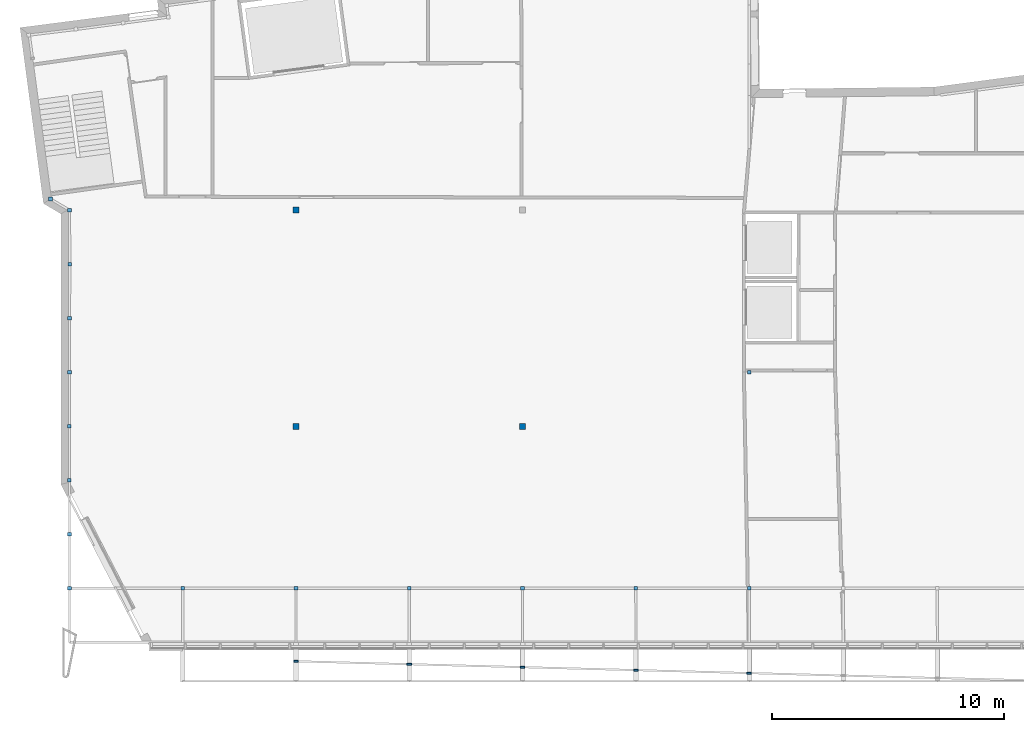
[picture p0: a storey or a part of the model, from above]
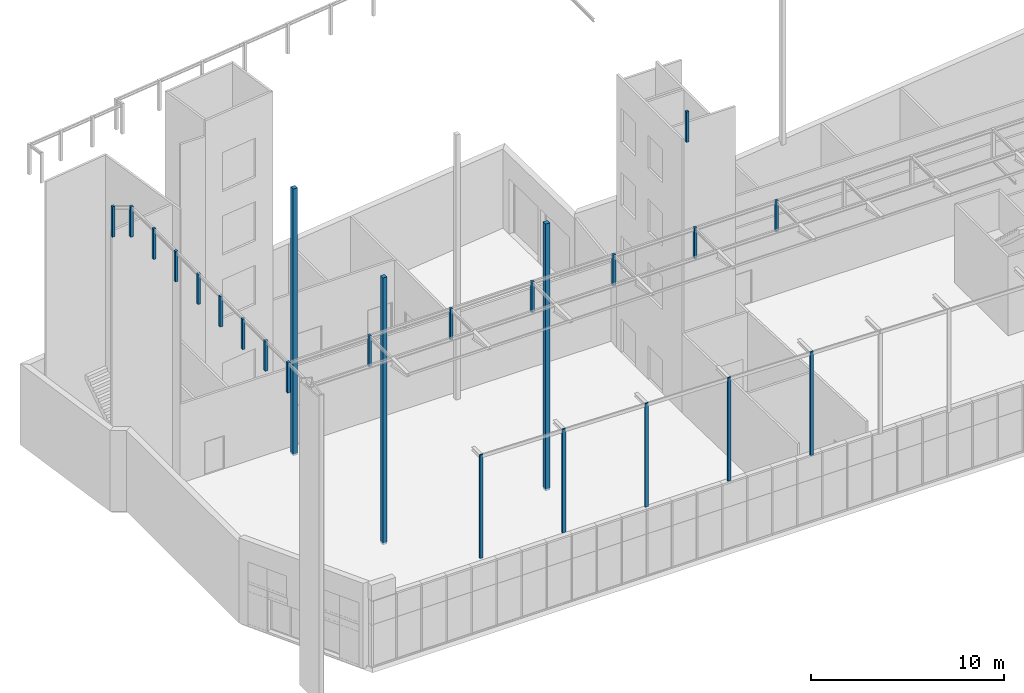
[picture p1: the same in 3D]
Properties of the parts of a building model (IFC2X3), part 1 of 19

# File
Description: ViewDefinition [CoordinationView_V2.0, QuantityTakeOffAddOnView, SpaceBoundary2ndLevelAddOnView], Option [Drawing Scale: 50.000000], Option [Global Unique Identifiers (GUID): Keep existing], Option [Elements to export: Visible elements (on all stories)], Option [Partial Structure Display: Entire Model], Option [IFC Domain: All], Option [Structural Function: All Elements], Option [Convert Grid elements: On], Option [Convert IFC Annotations and ArchiCAD 2D elements: Off], Option [Convert 2D symbols of Doors and Windows: Off], Option [Explode Composite and Complex Profile elements into parts: Off], Option [Export geometries that Participates in Collision Detection only: Off], Option [Multi-skin complex geometries: Building element parts], Option [Elements in Solid Element Operations: Extruded/revolved], Option [Elements with junctions: Extruded/revolved without junctions], Option [Slabs with slanted edge(s): Extruded], Option [Use legacy geometric methods as in Coordination View 1.0: Off], Option [IFC Site Geometry: As boundary representation (BRep)], Option [Properties To Export: All properties], Option [Space containment: On], Option [Bounding Box: Off], Option [Geometry to type objects: Off], Option [IFC base quantities (size, area and volume): On], Option [All ArchiCAD BIM parameters: On], Option [IFC Space boundaries: On], Option [ArchiCAD Zone Categories as IFC Space classification data: On]
File name: /Users/judde/Desktop/OpenBIM Tour/ArchiCAD Modèle entier.ifc
Time: 2015-04-22T15:16:54
Author: Architect
Organization: Building Designer Office
Written by: PreProc - EDM 5.0
Made in: IFC file generated by Graphisoft ArchiCAD-64 18.0.0 FRA FULL Macintosh version (IFC2x3 add-on version: 5100 FRA FULL).
Authorization: The authorising person

# IfcSite, Undefined
RefLatitude: 38, 55, 0, 0; RefLongitude: -77, 0, 0, 0; RefElevation: 0 m
BaseQuantities - GrossPerimeter: 0 m; GrossArea: 0 m2

# IfcBuilding, Undefined
BaseQuantities - GrossFloorArea: 0 m2

# IfcBuildingStorey (6)
In: Undefined
BaseQuantities - GrossFloorArea: 0 m2
Name | LongName | Elevation (m) | NetHeight (m) = GrossHeight (m) = Height (m)
Rez de chaussée | 0. Groud | 0 | 5.4
R+1 | 1. First Floor | 5.4 | 4.025
Mezzannine | 2. Mezz | 9.425 | 4.025
R+2 | 3. 2nd Floor | 13.45 | 3.95
Toiture | 4. Roof | 17.4 | 1.95
Etage | 5. Story | 19.35 | 3.235

# IfcBeam: HEB200 (10)
In: Rez de chaussée
Description: A_Beam; Material: STEEL/S235JRG2 3386696625
ArchiCADProperties - ID: BEAM; Etage d'implantation: Rez de chaussée; Calque: A-BEAM; Type: Poutre; Verrouillé: no; Matériau de construction / Composite / Profil / Hachure: HEB200 0000000000; Fonction structurelle: Elément porteur; Position: Non défini; Classification d'lément: Poutre; Etat de rénovation: Existant; Afficher sur filtre de rénovation: Tous les filtres appropriés; Type de structure: Profil complexe; Matériau de construction / Profil: HEB200 0000000000; Angle d'inclinaison de poutre: 0 deg; Coupe transversale de poutre: Profilé
AC_Pset_RenovationAndPhasing - Renovation Status: Existing
Pset_BeamCommon - LoadBearing: yes; Reference: HEB200 0000000000 200 x 200
BaseQuantities - CrossSectionArea: 0.00780812 m2
ArchiCADQuantities - Altitude à Zéro du Projet: 11.65 m; Altitude à étage: 11.65 m; Hauteur: 0.2 m; Surface des trous: 0 m2; Surface des arêtes de trou: 0 m2; Nombre de trous: 0; Volume des trous: 0 m3; Largeur des trous: 0 m; Hauteur du trou: 0 m; Niveau du trou: 0 m; Largeur: 0.2 m; Décalage: 0 m
Name | Nom de Zone | Numéro de Zone | NetSurfaceAreaExtrudedSides (m2) = OuterSurfaceArea (m2) | Length (m) = Longueur droite (m) = Longueur gauche (m) | TotalSurfaceArea (m2) = GrossSurfaceArea (m2) | GrossVolume (m3) = NetVolume (m3) = Volume net (m3) = Volume (m3) = Volume conditionnel (m3) | Superficie de surface (m2) | Superficie (m2) = Surface inférieure (m2) = Surface supérieure (m2) | Surface côté gauche (m2) | Surface côté droit (m2) | Surface de fin (m2)
BEAM | Vide | 001 | 0.917813 | 1.23231 | 0.93343 | 0.00626754 | 0.925667 | 0.283291 | 0.175661 | 0.175571 | 0.007854
BEAM | Vide | 001 | 1.06306 | 1.35983 | 1.07868 | 0.00726072 | 1.07091 | 0.328183 | 0.203375 | 0.203318 | 0.007854
BEAM | Vide | 001 | 1.30754 | 1.57068 | 1.32316 | 0.00892973 | 1.31539 | 0.403621 | 0.250178 | 0.25012 | 0.007854
BEAM | Vide | 001 | 0.770857 | 1.10595 | 0.786474 | 0.00526391 | 0.778711 | 0.237927 | 0.147544 | 0.147459 | 0.007854
BEAM | Vide | 001 | 0.607316 | 0.978469 | 0.622933 | 0.00414768 | 0.607316 | 0.187474 | 0.116213 | 0.116155 | 0
BEAM | Plateau bureaux | 005 | 1.74563 | 1.95138 | 1.76125 | 0.0119068 | 1.76134 | 0.538184 | 0.33586 | 0.333402 | 0.015708
BEAM | Vide | 001 | 1.45225 | 1.69643 | 1.46787 | 0.00991454 | 1.46011 | 0.448133 | 0.277794 | 0.278195 | 0.007854
BEAM | Vide | 001 | 1.18343 | 1.46426 | 1.19904 | 0.00808366 | 1.19128 | 0.36538 | 0.22634 | 0.226326 | 0.007854
BEAM | Cafetaria | 007 | 0.46249 | 0.852231 | 0.478106 | 0.00315913 | 0.46249 | 0.142792 | 0.0884527 | 0.0884527 | 0
BEAM | Vide | 001 | 1.59732 | 1.82448 | 1.61293 | 0.0109101 | 1.60517 | 0.493134 | 0.305554 | 0.305496 | 0.007854

# IfcBeam: IPE200 (87)
In: Rez de chaussée
Description: A_Beam; Material: STEEL/S235JRG2 3386696625
ArchiCADProperties - Etage d'implantation: Rez de chaussée; Calque: A-BEAM; Type: Poutre; Verrouillé: no; Matériau de construction / Composite / Profil / Hachure: IPE200 0000000000; Classification d'lément: Poutre; Etat de rénovation: Existant; Afficher sur filtre de rénovation: Tous les filtres appropriés; Type de structure: Profil complexe; Matériau de construction / Profil: IPE200 0000000000; Coupe transversale de poutre: Profilé
AC_Pset_RenovationAndPhasing - Renovation Status: Existing
Pset_BeamCommon - Reference: IPE200 0000000000 100 x 200
BaseQuantities - CrossSectionArea: 0.00284841 m2
ArchiCADQuantities - Hauteur: 0.2 m; Surface des trous: 0 m2; Surface des arêtes de trou: 0 m2; Nombre de trous: 0; Volume des trous: 0 m3; Largeur des trous: 0 m; Hauteur du trou: 0 m; Niveau du trou: 0 m; Largeur: 0.1 m; Décalage: 0 m
Name | ID | Fonction structurelle | Position | Angle d'inclinaison de poutre (deg) | LoadBearing | IsExternal | NetSurfaceAreaExtrudedSides (m2) = OuterSurfaceArea (m2) | Length (m) = Longueur droite (m) = Longueur gauche (m) | TotalSurfaceArea (m2) = GrossSurfaceArea (m2) | GrossVolume (m3) = NetVolume (m3) = Volume net (m3) = Volume (m3) = Volume conditionnel (m3) | Altitude à Zéro du Projet (m) = Altitude à étage (m) | Superficie de surface (m2) | Superficie (m2) = Surface inférieure (m2) | Surface supérieure (m2) | Surface côté gauche (m2) | Surface côté droit (m2) | Surface de fin (m2)
Poutre | Poutre | Elément non porteur | Extérieur | 0 | no | yes | 1.45974 | 2.2201 | 1.46544 | 0.00530882 | 19.025 | 1.4649 | 0.24483 | 0.351041 | 0.425612 | 0.43826 | 0.00515369
3 x Poutre | Poutre | Elément porteur | Extérieur | 0 | yes | yes | 3.613 | 4.875 | 3.61869 | 0.0136423 | 19.025 | 3.613 | 0.803447 | 0.803447 | 1.00306 | 1.00305 | 0
Poutre | Poutre | Elément non porteur | Extérieur | 0 | no | yes | 1.3931 | 2.05 | 1.39879 | 0.00520218 | 19.025 | 1.3931 | 0.278304 | 0.322088 | 0.390549 | 0.402156 | 0
Poutre | Poutre | Elément porteur | Extérieur | 0 | yes | yes | 2.73538 | 4.69122 | 2.74108 | 0.0102079 | 19.025 | 2.73538 | 0.436856 | 0.436856 | 0.866843 | 0.994826 | 0
Poutre | Poutre | Elément porteur | Extérieur | 0 | yes | yes | 1.33106 | 2.07 | 1.33676 | 0.00509716 | 19.025 | 1.33107 | 0.28051 | 0.28051 | 0.3699 | 0.400141 | 0.0000115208
Poutre | Poutre | Elément non porteur | Extérieur | 0 | no | yes | 1.38022 | 1.96802 | 1.38592 | 0.00498391 | 19.025 | 1.38529 | 0.219614 | 0.33535 | 0.406589 | 0.418671 | 0.0050649
3 x BEAM | BEAM | Elément porteur | Extérieur | -0.000687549 | yes | yes | 1.72018 | 2.32501 | 1.72588 | 0.00649781 | 19.025 | 1.72308 | 0.382548 | 0.382548 | 0.477562 | 0.477524 | 0.00289552
Poutre | Poutre | Elément porteur | Extérieur | 0 | yes | yes | 2.83053 | 4.69121 | 2.83623 | 0.0106495 | 19.025 | 2.83053 | 0.459461 | 0.459461 | 0.916788 | 0.994823 | 0
Poutre | Poutre | Elément porteur | Extérieur | 0 | yes | yes | 2.83059 | 4.69121 | 2.83629 | 0.0106497 | 19.025 | 2.83059 | 0.459491 | 0.459491 | 0.916788 | 0.994823 | 0
Poutre | Poutre | Elément non porteur | Extérieur | 0 | no | yes | 3.19786 | 4.65 | 3.20356 | 0.0118507 | 19.025 | 3.19891 | 0.603178 | 0.761832 | 0.929718 | 0.903134 | 0.00105092
BEAM | BEAM | Elément porteur | Extérieur | -0.000687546 | yes | yes | 1.71677 | 2.32481 | 1.72247 | 0.00644232 | 19.025 | 1.71752 | 0.377904 | 0.385892 | 0.477004 | 0.47597 | 0.000745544
Poutre | Poutre | Elément porteur | Extérieur | 0 | yes | yes | 1.73799 | 2.325 | 1.74368 | 0.00658569 | 19.025 | 1.7457 | 0.388585 | 0.391068 | 0.479167 | 0.479167 | 0.00771184
Poutre | Poutre | Elément porteur | Extérieur | 0 | yes | yes | 1.80863 | 2.56534 | 1.81433 | 0.00680944 | 19.025 | 1.80863 | 0.397836 | 0.397836 | 0.50702 | 0.505937 | 0 | ArchiCADProperties - Nom de Zone: Dégagement; Numéro de Zone: 001
Poutre | Poutre | Elément porteur | Extérieur | 0 | yes | yes | 1.55051 | 2.14602 | 1.55621 | 0.00585484 | 19.025 | 1.55051 | 0.344794 | 0.344794 | 0.430252 | 0.430672 | 0
BEAM | BEAM | Elément porteur | Extérieur | 0 | yes | yes | 2.95887 | 4.05 | 2.96457 | 0.0113675 | 19.025 | 2.95887 | 0.652573 | 0.655539 | 0.858892 | 0.791865 | 0.00000111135
Poutre | Poutre | Elément porteur | Extérieur | 0 | yes | yes | 3.613 | 4.875 | 3.61869 | 0.0136422 | 19.025 | 3.613 | 0.803447 | 0.803447 | 1.00306 | 1.00305 | 0
Poutre | Poutre | Elément porteur | Extérieur | 0 | yes | yes | 3.06337 | 4.05 | 3.06907 | 0.0115359 | 19.025 | 3.06338 | 0.683569 | 0.672733 | 0.858439 | 0.848632 | 0.0000061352
BEAM | BEAM | Elément porteur | Extérieur | 0 | yes | yes | 3.21158 | 4.875 | 3.21727 | 0.0121817 | 19.025 | 3.21158 | 0.608472 | 0.616131 | 1.03392 | 0.953048 | 0.00000362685
Poutre | Poutre | Elément porteur | Extérieur | 0 | yes | yes | 3.61299 | 4.875 | 3.61869 | 0.0136421 | 19.025 | 3.61299 | 0.803447 | 0.803447 | 1.00305 | 1.00304 | 0
Poutre | Poutre | Elément non porteur | Extérieur | 0 | no | yes | 1.3121 | 1.96001 | 1.3178 | 0.00486586 | 19.025 | 1.3121 | 0.250649 | 0.306682 | 0.371935 | 0.382837 | 0
2 x Poutre | Poutre | Elément non porteur | Extérieur | 0 | no | yes | 1.58475 | 2.32504 | 1.59045 | 0.00589022 | 19.025 | 1.58475 | 0.307953 | 0.368922 | 0.447293 | 0.460585 | 0
Poutre | Poutre | Elément porteur | Extérieur | 0 | yes | yes | 0 | 3.31938 | 0.00569682 | 0 | 19.025 | 0 | 0 | 0 | 0 | 0 | 0
Poutre | Poutre | Elément porteur | Extérieur | 0 | yes | yes | 0 | 2.53 | 0.00569682 | 0 | 19.025 | 0 | 0 | 0 | 0 | 0 | 0
Poutre | Poutre | Elément porteur | Extérieur | 0 | yes | yes | 1.3938 | 2.07 | 1.39949 | 0.00526307 | 19.025 | 1.3938 | 0.309945 | 0.309945 | 0.386954 | 0.386954 | 0
Poutre | Poutre | Elément porteur | Extérieur | 0 | yes | yes | 0 | 1.3559 | 0.00569682 | 0 | 19.025 | 0 | 0 | 0 | 0 | 0 | 0
BEAM | BEAM | Elément porteur | Extérieur | 0 | yes | yes | 3.39687 | 4.875 | 3.40257 | 0.0129631 | 19.025 | 3.39688 | 0.7004 | 0.709502 | 1.03392 | 0.953048 | 0.00000440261
Poutre | Poutre | Elément porteur | Extérieur | 0 | yes | yes | 1.73364 | 2.325 | 1.73934 | 0.00656146 | 19.025 | 1.73781 | 0.387158 | 0.388637 | 0.478925 | 0.478924 | 0.00416588
Poutre | Poutre | Elément porteur | Extérieur | 0 | yes | yes | 3.3044 | 4.47366 | 3.3101 | 0.0124776 | 19.025 | 3.3044 | 0.734823 | 0.734823 | 0.917377 | 0.917377 | 0
Poutre | Poutre | Elément non porteur | Extérieur | 0 | no | yes | 1.45526 | 2.2201 | 1.46096 | 0.00528133 | 19.025 | 1.46039 | 0.240351 | 0.351041 | 0.425612 | 0.43826 | 0.00512644
Poutre | Poutre | Elément porteur | Extérieur | 0 | yes | yes | 3.47108 | 4.69121 | 3.47678 | 0.013107 | 19.025 | 3.47108 | 0.771883 | 0.771883 | 0.963657 | 0.963657 | 0
Poutre | Poutre | Elément porteur | Extérieur | 0 | yes | yes | 3.70828 | 4.875 | 3.71397 | 0.0139433 | 19.025 | 3.70934 | 0.823691 | 0.814935 | 1.03474 | 1.03491 | 0.00106386
Poutre | Poutre | Elément porteur | Extérieur | 0 | yes | yes | 3.70523 | 4.875 | 3.71093 | 0.0139262 | 19.025 | 3.70524 | 0.823422 | 0.81366 | 1.03395 | 1.0342 | 0.00000570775
Poutre | Poutre | Elément porteur | Extérieur | 0 | yes | yes | 3.47108 | 4.69121 | 3.47678 | 0.013107 | 19.025 | 3.47108 | 0.771882 | 0.771882 | 0.963657 | 0.963657 | 0
Poutre | Poutre | Elément porteur | Extérieur | 0 | yes | yes | 3.47183 | 4.69221 | 3.47753 | 0.0131099 | 19.025 | 3.47183 | 0.772047 | 0.772047 | 0.96387 | 0.96387 | 0
BEAM | BEAM | Elément porteur | Extérieur | -0.000687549 | yes | yes | 1.72018 | 2.32501 | 1.72588 | 0.00649779 | 19.025 | 1.72308 | 0.382548 | 0.382548 | 0.477562 | 0.477525 | 0.0028955
Poutre | Poutre | Elément non porteur | Extérieur | 0 | no | yes | 1.93865 | 2.91441 | 1.94435 | 0.0070178 | 19.025 | 1.94374 | 0.314274 | 0.469352 | 0.569056 | 0.585967 | 0.0050949
2 x BEAM | BEAM | Elément porteur | Non défini | 0 | yes |  | 0.590744 | 2.325 | 0.596441 | 0.00249364 | 17.1 | 0.591855 | 0.158048 | 0.2245 | 0.104098 | 0.104098 | 0.00111075 | ArchiCADProperties - Nom de Zone: Plateau bureaux; Numéro de Zone: 005
Poutre | Poutre | Elément non porteur | Extérieur | 0 | no | yes | 0.524645 | 0.949746 | 0.530342 | 0.00184989 | 19.025 | 0.524645 | 0.0706959 | 0.132346 | 0.158303 | 0.1633 | 0
Poutre | Poutre | Elément porteur | Extérieur | 0 | yes | yes | 3.613 | 4.875 | 3.61869 | 0.0136422 | 19.025 | 3.613 | 0.803447 | 0.803447 | 1.00305 | 1.00305 | 0
Poutre | Poutre | Elément porteur | Extérieur | 0 | yes | yes | 3.34717 | 4.47366 | 3.35287 | 0.0126256 | 19.025 | 3.34718 | 0.740315 | 0.740315 | 0.933474 | 0.933065 | 0.0000115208
Poutre | Poutre | Elément porteur | Extérieur | 0 | yes | yes | 1.55054 | 2.11398 | 1.55624 | 0.00585495 | 19.025 | 1.55054 | 0.344801 | 0.344801 | 0.43026 | 0.43068 | 0
Poutre | Poutre | Elément porteur | Extérieur | 0 | yes | yes | 0.949796 | 1.32029 | 0.955493 | 0.00358649 | 19.025 | 0.953904 | 0.21121 | 0.21121 | 0.26505 | 0.262325 | 0.00410816
Poutre | Poutre | Elément porteur | Extérieur | 0 | yes | yes | 1.55054 | 2.17912 | 1.55624 | 0.00585495 | 19.025 | 1.55054 | 0.344801 | 0.344801 | 0.43026 | 0.43068 | 0
Poutre | Poutre | Elément porteur | Extérieur | 0 | yes | yes | 1.55054 | 2.21219 | 1.55624 | 0.00585495 | 19.025 | 1.55054 | 0.344801 | 0.344801 | 0.43026 | 0.43068 | 0
Poutre | Poutre | Elément non porteur | Extérieur | 0 | no | yes | 1.90755 | 2.806 | 1.91325 | 0.00701914 | 19.025 | 1.90755 | 0.347112 | 0.450878 | 0.546659 | 0.562904 | 0
Poutre | Poutre | Elément non porteur | Extérieur | 0 | no | yes | 1.62822 | 2.43476 | 1.63391 | 0.0059625 | 19.025 | 1.63346 | 0.286709 | 0.38762 | 0.469962 | 0.483928 | 0.00524305
Poutre | Poutre | Elément porteur | Extérieur | 0 | yes | yes | 3.51719 | 4.75 | 3.52289 | 0.0132808 | 19.025 | 3.51719 | 0.782136 | 0.782152 | 0.976455 | 0.97645 | 0
Poutre | Poutre | Elément non porteur | Extérieur | 0 | no | yes | 1.91499 | 2.806 | 1.92069 | 0.00706481 | 19.025 | 1.91499 | 0.354551 | 0.450878 | 0.546658 | 0.562904 | 0
Poutre | Poutre | Elément porteur | Extérieur | 0 | yes | yes | 3.45841 | 4.6905 | 3.46411 | 0.0130547 | 19.025 | 3.45841 | 0.769762 | 0.76976 | 0.959449 | 0.95944 | 0
Poutre | Poutre | Elément porteur | Extérieur | 0 | yes | yes | 3.03836 | 4.75 | 3.04406 | 0.0114906 | 19.025 | 3.03837 | 0.554067 | 0.548361 | 1.00736 | 0.928577 | 0.00000338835
Poutre | Poutre | Elément non porteur | Extérieur | 0 | no | yes | 1.6574 | 2.48344 | 1.6631 | 0.00605535 | 19.025 | 1.66261 | 0.287186 | 0.395914 | 0.480018 | 0.494283 | 0.00521284
Poutre | Poutre | Elément porteur | Extérieur | 0 | yes | yes | 1.47839 | 2.08034 | 1.48409 | 0.00559674 | 19.025 | 1.48734 | 0.31971 | 0.31971 | 0.421284 | 0.417685 | 0.00895083 | ArchiCADProperties - Nom de Zone: Dégagement; Numéro de Zone: 001
Poutre | Poutre | Elément non porteur | Extérieur | 0 | no | yes | 1.6344 | 2.4591 | 1.6401 | 0.00595728 | 19.025 | 1.63958 | 0.278536 | 0.391767 | 0.47499 | 0.489105 | 0.00518243
Poutre | Poutre | Elément non porteur | Extérieur | 0 | no | yes | 1.70877 | 2.4591 | 1.71447 | 0.00627203 | 19.025 | 1.7114 | 0.305731 | 0.405399 | 0.491518 | 0.506124 | 0.00262899
Poutre | Poutre | Elément non porteur | Extérieur | 0 | no | yes | 0.246564 | 0.499998 | 0.252261 | 0.000911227 | 19.025 | 0.246564 | 0.0460409 | 0.0579356 | 0.0702512 | 0.0723365 | 0
Poutre | Poutre | Elément porteur | Extérieur | 0 | yes | yes | 1.73072 | 2.325 | 1.73641 | 0.00654514 | 19.025 | 1.73363 | 0.386196 | 0.386997 | 0.478762 | 0.478761 | 0.00291842
Poutre | Poutre | Elément porteur | Extérieur | 0 | yes | yes | 1.38566 | 2.05014 | 1.39136 | 0.00515703 | 19.025 | 1.38566 | 0.270923 | 0.322069 | 0.390573 | 0.402099 | 0
Poutre | Poutre | Elément porteur | Extérieur | 0 | yes | yes | 3.7205 | 4.875 | 3.7262 | 0.0140058 | 19.025 | 3.72375 | 0.828957 | 0.820955 | 1.03395 | 1.03664 | 0.00325495
BEAM | BEAM | Elément porteur | Extérieur | 0 | yes | yes | 3.70649 | 4.875 | 3.71219 | 0.013926 | 19.025 | 3.70649 | 0.813671 | 0.824666 | 1.03392 | 1.03423 | 0.00000554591
Poutre | Poutre | Elément porteur | Extérieur | 0 | yes | yes | 3.30299 | 4.875 | 3.30868 | 0.0125726 | 19.025 | 3.30299 | 0.661577 | 0.654436 | 1.03395 | 0.953027 | 0.00000410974
Poutre | Poutre | Elément porteur | Extérieur | 0 | yes | yes | 1.89292 | 2.56534 | 1.89861 | 0.0071447 | 19.025 | 1.89498 | 0.418638 | 0.418638 | 0.526791 | 0.528849 | 0.00206217
BEAM | BEAM | Elément porteur | Extérieur | -0.000687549 | yes | yes | 1.72814 | 2.32501 | 1.73384 | 0.00649579 | 19.025 | 1.73104 | 0.382548 | 0.390408 | 0.477596 | 0.47759 | 0.0028936
Poutre | Poutre | Elément porteur | Extérieur | 0 | yes | yes | 1.738 | 2.325 | 1.74369 | 0.00658573 | 19.025 | 1.74571 | 0.388591 | 0.391074 | 0.479165 | 0.479166 | 0.0077119
BEAM | BEAM | Elément porteur | Extérieur | -0.000687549 | yes | yes | 1.72018 | 2.32501 | 1.72588 | 0.00649781 | 19.025 | 1.72308 | 0.382548 | 0.382548 | 0.477563 | 0.477526 | 0.00289549
Poutre | Poutre | Elément porteur | Extérieur | 0 | yes | yes | 2.74807 | 4.69121 | 2.75377 | 0.01035 | 19.025 | 2.74807 | 0.45098 | 0.45098 | 0.962662 | 0.88345 | 0
Poutre | Poutre | Elément porteur | Extérieur | 0 | yes | yes | 2.98081 | 4.05 | 2.98651 | 0.0112552 | 19.025 | 2.98081 | 0.662863 | 0.662863 | 0.827542 | 0.827544 | 0
Poutre | Poutre | Elément porteur | Extérieur | 0 | yes | yes | 0.884971 | 1.5975 | 0.890668 | 0.00328279 | 19.025 | 0.884971 | 0.136711 | 0.136711 | 0.295753 | 0.315795 | 0 | ArchiCADProperties - Nom de Zone: Dégagement; Numéro de Zone: 001
Poutre | Poutre | Elément porteur | Extérieur | 0 | yes | yes | 0 | 2.3 | 0.00569682 | 0 | 19.025 | 0 | 0 | 0 | 0 | 0 | 0
Poutre | Poutre | Elément non porteur | Extérieur | 0.000687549 | no | yes | 1.61636 | 2.32501 | 1.62206 | 0.00600006 | 19.025 | 1.61802 | 0.307437 | 0.384915 | 0.468634 | 0.455372 | 0.00165853
BEAM | BEAM | Elément non porteur | Extérieur | 0 | no | yes | 1.36437 | 2.325 | 1.37007 | 0.00514087 | 19.025 | 1.36762 | 0.223123 | 0.225073 | 0.476024 | 0.440154 | 0.00325058
Poutre | Poutre | Elément porteur | Extérieur | 0 | yes | yes | 1.73799 | 2.325 | 1.74368 | 0.00658572 | 19.025 | 1.7457 | 0.388585 | 0.391068 | 0.479167 | 0.479167 | 0.00771218
Poutre | Poutre | Elément porteur | Extérieur | 0 | yes | yes | 2.98082 | 4.05 | 2.98651 | 0.0112552 | 19.025 | 2.98082 | 0.662865 | 0.662865 | 0.827547 | 0.827538 | 0
Poutre | Poutre | Elément porteur | Extérieur | 0 | yes | yes | 3.61561 | 4.875 | 3.62131 | 0.0136389 | 19.025 | 3.61561 | 0.803447 | 0.806636 | 1.00263 | 1.00289 | 0
Poutre | Poutre | Elément porteur | Extérieur | 0 | yes | yes | 1.719 | 2.325 | 1.7247 | 0.00648576 | 19.025 | 1.72006 | 0.381944 | 0.381943 | 0.479091 | 0.476023 | 0.00105482
Poutre | Poutre | Elément porteur | Extérieur | 0 | yes | yes | 3.61299 | 4.875 | 3.61869 | 0.0136432 | 19.025 | 3.61299 | 0.803436 | 0.803436 | 1.00306 | 1.00306 | 0
Poutre | Poutre | Elément porteur | Extérieur | 0 | yes | yes | 3.50504 | 4.875 | 3.51074 | 0.0134402 | 19.025 | 3.50786 | 0.761476 | 0.754417 | 1.03552 | 0.95363 | 0.00281842
Poutre | Poutre | Elément porteur | Extérieur | 0 | yes | yes | 3.61298 | 4.875 | 3.61868 | 0.0136428 | 19.025 | 3.61298 | 0.803437 | 0.803438 | 1.00305 | 1.00306 | 0
BEAM | BEAM | Elément porteur | Extérieur | 0 | yes | yes | 3.72421 | 4.875 | 3.7299 | 0.014016 | 19.025 | 3.72711 | 0.822185 | 0.8307 | 1.03552 | 1.0358 | 0.00290153
BEAM | BEAM | Elément porteur | Extérieur | 0 | yes | yes | 3.70651 | 4.875 | 3.71221 | 0.0139262 | 19.025 | 3.70652 | 0.813671 | 0.824667 | 1.03395 | 1.03423 | 0.00000551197
Poutre | Poutre | Elément porteur | Extérieur | 0 | yes | yes | 3.613 | 4.875 | 3.61869 | 0.0136423 | 19.025 | 3.613 | 0.803447 | 0.803447 | 1.00305 | 1.00305 | 0
BEAM | BEAM | Elément porteur | Extérieur | 0 | yes | yes | 4.16914 | 6.84121 | 4.17484 | 0.0157209 | 19.025 | 4.16914 | 0.710063 | 0.718645 | 1.42673 | 1.3137 | 0.00000249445

# IfcBeam: IPE200 0000000000 100 x 200 (9)
In: Rez de chaussée
Description: A_Beam; Material: STEEL/S235JRG2 3386696625
ArchiCADProperties - Etage d'implantation: Rez de chaussée; Calque: A-BEAM; Type: Poutre; Verrouillé: no; Matériau de construction / Composite / Profil / Hachure: IPE200 0000000000; Position: Extérieur; Classification d'lément: Poutre; Etat de rénovation: Existant; Afficher sur filtre de rénovation: Tous les filtres appropriés; Type de structure: Profil complexe; Matériau de construction / Profil: IPE200 0000000000; Angle d'inclinaison de poutre: 0 deg; Coupe transversale de poutre: Profilé
AC_Pset_RenovationAndPhasing - Renovation Status: Existing
Pset_BeamCommon - IsExternal: yes; Reference: IPE200 0000000000 100 x 200
BaseQuantities - CrossSectionArea: 0.00284841 m2
ArchiCADQuantities - Altitude à Zéro du Projet: 19.025 m; Altitude à étage: 19.025 m; Hauteur: 0.2 m; Surface des trous: 0 m2; Surface des arêtes de trou: 0 m2; Nombre de trous: 0; Volume des trous: 0 m3; Largeur des trous: 0 m; Hauteur du trou: 0 m; Niveau du trou: 0 m; Largeur: 0.1 m; Décalage: 0 m
Name | ID | Fonction structurelle | LoadBearing | NetSurfaceAreaExtrudedSides (m2) = OuterSurfaceArea (m2) | Length (m) = Longueur droite (m) = Longueur gauche (m) | TotalSurfaceArea (m2) = GrossSurfaceArea (m2) | GrossVolume (m3) = NetVolume (m3) = Volume net (m3) = Volume (m3) = Volume conditionnel (m3) | Superficie de surface (m2) | Superficie (m2) = Surface inférieure (m2) | Surface supérieure (m2) | Surface côté gauche (m2) | Surface côté droit (m2) | Surface de fin (m2)
Poutre | Poutre | Elément porteur | yes | 0.635466 | 1.05252 | 0.641163 | 0.0023096 | 0.635466 | 0.107522 | 0.152171 | 0.191303 | 0.18447 | 0
BEAM | BEAM | Elément non porteur | no | 1.61337 | 2.325 | 1.61906 | 0.00598279 | 1.61563 | 0.304405 | 0.384916 | 0.455409 | 0.468636 | 0.00226633
BEAM | BEAM | Elément non porteur | no | 1.41382 | 2.325 | 1.41952 | 0.00528079 | 1.41488 | 0.243216 | 0.274251 | 0.43292 | 0.463438 | 0.00105303
Poutre | Poutre | Elément non porteur | no | 3.85126 | 5.41151 | 3.85695 | 0.0143322 | 3.85126 | 0.754296 | 0.894846 | 1.08496 | 1.11715 | 0
Poutre | Poutre | Elément non porteur | no | 3.40083 | 4.7957 | 3.40653 | 0.0126055 | 3.40354 | 0.649303 | 0.795035 | 0.99257 | 0.963924 | 0.00270474
Poutre | Poutre | Elément non porteur | no | 1.63979 | 2.45871 | 1.64548 | 0.00607972 | 1.63979 | 0.313639 | 0.383181 | 0.464581 | 0.478385 | 0
Poutre | Poutre | Elément non porteur | no | 3.47397 | 4.91781 | 3.47966 | 0.0128912 | 3.47397 | 0.668114 | 0.810731 | 0.982954 | 1.01217 | 0
Poutre | Poutre | Elément non porteur | no | 3.46877 | 4.9182 | 3.47446 | 0.0128585 | 3.46877 | 0.662684 | 0.810797 | 0.983019 | 1.01227 | 0
Poutre | Poutre | Elément non porteur | no | 2.06371 | 2.95243 | 2.0694 | 0.00787333 | 2.07046 | 0.430982 | 0.448576 | 0.573182 | 0.610966 | 0.00675977

# IfcBeam: IPE300 (3)
In: Rez de chaussée
Description: A_Beam; Material: STEEL/S235JRG2 3386696625
ArchiCADProperties - ID: BEAM; Etage d'implantation: Rez de chaussée; Calque: A-BEAM; Type: Poutre; Verrouillé: no; Matériau de construction / Composite / Profil / Hachure: IPE300 0000000000; Fonction structurelle: Elément porteur; Position: Non défini; Classification d'lément: Poutre; Etat de rénovation: Existant; Afficher sur filtre de rénovation: Tous les filtres appropriés; Type de structure: Profil complexe; Matériau de construction / Profil: IPE300 0000000000; Angle d'inclinaison de poutre: 0 deg; Coupe transversale de poutre: Profilé
AC_Pset_RenovationAndPhasing - Renovation Status: Existing
Pset_BeamCommon - LoadBearing: yes; Reference: IPE300 0000000000 150 x 300
BaseQuantities - CrossSectionArea: 0.0053812 m2
ArchiCADQuantities - Altitude à Zéro du Projet: 17.05 m; Altitude à étage: 17.05 m; Hauteur: 0.3 m; Surface des trous: 0 m2; Surface des arêtes de trou: 0 m2; Nombre de trous: 0; Volume des trous: 0 m3; Largeur des trous: 0 m; Hauteur du trou: 0 m; Niveau du trou: 0 m; Largeur: 0.15 m; Décalage: 0 m
Name | NetSurfaceAreaExtrudedSides (m2) = OuterSurfaceArea (m2) | Length (m) = Longueur droite (m) = Longueur gauche (m) | TotalSurfaceArea (m2) = GrossSurfaceArea (m2) | GrossVolume (m3) = NetVolume (m3) = Volume net (m3) = Volume (m3) = Volume conditionnel (m3) | Superficie de surface (m2) | Superficie (m2) = Surface inférieure (m2) | Surface supérieure (m2) | Surface côté gauche (m2) | Surface côté droit (m2) | Surface de fin (m2)
BEAM | 2.18266 | 1.9084 | 2.19342 | 0.0101725 | 2.18807 | 0.491521 | 0.488516 | 0.601312 | 0.601312 | 0.00541306
BEAM | 2.75786 | 2.56527 | 2.76863 | 0.0130316 | 2.76328 | 0.654691 | 0.654691 | 0.724239 | 0.724243 | 0.00541306
BEAM | 3.20556 | 4.36069 | 3.21632 | 0.0168594 | 3.21162 | 1.11117 | 1.10818 | 0.492988 | 0.493216 | 0.00606059 | ArchiCADProperties - Nom de Zone: Plateau bureaux; Numéro de Zone: 005

# IfcBeam: IPE360, BEAM
In: Rez de chaussée
Description: A_Beam; Material: STEEL/S235JRG2 3386696625
ArchiCADProperties - ID: BEAM; Etage d'implantation: Rez de chaussée; Nom de Zone: Plateau bureaux; Numéro de Zone: 005; Calque: A-BEAM; Type: Poutre; Verrouillé: no; Matériau de construction / Composite / Profil / Hachure: IPE360 0000000000; Fonction structurelle: Elément porteur; Position: Non défini; Classification d'lément: Poutre; Etat de rénovation: Existant; Afficher sur filtre de rénovation: Tous les filtres appropriés; Type de structure: Profil complexe; Matériau de construction / Profil: IPE360 0000000000; Angle d'inclinaison de poutre: 0 deg; Coupe transversale de poutre: Profilé
AC_Pset_RenovationAndPhasing - Renovation Status: Existing
Pset_BeamCommon - LoadBearing: yes; Reference: IPE360 0000000000 170 x 360
BaseQuantities - NetSurfaceAreaExtrudedSides: 4.20173 m2; Length: 4.34 m; CrossSectionArea: 0.00727292 m2; OuterSurfaceArea: 4.20173 m2; TotalSurfaceArea: 4.21628 m2; GrossSurfaceArea: 4.21628 m2; GrossVolume: 0.0235418 m3; NetVolume: 0.0235418 m3
ArchiCADQuantities - Altitude à Zéro du Projet: 17.02 m; Altitude à étage: 17.02 m; Hauteur: 0.36 m; Superficie de surface: 4.21521 m2; Volume net: 0.0235418 m3; Superficie: 0.869628 m2; Longueur droite: 4.34 m; Longueur gauche: 4.34 m; Surface inférieure: 0.869628 m2; Surface supérieure: 0.869628 m2; Surface côté gauche: 1.18091 m2; Surface côté droit: 1.28157 m2; Volume: 0.0235418 m3; Surface de fin: 0.0134799 m2; Surface des trous: 0 m2; Surface des arêtes de trou: 0 m2; Nombre de trous: 0; Volume des trous: 0 m3; Largeur des trous: 0 m; Hauteur du trou: 0 m; Niveau du trou: 0 m; Largeur: 0.17 m; Décalage: 0 m; Volume conditionnel: 0.0235418 m3

# IfcBeam: IPE550, BEAM
In: Rez de chaussée
Description: A_Beam; Material: STEEL/S235JRG2 3386696625
ArchiCADProperties - ID: BEAM; Etage d'implantation: Rez de chaussée; Calque: A-BEAM; Type: Poutre; Verrouillé: no; Matériau de construction / Composite / Profil / Hachure: IPE550 0000000000; Fonction structurelle: Elément porteur; Position: Non défini; Classification d'lément: Poutre; Etat de rénovation: Existant; Afficher sur filtre de rénovation: Tous les filtres appropriés; Type de structure: Profil complexe; Matériau de construction / Profil: IPE550 0000000000; Angle d'inclinaison de poutre: 0 deg; Coupe transversale de poutre: Profilé
AC_Pset_RenovationAndPhasing - Renovation Status: Existing
Pset_BeamCommon - LoadBearing: yes; Reference: IPE550 0000000000 210 x 550
BaseQuantities - NetSurfaceAreaExtrudedSides: 2.09891 m2; Length: 1.90851 m; CrossSectionArea: 0.0134416 m2; OuterSurfaceArea: 2.09891 m2; TotalSurfaceArea: 2.12579 m2; GrossSurfaceArea: 2.12579 m2; GrossVolume: 0.0157966 m3; NetVolume: 0.0157966 m3
ArchiCADQuantities - Altitude à Zéro du Projet: 16.925 m; Altitude à étage: 16.925 m; Hauteur: 0.55 m; Superficie de surface: 2.1179 m2; Volume net: 0.0157966 m3; Superficie: 0.356083 m2; Longueur droite: 1.90851 m; Longueur gauche: 1.90851 m; Surface inférieure: 0.356083 m2; Surface supérieure: 0.356083 m2; Surface côté gauche: 0.944564 m2; Surface côté droit: 0.442179 m2; Volume: 0.0157966 m3; Surface de fin: 0.0189934 m2; Surface des trous: 0 m2; Surface des arêtes de trou: 0 m2; Nombre de trous: 0; Volume des trous: 0 m3; Largeur des trous: 0 m; Hauteur du trou: 0 m; Niveau du trou: 0 m; Largeur: 0.21 m; Décalage: 0 m; Volume conditionnel: 0.0157966 m3

# IfcBeam: PHI533-125-10-14*210-14*210 (16)
In: Rez de chaussée
Description: PHI533-125-10-14*210-14*210; Material: 50 %
Tekla Common - Part mark: M/0(?); Phase: 1; Class: 3; Grade: S275; Profile: PHI533-125-10-14*210-14*210; Name: BEAM
Tekla Quantity - Net weight: 0 g; Gross weight: 0 g; Weight: 0 g; Gross footprint area: 357000 m2; Height: 533 m; Width: 210 m; Length: 1700 m
ArchiCADProperties - ID: BEAM; Etage d'implantation: Rez de chaussée; Calque: A-BEAM; Type: Objet; Verrouillé: no; Matériau de construction / Composite / Profil / Hachure: 50 %; Fonction structurelle: Elément porteur; Position: Extérieur; Classification d'lément: Type ArchiCAD; Etat de rénovation: Existant; Afficher sur filtre de rénovation: Tous les filtres appropriés; Surface: Mtl-Stainless Steel
AC_Pset_RenovationAndPhasing - Renovation Status: Existing
Pset_BeamCommon - LoadBearing: yes; IsExternal: yes
ArchiCADQuantities - Altitude à Zéro du Projet: 19.025 m; Altitude à étage: 19.025 m; Superficie de surface: 2.55033 m2; Volume net: 0.0152483 m3; Superficie: 1 m2; Hauteur (Taille en Z): 1 m; Longueur (A): 1 m; Volume: 0.0152483 m3; Largeur (B): 1 m
Name | Center of gravity Z (m) | Center of gravity Y (m) | Center of gravity X (m) | Bottom elevation | Top elevation | Assembly mark | Net volume (m3) = Gross volume (m3) | Net surface area (m2) = Gross area (m2) | Nom Elément de Bibliothèque | Angle de rotation (deg)
BEAM | 19588.9 | -785.56 | 47109.7 | +19.230 | +19.763 | B/595(?) | 15248169 | 2550332 | IFC Beam 8EECFB47-5D60-46AC-9301-5C0A1F680FA9 | -90 | AC_Pset_IFC_Beam_8EECFB47-5D60-46AC-9301-5C0A1F680FA9 - Contour Pen: Eléments 2D - Général; Fill Type: Background Fill-International; Fill Pen: Fond - Couleur 1; Fill Background Pen: Fond - Couleur 1; Cost: 0; Group Type: Others; Type de groupe: 25; Object Weight: 0; Object Weight Unit: kg; IFC Material: 07 | Spanish Tile; AC_Equantity_IFC_Beam_8EECFB47-5D60-46AC-9301-5C0A1F680FA9 - Dimension 1: 1 m; Dimension 2: 1 m; Height: 1 m; Bottom Level: 1 m; Top Level: 0 m
BEAM | 19588.9 | 103.895 | 69161.3 | +19.229 | +19.762 | B/595(?) | 15248168 | 2550331 | IFC Beam C3E2A19D-6B3E-4DA2-811C-C8BABFE3A247 | 7.6 | AC_Pset_IFC_Beam_C3E2A19D-6B3E-4DA2-811C-C8BABFE3A247 - Contour Pen: Eléments 2D - Général; Fill Type: Background Fill-International; Fill Pen: Fond - Couleur 1; Fill Background Pen: Fond - Couleur 1; Cost: 0; Group Type: Others; Type de groupe: 25; Object Weight: 0; Object Weight Unit: kg; IFC Material: 07 | Spanish Tile; AC_Equantity_IFC_Beam_C3E2A19D-6B3E-4DA2-811C-C8BABFE3A247 - Dimension 1: 1 m; Dimension 2: 1 m; Height: 1 m; Bottom Level: 1 m; Top Level: 0 m
BEAM | 19588.9 | -785.56 | 29257.5 | +19.229 | +19.762 | B/595(?) | 15248169 | 2550332 | IFC Beam 3FDDF855-154C-4F76-8819-6CBF0826A86B | -90 | AC_Pset_IFC_Beam_3FDDF855-154C-4F76-8819-6CBF0826A86B - Contour Pen: Eléments 2D - Général; Fill Type: Background Fill-International; Fill Pen: Fond - Couleur 1; Fill Background Pen: Fond - Couleur 1; Cost: 0; Group Type: Others; Type de groupe: 25; Object Weight: 0; Object Weight Unit: kg; IFC Material: 07 | Spanish Tile; AC_Equantity_IFC_Beam_3FDDF855-154C-4F76-8819-6CBF0826A86B - Dimension 1: 1 m; Dimension 2: 1 m; Height: 1 m; Bottom Level: 1 m; Top Level: 0 m
BEAM | 19588.9 | 27939.2 | 64654.6 | +19.229 | +19.762 | B/593(?) | 15248169 | 2550332 | IFC Beam 6E4A7AAD-44DD-43CA-BBB9-2BEAA058AF3A | 97.6 | AC_Pset_IFC_Beam_6E4A7AAD-44DD-43CA-BBB9-2BEAA058AF3A - Contour Pen: Eléments 2D - Général; Fill Type: Background Fill-International; Fill Pen: Fond - Couleur 1; Fill Background Pen: Fond - Couleur 1; Cost: 0; Group Type: Others; Type de groupe: 25; Object Weight: 0; Object Weight Unit: kg; IFC Material: 07 | Spanish Tile; AC_Equantity_IFC_Beam_6E4A7AAD-44DD-43CA-BBB9-2BEAA058AF3A - Dimension 1: 1 m; Dimension 2: 1 m; Height: 1 m; Bottom Level: 1 m; Top Level: 0 m
BEAM | 19588.9 | 27665.5 | 62602.8 | +19.229 | +19.762 | B/596(?) | 15248169 | 2550332 | IFC Beam 0376F248-F389-44C0-991B-D3C7ED58CA60 | 97.6 | AC_Pset_IFC_Beam_0376F248-F389-44C0-991B-D3C7ED58CA60 - Contour Pen: Eléments 2D - Général; Fill Type: Background Fill-International; Fill Pen: Fond - Couleur 1; Fill Background Pen: Fond - Couleur 1; Cost: 0; Group Type: Others; Type de groupe: 25; Object Weight: 0; Object Weight Unit: kg; IFC Material: 07 | Spanish Tile; AC_Equantity_IFC_Beam_0376F248-F389-44C0-991B-D3C7ED58CA60 - Dimension 1: 1 m; Dimension 2: 1 m; Height: 1 m; Bottom Level: 1 m; Top Level: 0 m
BEAM | 19588.9 | 18705.2 | 66689.2 | +19.229 | +19.762 | B/595(?) | 15248168 | 2550332 | IFC Beam DF3DA8A2-0B6C-452F-8640-2FB6D51E3C50 | 7.6 | AC_Pset_IFC_Beam_DF3DA8A2-0B6C-452F-8640-2FB6D51E3C50 - Contour Pen: Eléments 2D - Général; Fill Type: Background Fill-International; Fill Pen: Fond - Couleur 1; Fill Background Pen: Fond - Couleur 1; Cost: 0; Group Type: Others; Type de groupe: 25; Object Weight: 0; Object Weight Unit: kg; IFC Material: 07 | Spanish Tile; AC_Equantity_IFC_Beam_DF3DA8A2-0B6C-452F-8640-2FB6D51E3C50 - Dimension 1: 1 m; Dimension 2: 1 m; Height: 1 m; Bottom Level: 1 m; Top Level: 0 m
BEAM | 19588.9 | 14053.9 | 67300 | +19.229 | +19.762 | B/595(?) | 15248168 | 2550332 | IFC Beam AD47241C-6B34-4C66-A925-06E6CC1A0111 | 7.6 | AC_Pset_IFC_Beam_AD47241C-6B34-4C66-A925-06E6CC1A0111 - Contour Pen: Eléments 2D - Général; Fill Type: Background Fill-International; Fill Pen: Fond - Couleur 1; Fill Background Pen: Fond - Couleur 1; Cost: 0; Group Type: Others; Type de groupe: 25; Object Weight: 0; Object Weight Unit: kg; IFC Material: 07 | Spanish Tile; AC_Equantity_IFC_Beam_AD47241C-6B34-4C66-A925-06E6CC1A0111 - Dimension 1: 1 m; Dimension 2: 1 m; Height: 1 m; Bottom Level: 1 m; Top Level: 0 m
BEAM | 19588.9 | 9403.9 | 67920.4 | +19.229 | +19.762 | B/595(?) | 15248168 | 2550331 | IFC Beam 5D250349-0A12-4F45-A130-49F93D5FC557 | 7.6 | AC_Pset_IFC_Beam_5D250349-0A12-4F45-A130-49F93D5FC557 - Contour Pen: Eléments 2D - Général; Fill Type: Background Fill-International; Fill Pen: Fond - Couleur 1; Fill Background Pen: Fond - Couleur 1; Cost: 0; Group Type: Others; Type de groupe: 25; Object Weight: 0; Object Weight Unit: kg; IFC Material: 07 | Spanish Tile; AC_Equantity_IFC_Beam_5D250349-0A12-4F45-A130-49F93D5FC557 - Dimension 1: 1 m; Dimension 2: 1 m; Height: 1 m; Bottom Level: 1 m; Top Level: 0 m
BEAM | 19588.9 | -778.662 | 68486.5 | +19.229 | +19.762 | B/591(?) | 15248169 | 2550332 | IFC Beam E29CFB2B-4941-43D1-8E87-5F7E310EBEF2 | -82.4018 | AC_Pset_IFC_Beam_E29CFB2B-4941-43D1-8E87-5F7E310EBEF2 - Contour Pen: Eléments 2D - Général; Fill Type: Background Fill-International; Fill Pen: Fond - Couleur 1; Fill Background Pen: Fond - Couleur 1; Cost: 0; Group Type: Others; Type de groupe: 25; Object Weight: 0; Object Weight Unit: kg; IFC Material: 07 | Spanish Tile; AC_Equantity_IFC_Beam_E29CFB2B-4941-43D1-8E87-5F7E310EBEF2 - Dimension 1: 1 m; Dimension 2: 1 m; Height: 1 m; Bottom Level: 1 m; Top Level: 0 m
BEAM | 19588.9 | -785.56 | 37359.7 | +19.229 | +19.762 | B/595(?) | 15248169 | 2550332 | IFC Beam CB83B1B8-4510-4357-8497-49179DBB5492 | -90 | AC_Pset_IFC_Beam_CB83B1B8-4510-4357-8497-49179DBB5492 - Contour Pen: Eléments 2D - Général; Fill Type: Background Fill-International; Fill Pen: Fond - Couleur 1; Fill Background Pen: Fond - Couleur 1; Cost: 0; Group Type: Others; Type de groupe: 25; Object Weight: 0; Object Weight Unit: kg; IFC Material: 07 | Spanish Tile; AC_Equantity_IFC_Beam_CB83B1B8-4510-4357-8497-49179DBB5492 - Dimension 1: 1 m; Dimension 2: 1 m; Height: 1 m; Bottom Level: 1 m; Top Level: 0 m
BEAM | 19589 | -785.56 | 42234.7 | +19.230 | +19.763 | B/595(?) | 15248169 | 2550332 | IFC Beam 30843C20-7F3A-4699-8F4B-53C472F7902D | -90 | AC_Pset_IFC_Beam_30843C20-7F3A-4699-8F4B-53C472F7902D - Contour Pen: Eléments 2D - Général; Fill Type: Background Fill-International; Fill Pen: Fond - Couleur 1; Fill Background Pen: Fond - Couleur 1; Cost: 0; Group Type: Others; Type de groupe: 25; Object Weight: 0; Object Weight Unit: kg; IFC Material: 07 | Spanish Tile; AC_Equantity_IFC_Beam_30843C20-7F3A-4699-8F4B-53C472F7902D - Dimension 1: 1 m; Dimension 2: 1 m; Height: 1 m; Bottom Level: 1 m; Top Level: 0 m
BEAM | 19589 | -785.56 | 61609.7 | +19.230 | +19.763 | B/595(?) | 15248169 | 2550332 | IFC Beam FE3D1B2D-54E1-4488-A4C8-591FD77DE250 | -90 | AC_Pset_IFC_Beam_FE3D1B2D-54E1-4488-A4C8-591FD77DE250 - Contour Pen: Eléments 2D - Général; Fill Type: Background Fill-International; Fill Pen: Fond - Couleur 1; Fill Background Pen: Fond - Couleur 1; Cost: 0; Group Type: Others; Type de groupe: 25; Object Weight: 0; Object Weight Unit: kg; IFC Material: 07 | Spanish Tile; AC_Equantity_IFC_Beam_FE3D1B2D-54E1-4488-A4C8-591FD77DE250 - Dimension 1: 1 m; Dimension 2: 1 m; Height: 1 m; Bottom Level: 1 m; Top Level: 0 m
BEAM | 19588.9 | -785.56 | 56859.7 | +19.229 | +19.762 | B/595(?) | 15248169 | 2550332 | IFC Beam F3B2D20F-C953-4AC1-92AB-B673CBFCACD5 | -90 | AC_Pset_IFC_Beam_F3B2D20F-C953-4AC1-92AB-B673CBFCACD5 - Contour Pen: Eléments 2D - Général; Fill Type: Background Fill-International; Fill Pen: Fond - Couleur 1; Fill Background Pen: Fond - Couleur 1; Cost: 0; Group Type: Others; Type de groupe: 25; Object Weight: 0; Object Weight Unit: kg; IFC Material: 07 | Spanish Tile; AC_Equantity_IFC_Beam_F3B2D20F-C953-4AC1-92AB-B673CBFCACD5 - Dimension 1: 1 m; Dimension 2: 1 m; Height: 1 m; Bottom Level: 1 m; Top Level: 0 m
BEAM | 19589 | -785.56 | 51984.7 | +19.230 | +19.763 | B/595(?) | 15248169 | 2550332 | IFC Beam C6684523-284A-413B-BBFF-6E87432DFF51 | -90 | AC_Pset_IFC_Beam_C6684523-284A-413B-BBFF-6E87432DFF51 - Contour Pen: Eléments 2D - Général; Fill Type: Background Fill-International; Fill Pen: Fond - Couleur 1; Fill Background Pen: Fond - Couleur 1; Cost: 0; Group Type: Others; Type de groupe: 25; Object Weight: 0; Object Weight Unit: kg; IFC Material: 07 | Spanish Tile; AC_Equantity_IFC_Beam_C6684523-284A-413B-BBFF-6E87432DFF51 - Dimension 1: 1 m; Dimension 2: 1 m; Height: 1 m; Bottom Level: 1 m; Top Level: 0 m
BEAM | 19588.9 | 4753.9 | 68540.9 | +19.229 | +19.762 | B/595(?) | 15248168 | 2550331 | IFC Beam DB1B9199-4AFA-4E28-B072-E42F7D0BA569 | 7.6 | AC_Pset_IFC_Beam_DB1B9199-4AFA-4E28-B072-E42F7D0BA569 - Contour Pen: Eléments 2D - Général; Fill Type: Background Fill-International; Fill Pen: Fond - Couleur 1; Fill Background Pen: Fond - Couleur 1; Cost: 0; Group Type: Others; Type de groupe: 25; Object Weight: 0; Object Weight Unit: kg; IFC Material: 07 | Spanish Tile; AC_Equantity_IFC_Beam_DB1B9199-4AFA-4E28-B072-E42F7D0BA569 - Dimension 1: 1 m; Dimension 2: 1 m; Height: 1 m; Bottom Level: 1 m; Top Level: 0 m
BEAM | 19589 | -785.56 | 33307.5 | +19.230 | +19.763 | B/595(?) | 15248169 | 2550332 | IFC Beam CB54A826-F254-4EDA-8C11-8B536EE12554 | -90 | AC_Pset_IFC_Beam_CB54A826-F254-4EDA-8C11-8B536EE12554 - Contour Pen: Eléments 2D - Général; Fill Type: Background Fill-International; Fill Pen: Fond - Couleur 1; Fill Background Pen: Fond - Couleur 1; Cost: 0; Group Type: Others; Type de groupe: 25; Object Weight: 0; Object Weight Unit: kg; IFC Material: 07 | Spanish Tile; AC_Equantity_IFC_Beam_CB54A826-F254-4EDA-8C11-8B536EE12554 - Dimension 1: 1 m; Dimension 2: 1 m; Height: 1 m; Bottom Level: 1 m; Top Level: 0 m

# IfcBeam: PHI533-200-10-14*210-14*210 (6)
In: Rez de chaussée
Description: PHI533-200-10-14*210-14*210; Material: 50 %
Tekla Common - Bottom elevation: +19.267; Top elevation: +19.800; Part mark: M/0(?); Phase: 1; Class: 3; Grade: S275; Profile: PHI533-200-10-14*210-14*210; Name: BEAM
Tekla Quantity - Net weight: 0 g; Gross weight: 0 g; Weight: 0 g; Net volume: 15840961 m3; Gross volume: 15840961 m3; Gross footprint area: 357000 m2; Net surface area: 2671982 m2; Gross area: 2671982 m2; Height: 533 m; Width: 210 m; Length: 1700 m
ArchiCADProperties - ID: BEAM; Etage d'implantation: Rez de chaussée; Calque: A-BEAM; Type: Objet; Verrouillé: no; Matériau de construction / Composite / Profil / Hachure: 50 %; Classification d'lément: Type ArchiCAD; Etat de rénovation: Existant; Afficher sur filtre de rénovation: Tous les filtres appropriés; Angle de rotation: -90 deg; Surface: Mtl-Stainless Steel
AC_Pset_RenovationAndPhasing - Renovation Status: Existing
ArchiCADQuantities - Superficie de surface: 2.67198 m2; Volume net: 0.0158409 m3; Superficie: 1 m2; Hauteur (Taille en Z): 1 m; Longueur (A): 1 m; Volume: 0.0158409 m3; Largeur (B): 1 m
Name | Center of gravity Z (m) | Center of gravity Y (m) | Center of gravity X (m) | Assembly mark | Nom Elément de Bibliothèque | Fonction structurelle | Position | LoadBearing = IsExternal | Altitude à Zéro du Projet (m) = Altitude à étage (m)
BEAM | 19610.9 | -799.373 | 4875 | B/590(?) | IFC Beam 4494EBF5-99DF-4DFF-8A58-51AB8CA3FADE | Elément porteur | Extérieur | yes | 19.025 | AC_Pset_IFC_Beam_4494EBF5-99DF-4DFF-8A58-51AB8CA3FADE - Contour Pen: Eléments 2D - Général; Fill Type: Background Fill-International; Fill Pen: Fond - Couleur 1; Fill Background Pen: Fond - Couleur 1; Cost: 0; Group Type: Others; Type de groupe: 25; Object Weight: 0; Object Weight Unit: kg; IFC Material: 07 | Spanish Tile; AC_Equantity_IFC_Beam_4494EBF5-99DF-4DFF-8A58-51AB8CA3FADE - Dimension 1: 1 m; Dimension 2: 1 m; Height: 1 m; Bottom Level: 1 m; Top Level: 0 m
BEAM | 19610.9 | -799.373 | 14625 | B/590(?) | IFC Beam 824B5283-3665-43B5-B57B-16A2EC6BFAAB | Elément porteur | Extérieur | yes | 19.025 | AC_Pset_IFC_Beam_824B5283-3665-43B5-B57B-16A2EC6BFAAB - Contour Pen: Eléments 2D - Général; Fill Type: Background Fill-International; Fill Pen: Fond - Couleur 1; Fill Background Pen: Fond - Couleur 1; Cost: 0; Group Type: Others; Type de groupe: 25; Object Weight: 0; Object Weight Unit: kg; IFC Material: 07 | Spanish Tile; AC_Equantity_IFC_Beam_824B5283-3665-43B5-B57B-16A2EC6BFAAB - Dimension 1: 1 m; Dimension 2: 1 m; Height: 1 m; Bottom Level: 1 m; Top Level: 0 m
BEAM | 19610.8 | -799.373 | 9750 | B/590(?) | IFC Beam 97B1B40D-602A-4041-9CD9-6F6EEB14CD4B | Elément porteur | Extérieur | yes | 19.025 | AC_Pset_IFC_Beam_97B1B40D-602A-4041-9CD9-6F6EEB14CD4B - Contour Pen: Eléments 2D - Général; Fill Type: Background Fill-International; Fill Pen: Fond - Couleur 1; Fill Background Pen: Fond - Couleur 1; Cost: 0; Group Type: Others; Type de groupe: 25; Object Weight: 0; Object Weight Unit: kg; IFC Material: 07 | Spanish Tile; AC_Equantity_IFC_Beam_97B1B40D-602A-4041-9CD9-6F6EEB14CD4B - Dimension 1: 1 m; Dimension 2: 1 m; Height: 1 m; Bottom Level: 1 m; Top Level: 0 m
BEAM | 19610.9 | -799.163 | 19507.5 | B/590(?) | IFC Beam 7B7CAE2F-ED8E-439A-8E55-D99453439C67 | Non défini | Non défini |  | 19.0251 | AC_Pset_IFC_Beam_7B7CAE2F-ED8E-439A-8E55-D99453439C67 - Contour Pen: Eléments 2D - Général; Fill Type: Background Fill-International; Fill Pen: Fond - Couleur 1; Fill Background Pen: Fond - Couleur 1; Cost: 0; Group Type: Others; Type de groupe: 25; Object Weight: 0; Object Weight Unit: kg; IFC Material: 07 | Spanish Tile; AC_Equantity_IFC_Beam_7B7CAE2F-ED8E-439A-8E55-D99453439C67 - Dimension 1: 1 m; Dimension 2: 1 m; Height: 1 m; Bottom Level: 1 m; Top Level: 0 m
BEAM | 19610.8 | -799.373 | 19500 | B/590(?) | IFC Beam 15229522-8FC6-4F9A-B1B1-672EAB7E8F32 | Elément porteur | Extérieur | yes | 19.025 | AC_Pset_IFC_Beam_15229522-8FC6-4F9A-B1B1-672EAB7E8F32 - Contour Pen: Eléments 2D - Général; Fill Type: Background Fill-International; Fill Pen: Fond - Couleur 1; Fill Background Pen: Fond - Couleur 1; Cost: 0; Group Type: Others; Type de groupe: 25; Object Weight: 0; Object Weight Unit: kg; IFC Material: 07 | Spanish Tile; AC_Equantity_IFC_Beam_15229522-8FC6-4F9A-B1B1-672EAB7E8F32 - Dimension 1: 1 m; Dimension 2: 1 m; Height: 1 m; Bottom Level: 1 m; Top Level: 0 m
BEAM | 19610.9 | -799.163 | 24382.5 | B/589(?) | IFC Beam 3AD8FF48-429B-4184-B807-78002E85085D | Elément porteur | Extérieur | yes | 19.025 | AC_Pset_IFC_Beam_3AD8FF48-429B-4184-B807-78002E85085D - Contour Pen: Eléments 2D - Général; Fill Type: Background Fill-International; Fill Pen: Fond - Couleur 1; Fill Background Pen: Fond - Couleur 1; Cost: 0; Group Type: Others; Type de groupe: 25; Object Weight: 0; Object Weight Unit: kg; IFC Material: 07 | Spanish Tile; AC_Equantity_IFC_Beam_3AD8FF48-429B-4184-B807-78002E85085D - Dimension 1: 1 m; Dimension 2: 1 m; Height: 1 m; Bottom Level: 1 m; Top Level: 0 m

# IfcBeam: UPE120 (20)
In: Rez de chaussée
Description: A_Beam; Material: STEEL/S235JRG2 3386696625
ArchiCADProperties - ID: Poutre; Etage d'implantation: Rez de chaussée; Calque: A-BEAM; Type: Poutre; Verrouillé: no; Matériau de construction / Composite / Profil / Hachure: UPE120 0000000000; Fonction structurelle: Elément porteur; Position: Extérieur; Classification d'lément: Poutre; Etat de rénovation: Existant; Afficher sur filtre de rénovation: Tous les filtres appropriés; Type de structure: Profil complexe; Matériau de construction / Profil: UPE120 0000000000; Angle d'inclinaison de poutre: 0 deg; Coupe transversale de poutre: Profilé
AC_Pset_RenovationAndPhasing - Renovation Status: Existing
Pset_BeamCommon - LoadBearing: yes; IsExternal: yes; Reference: UPE120 0000000000 60 x 120
BaseQuantities - CrossSectionArea: 0.00154181 m2
ArchiCADQuantities - Altitude à Zéro du Projet: 19.045 m; Altitude à étage: 19.045 m; Hauteur: 0.12 m; Surface des trous: 0 m2; Surface des arêtes de trou: 0 m2; Nombre de trous: 0; Volume des trous: 0 m3; Largeur des trous: 0 m; Hauteur du trou: 0 m; Niveau du trou: 0 m; Largeur: 0.06 m; Décalage: 0 m
Name | NetSurfaceAreaExtrudedSides (m2) = OuterSurfaceArea (m2) | Length (m) = Longueur droite (m) = Longueur gauche (m) | TotalSurfaceArea (m2) = GrossSurfaceArea (m2) | GrossVolume (m3) = NetVolume (m3) = Volume net (m3) = Volume (m3) = Volume conditionnel (m3) | Superficie de surface (m2) | Superficie (m2) = Surface inférieure (m2) | Surface supérieure (m2) | Surface côté gauche (m2) | Surface côté droit (m2) | Surface de fin (m2)
7 x Poutre | 2.23635 | 4.875 | 2.23943 | 0.00762622 | 2.23947 | 0.502125 | 0.502125 | 0.647096 | 0.585 | 0.00312871
Poutre | 1.85891 | 4.05222 | 1.86199 | 0.0063391 | 1.86203 | 0.417379 | 0.417379 | 0.537882 | 0.486267 | 0.00312871
Poutre | 1.85789 | 4.05 | 1.86097 | 0.00633563 | 1.86102 | 0.41715 | 0.41715 | 0.537587 | 0.486 | 0.00312871
Poutre | 2.23977 | 4.88246 | 2.24285 | 0.0076379 | 2.2429 | 0.502894 | 0.502894 | 0.648086 | 0.585896 | 0.00312871
Poutre | 2.23734 | 4.88246 | 2.24043 | 0.00762641 | 2.23893 | 0.502128 | 0.502128 | 0.648086 | 0.585 | 0.00158951
Poutre | 1.97528 | 4.34 | 1.97837 | 0.00672805 | 1.97685 | 0.440843 | 0.440843 | 0.519236 | 0.574363 | 0.00156435
Poutre | 2.15204 | 4.69122 | 2.15512 | 0.00733872 | 2.15517 | 0.483196 | 0.483196 | 0.562946 | 0.622701 | 0.00312871
2 x Poutre | 2.15203 | 4.69121 | 2.15512 | 0.00733871 | 2.15516 | 0.483195 | 0.483195 | 0.562945 | 0.6227 | 0.00312871
Poutre | 3.03425 | 6.61436 | 3.03734 | 0.0103472 | 3.03738 | 0.681279 | 0.681279 | 0.793723 | 0.877974 | 0.00312871
Poutre | 3.76039 | 8.65461 | 3.76347 | 0.0128228 | 3.76195 | 0.844209 | 0.844202 | 0.983805 | 1.08817 | 0.00156435 | ArchiCADProperties - Nom de Zone: Dégagement; Numéro de Zone: 001
Poutre | 2.17899 | 4.75 | 2.18208 | 0.00743061 | 2.18056 | 0.489243 | 0.48925 | 0.630502 | 0.57 | 0.00156435
Poutre | 3.98093 | 8.7124 | 3.98401 | 0.0135672 | 3.98406 | 0.891144 | 0.891144 | 1.15473 | 1.04391 | 0.00312871
Poutre | 0.617002 | 1.7 | 0.620086 | 0.00210405 | 0.620131 | 0.138535 | 0.138535 | 0.1614 | 0.178532 | 0.00312871

# IfcBeam: UPE200 (9)
In: Rez de chaussée
Description: A_Beam; Material: STEEL/S235JRG2 3386696625
ArchiCADProperties - ID: BEAM; Etage d'implantation: Rez de chaussée; Calque: A-BEAM; Type: Poutre; Verrouillé: no; Matériau de construction / Composite / Profil / Hachure: UPE200 0000000000; Fonction structurelle: Elément porteur; Position: Non défini; Classification d'lément: Poutre; Etat de rénovation: Existant; Afficher sur filtre de rénovation: Tous les filtres appropriés; Type de structure: Profil complexe; Matériau de construction / Profil: UPE200 0000000000; Angle d'inclinaison de poutre: 0 deg; Coupe transversale de poutre: Profilé
AC_Pset_RenovationAndPhasing - Renovation Status: Existing
Pset_BeamCommon - LoadBearing: yes; Reference: UPE200 0000000000 80 x 200
BaseQuantities - CrossSectionArea: 0.00290054 m2
ArchiCADQuantities - Altitude à Zéro du Projet: 11.65 m; Altitude à étage: 11.65 m; Hauteur: 0.2 m; Surface des trous: 0 m2; Surface des arêtes de trou: 0 m2; Nombre de trous: 0; Volume des trous: 0 m3; Largeur des trous: 0 m; Hauteur du trou: 0 m; Niveau du trou: 0 m; Largeur: 0.08 m; Décalage: 0 m
Name | NetSurfaceAreaExtrudedSides (m2) = OuterSurfaceArea (m2) | Length (m) = Longueur droite (m) = Longueur gauche (m) | TotalSurfaceArea (m2) = GrossSurfaceArea (m2) | GrossVolume (m3) = NetVolume (m3) = Volume net (m3) = Volume (m3) = Volume conditionnel (m3) | Superficie de surface (m2) | Superficie (m2) = Surface inférieure (m2) = Surface supérieure (m2) | Surface côté gauche (m2) | Surface côté droit (m2) | Surface de fin (m2)
BEAM | 2.7054 | 4.0514 | 2.7112 | 0.0112859 | 2.70579 | 0.543635 | 0.827855 | 0.790272 | 0.000397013
BEAM | 3.26362 | 4.87663 | 3.26942 | 0.0136301 | 3.26372 | 0.660262 | 1.00687 | 0.936233 | 0.0000930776
BEAM | 3.27967 | 4.87663 | 3.28547 | 0.013651 | 3.27971 | 0.660087 | 1.00484 | 0.954659 | 0.0000336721
BEAM | 3.28019 | 4.87663 | 3.286 | 0.0136521 | 3.28022 | 0.660043 | 1.00479 | 0.95532 | 0.0000266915
2 x BEAM | 3.27967 | 4.87663 | 3.28547 | 0.0136493 | 3.27967 | 0.65979 | 1.00477 | 0.95532 | 0
BEAM | 2.7181 | 4.0514 | 2.7239 | 0.0112585 | 2.71849 | 0.543261 | 0.826193 | 0.805382 | 0.000397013
BEAM | 3.27979 | 4.87663 | 3.2856 | 0.0136625 | 3.27993 | 0.659855 | 1.00476 | 0.955319 | 0.000132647
BEAM | 3.27966 | 4.87663 | 3.28546 | 0.0136493 | 3.27966 | 0.659789 | 1.00477 | 0.955319 | 0

# IfcBuildingElementPart (45)
Name | In | Material
 | Rez de chaussée | Finition int - Enduit plâtre
 | Rez de chaussée | Métal - Acier
3 x  | R+1 | Finition ext - Crépis
3 x  | R+1 | Isolation - Fibres de bois
4 x  | R+1 | Struct. - B.A. banché
4 x  | R+1 | Finition int - Enduit plâtre
 | R+1 | Lame d'air
 | R+1 | Isolation - Laine de verre
 | R+1 | Finition int - Enduit minéral
2 x  | Mezzannine | Finition ext - Crépis
2 x  | Mezzannine | Isolation - Fibres de bois
3 x  | Mezzannine | Struct. - B.A. banché
3 x  | Mezzannine | Finition int - Enduit plâtre
 | Mezzannine | Lame d'air
 | Mezzannine | Isolation - Laine de verre
 | Mezzannine | Finition int - Enduit minéral
2 x  | R+2 | Finition ext - Crépis
2 x  | R+2 | Isolation - Fibres de bois
3 x  | R+2 | Struct. - B.A. banché
3 x  | R+2 | Finition int - Enduit plâtre
 | R+2 | Lame d'air
 | R+2 | Isolation - Laine de verre
 | R+2 | Finition int - Enduit minéral

# IfcColumn: HEB160 (37)
In: Rez de chaussée
Description: A_col; Material: STEEL/S235JRG2 3386696625
ArchiCADProperties - ID: Column; Etage d'implantation: Rez de chaussée; Calque: A-COLS; Type: Poteau; Verrouillé: no; Matériau de construction / Composite / Profil / Hachure: STEEL/S235JRG2 3386696625; Classification d'lément: Type ArchiCAD; Etat de rénovation: Existant; Afficher sur filtre de rénovation: Tous les filtres appropriés; Type de structure: Basique; Matériau de construction / Profil: STEEL/S235JRG2 3386696625; Surface: STEEL/S235JRG2 1; Angle d'inclinaison de poteau: 90 deg; Coupe transversale de poteau: Rectangulaire; Etage supérieur lié: Non lié
AC_Pset_RenovationAndPhasing - Renovation Status: Existing
Pset_ColumnCommon - Reference: STEEL/S235JRG2 3386696625 160 x 160
BaseQuantities - Width: 0.16 m; Depth: 0.16 m; CrossSectionArea: 0.0256 m2
ArchiCADQuantities - Superficie: 0.0256 m2; Surface du revêtement: 0 m2; Volume net du revêtement: 0 m3; Dimensions Ame: 0.16 m; 2ème dimension âme: 0.16 m; Périmètre du Poteau: 0.64 m; Surface du Poteau: 0.0256 m2; Surface brute du revêtement (sans haut/bas): 0 m2; Volume brut du revêtement: 0 m3; Surface nette du haut du Revêtement: 0 m2; Surface nette du bas du Revêtement: 0 m2; Surface brute du haut (ou bas) de l'âme: 0.0256 m2; Surface brute du haut (ou bas) du revêtement: 0 m2; Décalage supérieur: 0 m
Name | Nom de Zone | Numéro de Zone | Fonction structurelle | Position | Length (m) = Hauteur (m) = Hauteur maximum Poteau (m) | OuterSurfaceArea (m2) = Superficie de surface (m2) = Surface nette de l'âme (sans haut/bas) (m2) | TotalSurfaceArea (m2) = GrossSurfaceArea (m2) | GrossVolume (m3) = NetVolume (m3) = Volume net (m3) = Volume net de l'Ame (m3) = Volume du Poteau (m3) | Altitude à Zéro du Projet (m) = Altitude à étage (m) = Décalage étage d'implantation (m) | Hauteur minimum du Poteau (m) | Volume brut du Poteau (m3) = Volume brut de l'Ame (m3) | Surface brute de l'âme (sans haut/bas) (m2) | Surface nette du haut de l'Ame (m2) | Surface nette du bas de l'Ame (m2) | LoadBearing | IsExternal
Column | Plateau bureaux | 005 | Non défini | Non défini | 1.925 | 0.721468 | 0.762268 | 0.0309713 | 17.1707 | 0 | 0.04928 | 1.232 | 0.0256 | 0.0152
Column | Plateau bureaux | 005 | Elément non porteur | Extérieur | 1.925 | 0.747907 | 0.789536 | 0.0327112 | 17.2 | 0 | 0.04928 | 1.232 | 0.0256 | 0.0160289 | no | yes
Column | Plateau bureaux | 005 | Elément non porteur | Extérieur | 1.925 | 0.72998 | 0.77078 | 0.0312765 | 17.2 | 0 | 0.04928 | 1.232 | 0.0256 | 0.0152 | no | yes
Column | Plateau bureaux | 005 | Elément non porteur | Extérieur | 1.925 | 0.746824 | 0.788403 | 0.0326245 | 17.2 | 0 | 0.04928 | 1.232 | 0.0256 | 0.0159789 | no | yes
Column | Plateau bureaux | 005 | Elément non porteur | Extérieur | 1.925 | 0.452859 | 0.487481 | 0.0205816 | 17.2 | 0 | 0.04928 | 1.232 | 0.0256 | 0.00902214 | no | yes
Column |  |  | Elément non porteur | Extérieur | 1.925 | 1.232 | 1.2832 | 0.04928 | 17.2 | 1.925 | 0.04928 | 1.232 | 0.0256 | 0.0256 | no | yes
18 x Column | Plateau bureaux | 005 | Elément porteur | Extérieur | 1.965 | 1.2576 | 1.3088 | 0.050304 | 17.16 | 1.965 | 0.050304 | 1.2576 | 0.0256 | 0.0256 | yes | yes
Column | Plateau bureaux | 005 | Elément non porteur | Extérieur | 1.925 | 0.720238 | 0.760589 | 0.0304977 | 17.2 | 0 | 0.04928 | 1.232 | 0.0256 | 0.0147503 | no | yes
Column | Plateau bureaux | 005 | Elément non porteur | Extérieur | 1.925 | 0.738829 | 0.780039 | 0.0319849 | 17.2 | 0 | 0.04928 | 1.232 | 0.0256 | 0.0156094 | no | yes
Column | Plateau bureaux | 005 | Elément non porteur | Extérieur | 1.925 | 1.00751 | 1.0545 | 0.0419876 | 17.2 | 0 | 0.04928 | 1.232 | 0.0256 | 0.0213874 | no | yes
Column | Plateau bureaux | 005 | Elément non porteur | Extérieur | 1.925 | 0 | 0 | 0 | 17.2 | 1.925 | 0.04928 | 1.232 | 0 | 0 | no | yes
Column | Plateau bureaux | 005 | Elément non porteur | Extérieur | 1.925 | 0.72997 | 0.77077 | 0.0312762 | 17.2 | 0 | 0.04928 | 1.232 | 0.0256 | 0.0152 | no | yes
Column |  |  | Elément non porteur | Extérieur | 1.925 | 0.773278 | 0.81195 | 0.0372222 | 17.2 | 0 | 0.04928 | 1.232 | 0.0193362 | 0.0193362 | no | yes
Column | Plateau bureaux | 005 | Elément non porteur | Extérieur | 1.925 | 0.72997 | 0.77077 | 0.0312761 | 17.2 | 0 | 0.04928 | 1.232 | 0.0256 | 0.0152 | no | yes
Column | Plateau bureaux | 005 | Elément non porteur | Extérieur | 1.925 | 0.835272 | 0.877172 | 0.0331808 | 17.2 | 0 | 0.04928 | 1.232 | 0.0256 | 0.0163002 | no | yes
Column | Plateau bureaux | 005 | Elément non porteur | Extérieur | 1.925 | 0.777329 | 0.820318 | 0.0350649 | 17.2 | 0 | 0.04928 | 1.232 | 0.0256 | 0.0173886 | no | yes
Column | Plateau bureaux | 005 | Elément non porteur | Extérieur | 1.925 | 0.729998 | 0.770799 | 0.0312779 | 17.2 | 0 | 0.04928 | 1.232 | 0.0256 | 0.0152008 | no | yes
Column | Plateau bureaux | 005 | Elément non porteur | Extérieur | 1.925 | 0.374541 | 0.404879 | 0.0131647 | 17.2 | 0 | 0.04928 | 1.232 | 0.0256 | 0.00473774 | no | yes
Column | Plateau bureaux | 005 | Elément non porteur | Extérieur | 1.925 | 0.73175 | 0.77255 | 0.03134 | 17.2 | 0.2 | 0.04928 | 1.232 | 0.0152 | 0.0256 | no | yes
Column | Plateau bureaux | 005 | Elément non porteur | Extérieur | 1.925 | 0.166956 | 0.189436 | 0.00595913 | 17.2 | 0 | 0.04928 | 1.232 | 0.0214388 | 0.00104152 | no | yes

# IfcColumn: HEB260 (7)
In: Rez de chaussée
ArchiCADProperties - Etage d'implantation: Rez de chaussée; Calque: A-COLS; Type: Poteau; Verrouillé: no; Classification d'lément: Type ArchiCAD; Etat de rénovation: Existant; Afficher sur filtre de rénovation: Tous les filtres appropriés; Type de structure: Basique; Angle d'inclinaison de poteau: 90 deg; Etage supérieur lié: Non lié
AC_Pset_RenovationAndPhasing - Renovation Status: Existing
ArchiCADQuantities - Surface nette du bas du Revêtement: 0 m2; Décalage supérieur: 0 m
Name | Description | Material | Reference | LoadBearing | IsExternal | GUID | RepËre de piËce = RepËre d'assemblage | Phase | Classe | MatÈriau | Profil | Nom | ID | Matériau de construction / Composite / Profil / Hachure = Matériau de construction / Profil | Fonction structurelle | Position | Surface | Coupe transversale de poteau | Length (m) = Hauteur (m) = Hauteur maximum Poteau (m) | CrossSectionArea (m2) | OuterSurfaceArea (m2) = Surface nette de l'âme (sans haut/bas) (m2) | TotalSurfaceArea (m2) = GrossSurfaceArea (m2) | GrossVolume (m3) = NetVolume (m3) = Volume net (m3) = Volume du Poteau (m3) | Altitude à Zéro du Projet (m) = Altitude à étage (m) = Décalage étage d'implantation (m) | Superficie de surface (m2) | Superficie (m2) = Surface du Poteau (m2) | Surface du revêtement (m2) | Volume net de l'Ame (m3) | Volume net du revêtement (m3) | Dimensions Ame (m) = 2ème dimension âme (m) | Hauteur minimum du Poteau (m) | Périmètre du Poteau (m) | Volume brut du Poteau (m3) | Surface brute de l'âme (sans haut/bas) (m2) | Volume brut de l'Ame (m3) | Surface brute du revêtement (sans haut/bas) (m2) | Volume brut du revêtement (m3) | Surface nette du haut de l'Ame (m2) | Surface nette du bas de l'Ame (m2) | Surface nette du haut du Revêtement (m2) = Surface brute du haut (ou bas) du revêtement (m2) | Surface brute du haut (ou bas) de l'âme (m2) | Nom de Zone | Numéro de Zone | Width (m) = Depth (m)
POTEAU | 260*260 | STEEL/S235JRG2 3386696625 | Pt0(?) | yes | yes | ID551A4115-0000-433D-3134-323737393933 | Pt0(?) | 202 | 13 | C25/30 | 260*260 | POTEAU | POTEAU | STEEL/S235JRG2 3386696625 | Elément porteur | Extérieur | STEEL/S235JRG2 1 | Circulaire | 19.32 | 3.14159 | 28.8711 | 29.2185 | 3.67754 | -0.195 | 28.8711 | 0.19635 | 0 | 3.67754 | 0 | 0.5 | 4.465 | 1.5708 | 3.77424 | 30.3093 | 3.77424 | 0 | 0 | 0.151985 | 0.195354 | 0 | 0.19635
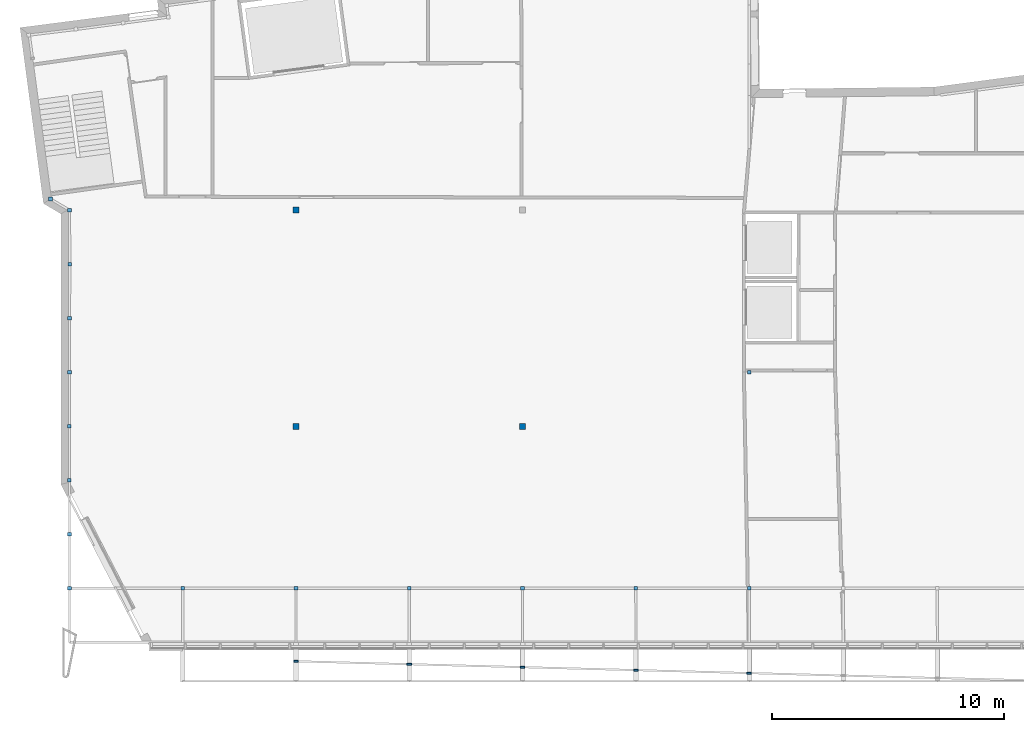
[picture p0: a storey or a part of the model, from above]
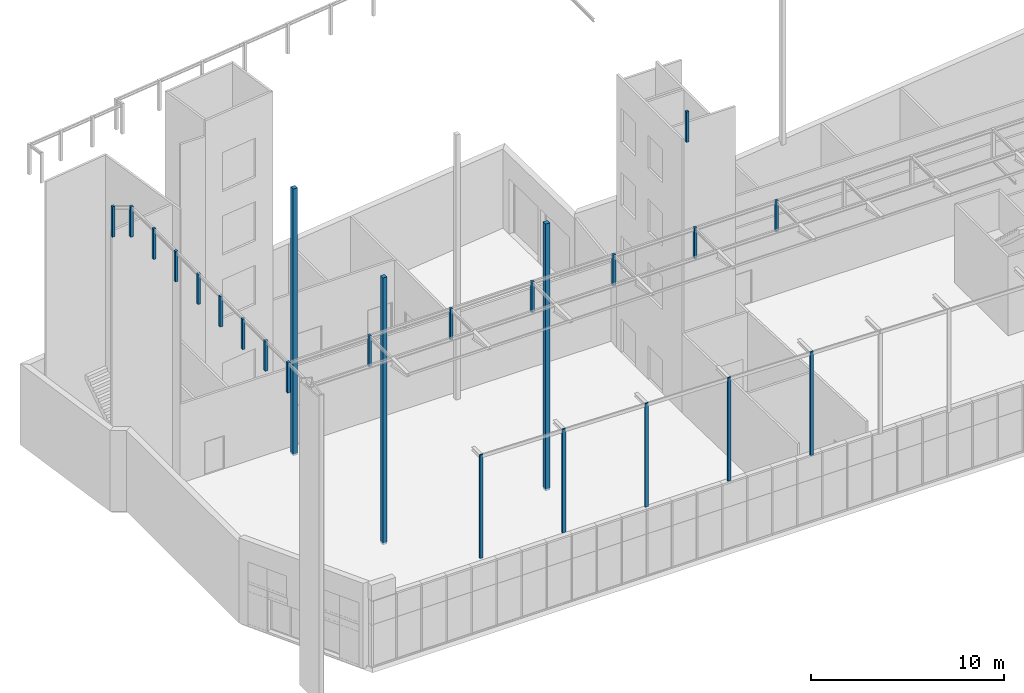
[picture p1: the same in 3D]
Properties of the parts of a building model (IFC2X3), part 2 of 19

# IfcColumn: HEB260 (7)
Name | Description | Material | Reference | LoadBearing | IsExternal | GUID | RepËre de piËce = RepËre d'assemblage | Phase | Classe | MatÈriau | Profil | Nom | ID | Matériau de construction / Composite / Profil / Hachure = Matériau de construction / Profil | Fonction structurelle | Position | Surface | Coupe transversale de poteau | Length (m) = Hauteur (m) = Hauteur maximum Poteau (m) | CrossSectionArea (m2) | OuterSurfaceArea (m2) = Surface nette de l'âme (sans haut/bas) (m2) | TotalSurfaceArea (m2) = GrossSurfaceArea (m2) | GrossVolume (m3) = NetVolume (m3) = Volume net (m3) = Volume du Poteau (m3) | Altitude à Zéro du Projet (m) = Altitude à étage (m) = Décalage étage d'implantation (m) | Superficie de surface (m2) | Superficie (m2) = Surface du Poteau (m2) | Surface du revêtement (m2) | Volume net de l'Ame (m3) | Volume net du revêtement (m3) | Dimensions Ame (m) = 2ème dimension âme (m) | Hauteur minimum du Poteau (m) | Périmètre du Poteau (m) | Volume brut du Poteau (m3) | Surface brute de l'âme (sans haut/bas) (m2) | Volume brut de l'Ame (m3) | Surface brute du revêtement (sans haut/bas) (m2) | Volume brut du revêtement (m3) | Surface nette du haut de l'Ame (m2) | Surface nette du bas de l'Ame (m2) | Surface nette du haut du Revêtement (m2) = Surface brute du haut (ou bas) du revêtement (m2) | Surface brute du haut (ou bas) de l'âme (m2) | Nom de Zone | Numéro de Zone | Width (m) = Depth (m)
Poteau | A_col | Métal - Acier | Métal - Acier 260 x 260 | yes | no |  |  |  |  |  |  |  | Poteau | Métal - Acier | Elément porteur | Intérieur | Métal - Acier | Rectangulaire | 16.9 | 0.0676 | 17.0144 | 17.1496 | 1.10594 | 0 | 17.0144 | 0.0676 | 0 | 1.10594 | 0 | 0.26 | 5.12 | 1.04 | 1.14244 | 17.576 | 1.14244 | 0 | 0 | 0.0676 | 0.0676 | 0 | 0.0676 | Plateau bureaux | 005 | 0.26
POTEAU | 260*260 | Métal - Acier | Pt0(?) | yes | no | ID551A4115-0000-435D-3134-323737393933 | Pt0(?) | 202 | 13 | C25/30 | 260*260 | POTEAU | POTEAU | Métal - Acier | Elément porteur | Intérieur | Métal - Acier | Rectangulaire | 16.9 | 0.0676 | 17.2016 | 17.3368 | 1.1181 | 0 | 17.2016 | 0.0676 | 0 | 1.1181 | 0 | 0.26 | 5.12 | 1.04 | 1.14244 | 17.576 | 1.14244 | 0 | 0 | 0.0676 | 0.0676 | 0 | 0.0676 | Plateau bureaux | 005 | 0.26
POTEAU | 260*260 |  | Pt0(?) | yes | no | ID551A4115-0000-4359-3134-323737393933 | Pt0(?) | 202 | 13 | C25/30 | 260*260 | POTEAU | POTEAU | Métal - Acier | Elément porteur | Intérieur | Métal - Acier | Rectangulaire | 16.9 | 0.0841 | 17.0144 | 17.1496 | 1.35232 | 0 | 17.3754 | 0.0841 | 17.3754 | 1.10594 | 0.246385 | 0.26 | 0.105 | 1.16 | 1.42129 | 17.576 | 1.14244 | 19.604 | 0.27885 | 0.0676 | 0.0676 | 0.0165 | 0.0676 | Plateau bureaux | 005 | 0.275 | ArchiCADProperties - Matériau de construction de revêtement: Finition int - Enduit plâtre; Type de revêtement: Ame
POTEAU | 260*260 | Métal - Acier | Pt0(?) | yes | no | ID551A4115-0000-434D-3134-323737393933 | Pt0(?) | 202 | 13 | C25/30 | 260*260 | POTEAU | POTEAU | Métal - Acier | Elément porteur | Intérieur | Métal - Acier | Rectangulaire | 16.9 | 0.0676 | 17.2016 | 17.3368 | 1.1181 | 0 | 17.2016 | 0.0676 | 0 | 1.1181 | 0 | 0.26 | 5.12 | 1.04 | 1.14244 | 17.576 | 1.14244 | 0 | 0 | 0.0676 | 0.0676 | 0 | 0.0676 | Plateau bureaux | 005 | 0.26
POTEAU | 260*260 | Métal - Acier | Pt0(?) | yes | no | ID551A4115-0000-4341-3134-323737393933 | Pt0(?) | 202 | 13 | C25/30 | 260*260 | POTEAU | POTEAU | Métal - Acier | Elément porteur | Intérieur | Métal - Acier | Rectangulaire | 16.9 | 0.0676 | 17.0144 | 17.1496 | 1.10594 | 0 | 17.0144 | 0.0676 | 0 | 1.10594 | 0 | 0.26 | 5.12 | 1.04 | 1.14244 | 17.576 | 1.14244 | 0 | 0 | 0.0676 | 0.0676 | 0 | 0.0676 | Plateau bureaux | 005 | 0.26
Column | A_col | STEEL/S235JRG2 3386696625 | STEEL/S235JRG2 3386696625 260 x 260 |  |  |  |  |  |  |  |  |  | Column | STEEL/S235JRG2 3386696625 | Non défini | Non défini | STEEL/S235JRG2 1 | Rectangulaire | 14.225 | 0.0676 | 7.62701 | 7.73316 | 0.529166 | 4.9 | 7.62701 | 0.0676 | 0 | 0.529166 | 0 | 0.26 | 0 | 1.04 | 0.96161 | 14.794 | 0.96161 | 0 | 0 | 0.0676 | 0.0385438 | 0 | 0.0676 | Plateau bureaux | 005 | 0.26

# IfcColumn: STEEL/S235JRG2 3386696625 160 x 160 (10)
In: Rez de chaussée
Description: A_col; Material: STEEL/S235JRG2 3386696625
ArchiCADProperties - ID: Column; Etage d'implantation: Rez de chaussée; Nom de Zone: Plateau bureaux; Numéro de Zone: 005; Calque: A-COLS; Type: Poteau; Verrouillé: no; Matériau de construction / Composite / Profil / Hachure: STEEL/S235JRG2 3386696625; Classification d'lément: Type ArchiCAD; Etat de rénovation: Existant; Afficher sur filtre de rénovation: Tous les filtres appropriés; Type de structure: Basique; Matériau de construction / Profil: STEEL/S235JRG2 3386696625; Surface: STEEL/S235JRG2 1; Angle d'inclinaison de poteau: 90 deg; Coupe transversale de poteau: Rectangulaire; Etage supérieur lié: Non lié
AC_Pset_RenovationAndPhasing - Renovation Status: Existing
Pset_ColumnCommon - Reference: STEEL/S235JRG2 3386696625 160 x 160
BaseQuantities - Width: 0.16 m; Depth: 0.16 m; CrossSectionArea: 0.0256 m2
ArchiCADQuantities - Hauteur: 1.925 m; Superficie: 0.0256 m2; Surface du revêtement: 0 m2; Volume net du revêtement: 0 m3; Dimensions Ame: 0.16 m; 2ème dimension âme: 0.16 m; Hauteur minimum du Poteau: 0 m; Périmètre du Poteau: 0.64 m; Surface du Poteau: 0.0256 m2; Volume brut du Poteau: 0.04928 m3; Surface brute de l'âme (sans haut/bas): 1.232 m2; Volume brut de l'Ame: 0.04928 m3; Surface brute du revêtement (sans haut/bas): 0 m2; Volume brut du revêtement: 0 m3; Surface nette du haut de l'Ame: 0.0256 m2; Surface nette du haut du Revêtement: 0 m2; Surface nette du bas du Revêtement: 0 m2; Surface brute du haut (ou bas) de l'âme: 0.0256 m2; Surface brute du haut (ou bas) du revêtement: 0 m2; Décalage supérieur: 0 m
Name | Fonction structurelle | Position | Length (m) = Hauteur maximum Poteau (m) | OuterSurfaceArea (m2) = Superficie de surface (m2) = Surface nette de l'âme (sans haut/bas) (m2) | TotalSurfaceArea (m2) = GrossSurfaceArea (m2) | GrossVolume (m3) = NetVolume (m3) = Volume net (m3) = Volume net de l'Ame (m3) = Volume du Poteau (m3) | Altitude à Zéro du Projet (m) = Altitude à étage (m) = Décalage étage d'implantation (m) | Surface nette du bas de l'Ame (m2) | LoadBearing | IsExternal
Column | Non défini | Non défini | 1.925 | 0.721468 | 0.762268 | 0.0309713 | 17.1707 | 0.0152
Column | Elément non porteur | Extérieur | 1.925 | 0.671559 | 0.709659 | 0.0266033 | 17.2 | 0.0125007 | no | yes
Column | Elément non porteur | Extérieur | 1.925 | 0.681295 | 0.719845 | 0.0273822 | 17.2 | 0.0129506 | no | yes
Column | Non défini | Non défini | 1.90637 | 0.657993 | 0.683593 | 0.0265069 | 17.1414 | 0
Column | Elément non porteur | Extérieur | 1.925 | 0.700767 | 0.740217 | 0.0289399 | 17.2 | 0.0138505 | no | yes
Column | Elément non porteur | Extérieur | 1.925 | 0.710503 | 0.750403 | 0.0297188 | 17.2 | 0.0143004 | no | yes
Column | Elément non porteur | Extérieur | 1.925 | 0.652087 | 0.689288 | 0.0250455 | 17.2 | 0.0116009 | no | yes
Column | Elément non porteur | Extérieur | 1.925 | 0.691031 | 0.730031 | 0.028161 | 17.2 | 0.0134005 | no | yes
Column | Elément non porteur | Extérieur | 1.925 | 0.661823 | 0.699474 | 0.0258244 | 17.2 | 0.0120508 | no | yes
Column | Non défini | Non défini | 1.925 | 0.673307 | 0.711918 | 0.0271184 | 17.1707 | 0.0130114

# IfcColumn: STEEL/S235JRG2 3386696625 80 x 160, Column
In: Rez de chaussée
Description: A_col; Material: STEEL/S235JRG2 3386696625
ArchiCADProperties - ID: Column; Etage d'implantation: Rez de chaussée; Nom de Zone: Plateau bureaux; Numéro de Zone: 005; Calque: A-COLS; Type: Poteau; Verrouillé: no; Matériau de construction / Composite / Profil / Hachure: STEEL/S235JRG2 3386696625; Fonction structurelle: Elément non porteur; Position: Extérieur; Classification d'lément: Type ArchiCAD; Etat de rénovation: Existant; Afficher sur filtre de rénovation: Tous les filtres appropriés; Type de structure: Basique; Matériau de construction / Profil: STEEL/S235JRG2 3386696625; Surface: STEEL/S235JRG2 1; Angle d'inclinaison de poteau: 90 deg; Coupe transversale de poteau: Rectangulaire; Etage supérieur lié: Non lié
AC_Pset_RenovationAndPhasing - Renovation Status: Existing
Pset_ColumnCommon - LoadBearing: no; IsExternal: yes; Reference: STEEL/S235JRG2 3386696625 80 x 160
BaseQuantities - Length: 1.925 m; Width: 0.08 m; Depth: 0.16 m; CrossSectionArea: 0.0128 m2; OuterSurfaceArea: 0.508526 m2; TotalSurfaceArea: 0.527726 m2; GrossSurfaceArea: 0.527726 m2; GrossVolume: 0.0135607 m3; NetVolume: 0.0135607 m3
ArchiCADQuantities - Altitude à Zéro du Projet: 17.2 m; Altitude à étage: 17.2 m; Hauteur: 1.925 m; Superficie de surface: 0.508526 m2; Volume net: 0.0135607 m3; Superficie: 0.0128 m2; Surface nette de l'âme (sans haut/bas): 0.508526 m2; Surface du revêtement: 0 m2; Volume net de l'Ame: 0.0135607 m3; Volume net du revêtement: 0 m3; Dimensions Ame: 0.16 m; 2ème dimension âme: 0.08 m; Hauteur minimum du Poteau: 0 m; Hauteur maximum Poteau: 1.925 m; Périmètre du Poteau: 0.48 m; Surface du Poteau: 0.0128 m2; Volume du Poteau: 0.0135607 m3; Volume brut du Poteau: 0.02464 m3; Surface brute de l'âme (sans haut/bas): 0.924 m2; Volume brut de l'Ame: 0.02464 m3; Surface brute du revêtement (sans haut/bas): 0 m2; Volume brut du revêtement: 0 m3; Surface nette du haut de l'Ame: 0.0128 m2; Surface nette du bas de l'Ame: 0.0064 m2; Surface nette du haut du Revêtement: 0 m2; Surface nette du bas du Revêtement: 0 m2; Surface brute du haut (ou bas) de l'âme: 0.0128 m2; Surface brute du haut (ou bas) du revêtement: 0 m2; Décalage étage d'implantation: 17.2 m; Décalage supérieur: 0 m

# IfcColumn: UPE200 (10)
In: Rez de chaussée
Description: A_col; Material: STEEL/S235JRG2 3386696625
ArchiCADProperties - ID: Column; Etage d'implantation: Rez de chaussée; Nom de Zone: Serre; Numéro de Zone: 006; Calque: A-COLS; Type: Poteau; Verrouillé: no; Matériau de construction / Composite / Profil / Hachure: STEEL/S235JRG2 3386696625; Fonction structurelle: Elément porteur; Position: Intérieur; Classification d'lément: Type ArchiCAD; Etat de rénovation: Existant; Afficher sur filtre de rénovation: Tous les filtres appropriés; Type de structure: Basique; Matériau de construction / Profil: STEEL/S235JRG2 3386696625; Surface: STEEL/S235JRG2 1; Angle d'inclinaison de poteau: 90 deg; Coupe transversale de poteau: Rectangulaire; Etage supérieur lié: Non lié
AC_Pset_RenovationAndPhasing - Renovation Status: Existing
Pset_ColumnCommon - LoadBearing: yes; IsExternal: no; Reference: STEEL/S235JRG2 3386696625 80 x 200
BaseQuantities - Length: 6.45 m; Width: 0.08 m; Depth: 0.2 m; CrossSectionArea: 0.016 m2; OuterSurfaceArea: 3.612 m2; TotalSurfaceArea: 3.628 m2; GrossSurfaceArea: 3.628 m2; GrossVolume: 0.1032 m3; NetVolume: 0.1032 m3
ArchiCADQuantities - Altitude à Zéro du Projet: 5.2 m; Altitude à étage: 5.2 m; Hauteur: 6.55 m; Superficie de surface: 3.612 m2; Volume net: 0.1032 m3; Superficie: 0.016 m2; Surface nette de l'âme (sans haut/bas): 3.612 m2; Surface du revêtement: 0 m2; Volume net de l'Ame: 0.1032 m3; Volume net du revêtement: 0 m3; Dimensions Ame: 0.2 m; 2ème dimension âme: 0.08 m; Hauteur minimum du Poteau: 6.45 m; Hauteur maximum Poteau: 6.45 m; Périmètre du Poteau: 0.56 m; Surface du Poteau: 0.016 m2; Volume du Poteau: 0.1032 m3; Volume brut du Poteau: 0.1048 m3; Surface brute de l'âme (sans haut/bas): 3.668 m2; Volume brut de l'Ame: 0.1048 m3; Surface brute du revêtement (sans haut/bas): 0 m2; Volume brut du revêtement: 0 m3; Surface nette du haut de l'Ame: 0.016 m2; Surface nette du bas de l'Ame: 0 m2; Surface nette du haut du Revêtement: 0 m2; Surface nette du bas du Revêtement: 0 m2; Surface brute du haut (ou bas) de l'âme: 0.016 m2; Surface brute du haut (ou bas) du revêtement: 0 m2; Décalage étage d'implantation: 5.2 m; Décalage supérieur: 0 m

# IfcCurtainWall: Type de mur-rideau (10)
ArchiCADProperties - Calque: A-WALL-CURT; Type: Mur-rideau; Verrouillé: no; Fonction structurelle: Elément non porteur; Position: Extérieur; Classification d'lément: Type ArchiCAD; Etat de rénovation: Existant; Afficher sur filtre de rénovation: Tous les filtres appropriés; Angle d'inclinaison: 90 deg; Angle de motif: 90 deg
AC_Pset_RenovationAndPhasing - Renovation Status: Existing
Pset_CurtainWallCommon - IsExternal: yes
BaseQuantities - Width: 0.3 m
ArchiCADQuantities - Epaisseur: 0.3 m; Longueur totale des cadres personnalisés: 0 m; Surface totale des panneaux tournés vers le nord-est: 0 m2; Surface totale des panneaux tournés vers le nord-ouest: 0 m2; Surface totale des panneaux tournés vers le sud-est: 0 m2; Surface totale des panneaux tournés vers le sud-ouest: 0 m2
Name | In | Description = ID | Etage d'implantation | Length (m) = Longueur (m) | Height (m) | GrossSideArea (m2) = NetSideArea (m2) = Superficie de surface (m2) | Altitude à Zéro du Projet (m) | Altitude à étage (m) | Hauteur (m) | Longueur totale des cadres (m) | Surface totale de panneau (m2) | Nombre de panneaux | Surface inclut bordure (m2) | Longueur totale des cadres de contour (m) | Longueur totale des cadres appartient à axe principal (m) | Longueur totale des cadres appartient à axe secondaire (m) | Surface totale des panneaux tournés vers le nord (m2) | Surface totale des panneaux tournés vers le sud (m2) | Surface totale des panneaux tournés vers l'est (m2) | Surface totale des panneaux tournés vers l'ouest (m2)
CurtainWall_02 | Rez de chaussée | CurtainWall_02 | Rez de chaussée | 58.1168 | 4.3 | 249.902 | 0.1 | 0.1 | 6 | 393.787 | 220.056 | 117 | 249.902 | 124.434 | 159.6 | 109.754 | 0 | 220.056 | 0 | 0 | ArchiCADProperties - Nom de Zone: Réserve; Numéro de Zone: 010
CurtainWall_01 | R+1 | CurtainWall_01 | R+1 | 0.852231 | 7.27483 | 6.19984 | 4.85 | -0.55 | 18 | 17.574 | 5.14137 | 5 | 6.19037 | 15.5592 | 0 | 2.01483 | 0 | 0 | 0 | 5.14137
CurtainWall_01 | R+1 | CurtainWall_01 | R+1 | 12.6756 | 12 | 152.107 | 5.4 | -7.09988e-14 | 3.1 | 191.768 | 132.74 | 40 | 152.107 | 60.3506 | 35.4 | 96.0176 | 0 | 56.2691 | 0 | 76.4708
CurtainWall_01 | R+1 | CurtainWall_01 | R+1 | 1.95138 | 7.275 | 14.1963 | 4.85 | -0.55 | 18 | 25.3583 | 12.3124 | 5 | 14.5601 | 18.1528 | 0 | 7.20553 | 0 | 0 | 12.3124 | 0
CurtainWall_01 | R+1 | CurtainWall_01 | R+1 | 7.20529 | 12 | 86.4635 | 5.4 | 0 | 18 | 109.528 | 77.8994 | 24 | 86.4635 | 38.0106 | 23.6 | 47.917 | 0 | 0 | 77.8994 | 0
CurtainWall_01 | R+1 | CurtainWall_01 | R+1 | 9.38242 | 13 | 121.971 | 4.4 | -1 | 15 | 154.304 | 110.171 | 36 | 121.971 | 44.3648 | 38.4 | 71.5394 | 0 | 0 | 110.171 | 0
CurtainWall_01 | R+1 | CurtainWall_01 | R+1 | 11.5326 | 13 | 149.924 | 4.4 | -1 | 15 | 175.806 | 136.661 | 36 | 149.924 | 48.6653 | 38.4 | 88.7412 | 0 | 136.661 | 0 | 0 | ArchiCADProperties - Nom de Zone: Plateau bureaux; Numéro de Zone: 005
CurtainWall_01 | R+1 | CurtainWall_01 | R+1 | 8.1 | 12 | 97.2 | 5.4 | 0 | 18 | 117.58 | 88.0812 | 24 | 97.2 | 39.8 | 23.6 | 54.18 | 88.0812 | 0 | 0 | 0
CurtainWall_01 | R+1 | CurtainWall_01 | R+1 | 42.7389 | 7.27507 | 310.928 | 4.85 | -0.55 | 18 | 363.743 | 284.126 | 75 | 311.283 | 99.4226 | 99.051 | 165.269 | 0 | 284.126 | 0 | 0
CurtainWall_02 | Mezzannine | CurtainWall_02 | Mezzannine | 17.0227 | 4.3 | 73.1976 | 0.1 | -9.325 | 3.1 | 148.611 | 61.6846 | 57 | 73.1976 | 42.2454 | 75.6 | 30.7654 | 0 | 0 | 61.6846 | 0

# IfcDoor: Double porte d'entrée 18 (2)
In: Rez de chaussée
Type - OperationType: DOUBLE_DOOR_SINGLE_SWING; ParameterTakesPrecedence: no; Sizeable: no
Type - Propriétés Doublure Porte - LiningDepth: 0.1 m; LiningThickness: 0.032 m; LiningOffset: -0.27 m
Type - Propriétés Panneau Porte - Panneau1 - PanelDepth: 0.04 m; PanelOperation: SWINGING; PanelWidth: 0.506198; PanelPosition: RIGHT
Type - Propriétés Panneau Porte - Panneau2 - PanelDepth: 0.04 m; PanelOperation: SWINGING; PanelWidth: 0.506198; PanelPosition: LEFT
Description: DOOR; OverallHeight: 2.1 m; OverallWidth: 2 m; Material: Background Fill-International (12), Air Space (2), 01 | Hatch-Dashed, Foreground Fill-International, 07 | Insulation Rigid
ArchiCADProperties - ID: DOOR; Etage d'implantation: Rez de chaussée; Calque: A-WALL-EXTR; Type: Porte; Verrouillé: no; Nom Elément de Bibliothèque: Double porte d'entrée 18; Matériau de construction / Composite / Profil / Hachure: Solid Fill; Fonction structurelle: Elément non porteur; Position: Intérieur; Classification d'lément: Porte; Etat de rénovation: Existant; Afficher sur filtre de rénovation: Tous les filtres appropriés; Texte Marque: DOOR; Orientation: D; Dimensions ébrasure: 78,74"x82,68"; Dimensions trou mur: 78,74"x82,68"; Dimensions unité: 78,74"x82,68"; Dimensions sortie: 76,22"x81,42"; Dimensions battant: 77,17"x81,89"; Structure mur: 1.2-Mur ext: revét ext + isol ext + maçonnerie + enduit; Taille L x H nominale: 78,74"x82,68"; Taille L x H x E nominale: 78,74"x82,68"x14,57"
AC_Pset_Double_porte_d'entrée_18 - Contours Mur (0-Sans,1-Tout,2-Côté,3-Longueur): 0; Point ch.0-Non,1-2D,2-3D,3-Tous: 3; Afficher points chauds 2D en 3D: yes; Option affichage en plan: 3; Angle de position baie: 0 deg; Trou reprend surface latérale de mur: yes; Division de surface de trou courbée: no; Type de mur: 1; Type de direction de mur: 0; Direction d'ouverture: 0; Basculer: no; Valeur incrustation allège: 3; Démolition / Nouvelle constr.: 1; Motif de hachure démolition: 0; Stylo démolition: Transparent; Stylo fond démolition: Transparent; Nouveau motif de hachure: 0; Nouveau stylo: Transparent; Nouveau stylo de fond: Transparent; Nouveau motif de hachure de mur: 04 | Block Masonry; Nouveau stylo de hachure de mur: Général - Dessin; Nouveau stylo fond hachure mur: Fond - Couleur 1; Afficher nouv. constr. sur mur: no; Type de ligne démolition: 1; Aff. param. Démolition/Nouveau: no; Afficher comme imposte: no; Châssis vitré (gs_SidelightTransomRelation): Sous imposte; Châssis vitré (gs_SidelightTransomRelation_m): 1; Tierce vitrée 1: no; Tierce vitrée 2: no; Tolérances uniformes: no; Taille nominale: 0; Taille trou comme taille nominale: yes; Taille ébrasure comme nominale: no; Taille unité comme nominale: no; Taille sortie comme nominale: no; Taille battant comme nominale: no; Conserver valeur de taille nominale en changeant: no; Afficher points chaud éditables: yes; Niveau de détail 2D: 2; Afficher ébrasure sur symbole: 2; Affichage symbolique de l'ouverture: no; Niveau de détail 3D: 2; Direction ouverture tiere vitrée (gs_opening_dir_sl): Identique à battant; Direction ouverture tiere vitrée (gs_opening_dir_sl_m): 1; Cadre porte (gs_pocket_door_frame): yes; Style de cadre (gs_frame_style): Simple feuillure; Style de cadre (gs_frame_style_m): 3; Epaisseur cadre=Epaisseur mur: no; Epaisseur cadre uniforme: yes; Battant centré: yes; Largeur cadre uniforme: yes; Style cadre changé automatiquement: no; Nombre de battants: 4; Nombre de battants - côté 2: 3; Style panneau de porte (gs_door_typ): Style 6; Style panneau de porte (gs_door_typ_m): 75; Configuration battants (gs_LeavesConfig): Battants uniformes; Configuration battants (gs_iLeavesConfig): 1; Position meneau (gs_grill_pos): Les deux; Position meneau (gs_grill_pos_m): 3; Nombre panneaux verticalement: 4; Nombre panneaux horizontalement: 3; Nbre panneaux vert. côté 1: 4; Nbre panneaux hor. côté 1: 3; Afficher comme panneau vitre sur symbole: no; Afficher symbole porte chinoise: no; Afficher symbole comme panneau étanche: no; Poignée d'ouverture (gs_handle_type): Sans; Poignée d'ouverture (gs_handle_type_m): 0; Afficher poignée sur symbole: no; Châssis uniformes: no; Type d'ouverture (gs_optype_m_05): 3; Type d'ouverture (gs_optype_m_09): 1; Type d'ouverture (gs_optype_m_02): 1; Type d'ouverture (gs_optype_m_06): 1; Type d'ouverture (gs_optype_m_10): 1; Type châssis (MullionStyle_00): Nombre de meneaux; Type châssis (iMullionStyle_00): 1; Type châssis (iMullionStyle_05): 1; Type châssis (iMullionStyle_09): 1; Type châssis (iMullionStyle_02): 1; Type châssis (iMullionStyle_06): 1; Type châssis (iMullionStyle_10): 1; Edition point chaud de grille: yes; Position meneau (MullionPosition): Les deux; Position meneau (iMullionPosition): 3; Nbre panneaux V châssis princ. côté 1: 4; Nbre panneaux H châssis princ. côté 1: 2; Nbre panneaux V 2 châssis princ. côté 1: 4; Nbre panneaux H 2 châssis princ. côté 1: 2; Nbre panneaux V châssis princ. côté 2: 4; Nbre panneaux H châssis princ. côté 2: 2; Nbre panneaux V 2 châssis princ. côté 2: 4; Nbre panneaux H 2 châssis princ. côté 2: 2; Nbre panneaux V imposte centre: 2; Nbre panneaux H imposte centre: 2; Nbre panneaux V 2 imposte centre: 2; Nbre panneaux H 2 imposte centre: 2; Nbre panneaux vert. imposte côté 1: 2; Nbre panneaux hor. imposte côté 1: 2; Nbre panneaux V 2 imposte côté 1: 2; Nbre panneaux H 2 imposte côté 1: 2; Nbre panneaux vert. imposte côté 2: 2; Nbre panneaux hor. imposte côté 2: 2; Nbre panneaux V 2 imposte côté 2: 2; Nbre panneaux H 2 imposte côté 2: 2; Imposte (gs_door_transom): no; Chambranle extérieur: no; Type chambr. ext. (gs_trimtype_out): Rectangulaire; Type chambr. ext. (gs_trimtype_out_int): 1; Largeurs uniformes de chambranle (gs_trim_outside_uniform): no; Chambranle intérieur.: no; Type chambr. intérieur (gs_trimtype_in): Rectangulaire; Type chambr. intérieur (gs_trimtype_in_int): 1; Largeurs uniformes de chambranle (gs_trim_inside_uniform): no; Seuil: 1; Angle seuil: 3.1996 deg; Seuil changé automatiquement: no; Appui - porte: yes; Appui - Tierce vitrée côté 1: no; Appui - Tierce vitrée: no; Dépassement appui: no; Type d'appui/seuil: 2; Angle appui: 3 deg; Appui courbe dans murs courbes: yes; Isolation sous appui: yes; Utiliser couche isolation mur: no; Niveau détail 3D seuil brique: 1; Style appui changé automatiquement: no; Tablette - côté tierce vitrée 1: no; Tablette - Tierce vitrée: no; Tablette - porte: no; Angle tablette: 0 deg; Tabl. courbe dans murs courbes: yes; Tableau dans murs polygonaux: 1; Aération naturelle (VentilationProfileType): Sans; Aération naturelle (iVentilationProfileType): 1; Type volet (gs_sunShade_type): Sans; Type volet (gs_sunShade_iType): 0; Types volet activés: 127; Nombre de panneaux: 2; Nombre de panneaux 2: 1; Position panneau (gs_shutter_panelPos): Symmetric; Position panneau (gs_shutter_iPanelPos): 1; Hauteur volet automatique: yes; Cadre supplémentaire: no; Type de couverture (gs_slidingShutter_cover): Z-Profile; Type de couverture (gs_slidingShutter_iCover): 1; Direction articulation (gs_foldingShutter_stacking): Inside; Direction articulation (gs_foldingShutter_iStacking): 1; Ouvert en 3D: yes; Angle ouverture en 3D (gs_shutter_opAngle): 180 deg; Afficher symbole 2D: yes; Afficher lignes d'ouverture sur symbole: no; Type de panneau: (gs_shutPanel_type): Style 1; Type de panneau: (gs_shutPanel_iType): 1; Largeur cadre inf. différente: no; Largeur volets automatiques: yes; Angle persienne: 30 deg; Résolution trou: 3; Nombre trous horizontaux: 5; Nombre trous verticaux: 8; Placement volet roulant (gs_shutRoll_placement): Fixed on Facade; Placement volet roulant (gs_shutRoll_iPlacement): 1; Type boîte (gs_shutRoll_boxType): Rectangular; Type boîte (gs_shutRoll_iBoxType): 1; Position rampe (gs_shutRoll_railPos): Sur revêtement; Position rampe (gs_shutRoll_iRailPos): 1; Afficher revêtement derrière parasol (gs_shutRoll_showCasingBehind): no; Isolation derrière cellule (gs_shutRoll_cutWallBehind): no; Inclure hauteur dans hauteur de trou de mur: no; Angle supérieur boîte: 10 deg; Taille boîte par défaut (gs_shutRoll_boxDefaultSize): Reveal Width; Taille boîte par défaut (gs_shutRoll_iBoxDefaultSize): 1; Placement stores (gs_shutLam_placement): Fixed on Facade; Placement stores (gs_shutLam_iPlacement): 1; Isolation derrière cellule (gs_shutLam_cutWallBehind): no; Boîte ouverte: yes; Rampe (gs_shutLam_bRail): yes; Position rampe (gs_shutLam_railPos): Sur revêtement; Position rampe (gs_shutLam_iRailPos): 1; Afficher revêtement derrière parasol (gs_shutLam_showCasingBehind): no; Angle de rotation des lamelles (gs_shutLam_rotation): 45 deg; Angle de rotation des lamelles (gs_shutLam2_rotation): 45 deg; Linteau (gs_masonry_arch): Sans; Linteau (gs_masonry_arch_int): 1; Type linteau (gs_masonry_arch_structure): Stuc; Type linteau (gs_masonry_arch_structure_int): 1; Arche sur linteau: yes; Niche sous arche: yes; Angle inclinaison: 75 deg; Surface niche personnalisée: no; Type ébrasure (gs_reveal_type_new): Pas d'ébrasure - arête; Type ébrasure (gs_reveal_type_int): 1; Type ébrasure inférieure (gs_reveal_type_bottom): Baie simple; Type ébrasure inférieure (gs_reveal_type_bottom_int): 2; Définir profondeur montant sur côté: 1; Profondeur montant uniforme: no; Type ébrasure extérieure: Baie simple; Type ébrasure (gs_reveal_doubleOuterTypeInt): 2; Type ébrasure intérieure: Baie simple; Type ébrasure (gs_reveal_doubleInnerTypeInt): 2; Côté angle 2: 20 deg; Côté angle: 20 deg; Angle côté supérieur: 20 deg; Angle côté inférieur: 20 deg; Côté angle extérieur 2: 20 deg; Côté angle extérieur: 20 deg; Angle extérieur côté sup.: 20 deg; Angle extérieur côté inf.: 20 deg; Rampe sous battants: no; Rampe (gs_door_rail_ext): Sans; Rampe (gs_door_rail_ext_m): 1; Utiliser composant finition mur: no; Tourner automatiquement plâtre surface intérieure: yes; Tourner plâtre surface intérieure: 0; Tourner automatiquement plâtre surface extérieure: yes; Tourner plâtre surface extérieure: 0; Afficher en 3D: no; Type de fermeture (gs_closure_type): Pas de fermeture; Type de fermeture (gs_closure_type_int): 1; Tourner couche sur côté (gs_cavity_side): Les deux; Tourner couche sur côté (iCavityClosureSide): 1; Nbre de couches retournées: 1; Num. à partir de (gs_nTurnDir): Face extérieure; Num. à partir de (iCavityClosureTurnDir): 1; Placer fermeture sur côté 1: yes; Placer fermeture sur côté 2: yes; Placer fermeture en haut: no; Placer fermeture en bas: no; Placer fermeture sur couche: 1; Placer fermeture de côté (gs_cc_dutch_ClosureToSide): 1; Ecart à couche externe: yes; Tourner couche sur fermeture: no; Insérer bande d'isolation: yes; Afficher bande d'isolation: yes; Stylo contour (gs_penJoint): Ouvertures - Coupé non structurel; Type de ligne de contour (gs_ltJoint): 1; Motif de hachure (gs_fillJoint): 07 | Insulation Rigid; Stylo hachure (gs_penJointFg): Général - Dessin; Stylo fond de hachure (gs_penJointBg): Eléments 2D - Dessin; Surface personnalisée: no; Surface: 06 | W Pine H; Stylo contour (gs_penPlug): Ouvertures - Coupé non structurel; Type de ligne de contour (gs_ltPlug): 1; Motif de hachure (gs_fillPlug): 07 | Insulation Rigid; Stylo hachure (gs_penPlugFg): Général - Dessin; Stylo fond de hachure (gs_penPlugBg): Eléments 2D - Dessin; Côté montant édité: 1; Côté mur édité: 1; Numéro couche éditée: 1; Tourner couche: no; Considérer couches comme plâtre: no; Tourner épaiseur: 1; Orientation hachure: 1; Ligne de séparation tournant: no; Stylo ligne de séparation: Général - Dessin; Dernier côté sélectionné: no; Méthode fermeture changée auto.: no; Connexion sur côté 1: no; Connexion sur côté 2: no; Connexion en haut: no; Type d'ouverture (gs_leaf_optype): Accrochée sur côté; Type d'ouverture (gs_leaf_optype_m): 5; Ouverture panneau de fin côté 1: no; Ouverture panneau de fin côté 2: no; Angle ouverture en 2D: 90 deg; Angle ouverture 2D côté 2: 90 deg; Angle ouverture en 3D (gs_open_3D): 0 deg; Angle ouv. battant fin 3D côté 2: 0 deg; Angle ouv. châssis principal côté 1 (openingAngle_05): 0 deg; Angle ouv. châssis principal côté 1 (openingAngle2_05): 0 deg; Angle ouv. châssis principal côté 2 (openingAngle_09): 0 deg; Angle ouv. châssis principal côté 2 (openingAngle2_09): 0 deg; Angle ouv. imposte centre (openingAngle_02): 0 deg; Angle ouv. imposte centre (openingAngle2_02): 0 deg; Angle ouverture imposte côté 1 (openingAngle_06): 0 deg; Angle ouverture imposte côté 1 (openingAngle2_06): 0 deg; Angle ouverture imposte côté 2 (openingAngle_10): 0 deg; Angle ouverture imposte côté 2 (openingAngle2_10): 0 deg; Type ligne double à carreaux: 4; Suppl. Opt. vue pour aff. symb. 2D: no; Type ligne ouverture: 1; Forme ligne ouverture (or_SwingType): Courbé; Forme ligne ouverture (or_iSwingType): 1; Forme ligne ouverture (or_SlidingType): Sans; Forme ligne ouverture (or_iSlidingType): 0; Suppl. Opt. vue pour proj. porte 3D: no; Afficher ligne d'ouverture (or_bOplines3d): yes; Type ligne côté ouverture (or_opLineType3dIn): Tirets; Type ligne côté ouverture (or_iOpLineType3dIn): 1; Type ligne côté opposé (or_opLineType3dOut): Ligne continue; Type ligne côté opposé (or_iOpLineType3dOut): 0; Orient. ligne (or_oplineStyle): Poignée; Orient. ligne (or_iOplineStyle): 1; Stylo ligne ouverture 2D/3D (or_opLinePen): Ouvertures - Général; Stylo ligne ouverture 2D/3D (or_iOpLinePen): 3; Suppl. Opt. vue mod. pr proj. 3D tierce/imposte: no; Afficher ligne d'ouverture (or_bWinOplines3d): yes; Type ligne côté ouverture (or_winOpLineType3dIn): Ligne continue; Type ligne côté ouverture (or_iWinOpLineType3dIn): 0; Type ligne côté opposé (or_winOpLineType3dOut): Ligne continue; Type ligne côté opposé (or_iWinOpLineType3dOut): 0; Orient. ligne (or_winOplineStyle): Poignée; Orient. ligne (or_iWinOplineStyle): 1; Stylo ligne ouverture 2D/3D (or_winOpLinePen): Ouvertures - Général; Stylo ligne ouverture 2D/3D (or_iWinOpLinePen): 3; Stylo du symbole: Ouvertures - Général; Stylo contour vitre: A construire - Coupe; Stylo ligne coupée chambranle des deux côtés: Ouvertures - Général; Stylo contour battant: A construire - Coupe; Ligne contour de porte ds mur: Sans; Ligne de contour de mur: 1; Type ligne contour int. mur: 4; Type ligne contour ext. mur: 4; Type ligne contour int. mur masqué: 4; Type ligne contour ext. mur masqué: 4; Ligne contour de tierce vitrée ds mur (gs_wcont_line_sl): Des deux côtés; Ligne contour de tierce vitrée ds mur (iWallContourLineSl): 4; Type ligne contour int. tierce vitrée ds mur: 1; Type ligne contour ext. tierce vitrée ds mur: 1; Type ligne contour int. tierce vitrée ds mur masqué: 4; Type ligne contour ext. tierce vitrée ds mur masqué: 4; Stylo ligne contour de mur: Ouvertures - Général; Utiliser hachures: yes; Motif de hachure cadre: Background Fill-International; Stylo fond de hachure cadre: Fond - Couleur 1; Motif de hachure battant: Air Space; Stylo hachure de battant: Fond - Couleur 1; Stylo fond de hachure battant: Fond - Couleur 1; Hachure vitrage: 01 | Hatch-Dashed; Stylo hachure vitrage: A construire - Coupe; Stylo fond de hachure vitre: Transparent; Motif hachure symbole étanche: Foreground Fill-International; Stylo hachure symbole étanche: Général - Dessin; Stylo fond hachure symbole étanche: Général - Dessin; Motif hachure symbole plan de porte: Background Fill-International; Stylo hachure symbole plan de porte: Fond - Couleur 1; Stylo fond hachure symbole plan de porte: Transparent; Motif hachure symbole plan de tierce vitrée: Background Fill-International; Stylo hachure symbole plan de tierce vitrée: Fond - Couleur 1; Stylo fond hachure symbole plan de tierce vitrée: Fond - Couleur 1; Type ligne seuil et appui: 1; Stylo contour de seuil en coupe: Ouvertures - Général; Motif hachure de seuil en Coupe: Background Fill-International; Stylo hachure seuil en Coupe: Fond - Couleur 1; Stylo fond hachure coupe Seuil: Fond - Couleur 1; Stylo appui 3D et non coupé: Général - Dessin; Stylo contour appui en Coupe: Général - Dessin; Motif hachure appui en Coupe: Background Fill-International; Stylo hachure d'appui en Coupe: Fond - Couleur 1; Stylo fond hachure appui Coupe: Fond - Couleur 1; Stylo contour isolation coupe: Général - Dessin; Motif hachure isolation Coupe: 07 | Insulation Rigid; Stylo hachure isolation Coupe: Général - Dessin; Stylo fond hachure isol. Coupe: Fond - Couleur 1; Stylo latte 3D et non coupé: Général - Dessin; Stylo contour latte en Coupe: Général - Dessin; Motif hachure tablette en Coupe: Background Fill-International; Stylo hachure tablette en Coupe: Fond - Couleur 1; Stylo fond hach. tablette Coupe: Fond - Couleur 1; Type hachure chambr. intérieur: Background Fill-International; Stylo hachure chambr. int.: Fond - Couleur 1; Stylo fond hachure chambr. int.: Fond - Couleur 1; Type hachure chambr. ext.: Background Fill-International; Stylo hachure chambr. ext.: Fond - Couleur 1; Stylo fond hachure chambr. ext.: Fond - Couleur 1; Motif de hachure arche coupe: Background Fill-International; Stylo fond hachure appui arche Coupe (gs_masonry_arch_pen_fg): Fond - Couleur 1; Stylo fond hachure appui arche Coupe (gs_masonry_arch_pen_bg): Fond - Couleur 1; Motif de hachure de Coupe de Profil de ventilation: Air Space; Stylo de hachure de Coupe de Profil de ventilation: Fond - Couleur 1; Stylo de fond de hachure de Coupe de Profil de ventilation: Fond - Couleur 1; Type de ligne symbole volet: 1; Stylo ligne coupée volet: Général - Dessin; Stylo ligne non coupée volet: Général - Dessin; Type hachure coupée volet: Background Fill-International; Stylo hachure coupée volet: Général - Dessin; Stylo fond hachure coupé volet: Fond de fenêtre; Motif de hachure d'isolation de pare-soleil: Background Fill-International; Stylo de hachure d'isolation de pare-soleil: Général - Dessin; Stylo de fond d'isolation de pare-soleil: Fond de fenêtre; Type hachure non coupée: Background Fill-International; Stylo hachure non coupée: Fond - Couleur 1; Stylo fond de hachure non coupé: Fond - Couleur 1; Valeurs côté ouverture (gs_opside_list): Custom; Valeurs côté ouverture (gs_opside_list_m): 0; Jonction éléments cadree (gs_SashText_typ): Assemblage bout à bout; Jonction éléments cadree (gs_SashText_typ_num): 2; Stylo panneaux: A construire - Coupe; Stylo linteau: Murs - Général; Résolution de courbe: 12; Ombre: yes; Surface extérieure cadre: 05 | Iron Coarse; Surface intérieure cadre: 05 | Iron Coarse; Surface extérieure de battant: 05 | Nickel Satin; Surface intérieure de battant: 05 | Nickel Satin; Surface de battant 2: 05 | Nickel Satin; Surface de battant 3: 06 | W Pine H; Surface de verrou: 09 | Paint-08 Black; Surface extérieure de meneau (gs_grill_mat): 06 | W Pine H; Surface intérieure de meneau (gs_grill_mat2): 06 | W Pine H; Surface extérieure de meneau (gs_leaf_grill_mat): 06 | W Pine H; Surface intérieure de meneau (gs_leaf_grill_mat2): 06 | W Pine H; Surface vitre: 08 | Glass-Clear; Surface vitre battant: 08 | Glass-Clear; Surface de rampe: 05 | Iron Coarse; Surface extérieure de persienne: 06 | W Pine H; Surface intérieure de persienne: 06 | W Pine H; Surface de plaque entrée inférieure: 05 | Aluminum Plain; Surface intérieure chambranle: 05 | Iron Coarse; Surface extérieure chambranle: 05 | Iron Coarse; Surface de profil de ventilation: 05 | Aluminum Plain; Surface panneau de volet: 06 | W Pine H; Surface cadre volet: 06 | W Pine H; Surface boîte volet roulant: 05 | Stainless Reflective; Surface lames volet roulant: 09 | Paint-05 Grey; Surface rail volet roulant: 09 | Paint-05 Grey; Surface boîtier de stores: 05 | Stainless Reflective; Surface segments de stores: 09 | Paint-05 Grey; Surface rail volet coulissant: 05 | Stainless Reflective; Surface de seuil: 05 | Iron Coarse; Surface métal seuil: 05 | Aluminum Plain; Surface d'appui: 04 | B Running Bond; Surface mortier appui briques: 09 | Stucco White; Surface de tableau: 06 | W Pine H; Surface de poignée: 05 | Stainless Reflective; Surface accessoires poignée: 05 | Iron Coarse; Surface brique linteau: 04 | B Running Bond; Surface mortier linteau: 09 | Stucco White; Surface clef de voûte linteau: 04 | Sandstone; Surface niche: 32 | Mulch; Porte appartient à Zone vers laquelle elle donne: yes; Coût: 0; Emplacement comme: Personnalisé; Surface vitrée totale (gs_list_glassarea_tmp): 0; Supplanter surface vitrée: yes; Surface vitrée totale (gs_list_glassarea): 0; Périmètre total vitrage: 0; Fermeture automatique: no; Numéro de fermeture automatique: 2; Performance air libre (mm2/l/m): 0; Type de groupe (FM_Type): Others; Type de groupe (iFMType): 999; Poids de l'objet: 0; Unité poids de l'objet: kg; Définition orientation porte (gs_list_orientationDef): Automatique; Définition orientation porte (gs_list_orientationDef_m): 0; Fermeture porte: no; Type panneau de vision: Nbre panneaux vision; Dispositif main. ouvert.: no; Opération IFC (ifc_optypestr): Porte double battant simple; Opération IFC (ifc_optype): 2
AC_Pset_RenovationAndPhasing - Renovation Status: Existing
Pset_DoorCommon - IsExternal: no
BaseQuantities - Height: 2.1 m; Width: 2 m; Perimeter: 8.2 m; Area: 4.2 m2; Volume: 0.0752371 m3; Depth: 0.37 m
ArchiCADQuantities - Hauteur: 2.1 m; Superficie de surface: 10.8533 m2; Volume net: 0.0752371 m3; Largeur: 2 m; Epaisseur: 0.1 m; Largeur ouverture côté ébrasure: 2 m; Largeur ouverture côté opposé ébrasure: 2 m; Hauteur ouverture côté ébrasure: 2.1 m; Hauteur ouverture côté opposé ébrasure: 2.1 m; Surface ouverture côté ébrasure: 4.2 m2; Surface ouverture côté opposé ébrasure: 4.2 m2; Largeur nominale de l'ouverture côté ébrasure: 1.88 m; Largeur nominale de l'ouverture côté opposée ébrasure: 2 m; Hauteur nominale de l'ouverture côté ébrasure: 2.04 m; Hauteur nominale de l'ouverture côté opposée ébrasure: 2.1 m; Surface nominale de l'ouverture P/F côté ébrasure: 3.8352 m2; Surface nominale de l'ouverture P/F côté opposé ébrasure: 4.2 m2; Volume ouverture: 0.0752371 m3; Surface nominale ouverture P/F: 4.2 m2; Volume nominal ouverture: 1.554 m3; Epaisseur de Mur: 0.37 m
AC_Equantity_Double_porte_d'entrée_18 - Largeur: 2 m; Hauteur: 2.1 m; Dimension Z: 1 m; Niveau inférieur: 1 m; Niveau supérieur: 0 m; Nouv. largeur droite hach. mur: 0.15 m; Nouv. largeur gauche hach. mur: 0.15 m; Hauteur départ Linteau: 2.074 m; Largeur tierce vitrée 1: 0.3 m; Largeur tierce vitrée 2 (gs_sidelight_width_right_half): 0.15 m; Largeur tierce vitrée 2 (gs_sidelight_width_right_orig): 0.3 m; Hauteur seuil tierce vitrée 1: 0 m; Largeur tierce vitrée 2 (gs_sidelight_width_left): 0.3 m; Largeur tierce vitrée 2 (gs_sidelight_width_left_half): 0.15 m; Largeur tierce vitrée 2 (gs_sidelight_width_left_orig): 0.3 m; Hauteur seuil tierce vitrée 2: 0 m; Décalage axe pivot: 0.275 m; Tolérance côté 1: 0 m; Tolérance côté 1 inf.: 0 m; Tolérance tierce vitrée bas1: 0 m; Tolérance côté 2: 0 m; Tolérance côté 2 inf.: 0 m; Tolérance tierce vitrée bas 2: 0 m; Tolérance supérieure: 0 m; Tolérance inférieure: 0 m; Largeur cavité mur: 2 m; Hauteur cavité mur: 2.1 m; Largeur ébrasure: 2 m; Hauteur ébrasure: 2.1 m; Largeur unité: 2 m; Hauteur unité: 2.1 m; Largeur passage: 1.936 m; Hauteur passage: 2.068 m; Largeur battant: 1.96 m; Hauteur battant: 2.08 m; Epaisseur cadre: 0.1 m; Epaisseur cadre intérieur: 0.115 m; Décalage battant: 0 m; Largeur cadre: 0.032 m; Débord cadre: 0.01 m; Largeur cadre côté 1: 0.032 m; Largeur cadre centre côté 1: 0.032 m; Largeur cadre inf. côté 1: 0.032 m; Largeur cadre côté 2: 0.032 m; Largeur cadre centre côté 2: 0.032 m; Largeur cadre inf. côté 2: 0.032 m; Largeur cadre imposte (gs_frame_width_transom): 0.032 m; Largeur cadre supérieur: 0.032 m; Epaisseur butoir: 0.04 m; Largeur butoir: 0.016 m; Largeur feuillure: 0.012 m; Largeur feuillure tierce vitrée et imposte: 0.01 m; Profondeur feuillure tierce vitrée et imposte: 0.018 m; Largeur battant côté 1: 0.98 m; Epaisseur panneaux: 0.04 m; Larg. latérale cadre battant: 0.1 m; Larg. droite cadre battant: 0.1 m; Larg. gauche cadre battant: 0.1 m; Larg. inférieure cadre battant: 0.2 m; Larg. sup. cadre battant: 0.1 m; Largeur int. cadre battant: 0.025 m; Largeur meneau: 0.012 m; Épaisseur meneau: 0.025 m; Epaisseur vitrage: 0.007 m; Hauteur poignée: 1 m; Position poignée: 0.05 m; Hauteur division H côté tierce vitrée 1: 0.9 m; Hauteur division H côté tierce vitrée 2: 0.9 m; Hauteur division H imposte centre: 0.9 m; Hauteur division H côté imposte 1: 0.9 m; Hauteur division H côté imposte 2: 0.9 m; Epaisseur cadre tierce vitrée et imposte: 0.044 m; Largeur cadre imposte (gs_sash_width): 0.067 m; Largeur cadre châssis vitré: 0.067 m; Largeur grille: 0.02 m; Epaisseur grille: 0.025 m; Largeur division tierce vitrée: 0.04 m; Epaisseur division tierce vitrée: 0.1 m; Hauteur imposte: 0.3 m; Largeur côté 1 (gs_tw_right_out): 0.075 m; Largeur côté 2 (gs_tw_left_out): 0.075 m; Largeur haut (gs_tw_top_out): 0.075 m; Epaisseur sur mur (gs_trim_thk_out): 0.005 m; Epaisseur dans trou de mur (gs_trim_width_out): 0.005 m; Décalage (gs_trim_offs_out): 0.012 m; Débord supérieur (gs_trimov_top_left_out): 0 m; Débord supérieur (gs_trimov_top_right_out): 0 m; Largeur côté 1 (gs_tw_right_in): 0.075 m; Largeur côté 2 (gs_tw_left_in): 0.075 m; Largeur haut (gs_tw_top_in): 0.075 m; Epaisseur sur mur (gs_trim_thk_in): 0.005 m; Epaisseur dans trou de mur (gs_trim_width_in): 0.005 m; Décalage (gs_trim_offs_in): 0.012 m; Débord supérieur (gs_trimov_top_left_in): 0 m; Débord supérieur (gs_trimov_top_right_in): 0 m; Epaisseur seuil: 0.012 m; Largeur seuil: 0.01 m; Epaisseur externe seuil: 0.00580738 m; Nez seuil extérieur: 0.025 m; Nez seuil intérieur: 0.025 m; Débord côté ext.: 0 m; Débord côté int.: 0 m; Epaisseur appui: 0.025 m; Epaisseur front appui: 0.07 m; Altitude appui: 0.005 m; Débord larmier appui: 0.02 m; Largeur larmier appui: 0.03 m; Débord appui: 0.03 m; Débord seuil sur côté 1: 0 m; Débord seuil sur côté 2: 0 m; Glissement appui en profondeur: 0.02 m; Largeur supérieure appui: 0.02 m; Hauteur supérieure appui: 0.01 m; Glissement appui de mur: 0 m; Profondeur trou arrière (gs_sill_holeDepthBehind): 0.0013084 m; Largeur appui: 0.0513788 m; Epaisseur brique (gs_brick_sill_br_thk): 0.065 m; Epaisseur mortier (gs_brick_sill_mort_thk): 0.015 m; Largeur latte: 0.1 m; Epaisseur latte: 0.025 m; Débord tablette: 0.03 m; Débord tablette côté 1: 0 m; Débord tablette côté 2: 0 m; Glissement tabl. en profondeur: 0 m; Hauteur profil: 0.065 m; Epaisseur profil: 0.11 m; Hauteur panneau: 1.5 m; Décalage intérieur: 0.02 m; Profondeur fermeture: 0 m; Largeur cadre supplémentaire: 0.04 m; Epaisseur cadre supplémentaire: 0.03 m; Epaisseur allège vitrée: 0.03 m; Longueur colonne centrale: 0.02 m; Rayon colonne centrale: 0.005 m; Distance panneau: 0.006 m; Débord extérieur: 0 m; Largeur panneau intérieur: 0.12 m; Longueur ouverture en 3D: 1.5 m; Longueur fermée en 3D: 0 m; Longueur ouverture 1 en 3D: 0.56 m; Longueur ouverture 2 en 3D: 0.14 m; Hauteur ouverture en 3D: 1.5 m; Hauteur fermée en 3D: 0 m; Epaisseur panneau: 0.05 m; Largeur cadre panneau: 0.05 m; Largeur cadre inférieur: 0.05 m; Largeur panneau: 0 m; Epaisseur hachure panneau: 0.01 m; Epaisseur persienne: 0.01 m; Largeur persienne: 0.04 m; Largeur diviseur cadre horiz.: 0.05 m; Largeur diviseur cadre vert.: 0.05 m; Rayon trou: 0.01 m; Largeur montant: 0.1 m; Largeur cadre Z: 0.05 m; Epaisseur cadre Z: 0.025 m; Epaisseur plans verticaux: 0.025 m; Epaisseur plans horizontaux: 0.025 m; Largeur appr. plans verticaux: 0.08 m; Largeur appr. plans horizontaux: 0.115 m; Hauteur boîte (gs_shutRoll_boxHeight): 0.2 m; Profondeur boîte (gs_shutRoll_boxWidth): 0.15 m; Décalage boîte gauche: 0 m; Décalage boîte droite: 0 m; Profondeur rails: 0.0725 m; Distance au mur (gs_shutRoll_distFromWall): 0 m; Distance au linteau (gs_shutRoll_distFromHead): 0 m; Largeur lamelle: 0.05 m; Hauteur boîte (gs_shutLam_boxHeight): 0.2 m; Profondeur boîte (gs_shutLam_boxWidth): 0.15 m; Largeur recouvrement: 0 m; Distance au mur (gs_shutLam_distFromWall): 0 m; Distance au linteau (gs_shutLam_distFromHead): 0 m; Largeur segment (gs_shutLam_segmentWidth): 0.06 m; Hauteur boîte (gs_shutLam2_boxHeight): 0.06 m; Largeur boîte: 0.06 m; Distance à fenêtre: 0.06 m; Distance au linteau (gs_shutLam2_distFromHead): 0.06 m; Hauteur axe cellule à linteau: 0 m; Largeur segment (gs_shutLam2_segmentWidth): 0.06 m; Distance entre arche et fenêtre: 0 m; Dépassement linteau côté 1: 0 m; Dépassement linteau côté 2: 0 m; Elevation linteau: 0.03 m; Décalage linteau: 0 m; Hauteur linteau: 0.25 m; Profondeur linteau: 0.12 m; Profondeur trou arrière (gs_masonry_arch_rearHoleDepth): 0 m; Epaisseur brique (gs_masonry_arch_brick_thk): 0.065 m; Epaisseur mortier (gs_masonry_arch_mort_thk): 0.01 m; Largeur clé de voûte: 0.1 m; Dépassement clé de voûte: 0 m; Projection clé de voûte: 0.01 m; Profondeur ébrasure : (gs_wido_sill): 0 m; Profondeur ébrasure : (AC_wido_sill): 0 m; Profondeur montant: 0.06 m; Profondeur montant côté 2: 0.06 m; Profondeur montant inf. côté 1: 0.06 m; Profondeur montant inf. côté 2: 0.06 m; Profondeur montant int. côté 2 (gs_reveal_splayed_innerLeft): 0.06 m; Profondeur montant intérieur (gs_reveal_splayed_innerRight): 0.06 m; Profondeur montant intérieur (gs_reveal_double_innerRight): 0.06 m; Profondeur montant int. côté 2 (gs_reveal_double_innerLeft): 0.06 m; Profondeur montant inf. int. côté 1: 0.06 m; Profondeur montant inf. int. côté 2: 0.06 m; Profondeur tête: 0.06 m; Profondeur appui: 0 m; Profondeur seuil sur côté 1: 0.06 m; Profondeur seuil sur côté 2: 0.06 m; Profondeur linteau int. (gs_reveal_splayed_innerTop): 0.06 m; Profondeur appui int. (gs_reveal_splayed_innerBottom): 0.06 m; Profondeur linteau int. (gs_reveal_double_innerTop): 0.06 m; Profondeur appui int. (gs_reveal_double_innerBottom): 0 m; Profondeur seuil int. côté 1: 0 m; Profondeur seuil int. côté 2: 0 m; Profondeur montant ext.: 0.08 m; Limite épaisseur plâtre: 0.04 m; Distance de couche / fermeture: 0 m; Largeur fermeture: 0.038 m; Epaisseur fermeture: 0.1 m; Epaisseur bande: 0.025 m; Largeur profilé: 0.15 m; Epaisseur personnalisée: 0.015 m; Dépassement couche prof. cadre: 0 m; Dépassement ouverture gauche: 0 m; Dépassement ouverture droite: 0 m; Dépassement ouverture supérieur: 0 m; Dépassement ouverture inférieur: 0 m; Largeur d'ouverture en 3D: 0 m; Largeur ouverture 3D côté 2: 0 m; Largeur d'ouverture en 2D: 0 m; Largeur ouverture 2D côté 2: 0 m; Distance ouverture 1 Châssis princ. côté 1: 0 m; Distance ouverture 2 Châssis princ. côté 1: 0 m; Distance ouverture 1 Châssis princ. côté 2: 0 m; Distance ouverture 2 Châssis princ. côté 2: 0 m; Distance ouverture 1 imposte centre: 0 m; Distance ouverture 2 imposte centre: 0 m; Distance ouverture 1 imposte côté 1: 0 m; Distance ouverture 2 imposte côté 1: 0 m; Distance ouverture 1 imposte côté 2: 0 m; Distance ouverture 2 imposte côté 2: 0 m; Côté ouverture Largeur 2 (ms_openingSWidth1): 0.1 m; Côté ouverture Largeur 1 (ms_openingSWidth2): 0.1 m; Côté ouverture Profondeur: 2 m; Côté ouverture Largeur 2 (ms_oppositeSWidth1): 0.1 m; Côté ouverture Largeur 1 (ms_oppositeSWidth2): 0.1 m; Côté opposé Profondeur: 1.2 m; Côté ouverture Largeur: 0 m; Dépass.ouverture gauche: 0 m; Dépass.ouverture à droite: 0 m; Dépass.ouverture supérieur: 0 m; Dépass.ouverture inférieur: 0 m; Epaisseur réelle du cadre: 0.1 m
Name | Stylo contour cadre | Stylo hachure cadre | Stylo cadre | Stylo vitrage = Stylo vitrage battant | Orientation porte | Altitude à Zéro du Projet (m) = Altitude à étage (m) = Hauteur appui à étage actuel (m) | Hauteur nominale seuil (m) = Hauteur seuil côté ébrasure (m) = Hauteur seuil côté opposé ébrasure (m) = Valeur Appui ou Linteau (m) | Hauteur nominale linteau (m) = Hauteur linteau côté opposé ébrasure (m) | Hauteur linteau côté ébrasure (m)
DOOR | Ouvertures - Coupé structurel | Ouvertures - Hachures coupées | Ouvertures - Général | Maçonnerie | G | 0.12 | 0.12 | 2.22 | 2.16 | ArchiCADProperties - Nom de Zone: Surface expoitation; Numéro de Zone: 007; De Zone: Surface expoitation; De la Zone numéro: 007
DOOR | A construire - Coupe | A construire - Coupe | A construire - Coupe | A construire - Coupe | D | 0.1 | 0 | 2.1 | 2.04

# IfcDoor: IFC Porte - Enroulée (2)
In: Rez de chaussée
Type - OperationType: ROLLINGUP; ConstructionType: ALUMINIUM; ParameterTakesPrecedence: yes; Sizeable: no
Type - Propriétés Doublure Porte - LiningDepth: 0.1 m; LiningThickness: 0.05 m; LiningOffset: 0 m
Type - Propriétés Panneau Porte - Panneau1 - PanelDepth: 0.04 m; PanelOperation: ROLLINGUP; PanelWidth: 1; PanelPosition: MIDDLE
Description: DOOR; OverallHeight: 3.5 m; OverallWidth: 2.94934 m; Material: Background Fill-International, Air Space
ArchiCADProperties - ID: DOOR; Etage d'implantation: Rez de chaussée; Nom de Zone: Garage; Numéro de Zone: 004; Calque: A-WALL-EXTR; Type: Porte; Verrouillé: no; Nom Elément de Bibliothèque: IFC Porte - Enroulée; Matériau de construction / Composite / Profil / Hachure: Solid Fill; Fonction structurelle: Elément non porteur; Position: Intérieur; Classification d'lément: Porte; Etat de rénovation: Existant; Afficher sur filtre de rénovation: Tous les filtres appropriés; Texte Marque: DOOR; De Zone: Garage; Orientation: G; De la Zone numéro: 004; Dimensions ébrasure: 116,12"x137,80"; Dimensions trou mur: 116,12"x137,80"; Dimensions unité: 116,12"x137,80"; Dimensions sortie: 112,18"x135,83"; Dimensions battant: 112,18"x135,83"; Structure mur: 1.2-Mur ext: revét ext + isol ext + maçonnerie + enduit; Taille L x H nominale: 116,12"x137,80"; Taille L x H x E nominale: 116,12"x137,80"x14,57"
AC_Pset_IFC_Porte_-_Enroulée - Contours Mur (0-Sans,1-Tout,2-Côté,3-Longueur): 1; Point ch.0-Non,1-2D,2-3D,3-Tous: 3; Afficher points chauds 2D en 3D: yes; Trou reprend surface latérale de mur: no; Division de surface de trou courbée: no; Type racine: IfcDoor; Matière de construction: Aluminum; ID matériau de construction: 1; Cadre porte (Revêtement) (ifc_door_frame): yes; Epaisseur cadre = Epaisseur mur: no; Ajuster largeur panneau à trou: yes; Largeur panneau: 1; Encadr./Chambranle: no; Seuil: no; Ajuster larg. seuil revêtement: yes; Imposte: no; Ligne d'ouverture en 2D: yes; Type ligne d'ouverture en 2D: 4; Stylo du symbole: Ouvertures - Général; Angle ouverture en 2D: 0 deg; Motif de hachure cadre: Background Fill-International; Stylo hachure cadre: Ouvertures - Hachures coupées; Stylo fond de hachure cadre: Fond - Couleur 1; Motif de hachure battant: Air Space; Stylo hachure de battant: Fond - Couleur 1; Stylo fond de hachure battant: Fond - Couleur 1; Stylo cadre: Eléments 2D - Général; Stylo panneaux: Eléments 2D - Général; Angle ouverture en 3D: 0 deg; Surface de cadre: 06 | W Pine V; Surface de battant: 06 | W Pine H; Surface d'imposte: 08 | Glass-Clear; Surface de seuil: 06 | W Pine V; Opération IFC (ifc_optypestr): Déroulement vers le haut; Opération IFC (ifc_optype): 11
AC_Pset_RenovationAndPhasing - Renovation Status: Existing
Pset_DoorCommon - IsExternal: no
BaseQuantities - Height: 3.5 m; Width: 2.94934 m; Perimeter: 12.8987 m; Area: 10.3227 m2; Volume: 0.442455 m3; Depth: 0.37 m
ArchiCADQuantities - Altitude à Zéro du Projet: 0.12 m; Altitude à étage: 0.12 m; Hauteur: 3.5 m; Superficie de surface: 23.1292 m2; Volume net: 0.442455 m3; Largeur: 2.94934 m; Epaisseur: 0.1 m; Hauteur nominale seuil: 0.12 m; Hauteur seuil côté ébrasure: 0.12 m; Hauteur seuil côté opposé ébrasure: 0.12 m; Hauteur nominale linteau: 3.62 m; Hauteur linteau côté ébrasure: 3.62 m; Hauteur linteau côté opposé ébrasure: 3.62 m; Largeur ouverture côté ébrasure: 2.94934 m; Largeur ouverture côté opposé ébrasure: 2.94934 m; Hauteur ouverture côté ébrasure: 3.5 m; Hauteur ouverture côté opposé ébrasure: 3.5 m; Surface ouverture côté ébrasure: 10.3227 m2; Surface ouverture côté opposé ébrasure: 10.3227 m2; Largeur nominale de l'ouverture côté ébrasure: 2.94934 m; Largeur nominale de l'ouverture côté opposée ébrasure: 2.94934 m; Hauteur nominale de l'ouverture côté ébrasure: 3.5 m; Hauteur nominale de l'ouverture côté opposée ébrasure: 3.5 m; Surface nominale de l'ouverture P/F côté ébrasure: 10.3227 m2; Surface nominale de l'ouverture P/F côté opposé ébrasure: 10.3227 m2; Volume ouverture: 0.442455 m3; Surface nominale ouverture P/F: 10.3227 m2; Volume nominal ouverture: 3.81939 m3; Valeur Appui ou Linteau: 0.12 m; Epaisseur de Mur: 0.37 m
AC_Equantity_IFC_Porte_-_Enroulée - 1ère dimension: 2.94934 m; 2ème dimension: 3.5 m; Hauteur: 1 m; Niveau inférieur: 1 m; Niveau supérieur: 0 m; Largeur cavité mur: 2.94934 m; Hauteur cavité mur: 3.5 m; Largeur ébrasure: 2.94934 m; Hauteur ébrasure: 3.5 m; Largeur unité: 2.94934 m; Hauteur unité: 3.5 m; Largeur passage: 2.84934 m; Hauteur passage: 3.45 m; Largeur battant: 2.84934 m; Hauteur battant: 3.45 m; Epaisseur cadre: 0.1 m; Largeur cadre: 0.05 m; Epaisseur panneaux: 0.04 m; Couper épaisseur (Profondeur de chambranle): 0.02 m; Couper largeur (Epaisseur de chambranle): 0.1 m; Largeur seuil: 0.1 m; Décalage seuil: 0 m; Epaisseur seuil: 0.025 m; Hauteur panneau de porte: 1.5 m; Epaisseur imposte: 0.05 m; Hauteur ouverture en 3D: 0 m; Dépass.ouverture gauche: 0 m; Dépass.ouverture à droite: 0 m; Dépass.ouverture supérieur: 0 m; Dépass.ouverture inférieur: 0 m

# IfcDoor: IFC Porte - Simple battant (13)
Type - OperationType: SINGLE_SWING_LEFT; ParameterTakesPrecedence: yes; Sizeable: no
Type - Propriétés Doublure Porte - LiningDepth: 0.1 m; LiningThickness: 0.05 m; LiningOffset: 0 m
Type - Propriétés Panneau Porte - Panneau1 - PanelDepth: 0.04 m; PanelOperation: SWINGING; PanelWidth: 1; PanelPosition: MIDDLE
Description: DOOR_1000; OverallHeight: 2.1 m; OverallWidth: 1 m; Material: Background Fill-International, Air Space
ArchiCADProperties - ID: DOOR_1000; Calque: A-WALL-INTR; Type: Porte; Verrouillé: no; Nom Elément de Bibliothèque: IFC Porte - Simple battant; Matériau de construction / Composite / Profil / Hachure: Solid Fill; Fonction structurelle: Elément non porteur; Position: Intérieur; Classification d'lément: Porte; Etat de rénovation: Existant; Afficher sur filtre de rénovation: Tous les filtres appropriés; Texte Marque: DOOR_1000; Orientation: D; Dimensions ébrasure: 39,37"x82,68"; Dimensions trou mur: 39,37"x82,68"; Dimensions unité: 39,37"x82,68"; Dimensions sortie: 35,43"x80,71"; Dimensions battant: 35,43"x80,71"; Structure mur: 0.0-Cloison: parpaing + plâtre 2 faces copie; Taille L x H nominale: 39,37"x82,68"; Taille L x H x E nominale: 39,37"x82,68"x5,12"
AC_Pset_IFC_Porte_-_Simple_battant - Contours Mur (0-Sans,1-Tout,2-Côté,3-Longueur): 1; Point ch.0-Non,1-2D,2-3D,3-Tous: 3; Afficher points chauds 2D en 3D: yes; Trou reprend surface latérale de mur: no; Division de surface de trou courbée: no; Type racine: IfcDoor; Matière de construction: Non défini; ID matériau de construction: 0; Cadre porte (Revêtement) (ifc_door_frame): yes; Epaisseur cadre = Epaisseur mur: no; Ajuster largeur panneau à trou: yes; Largeur panneau: 1; Encadr./Chambranle: no; Seuil: no; Ajuster larg. seuil revêtement: yes; Imposte: no; Angle ouverture en 2D: 90 deg; Stylo du symbole: Ouvertures - Général; Motif de hachure cadre: Background Fill-International; Stylo hachure cadre: Ouvertures - Hachures coupées; Stylo fond de hachure cadre: Fond - Couleur 1; Motif de hachure battant: Air Space; Stylo hachure de battant: Fond - Couleur 1; Stylo fond de hachure battant: Fond - Couleur 1; Angle ouverture en 3D: 0 deg; Stylo cadre: Eléments 2D - Général; Stylo panneaux: Eléments 2D - Général; Surface de cadre: 06 | W Pine V; Surface de battant: 06 | W Pine H; Surface d'imposte: 08 | Glass-Clear; Surface de seuil: 06 | W Pine V; Opération IFC (ifc_optypestr): Porte simple battant simple; Opération IFC (ifc_optype): 1
AC_Pset_RenovationAndPhasing - Renovation Status: Existing
Pset_DoorCommon - IsExternal: no
BaseQuantities - Height: 2.1 m; Width: 1 m; Perimeter: 6.2 m; Area: 2.1 m2; Volume: 0.0993 m3; Depth: 0.13 m
ArchiCADQuantities - Hauteur: 2.1 m; Superficie de surface: 5.466 m2; Volume net: 0.0993 m3; Largeur: 1 m; Epaisseur: 0.1 m; Largeur ouverture côté ébrasure: 1 m; Largeur ouverture côté opposé ébrasure: 1 m; Hauteur ouverture côté ébrasure: 2.1 m; Hauteur ouverture côté opposé ébrasure: 2.1 m; Surface ouverture côté ébrasure: 2.1 m2; Surface ouverture côté opposé ébrasure: 2.1 m2; Largeur nominale de l'ouverture côté ébrasure: 1 m; Largeur nominale de l'ouverture côté opposée ébrasure: 1 m; Hauteur nominale de l'ouverture côté ébrasure: 2.1 m; Hauteur nominale de l'ouverture côté opposée ébrasure: 2.1 m; Surface nominale de l'ouverture P/F côté ébrasure: 2.1 m2; Surface nominale de l'ouverture P/F côté opposé ébrasure: 2.1 m2; Volume ouverture: 0.0993 m3; Surface nominale ouverture P/F: 2.1 m2; Volume nominal ouverture: 0.273 m3; Epaisseur de Mur: 0.13 m
AC_Equantity_IFC_Porte_-_Simple_battant - 1ère dimension: 1 m; 2ème dimension: 2.1 m; Hauteur: 1 m; Niveau inférieur: 1 m; Niveau supérieur: 0 m; Largeur cavité mur: 1 m; Hauteur cavité mur: 2.1 m; Largeur ébrasure: 1 m; Hauteur ébrasure: 2.1 m; Largeur unité: 1 m; Hauteur unité: 2.1 m; Largeur passage: 0.9 m; Hauteur passage: 2.05 m; Largeur battant: 0.9 m; Hauteur battant: 2.05 m; Epaisseur cadre: 0.1 m; Largeur cadre: 0.05 m; Epaisseur panneaux: 0.04 m; Couper épaisseur (Profondeur de chambranle): 0.02 m; Couper largeur (Epaisseur de chambranle): 0.1 m; Largeur seuil: 0.1 m; Décalage seuil: 0 m; Epaisseur seuil: 0.02 m; Hauteur panneau de porte: 1.5 m; Epaisseur imposte: 0.05 m; Dépass.ouverture gauche: 0 m; Dépass.ouverture à droite: 0 m; Dépass.ouverture supérieur: 0 m; Dépass.ouverture inférieur: 0 m
Name | In | Etage d'implantation | Nom de Zone = De Zone | Numéro de Zone = De la Zone numéro | Altitude à Zéro du Projet (m) | Altitude à étage (m) | Hauteur nominale seuil (m) = Hauteur seuil côté ébrasure (m) = Hauteur seuil côté opposé ébrasure (m) = Valeur Appui ou Linteau (m) | Hauteur nominale linteau (m) = Hauteur linteau côté ébrasure (m) = Hauteur linteau côté opposé ébrasure (m)
DOOR_1000 | Rez de chaussée | Rez de chaussée | Dégagement | 001 | 0.12 | 0.12 | 0.12 | 2.22
DOOR_1000 | Rez de chaussée | Rez de chaussée | Rangement | 004 | 0.12 | 0.12 | 0.12 | 2.22
DOOR_1000 | Rez de chaussée | Rez de chaussée | Rangement | 006 | 0.12 | 0.12 | 0.12 | 2.22
DOOR_1000 | Rez de chaussée | Rez de chaussée | Cage Escalier | 001 | 0 | 0 | 0 | 2.1
DOOR_1000 | R+1 | R+1 | WC | 006 | 5.4 | 0 | 0.1 | 2.2
DOOR_1000 | R+1 | R+1 | WC | 004 | 5.4 | 0 | 0.1 | 2.2
DOOR_1000 | R+1 | R+1 |  |  | 5.3 | -0.1 | 0 | 2.1
DOOR_1000 | Mezzannine | Mezzannine | WC | 006 | 9.425 | 3.55271e-15 | 0.12 | 2.22
DOOR_1000 | Mezzannine | Mezzannine | WC | 004 | 9.425 | 3.55271e-15 | 0.12 | 2.22
DOOR_1000 | Mezzannine | Mezzannine |  |  | 9.305 | -0.12 | 0 | 2.1
DOOR_1000 | R+2 | R+2 |  |  | 13.33 | -0.12 | 0 | 2.1
DOOR_1000 | R+2 | R+2 | Rangement | 006 | 13.45 | 0 | 0.12 | 2.22
DOOR_1000 | R+2 | R+2 | Rangement | 004 | 13.45 | 0 | 0.12 | 2.22

# IfcDoor: IFC Porte - Simple battant (4)
Type - OperationType: SINGLE_SWING_LEFT; ParameterTakesPrecedence: yes; Sizeable: no
Type - Propriétés Doublure Porte - LiningDepth: 0.1 m; LiningThickness: 0.05 m; LiningOffset: 0.13 m
Type - Propriétés Panneau Porte - Panneau1 - PanelDepth: 0.04 m; PanelOperation: SWINGING; PanelWidth: 1; PanelPosition: MIDDLE
Description: DOOR_1000; OverallHeight: 2.1 m; OverallWidth: 1 m; Material: Background Fill-International, Air Space
ArchiCADProperties - ID: DOOR_1000; Numéro de Zone: 006; Calque: A-WALL-INTR; Type: Porte; Verrouillé: no; Nom Elément de Bibliothèque: IFC Porte - Simple battant; Matériau de construction / Composite / Profil / Hachure: Solid Fill; Fonction structurelle: Elément non porteur; Position: Intérieur; Classification d'lément: Porte; Etat de rénovation: Existant; Afficher sur filtre de rénovation: Tous les filtres appropriés; Texte Marque: DOOR_1000; Orientation: D; De la Zone numéro: 006; Dimensions ébrasure: 39,37"x82,68"; Dimensions trou mur: 39,37"x82,68"; Dimensions unité: 39,37"x82,68"; Dimensions sortie: 35,43"x80,71"; Dimensions battant: 35,43"x80,71"; Structure mur: 0.0-Cloison: parpaing + plâtre 2 faces copie; Taille L x H nominale: 39,37"x82,68"; Taille L x H x E nominale: 39,37"x82,68"x5,12"
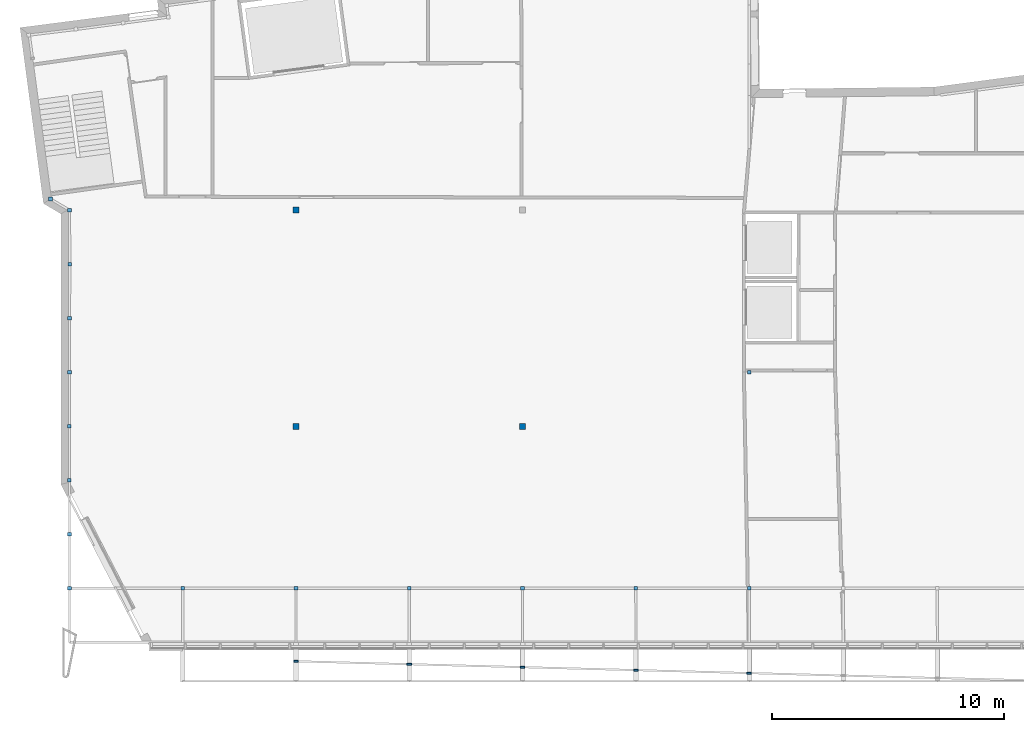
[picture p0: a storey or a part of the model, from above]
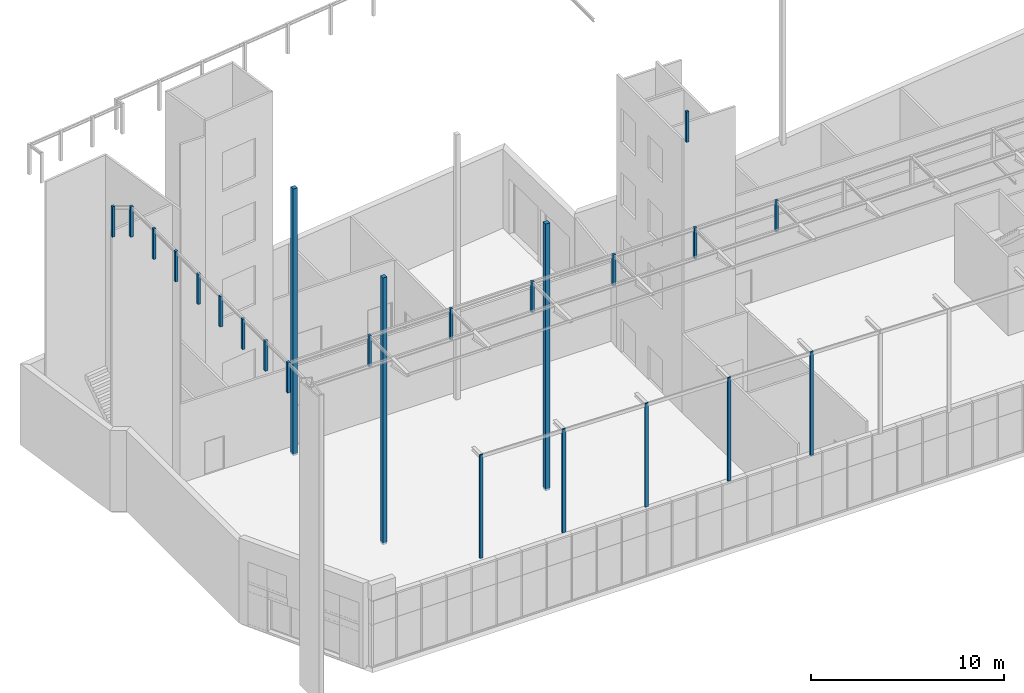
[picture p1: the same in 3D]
Properties of the parts of a building model (IFC2X3), part 3 of 19

# IfcDoor: IFC Porte - Simple battant (4)
AC_Pset_IFC_Porte_-_Simple_battant - Contours Mur (0-Sans,1-Tout,2-Côté,3-Longueur): 1; Point ch.0-Non,1-2D,2-3D,3-Tous: 3; Afficher points chauds 2D en 3D: yes; Trou reprend surface latérale de mur: no; Division de surface de trou courbée: no; Type racine: IfcDoor; Matière de construction: Non défini; ID matériau de construction: 0; Cadre porte (Revêtement) (ifc_door_frame): yes; Epaisseur cadre = Epaisseur mur: no; Ajuster largeur panneau à trou: yes; Largeur panneau: 1; Encadr./Chambranle: no; Seuil: no; Ajuster larg. seuil revêtement: yes; Imposte: no; Angle ouverture en 2D: 90 deg; Stylo du symbole: Ouvertures - Général; Motif de hachure cadre: Background Fill-International; Stylo hachure cadre: Ouvertures - Hachures coupées; Stylo fond de hachure cadre: Fond - Couleur 1; Motif de hachure battant: Air Space; Stylo hachure de battant: Fond - Couleur 1; Stylo fond de hachure battant: Fond - Couleur 1; Angle ouverture en 3D: 0 deg; Stylo cadre: Eléments 2D - Général; Stylo panneaux: Eléments 2D - Général; Surface de cadre: 06 | W Pine V; Surface de battant: 06 | W Pine H; Surface d'imposte: 08 | Glass-Clear; Surface de seuil: 06 | W Pine V; Opération IFC (ifc_optypestr): Porte simple battant simple; Opération IFC (ifc_optype): 1
AC_Pset_RenovationAndPhasing - Renovation Status: Existing
Pset_DoorCommon - IsExternal: no
BaseQuantities - Height: 2.1 m; Width: 1 m; Perimeter: 6.2 m; Area: 2.1 m2; Volume: 0.0993 m3; Depth: 0.13 m
ArchiCADQuantities - Altitude à étage: 0 m; Hauteur: 2.1 m; Superficie de surface: 5.466 m2; Volume net: 0.0993 m3; Largeur: 1 m; Epaisseur: 0.1 m; Largeur ouverture côté ébrasure: 1 m; Largeur ouverture côté opposé ébrasure: 1 m; Hauteur ouverture côté ébrasure: 2.1 m; Hauteur ouverture côté opposé ébrasure: 2.1 m; Surface ouverture côté ébrasure: 2.1 m2; Surface ouverture côté opposé ébrasure: 2.1 m2; Largeur nominale de l'ouverture côté ébrasure: 1 m; Largeur nominale de l'ouverture côté opposée ébrasure: 1 m; Hauteur nominale de l'ouverture côté ébrasure: 2.1 m; Hauteur nominale de l'ouverture côté opposée ébrasure: 2.1 m; Surface nominale de l'ouverture P/F côté ébrasure: 2.1 m2; Surface nominale de l'ouverture P/F côté opposé ébrasure: 2.1 m2; Volume ouverture: 0.0993 m3; Surface nominale ouverture P/F: 2.1 m2; Volume nominal ouverture: 0.273 m3; Epaisseur de Mur: 0.13 m
AC_Equantity_IFC_Porte_-_Simple_battant - 1ère dimension: 1 m; 2ème dimension: 2.1 m; Hauteur: 1 m; Niveau inférieur: 1 m; Niveau supérieur: 0 m; Largeur cavité mur: 1 m; Hauteur cavité mur: 2.1 m; Largeur ébrasure: 1 m; Hauteur ébrasure: 2.1 m; Largeur unité: 1 m; Hauteur unité: 2.1 m; Largeur passage: 0.9 m; Hauteur passage: 2.05 m; Largeur battant: 0.9 m; Hauteur battant: 2.05 m; Epaisseur cadre: 0.1 m; Largeur cadre: 0.05 m; Epaisseur panneaux: 0.04 m; Couper épaisseur (Profondeur de chambranle): 0.02 m; Couper largeur (Epaisseur de chambranle): 0.1 m; Largeur seuil: 0.1 m; Décalage seuil: 0 m; Epaisseur seuil: 0.02 m; Hauteur panneau de porte: 1.5 m; Epaisseur imposte: 0.05 m; Dépass.ouverture gauche: 0 m; Dépass.ouverture à droite: 0 m; Dépass.ouverture supérieur: 0 m; Dépass.ouverture inférieur: 0 m
Name | In | Etage d'implantation | Nom de Zone = De Zone | Altitude à Zéro du Projet (m) | Hauteur nominale seuil (m) = Hauteur seuil côté ébrasure (m) = Hauteur seuil côté opposé ébrasure (m) = Valeur Appui ou Linteau (m) | Hauteur nominale linteau (m) = Hauteur linteau côté ébrasure (m) = Hauteur linteau côté opposé ébrasure (m)
DOOR_1000 | Rez de chaussée | Rez de chaussée | Rangement | 0 | 0 | 2.1
DOOR_1000 | R+1 | R+1 | WC | 5.4 | 0.1 | 2.2
DOOR_1000 | Mezzannine | Mezzannine | WC | 9.425 | 0.12 | 2.22
DOOR_1000 | R+2 | R+2 | Rangement | 13.45 | 0.12 | 2.22

# IfcDoor: IFC Porte - Simple battant (15)
Type - OperationType: SINGLE_SWING_RIGHT; ParameterTakesPrecedence: yes; Sizeable: no
Type - Propriétés Doublure Porte - LiningDepth: 0.1 m; LiningThickness: 0.05 m; LiningOffset: 0 m
Type - Propriétés Panneau Porte - Panneau1 - PanelDepth: 0.04 m; PanelOperation: SWINGING; PanelWidth: 1; PanelPosition: MIDDLE
OverallHeight: 2.1 m; Material: Background Fill-International, Air Space
ArchiCADProperties - Type: Porte; Verrouillé: no; Nom Elément de Bibliothèque: IFC Porte - Simple battant; Matériau de construction / Composite / Profil / Hachure: Solid Fill; Fonction structurelle: Elément non porteur; Position: Intérieur; Classification d'lément: Porte; Etat de rénovation: Existant; Afficher sur filtre de rénovation: Tous les filtres appropriés; Orientation: G
AC_Pset_IFC_Porte_-_Simple_battant - Contours Mur (0-Sans,1-Tout,2-Côté,3-Longueur): 1; Point ch.0-Non,1-2D,2-3D,3-Tous: 3; Afficher points chauds 2D en 3D: yes; Trou reprend surface latérale de mur: no; Division de surface de trou courbée: no; Type racine: IfcDoor; Matière de construction: Non défini; ID matériau de construction: 0; Cadre porte (Revêtement) (ifc_door_frame): yes; Epaisseur cadre = Epaisseur mur: no; Ajuster largeur panneau à trou: yes; Largeur panneau: 1; Encadr./Chambranle: no; Seuil: no; Ajuster larg. seuil revêtement: yes; Imposte: no; Angle ouverture en 2D: 90 deg; Stylo du symbole: Ouvertures - Général; Motif de hachure cadre: Background Fill-International; Stylo hachure cadre: Ouvertures - Hachures coupées; Stylo fond de hachure cadre: Fond - Couleur 1; Motif de hachure battant: Air Space; Stylo hachure de battant: Fond - Couleur 1; Stylo fond de hachure battant: Fond - Couleur 1; Angle ouverture en 3D: 0 deg; Stylo cadre: Eléments 2D - Général; Stylo panneaux: Eléments 2D - Général; Surface de cadre: 06 | W Pine V; Surface de battant: 06 | W Pine H; Surface d'imposte: 08 | Glass-Clear; Surface de seuil: 06 | W Pine V; Opération IFC (ifc_optypestr): Porte simple battant simple; Opération IFC (ifc_optype): 1
AC_Pset_RenovationAndPhasing - Renovation Status: Existing
Pset_DoorCommon - IsExternal: no
ArchiCADQuantities - Hauteur: 2.1 m; Epaisseur: 0.1 m; Hauteur nominale de l'ouverture côté ébrasure: 2.1 m; Hauteur nominale de l'ouverture côté opposée ébrasure: 2.1 m
AC_Equantity_IFC_Porte_-_Simple_battant - 2ème dimension: 2.1 m; Hauteur: 1 m; Niveau inférieur: 1 m; Niveau supérieur: 0 m; Hauteur cavité mur: 2.1 m; Hauteur ébrasure: 2.1 m; Hauteur unité: 2.1 m; Hauteur passage: 2.05 m; Hauteur battant: 2.05 m; Epaisseur cadre: 0.1 m; Largeur cadre: 0.05 m; Epaisseur panneaux: 0.04 m; Couper épaisseur (Profondeur de chambranle): 0.02 m; Couper largeur (Epaisseur de chambranle): 0.1 m; Largeur seuil: 0.1 m; Décalage seuil: 0 m; Epaisseur seuil: 0.02 m; Hauteur panneau de porte: 1.5 m; Epaisseur imposte: 0.05 m; Dépass.ouverture gauche: 0 m; Dépass.ouverture à droite: 0 m; Dépass.ouverture supérieur: 0 m; Dépass.ouverture inférieur: 0 m
Name | In | Description = ID = Texte Marque | OverallWidth (m) = Width (m) = Largeur (m) = Largeur ouverture côté ébrasure (m) = Largeur ouverture côté opposé ébrasure (m) = Largeur nominale de l'ouverture côté ébrasure (m) = Largeur nominale de l'ouverture côté opposée ébrasure (m) = 1ère dimension (m) = Largeur cavité mur (m) = Largeur ébrasure (m) = Largeur unité (m) | Etage d'implantation | Nom de Zone = De Zone | Numéro de Zone = De la Zone numéro | Calque | Dimensions ébrasure = Dimensions trou mur = Dimensions unité = Taille L x H nominale | Dimensions sortie = Dimensions battant | Structure mur | Taille L x H x E nominale | Height (m) = Hauteur ouverture côté ébrasure (m) | Perimeter (m) | Area (m2) = Surface ouverture côté ébrasure (m2) | Volume (m3) = Volume net (m3) = Volume ouverture (m3) | Depth (m) = Epaisseur de Mur (m) | Altitude à Zéro du Projet (m) | Altitude à étage (m) | Superficie de surface (m2) | Hauteur nominale seuil (m) = Hauteur seuil côté ébrasure (m) = Hauteur seuil côté opposé ébrasure (m) = Valeur Appui ou Linteau (m) | Hauteur nominale linteau (m) = Hauteur linteau côté ébrasure (m) = Hauteur linteau côté opposé ébrasure (m) | Hauteur ouverture côté opposé ébrasure (m) | Surface ouverture côté opposé ébrasure (m2) | Surface nominale de l'ouverture P/F côté ébrasure (m2) = Surface nominale de l'ouverture P/F côté opposé ébrasure (m2) = Surface nominale ouverture P/F (m2) | Volume nominal ouverture (m3) | Largeur passage (m) = Largeur battant (m)
DOOR | Rez de chaussée | DOOR | 1.2 | Rez de chaussée | Dégagement | 001 | A-WALL-EXTR | 47,24"x82,68" | 43,31"x80,71" | 1.2-Mur ext: revét ext + isol ext + maçonnerie + enduit | 47,24"x82,68"x14,57" | 2.1 | 6.6 | 2.52 | 0.1167 | 0.37 | 0.105 | 0.105 | 6.362 | 0.105 | 2.205 | 2.1 | 2.52 | 2.52 | 0.9324 | 1.1
DOOR_1000 | Rez de chaussée | DOOR_1000 | 1 | Rez de chaussée | Dégagement | 003 | A-WALL-EXTR | 39,37"x82,68" | 35,43"x80,71" | 1.2-Mur ext: revét ext + isol ext + maçonnerie + enduit | 39,37"x82,68"x14,57" | 2.1 | 6.2 | 2.1 | 0.0993 | 0.37 | -0.195 | -0.195 | 5.466 | 0 | 2.1 | 2.1 | 2.1 | 2.1 | 0.777 | 0.9
DOOR | Rez de chaussée | DOOR | 1.25889 | Rez de chaussée | Dégagement | 002 | A-WALL-EXTR | 49,56"x82,68" | 45,63"x80,71" | 1.2-Mur ext: revét ext + isol ext + maçonnerie + enduit | 49,56"x82,68"x14,57" | 2.1 | 6.71779 | 2.64368 | 0.121824 | 0.37 | 0 | 0 | 6.62585 | 0 | 2.1 | 2.1 | 2.64368 | 2.64368 | 0.978161 | 1.15889
DOOR_1000 | Rez de chaussée | DOOR_1000 | 1 | Rez de chaussée | Dégagement | 002 | A-WALL-INTR | 39,37"x82,68" | 35,43"x80,71" | 0.0-Cloison: parpaing + plâtre 2 faces copie | 39,37"x82,68"x5,12" | 2.1 | 6.2 | 2.1 | 0.0993 | 0.13 | 0 | 0 | 5.466 | 0 | 2.1 | 2.1 | 2.1 | 2.1 | 0.273 | 0.9
DOOR | Rez de chaussée | DOOR | 1.2 | Rez de chaussée | Dégagement | 002 | A-WALL-INTR | 47,24"x82,68" | 43,31"x80,71" | 0.0-Cloison: parpaing + plâtre 2 faces copie | 47,24"x82,68"x5,12" | 2.1 | 6.6 | 2.52 | 0.1167 | 0.13 | 0.12 | 0.12 | 6.362 | 0.12 | 2.22 | 2.1 | 2.52 | 2.52 | 0.3276 | 1.1
DOOR_1000 | Rez de chaussée | DOOR_1000 | 1 | Rez de chaussée | Dégagement | 001 | A-WALL-INTR | 39,37"x82,68" | 35,43"x80,71" | 0.0-Cloison: parpaing + plâtre 2 faces copie | 39,37"x82,68"x5,12" | 2.1 | 6.2 | 2.1 | 0.0993 | 0.13 | 0 | 0 | 5.466 | 0 | 2.1 | 2.1 | 2.1 | 2.1 | 0.273 | 0.9
DOOR_1000 | R+1 | DOOR_1000 | 1 | R+1 | Dégagement | 001 | A-WALL-INTR | 39,37"x82,68" | 35,43"x80,71" | 0.0-Cloison: parpaing + plâtre 2 faces copie | 39,37"x82,68"x5,12" | 2.1 | 6.2 | 2.1 | 0.0993 | 0.13 | 5.4 | 0 | 5.466 | 0.1 | 2.2 | 2.1 | 2.1 | 2.1 | 0.273 | 0.9
DOOR_1000 | R+1 | DOOR_1000 | 1 | R+1 | Plateau bureaux | 005 | A-WALL-INTR | 39,37"x82,68" | 35,43"x80,71" | 0.0-Cloison: parpaing + plâtre 2 faces copie | 39,37"x82,68"x5,12" | 2.1 | 6.2 | 2.1 | 0.0993 | 0.13 | 5.4 | 0 | 5.466 | 0 | 2.1 | 2.1 | 2.1 | 2.1 | 0.273 | 0.9
DOOR_1000 | Mezzannine | DOOR_1000 | 1 | Mezzannine | Cafetaria | 007 | A-WALL-INTR | 39,37"x82,68" | 35,43"x80,71" | 0.0-Cloison: parpaing + plâtre 2 faces copie | 39,37"x82,68"x5,12" | 2.1 | 6.2 | 2.1 | 0.0993 | 0.13 | 9.425 | 0 | 5.466 | 0 | 2.1 | 2.1 | 2.1 | 2.1 | 0.273 | 0.9
DOOR_1000 | Mezzannine | DOOR_1000 | 1 | Mezzannine |  |  | A-WALL-INTR | 39,37"x82,68" | 35,43"x80,71" | 0.0-Cloison: parpaing + plâtre 2 faces copie | 39,37"x82,68"x5,12" | 2.1 | 6.2 | 2.1 | 0.0993 | 0.13 | 9.425 | 0 | 5.466 | 0.12 | 2.22 | 2.1 | 2.1 | 2.1 | 0.273 | 0.9
DOOR_1000 | R+2 | DOOR_1000 | 1 | R+2 |  |  | A-WALL-INTR | 39,37"x82,68" | 35,43"x80,71" | 0.0-Cloison: parpaing + plâtre 2 faces copie | 39,37"x82,68"x5,12" | 2.1 | 6.2 | 2.1 | 0.0993 | 0.13 | 13.45 | 0 | 5.466 | 0 | 2.1 | 2.1 | 2.1 | 2.1 | 0.273 | 0.9
DOOR_1000 | R+2 | DOOR_1000 | 1 | R+2 |  |  | A-WALL-INTR | 39,37"x82,68" | 35,43"x80,71" | 0.0-Cloison: parpaing + plâtre 2 faces copie | 39,37"x82,68"x5,12" | 2.1 | 6.2 | 2.1 | 0.0993 | 0.13 | 13.45 | -8.20677e-13 | 5.466 | 0.12 | 2.22 | 2.1 | 2.1 | 2.1 | 0.273 | 0.9
DOOR_1000 | Toiture | DOOR_1000 | 1 | Toiture |  |  | A-WALL-INTR | 39,37"x82,68" | 35,43"x80,71" | 0.0-Cloison: parpaing + plâtre 2 faces copie | 39,37"x82,68"x5,12" | 1.84981 | 5.69962 | 1.84981 | 0.0993 | 0.13 | 17.16 | -0.24 | 5.466 | 0 | 2.1 | 1.83844 | 1.83843 | 2.1 | 0.273 | 0.9
DOOR_1000 | Etage | DOOR_1000 | 1 |  |  |  | A-WALL-EXTR | 39,37"x82,68" | 35,43"x80,71" | 3.3-Refend: 2x béton + vide + enduit plâtre 2 faces | 39,37"x82,68"x11,02" | 2.1 | 6.2 | 2.1 | 0.0993 | 0.28 | 17.413 | 0.0129817 | 5.466 | 0.252982 | 2.35298 | 2.1 | 2.1 | 2.1 | 0.588 | 0.9
DOOR_1000 | Etage | DOOR_1000 | 1 |  | Local Tech. | 007 | A-WALL-EXTR | 39,37"x82,68" | 35,43"x80,71" | 1.2-Mur ext: revét ext + isol ext + maçonnerie + enduit | 39,37"x82,68"x14,57" | 2.1 | 6.2 | 2.1 | 0.0993 | 0.37 | 17.4182 | 0.0181735 | 5.466 | 0.258174 | 2.35817 | 2.1 | 2.1 | 2.1 | 0.777 | 0.9

# IfcDoor: IFC Porte - Simple battant (6)
Type - OperationType: SINGLE_SWING_RIGHT; ParameterTakesPrecedence: yes; Sizeable: no
Type - Propriétés Doublure Porte - LiningDepth: 0.1 m; LiningThickness: 0.05 m; LiningOffset: 0.13 m
Type - Propriétés Panneau Porte - Panneau1 - PanelDepth: 0.04 m; PanelOperation: SWINGING; PanelWidth: 1; PanelPosition: MIDDLE
Description: DOOR_1000; OverallHeight: 2.1 m; OverallWidth: 1 m; Material: Background Fill-International, Air Space
ArchiCADProperties - ID: DOOR_1000; Calque: A-WALL-INTR; Type: Porte; Verrouillé: no; Nom Elément de Bibliothèque: IFC Porte - Simple battant; Matériau de construction / Composite / Profil / Hachure: Solid Fill; Fonction structurelle: Elément non porteur; Position: Intérieur; Classification d'lément: Porte; Etat de rénovation: Existant; Afficher sur filtre de rénovation: Tous les filtres appropriés; Texte Marque: DOOR_1000; Orientation: G; Dimensions ébrasure: 39,37"x82,68"; Dimensions trou mur: 39,37"x82,68"; Dimensions unité: 39,37"x82,68"; Dimensions sortie: 35,43"x80,71"; Dimensions battant: 35,43"x80,71"; Structure mur: 0.0-Cloison: parpaing + plâtre 2 faces copie; Taille L x H nominale: 39,37"x82,68"; Taille L x H x E nominale: 39,37"x82,68"x5,12"
AC_Pset_IFC_Porte_-_Simple_battant - Contours Mur (0-Sans,1-Tout,2-Côté,3-Longueur): 1; Point ch.0-Non,1-2D,2-3D,3-Tous: 3; Afficher points chauds 2D en 3D: yes; Trou reprend surface latérale de mur: no; Division de surface de trou courbée: no; Type racine: IfcDoor; Matière de construction: Non défini; ID matériau de construction: 0; Cadre porte (Revêtement) (ifc_door_frame): yes; Epaisseur cadre = Epaisseur mur: no; Ajuster largeur panneau à trou: yes; Largeur panneau: 1; Encadr./Chambranle: no; Seuil: no; Ajuster larg. seuil revêtement: yes; Imposte: no; Angle ouverture en 2D: 90 deg; Stylo du symbole: Ouvertures - Général; Motif de hachure cadre: Background Fill-International; Stylo hachure cadre: Ouvertures - Hachures coupées; Stylo fond de hachure cadre: Fond - Couleur 1; Motif de hachure battant: Air Space; Stylo hachure de battant: Fond - Couleur 1; Stylo fond de hachure battant: Fond - Couleur 1; Angle ouverture en 3D: 0 deg; Stylo cadre: Eléments 2D - Général; Stylo panneaux: Eléments 2D - Général; Surface de cadre: 06 | W Pine V; Surface de battant: 06 | W Pine H; Surface d'imposte: 08 | Glass-Clear; Surface de seuil: 06 | W Pine V; Opération IFC (ifc_optypestr): Porte simple battant simple; Opération IFC (ifc_optype): 1
AC_Pset_RenovationAndPhasing - Renovation Status: Existing
Pset_DoorCommon - IsExternal: no
BaseQuantities - Width: 1 m; Volume: 0.0993 m3; Depth: 0.13 m
ArchiCADQuantities - Hauteur: 2.1 m; Superficie de surface: 5.466 m2; Volume net: 0.0993 m3; Largeur: 1 m; Epaisseur: 0.1 m; Hauteur nominale seuil: 0 m; Hauteur seuil côté ébrasure: 0 m; Hauteur seuil côté opposé ébrasure: 0 m; Hauteur nominale linteau: 2.1 m; Hauteur linteau côté ébrasure: 2.1 m; Hauteur linteau côté opposé ébrasure: 2.1 m; Largeur ouverture côté ébrasure: 1 m; Largeur ouverture côté opposé ébrasure: 1 m; Largeur nominale de l'ouverture côté ébrasure: 1 m; Largeur nominale de l'ouverture côté opposée ébrasure: 1 m; Hauteur nominale de l'ouverture côté ébrasure: 2.1 m; Hauteur nominale de l'ouverture côté opposée ébrasure: 2.1 m; Surface nominale de l'ouverture P/F côté ébrasure: 2.1 m2; Surface nominale de l'ouverture P/F côté opposé ébrasure: 2.1 m2; Volume ouverture: 0.0993 m3; Surface nominale ouverture P/F: 2.1 m2; Volume nominal ouverture: 0.273 m3; Valeur Appui ou Linteau: 0 m; Epaisseur de Mur: 0.13 m
AC_Equantity_IFC_Porte_-_Simple_battant - 1ère dimension: 1 m; 2ème dimension: 2.1 m; Hauteur: 1 m; Niveau inférieur: 1 m; Niveau supérieur: 0 m; Largeur cavité mur: 1 m; Hauteur cavité mur: 2.1 m; Largeur ébrasure: 1 m; Hauteur ébrasure: 2.1 m; Largeur unité: 1 m; Hauteur unité: 2.1 m; Largeur passage: 0.9 m; Hauteur passage: 2.05 m; Largeur battant: 0.9 m; Hauteur battant: 2.05 m; Epaisseur cadre: 0.1 m; Largeur cadre: 0.05 m; Epaisseur panneaux: 0.04 m; Couper épaisseur (Profondeur de chambranle): 0.02 m; Couper largeur (Epaisseur de chambranle): 0.1 m; Largeur seuil: 0.1 m; Décalage seuil: 0 m; Epaisseur seuil: 0.02 m; Hauteur panneau de porte: 1.5 m; Epaisseur imposte: 0.05 m; Dépass.ouverture gauche: 0 m; Dépass.ouverture à droite: 0 m; Dépass.ouverture supérieur: 0 m; Dépass.ouverture inférieur: 0 m
Name | In | Etage d'implantation | Nom de Zone = De Zone | Numéro de Zone = De la Zone numéro | Height (m) = Hauteur ouverture côté ébrasure (m) | Perimeter (m) | Area (m2) = Surface ouverture côté ébrasure (m2) | Altitude à Zéro du Projet (m) | Altitude à étage (m) | Hauteur ouverture côté opposé ébrasure (m) | Surface ouverture côté opposé ébrasure (m2)
DOOR_1000 | Rez de chaussée | Rez de chaussée | Dégagement | 001 | 2.1 | 6.2 | 2.1 | -0.1 | -0.1 | 2.1 | 2.1
DOOR_1000 | Rez de chaussée | Rez de chaussée | Dégagement | 002 | 2.1 | 6.2 | 2.1 | 0 | 0 | 2.1 | 2.1
DOOR_1000 | Rez de chaussée | Rez de chaussée | Garage | 004 | 2.1 | 6.2 | 2.1 | 0 | 0 | 2.1 | 2.1
DOOR_1000 | R+1 | R+1 | Dégagement | 001 | 2.1 | 6.2 | 2.1 | 5.3 | -0.1 | 2.1 | 2.1
DOOR_1000 | Mezzannine | Mezzannine |  |  | 2.1 | 6.2 | 2.1 | 9.425 | 0 | 2.1 | 2.1
DOOR_1000 | Toiture | Toiture |  |  | 2.07891 | 6.15783 | 2.03517 | 17.115 | -0.285 | 2.0789 | 2.03516

# IfcDoor: IFC Porte - Simple battant, DOOR_1000
In: R+2
Type - OperationType: SINGLE_SWING_RIGHT; ParameterTakesPrecedence: yes; Sizeable: no
Type - Propriétés Doublure Porte - LiningDepth: 0.1 m; LiningThickness: 0.05 m; LiningOffset: 0.18 m
Type - Propriétés Panneau Porte - Panneau1 - PanelDepth: 0.04 m; PanelOperation: SWINGING; PanelWidth: 1; PanelPosition: MIDDLE
Description: DOOR_1000; OverallHeight: 2.1 m; OverallWidth: 1 m; Material: Background Fill-International, Air Space
ArchiCADProperties - ID: DOOR_1000; Etage d'implantation: R+2; Nom de Zone: Dégagement; Numéro de Zone: 001; Calque: A-WALL-INTR; Type: Porte; Verrouillé: no; Nom Elément de Bibliothèque: IFC Porte - Simple battant; Matériau de construction / Composite / Profil / Hachure: Solid Fill; Fonction structurelle: Elément non porteur; Position: Intérieur; Classification d'lément: Porte; Etat de rénovation: Existant; Afficher sur filtre de rénovation: Tous les filtres appropriés; Texte Marque: DOOR_1000; De Zone: Dégagement; Orientation: G; De la Zone numéro: 001; Dimensions ébrasure: 39,37"x82,68"; Dimensions trou mur: 39,37"x82,68"; Dimensions unité: 39,37"x82,68"; Dimensions sortie: 35,43"x80,71"; Dimensions battant: 35,43"x80,71"; Structure mur: 0.0-Mur béton enduit platre x2; Taille L x H nominale: 39,37"x82,68"; Taille L x H x E nominale: 39,37"x82,68"x7,09"
AC_Pset_IFC_Porte_-_Simple_battant - Contours Mur (0-Sans,1-Tout,2-Côté,3-Longueur): 1; Point ch.0-Non,1-2D,2-3D,3-Tous: 3; Afficher points chauds 2D en 3D: yes; Trou reprend surface latérale de mur: no; Division de surface de trou courbée: no; Type racine: IfcDoor; Matière de construction: Non défini; ID matériau de construction: 0; Cadre porte (Revêtement) (ifc_door_frame): yes; Epaisseur cadre = Epaisseur mur: no; Ajuster largeur panneau à trou: yes; Largeur panneau: 1; Encadr./Chambranle: no; Seuil: no; Ajuster larg. seuil revêtement: yes; Imposte: no; Angle ouverture en 2D: 90 deg; Stylo du symbole: Ouvertures - Général; Motif de hachure cadre: Background Fill-International; Stylo hachure cadre: Ouvertures - Hachures coupées; Stylo fond de hachure cadre: Fond - Couleur 1; Motif de hachure battant: Air Space; Stylo hachure de battant: Fond - Couleur 1; Stylo fond de hachure battant: Fond - Couleur 1; Angle ouverture en 3D: 0 deg; Stylo cadre: Eléments 2D - Général; Stylo panneaux: Eléments 2D - Général; Surface de cadre: 06 | W Pine V; Surface de battant: 06 | W Pine H; Surface d'imposte: 08 | Glass-Clear; Surface de seuil: 06 | W Pine V; Opération IFC (ifc_optypestr): Porte simple battant simple; Opération IFC (ifc_optype): 1
AC_Pset_RenovationAndPhasing - Renovation Status: Existing
Pset_DoorCommon - IsExternal: no
BaseQuantities - Height: 2.1 m; Width: 1 m; Perimeter: 6.2 m; Area: 2.1 m2; Volume: 0.0993 m3; Depth: 0.18 m
ArchiCADQuantities - Altitude à Zéro du Projet: 13.33 m; Altitude à étage: -0.12 m; Hauteur: 2.1 m; Superficie de surface: 5.466 m2; Volume net: 0.0993 m3; Largeur: 1 m; Epaisseur: 0.1 m; Hauteur nominale seuil: 0 m; Hauteur seuil côté ébrasure: 0 m; Hauteur seuil côté opposé ébrasure: 0 m; Hauteur nominale linteau: 2.1 m; Hauteur linteau côté ébrasure: 2.1 m; Hauteur linteau côté opposé ébrasure: 2.1 m; Largeur ouverture côté ébrasure: 1 m; Largeur ouverture côté opposé ébrasure: 1 m; Hauteur ouverture côté ébrasure: 2.1 m; Hauteur ouverture côté opposé ébrasure: 2.1 m; Surface ouverture côté ébrasure: 2.1 m2; Surface ouverture côté opposé ébrasure: 2.1 m2; Largeur nominale de l'ouverture côté ébrasure: 1 m; Largeur nominale de l'ouverture côté opposée ébrasure: 1 m; Hauteur nominale de l'ouverture côté ébrasure: 2.1 m; Hauteur nominale de l'ouverture côté opposée ébrasure: 2.1 m; Surface nominale de l'ouverture P/F côté ébrasure: 2.1 m2; Surface nominale de l'ouverture P/F côté opposé ébrasure: 2.1 m2; Volume ouverture: 0.0993 m3; Surface nominale ouverture P/F: 2.1 m2; Volume nominal ouverture: 0.378 m3; Valeur Appui ou Linteau: 0 m; Epaisseur de Mur: 0.18 m
AC_Equantity_IFC_Porte_-_Simple_battant - 1ère dimension: 1 m; 2ème dimension: 2.1 m; Hauteur: 1 m; Niveau inférieur: 1 m; Niveau supérieur: 0 m; Largeur cavité mur: 1 m; Hauteur cavité mur: 2.1 m; Largeur ébrasure: 1 m; Hauteur ébrasure: 2.1 m; Largeur unité: 1 m; Hauteur unité: 2.1 m; Largeur passage: 0.9 m; Hauteur passage: 2.05 m; Largeur battant: 0.9 m; Hauteur battant: 2.05 m; Epaisseur cadre: 0.1 m; Largeur cadre: 0.05 m; Epaisseur panneaux: 0.04 m; Couper épaisseur (Profondeur de chambranle): 0.02 m; Couper largeur (Epaisseur de chambranle): 0.1 m; Largeur seuil: 0.1 m; Décalage seuil: 0 m; Epaisseur seuil: 0.02 m; Hauteur panneau de porte: 1.5 m; Epaisseur imposte: 0.05 m; Dépass.ouverture gauche: 0 m; Dépass.ouverture à droite: 0 m; Dépass.ouverture supérieur: 0 m; Dépass.ouverture inférieur: 0 m

# IfcDoor: IFC Porte double - Double battant, DOOR
In: Rez de chaussée
Type - OperationType: DOUBLE_DOOR_DOUBLE_SWING; ConstructionType: ALUMINIUM; ParameterTakesPrecedence: yes; Sizeable: no
Type - Propriétés Doublure Porte - LiningDepth: 0.1 m; LiningThickness: 0.05 m; LiningOffset: 0 m
Type - Propriétés Panneau Porte - Panneau1 - PanelDepth: 0.04 m; PanelOperation: DOUBLE_ACTING; PanelWidth: 0.5; PanelPosition: LEFT
Type - Propriétés Panneau Porte - Panneau2 - PanelDepth: 0.04 m; PanelOperation: DOUBLE_ACTING; PanelWidth: 0.5; PanelPosition: RIGHT
Description: DOOR; OverallHeight: 2.5 m; OverallWidth: 1.5 m; Material: Background Fill-International, Air Space
ArchiCADProperties - ID: DOOR; Etage d'implantation: Rez de chaussée; Nom de Zone: Dégagement; Numéro de Zone: 003; Calque: A-WALL-INTR; Type: Porte; Verrouillé: no; Nom Elément de Bibliothèque: IFC Porte double - Double battant; Matériau de construction / Composite / Profil / Hachure: Solid Fill; Fonction structurelle: Elément non porteur; Position: Intérieur; Classification d'lément: Porte; Etat de rénovation: Existant; Afficher sur filtre de rénovation: Tous les filtres appropriés; Texte Marque: DOOR; De Zone: Dégagement; Orientation: G; De la Zone numéro: 003; Dimensions ébrasure: 59,06"x98,43"; Dimensions trou mur: 59,06"x98,43"; Dimensions unité: 59,06"x98,43"; Dimensions sortie: 55,12"x96,46"; Dimensions battant: 55,12"x96,46"; Structure mur: 0.0-Cloison: parpaing + plâtre 2 faces copie; Taille L x H nominale: 59,06"x98,43"; Taille L x H x E nominale: 59,06"x98,43"x5,12"
AC_Pset_IFC_Porte_double_-_Double_battant - Contours Mur (0-Sans,1-Tout,2-Côté,3-Longueur): 1; Point ch.0-Non,1-2D,2-3D,3-Tous: 3; Afficher points chauds 2D en 3D: yes; Trou reprend surface latérale de mur: no; Division de surface de trou courbée: no; Type racine: IfcDoor; Matière de construction: Aluminum; ID matériau de construction: 1; Cadre porte (Revêtement) (ifc_door_frame): yes; Epaisseur cadre = Epaisseur mur: no; Ajuster largeur panneau à trou: yes; Largeur battant droit: 0.5; Largeur battant gauche: 0.5; Encadr./Chambranle: no; Seuil: no; Ajuster larg. seuil revêtement: yes; Imposte: no; Angle ouv. battant droit en 2D: 90 deg; Angle ouv. battant gauche en 2D: 90 deg; Stylo du symbole: Ouvertures - Général; Motif de hachure cadre: Background Fill-International; Stylo hachure cadre: Ouvertures - Hachures coupées; Stylo fond de hachure cadre: Fond - Couleur 1; Motif de hachure battant: Air Space; Stylo hachure de battant: Fond - Couleur 1; Stylo fond de hachure battant: Fond - Couleur 1; Angle ouv. battant droit en 3D: 0 deg; Angle ouv. battant gauche en 3D: 0 deg; Stylo cadre: Eléments 2D - Général; Stylo panneaux: Eléments 2D - Général; Surface de cadre: 06 | W Pine H; Surface de battant: 09 | W Cherry H; Surface d'imposte: 08 | Glass-Clear; Surface de seuil: 06 | W Pine V; Opération IFC (ifc_optypestr): Porte double battant double; Opération IFC (ifc_optype): 4
AC_Pset_RenovationAndPhasing - Renovation Status: Existing
Pset_DoorCommon - IsExternal: no
BaseQuantities - Height: 2.5 m; Width: 1.5 m; Perimeter: 8 m; Area: 3.75 m2; Volume: 0.1692 m3; Depth: 0.13 m
ArchiCADQuantities - Altitude à Zéro du Projet: 0.12 m; Altitude à étage: 0.12 m; Hauteur: 2.5 m; Superficie de surface: 9.294 m2; Volume net: 0.1692 m3; Largeur: 1.5 m; Epaisseur: 0.1 m; Hauteur nominale seuil: 0.12 m; Hauteur seuil côté ébrasure: 0.12 m; Hauteur seuil côté opposé ébrasure: 0.12 m; Hauteur nominale linteau: 2.62 m; Hauteur linteau côté ébrasure: 2.62 m; Hauteur linteau côté opposé ébrasure: 2.62 m; Largeur ouverture côté ébrasure: 1.5 m; Largeur ouverture côté opposé ébrasure: 1.5 m; Hauteur ouverture côté ébrasure: 2.5 m; Hauteur ouverture côté opposé ébrasure: 2.5 m; Surface ouverture côté ébrasure: 3.75 m2; Surface ouverture côté opposé ébrasure: 3.75 m2; Largeur nominale de l'ouverture côté ébrasure: 1.5 m; Largeur nominale de l'ouverture côté opposée ébrasure: 1.5 m; Hauteur nominale de l'ouverture côté ébrasure: 2.5 m; Hauteur nominale de l'ouverture côté opposée ébrasure: 2.5 m; Surface nominale de l'ouverture P/F côté ébrasure: 3.75 m2; Surface nominale de l'ouverture P/F côté opposé ébrasure: 3.75 m2; Volume ouverture: 0.1692 m3; Surface nominale ouverture P/F: 3.75 m2; Volume nominal ouverture: 0.4875 m3; Valeur Appui ou Linteau: 0.12 m; Epaisseur de Mur: 0.13 m
AC_Equantity_IFC_Porte_double_-_Double_battant - 1ère dimension: 1.5 m; 2ème dimension: 2.5 m; Hauteur: 1 m; Niveau inférieur: 1 m; Niveau supérieur: 0 m; Largeur cavité mur: 1.5 m; Hauteur cavité mur: 2.5 m; Largeur ébrasure: 1.5 m; Hauteur ébrasure: 2.5 m; Largeur unité: 1.5 m; Hauteur unité: 2.5 m; Largeur passage: 1.4 m; Hauteur passage: 2.45 m; Largeur battant: 1.4 m; Hauteur battant: 2.45 m; Epaisseur cadre: 0.1 m; Largeur cadre: 0.05 m; Epaisseur battant droit: 0.04 m; Epaisseur battant gauche: 0.04 m; Couper épaisseur (Profondeur de chambranle): 0.02 m; Couper largeur (Epaisseur de chambranle): 0.1 m; Largeur seuil: 0.1 m; Décalage seuil: 0 m; Epaisseur seuil: 0.02 m; Hauteur panneau de porte: 1.5 m; Epaisseur imposte: 0.05 m; Dépass.ouverture gauche: 0 m; Dépass.ouverture à droite: 0 m; Dépass.ouverture supérieur: 0 m; Dépass.ouverture inférieur: 0 m

# IfcDoor: IFC Porte double - Double battant (3)
In: Rez de chaussée
Type - OperationType: DOUBLE_DOOR_DOUBLE_SWING; ConstructionType: ALUMINIUM; ParameterTakesPrecedence: yes; Sizeable: no
Type - Propriétés Doublure Porte - LiningDepth: 0.1 m; LiningThickness: 0.05 m; LiningOffset: 0 m
Type - Propriétés Panneau Porte - Panneau1 - PanelDepth: 0.04 m; PanelOperation: DOUBLE_ACTING; PanelWidth: 0.5; PanelPosition: RIGHT
Type - Propriétés Panneau Porte - Panneau2 - PanelDepth: 0.04 m; PanelOperation: DOUBLE_ACTING; PanelWidth: 0.5; PanelPosition: LEFT
Description: DOOR; OverallHeight: 2.5 m; OverallWidth: 1.5 m; Material: Background Fill-International, Air Space
ArchiCADProperties - ID: DOOR; Etage d'implantation: Rez de chaussée; Calque: A-WALL-INTR; Type: Porte; Verrouillé: no; Nom Elément de Bibliothèque: IFC Porte double - Double battant; Matériau de construction / Composite / Profil / Hachure: Solid Fill; Fonction structurelle: Elément non porteur; Position: Intérieur; Classification d'lément: Porte; Etat de rénovation: Existant; Afficher sur filtre de rénovation: Tous les filtres appropriés; Texte Marque: DOOR; Orientation: D; Dimensions ébrasure: 59,06"x98,43"; Dimensions trou mur: 59,06"x98,43"; Dimensions unité: 59,06"x98,43"; Dimensions sortie: 55,12"x96,46"; Dimensions battant: 55,12"x96,46"; Structure mur: 0.0-Cloison: parpaing + plâtre 2 faces copie; Taille L x H nominale: 59,06"x98,43"; Taille L x H x E nominale: 59,06"x98,43"x5,12"
AC_Pset_IFC_Porte_double_-_Double_battant - Contours Mur (0-Sans,1-Tout,2-Côté,3-Longueur): 1; Point ch.0-Non,1-2D,2-3D,3-Tous: 3; Afficher points chauds 2D en 3D: yes; Trou reprend surface latérale de mur: no; Division de surface de trou courbée: no; Type racine: IfcDoor; Matière de construction: Aluminum; ID matériau de construction: 1; Cadre porte (Revêtement) (ifc_door_frame): yes; Epaisseur cadre = Epaisseur mur: no; Ajuster largeur panneau à trou: yes; Largeur battant droit: 0.5; Largeur battant gauche: 0.5; Encadr./Chambranle: no; Seuil: no; Ajuster larg. seuil revêtement: yes; Imposte: no; Angle ouv. battant droit en 2D: 90 deg; Angle ouv. battant gauche en 2D: 90 deg; Stylo du symbole: Ouvertures - Général; Motif de hachure cadre: Background Fill-International; Stylo hachure cadre: Ouvertures - Hachures coupées; Stylo fond de hachure cadre: Fond - Couleur 1; Motif de hachure battant: Air Space; Stylo hachure de battant: Fond - Couleur 1; Stylo fond de hachure battant: Fond - Couleur 1; Angle ouv. battant droit en 3D: 0 deg; Angle ouv. battant gauche en 3D: 0 deg; Stylo cadre: Eléments 2D - Général; Stylo panneaux: Eléments 2D - Général; Surface de cadre: 06 | W Pine H; Surface de battant: 09 | W Cherry H; Surface d'imposte: 08 | Glass-Clear; Surface de seuil: 06 | W Pine V; Opération IFC (ifc_optypestr): Porte double battant double; Opération IFC (ifc_optype): 4
AC_Pset_RenovationAndPhasing - Renovation Status: Existing
Pset_DoorCommon - IsExternal: no
BaseQuantities - Height: 2.5 m; Width: 1.5 m; Perimeter: 8 m; Area: 3.75 m2; Volume: 0.1692 m3; Depth: 0.13 m
ArchiCADQuantities - Altitude à Zéro du Projet: 0 m; Altitude à étage: 0 m; Hauteur: 2.5 m; Superficie de surface: 9.294 m2; Volume net: 0.1692 m3; Largeur: 1.5 m; Epaisseur: 0.1 m; Hauteur nominale seuil: 0 m; Hauteur seuil côté ébrasure: 0 m; Hauteur seuil côté opposé ébrasure: 0 m; Hauteur nominale linteau: 2.5 m; Hauteur linteau côté ébrasure: 2.5 m; Hauteur linteau côté opposé ébrasure: 2.5 m; Largeur ouverture côté ébrasure: 1.5 m; Largeur ouverture côté opposé ébrasure: 1.5 m; Hauteur ouverture côté ébrasure: 2.5 m; Hauteur ouverture côté opposé ébrasure: 2.5 m; Surface ouverture côté ébrasure: 3.75 m2; Surface ouverture côté opposé ébrasure: 3.75 m2; Largeur nominale de l'ouverture côté ébrasure: 1.5 m; Largeur nominale de l'ouverture côté opposée ébrasure: 1.5 m; Hauteur nominale de l'ouverture côté ébrasure: 2.5 m; Hauteur nominale de l'ouverture côté opposée ébrasure: 2.5 m; Surface nominale de l'ouverture P/F côté ébrasure: 3.75 m2; Surface nominale de l'ouverture P/F côté opposé ébrasure: 3.75 m2; Volume ouverture: 0.1692 m3; Surface nominale ouverture P/F: 3.75 m2; Volume nominal ouverture: 0.4875 m3; Valeur Appui ou Linteau: 0 m; Epaisseur de Mur: 0.13 m
AC_Equantity_IFC_Porte_double_-_Double_battant - 1ère dimension: 1.5 m; 2ème dimension: 2.5 m; Hauteur: 1 m; Niveau inférieur: 1 m; Niveau supérieur: 0 m; Largeur cavité mur: 1.5 m; Hauteur cavité mur: 2.5 m; Largeur ébrasure: 1.5 m; Hauteur ébrasure: 2.5 m; Largeur unité: 1.5 m; Hauteur unité: 2.5 m; Largeur passage: 1.4 m; Hauteur passage: 2.45 m; Largeur battant: 1.4 m; Hauteur battant: 2.45 m; Epaisseur cadre: 0.1 m; Largeur cadre: 0.05 m; Epaisseur battant droit: 0.04 m; Epaisseur battant gauche: 0.04 m; Couper épaisseur (Profondeur de chambranle): 0.02 m; Couper largeur (Epaisseur de chambranle): 0.1 m; Largeur seuil: 0.1 m; Décalage seuil: 0 m; Epaisseur seuil: 0.02 m; Hauteur panneau de porte: 1.5 m; Epaisseur imposte: 0.05 m; Dépass.ouverture gauche: 0 m; Dépass.ouverture à droite: 0 m; Dépass.ouverture supérieur: 0 m; Dépass.ouverture inférieur: 0 m
Name | Nom de Zone = De Zone | Numéro de Zone = De la Zone numéro
DOOR | Local Tech. | 007
DOOR | Réserve | 008
DOOR | Garage | 004

# IfcDoor: IFC Porte double - Simple battant (3)
Type - OperationType: DOUBLE_DOOR_SINGLE_SWING; ConstructionType: ALUMINIUM; ParameterTakesPrecedence: yes; Sizeable: no
Type - Propriétés Doublure Porte - LiningDepth: 0.1 m; LiningThickness: 0.05 m; LiningOffset: 0 m
Type - Propriétés Panneau Porte - Panneau1 - PanelDepth: 0.04 m; PanelOperation: SWINGING; PanelWidth: 0.2; PanelPosition: RIGHT
Type - Propriétés Panneau Porte - Panneau2 - PanelDepth: 0.04 m; PanelOperation: SWINGING; PanelWidth: 0.8; PanelPosition: LEFT
Description: DOOR; OverallHeight: 2.1 m; OverallWidth: 1.5 m; Material: Background Fill-International, Air Space
ArchiCADProperties - ID: DOOR; Nom de Zone: Dégagement; Numéro de Zone: 001; Calque: A-WALL-INTR; Type: Porte; Verrouillé: no; Nom Elément de Bibliothèque: IFC Porte double - Simple battant; Matériau de construction / Composite / Profil / Hachure: Solid Fill; Fonction structurelle: Elément non porteur; Position: Intérieur; Classification d'lément: Porte; Etat de rénovation: Existant; Afficher sur filtre de rénovation: Tous les filtres appropriés; Texte Marque: DOOR; De Zone: Dégagement; Orientation: D; De la Zone numéro: 001; Dimensions ébrasure: 59,06"x82,68"; Dimensions trou mur: 59,06"x82,68"; Dimensions unité: 59,06"x82,68"; Dimensions sortie: 55,12"x80,71"; Dimensions battant: 55,12"x80,71"; Structure mur: 0.0-Cloison: parpaing + plâtre 2 faces copie; Taille L x H nominale: 59,06"x82,68"; Taille L x H x E nominale: 59,06"x82,68"x5,12"
AC_Pset_IFC_Porte_double_-_Simple_battant - Contours Mur (0-Sans,1-Tout,2-Côté,3-Longueur): 1; Point ch.0-Non,1-2D,2-3D,3-Tous: 3; Afficher points chauds 2D en 3D: yes; Trou reprend surface latérale de mur: no; Division de surface de trou courbée: no; Type racine: IfcDoor; Matière de construction: Aluminum; ID matériau de construction: 1; Cadre porte (Revêtement) (ifc_door_frame): yes; Epaisseur cadre = Epaisseur mur: no; Ajuster largeur panneau à trou: yes; Largeur battant droit: 0.8; Largeur battant gauche: 0.2; Encadr./Chambranle: no; Seuil: no; Ajuster larg. seuil revêtement: yes; Imposte: no; Angle ouv. battant droit en 2D: 90 deg; Angle ouv. battant gauche en 2D: 90 deg; Stylo du symbole: Ouvertures - Général; Motif de hachure cadre: Background Fill-International; Stylo hachure cadre: Ouvertures - Hachures coupées; Stylo fond de hachure cadre: Fond - Couleur 1; Motif de hachure battant: Air Space; Stylo hachure de battant: Fond - Couleur 1; Stylo fond de hachure battant: Fond - Couleur 1; Angle ouv. battant droit en 3D: 0 deg; Angle ouv. battant gauche en 3D: 0 deg; Stylo cadre: Eléments 2D - Général; Stylo panneaux: Eléments 2D - Général; Surface de cadre: 06 | W Pine V; Surface de battant: 06 | W Pine H; Surface d'imposte: 08 | Glass-Clear; Surface de seuil: 06 | W Pine V; Opération IFC (ifc_optypestr): Porte double battant simple; Opération IFC (ifc_optype): 2
AC_Pset_RenovationAndPhasing - Renovation Status: Existing
Pset_DoorCommon - IsExternal: no
BaseQuantities - Height: 2.1 m; Width: 1.5 m; Perimeter: 7.2 m; Area: 3.15 m2; Volume: 0.1428 m3; Depth: 0.13 m
ArchiCADQuantities - Hauteur: 2.1 m; Superficie de surface: 7.87 m2; Volume net: 0.1428 m3; Largeur: 1.5 m; Epaisseur: 0.1 m; Largeur ouverture côté ébrasure: 1.5 m; Largeur ouverture côté opposé ébrasure: 1.5 m; Hauteur ouverture côté ébrasure: 2.1 m; Hauteur ouverture côté opposé ébrasure: 2.1 m; Surface ouverture côté ébrasure: 3.15 m2; Surface ouverture côté opposé ébrasure: 3.15 m2; Largeur nominale de l'ouverture côté ébrasure: 1.5 m; Largeur nominale de l'ouverture côté opposée ébrasure: 1.5 m; Hauteur nominale de l'ouverture côté ébrasure: 2.1 m; Hauteur nominale de l'ouverture côté opposée ébrasure: 2.1 m; Surface nominale de l'ouverture P/F côté ébrasure: 3.15 m2; Surface nominale de l'ouverture P/F côté opposé ébrasure: 3.15 m2; Volume ouverture: 0.1428 m3; Surface nominale ouverture P/F: 3.15 m2; Volume nominal ouverture: 0.4095 m3; Epaisseur de Mur: 0.13 m
AC_Equantity_IFC_Porte_double_-_Simple_battant - 1ère dimension: 1.5 m; 2ème dimension: 2.1 m; Hauteur: 1 m; Niveau inférieur: 1 m; Niveau supérieur: 0 m; Largeur cavité mur: 1.5 m; Hauteur cavité mur: 2.1 m; Largeur ébrasure: 1.5 m; Hauteur ébrasure: 2.1 m; Largeur unité: 1.5 m; Hauteur unité: 2.1 m; Largeur passage: 1.4 m; Hauteur passage: 2.05 m; Largeur battant: 1.4 m; Hauteur battant: 2.05 m; Epaisseur cadre: 0.1 m; Largeur cadre: 0.05 m; Epaisseur battant droit: 0.04 m; Epaisseur battant gauche: 0.04 m; Couper épaisseur (Profondeur de chambranle): 0.02 m; Couper largeur (Epaisseur de chambranle): 0.1 m; Largeur seuil: 0.1 m; Décalage seuil: 0 m; Epaisseur seuil: 0.02 m; Hauteur panneau de porte: 1.5 m; Epaisseur imposte: 0.05 m; Dépass.ouverture gauche: 0 m; Dépass.ouverture à droite: 0 m; Dépass.ouverture supérieur: 0 m; Dépass.ouverture inférieur: 0 m
Name | In | Etage d'implantation | Altitude à Zéro du Projet (m) | Altitude à étage (m) | Hauteur nominale seuil (m) = Hauteur seuil côté ébrasure (m) = Hauteur seuil côté opposé ébrasure (m) = Valeur Appui ou Linteau (m) | Hauteur nominale linteau (m) = Hauteur linteau côté ébrasure (m) = Hauteur linteau côté opposé ébrasure (m)
DOOR | R+1 | R+1 | 5.4 | 0 | 0.1 | 2.2
DOOR | Mezzannine | Mezzannine | 9.425 | 3.55271e-15 | 0.12 | 2.22
DOOR | R+2 | R+2 | 13.45 | 0 | 0.12 | 2.22

# IfcDoor: IFC Porte double - Simple battant (4)
Type - OperationType: DOUBLE_DOOR_SINGLE_SWING; ConstructionType: ALUMINIUM; ParameterTakesPrecedence: yes; Sizeable: no
Type - Propriétés Doublure Porte - LiningDepth: 0.1 m; LiningThickness: 0.05 m; LiningOffset: 0 m
Type - Propriétés Panneau Porte - Panneau1 - PanelDepth: 0.04 m; PanelOperation: SWINGING; PanelWidth: 0.5; PanelPosition: LEFT
Type - Propriétés Panneau Porte - Panneau2 - PanelDepth: 0.04 m; PanelOperation: SWINGING; PanelWidth: 0.5; PanelPosition: RIGHT
Description: DOOR; OverallHeight: 2.1 m; OverallWidth: 1.5 m; Material: Background Fill-International, Air Space
ArchiCADProperties - ID: DOOR; Calque: A-WALL-INTR; Type: Porte; Verrouillé: no; Nom Elément de Bibliothèque: IFC Porte double - Simple battant; Matériau de construction / Composite / Profil / Hachure: Solid Fill; Fonction structurelle: Elément non porteur; Position: Intérieur; Classification d'lément: Porte; Etat de rénovation: Existant; Afficher sur filtre de rénovation: Tous les filtres appropriés; Texte Marque: DOOR; Orientation: G; Dimensions ébrasure: 59,06"x82,68"; Dimensions trou mur: 59,06"x82,68"; Dimensions unité: 59,06"x82,68"; Dimensions sortie: 55,12"x80,71"; Dimensions battant: 55,12"x80,71"; Structure mur: 0.0-Cloison: parpaing + plâtre 2 faces copie; Taille L x H nominale: 59,06"x82,68"; Taille L x H x E nominale: 59,06"x82,68"x5,12"
AC_Pset_IFC_Porte_double_-_Simple_battant - Contours Mur (0-Sans,1-Tout,2-Côté,3-Longueur): 1; Point ch.0-Non,1-2D,2-3D,3-Tous: 3; Afficher points chauds 2D en 3D: yes; Trou reprend surface latérale de mur: no; Division de surface de trou courbée: no; Type racine: IfcDoor; Matière de construction: Aluminum; ID matériau de construction: 1; Cadre porte (Revêtement) (ifc_door_frame): yes; Epaisseur cadre = Epaisseur mur: no; Ajuster largeur panneau à trou: yes; Largeur battant droit: 0.5; Largeur battant gauche: 0.5; Encadr./Chambranle: no; Seuil: no; Ajuster larg. seuil revêtement: yes; Imposte: no; Angle ouv. battant droit en 2D: 90 deg; Angle ouv. battant gauche en 2D: 90 deg; Stylo du symbole: Ouvertures - Général; Motif de hachure cadre: Background Fill-International; Stylo hachure cadre: Ouvertures - Hachures coupées; Stylo fond de hachure cadre: Fond - Couleur 1; Motif de hachure battant: Air Space; Stylo hachure de battant: Fond - Couleur 1; Stylo fond de hachure battant: Fond - Couleur 1; Angle ouv. battant droit en 3D: 0 deg; Angle ouv. battant gauche en 3D: 0 deg; Stylo cadre: Eléments 2D - Général; Stylo panneaux: Eléments 2D - Général; Surface de cadre: 06 | W Pine V; Surface de battant: 06 | W Pine H; Surface d'imposte: 08 | Glass-Clear; Surface de seuil: 06 | W Pine V; Opération IFC (ifc_optypestr): Porte double battant simple; Opération IFC (ifc_optype): 2
AC_Pset_RenovationAndPhasing - Renovation Status: Existing
Pset_DoorCommon - IsExternal: no
BaseQuantities - Height: 2.1 m; Width: 1.5 m; Perimeter: 7.2 m; Area: 3.15 m2; Volume: 0.1428 m3; Depth: 0.13 m
ArchiCADQuantities - Hauteur: 2.1 m; Superficie de surface: 7.87 m2; Volume net: 0.1428 m3; Largeur: 1.5 m; Epaisseur: 0.1 m; Largeur ouverture côté ébrasure: 1.5 m; Largeur ouverture côté opposé ébrasure: 1.5 m; Hauteur ouverture côté ébrasure: 2.1 m; Hauteur ouverture côté opposé ébrasure: 2.1 m; Surface ouverture côté ébrasure: 3.15 m2; Surface ouverture côté opposé ébrasure: 3.15 m2; Largeur nominale de l'ouverture côté ébrasure: 1.5 m; Largeur nominale de l'ouverture côté opposée ébrasure: 1.5 m; Hauteur nominale de l'ouverture côté ébrasure: 2.1 m; Hauteur nominale de l'ouverture côté opposée ébrasure: 2.1 m; Surface nominale de l'ouverture P/F côté ébrasure: 3.15 m2; Surface nominale de l'ouverture P/F côté opposé ébrasure: 3.15 m2; Volume ouverture: 0.1428 m3; Surface nominale ouverture P/F: 3.15 m2; Volume nominal ouverture: 0.4095 m3; Epaisseur de Mur: 0.13 m
AC_Equantity_IFC_Porte_double_-_Simple_battant - 1ère dimension: 1.5 m; 2ème dimension: 2.1 m; Hauteur: 1 m; Niveau inférieur: 1 m; Niveau supérieur: 0 m; Largeur cavité mur: 1.5 m; Hauteur cavité mur: 2.1 m; Largeur ébrasure: 1.5 m; Hauteur ébrasure: 2.1 m; Largeur unité: 1.5 m; Hauteur unité: 2.1 m; Largeur passage: 1.4 m; Hauteur passage: 2.05 m; Largeur battant: 1.4 m; Hauteur battant: 2.05 m; Epaisseur cadre: 0.1 m; Largeur cadre: 0.05 m; Epaisseur battant droit: 0.04 m; Epaisseur battant gauche: 0.04 m; Couper épaisseur (Profondeur de chambranle): 0.02 m; Couper largeur (Epaisseur de chambranle): 0.1 m; Largeur seuil: 0.1 m; Décalage seuil: 0 m; Epaisseur seuil: 0.02 m; Hauteur panneau de porte: 1.5 m; Epaisseur imposte: 0.05 m; Dépass.ouverture gauche: 0 m; Dépass.ouverture à droite: 0 m; Dépass.ouverture supérieur: 0 m; Dépass.ouverture inférieur: 0 m
Name | In | Etage d'implantation | Altitude à Zéro du Projet (m) | Altitude à étage (m) | Hauteur nominale seuil (m) = Hauteur seuil côté ébrasure (m) = Hauteur seuil côté opposé ébrasure (m) = Valeur Appui ou Linteau (m) | Hauteur nominale linteau (m) = Hauteur linteau côté ébrasure (m) = Hauteur linteau côté opposé ébrasure (m)
DOOR | Rez de chaussée | Rez de chaussée | 0.12 | 0.12 | 0.12 | 2.22 | ArchiCADProperties - Nom de Zone: Réserve; Numéro de Zone: 009; De Zone: Réserve; De la Zone numéro: 009
DOOR | R+1 | R+1 | 5.4 | 4.17444e-14 | 0.1 | 2.2
DOOR | Mezzannine | Mezzannine | 9.425 | 0 | 0.12 | 2.22 | ArchiCADProperties - Nom de Zone: Plateau bureaux; Numéro de Zone: 005; De Zone: Plateau bureaux; De la Zone numéro: 005
DOOR | R+2 | R+2 | 13.45 | 3.55271e-15 | 0.12 | 2.22

# IfcDoor: IFC Porte double - Simple battant (8)
Type - OperationType: DOUBLE_DOOR_SINGLE_SWING; ConstructionType: ALUMINIUM; ParameterTakesPrecedence: yes; Sizeable: no
Type - Propriétés Doublure Porte - LiningDepth: 0.1 m; LiningThickness: 0.05 m; LiningOffset: 0 m
Type - Propriétés Panneau Porte - Panneau1 - PanelDepth: 0.04 m; PanelOperation: SWINGING; PanelWidth: 0.5; PanelPosition: RIGHT
Type - Propriétés Panneau Porte - Panneau2 - PanelDepth: 0.04 m; PanelOperation: SWINGING; PanelWidth: 0.5; PanelPosition: LEFT
Description: DOOR; OverallHeight: 2.1 m; Material: Background Fill-International, Air Space
ArchiCADProperties - ID: DOOR; Calque: A-WALL-INTR; Type: Porte; Verrouillé: no; Nom Elément de Bibliothèque: IFC Porte double - Simple battant; Matériau de construction / Composite / Profil / Hachure: Solid Fill; Fonction structurelle: Elément non porteur; Position: Intérieur; Classification d'lément: Porte; Etat de rénovation: Existant; Afficher sur filtre de rénovation: Tous les filtres appropriés; Texte Marque: DOOR; Orientation: D; Structure mur: 0.0-Cloison: parpaing + plâtre 2 faces copie
AC_Pset_IFC_Porte_double_-_Simple_battant - Contours Mur (0-Sans,1-Tout,2-Côté,3-Longueur): 1; Point ch.0-Non,1-2D,2-3D,3-Tous: 3; Afficher points chauds 2D en 3D: yes; Trou reprend surface latérale de mur: no; Division de surface de trou courbée: no; Type racine: IfcDoor; Matière de construction: Aluminum; ID matériau de construction: 1; Cadre porte (Revêtement) (ifc_door_frame): yes; Epaisseur cadre = Epaisseur mur: no; Ajuster largeur panneau à trou: yes; Largeur battant droit: 0.5; Largeur battant gauche: 0.5; Encadr./Chambranle: no; Seuil: no; Ajuster larg. seuil revêtement: yes; Imposte: no; Angle ouv. battant droit en 2D: 90 deg; Angle ouv. battant gauche en 2D: 90 deg; Stylo du symbole: Ouvertures - Général; Motif de hachure cadre: Background Fill-International; Stylo hachure cadre: Ouvertures - Hachures coupées; Stylo fond de hachure cadre: Fond - Couleur 1; Motif de hachure battant: Air Space; Stylo hachure de battant: Fond - Couleur 1; Stylo fond de hachure battant: Fond - Couleur 1; Angle ouv. battant droit en 3D: 0 deg; Angle ouv. battant gauche en 3D: 0 deg; Stylo cadre: Eléments 2D - Général; Stylo panneaux: Eléments 2D - Général; Surface de cadre: 06 | W Pine V; Surface de battant: 06 | W Pine H; Surface d'imposte: 08 | Glass-Clear; Surface de seuil: 06 | W Pine V; Opération IFC (ifc_optypestr): Porte double battant simple; Opération IFC (ifc_optype): 2
AC_Pset_RenovationAndPhasing - Renovation Status: Existing
Pset_DoorCommon - IsExternal: no
BaseQuantities - Height: 2.1 m; Depth: 0.13 m
ArchiCADQuantities - Hauteur: 2.1 m; Epaisseur: 0.1 m; Hauteur ouverture côté ébrasure: 2.1 m; Hauteur ouverture côté opposé ébrasure: 2.1 m; Hauteur nominale de l'ouverture côté ébrasure: 2.1 m; Hauteur nominale de l'ouverture côté opposée ébrasure: 2.1 m; Epaisseur de Mur: 0.13 m
AC_Equantity_IFC_Porte_double_-_Simple_battant - 2ème dimension: 2.1 m; Hauteur: 1 m; Niveau inférieur: 1 m; Niveau supérieur: 0 m; Hauteur cavité mur: 2.1 m; Hauteur ébrasure: 2.1 m; Hauteur unité: 2.1 m; Hauteur passage: 2.05 m; Hauteur battant: 2.05 m; Epaisseur cadre: 0.1 m; Largeur cadre: 0.05 m; Epaisseur battant droit: 0.04 m; Epaisseur battant gauche: 0.04 m; Couper épaisseur (Profondeur de chambranle): 0.02 m; Couper largeur (Epaisseur de chambranle): 0.1 m; Largeur seuil: 0.1 m; Décalage seuil: 0 m; Epaisseur seuil: 0.02 m; Hauteur panneau de porte: 1.5 m; Epaisseur imposte: 0.05 m; Dépass.ouverture gauche: 0 m; Dépass.ouverture à droite: 0 m; Dépass.ouverture supérieur: 0 m; Dépass.ouverture inférieur: 0 m
Name | In | OverallWidth (m) = Width (m) = Largeur (m) = Largeur ouverture côté ébrasure (m) = Largeur ouverture côté opposé ébrasure (m) = Largeur nominale de l'ouverture côté ébrasure (m) = Largeur nominale de l'ouverture côté opposée ébrasure (m) = 1ère dimension (m) = Largeur cavité mur (m) = Largeur ébrasure (m) = Largeur unité (m) | Etage d'implantation | Nom de Zone = De Zone | Numéro de Zone = De la Zone numéro | Dimensions ébrasure = Dimensions trou mur = Dimensions unité = Taille L x H nominale | Dimensions sortie = Dimensions battant | Taille L x H x E nominale | Perimeter (m) | Area (m2) = Surface ouverture côté ébrasure (m2) = Surface ouverture côté opposé ébrasure (m2) = Surface nominale de l'ouverture P/F côté ébrasure (m2) = Surface nominale de l'ouverture P/F côté opposé ébrasure (m2) = Surface nominale ouverture P/F (m2) | Volume (m3) = Volume net (m3) = Volume ouverture (m3) | Altitude à Zéro du Projet (m) | Altitude à étage (m) | Superficie de surface (m2) | Hauteur nominale seuil (m) = Hauteur seuil côté ébrasure (m) = Hauteur seuil côté opposé ébrasure (m) = Valeur Appui ou Linteau (m) | Hauteur nominale linteau (m) = Hauteur linteau côté ébrasure (m) = Hauteur linteau côté opposé ébrasure (m) | Volume nominal ouverture (m3) | Largeur passage (m) = Largeur battant (m)
DOOR | Rez de chaussée | 1.5 | Rez de chaussée | Surface expoitation | 007 | 59,06"x82,68" | 55,12"x80,71" | 59,06"x82,68"x5,12" | 7.2 | 3.15 | 0.1428 | 0.12 | 0.12 | 7.87 | 0.12 | 2.22 | 0.4095 | 1.4
DOOR | Rez de chaussée | 1.5 | Rez de chaussée | Surface expoitation | 007 | 59,06"x82,68" | 55,12"x80,71" | 59,06"x82,68"x5,12" | 7.2 | 3.15 | 0.1428 | 0 | 0 | 7.87 | 0 | 2.1 | 0.4095 | 1.4
DOOR | R+1 | 1.39592 | R+1 | Plateau bureaux | 005 | 54,96"x82,68" | 51,02"x80,71" | 54,96"x82,68"x5,12" | 6.99184 | 2.93143 | 0.133745 | 5.4 | -4.52971e-14 | 7.40372 | 0.1 | 2.2 | 0.381086 | 1.29592
DOOR | R+1 | 1.5 | R+1 | Plateau bureaux | 005 | 59,06"x82,68" | 55,12"x80,71" | 59,06"x82,68"x5,12" | 7.2 | 3.15 | 0.1428 | 5.4 | -4.52971e-14 | 7.87 | 0.1 | 2.2 | 0.4095 | 1.4
2 x DOOR | Mezzannine | 1.5 | Mezzannine |  |  | 59,06"x82,68" | 55,12"x80,71" | 59,06"x82,68"x5,12" | 7.2 | 3.15 | 0.1428 | 9.425 | -2.94875e-13 | 7.87 | 0.12 | 2.22 | 0.4095 | 1.4
DOOR | R+2 | 1.39592 | R+2 | Plateau bureaux | 005 | 54,96"x82,68" | 51,02"x80,71" | 54,96"x82,68"x5,12" | 6.99184 | 2.93143 | 0.133745 | 13.45 | -1.35003e-13 | 7.40372 | 0.12 | 2.22 | 0.381086 | 1.29592
DOOR | R+2 | 1.5 | R+2 | Plateau bureaux | 005 | 59,06"x82,68" | 55,12"x80,71" | 59,06"x82,68"x5,12" | 7.2 | 3.15 | 0.1428 | 13.45 | -1.35003e-13 | 7.87 | 0.12 | 2.22 | 0.4095 | 1.4

# IfcDoor: IFC Porte double - Simple battant, DOOR
In: Rez de chaussée
Type - OperationType: DOUBLE_DOOR_SINGLE_SWING; ConstructionType: ALUMINIUM; ParameterTakesPrecedence: yes; Sizeable: no
Type - Propriétés Doublure Porte - LiningDepth: 0.1 m; LiningThickness: 0.05 m; LiningOffset: 0.13 m
Type - Propriétés Panneau Porte - Panneau1 - PanelDepth: 0.04 m; PanelOperation: SWINGING; PanelWidth: 0.5; PanelPosition: LEFT
Type - Propriétés Panneau Porte - Panneau2 - PanelDepth: 0.04 m; PanelOperation: SWINGING; PanelWidth: 0.5; PanelPosition: RIGHT
Description: DOOR; OverallHeight: 2.1 m; OverallWidth: 1.5 m; Material: Background Fill-International, Air Space
ArchiCADProperties - ID: DOOR; Etage d'implantation: Rez de chaussée; Calque: A-WALL-INTR; Type: Porte; Verrouillé: no; Nom Elément de Bibliothèque: IFC Porte double - Simple battant; Matériau de construction / Composite / Profil / Hachure: Solid Fill; Fonction structurelle: Elément non porteur; Position: Intérieur; Classification d'lément: Porte; Etat de rénovation: Existant; Afficher sur filtre de rénovation: Tous les filtres appropriés; Texte Marque: DOOR; Orientation: G; Dimensions ébrasure: 59,06"x82,68"; Dimensions trou mur: 59,06"x82,68"; Dimensions unité: 59,06"x82,68"; Dimensions sortie: 55,12"x80,71"; Dimensions battant: 55,12"x80,71"; Structure mur: 0.0-Cloison: parpaing + plâtre 2 faces copie; Taille L x H nominale: 59,06"x82,68"; Taille L x H x E nominale: 59,06"x82,68"x5,12"
AC_Pset_IFC_Porte_double_-_Simple_battant - Contours Mur (0-Sans,1-Tout,2-Côté,3-Longueur): 1; Point ch.0-Non,1-2D,2-3D,3-Tous: 3; Afficher points chauds 2D en 3D: yes; Trou reprend surface latérale de mur: no; Division de surface de trou courbée: no; Type racine: IfcDoor; Matière de construction: Aluminum; ID matériau de construction: 1; Cadre porte (Revêtement) (ifc_door_frame): yes; Epaisseur cadre = Epaisseur mur: no; Ajuster largeur panneau à trou: yes; Largeur battant droit: 0.5; Largeur battant gauche: 0.5; Encadr./Chambranle: no; Seuil: no; Ajuster larg. seuil revêtement: yes; Imposte: no; Angle ouv. battant droit en 2D: 90 deg; Angle ouv. battant gauche en 2D: 90 deg; Stylo du symbole: Ouvertures - Général; Motif de hachure cadre: Background Fill-International; Stylo hachure cadre: Ouvertures - Hachures coupées; Stylo fond de hachure cadre: Fond - Couleur 1; Motif de hachure battant: Air Space; Stylo hachure de battant: Fond - Couleur 1; Stylo fond de hachure battant: Fond - Couleur 1; Angle ouv. battant droit en 3D: 0 deg; Angle ouv. battant gauche en 3D: 0 deg; Stylo cadre: Eléments 2D - Général; Stylo panneaux: Eléments 2D - Général; Surface de cadre: 06 | W Pine V; Surface de battant: 06 | W Pine H; Surface d'imposte: 08 | Glass-Clear; Surface de seuil: 06 | W Pine V; Opération IFC (ifc_optypestr): Porte double battant simple; Opération IFC (ifc_optype): 2
AC_Pset_RenovationAndPhasing - Renovation Status: Existing
Pset_DoorCommon - IsExternal: no
BaseQuantities - Height: 2.1 m; Width: 1.5 m; Perimeter: 7.2 m; Area: 3.15 m2; Volume: 0.1428 m3; Depth: 0.13 m
ArchiCADQuantities - Altitude à Zéro du Projet: 0.12 m; Altitude à étage: 0.12 m; Hauteur: 2.1 m; Superficie de surface: 7.87 m2; Volume net: 0.1428 m3; Largeur: 1.5 m; Epaisseur: 0.1 m; Hauteur nominale seuil: 0.12 m; Hauteur seuil côté ébrasure: 0.12 m; Hauteur seuil côté opposé ébrasure: 0.12 m; Hauteur nominale linteau: 2.22 m; Hauteur linteau côté ébrasure: 2.22 m; Hauteur linteau côté opposé ébrasure: 2.22 m; Largeur ouverture côté ébrasure: 1.5 m; Largeur ouverture côté opposé ébrasure: 1.5 m; Hauteur ouverture côté ébrasure: 2.1 m; Hauteur ouverture côté opposé ébrasure: 2.1 m; Surface ouverture côté ébrasure: 3.15 m2; Surface ouverture côté opposé ébrasure: 3.15 m2; Largeur nominale de l'ouverture côté ébrasure: 1.5 m; Largeur nominale de l'ouverture côté opposée ébrasure: 1.5 m; Hauteur nominale de l'ouverture côté ébrasure: 2.1 m; Hauteur nominale de l'ouverture côté opposée ébrasure: 2.1 m; Surface nominale de l'ouverture P/F côté ébrasure: 3.15 m2; Surface nominale de l'ouverture P/F côté opposé ébrasure: 3.15 m2; Volume ouverture: 0.1428 m3; Surface nominale ouverture P/F: 3.15 m2; Volume nominal ouverture: 0.4095 m3; Valeur Appui ou Linteau: 0.12 m; Epaisseur de Mur: 0.13 m
AC_Equantity_IFC_Porte_double_-_Simple_battant - 1ère dimension: 1.5 m; 2ème dimension: 2.1 m; Hauteur: 1 m; Niveau inférieur: 1 m; Niveau supérieur: 0 m; Largeur cavité mur: 1.5 m; Hauteur cavité mur: 2.1 m; Largeur ébrasure: 1.5 m; Hauteur ébrasure: 2.1 m; Largeur unité: 1.5 m; Hauteur unité: 2.1 m; Largeur passage: 1.4 m; Hauteur passage: 2.05 m; Largeur battant: 1.4 m; Hauteur battant: 2.05 m; Epaisseur cadre: 0.1 m; Largeur cadre: 0.05 m; Epaisseur battant droit: 0.04 m; Epaisseur battant gauche: 0.04 m; Couper épaisseur (Profondeur de chambranle): 0.02 m; Couper largeur (Epaisseur de chambranle): 0.1 m; Largeur seuil: 0.1 m; Décalage seuil: 0 m; Epaisseur seuil: 0.02 m; Hauteur panneau de porte: 1.5 m; Epaisseur imposte: 0.05 m; Dépass.ouverture gauche: 0 m; Dépass.ouverture à droite: 0 m; Dépass.ouverture supérieur: 0 m; Dépass.ouverture inférieur: 0 m

# IfcDoor: IFC Porte double - Simple battant (6)
In: Rez de chaussée
Type - OperationType: DOUBLE_DOOR_SINGLE_SWING; ConstructionType: ALUMINIUM; ParameterTakesPrecedence: yes; Sizeable: no
Type - Propriétés Doublure Porte - LiningDepth: 0.1 m; LiningThickness: 0.05 m; LiningOffset: 0.13 m
Type - Propriétés Panneau Porte - Panneau1 - PanelDepth: 0.04 m; PanelOperation: SWINGING; PanelWidth: 0.5; PanelPosition: RIGHT
Type - Propriétés Panneau Porte - Panneau2 - PanelDepth: 0.04 m; PanelOperation: SWINGING; PanelWidth: 0.5; PanelPosition: LEFT
Description: DOOR; OverallHeight: 2.1 m; Material: Background Fill-International, Air Space
ArchiCADProperties - ID: DOOR; Etage d'implantation: Rez de chaussée; Calque: A-WALL-INTR; Type: Porte; Verrouillé: no; Nom Elément de Bibliothèque: IFC Porte double - Simple battant; Matériau de construction / Composite / Profil / Hachure: Solid Fill; Fonction structurelle: Elément non porteur; Position: Intérieur; Classification d'lément: Porte; Etat de rénovation: Existant; Afficher sur filtre de rénovation: Tous les filtres appropriés; Texte Marque: DOOR; Orientation: D; Structure mur: 0.0-Cloison: parpaing + plâtre 2 faces copie
AC_Pset_IFC_Porte_double_-_Simple_battant - Contours Mur (0-Sans,1-Tout,2-Côté,3-Longueur): 1; Point ch.0-Non,1-2D,2-3D,3-Tous: 3; Afficher points chauds 2D en 3D: yes; Trou reprend surface latérale de mur: no; Division de surface de trou courbée: no; Type racine: IfcDoor; Matière de construction: Aluminum; ID matériau de construction: 1; Cadre porte (Revêtement) (ifc_door_frame): yes; Epaisseur cadre = Epaisseur mur: no; Ajuster largeur panneau à trou: yes; Largeur battant droit: 0.5; Largeur battant gauche: 0.5; Encadr./Chambranle: no; Seuil: no; Ajuster larg. seuil revêtement: yes; Imposte: no; Angle ouv. battant droit en 2D: 90 deg; Angle ouv. battant gauche en 2D: 90 deg; Stylo du symbole: Ouvertures - Général; Motif de hachure cadre: Background Fill-International; Stylo hachure cadre: Ouvertures - Hachures coupées; Stylo fond de hachure cadre: Fond - Couleur 1; Motif de hachure battant: Air Space; Stylo hachure de battant: Fond - Couleur 1; Stylo fond de hachure battant: Fond - Couleur 1; Angle ouv. battant droit en 3D: 0 deg; Angle ouv. battant gauche en 3D: 0 deg; Stylo cadre: Eléments 2D - Général; Stylo panneaux: Eléments 2D - Général; Surface de cadre: 06 | W Pine V; Surface de battant: 06 | W Pine H; Surface d'imposte: 08 | Glass-Clear; Surface de seuil: 06 | W Pine V; Opération IFC (ifc_optypestr): Porte double battant simple; Opération IFC (ifc_optype): 2
AC_Pset_RenovationAndPhasing - Renovation Status: Existing
Pset_DoorCommon - IsExternal: no
BaseQuantities - Height: 2.1 m; Depth: 0.13 m
ArchiCADQuantities - Hauteur: 2.1 m; Epaisseur: 0.1 m; Hauteur ouverture côté ébrasure: 2.1 m; Hauteur ouverture côté opposé ébrasure: 2.1 m; Hauteur nominale de l'ouverture côté ébrasure: 2.1 m; Hauteur nominale de l'ouverture côté opposée ébrasure: 2.1 m; Epaisseur de Mur: 0.13 m
AC_Equantity_IFC_Porte_double_-_Simple_battant - 2ème dimension: 2.1 m; Hauteur: 1 m; Niveau inférieur: 1 m; Niveau supérieur: 0 m; Hauteur cavité mur: 2.1 m; Hauteur ébrasure: 2.1 m; Hauteur unité: 2.1 m; Hauteur passage: 2.05 m; Hauteur battant: 2.05 m; Epaisseur cadre: 0.1 m; Largeur cadre: 0.05 m; Epaisseur battant droit: 0.04 m; Epaisseur battant gauche: 0.04 m; Couper épaisseur (Profondeur de chambranle): 0.02 m; Couper largeur (Epaisseur de chambranle): 0.1 m; Largeur seuil: 0.1 m; Décalage seuil: 0 m; Epaisseur seuil: 0.02 m; Hauteur panneau de porte: 1.5 m; Epaisseur imposte: 0.05 m; Dépass.ouverture gauche: 0 m; Dépass.ouverture à droite: 0 m; Dépass.ouverture supérieur: 0 m; Dépass.ouverture inférieur: 0 m
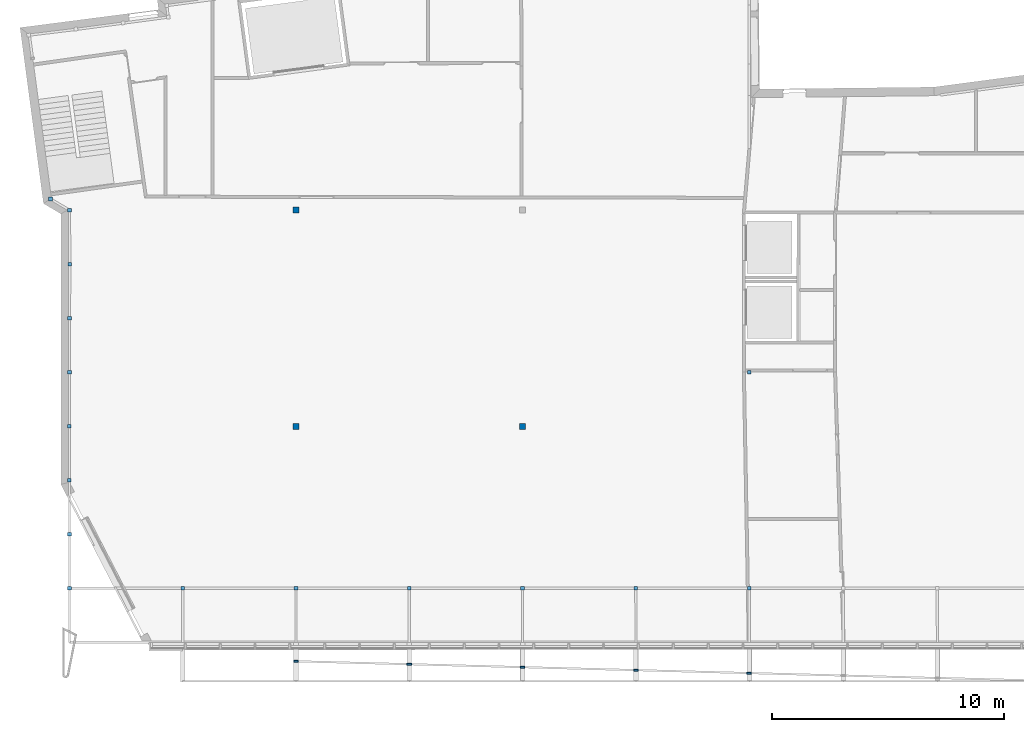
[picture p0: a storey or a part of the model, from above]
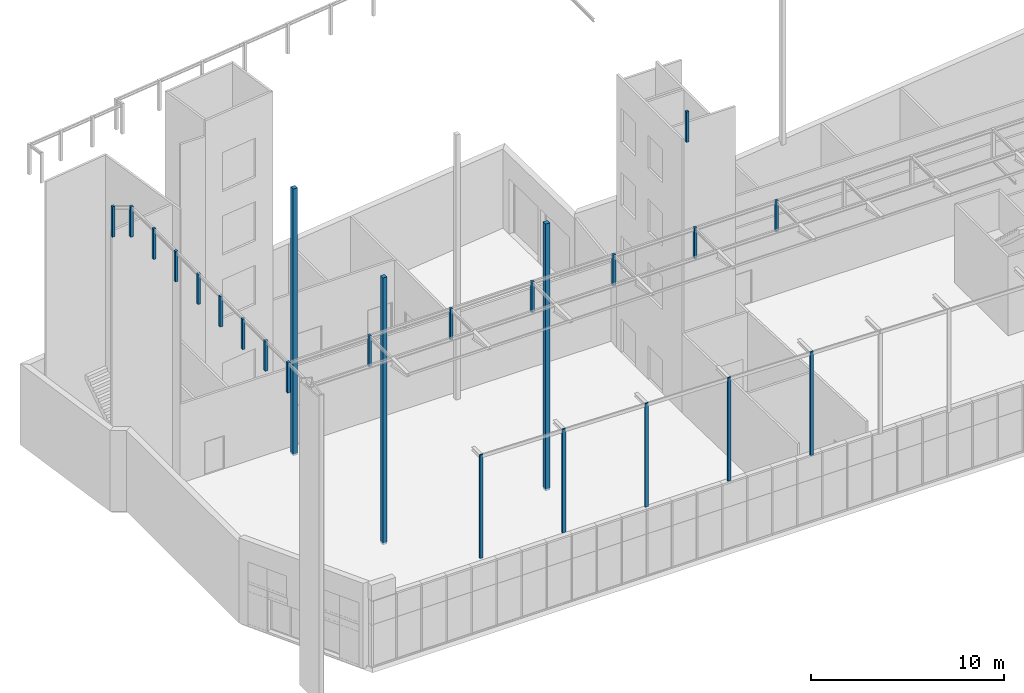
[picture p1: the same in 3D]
Properties of the parts of a building model (IFC2X3), part 9 of 19

# IfcDoor: Porte d'entrée 18 (2)
AC_Equantity_Porte_d'entrée_18 - Largeur: 1.2 m; Hauteur: 2.1 m; Dimension Z: 1 m; Niveau inférieur: 1 m; Niveau supérieur: 0 m; Nouv. largeur droite hach. mur: 0.15 m; Nouv. largeur gauche hach. mur: 0.15 m; Hauteur départ Linteau: 2.07 m; Largeur tierce vitrée 1 (gs_sidelight_width_right): 0.3 m; Largeur tierce vitrée 1 (gs_sidelight_width_right_half): 0.15 m; Largeur tierce vitrée 1 (gs_sidelight_width_right_orig): 0.3 m; Hauteur seuil tierce vitrée 1: 0 m; Largeur tierce vitrée 2 (gs_sidelight_width_left): 0.3 m; Largeur tierce vitrée 2 (gs_sidelight_width_left_half): 0.15 m; Largeur tierce vitrée 2 (gs_sidelight_width_left_orig): 0.3 m; Hauteur seuil tierce vitrée 2: 0 m; Décalage axe pivot: 0.275 m; Tolérance côté 1: 0 m; Tolérance côté 1 inf.: 0 m; Tolérance tierce vitrée bas1: 0 m; Tolérance côté 2: 0 m; Tolérance côté 2 inf.: 0 m; Tolérance tierce vitrée bas 2: 0 m; Tolérance supérieure: 0 m; Tolérance inférieure: 0 m; Largeur cavité mur: 1.2 m; Hauteur cavité mur: 2.1 m; Largeur ébrasure: 1.2 m; Hauteur ébrasure: 2.1 m; Largeur unité: 1.2 m; Hauteur unité: 2.1 m; Largeur passage: 1.12 m; Hauteur passage: 2.06 m; Largeur battant: 1.144 m; Hauteur battant: 2.072 m; Epaisseur cadre: 0.1 m; Epaisseur cadre intérieur: 0.115 m; Décalage battant: 0 m; Largeur cadre: 0.04 m; Débord cadre: 0.01 m; Largeur cadre côté 1: 0.032 m; Largeur cadre centre côté 1: 0.04 m; Largeur cadre inf. côté 1: 0.04 m; Largeur cadre côté 2: 0.032 m; Largeur cadre centre côté 2: 0.04 m; Largeur cadre inf. côté 2: 0.04 m; Largeur cadre imposte (gs_frame_width_transom): 0.04 m; Largeur cadre supérieur: 0.032 m; Epaisseur butoir: 0.032 m; Largeur butoir: 0.016 m; Largeur feuillure: 0.012 m; Largeur feuillure tierce vitrée et imposte: 0.01 m; Profondeur feuillure tierce vitrée et imposte: 0.018 m; Largeur battant côté 1: 0.9 m; Epaisseur panneaux: 0.04 m; Larg. latérale cadre battant: 0.1 m; Larg. droite cadre battant: 0.1 m; Larg. gauche cadre battant: 0.1 m; Larg. inférieure cadre battant: 0.2 m; Larg. sup. cadre battant: 0.1 m; Largeur int. cadre battant: 0.025 m; Largeur meneau: 0.012 m; Épaisseur meneau: 0.025 m; Epaisseur vitrage: 0.007 m; Hauteur poignée: 1 m; Position poignée: 0.05 m; Hauteur division H côté tierce vitrée 1: 0.9 m; Hauteur division H côté tierce vitrée 2: 0.9 m; Hauteur division H imposte centre: 0.9 m; Hauteur division H côté imposte 1: 0.9 m; Hauteur division H côté imposte 2: 0.9 m; Epaisseur cadre tierce vitrée et imposte: 0.044 m; Largeur cadre imposte (gs_sash_width): 0.067 m; Largeur cadre châssis vitré: 0.067 m; Largeur grille: 0.02 m; Epaisseur grille: 0.025 m; Largeur division tierce vitrée: 0.04 m; Epaisseur division tierce vitrée: 0.1 m; Hauteur imposte: 0.3 m; Largeur côté 1 (gs_tw_right_out): 0.075 m; Largeur côté 2 (gs_tw_left_out): 0.075 m; Largeur haut (gs_tw_top_out): 0.075 m; Epaisseur sur mur (gs_trim_thk_out): 0.005 m; Epaisseur dans trou de mur (gs_trim_width_out): 0.005 m; Décalage (gs_trim_offs_out): 0.012 m; Débord supérieur (gs_trimov_top_left_out): 0 m; Débord supérieur (gs_trimov_top_right_out): 0 m; Largeur côté 1 (gs_tw_right_in): 0.075 m; Largeur côté 2 (gs_tw_left_in): 0.075 m; Largeur haut (gs_tw_top_in): 0.075 m; Epaisseur sur mur (gs_trim_thk_in): 0.005 m; Epaisseur dans trou de mur (gs_trim_width_in): 0.005 m; Décalage (gs_trim_offs_in): 0.012 m; Débord supérieur (gs_trimov_top_left_in): 0 m; Débord supérieur (gs_trimov_top_right_in): 0 m; Epaisseur seuil: 0.012 m; Largeur seuil: 0.01 m; Epaisseur externe seuil: 0.00580738 m; Nez seuil extérieur: 0.025 m; Nez seuil intérieur: 0.025 m; Débord côté ext.: 0 m; Débord côté int.: 0 m; Epaisseur appui: 0.025 m; Epaisseur front appui: 0.07 m; Altitude appui: 0.005 m; Débord larmier appui: 0.02 m; Largeur larmier appui: 0.03 m; Débord appui: 0.03 m; Débord seuil sur côté 1: 0 m; Débord seuil sur côté 2: 0 m; Glissement appui en profondeur: 0.02 m; Largeur supérieure appui: 0.02 m; Hauteur supérieure appui: 0.01 m; Glissement appui de mur: 0 m; Profondeur trou arrière (gs_sill_holeDepthBehind): 0.0013084 m; Largeur appui: 0.0513788 m; Epaisseur brique (gs_brick_sill_br_thk): 0.065 m; Epaisseur mortier (gs_brick_sill_mort_thk): 0.015 m; Largeur latte: 0.1 m; Epaisseur latte: 0.025 m; Débord tablette: 0.03 m; Débord tablette côté 1: 0 m; Débord tablette côté 2: 0 m; Glissement tabl. en profondeur: 0 m; Hauteur profil: 0.065 m; Epaisseur profil: 0.11 m; Hauteur panneau: 1.5 m; Décalage intérieur: 0.02 m; Profondeur fermeture: 0 m; Largeur cadre supplémentaire: 0.04 m; Epaisseur cadre supplémentaire: 0.03 m; Epaisseur allège vitrée: 0.03 m; Longueur colonne centrale: 0.02 m; Rayon colonne centrale: 0.005 m; Distance panneau: 0.006 m; Débord extérieur: 0 m; Largeur panneau intérieur: 0.12 m; Longueur ouverture en 3D: 1.5 m; Longueur fermée en 3D: 0 m; Longueur ouverture 1 en 3D: 0.56 m; Longueur ouverture 2 en 3D: 0.14 m; Hauteur ouverture en 3D: 1.5 m; Hauteur fermée en 3D: 0 m; Epaisseur panneau: 0.05 m; Largeur cadre panneau: 0.05 m; Largeur cadre inférieur: 0.05 m; Largeur panneau: 0 m; Epaisseur hachure panneau: 0.01 m; Epaisseur persienne: 0.01 m; Largeur persienne: 0.04 m; Largeur diviseur cadre horiz.: 0.05 m; Largeur diviseur cadre vert.: 0.05 m; Rayon trou: 0.01 m; Largeur montant: 0.1 m; Largeur cadre Z: 0.05 m; Epaisseur cadre Z: 0.025 m; Epaisseur plans verticaux: 0.025 m; Epaisseur plans horizontaux: 0.025 m; Largeur appr. plans verticaux: 0.08 m; Largeur appr. plans horizontaux: 0.115 m; Hauteur boîte (gs_shutRoll_boxHeight): 0.2 m; Profondeur boîte (gs_shutRoll_boxWidth): 0.15 m; Décalage boîte gauche: 0 m; Décalage boîte droite: 0 m; Profondeur rails: 0.0725 m; Distance au mur (gs_shutRoll_distFromWall): 0 m; Distance au linteau (gs_shutRoll_distFromHead): 0 m; Largeur lamelle: 0.05 m; Hauteur boîte (gs_shutLam_boxHeight): 0.2 m; Profondeur boîte (gs_shutLam_boxWidth): 0.15 m; Largeur recouvrement: 0 m; Distance au mur (gs_shutLam_distFromWall): 0 m; Distance au linteau (gs_shutLam_distFromHead): 0 m; Largeur segment (gs_shutLam_segmentWidth): 0.06 m; Hauteur boîte (gs_shutLam2_boxHeight): 0.06 m; Largeur boîte: 0.06 m; Distance à fenêtre: 0.06 m; Distance au linteau (gs_shutLam2_distFromHead): 0.06 m; Hauteur axe cellule à linteau: 0 m; Largeur segment (gs_shutLam2_segmentWidth): 0.06 m; Distance entre arche et fenêtre: 0 m; Dépassement linteau côté 1: 0 m; Dépassement linteau côté 2: 0 m; Elevation linteau: 0.03 m; Décalage linteau: 0 m; Hauteur linteau: 0.25 m; Profondeur linteau: 0.12 m; Profondeur trou arrière (gs_masonry_arch_rearHoleDepth): 0 m; Epaisseur brique (gs_masonry_arch_brick_thk): 0.065 m; Epaisseur mortier (gs_masonry_arch_mort_thk): 0.01 m; Largeur clé de voûte: 0.1 m; Dépassement clé de voûte: 0 m; Projection clé de voûte: 0.01 m; Profondeur ébrasure : (gs_wido_sill): 0 m; Profondeur ébrasure : (AC_wido_sill): 0 m; Profondeur montant: 0.06 m; Profondeur montant côté 2: 0.06 m; Profondeur montant inf. côté 1: 0.06 m; Profondeur montant inf. côté 2: 0.06 m; Profondeur montant int. côté 2 (gs_reveal_splayed_innerLeft): 0.06 m; Profondeur montant intérieur (gs_reveal_splayed_innerRight): 0.06 m; Profondeur montant intérieur (gs_reveal_double_innerRight): 0.06 m; Profondeur montant int. côté 2 (gs_reveal_double_innerLeft): 0.06 m; Profondeur montant inf. int. côté 1: 0.06 m; Profondeur montant inf. int. côté 2: 0.06 m; Profondeur tête: 0.06 m; Profondeur appui: 0 m; Profondeur seuil sur côté 1: 0.06 m; Profondeur seuil sur côté 2: 0.06 m; Profondeur linteau int. (gs_reveal_splayed_innerTop): 0.06 m; Profondeur appui int. (gs_reveal_splayed_innerBottom): 0.06 m; Profondeur linteau int. (gs_reveal_double_innerTop): 0.06 m; Profondeur appui int. (gs_reveal_double_innerBottom): 0 m; Profondeur seuil int. côté 1: 0 m; Profondeur seuil int. côté 2: 0 m; Profondeur montant ext.: 0.08 m; Limite épaisseur plâtre: 0.04 m; Distance de couche / fermeture: 0 m; Largeur fermeture: 0.038 m; Epaisseur fermeture: 0.1 m; Epaisseur bande: 0.025 m; Largeur profilé: 0.15 m; Epaisseur personnalisée: 0.015 m; Dépassement couche prof. cadre: 0 m; Dépassement ouverture gauche: 0 m; Dépassement ouverture droite: 0 m; Dépassement ouverture supérieur: 0 m; Dépassement ouverture inférieur: 0 m; Largeur d'ouverture en 3D: 0 m; Largeur ouverture 3D côté 2: 0 m; Largeur d'ouverture en 2D: 0 m; Largeur ouverture 2D côté 2: 0 m; Distance ouverture 1 Châssis princ. côté 1: 0 m; Distance ouverture 2 Châssis princ. côté 1: 0 m; Distance ouverture 1 Châssis princ. côté 2: 0 m; Distance ouverture 2 Châssis princ. côté 2: 0 m; Distance ouverture 1 imposte centre: 0 m; Distance ouverture 2 imposte centre: 0 m; Distance ouverture 1 imposte côté 1: 0 m; Distance ouverture 2 imposte côté 1: 0 m; Distance ouverture 1 imposte côté 2: 0 m; Distance ouverture 2 imposte côté 2: 0 m; Côté ouverture Largeur 2 (ms_openingSWidth1): 0.3 m; Côté ouverture Largeur 1 (ms_openingSWidth2): 0.1 m; Côté ouverture Profondeur: 2 m; Côté ouverture Largeur 2 (ms_oppositeSWidth1): 0.25 m; Côté ouverture Largeur 1 (ms_oppositeSWidth2): 0.1 m; Côté opposé Profondeur: 1.2 m; Côté ouverture Largeur: 0 m; Dépass.ouverture gauche: 0 m; Dépass.ouverture à droite: 0 m; Dépass.ouverture supérieur: 0 m; Dépass.ouverture inférieur: 0 m; Epaisseur réelle du cadre: 0.1 m
Name | Stylo contour cadre | Stylo hachure cadre | Stylo cadre | Stylo vitrage = Stylo vitrage battant | Orientation porte | Altitude à Zéro du Projet (m) = Altitude à étage (m) = Hauteur appui à étage actuel (m) | Hauteur nominale seuil (m) = Hauteur seuil côté ébrasure (m) = Hauteur seuil côté opposé ébrasure (m) = Valeur Appui ou Linteau (m) | Hauteur nominale linteau (m) = Hauteur linteau côté opposé ébrasure (m) | Hauteur linteau côté ébrasure (m)
DOOR | Ouvertures - Coupé structurel | Ouvertures - Hachures coupées | Ouvertures - Général | Maçonnerie | G | 0.12 | 0.12 | 2.22 | 2.16 | ArchiCADProperties - Nom de Zone: Surface expoitation; Numéro de Zone: 007; De Zone: Surface expoitation; De la Zone numéro: 007
DOOR | A construire - Coupe | A construire - Coupe | A construire - Coupe | A construire - Coupe | D | 0.1 | 0 | 2.1 | 2.04

# IfcDoor: Porte d'entrée 18 (2)
In: Rez de chaussée
Type - OperationType: SINGLE_SWING_RIGHT; ParameterTakesPrecedence: no; Sizeable: no
Type - Propriétés Doublure Porte - LiningDepth: 0.1 m; LiningThickness: 0.04 m; LiningOffset: -0.27 m
Type - Propriétés Panneau Porte - Panneau1 - PanelDepth: 0.04 m; PanelOperation: SWINGING; PanelWidth: 1; PanelPosition: MIDDLE
Description: DOOR; OverallHeight: 2.1 m; OverallWidth: 1.2 m; Material: Background Fill-International (12), Air Space (2), 01 | Hatch-Dashed, Foreground Fill-International, 07 | Insulation Rigid
ArchiCADProperties - ID: DOOR; Etage d'implantation: Rez de chaussée; Calque: A-WALL-EXTR; Type: Porte; Verrouillé: no; Nom Elément de Bibliothèque: Porte d'entrée 18; Matériau de construction / Composite / Profil / Hachure: Solid Fill; Fonction structurelle: Elément non porteur; Position: Intérieur; Classification d'lément: Porte; Etat de rénovation: Existant; Afficher sur filtre de rénovation: Tous les filtres appropriés; Texte Marque: DOOR; Orientation: G; Dimensions ébrasure: 47,24"x82,68"; Dimensions trou mur: 47,24"x82,68"; Dimensions unité: 47,24"x82,68"; Dimensions sortie: 44,09"x81,10"; Dimensions battant: 45,04"x81,57"; Structure mur: 1.2-Mur ext: revét ext + isol ext + maçonnerie + enduit; Taille L x H nominale: 47,24"x82,68"; Taille L x H x E nominale: 47,24"x82,68"x14,57"
AC_Pset_Porte_d'entrée_18 - Contours Mur (0-Sans,1-Tout,2-Côté,3-Longueur): 0; Point ch.0-Non,1-2D,2-3D,3-Tous: 3; Afficher points chauds 2D en 3D: yes; Option affichage en plan: 3; Angle de position baie: 0 deg; Trou reprend surface latérale de mur: yes; Division de surface de trou courbée: no; Type de mur: 1; Type de direction de mur: 0; Direction d'ouverture: 0; Basculer: no; Valeur incrustation allège: 3; Démolition / Nouvelle constr.: 1; Motif de hachure démolition: 0; Stylo démolition: Transparent; Stylo fond démolition: Transparent; Nouveau motif de hachure: 0; Nouveau stylo: Transparent; Nouveau stylo de fond: Transparent; Nouveau motif de hachure de mur: 04 | Block Masonry; Nouveau stylo de hachure de mur: Général - Dessin; Nouveau stylo fond hachure mur: Fond - Couleur 1; Afficher nouv. constr. sur mur: no; Type de ligne démolition: 1; Aff. param. Démolition/Nouveau: no; Afficher comme imposte: no; Châssis vitré (gs_SidelightTransomRelation): Sous imposte; Châssis vitré (gs_SidelightTransomRelation_m): 1; Tierce vitrée 1: no; Tierce vitrée 2: no; Tolérances uniformes: no; Taille nominale: 0; Taille trou comme taille nominale: yes; Taille ébrasure comme nominale: no; Taille unité comme nominale: no; Taille sortie comme nominale: no; Taille battant comme nominale: no; Conserver valeur de taille nominale en changeant: no; Afficher points chaud éditables: yes; Niveau de détail 2D: 2; Afficher ébrasure sur symbole: 2; Affichage symbolique de l'ouverture: no; Niveau de détail 3D: 2; Direction ouverture tiere vitrée (gs_opening_dir_sl): Identique à battant; Direction ouverture tiere vitrée (gs_opening_dir_sl_m): 1; Cadre porte (gs_pocket_door_frame): yes; Style de cadre (gs_frame_style): Simple feuillure; Style de cadre (gs_frame_style_m): 3; Epaisseur cadre=Epaisseur mur: no; Epaisseur cadre uniforme: yes; Battant centré: yes; Largeur cadre uniforme: yes; Style cadre changé automatiquement: no; Nombre de battants: 4; Nombre de battants - côté 2: 3; Style panneau de porte (gs_door_typ): Style 6; Style panneau de porte (gs_door_typ_m): 75; Configuration battants (gs_LeavesConfig): Battants uniformes; Configuration battants (gs_iLeavesConfig): 1; Position meneau (gs_grill_pos): Les deux; Position meneau (gs_grill_pos_m): 3; Nombre panneaux verticalement: 4; Nombre panneaux horizontalement: 3; Nbre panneaux vert. côté 1: 4; Nbre panneaux hor. côté 1: 3; Afficher comme panneau vitre sur symbole: no; Afficher symbole porte chinoise: no; Afficher symbole comme panneau étanche: no; Poignée d'ouverture (gs_handle_type): Sans; Poignée d'ouverture (gs_handle_type_m): 0; Afficher poignée sur symbole: no; Châssis uniformes: no; Type d'ouverture (gs_optype_m_05): 3; Type d'ouverture (gs_optype_m_09): 1; Type d'ouverture (gs_optype_m_02): 1; Type d'ouverture (gs_optype_m_06): 1; Type d'ouverture (gs_optype_m_10): 1; Type châssis (MullionStyle_00): Nombre de meneaux; Type châssis (iMullionStyle_00): 1; Type châssis (iMullionStyle_05): 1; Type châssis (iMullionStyle_09): 1; Type châssis (iMullionStyle_02): 1; Type châssis (iMullionStyle_06): 1; Type châssis (iMullionStyle_10): 1; Edition point chaud de grille: yes; Position meneau (MullionPosition): Les deux; Position meneau (iMullionPosition): 3; Nbre panneaux V châssis princ. côté 1: 4; Nbre panneaux H châssis princ. côté 1: 2; Nbre panneaux V 2 châssis princ. côté 1: 4; Nbre panneaux H 2 châssis princ. côté 1: 2; Nbre panneaux V châssis princ. côté 2: 4; Nbre panneaux H châssis princ. côté 2: 2; Nbre panneaux V 2 châssis princ. côté 2: 4; Nbre panneaux H 2 châssis princ. côté 2: 2; Nbre panneaux V imposte centre: 2; Nbre panneaux H imposte centre: 2; Nbre panneaux V 2 imposte centre: 2; Nbre panneaux H 2 imposte centre: 2; Nbre panneaux vert. imposte côté 1: 2; Nbre panneaux hor. imposte côté 1: 2; Nbre panneaux V 2 imposte côté 1: 2; Nbre panneaux H 2 imposte côté 1: 2; Nbre panneaux vert. imposte côté 2: 2; Nbre panneaux hor. imposte côté 2: 2; Nbre panneaux V 2 imposte côté 2: 2; Nbre panneaux H 2 imposte côté 2: 2; Imposte (gs_door_transom): no; Chambranle extérieur: no; Type chambr. ext. (gs_trimtype_out): Rectangulaire; Type chambr. ext. (gs_trimtype_out_int): 1; Largeurs uniformes de chambranle (gs_trim_outside_uniform): no; Chambranle intérieur.: no; Type chambr. intérieur (gs_trimtype_in): Rectangulaire; Type chambr. intérieur (gs_trimtype_in_int): 1; Largeurs uniformes de chambranle (gs_trim_inside_uniform): no; Seuil: 1; Angle seuil: 3.1996 deg; Seuil changé automatiquement: no; Appui - porte: yes; Appui - Tierce vitrée côté 1: no; Appui - Tierce vitrée: no; Dépassement appui: no; Type d'appui/seuil: 2; Angle appui: 3 deg; Appui courbe dans murs courbes: yes; Isolation sous appui: yes; Utiliser couche isolation mur: no; Niveau détail 3D seuil brique: 1; Style appui changé automatiquement: no; Tablette - côté tierce vitrée 1: no; Tablette - Tierce vitrée: no; Tablette - porte: no; Angle tablette: 0 deg; Tabl. courbe dans murs courbes: yes; Tableau dans murs polygonaux: 1; Aération naturelle (VentilationProfileType): Sans; Aération naturelle (iVentilationProfileType): 1; Type volet (gs_sunShade_type): Sans; Type volet (gs_sunShade_iType): 0; Types volet activés: 127; Nombre de panneaux: 2; Nombre de panneaux 2: 1; Position panneau (gs_shutter_panelPos): Symmetric; Position panneau (gs_shutter_iPanelPos): 1; Hauteur volet automatique: yes; Cadre supplémentaire: no; Type de couverture (gs_slidingShutter_cover): Z-Profile; Type de couverture (gs_slidingShutter_iCover): 1; Direction articulation (gs_foldingShutter_stacking): Inside; Direction articulation (gs_foldingShutter_iStacking): 1; Ouvert en 3D: yes; Angle ouverture en 3D (gs_shutter_opAngle): 180 deg; Afficher symbole 2D: yes; Afficher lignes d'ouverture sur symbole: no; Type de panneau: (gs_shutPanel_type): Style 1; Type de panneau: (gs_shutPanel_iType): 1; Largeur cadre inf. différente: no; Largeur volets automatiques: yes; Angle persienne: 30 deg; Résolution trou: 3; Nombre trous horizontaux: 5; Nombre trous verticaux: 8; Placement volet roulant (gs_shutRoll_placement): Fixed on Facade; Placement volet roulant (gs_shutRoll_iPlacement): 1; Type boîte (gs_shutRoll_boxType): Rectangular; Type boîte (gs_shutRoll_iBoxType): 1; Position rampe (gs_shutRoll_railPos): Sur revêtement; Position rampe (gs_shutRoll_iRailPos): 1; Afficher revêtement derrière parasol (gs_shutRoll_showCasingBehind): no; Isolation derrière cellule (gs_shutRoll_cutWallBehind): no; Inclure hauteur dans hauteur de trou de mur: no; Angle supérieur boîte: 10 deg; Taille boîte par défaut (gs_shutRoll_boxDefaultSize): Reveal Width; Taille boîte par défaut (gs_shutRoll_iBoxDefaultSize): 1; Placement stores (gs_shutLam_placement): Fixed on Facade; Placement stores (gs_shutLam_iPlacement): 1; Isolation derrière cellule (gs_shutLam_cutWallBehind): no; Boîte ouverte: yes; Rampe (gs_shutLam_bRail): yes; Position rampe (gs_shutLam_railPos): Sur revêtement; Position rampe (gs_shutLam_iRailPos): 1; Afficher revêtement derrière parasol (gs_shutLam_showCasingBehind): no; Angle de rotation des lamelles (gs_shutLam_rotation): 45 deg; Angle de rotation des lamelles (gs_shutLam2_rotation): 45 deg; Linteau (gs_masonry_arch): Sans; Linteau (gs_masonry_arch_int): 1; Type linteau (gs_masonry_arch_structure): Stuc; Type linteau (gs_masonry_arch_structure_int): 1; Arche sur linteau: yes; Niche sous arche: yes; Angle inclinaison: 75 deg; Surface niche personnalisée: no; Type ébrasure (gs_reveal_type_new): Pas d'ébrasure - arête; Type ébrasure (gs_reveal_type_int): 1; Type ébrasure inférieure (gs_reveal_type_bottom): Baie simple; Type ébrasure inférieure (gs_reveal_type_bottom_int): 2; Définir profondeur montant sur côté: 1; Profondeur montant uniforme: no; Type ébrasure extérieure: Baie simple; Type ébrasure (gs_reveal_doubleOuterTypeInt): 2; Type ébrasure intérieure: Baie simple; Type ébrasure (gs_reveal_doubleInnerTypeInt): 2; Côté angle 2: 20 deg; Côté angle: 20 deg; Angle côté supérieur: 20 deg; Angle côté inférieur: 20 deg; Côté angle extérieur 2: 20 deg; Côté angle extérieur: 20 deg; Angle extérieur côté sup.: 20 deg; Angle extérieur côté inf.: 20 deg; Rampe sous battants: no; Rampe (gs_door_rail_ext): Sans; Rampe (gs_door_rail_ext_m): 1; Utiliser composant finition mur: no; Tourner automatiquement plâtre surface intérieure: yes; Tourner plâtre surface intérieure: 0; Tourner automatiquement plâtre surface extérieure: yes; Tourner plâtre surface extérieure: 0; Afficher en 3D: no; Type de fermeture (gs_closure_type): Pas de fermeture; Type de fermeture (gs_closure_type_int): 1; Tourner couche sur côté (gs_cavity_side): Les deux; Tourner couche sur côté (iCavityClosureSide): 1; Nbre de couches retournées: 1; Num. à partir de (gs_nTurnDir): Face extérieure; Num. à partir de (iCavityClosureTurnDir): 1; Placer fermeture sur côté 1: yes; Placer fermeture sur côté 2: yes; Placer fermeture en haut: no; Placer fermeture en bas: no; Placer fermeture sur couche: 1; Placer fermeture de côté (gs_cc_dutch_ClosureToSide): 1; Ecart à couche externe: yes; Tourner couche sur fermeture: no; Insérer bande d'isolation: yes; Afficher bande d'isolation: yes; Stylo contour (gs_penJoint): Ouvertures - Coupé non structurel; Type de ligne de contour (gs_ltJoint): 1; Motif de hachure (gs_fillJoint): 07 | Insulation Rigid; Stylo hachure (gs_penJointFg): Général - Dessin; Stylo fond de hachure (gs_penJointBg): Eléments 2D - Dessin; Surface personnalisée: no; Surface: 06 | W Pine H; Stylo contour (gs_penPlug): Ouvertures - Coupé non structurel; Type de ligne de contour (gs_ltPlug): 1; Motif de hachure (gs_fillPlug): 07 | Insulation Rigid; Stylo hachure (gs_penPlugFg): Général - Dessin; Stylo fond de hachure (gs_penPlugBg): Eléments 2D - Dessin; Côté montant édité: 1; Côté mur édité: 1; Numéro couche éditée: 1; Tourner couche: no; Considérer couches comme plâtre: no; Tourner épaiseur: 1; Orientation hachure: 1; Ligne de séparation tournant: no; Stylo ligne de séparation: Général - Dessin; Dernier côté sélectionné: no; Méthode fermeture changée auto.: no; Connexion sur côté 1: no; Connexion sur côté 2: no; Connexion en haut: no; Type d'ouverture (gs_leaf_optype): Accrochée sur côté; Type d'ouverture (gs_leaf_optype_m): 1; Ouverture panneau de fin côté 1: no; Ouverture panneau de fin côté 2: no; Angle ouverture en 2D: 90 deg; Angle ouverture 2D côté 2: 90 deg; Angle ouverture en 3D (gs_open_3D): 0 deg; Angle ouv. battant fin 3D côté 2: 0 deg; Angle ouv. châssis principal côté 1 (openingAngle_05): 0 deg; Angle ouv. châssis principal côté 1 (openingAngle2_05): 0 deg; Angle ouv. châssis principal côté 2 (openingAngle_09): 0 deg; Angle ouv. châssis principal côté 2 (openingAngle2_09): 0 deg; Angle ouv. imposte centre (openingAngle_02): 0 deg; Angle ouv. imposte centre (openingAngle2_02): 0 deg; Angle ouverture imposte côté 1 (openingAngle_06): 0 deg; Angle ouverture imposte côté 1 (openingAngle2_06): 0 deg; Angle ouverture imposte côté 2 (openingAngle_10): 0 deg; Angle ouverture imposte côté 2 (openingAngle2_10): 0 deg; Type ligne double à carreaux: 4; Suppl. Opt. vue pour aff. symb. 2D: no; Type ligne ouverture: 1; Forme ligne ouverture (or_SwingType): Courbé; Forme ligne ouverture (or_iSwingType): 1; Forme ligne ouverture (or_SlidingType): Sans; Forme ligne ouverture (or_iSlidingType): 0; Suppl. Opt. vue pour proj. porte 3D: no; Afficher ligne d'ouverture (or_bOplines3d): yes; Type ligne côté ouverture (or_opLineType3dIn): Tirets; Type ligne côté ouverture (or_iOpLineType3dIn): 1; Type ligne côté opposé (or_opLineType3dOut): Ligne continue; Type ligne côté opposé (or_iOpLineType3dOut): 0; Orient. ligne (or_oplineStyle): Poignée; Orient. ligne (or_iOplineStyle): 1; Stylo ligne ouverture 2D/3D (or_opLinePen): Ouvertures - Général; Stylo ligne ouverture 2D/3D (or_iOpLinePen): 3; Suppl. Opt. vue mod. pr proj. 3D tierce/imposte: no; Afficher ligne d'ouverture (or_bWinOplines3d): yes; Type ligne côté ouverture (or_winOpLineType3dIn): Ligne continue; Type ligne côté ouverture (or_iWinOpLineType3dIn): 0; Type ligne côté opposé (or_winOpLineType3dOut): Ligne continue; Type ligne côté opposé (or_iWinOpLineType3dOut): 0; Orient. ligne (or_winOplineStyle): Poignée; Orient. ligne (or_iWinOplineStyle): 1; Stylo ligne ouverture 2D/3D (or_winOpLinePen): Ouvertures - Général; Stylo ligne ouverture 2D/3D (or_iWinOpLinePen): 3; Stylo du symbole: Ouvertures - Général; Stylo contour vitre: A construire - Coupe; Stylo ligne coupée chambranle des deux côtés: Ouvertures - Général; Stylo contour battant: A construire - Coupe; Ligne contour de porte ds mur: Sans; Ligne de contour de mur: 1; Type ligne contour int. mur: 4; Type ligne contour ext. mur: 4; Type ligne contour int. mur masqué: 4; Type ligne contour ext. mur masqué: 4; Ligne contour de tierce vitrée ds mur (gs_wcont_line_sl): Des deux côtés; Ligne contour de tierce vitrée ds mur (iWallContourLineSl): 4; Type ligne contour int. tierce vitrée ds mur: 1; Type ligne contour ext. tierce vitrée ds mur: 1; Type ligne contour int. tierce vitrée ds mur masqué: 4; Type ligne contour ext. tierce vitrée ds mur masqué: 4; Stylo ligne contour de mur: Ouvertures - Général; Utiliser hachures: yes; Motif de hachure cadre: Background Fill-International; Stylo fond de hachure cadre: Fond - Couleur 1; Motif de hachure battant: Air Space; Stylo hachure de battant: Fond - Couleur 1; Stylo fond de hachure battant: Fond - Couleur 1; Hachure vitrage: 01 | Hatch-Dashed; Stylo hachure vitrage: A construire - Coupe; Stylo fond de hachure vitre: Transparent; Motif hachure symbole étanche: Foreground Fill-International; Stylo hachure symbole étanche: Général - Dessin; Stylo fond hachure symbole étanche: Général - Dessin; Motif hachure symbole plan de porte: Background Fill-International; Stylo hachure symbole plan de porte: Fond - Couleur 1; Stylo fond hachure symbole plan de porte: Transparent; Motif hachure symbole plan de tierce vitrée: Background Fill-International; Stylo hachure symbole plan de tierce vitrée: Fond - Couleur 1; Stylo fond hachure symbole plan de tierce vitrée: Fond - Couleur 1; Type ligne seuil et appui: 1; Stylo contour de seuil en coupe: Ouvertures - Général; Motif hachure de seuil en Coupe: Background Fill-International; Stylo hachure seuil en Coupe: Fond - Couleur 1; Stylo fond hachure coupe Seuil: Fond - Couleur 1; Stylo appui 3D et non coupé: Général - Dessin; Stylo contour appui en Coupe: Général - Dessin; Motif hachure appui en Coupe: Background Fill-International; Stylo hachure d'appui en Coupe: Fond - Couleur 1; Stylo fond hachure appui Coupe: Fond - Couleur 1; Stylo contour isolation coupe: Général - Dessin; Motif hachure isolation Coupe: 07 | Insulation Rigid; Stylo hachure isolation Coupe: Général - Dessin; Stylo fond hachure isol. Coupe: Fond - Couleur 1; Stylo latte 3D et non coupé: Général - Dessin; Stylo contour latte en Coupe: Général - Dessin; Motif hachure tablette en Coupe: Background Fill-International; Stylo hachure tablette en Coupe: Fond - Couleur 1; Stylo fond hach. tablette Coupe: Fond - Couleur 1; Type hachure chambr. intérieur: Background Fill-International; Stylo hachure chambr. int.: Fond - Couleur 1; Stylo fond hachure chambr. int.: Fond - Couleur 1; Type hachure chambr. ext.: Background Fill-International; Stylo hachure chambr. ext.: Fond - Couleur 1; Stylo fond hachure chambr. ext.: Fond - Couleur 1; Motif de hachure arche coupe: Background Fill-International; Stylo fond hachure appui arche Coupe (gs_masonry_arch_pen_fg): Fond - Couleur 1; Stylo fond hachure appui arche Coupe (gs_masonry_arch_pen_bg): Fond - Couleur 1; Motif de hachure de Coupe de Profil de ventilation: Air Space; Stylo de hachure de Coupe de Profil de ventilation: Fond - Couleur 1; Stylo de fond de hachure de Coupe de Profil de ventilation: Fond - Couleur 1; Type de ligne symbole volet: 1; Stylo ligne coupée volet: Général - Dessin; Stylo ligne non coupée volet: Général - Dessin; Type hachure coupée volet: Background Fill-International; Stylo hachure coupée volet: Général - Dessin; Stylo fond hachure coupé volet: Fond de fenêtre; Motif de hachure d'isolation de pare-soleil: Background Fill-International; Stylo de hachure d'isolation de pare-soleil: Général - Dessin; Stylo de fond d'isolation de pare-soleil: Fond de fenêtre; Type hachure non coupée: Background Fill-International; Stylo hachure non coupée: Fond - Couleur 1; Stylo fond de hachure non coupé: Fond - Couleur 1; Valeurs côté ouverture (gs_opside_list): Custom; Valeurs côté ouverture (gs_opside_list_m): 0; Jonction éléments cadree (gs_SashText_typ): Assemblage bout à bout; Jonction éléments cadree (gs_SashText_typ_num): 2; Stylo panneaux: A construire - Coupe; Stylo linteau: Murs - Général; Résolution de courbe: 12; Ombre: yes; Surface extérieure cadre: 05 | Iron Coarse; Surface intérieure cadre: 05 | Iron Coarse; Surface extérieure de battant: 05 | Nickel Satin; Surface intérieure de battant: 05 | Nickel Satin; Surface de battant 2: 05 | Nickel Satin; Surface de battant 3: 06 | W Pine H; Surface de verrou: 09 | Paint-08 Black; Surface extérieure de meneau (gs_grill_mat): 06 | W Pine H; Surface intérieure de meneau (gs_grill_mat2): 06 | W Pine H; Surface extérieure de meneau (gs_leaf_grill_mat): 06 | W Pine H; Surface intérieure de meneau (gs_leaf_grill_mat2): 06 | W Pine H; Surface vitre: 08 | Glass-Clear; Surface vitre battant: 08 | Glass-Clear; Surface de rampe: 05 | Iron Coarse; Surface extérieure de persienne: 06 | W Pine H; Surface intérieure de persienne: 06 | W Pine H; Surface de plaque entrée inférieure: 05 | Aluminum Plain; Surface intérieure chambranle: 05 | Iron Coarse; Surface extérieure chambranle: 05 | Iron Coarse; Surface de profil de ventilation: 05 | Aluminum Plain; Surface panneau de volet: 06 | W Pine H; Surface cadre volet: 06 | W Pine H; Surface boîte volet roulant: 05 | Stainless Reflective; Surface lames volet roulant: 09 | Paint-05 Grey; Surface rail volet roulant: 09 | Paint-05 Grey; Surface boîtier de stores: 05 | Stainless Reflective; Surface segments de stores: 09 | Paint-05 Grey; Surface rail volet coulissant: 05 | Stainless Reflective; Surface de seuil: 05 | Iron Coarse; Surface métal seuil: 05 | Aluminum Plain; Surface d'appui: 04 | B Running Bond; Surface mortier appui briques: 09 | Stucco White; Surface de tableau: 06 | W Pine H; Surface de poignée: 05 | Stainless Reflective; Surface accessoires poignée: 05 | Iron Coarse; Surface brique linteau: 04 | B Running Bond; Surface mortier linteau: 09 | Stucco White; Surface clef de voûte linteau: 04 | Sandstone; Surface niche: 32 | Mulch; Porte appartient à Zone vers laquelle elle donne: yes; Coût: 0; Emplacement comme: Personnalisé; Surface vitrée totale (gs_list_glassarea_tmp): 0; Supplanter surface vitrée: yes; Surface vitrée totale (gs_list_glassarea): 0; Périmètre total vitrage: 0; Fermeture automatique: no; Numéro de fermeture automatique: 2; Performance air libre (mm2/l/m): 0; Type de groupe (FM_Type): Others; Type de groupe (iFMType): 999; Poids de l'objet: 0; Unité poids de l'objet: kg; Définition orientation porte (gs_list_orientationDef): Automatique; Définition orientation porte (gs_list_orientationDef_m): 0; Fermeture porte: no; Type panneau de vision: Nbre panneaux vision; Dispositif main. ouvert.: no; Opération IFC (ifc_optypestr): Porte simple battant simple; Opération IFC (ifc_optype): 1
AC_Pset_RenovationAndPhasing - Renovation Status: Existing
Pset_DoorCommon - IsExternal: no
BaseQuantities - Height: 2.1 m; Width: 1.2 m; Perimeter: 6.6 m; Area: 2.52 m2; Volume: 0.051805 m3; Depth: 0.37 m
ArchiCADQuantities - Hauteur: 2.1 m; Superficie de surface: 6.81226 m2; Volume net: 0.051805 m3; Largeur: 1.2 m; Epaisseur: 0.1 m; Largeur ouverture côté ébrasure: 1.2 m; Largeur ouverture côté opposé ébrasure: 1.2 m; Hauteur ouverture côté ébrasure: 2.1 m; Hauteur ouverture côté opposé ébrasure: 2.1 m; Surface ouverture côté ébrasure: 2.52 m2; Surface ouverture côté opposé ébrasure: 2.52 m2; Largeur nominale de l'ouverture côté ébrasure: 1.08 m; Largeur nominale de l'ouverture côté opposée ébrasure: 1.2 m; Hauteur nominale de l'ouverture côté ébrasure: 2.04 m; Hauteur nominale de l'ouverture côté opposée ébrasure: 2.1 m; Surface nominale de l'ouverture P/F côté ébrasure: 2.2032 m2; Surface nominale de l'ouverture P/F côté opposé ébrasure: 2.52 m2; Volume ouverture: 0.051805 m3; Surface nominale ouverture P/F: 2.52 m2; Volume nominal ouverture: 0.9324 m3; Epaisseur de Mur: 0.37 m
AC_Equantity_Porte_d'entrée_18 - Largeur: 1.2 m; Hauteur: 2.1 m; Dimension Z: 1 m; Niveau inférieur: 1 m; Niveau supérieur: 0 m; Nouv. largeur droite hach. mur: 0.15 m; Nouv. largeur gauche hach. mur: 0.15 m; Hauteur départ Linteau: 2.07 m; Largeur tierce vitrée 1 (gs_sidelight_width_right): 0.3 m; Largeur tierce vitrée 1 (gs_sidelight_width_right_half): 0.15 m; Largeur tierce vitrée 1 (gs_sidelight_width_right_orig): 0.3 m; Hauteur seuil tierce vitrée 1: 0 m; Largeur tierce vitrée 2 (gs_sidelight_width_left): 0.3 m; Largeur tierce vitrée 2 (gs_sidelight_width_left_half): 0.15 m; Largeur tierce vitrée 2 (gs_sidelight_width_left_orig): 0.3 m; Hauteur seuil tierce vitrée 2: 0 m; Décalage axe pivot: 0.275 m; Tolérance côté 1: 0 m; Tolérance côté 1 inf.: 0 m; Tolérance tierce vitrée bas1: 0 m; Tolérance côté 2: 0 m; Tolérance côté 2 inf.: 0 m; Tolérance tierce vitrée bas 2: 0 m; Tolérance supérieure: 0 m; Tolérance inférieure: 0 m; Largeur cavité mur: 1.2 m; Hauteur cavité mur: 2.1 m; Largeur ébrasure: 1.2 m; Hauteur ébrasure: 2.1 m; Largeur unité: 1.2 m; Hauteur unité: 2.1 m; Largeur passage: 1.12 m; Hauteur passage: 2.06 m; Largeur battant: 1.144 m; Hauteur battant: 2.072 m; Epaisseur cadre: 0.1 m; Epaisseur cadre intérieur: 0.115 m; Décalage battant: 0 m; Largeur cadre: 0.04 m; Débord cadre: 0.01 m; Largeur cadre côté 1: 0.032 m; Largeur cadre centre côté 1: 0.04 m; Largeur cadre inf. côté 1: 0.04 m; Largeur cadre côté 2: 0.032 m; Largeur cadre centre côté 2: 0.04 m; Largeur cadre inf. côté 2: 0.04 m; Largeur cadre imposte (gs_frame_width_transom): 0.04 m; Largeur cadre supérieur: 0.032 m; Epaisseur butoir: 0.032 m; Largeur butoir: 0.016 m; Largeur feuillure: 0.012 m; Largeur feuillure tierce vitrée et imposte: 0.01 m; Profondeur feuillure tierce vitrée et imposte: 0.018 m; Largeur battant côté 1: 0.9 m; Epaisseur panneaux: 0.04 m; Larg. latérale cadre battant: 0.1 m; Larg. droite cadre battant: 0.1 m; Larg. gauche cadre battant: 0.1 m; Larg. inférieure cadre battant: 0.2 m; Larg. sup. cadre battant: 0.1 m; Largeur int. cadre battant: 0.025 m; Largeur meneau: 0.012 m; Épaisseur meneau: 0.025 m; Epaisseur vitrage: 0.007 m; Hauteur poignée: 1 m; Position poignée: 0.05 m; Hauteur division H côté tierce vitrée 1: 0.9 m; Hauteur division H côté tierce vitrée 2: 0.9 m; Hauteur division H imposte centre: 0.9 m; Hauteur division H côté imposte 1: 0.9 m; Hauteur division H côté imposte 2: 0.9 m; Epaisseur cadre tierce vitrée et imposte: 0.044 m; Largeur cadre imposte (gs_sash_width): 0.067 m; Largeur cadre châssis vitré: 0.067 m; Largeur grille: 0.02 m; Epaisseur grille: 0.025 m; Largeur division tierce vitrée: 0.04 m; Epaisseur division tierce vitrée: 0.1 m; Hauteur imposte: 0.3 m; Largeur côté 1 (gs_tw_right_out): 0.075 m; Largeur côté 2 (gs_tw_left_out): 0.075 m; Largeur haut (gs_tw_top_out): 0.075 m; Epaisseur sur mur (gs_trim_thk_out): 0.005 m; Epaisseur dans trou de mur (gs_trim_width_out): 0.005 m; Décalage (gs_trim_offs_out): 0.012 m; Débord supérieur (gs_trimov_top_left_out): 0 m; Débord supérieur (gs_trimov_top_right_out): 0 m; Largeur côté 1 (gs_tw_right_in): 0.075 m; Largeur côté 2 (gs_tw_left_in): 0.075 m; Largeur haut (gs_tw_top_in): 0.075 m; Epaisseur sur mur (gs_trim_thk_in): 0.005 m; Epaisseur dans trou de mur (gs_trim_width_in): 0.005 m; Décalage (gs_trim_offs_in): 0.012 m; Débord supérieur (gs_trimov_top_left_in): 0 m; Débord supérieur (gs_trimov_top_right_in): 0 m; Epaisseur seuil: 0.012 m; Largeur seuil: 0.01 m; Epaisseur externe seuil: 0.00580738 m; Nez seuil extérieur: 0.025 m; Nez seuil intérieur: 0.025 m; Débord côté ext.: 0 m; Débord côté int.: 0 m; Epaisseur appui: 0.025 m; Epaisseur front appui: 0.07 m; Altitude appui: 0.005 m; Débord larmier appui: 0.02 m; Largeur larmier appui: 0.03 m; Débord appui: 0.03 m; Débord seuil sur côté 1: 0 m; Débord seuil sur côté 2: 0 m; Glissement appui en profondeur: 0.02 m; Largeur supérieure appui: 0.02 m; Hauteur supérieure appui: 0.01 m; Glissement appui de mur: 0 m; Profondeur trou arrière (gs_sill_holeDepthBehind): 0.0013084 m; Largeur appui: 0.0513788 m; Epaisseur brique (gs_brick_sill_br_thk): 0.065 m; Epaisseur mortier (gs_brick_sill_mort_thk): 0.015 m; Largeur latte: 0.1 m; Epaisseur latte: 0.025 m; Débord tablette: 0.03 m; Débord tablette côté 1: 0 m; Débord tablette côté 2: 0 m; Glissement tabl. en profondeur: 0 m; Hauteur profil: 0.065 m; Epaisseur profil: 0.11 m; Hauteur panneau: 1.5 m; Décalage intérieur: 0.02 m; Profondeur fermeture: 0 m; Largeur cadre supplémentaire: 0.04 m; Epaisseur cadre supplémentaire: 0.03 m; Epaisseur allège vitrée: 0.03 m; Longueur colonne centrale: 0.02 m; Rayon colonne centrale: 0.005 m; Distance panneau: 0.006 m; Débord extérieur: 0 m; Largeur panneau intérieur: 0.12 m; Longueur ouverture en 3D: 1.5 m; Longueur fermée en 3D: 0 m; Longueur ouverture 1 en 3D: 0.56 m; Longueur ouverture 2 en 3D: 0.14 m; Hauteur ouverture en 3D: 1.5 m; Hauteur fermée en 3D: 0 m; Epaisseur panneau: 0.05 m; Largeur cadre panneau: 0.05 m; Largeur cadre inférieur: 0.05 m; Largeur panneau: 0 m; Epaisseur hachure panneau: 0.01 m; Epaisseur persienne: 0.01 m; Largeur persienne: 0.04 m; Largeur diviseur cadre horiz.: 0.05 m; Largeur diviseur cadre vert.: 0.05 m; Rayon trou: 0.01 m; Largeur montant: 0.1 m; Largeur cadre Z: 0.05 m; Epaisseur cadre Z: 0.025 m; Epaisseur plans verticaux: 0.025 m; Epaisseur plans horizontaux: 0.025 m; Largeur appr. plans verticaux: 0.08 m; Largeur appr. plans horizontaux: 0.115 m; Hauteur boîte (gs_shutRoll_boxHeight): 0.2 m; Profondeur boîte (gs_shutRoll_boxWidth): 0.15 m; Décalage boîte gauche: 0 m; Décalage boîte droite: 0 m; Profondeur rails: 0.0725 m; Distance au mur (gs_shutRoll_distFromWall): 0 m; Distance au linteau (gs_shutRoll_distFromHead): 0 m; Largeur lamelle: 0.05 m; Hauteur boîte (gs_shutLam_boxHeight): 0.2 m; Profondeur boîte (gs_shutLam_boxWidth): 0.15 m; Largeur recouvrement: 0 m; Distance au mur (gs_shutLam_distFromWall): 0 m; Distance au linteau (gs_shutLam_distFromHead): 0 m; Largeur segment (gs_shutLam_segmentWidth): 0.06 m; Hauteur boîte (gs_shutLam2_boxHeight): 0.06 m; Largeur boîte: 0.06 m; Distance à fenêtre: 0.06 m; Distance au linteau (gs_shutLam2_distFromHead): 0.06 m; Hauteur axe cellule à linteau: 0 m; Largeur segment (gs_shutLam2_segmentWidth): 0.06 m; Distance entre arche et fenêtre: 0 m; Dépassement linteau côté 1: 0 m; Dépassement linteau côté 2: 0 m; Elevation linteau: 0.03 m; Décalage linteau: 0 m; Hauteur linteau: 0.25 m; Profondeur linteau: 0.12 m; Profondeur trou arrière (gs_masonry_arch_rearHoleDepth): 0 m; Epaisseur brique (gs_masonry_arch_brick_thk): 0.065 m; Epaisseur mortier (gs_masonry_arch_mort_thk): 0.01 m; Largeur clé de voûte: 0.1 m; Dépassement clé de voûte: 0 m; Projection clé de voûte: 0.01 m; Profondeur ébrasure : (gs_wido_sill): 0 m; Profondeur ébrasure : (AC_wido_sill): 0 m; Profondeur montant: 0.06 m; Profondeur montant côté 2: 0.06 m; Profondeur montant inf. côté 1: 0.06 m; Profondeur montant inf. côté 2: 0.06 m; Profondeur montant int. côté 2 (gs_reveal_splayed_innerLeft): 0.06 m; Profondeur montant intérieur (gs_reveal_splayed_innerRight): 0.06 m; Profondeur montant intérieur (gs_reveal_double_innerRight): 0.06 m; Profondeur montant int. côté 2 (gs_reveal_double_innerLeft): 0.06 m; Profondeur montant inf. int. côté 1: 0.06 m; Profondeur montant inf. int. côté 2: 0.06 m; Profondeur tête: 0.06 m; Profondeur appui: 0 m; Profondeur seuil sur côté 1: 0.06 m; Profondeur seuil sur côté 2: 0.06 m; Profondeur linteau int. (gs_reveal_splayed_innerTop): 0.06 m; Profondeur appui int. (gs_reveal_splayed_innerBottom): 0.06 m; Profondeur linteau int. (gs_reveal_double_innerTop): 0.06 m; Profondeur appui int. (gs_reveal_double_innerBottom): 0 m; Profondeur seuil int. côté 1: 0 m; Profondeur seuil int. côté 2: 0 m; Profondeur montant ext.: 0.08 m; Limite épaisseur plâtre: 0.04 m; Distance de couche / fermeture: 0 m; Largeur fermeture: 0.038 m; Epaisseur fermeture: 0.1 m; Epaisseur bande: 0.025 m; Largeur profilé: 0.15 m; Epaisseur personnalisée: 0.015 m; Dépassement couche prof. cadre: 0 m; Dépassement ouverture gauche: 0 m; Dépassement ouverture droite: 0 m; Dépassement ouverture supérieur: 0 m; Dépassement ouverture inférieur: 0 m; Largeur d'ouverture en 3D: 0 m; Largeur ouverture 3D côté 2: 0 m; Largeur d'ouverture en 2D: 0 m; Largeur ouverture 2D côté 2: 0 m; Distance ouverture 1 Châssis princ. côté 1: 0 m; Distance ouverture 2 Châssis princ. côté 1: 0 m; Distance ouverture 1 Châssis princ. côté 2: 0 m; Distance ouverture 2 Châssis princ. côté 2: 0 m; Distance ouverture 1 imposte centre: 0 m; Distance ouverture 2 imposte centre: 0 m; Distance ouverture 1 imposte côté 1: 0 m; Distance ouverture 2 imposte côté 1: 0 m; Distance ouverture 1 imposte côté 2: 0 m; Distance ouverture 2 imposte côté 2: 0 m; Côté ouverture Largeur 2 (ms_openingSWidth1): 0.3 m; Côté ouverture Largeur 1 (ms_openingSWidth2): 0.1 m; Côté ouverture Profondeur: 2 m; Côté ouverture Largeur 2 (ms_oppositeSWidth1): 0.25 m; Côté ouverture Largeur 1 (ms_oppositeSWidth2): 0.1 m; Côté opposé Profondeur: 1.2 m; Côté ouverture Largeur: 0 m; Dépass.ouverture gauche: 0 m; Dépass.ouverture à droite: 0 m; Dépass.ouverture supérieur: 0 m; Dépass.ouverture inférieur: 0 m; Epaisseur réelle du cadre: 0.1 m
Name | Stylo contour cadre | Stylo hachure cadre | Stylo cadre | Stylo vitrage = Stylo vitrage battant | Orientation porte | Altitude à Zéro du Projet (m) = Altitude à étage (m) = Hauteur appui à étage actuel (m) | Hauteur nominale seuil (m) = Hauteur seuil côté ébrasure (m) = Hauteur seuil côté opposé ébrasure (m) = Valeur Appui ou Linteau (m) | Hauteur nominale linteau (m) = Hauteur linteau côté opposé ébrasure (m) | Hauteur linteau côté ébrasure (m)
DOOR | Ouvertures - Coupé structurel | Ouvertures - Hachures coupées | Ouvertures - Général | Maçonnerie | D | 0.12 | 0.12 | 2.22 | 2.16 | ArchiCADProperties - Nom de Zone: Surface expoitation; Numéro de Zone: 007; De Zone: Surface expoitation; De la Zone numéro: 007
DOOR | A construire - Coupe | A construire - Coupe | A construire - Coupe | A construire - Coupe | G | 0.1 | 0 | 2.1 | 2.04

# IfcFurnishingElement: Lavabo 18 (3)
In: Mezzannine
Description: San_01; Material: 50 %
ArchiCADProperties - ID: Sanitary; Etage d'implantation: Mezzannine; Nom de Zone: WC; Calque: A-EQMT; Type: Objet; Verrouillé: no; Nom Elément de Bibliothèque: Lavabo 18; Matériau de construction / Composite / Profil / Hachure: 50 %; Fonction structurelle: Elément non porteur; Position: Intérieur; Classification d'lément: Mobilier; Etat de rénovation: Existant; Afficher sur filtre de rénovation: Tous les filtres appropriés; Surface: GENERAL
AC_Pset_Lavabo_18 - Type évier (stStyle): Arrondi 1; Type évier (iStyle): 1; Afficher points chauds 2D en 3D: no; Définir programme: no; 3D (gs_detlevel_3D): Détaillé; 3D (gs_detlevel_3D_m): 2; Type de support (suptyp): Sans; Type de support (iSuptyp): 0; Type robinet (tapGroup): Sans; Type robinet (iTapGroup): 6; Style de robinet (gs_tap_type): Sans; Style de robinet (gs_tap_type_m): 0; Connexion d'eau chaude: yes; Type outil (ConToolType_1): 2; Système MEP (ConSystem_1): Non défini; Type de forme (ConType_1): Cercle; Type connexion (ConConnectorType_1): Soudé; Connexion d'eau froide: yes; Type outil (ConToolType_2): 2; Système MEP (ConSystem_2): Non défini; Type de forme (ConType_2): Cercle; Type connexion (ConConnectorType_2): Soudé; Connexion eau résiduaire: yes; Type outil (ConToolType_3): 2; Système MEP (ConSystem_3): Non défini; Type de forme (ConType_3): Cercle; Type connexion (ConConnectorType_3): Soudé; Résolution: 12; Résolution connexion: 8; Ombre: yes; Type de symbole (gs_symbol_type): Fondé sur modèle; Type de symbole (iSymbolType): 1; Activer types de symbole: no; Niveau de détail 2D (gs_detlevel_2D): Selon échelle; Niveau de détail 2D (gs_detlevel_2D_m): 0; Type symbole robinet (TapSymbol): Détaillé; Type symbole robinet (TapSymbol_m): 2; Stylo contour: Technique - Plomberie; Stylo hachure: Fond - Couleur 1; Stylo fond de hachure: Fond - Couleur 1; Utiliser surface de système: no; Nombre connexions: 3; Coût: 0; Type de groupe (FM_Type): Sanitation; Type de groupe (iFMType): 999; Aire: 0; Volume: 0; Poids de l'objet: 0; Unité poids de l'objet: kg
AC_Pset_RenovationAndPhasing - Renovation Status: Existing
ArchiCADQuantities - Altitude à Zéro du Projet: 9.425 m; Altitude à étage: 0 m; Superficie de surface: 0.475487 m2; Volume net: 0.00000286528 m3; Superficie: 0.1518 m2; Hauteur (Taille en Z): 0.14 m; Longueur (A): 0.46 m; Volume: 0.00000286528 m3; Largeur (B): 0.33 m
AC_Equantity_Lavabo_18 - Largeur lavabo: 0.46 m; Profondeur lavabo: 0.33 m; Hauteur: 0.14 m; Hauteur robinet: 1.1 m; Position robinet en X: 0 m; Position robinet en Y: 0 m; Position robinet en Z: 0 m; Profondeur nominale (ConNominalDepth_1): 0.025 m; Diamètre extérieur (ConWidth_1): 0.027 m; Profondeur extérieure (ConDepth_1): 0.027 m; Epaisseur mur (ConWallThickness_1): 0.001 m; Longueur connexion (ConLength_1): 0.02 m; Diamètre connecteur (ConConnectorWidth_1): 0.04 m; Profondeur connecteur (ConConnectorDepth_1): 0 m; Largeur connecteur (ConConnectorWidth2_1): 0.005 m; Position connexion en X (ConPosX_1): -0.05 m; Position connexion en Y (ConPosY_1): 0 m; Position connexion en Z (ConPosZ_1): 0.107 m; Profondeur nominale (ConNominalDepth_2): 0.025 m; Diamètre extérieur (ConWidth_2): 0.027 m; Profondeur extérieure (ConDepth_2): 0.027 m; Epaisseur mur (ConWallThickness_2): 0.001 m; Longueur connexion (ConLength_2): 0.02 m; Diamètre connecteur (ConConnectorWidth_2): 0.04 m; Profondeur connecteur (ConConnectorDepth_2): 0 m; Largeur connecteur (ConConnectorWidth2_2): 0.005 m; Position connexion en X (ConPosX_2): 0.05 m; Position connexion en Y (ConPosY_2): 0 m; Position connexion en Z (ConPosZ_2): 0.107 m; Profondeur nominale (ConNominalDepth_3): 0.04 m; Diamètre extérieur (ConWidth_3): 0.042 m; Profondeur extérieure (ConDepth_3): 0.042 m; Epaisseur mur (ConWallThickness_3): 0.001 m; Longueur connexion (ConLength_3): 0.02 m; Diamètre connecteur (ConConnectorWidth_3): 0.042 m; Profondeur connecteur (ConConnectorDepth_3): 0 m; Largeur connecteur (ConConnectorWidth2_3): 0.005 m; Position connexion en X (ConPosX_3): 0 m; Position connexion en Y (ConPosY_3): -0.1519 m; Position connexion en Z (ConPosZ_3): 0 m; Espace minimum devant: 1.1 m; Espace minimum sur côté 1: 0.17 m; Espace minimum sur côté 2: 0.22 m
Name | Numéro de Zone | Angle de rotation (deg) | Motif de hachure | Lavabo | Robinet | Egout = Connexion | Surface de système | Hauteur supérieure (m) = Niveau supérieur (m) | Niveau inférieur (m)
Sanitary | 003 | 0 | Background | Surf-Porcelain | Mtl-Chrome | Mtl-Stainless Steel | Paint-15 | 0.9 | 0.76
Sanitary | 002 | 0 | Background | Surf-Porcelain | Mtl-Chrome | Mtl-Stainless Steel | Paint-15 | 0.9 | 0.76
Sanitary | 002 | 360 | Background Fill-International | 09 / Porcelain Fixture | 05 / Chrome Simple | 05 / Stainless Reflective | 08 / Glass-Tinted Dk | 1 | 0.86

# IfcFurnishingElement: WC 18 (3)
In: Mezzannine
Description: San_01; Material: 50 %
ArchiCADProperties - ID: Sanitary; Etage d'implantation: Mezzannine; Nom de Zone: WC; Calque: A-EQMT; Type: Equipement; Verrouillé: no; Nom Elément de Bibliothèque: WC 18; Matériau de construction / Composite / Profil / Hachure: 50 %; Fonction structurelle: Elément non porteur; Position: Intérieur; Classification d'lément: Mobilier; Etat de rénovation: Existant; Afficher sur filtre de rénovation: Tous les filtres appropriés; Angle de rotation: 90 deg; Surface: GENERAL
AC_Pset_WC_18 - Afficher points chauds 2D en 3D: no; Définir programme: no; Type support: Monté sur mur; Type cuvette support sol: Type 1; Type cuvette support mur: Type 1; Siège (gs_seat): Fermé; Couvercle: yes; Type chasse (strFlushType): Bâti-support; Type réservoir: Type 1; Type réservoir élevé: Type 1; Type bouton bâti-support: Type 2; Type chasse (strFlushometerType): Simple; Position bouton: Face; Afficher bâti-support en 2D: no; Afficher bâti-support en 3D: no; Type effluent: Retour; Connexion d'eau: yes; Type outil (ConToolType_1): 2; Système MEP (ConSystem_1): Non défini; Type de forme (ConType_1): Cercle; Type connexion (ConConnectorType_1): Soudé; Connexion eau résiduaire: yes; Type outil (ConToolType_2): 2; Système MEP (ConSystem_2): Non défini; Type de forme (ConType_2): Cercle; Type connexion (ConConnectorType_2): Soudé; Niveau de détail 3D: Détaillé; Résolution: 32; Ombre: yes; Afficher 3D (Projection 2D): yes; Niveau de détail 2D: Selon échelle; Stylo contour: Technique - Plomberie; Motif de hachure: Background Fill-International; Stylo hachure: Fond - Couleur 1; Stylo fond de hachure: Fond - Couleur 1; Cuvette (gs_bowl_mat): 09 | Porcelain Fixture; Siège (matSeatCover): 06 | P Laminate; Réservoir: 09 | Paint-02 Whitewash; Tuyau de réservoir: 05 | Stainless Reflective; Bouton: 09 | Paint-02 Whitewash; Détecteur: 09 | Paint-08 Black; Tuyau de débimètre: 05 | Stainless Reflective; Connexion: 05 | Stainless Reflective; Nombre connexions: 2; Aire: 0; Volume: 0; Coût: 0; Type de groupe (FM_Type): Sanitaires; Type de groupe (iFMType): 13; Poids de l'objet: 0; Unité poids de l'objet: kg
AC_Pset_RenovationAndPhasing - Renovation Status: Existing
ArchiCADQuantities - Altitude à Zéro du Projet: 9.425 m; Altitude à étage: 0 m; Volume net: 0.0105083 m3; Superficie: 0.196 m2; Hauteur (Taille en Z): 0.33 m; Longueur (A): 0.35 m; Volume: 0.0105083 m3; Largeur (B): 0.56 m
AC_Equantity_WC_18 - 1ère dimension: 0.35 m; 2ème dimension: 0.56 m; Hauteur: 0.33 m; Niveau inférieur: 1 m; Niveau supérieur: 0 m; Hauteur siège: 0.4 m; Largeur cuvette: 0.35 m; Profondeur cuvette: 0.56 m; Hauteur cuvette: 0.33 m; Altitude réservoir: 1.2 m; Diamètre tuyau: 0.03 m; Largeur réservoir: 0.435 m; Profondeur réservoir: 0.095 m; Hauteur réservoir: 0.3 m; Largeur bâti: 0.5 m; Hauteur bâti: 1.2 m; Profondeur bâti: 0.12 m; Hauteur connexion eau: 0.755 m; Profondeur nominale (ConNominalDepth_1): 0.03 m; Diamètre extérieur (ConWidth_1): 0.032 m; Profondeur extérieure (ConDepth_1): 0.032 m; Epaisseur mur (ConWallThickness_1): 0.001 m; Diamètre connecteur (ConConnectorWidth_1): 0.04 m; Profondeur connecteur (ConConnectorDepth_1): 0 m; Largeur connecteur (ConConnectorWidth2_1): 0.005 m; Position connexion en X (ConPosX_1): 0 m; Position connexion en Y (ConPosY_1): 0 m; Position connexion en Z (ConPosZ_1): 0.755 m; Profondeur nominale (ConNominalDepth_2): 0.11 m; Diamètre extérieur (ConWidth_2): 0.114 m; Profondeur extérieure (ConDepth_2): 0.114 m; Epaisseur mur (ConWallThickness_2): 0.002 m; Longueur connexion (ConLength_2): 0.02 m; Diamètre connecteur (ConConnectorWidth_2): 0.13 m; Profondeur connecteur (ConConnectorDepth_2): 0 m; Largeur connecteur (ConConnectorWidth2_2): 0.005 m; Position connexion en X (ConPosX_2): 0 m; Position connexion en Y (ConPosY_2): 0 m; Position connexion en Z (ConPosZ_2): 0.205128 m; Espace minimum devant: 1 m; Espace minimum sur côté 1: 0.3 m; Espace minimum sur côté 2: 0.9 m
Name | Numéro de Zone | Superficie de surface (m2) | Longueur connexion (ConLength_1) (m)
Sanitary | 002 | 1.59571 | 0.02
Sanitary | 002 | 1.59371 | 0
Sanitary | 003 | 1.59571 | 0.02

# IfcMember: Cadre 100 x 300 (296)
Material: 25 % 359672764
ArchiCADProperties - Calque: A-WALL-CURT; Type: Cadre de mur-rideau; Verrouillé: no; Matériau de construction / Composite / Profil / Hachure: 25 % 359672764; Etat de rénovation: Existant; Afficher sur filtre de rénovation: Tous les filtres appropriés; Emplacement :: Cadre; Type de cadre: Générique; Classe de cadre: Cadre; Surface: Mtl-Stainless Steel
AC_Pset_RenovationAndPhasing - Renovation Status: Existing
BaseQuantities - CrossSectionArea: 0.03 m2
ArchiCADQuantities - Superficie de surface: 0.03 m2; Largeur cadre: 0.1 m; Profondeur de cadre: 0.3 m
Name | In | ID | Etage d'implantation | Angle d'inclinaison (deg) | ID mur-rideau | Length (m) = Longueur cadre (m) | OuterSurfaceArea (m2) | TotalSurfaceArea (m2) = GrossSurfaceArea (m2) | GrossVolume (m3) = NetVolume (m3) = Volume net (m3) | Altitude à Zéro du Projet (m) | Altitude à étage (m)
Frame-Bnd-942 | Rez de chaussée | Frame-Bnd-942 | Rez de chaussée | 0 | CurtainWall_02 | 1.5 | 1.2 | 1.26 | 0.045 | 0.1 | 0.1
Frame-Bnd-922 | Rez de chaussée | Frame-Bnd-922 | Rez de chaussée | 0 | CurtainWall_02 | 1.5 | 1.2 | 1.26 | 0.045 | 0.1 | 0.1
Frame-Bnd-941 | Rez de chaussée | Frame-Bnd-941 | Rez de chaussée | 0 | CurtainWall_02 | 1.5 | 1.2 | 1.26 | 0.045 | 0.1 | 0.1
Frame-Bnd-912 | Rez de chaussée | Frame-Bnd-912 | Rez de chaussée | 0 | CurtainWall_02 | 1.5 | 1.2 | 1.26 | 0.045 | 0.1 | 0.1
Frame-Bnd-940 | Rez de chaussée | Frame-Bnd-940 | Rez de chaussée | 0 | CurtainWall_02 | 1.5 | 1.2 | 1.26 | 0.045 | 0.1 | 0.1
Frame-Bnd-921 | Rez de chaussée | Frame-Bnd-921 | Rez de chaussée | 0 | CurtainWall_02 | 1.5 | 1.2 | 1.26 | 0.045 | 0.1 | 0.1
Frame-Bnd-939 | Rez de chaussée | Frame-Bnd-939 | Rez de chaussée | 0 | CurtainWall_02 | 1.5 | 1.2 | 1.26 | 0.045 | 0.1 | 0.1
Frame-Bnd-907 | Rez de chaussée | Frame-Bnd-907 | Rez de chaussée | 0 | CurtainWall_02 | 1.5 | 1.2 | 1.26 | 0.045 | 0.1 | 0.1
Frame-Bnd-938 | Rez de chaussée | Frame-Bnd-938 | Rez de chaussée | 0 | CurtainWall_02 | 1.5 | 1.2 | 1.26 | 0.045 | 0.1 | 0.1
Frame-Bnd-920 | Rez de chaussée | Frame-Bnd-920 | Rez de chaussée | 0 | CurtainWall_02 | 1.5 | 1.2 | 1.26 | 0.045 | 0.1 | 0.1
Frame-Bnd-937 | Rez de chaussée | Frame-Bnd-937 | Rez de chaussée | 0 | CurtainWall_02 | 1.5 | 1.2 | 1.26 | 0.045 | 0.1 | 0.1
Frame-Bnd-911 | Rez de chaussée | Frame-Bnd-911 | Rez de chaussée | 0 | CurtainWall_02 | 1.5 | 1.2 | 1.26 | 0.045 | 0.1 | 0.1
Frame-Bnd-936 | Rez de chaussée | Frame-Bnd-936 | Rez de chaussée | 0 | CurtainWall_02 | 1.5 | 1.2 | 1.26 | 0.045 | 0.1 | 0.1
Frame-Bnd-919 | Rez de chaussée | Frame-Bnd-919 | Rez de chaussée | 0 | CurtainWall_02 | 1.5 | 1.2 | 1.26 | 0.045 | 0.1 | 0.1
Frame-Bnd-935 | Rez de chaussée | Frame-Bnd-935 | Rez de chaussée | 0 | CurtainWall_02 | 1.5 | 1.2 | 1.26 | 0.045 | 0.1 | 0.1
Frame-Bnd-798 | Rez de chaussée | Frame-Bnd-798 | Rez de chaussée | 90 | CurtainWall_02 | 2.65 | 2.12 | 2.18 | 0.0795 | 0.1 | 0.1
Frame-Bnd-934 | Rez de chaussée | Frame-Bnd-934 | Rez de chaussée | 0 | CurtainWall_02 | 1.5 | 1.2 | 1.26 | 0.045 | 0.1 | 0.1
Frame-Bnd-918 | Rez de chaussée | Frame-Bnd-918 | Rez de chaussée | 0 | CurtainWall_02 | 1.5 | 1.2 | 1.26 | 0.045 | 0.1 | 0.1
Frame-Bnd-933 | Rez de chaussée | Frame-Bnd-933 | Rez de chaussée | 0 | CurtainWall_02 | 1.5 | 1.2 | 1.26 | 0.045 | 0.1 | 0.1
Frame-Bnd-910 | Rez de chaussée | Frame-Bnd-910 | Rez de chaussée | 0 | CurtainWall_02 | 1.5 | 1.2 | 1.26 | 0.045 | 0.1 | 0.1
Frame-Bnd-932 | Rez de chaussée | Frame-Bnd-932 | Rez de chaussée | 0 | CurtainWall_02 | 1.5 | 1.2 | 1.26 | 0.045 | 0.1 | 0.1
Frame-Bnd-917 | Rez de chaussée | Frame-Bnd-917 | Rez de chaussée | 0 | CurtainWall_02 | 1.5 | 1.2 | 1.26 | 0.045 | 0.1 | 0.1
Frame-Bnd-931 | Rez de chaussée | Frame-Bnd-931 | Rez de chaussée | 0 | CurtainWall_02 | 1.5 | 1.2 | 1.26 | 0.045 | 0.1 | 0.1
Frame-Bnd-906 | Rez de chaussée | Frame-Bnd-906 | Rez de chaussée | 1.1662e-14 | CurtainWall_02 | 1.5 | 1.2 | 1.26 | 0.045 | 0.1 | 0.1
Frame-Bnd-930 | Rez de chaussée | Frame-Bnd-930 | Rez de chaussée | 0 | CurtainWall_02 | 1.5 | 1.2 | 1.26 | 0.045 | 0.1 | 0.1
Frame-Bnd-916 | Rez de chaussée | Frame-Bnd-916 | Rez de chaussée | 0 | CurtainWall_02 | 1.5 | 1.2 | 1.26 | 0.045 | 0.1 | 0.1
Frame-Bnd-929 | Rez de chaussée | Frame-Bnd-929 | Rez de chaussée | 0 | CurtainWall_02 | 1.5 | 1.2 | 1.26 | 0.045 | 0.1 | 0.1
Frame-Bnd-909 | Rez de chaussée | Frame-Bnd-909 | Rez de chaussée | 0 | CurtainWall_02 | 1.5 | 1.2 | 1.26 | 0.045 | 0.1 | 0.1
Frame-Bnd-928 | Rez de chaussée | Frame-Bnd-928 | Rez de chaussée | 0 | CurtainWall_02 | 1.5 | 1.2 | 1.26 | 0.045 | 0.1 | 0.1
Frame-Bnd-915 | Rez de chaussée | Frame-Bnd-915 | Rez de chaussée | 0 | CurtainWall_02 | 1.5 | 1.2 | 1.26 | 0.045 | 0.1 | 0.1
Frame-Bnd-927 | Rez de chaussée | Frame-Bnd-927 | Rez de chaussée | 0 | CurtainWall_02 | 1.5 | 1.2 | 1.26 | 0.045 | 0.1 | 0.1
Frame-Bnd-499 | Rez de chaussée | Frame-Bnd-499 | Rez de chaussée | 90 | CurtainWall_02 | 2.65 | 2.12 | 2.18 | 0.0795 | 0.1 | 0.1
Frame-Bnd-926 | Rez de chaussée | Frame-Bnd-926 | Rez de chaussée | 0 | CurtainWall_02 | 1.5 | 1.2 | 1.26 | 0.045 | 0.1 | 0.1 | ArchiCADProperties - Nom de Zone: Réserve; Numéro de Zone: 010
Frame-Bnd-914 | Rez de chaussée | Frame-Bnd-914 | Rez de chaussée | 0 | CurtainWall_02 | 1.5 | 1.2 | 1.26 | 0.045 | 0.1 | 0.1
Frame-Bnd-925 | Rez de chaussée | Frame-Bnd-925 | Rez de chaussée | 0 | CurtainWall_02 | 1.5 | 1.2 | 1.26 | 0.045 | 0.1 | 0.1 | ArchiCADProperties - Nom de Zone: Réserve; Numéro de Zone: 010
Frame-Bnd-908 | Rez de chaussée | Frame-Bnd-908 | Rez de chaussée | 0 | CurtainWall_02 | 1.5 | 1.2 | 1.26 | 0.045 | 0.1 | 0.1
Frame-Bnd-924 | Rez de chaussée | Frame-Bnd-924 | Rez de chaussée | 0 | CurtainWall_02 | 1.5 | 1.2 | 1.26 | 0.045 | 0.1 | 0.1 | ArchiCADProperties - Nom de Zone: Réserve; Numéro de Zone: 010
Frame-Bnd-913 | Rez de chaussée | Frame-Bnd-913 | Rez de chaussée | 0 | CurtainWall_02 | 1.5 | 1.2 | 1.26 | 0.045 | 0.1 | 0.1
Frame-Bnd-923 | Rez de chaussée | Frame-Bnd-923 | Rez de chaussée | 0 | CurtainWall_02 | 1.5 | 1.2 | 1.26 | 0.045 | 0.1 | 0.1
Frame-Bnd-943 | Rez de chaussée | Frame-Bnd-943 | Rez de chaussée | 0 | CurtainWall_02 | 1.45 | 1.16 | 1.22 | 0.0435 | 0.1 | 0.1
Frame-Bnd-905 | Rez de chaussée | Frame-Bnd-905 | Rez de chaussée | 0 | CurtainWall_02 | 1.06683 | 0.853462 | 0.913462 | 0.0320048 | 0.1 | 0.1
Frame-Bnd-499 | Rez de chaussée | Frame-Bnd-499 | Rez de chaussée | 90 | CurtainWall_02 | 1.5 | 1.2 | 1.26 | 0.045 | 2.8 | 2.8
Frame-Bnd-558 | Rez de chaussée | Frame-Bnd-558 | Rez de chaussée | 90 | CurtainWall_02 | 1.5 | 1.2 | 1.26 | 0.045 | 2.8 | 2.8
Frame-Bnd-814 | Rez de chaussée | Frame-Bnd-814 | Rez de chaussée | 90 | CurtainWall_02 | 0.05 | 0.04 | 0.1 | 0.0015 | 4.3 | 4.3
Frame-Bnd-813 | Rez de chaussée | Frame-Bnd-813 | Rez de chaussée | 4.77011e-14 | CurtainWall_02 | 1.06683 | 0.853462 | 0.913462 | 0.0320048 | 4.4 | 4.4
Frame-Bnd-812 | Rez de chaussée | Frame-Bnd-812 | Rez de chaussée | 0 | CurtainWall_02 | 1.5 | 1.2 | 1.26 | 0.045 | 4.4 | 4.4
Frame-Bnd-811 | Rez de chaussée | Frame-Bnd-811 | Rez de chaussée | 0 | CurtainWall_02 | 1.5 | 1.2 | 1.26 | 0.045 | 4.4 | 4.4
Frame-Bnd-810 | Rez de chaussée | Frame-Bnd-810 | Rez de chaussée | 0 | CurtainWall_02 | 1.5 | 1.2 | 1.26 | 0.045 | 4.4 | 4.4
Frame-Bnd-809 | Rez de chaussée | Frame-Bnd-809 | Rez de chaussée | 0 | CurtainWall_02 | 1.5 | 1.2 | 1.26 | 0.045 | 4.4 | 4.4
Frame-Bnd-808 | Rez de chaussée | Frame-Bnd-808 | Rez de chaussée | 0 | CurtainWall_02 | 1.5 | 1.2 | 1.26 | 0.045 | 4.4 | 4.4
Frame-Bnd-807 | Rez de chaussée | Frame-Bnd-807 | Rez de chaussée | 0 | CurtainWall_02 | 1.5 | 1.2 | 1.26 | 0.045 | 4.4 | 4.4
Frame-Bnd-806 | Rez de chaussée | Frame-Bnd-806 | Rez de chaussée | 0 | CurtainWall_02 | 1.5 | 1.2 | 1.26 | 0.045 | 4.4 | 4.4
Frame-Bnd-805 | Rez de chaussée | Frame-Bnd-805 | Rez de chaussée | 0 | CurtainWall_02 | 1.5 | 1.2 | 1.26 | 0.045 | 4.4 | 4.4
Frame-Bnd-804 | Rez de chaussée | Frame-Bnd-804 | Rez de chaussée | 0 | CurtainWall_02 | 1.5 | 1.2 | 1.26 | 0.045 | 4.4 | 4.4
Frame-Bnd-803 | Rez de chaussée | Frame-Bnd-803 | Rez de chaussée | 0 | CurtainWall_02 | 1.5 | 1.2 | 1.26 | 0.045 | 4.4 | 4.4
Frame-Bnd-802 | Rez de chaussée | Frame-Bnd-802 | Rez de chaussée | 0 | CurtainWall_02 | 1.5 | 1.2 | 1.26 | 0.045 | 4.4 | 4.4
Frame-Bnd-801 | Rez de chaussée | Frame-Bnd-801 | Rez de chaussée | 0 | CurtainWall_02 | 1.5 | 1.2 | 1.26 | 0.045 | 4.4 | 4.4
Frame-Bnd-800 | Rez de chaussée | Frame-Bnd-800 | Rez de chaussée | 0 | CurtainWall_02 | 1.5 | 1.2 | 1.26 | 0.045 | 4.4 | 4.4
Frame-Bnd-799 | Rez de chaussée | Frame-Bnd-799 | Rez de chaussée | 0 | CurtainWall_02 | 1.5 | 1.2 | 1.26 | 0.045 | 4.4 | 4.4
Frame-Bnd-798 | Rez de chaussée | Frame-Bnd-798 | Rez de chaussée | 0 | CurtainWall_02 | 1.5 | 1.2 | 1.26 | 0.045 | 4.4 | 4.4
Frame-Bnd-797 | Rez de chaussée | Frame-Bnd-797 | Rez de chaussée | 0 | CurtainWall_02 | 1.5 | 1.2 | 1.26 | 0.045 | 4.4 | 4.4
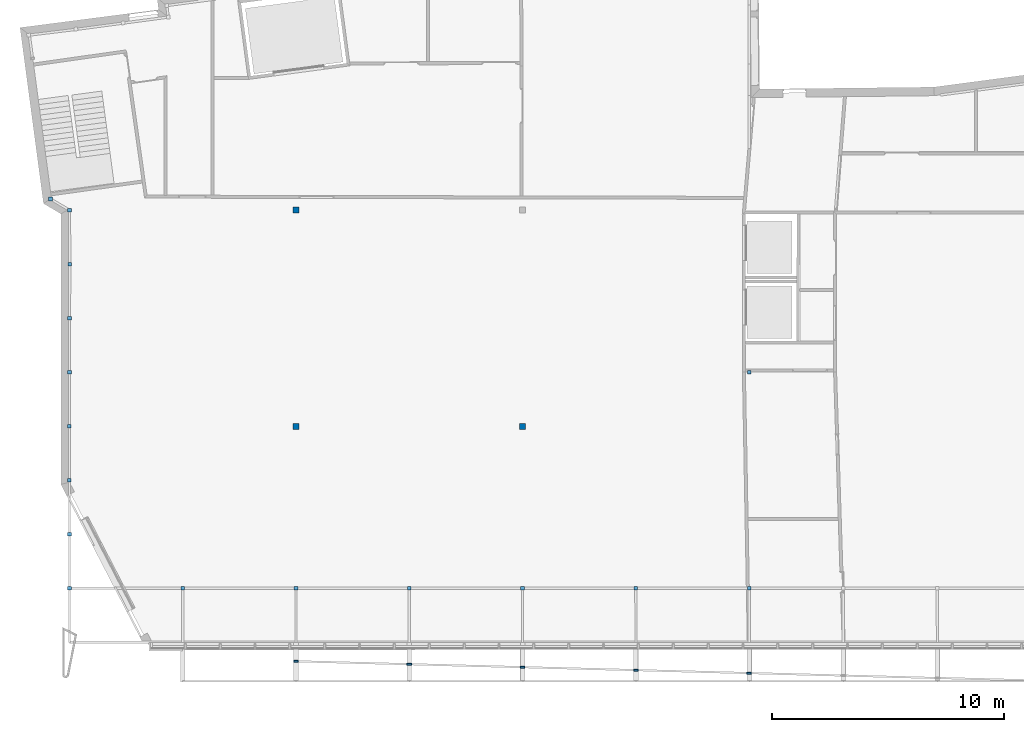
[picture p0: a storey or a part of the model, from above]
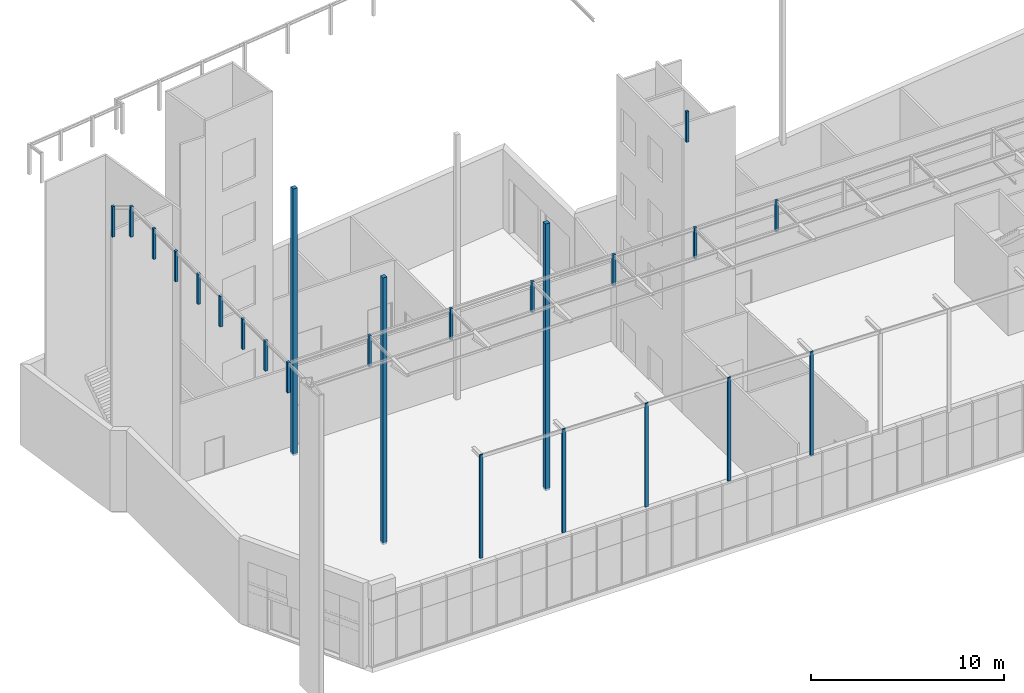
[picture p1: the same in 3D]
Properties of the parts of a building model (IFC2X3), part 10 of 19

# IfcMember: Cadre 100 x 300 (296)
Name | In | ID | Etage d'implantation | Angle d'inclinaison (deg) | ID mur-rideau | Length (m) = Longueur cadre (m) | OuterSurfaceArea (m2) | TotalSurfaceArea (m2) = GrossSurfaceArea (m2) | GrossVolume (m3) = NetVolume (m3) = Volume net (m3) | Altitude à Zéro du Projet (m) | Altitude à étage (m)
Frame-Bnd-796 | Rez de chaussée | Frame-Bnd-796 | Rez de chaussée | 0 | CurtainWall_02 | 1.5 | 1.2 | 1.26 | 0.045 | 4.4 | 4.4
Frame-Bnd-795 | Rez de chaussée | Frame-Bnd-795 | Rez de chaussée | 0 | CurtainWall_02 | 1.5 | 1.2 | 1.26 | 0.045 | 4.4 | 4.4
Frame-Bnd-794 | Rez de chaussée | Frame-Bnd-794 | Rez de chaussée | 0 | CurtainWall_02 | 1.5 | 1.2 | 1.26 | 0.045 | 4.4 | 4.4 | ArchiCADProperties - Nom de Zone: Réserve; Numéro de Zone: 010
Frame-Bnd-793 | Rez de chaussée | Frame-Bnd-793 | Rez de chaussée | 0 | CurtainWall_02 | 1.5 | 1.2 | 1.26 | 0.045 | 4.4 | 4.4 | ArchiCADProperties - Nom de Zone: Réserve; Numéro de Zone: 010
Frame-Bnd-792 | Rez de chaussée | Frame-Bnd-792 | Rez de chaussée | 0 | CurtainWall_02 | 1.5 | 1.2 | 1.26 | 0.045 | 4.4 | 4.4 | ArchiCADProperties - Nom de Zone: Réserve; Numéro de Zone: 010
Frame-Bnd-791 | Rez de chaussée | Frame-Bnd-791 | Rez de chaussée | 0 | CurtainWall_02 | 1.5 | 1.2 | 1.26 | 0.045 | 4.4 | 4.4
Frame-Bnd-790 | Rez de chaussée | Frame-Bnd-790 | Rez de chaussée | 0 | CurtainWall_02 | 1.5 | 1.2 | 1.26 | 0.045 | 4.4 | 4.4
Frame-Bnd-789 | Rez de chaussée | Frame-Bnd-789 | Rez de chaussée | 0 | CurtainWall_02 | 1.5 | 1.2 | 1.26 | 0.045 | 4.4 | 4.4
Frame-Bnd-788 | Rez de chaussée | Frame-Bnd-788 | Rez de chaussée | 0 | CurtainWall_02 | 1.5 | 1.2 | 1.26 | 0.045 | 4.4 | 4.4
Frame-Bnd-787 | Rez de chaussée | Frame-Bnd-787 | Rez de chaussée | 0 | CurtainWall_02 | 1.5 | 1.2 | 1.26 | 0.045 | 4.4 | 4.4
Frame-Bnd-786 | Rez de chaussée | Frame-Bnd-786 | Rez de chaussée | 0 | CurtainWall_02 | 1.5 | 1.2 | 1.26 | 0.045 | 4.4 | 4.4
Frame-Bnd-785 | Rez de chaussée | Frame-Bnd-785 | Rez de chaussée | 0 | CurtainWall_02 | 1.5 | 1.2 | 1.26 | 0.045 | 4.4 | 4.4
Frame-Bnd-784 | Rez de chaussée | Frame-Bnd-784 | Rez de chaussée | 0 | CurtainWall_02 | 1.5 | 1.2 | 1.26 | 0.045 | 4.4 | 4.4
Frame-Bnd-783 | Rez de chaussée | Frame-Bnd-783 | Rez de chaussée | 0 | CurtainWall_02 | 1.5 | 1.2 | 1.26 | 0.045 | 4.4 | 4.4
Frame-Bnd-782 | Rez de chaussée | Frame-Bnd-782 | Rez de chaussée | 0 | CurtainWall_02 | 1.5 | 1.2 | 1.26 | 0.045 | 4.4 | 4.4
Frame-Bnd-781 | Rez de chaussée | Frame-Bnd-781 | Rez de chaussée | 0 | CurtainWall_02 | 1.5 | 1.2 | 1.26 | 0.045 | 4.4 | 4.4
Frame-Bnd-780 | Rez de chaussée | Frame-Bnd-780 | Rez de chaussée | 0 | CurtainWall_02 | 1.5 | 1.2 | 1.26 | 0.045 | 4.4 | 4.4
Frame-Bnd-779 | Rez de chaussée | Frame-Bnd-779 | Rez de chaussée | 0 | CurtainWall_02 | 1.5 | 1.2 | 1.26 | 0.045 | 4.4 | 4.4
Frame-Bnd-778 | Rez de chaussée | Frame-Bnd-778 | Rez de chaussée | 0 | CurtainWall_02 | 1.5 | 1.2 | 1.26 | 0.045 | 4.4 | 4.4
Frame-Bnd-777 | Rez de chaussée | Frame-Bnd-777 | Rez de chaussée | 0 | CurtainWall_02 | 1.5 | 1.2 | 1.26 | 0.045 | 4.4 | 4.4
Frame-Bnd-776 | Rez de chaussée | Frame-Bnd-776 | Rez de chaussée | 0 | CurtainWall_02 | 1.5 | 1.2 | 1.26 | 0.045 | 4.4 | 4.4
Frame-Bnd-775 | Rez de chaussée | Frame-Bnd-775 | Rez de chaussée | 0 | CurtainWall_02 | 1.45 | 1.16 | 1.22 | 0.0435 | 4.4 | 4.4
Frame-Bnd-774 | Rez de chaussée | Frame-Bnd-774 | Rez de chaussée | 90 | CurtainWall_02 | 0.05 | 0.04 | 0.1 | 0.0015 | 4.3 | 4.3
Frame-Bnd-802 | R+1 | Frame-Bnd-802 | R+1 | 90 | CurtainWall_01 | 1.45 | 1.16 | 1.22 | 0.0435 | 4.85 | -0.55
Frame-Bnd-802 | R+1 | Frame-Bnd-802 | R+1 | 90 | CurtainWall_01 | 1.5 | 1.2 | 1.26 | 0.045 | 6.35 | 0.95
Frame-Bnd-802 | R+1 | Frame-Bnd-802 | R+1 | 90 | CurtainWall_01 | 1.5 | 1.2 | 1.26 | 0.045 | 7.85 | 2.45
Frame-Bnd-802 | R+1 | Frame-Bnd-802 | R+1 | 90 | CurtainWall_01 | 1.5 | 1.2 | 1.26 | 0.045 | 9.35 | 3.95
Frame-Bnd-802 | R+1 | Frame-Bnd-802 | R+1 | 0 | CurtainWall_01 | 0.55475 | 0.4438 | 0.5038 | 0.0166425 | 4.85 | -0.55
Frame-Bnd-802 | R+1 | Frame-Bnd-802 | R+1 | 90 | CurtainWall_01 | 1.22483 | 0.979862 | 1.03986 | 0.0367448 | 10.85 | 5.45
Frame-Bnd-880 | R+1 | Frame-Bnd-880 | R+1 | 0 | CurtainWall_01 | 0.55475 | 0.4438 | 0.5038 | 0.0166425 | 12.1248 | 6.72483
Frame-Bnd-934 | R+1 | Frame-Bnd-934 | R+1 | 0 | CurtainWall_01 | 2.95 | 2.36 | 2.42 | 0.0885 | 17.4 | 12
Frame-Bnd-727 | R+1 | Frame-Bnd-727 | R+1 | 90 | CurtainWall_01 | 0.45 | 0.36 | 0.42 | 0.0135 | 16.9 | 11.5
Frame-Bnd-677 | R+1 | Frame-Bnd-677 | R+1 | 90 | CurtainWall_01 | 0.95 | 0.76 | 0.82 | 0.0285 | 5.4 | 7.16094e-15
Frame-Bnd-835 | R+1 | Frame-Bnd-835 | R+1 | 0 | CurtainWall_01 | 2.95 | 2.36 | 2.42 | 0.0885 | 5.4 | -6.83897e-14
Frame-Bnd-833 | R+1 | Frame-Bnd-833 | R+1 | 0 | CurtainWall_01 | 1.20011 | 0.960085 | 1.02009 | 0.0360032 | 5.4 | -6.83897e-14
Frame-Bnd-635 | R+1 | Frame-Bnd-635 | R+1 | 90 | CurtainWall_01 | 1.5 | 1.2 | 1.26 | 0.045 | 7.9 | 2.5
Frame-Bnd-633 | R+1 | Frame-Bnd-633 | R+1 | 90 | CurtainWall_01 | 0.95 | 0.76 | 0.82 | 0.0285 | 5.4 | -6.83897e-14
Frame-Bnd-985 | R+1 | Frame-Bnd-985 | R+1 | 0.00000181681 | CurtainWall_01 | 2.9002 | 2.32016 | 2.38016 | 0.087006 | 17.4 | 12
Frame-Bnd-675 | R+1 | Frame-Bnd-675 | R+1 | 90 | CurtainWall_01 | 1.5 | 1.2 | 1.26 | 0.045 | 7.9 | 2.5
Frame-Bnd-676 | R+1 | Frame-Bnd-676 | R+1 | 90 | CurtainWall_01 | 1.5 | 1.2 | 1.26 | 0.045 | 6.4 | 1
Frame-Bnd-890 | R+1 | Frame-Bnd-890 | R+1 | 0 | CurtainWall_01 | 2.325 | 1.86 | 1.92 | 0.06975 | 5.4 | 7.16094e-15
Frame-Bnd-834 | R+1 | Frame-Bnd-834 | R+1 | 0 | CurtainWall_01 | 3 | 2.4 | 2.46 | 0.09 | 5.4 | -6.83897e-14
Frame-Bnd-722 | R+1 | Frame-Bnd-722 | R+1 | 90 | CurtainWall_01 | 1.5 | 1.2 | 1.26 | 0.045 | 9.4 | 4
Frame-Bnd-723 | R+1 | Frame-Bnd-723 | R+1 | 90 | CurtainWall_01 | 1.5 | 1.2 | 1.26 | 0.045 | 10.9 | 5.5
Frame-Bnd-724 | R+1 | Frame-Bnd-724 | R+1 | 90 | CurtainWall_01 | 1.5 | 1.2 | 1.26 | 0.045 | 12.4 | 7
Frame-Bnd-725 | R+1 | Frame-Bnd-725 | R+1 | 90 | CurtainWall_01 | 1.5 | 1.2 | 1.26 | 0.045 | 13.9 | 8.5
Frame-Bnd-726 | R+1 | Frame-Bnd-726 | R+1 | 90 | CurtainWall_01 | 1.5 | 1.2 | 1.26 | 0.045 | 15.4 | 10
Frame-Bnd-936 | R+1 | Frame-Bnd-936 | R+1 | 0.00000419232 | CurtainWall_01 | 1.20011 | 0.960085 | 1.02009 | 0.0360032 | 17.4 | 12
Frame-Bnd-634 | R+1 | Frame-Bnd-634 | R+1 | 90 | CurtainWall_01 | 1.5 | 1.2 | 1.26 | 0.045 | 6.4 | 1
Frame-Bnd-935 | R+1 | Frame-Bnd-935 | R+1 | 0 | CurtainWall_01 | 3 | 2.4 | 2.46 | 0.09 | 17.4 | 12
Frame-Bnd-986 | R+1 | Frame-Bnd-986 | R+1 | 0 | CurtainWall_01 | 2.325 | 1.86 | 1.92 | 0.06975 | 17.4 | 12
Frame-Bnd-891 | R+1 | Frame-Bnd-891 | R+1 | 0 | CurtainWall_01 | 2.9002 | 2.32016 | 2.38016 | 0.087006 | 5.4 | 7.16094e-15
Frame-Bnd-987 | R+1 | Frame-Bnd-987 | R+1 | 90 | CurtainWall_01 | 0.45 | 0.36 | 0.42 | 0.0135 | 16.9 | 11.5
Frame-Bnd-777 | R+1 | Frame-Bnd-777 | R+1 | 90 | CurtainWall_01 | 1.5 | 1.2 | 1.26 | 0.045 | 15.4 | 10
Frame-Bnd-778 | R+1 | Frame-Bnd-778 | R+1 | 90 | CurtainWall_01 | 1.5 | 1.2 | 1.26 | 0.045 | 13.9 | 8.5
Frame-Bnd-779 | R+1 | Frame-Bnd-779 | R+1 | 90 | CurtainWall_01 | 1.5 | 1.2 | 1.26 | 0.045 | 12.4 | 7
Frame-Bnd-780 | R+1 | Frame-Bnd-780 | R+1 | 90 | CurtainWall_01 | 1.5 | 1.2 | 1.26 | 0.045 | 10.9 | 5.5
Frame-Bnd-781 | R+1 | Frame-Bnd-781 | R+1 | 90 | CurtainWall_01 | 1.5 | 1.2 | 1.26 | 0.045 | 9.4 | 4
Frame-Bnd-565 | R+1 | Frame-Bnd-565 | R+1 | 90 | CurtainWall_01 | 1.5 | 1.2 | 1.26 | 0.045 | 9.35 | 3.95
Frame-Bnd-565 | R+1 | Frame-Bnd-565 | R+1 | 90 | CurtainWall_01 | 1.5 | 1.2 | 1.26 | 0.045 | 7.85 | 2.45
Frame-Bnd-565 | R+1 | Frame-Bnd-565 | R+1 | 90 | CurtainWall_01 | 1.5 | 1.2 | 1.26 | 0.045 | 6.35 | 0.95
Frame-Bnd-565 | R+1 | Frame-Bnd-565 | R+1 | 90 | CurtainWall_01 | 1.45 | 1.16 | 1.22 | 0.0435 | 4.85 | -0.55
Frame-Bnd-565 | R+1 | Frame-Bnd-565 | R+1 | 0 | CurtainWall_01 | 1.85138 | 1.48111 | 1.54111 | 0.0555415 | 4.85 | -0.55
Frame-Bnd-623 | R+1 | Frame-Bnd-623 | R+1 | 90 | CurtainWall_01 | 1.225 | 0.98 | 1.04 | 0.03675 | 10.85 | 5.45
Frame-Bnd-666 | R+1 | Frame-Bnd-666 | R+1 | 0 | CurtainWall_01 | 1.85138 | 1.48111 | 1.54111 | 0.0555415 | 12.125 | 6.725
Frame-Bnd-212 | R+1 | Frame-Bnd-212 | R+1 | 0 | CurtainWall_01 | 2.95 | 2.36 | 2.42 | 0.0885 | 5.4 | 0
Frame-Bnd-242 | R+1 | Frame-Bnd-242 | R+1 | 90 | CurtainWall_01 | 1.45 | 1.16 | 1.22 | 0.0435 | 5.4 | 0
Frame-Bnd-213 | R+1 | Frame-Bnd-213 | R+1 | 0 | CurtainWall_01 | 3 | 2.4 | 2.46 | 0.09 | 5.4 | 0
Frame-Bnd-243 | R+1 | Frame-Bnd-243 | R+1 | 90 | CurtainWall_01 | 1.5 | 1.2 | 1.26 | 0.045 | 6.9 | 1.5
Frame-Bnd-244 | R+1 | Frame-Bnd-244 | R+1 | 90 | CurtainWall_01 | 1.5 | 1.2 | 1.26 | 0.045 | 8.4 | 3
Frame-Bnd-245 | R+1 | Frame-Bnd-245 | R+1 | 90 | CurtainWall_01 | 1.5 | 1.2 | 1.26 | 0.045 | 9.9 | 4.5
Frame-Bnd-246 | R+1 | Frame-Bnd-246 | R+1 | 90 | CurtainWall_01 | 1.5 | 1.2 | 1.26 | 0.045 | 11.4 | 6
Frame-Bnd-247 | R+1 | Frame-Bnd-247 | R+1 | 90 | CurtainWall_01 | 1.5 | 1.2 | 1.26 | 0.045 | 12.9 | 7.5
Frame-Bnd-248 | R+1 | Frame-Bnd-248 | R+1 | 90 | CurtainWall_01 | 1.5 | 1.2 | 1.26 | 0.045 | 14.4 | 9
Frame-Bnd-249 | R+1 | Frame-Bnd-249 | R+1 | 90 | CurtainWall_01 | 1.45 | 1.16 | 1.22 | 0.0435 | 15.9 | 10.5
Frame-Bnd-270 | R+1 | Frame-Bnd-270 | R+1 | 0 | CurtainWall_01 | 2.95 | 2.36 | 2.42 | 0.0885 | 17.4 | 12
Frame-Bnd-270 | R+1 | Frame-Bnd-270 | R+1 | 0 | CurtainWall_01 | 3 | 2.4 | 2.46 | 0.09 | 17.4 | 12
Frame-Bnd-270 | R+1 | Frame-Bnd-270 | R+1 | 0 | CurtainWall_01 | 1.15529 | 0.924232 | 0.984232 | 0.0346587 | 17.4 | 12
Frame-Bnd-261 | R+1 | Frame-Bnd-261 | R+1 | 90 | CurtainWall_01 | 1.45 | 1.16 | 1.22 | 0.0435 | 15.9 | 10.5
Frame-Bnd-262 | R+1 | Frame-Bnd-262 | R+1 | 90 | CurtainWall_01 | 1.5 | 1.2 | 1.26 | 0.045 | 14.4 | 9
Frame-Bnd-263 | R+1 | Frame-Bnd-263 | R+1 | 90 | CurtainWall_01 | 1.5 | 1.2 | 1.26 | 0.045 | 12.9 | 7.5
Frame-Bnd-264 | R+1 | Frame-Bnd-264 | R+1 | 90 | CurtainWall_01 | 1.5 | 1.2 | 1.26 | 0.045 | 11.4 | 6
Frame-Bnd-265 | R+1 | Frame-Bnd-265 | R+1 | 90 | CurtainWall_01 | 1.5 | 1.2 | 1.26 | 0.045 | 9.9 | 4.5
Frame-Bnd-266 | R+1 | Frame-Bnd-266 | R+1 | 90 | CurtainWall_01 | 1.5 | 1.2 | 1.26 | 0.045 | 8.4 | 3
Frame-Bnd-267 | R+1 | Frame-Bnd-267 | R+1 | 90 | CurtainWall_01 | 1.5 | 1.2 | 1.26 | 0.045 | 6.9 | 1.5
Frame-Bnd-268 | R+1 | Frame-Bnd-268 | R+1 | 90 | CurtainWall_01 | 1.45 | 1.16 | 1.22 | 0.0435 | 5.4 | 0
Frame-Bnd-269 | R+1 | Frame-Bnd-269 | R+1 | 0 | CurtainWall_01 | 1.15529 | 0.924232 | 0.984232 | 0.0346587 | 5.4 | 0
Frame-Bnd-716 | R+1 | Frame-Bnd-716 | R+1 | 0 | CurtainWall_01 | 2.95 | 2.36 | 2.42 | 0.0885 | 4.4 | -1
Frame-Bnd-716 | R+1 | Frame-Bnd-716 | R+1 | 90 | CurtainWall_01 | 1.45 | 1.16 | 1.22 | 0.0435 | 4.4 | -1
2 x Frame-Bnd-716 | R+1 | Frame-Bnd-716 | R+1 | 0 | CurtainWall_01 | 3 | 2.4 | 2.46 | 0.09 | 4.4 | -1
Frame-Bnd-716 | R+1 | Frame-Bnd-716 | R+1 | 90 | CurtainWall_01 | 1.5 | 1.2 | 1.26 | 0.045 | 5.9 | 0.5
Frame-Bnd-716 | R+1 | Frame-Bnd-716 | R+1 | 90 | CurtainWall_01 | 1.5 | 1.2 | 1.26 | 0.045 | 7.4 | 2
Frame-Bnd-716 | R+1 | Frame-Bnd-716 | R+1 | 90 | CurtainWall_01 | 1.5 | 1.2 | 1.26 | 0.045 | 8.9 | 3.5
Frame-Bnd-716 | R+1 | Frame-Bnd-716 | R+1 | 90 | CurtainWall_01 | 1.5 | 1.2 | 1.26 | 0.045 | 10.4 | 5
Frame-Bnd-716 | R+1 | Frame-Bnd-716 | R+1 | 90 | CurtainWall_01 | 1.5 | 1.2 | 1.26 | 0.045 | 11.9 | 6.5
Frame-Bnd-716 | R+1 | Frame-Bnd-716 | R+1 | 90 | CurtainWall_01 | 1.5 | 1.2 | 1.26 | 0.045 | 13.4 | 8
Frame-Bnd-716 | R+1 | Frame-Bnd-716 | R+1 | 90 | CurtainWall_01 | 1.5 | 1.2 | 1.26 | 0.045 | 14.9 | 9.5
Frame-Bnd-830 | R+1 | Frame-Bnd-830 | R+1 | 0 | CurtainWall_01 | 0.332419 | 0.265935 | 0.325935 | 0.00997257 | 4.4 | -1
Frame-Bnd-824 | R+1 | Frame-Bnd-824 | R+1 | 90 | CurtainWall_01 | 1.5 | 1.2 | 1.26 | 0.045 | 11.9 | 6.5
Frame-Bnd-828 | R+1 | Frame-Bnd-828 | R+1 | 90 | CurtainWall_01 | 1.5 | 1.2 | 1.26 | 0.045 | 5.9 | 0.5
Frame-Bnd-826 | R+1 | Frame-Bnd-826 | R+1 | 90 | CurtainWall_01 | 1.5 | 1.2 | 1.26 | 0.045 | 8.9 | 3.5
Frame-Bnd-822 | R+1 | Frame-Bnd-822 | R+1 | 90 | CurtainWall_01 | 1.5 | 1.2 | 1.26 | 0.045 | 14.9 | 9.5
Frame-Bnd-866 | R+1 | Frame-Bnd-866 | R+1 | 0 | CurtainWall_01 | 2.95 | 2.36 | 2.42 | 0.0885 | 17.4 | 12
Frame-Bnd-825 | R+1 | Frame-Bnd-825 | R+1 | 90 | CurtainWall_01 | 1.5 | 1.2 | 1.26 | 0.045 | 10.4 | 5
Frame-Bnd-867 | R+1 | Frame-Bnd-867 | R+1 | 0 | CurtainWall_01 | 3 | 2.4 | 2.46 | 0.09 | 17.4 | 12
Frame-Bnd-869 | R+1 | Frame-Bnd-869 | R+1 | 0 | CurtainWall_01 | 0.332419 | 0.265935 | 0.325935 | 0.00997257 | 17.4 | 12
Frame-Bnd-868 | R+1 | Frame-Bnd-868 | R+1 | 0 | CurtainWall_01 | 3 | 2.4 | 2.46 | 0.09 | 17.4 | 12
Frame-Bnd-829 | R+1 | Frame-Bnd-829 | R+1 | 90 | CurtainWall_01 | 1.45 | 1.16 | 1.22 | 0.0435 | 4.4 | -1
Frame-Bnd-870 | R+1 | Frame-Bnd-870 | R+1 | 90 | CurtainWall_01 | 0.95 | 0.76 | 0.82 | 0.0285 | 16.4 | 11
Frame-Bnd-823 | R+1 | Frame-Bnd-823 | R+1 | 90 | CurtainWall_01 | 1.5 | 1.2 | 1.26 | 0.045 | 13.4 | 8
Frame-Bnd-827 | R+1 | Frame-Bnd-827 | R+1 | 90 | CurtainWall_01 | 1.5 | 1.2 | 1.26 | 0.045 | 7.4 | 2
Frame-Bnd-865 | R+1 | Frame-Bnd-865 | R+1 | 90 | CurtainWall_01 | 0.95 | 0.76 | 0.82 | 0.0285 | 16.4 | 11
Frame-Bnd-832 | R+1 | Frame-Bnd-832 | R+1 | 0 | CurtainWall_01 | 2.95 | 2.36 | 2.42 | 0.0885 | 4.4 | -1
2 x Frame-Bnd-832 | R+1 | Frame-Bnd-832 | R+1 | 90 | CurtainWall_01 | 1.45 | 1.16 | 1.22 | 0.0435 | 4.4 | -1
2 x Frame-Bnd-832 | R+1 | Frame-Bnd-832 | R+1 | 0 | CurtainWall_01 | 3 | 2.4 | 2.46 | 0.09 | 4.4 | -1
2 x Frame-Bnd-832 | R+1 | Frame-Bnd-832 | R+1 | 90 | CurtainWall_01 | 1.5 | 1.2 | 1.26 | 0.045 | 5.9 | 0.5
2 x Frame-Bnd-832 | R+1 | Frame-Bnd-832 | R+1 | 90 | CurtainWall_01 | 1.5 | 1.2 | 1.26 | 0.045 | 7.4 | 2
2 x Frame-Bnd-832 | R+1 | Frame-Bnd-832 | R+1 | 90 | CurtainWall_01 | 1.5 | 1.2 | 1.26 | 0.045 | 8.9 | 3.5
Frame-Bnd-832 | R+1 | Frame-Bnd-832 | R+1 | 90 | CurtainWall_01 | 1.5 | 1.2 | 1.26 | 0.045 | 10.4 | 5 | ArchiCADProperties - Nom de Zone: Plateau bureaux; Numéro de Zone: 005
Frame-Bnd-832 | R+1 | Frame-Bnd-832 | R+1 | 90 | CurtainWall_01 | 1.5 | 1.2 | 1.26 | 0.045 | 11.9 | 6.5 | ArchiCADProperties - Nom de Zone: Plateau bureaux; Numéro de Zone: 005
Frame-Bnd-832 | R+1 | Frame-Bnd-832 | R+1 | 90 | CurtainWall_01 | 1.5 | 1.2 | 1.26 | 0.045 | 13.4 | 8 | ArchiCADProperties - Nom de Zone: Plateau bureaux; Numéro de Zone: 005
Frame-Bnd-832 | R+1 | Frame-Bnd-832 | R+1 | 90 | CurtainWall_01 | 1.5 | 1.2 | 1.26 | 0.045 | 14.9 | 9.5 | ArchiCADProperties - Nom de Zone: Plateau bureaux; Numéro de Zone: 005
Frame-Bnd-832 | R+1 | Frame-Bnd-832 | R+1 | 90 | CurtainWall_01 | 1.5 | 1.2 | 1.26 | 0.045 | 14.9 | 9.5
Frame-Bnd-832 | R+1 | Frame-Bnd-832 | R+1 | 90 | CurtainWall_01 | 1.5 | 1.2 | 1.26 | 0.045 | 13.4 | 8
Frame-Bnd-832 | R+1 | Frame-Bnd-832 | R+1 | 90 | CurtainWall_01 | 1.5 | 1.2 | 1.26 | 0.045 | 11.9 | 6.5
Frame-Bnd-832 | R+1 | Frame-Bnd-832 | R+1 | 90 | CurtainWall_01 | 1.5 | 1.2 | 1.26 | 0.045 | 10.4 | 5
Frame-Bnd-832 | R+1 | Frame-Bnd-832 | R+1 | 0 | CurtainWall_01 | 2.48265 | 1.98612 | 2.04612 | 0.0744795 | 4.4 | -1
Frame-Bnd-903 | R+1 | Frame-Bnd-903 | R+1 | 90 | CurtainWall_01 | 0.95 | 0.76 | 0.82 | 0.0285 | 16.4 | 11 | ArchiCADProperties - Nom de Zone: Plateau bureaux; Numéro de Zone: 005
Frame-Bnd-904 | R+1 | Frame-Bnd-904 | R+1 | 0 | CurtainWall_01 | 2.95 | 2.36 | 2.42 | 0.0885 | 17.4 | 12 | ArchiCADProperties - Nom de Zone: Plateau bureaux; Numéro de Zone: 005
Frame-Bnd-905 | R+1 | Frame-Bnd-905 | R+1 | 0 | CurtainWall_01 | 3 | 2.4 | 2.46 | 0.09 | 17.4 | 12 | ArchiCADProperties - Nom de Zone: Plateau bureaux; Numéro de Zone: 005
Frame-Bnd-906 | R+1 | Frame-Bnd-906 | R+1 | 0 | CurtainWall_01 | 3 | 2.4 | 2.46 | 0.09 | 17.4 | 12 | ArchiCADProperties - Nom de Zone: Plateau bureaux; Numéro de Zone: 005
Frame-Bnd-907 | R+1 | Frame-Bnd-907 | R+1 | 0 | CurtainWall_01 | 2.48265 | 1.98612 | 2.04612 | 0.0744795 | 17.4 | 12 | ArchiCADProperties - Nom de Zone: Plateau bureaux; Numéro de Zone: 005
Frame-Bnd-908 | R+1 | Frame-Bnd-908 | R+1 | 90 | CurtainWall_01 | 0.95 | 0.76 | 0.82 | 0.0285 | 16.4 | 11
Frame-Bnd-120 | R+1 | Frame-Bnd-120 | R+1 | 0 | CurtainWall_01 | 2.95 | 2.36 | 2.42 | 0.0885 | 5.4 | 0
Frame-Bnd-150 | R+1 | Frame-Bnd-150 | R+1 | 90 | CurtainWall_01 | 1.45 | 1.16 | 1.22 | 0.0435 | 5.4 | 0
Frame-Bnd-121 | R+1 | Frame-Bnd-121 | R+1 | 0 | CurtainWall_01 | 3 | 2.4 | 2.46 | 0.09 | 5.4 | 0
Frame-Bnd-151 | R+1 | Frame-Bnd-151 | R+1 | 90 | CurtainWall_01 | 1.5 | 1.2 | 1.26 | 0.045 | 6.9 | 1.5
Frame-Bnd-152 | R+1 | Frame-Bnd-152 | R+1 | 90 | CurtainWall_01 | 1.5 | 1.2 | 1.26 | 0.045 | 8.4 | 3
Frame-Bnd-153 | R+1 | Frame-Bnd-153 | R+1 | 90 | CurtainWall_01 | 1.5 | 1.2 | 1.26 | 0.045 | 9.9 | 4.5
Frame-Bnd-154 | R+1 | Frame-Bnd-154 | R+1 | 90 | CurtainWall_01 | 1.5 | 1.2 | 1.26 | 0.045 | 11.4 | 6
Frame-Bnd-155 | R+1 | Frame-Bnd-155 | R+1 | 90 | CurtainWall_01 | 1.5 | 1.2 | 1.26 | 0.045 | 12.9 | 7.5
Frame-Bnd-156 | R+1 | Frame-Bnd-156 | R+1 | 90 | CurtainWall_01 | 1.5 | 1.2 | 1.26 | 0.045 | 14.4 | 9
Frame-Bnd-157 | R+1 | Frame-Bnd-157 | R+1 | 90 | CurtainWall_01 | 1.45 | 1.16 | 1.22 | 0.0435 | 15.9 | 10.5
Frame-Bnd-178 | R+1 | Frame-Bnd-178 | R+1 | 0 | CurtainWall_01 | 2.95 | 2.36 | 2.42 | 0.0885 | 17.4 | 12
Frame-Bnd-178 | R+1 | Frame-Bnd-178 | R+1 | 0 | CurtainWall_01 | 3 | 2.4 | 2.46 | 0.09 | 17.4 | 12
Frame-Bnd-178 | R+1 | Frame-Bnd-178 | R+1 | 0 | CurtainWall_01 | 2.05 | 1.64 | 1.7 | 0.0615 | 17.4 | 12
Frame-Bnd-169 | R+1 | Frame-Bnd-169 | R+1 | 90 | CurtainWall_01 | 1.45 | 1.16 | 1.22 | 0.0435 | 15.9 | 10.5
Frame-Bnd-170 | R+1 | Frame-Bnd-170 | R+1 | 90 | CurtainWall_01 | 1.5 | 1.2 | 1.26 | 0.045 | 14.4 | 9
Frame-Bnd-171 | R+1 | Frame-Bnd-171 | R+1 | 90 | CurtainWall_01 | 1.5 | 1.2 | 1.26 | 0.045 | 12.9 | 7.5
Frame-Bnd-172 | R+1 | Frame-Bnd-172 | R+1 | 90 | CurtainWall_01 | 1.5 | 1.2 | 1.26 | 0.045 | 11.4 | 6
Frame-Bnd-173 | R+1 | Frame-Bnd-173 | R+1 | 90 | CurtainWall_01 | 1.5 | 1.2 | 1.26 | 0.045 | 9.9 | 4.5
Frame-Bnd-174 | R+1 | Frame-Bnd-174 | R+1 | 90 | CurtainWall_01 | 1.5 | 1.2 | 1.26 | 0.045 | 8.4 | 3
Frame-Bnd-175 | R+1 | Frame-Bnd-175 | R+1 | 90 | CurtainWall_01 | 1.5 | 1.2 | 1.26 | 0.045 | 6.9 | 1.5
Frame-Bnd-176 | R+1 | Frame-Bnd-176 | R+1 | 90 | CurtainWall_01 | 1.45 | 1.16 | 1.22 | 0.0435 | 5.4 | 0
Frame-Bnd-177 | R+1 | Frame-Bnd-177 | R+1 | 0 | CurtainWall_01 | 2.05 | 1.64 | 1.7 | 0.0615 | 5.4 | 0
Frame-Bnd-565 | R+1 | Frame-Bnd-565 | R+1 | 0 | CurtainWall_01 | 2.95 | 2.36 | 2.42 | 0.0885 | 4.85 | -0.55
13 x Frame-Bnd-565 | R+1 | Frame-Bnd-565 | R+1 | 0 | CurtainWall_01 | 3 | 2.4 | 2.46 | 0.09 | 4.85 | -0.55
Frame-Bnd-565 | R+1 | Frame-Bnd-565 | R+1 | 0 | CurtainWall_01 | 0.486217 | 0.388973 | 0.448973 | 0.0145865 | 4.85 | -0.55
Frame-Bnd-848 | R+1 | Frame-Bnd-848 | R+1 | 0 | CurtainWall_01 | 2.95 | 2.36 | 2.42 | 0.0885 | 12.1251 | 6.72507
Frame-Bnd-849 | R+1 | Frame-Bnd-849 | R+1 | 0 | CurtainWall_01 | 3 | 2.4 | 2.46 | 0.09 | 12.1251 | 6.72507
Frame-Bnd-850 | R+1 | Frame-Bnd-850 | R+1 | 0 | CurtainWall_01 | 3 | 2.4 | 2.46 | 0.09 | 12.1251 | 6.72507
Frame-Bnd-851 | R+1 | Frame-Bnd-851 | R+1 | 0 | CurtainWall_01 | 3 | 2.4 | 2.46 | 0.09 | 12.1251 | 6.72507
Frame-Bnd-852 | R+1 | Frame-Bnd-852 | R+1 | 0 | CurtainWall_01 | 3 | 2.4 | 2.46 | 0.09 | 12.1251 | 6.72507
Frame-Bnd-853 | R+1 | Frame-Bnd-853 | R+1 | 0 | CurtainWall_01 | 3 | 2.4 | 2.46 | 0.09 | 12.1251 | 6.72507
Frame-Bnd-854 | R+1 | Frame-Bnd-854 | R+1 | 0 | CurtainWall_01 | 3 | 2.4 | 2.46 | 0.09 | 12.1251 | 6.72507
Frame-Bnd-855 | R+1 | Frame-Bnd-855 | R+1 | 0 | CurtainWall_01 | 3 | 2.4 | 2.46 | 0.09 | 12.1251 | 6.72507
Frame-Bnd-856 | R+1 | Frame-Bnd-856 | R+1 | 0 | CurtainWall_01 | 3 | 2.4 | 2.46 | 0.09 | 12.1251 | 6.72507
Frame-Bnd-857 | R+1 | Frame-Bnd-857 | R+1 | 0 | CurtainWall_01 | 3 | 2.4 | 2.46 | 0.09 | 12.1251 | 6.72507
Frame-Bnd-858 | R+1 | Frame-Bnd-858 | R+1 | 0 | CurtainWall_01 | 3 | 2.4 | 2.46 | 0.09 | 12.1251 | 6.72507
Frame-Bnd-859 | R+1 | Frame-Bnd-859 | R+1 | 0 | CurtainWall_01 | 3 | 2.4 | 2.46 | 0.09 | 12.1251 | 6.72507
Frame-Bnd-860 | R+1 | Frame-Bnd-860 | R+1 | 0 | CurtainWall_01 | 3 | 2.4 | 2.46 | 0.09 | 12.1251 | 6.72507
Frame-Bnd-861 | R+1 | Frame-Bnd-861 | R+1 | 0 | CurtainWall_01 | 3 | 2.4 | 2.46 | 0.09 | 12.1251 | 6.72507
Frame-Bnd-862 | R+1 | Frame-Bnd-862 | R+1 | 1.04663e-13 | CurtainWall_01 | 0.486217 | 0.388973 | 0.448973 | 0.0145865 | 12.1251 | 6.72507
Frame-Bnd-429 | Mezzannine | Frame-Bnd-429 | Mezzannine | 0 | CurtainWall_02 | 0.9 | 0.72 | 0.78 | 0.027 | 0.0999999 | -9.325
Frame-Bnd-419 | Mezzannine | Frame-Bnd-419 | Mezzannine | 0 | CurtainWall_02 | 0.9 | 0.72 | 0.78 | 0.027 | 0.0999999 | -9.325
Frame-Bnd-428 | Mezzannine | Frame-Bnd-428 | Mezzannine | 0 | CurtainWall_02 | 0.9 | 0.72 | 0.78 | 0.027 | 0.0999999 | -9.325
Frame-Bnd-414 | Mezzannine | Frame-Bnd-414 | Mezzannine | 0 | CurtainWall_02 | 0.9 | 0.72 | 0.78 | 0.027 | 0.0999999 | -9.325
Frame-Bnd-427 | Mezzannine | Frame-Bnd-427 | Mezzannine | 0 | CurtainWall_02 | 0.9 | 0.72 | 0.78 | 0.027 | 0.0999999 | -9.325
Frame-Bnd-418 | Mezzannine | Frame-Bnd-418 | Mezzannine | 0 | CurtainWall_02 | 0.9 | 0.72 | 0.78 | 0.027 | 0.0999999 | -9.325
Frame-Bnd-426 | Mezzannine | Frame-Bnd-426 | Mezzannine | 0 | CurtainWall_02 | 0.9 | 0.72 | 0.78 | 0.027 | 0.0999999 | -9.325
Frame-Bnd-360 | Mezzannine | Frame-Bnd-360 | Mezzannine | 90 | CurtainWall_02 | 2.65 | 2.12 | 2.18 | 0.0795 | 0.1 | -9.325
Frame-Bnd-425 | Mezzannine | Frame-Bnd-425 | Mezzannine | 0 | CurtainWall_02 | 0.9 | 0.72 | 0.78 | 0.027 | 0.0999999 | -9.325
Frame-Bnd-417 | Mezzannine | Frame-Bnd-417 | Mezzannine | 0 | CurtainWall_02 | 0.9 | 0.72 | 0.78 | 0.027 | 0.0999999 | -9.325
Frame-Bnd-424 | Mezzannine | Frame-Bnd-424 | Mezzannine | 0 | CurtainWall_02 | 0.9 | 0.72 | 0.78 | 0.027 | 0.0999999 | -9.325
Frame-Bnd-413 | Mezzannine | Frame-Bnd-413 | Mezzannine | 0.00000679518 | CurtainWall_02 | 0.9 | 0.72 | 0.78 | 0.027 | 0.0999999 | -9.325
Frame-Bnd-423 | Mezzannine | Frame-Bnd-423 | Mezzannine | 0 | CurtainWall_02 | 0.9 | 0.72 | 0.78 | 0.027 | 0.0999999 | -9.325
Frame-Bnd-416 | Mezzannine | Frame-Bnd-416 | Mezzannine | 0 | CurtainWall_02 | 0.9 | 0.72 | 0.78 | 0.027 | 0.0999999 | -9.325
Frame-Bnd-422 | Mezzannine | Frame-Bnd-422 | Mezzannine | 0 | CurtainWall_02 | 0.9 | 0.72 | 0.78 | 0.027 | 0.0999999 | -9.325
Frame-Bnd-236 | Mezzannine | Frame-Bnd-236 | Mezzannine | 90 | CurtainWall_02 | 2.65 | 2.12 | 2.18 | 0.0795 | 0.0999999 | -9.325
Frame-Bnd-421 | Mezzannine | Frame-Bnd-421 | Mezzannine | 0 | CurtainWall_02 | 0.9 | 0.72 | 0.78 | 0.027 | 0.0999999 | -9.325
Frame-Bnd-415 | Mezzannine | Frame-Bnd-415 | Mezzannine | 0 | CurtainWall_02 | 0.9 | 0.72 | 0.78 | 0.027 | 0.0999999 | -9.325
Frame-Bnd-420 | Mezzannine | Frame-Bnd-420 | Mezzannine | 0 | CurtainWall_02 | 0.9 | 0.72 | 0.78 | 0.027 | 0.0999999 | -9.325
Frame-Bnd-359 | Mezzannine | Frame-Bnd-359 | Mezzannine | 90 | CurtainWall_02 | 1.5 | 1.2 | 1.26 | 0.045 | 2.8 | -6.625
Frame-Bnd-287 | Mezzannine | Frame-Bnd-287 | Mezzannine | 0 | CurtainWall_02 | 0.9 | 0.72 | 0.78 | 0.027 | 4.4 | -5.025
Frame-Bnd-236 | Mezzannine | Frame-Bnd-236 | Mezzannine | 90 | CurtainWall_02 | 1.5 | 1.2 | 1.26 | 0.045 | 2.8 | -6.625
Frame-Bnd-297 | Mezzannine | Frame-Bnd-297 | Mezzannine | 0 | CurtainWall_02 | 0.9 | 0.72 | 0.78 | 0.027 | 4.4 | -5.025
Frame-Bnd-298 | Mezzannine | Frame-Bnd-298 | Mezzannine | 0 | CurtainWall_02 | 0.9 | 0.72 | 0.78 | 0.027 | 4.4 | -5.025
Frame-Bnd-299 | Mezzannine | Frame-Bnd-299 | Mezzannine | 0 | CurtainWall_02 | 0.9 | 0.72 | 0.78 | 0.027 | 4.4 | -5.025
Frame-Bnd-300 | Mezzannine | Frame-Bnd-300 | Mezzannine | 0 | CurtainWall_02 | 0.9 | 0.72 | 0.78 | 0.027 | 4.4 | -5.025
Frame-Bnd-301 | Mezzannine | Frame-Bnd-301 | Mezzannine | 0 | CurtainWall_02 | 0.9 | 0.72 | 0.78 | 0.027 | 4.4 | -5.025
Frame-Bnd-302 | Mezzannine | Frame-Bnd-302 | Mezzannine | 0 | CurtainWall_02 | 0.9 | 0.72 | 0.78 | 0.027 | 4.4 | -5.025
Frame-Bnd-303 | Mezzannine | Frame-Bnd-303 | Mezzannine | 0 | CurtainWall_02 | 0.9 | 0.72 | 0.78 | 0.027 | 4.4 | -5.025
Frame-Bnd-412 | Mezzannine | Frame-Bnd-412 | Mezzannine | 0 | CurtainWall_02 | 0.772687 | 0.618149 | 0.678149 | 0.0231806 | 0.1 | -9.325
Frame-Bnd-430 | Mezzannine | Frame-Bnd-430 | Mezzannine | 0 | CurtainWall_02 | 0.85 | 0.68 | 0.74 | 0.0255 | 0.0999999 | -9.325
Frame-Bnd-358 | Mezzannine | Frame-Bnd-358 | Mezzannine | 90 | CurtainWall_02 | 0.05 | 0.04 | 0.1 | 0.0015 | 4.3 | -5.125
Frame-Bnd-288 | Mezzannine | Frame-Bnd-288 | Mezzannine | 0 | CurtainWall_02 | 0.9 | 0.72 | 0.78 | 0.027 | 4.4 | -5.025
Frame-Bnd-286 | Mezzannine | Frame-Bnd-286 | Mezzannine | 0 | CurtainWall_02 | 0.85 | 0.68 | 0.74 | 0.0255 | 4.4 | -5.025
Frame-Bnd-296 | Mezzannine | Frame-Bnd-296 | Mezzannine | 0 | CurtainWall_02 | 0.9 | 0.72 | 0.78 | 0.027 | 4.4 | -5.025
Frame-Bnd-285 | Mezzannine | Frame-Bnd-285 | Mezzannine | 90 | CurtainWall_02 | 0.05 | 0.04 | 0.1 | 0.0015 | 4.3 | -5.125
Frame-Bnd-295 | Mezzannine | Frame-Bnd-295 | Mezzannine | 0 | CurtainWall_02 | 0.9 | 0.72 | 0.78 | 0.027 | 4.4 | -5.025
Frame-Bnd-304 | Mezzannine | Frame-Bnd-304 | Mezzannine | 0.00000577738 | CurtainWall_02 | 0.772687 | 0.618149 | 0.678149 | 0.0231806 | 4.4 | -5.025
Frame-Bnd-294 | Mezzannine | Frame-Bnd-294 | Mezzannine | 0 | CurtainWall_02 | 0.9 | 0.72 | 0.78 | 0.027 | 4.4 | -5.025
Frame-Bnd-293 | Mezzannine | Frame-Bnd-293 | Mezzannine | 0 | CurtainWall_02 | 0.9 | 0.72 | 0.78 | 0.027 | 4.4 | -5.025
Frame-Bnd-292 | Mezzannine | Frame-Bnd-292 | Mezzannine | 0 | CurtainWall_02 | 0.9 | 0.72 | 0.78 | 0.027 | 4.4 | -5.025
Frame-Bnd-291 | Mezzannine | Frame-Bnd-291 | Mezzannine | 0 | CurtainWall_02 | 0.9 | 0.72 | 0.78 | 0.027 | 4.4 | -5.025
Frame-Bnd-290 | Mezzannine | Frame-Bnd-290 | Mezzannine | 0 | CurtainWall_02 | 0.9 | 0.72 | 0.78 | 0.027 | 4.4 | -5.025
Frame-Bnd-289 | Mezzannine | Frame-Bnd-289 | Mezzannine | 0 | CurtainWall_02 | 0.9 | 0.72 | 0.78 | 0.027 | 4.4 | -5.025

# IfcMember: Montant 80 x 250 (304)
Material: 25 % 359672764
ArchiCADProperties - Calque: A-WALL-CURT; Type: Cadre de mur-rideau; Verrouillé: no; Matériau de construction / Composite / Profil / Hachure: 25 % 359672764; Etat de rénovation: Existant; Afficher sur filtre de rénovation: Tous les filtres appropriés; Type de cadre: Générique; Angle d'inclinaison: 90 deg; Classe de cadre: Montant; Surface: Mtl-Stainless Steel
AC_Pset_RenovationAndPhasing - Renovation Status: Existing
BaseQuantities - CrossSectionArea: 0.02 m2
ArchiCADQuantities - Superficie de surface: 0.02 m2; Largeur cadre: 0.08 m; Profondeur de cadre: 0.25 m
Name | In | ID | Etage d'implantation | Emplacement : | ID mur-rideau | Length (m) = Longueur cadre (m) | OuterSurfaceArea (m2) | TotalSurfaceArea (m2) = GrossSurfaceArea (m2) | GrossVolume (m3) = NetVolume (m3) = Volume net (m3) | Altitude à Zéro du Projet (m) | Altitude à étage (m)
36 x Frame-Mll-283 | Rez de chaussée | Frame-Mll-283 | Rez de chaussée | Grille primaire | CurtainWall_02 | 2.6 | 1.716 | 1.756 | 0.052 | 0.1 | 0.1
2 x Frame-Mll-283 | Rez de chaussée | Frame-Mll-283 | Rez de chaussée | Grille primaire | CurtainWall_02 | 2.6 | 1.716 | 1.756 | 0.052 | 0.1 | 0.1 | ArchiCADProperties - Nom de Zone: Réserve; Numéro de Zone: 010
Frame-Mll-651 | Rez de chaussée | Frame-Mll-651 | Rez de chaussée | Grille primaire | CurtainWall_02 | 1.5 | 0.99 | 1.03 | 0.03 | 2.8 | 2.8
Frame-Mll-652 | Rez de chaussée | Frame-Mll-652 | Rez de chaussée | Grille primaire | CurtainWall_02 | 1.5 | 0.99 | 1.03 | 0.03 | 2.8 | 2.8
Frame-Mll-653 | Rez de chaussée | Frame-Mll-653 | Rez de chaussée | Grille primaire | CurtainWall_02 | 1.5 | 0.99 | 1.03 | 0.03 | 2.8 | 2.8
Frame-Mll-654 | Rez de chaussée | Frame-Mll-654 | Rez de chaussée | Grille primaire | CurtainWall_02 | 1.5 | 0.99 | 1.03 | 0.03 | 2.8 | 2.8
Frame-Mll-655 | Rez de chaussée | Frame-Mll-655 | Rez de chaussée | Grille primaire | CurtainWall_02 | 1.5 | 0.99 | 1.03 | 0.03 | 2.8 | 2.8
Frame-Mll-656 | Rez de chaussée | Frame-Mll-656 | Rez de chaussée | Grille primaire | CurtainWall_02 | 1.5 | 0.99 | 1.03 | 0.03 | 2.8 | 2.8
Frame-Mll-657 | Rez de chaussée | Frame-Mll-657 | Rez de chaussée | Grille primaire | CurtainWall_02 | 1.5 | 0.99 | 1.03 | 0.03 | 2.8 | 2.8
Frame-Mll-658 | Rez de chaussée | Frame-Mll-658 | Rez de chaussée | Grille primaire | CurtainWall_02 | 1.5 | 0.99 | 1.03 | 0.03 | 2.8 | 2.8
Frame-Mll-659 | Rez de chaussée | Frame-Mll-659 | Rez de chaussée | Grille primaire | CurtainWall_02 | 1.5 | 0.99 | 1.03 | 0.03 | 2.8 | 2.8
Frame-Mll-660 | Rez de chaussée | Frame-Mll-660 | Rez de chaussée | Grille primaire | CurtainWall_02 | 1.5 | 0.99 | 1.03 | 0.03 | 2.8 | 2.8
Frame-Mll-661 | Rez de chaussée | Frame-Mll-661 | Rez de chaussée | Grille primaire | CurtainWall_02 | 1.5 | 0.99 | 1.03 | 0.03 | 2.8 | 2.8
Frame-Mll-662 | Rez de chaussée | Frame-Mll-662 | Rez de chaussée | Grille primaire | CurtainWall_02 | 1.5 | 0.99 | 1.03 | 0.03 | 2.8 | 2.8
Frame-Mll-663 | Rez de chaussée | Frame-Mll-663 | Rez de chaussée | Grille primaire | CurtainWall_02 | 1.5 | 0.99 | 1.03 | 0.03 | 2.8 | 2.8
Frame-Mll-664 | Rez de chaussée | Frame-Mll-664 | Rez de chaussée | Grille primaire | CurtainWall_02 | 1.5 | 0.99 | 1.03 | 0.03 | 2.8 | 2.8
Frame-Mll-665 | Rez de chaussée | Frame-Mll-665 | Rez de chaussée | Grille primaire | CurtainWall_02 | 1.5 | 0.99 | 1.03 | 0.03 | 2.8 | 2.8
Frame-Mll-666 | Rez de chaussée | Frame-Mll-666 | Rez de chaussée | Grille primaire | CurtainWall_02 | 1.5 | 0.99 | 1.03 | 0.03 | 2.8 | 2.8
Frame-Mll-667 | Rez de chaussée | Frame-Mll-667 | Rez de chaussée | Grille primaire | CurtainWall_02 | 1.5 | 0.99 | 1.03 | 0.03 | 2.8 | 2.8
Frame-Mll-668 | Rez de chaussée | Frame-Mll-668 | Rez de chaussée | Grille primaire | CurtainWall_02 | 1.5 | 0.99 | 1.03 | 0.03 | 2.8 | 2.8 | ArchiCADProperties - Nom de Zone: Réserve; Numéro de Zone: 010
Frame-Mll-669 | Rez de chaussée | Frame-Mll-669 | Rez de chaussée | Grille primaire | CurtainWall_02 | 1.5 | 0.99 | 1.03 | 0.03 | 2.8 | 2.8 | ArchiCADProperties - Nom de Zone: Réserve; Numéro de Zone: 010
Frame-Mll-670 | Rez de chaussée | Frame-Mll-670 | Rez de chaussée | Grille primaire | CurtainWall_02 | 1.5 | 0.99 | 1.03 | 0.03 | 2.8 | 2.8
Frame-Mll-671 | Rez de chaussée | Frame-Mll-671 | Rez de chaussée | Grille primaire | CurtainWall_02 | 1.5 | 0.99 | 1.03 | 0.03 | 2.8 | 2.8
Frame-Mll-672 | Rez de chaussée | Frame-Mll-672 | Rez de chaussée | Grille primaire | CurtainWall_02 | 1.5 | 0.99 | 1.03 | 0.03 | 2.8 | 2.8
Frame-Mll-673 | Rez de chaussée | Frame-Mll-673 | Rez de chaussée | Grille primaire | CurtainWall_02 | 1.5 | 0.99 | 1.03 | 0.03 | 2.8 | 2.8
Frame-Mll-674 | Rez de chaussée | Frame-Mll-674 | Rez de chaussée | Grille primaire | CurtainWall_02 | 1.5 | 0.99 | 1.03 | 0.03 | 2.8 | 2.8
Frame-Mll-675 | Rez de chaussée | Frame-Mll-675 | Rez de chaussée | Grille primaire | CurtainWall_02 | 1.5 | 0.99 | 1.03 | 0.03 | 2.8 | 2.8
Frame-Mll-676 | Rez de chaussée | Frame-Mll-676 | Rez de chaussée | Grille primaire | CurtainWall_02 | 1.5 | 0.99 | 1.03 | 0.03 | 2.8 | 2.8
Frame-Mll-677 | Rez de chaussée | Frame-Mll-677 | Rez de chaussée | Grille primaire | CurtainWall_02 | 1.5 | 0.99 | 1.03 | 0.03 | 2.8 | 2.8
Frame-Mll-678 | Rez de chaussée | Frame-Mll-678 | Rez de chaussée | Grille primaire | CurtainWall_02 | 1.5 | 0.99 | 1.03 | 0.03 | 2.8 | 2.8
Frame-Mll-679 | Rez de chaussée | Frame-Mll-679 | Rez de chaussée | Grille primaire | CurtainWall_02 | 1.5 | 0.99 | 1.03 | 0.03 | 2.8 | 2.8
Frame-Mll-680 | Rez de chaussée | Frame-Mll-680 | Rez de chaussée | Grille primaire | CurtainWall_02 | 1.5 | 0.99 | 1.03 | 0.03 | 2.8 | 2.8
Frame-Mll-681 | Rez de chaussée | Frame-Mll-681 | Rez de chaussée | Grille primaire | CurtainWall_02 | 1.5 | 0.99 | 1.03 | 0.03 | 2.8 | 2.8
Frame-Mll-682 | Rez de chaussée | Frame-Mll-682 | Rez de chaussée | Grille primaire | CurtainWall_02 | 1.5 | 0.99 | 1.03 | 0.03 | 2.8 | 2.8
Frame-Mll-683 | Rez de chaussée | Frame-Mll-683 | Rez de chaussée | Grille primaire | CurtainWall_02 | 1.5 | 0.99 | 1.03 | 0.03 | 2.8 | 2.8
Frame-Mll-684 | Rez de chaussée | Frame-Mll-684 | Rez de chaussée | Grille primaire | CurtainWall_02 | 1.5 | 0.99 | 1.03 | 0.03 | 2.8 | 2.8
Frame-Mll-685 | Rez de chaussée | Frame-Mll-685 | Rez de chaussée | Grille primaire | CurtainWall_02 | 1.5 | 0.99 | 1.03 | 0.03 | 2.8 | 2.8
Frame-Mll-686 | Rez de chaussée | Frame-Mll-686 | Rez de chaussée | Grille primaire | CurtainWall_02 | 1.5 | 0.99 | 1.03 | 0.03 | 2.8 | 2.8
Frame-Mll-687 | Rez de chaussée | Frame-Mll-687 | Rez de chaussée | Grille primaire | CurtainWall_02 | 1.5 | 0.99 | 1.03 | 0.03 | 2.8 | 2.8
Frame-Mll-688 | Rez de chaussée | Frame-Mll-688 | Rez de chaussée | Grille primaire | CurtainWall_02 | 1.5 | 0.99 | 1.03 | 0.03 | 2.8 | 2.8
Frame-Mll-289 | R+1 | Frame-Mll-289 | R+1 | Grille primaire | CurtainWall_01 | 0.4 | 0.264 | 0.304 | 0.008 | 16.9 | 11.5
Frame-Mll-361 | R+1 | Frame-Mll-361 | R+1 | Cadre | CurtainWall_01 | 1.5 | 0.99 | 1.03 | 0.03 | 6.4 | 1
Frame-Mll-132 | R+1 | Frame-Mll-132 | R+1 | Grille primaire | CurtainWall_01 | 0.9 | 0.594 | 0.634 | 0.018 | 5.4 | -6.83897e-14
Frame-Mll-133 | R+1 | Frame-Mll-133 | R+1 | Grille primaire | CurtainWall_01 | 1.5 | 0.99 | 1.03 | 0.03 | 6.4 | 1
Frame-Mll-134 | R+1 | Frame-Mll-134 | R+1 | Grille primaire | CurtainWall_01 | 1.5 | 0.99 | 1.03 | 0.03 | 6.4 | 1
Frame-Mll-361 | R+1 | Frame-Mll-361 | R+1 | Cadre | CurtainWall_01 | 0.9 | 0.594 | 0.634 | 0.018 | 5.4 | 7.16094e-15
Frame-Mll-145 | R+1 | Frame-Mll-145 | R+1 | Grille primaire | CurtainWall_01 | 0.9 | 0.594 | 0.634 | 0.018 | 5.4 | 7.16094e-15
Frame-Mll-146 | R+1 | Frame-Mll-146 | R+1 | Grille primaire | CurtainWall_01 | 1.5 | 0.99 | 1.03 | 0.03 | 6.4 | 1
Frame-Mll-361 | R+1 | Frame-Mll-361 | R+1 | Cadre | CurtainWall_01 | 1.5 | 0.99 | 1.03 | 0.03 | 7.9 | 2.5
Frame-Mll-166 | R+1 | Frame-Mll-166 | R+1 | Grille primaire | CurtainWall_01 | 1.5 | 0.99 | 1.03 | 0.03 | 7.9 | 2.5
Frame-Mll-167 | R+1 | Frame-Mll-167 | R+1 | Grille primaire | CurtainWall_01 | 1.5 | 0.99 | 1.03 | 0.03 | 9.4 | 4
Frame-Mll-168 | R+1 | Frame-Mll-168 | R+1 | Grille primaire | CurtainWall_01 | 1.5 | 0.99 | 1.03 | 0.03 | 10.9 | 5.5
Frame-Mll-169 | R+1 | Frame-Mll-169 | R+1 | Grille primaire | CurtainWall_01 | 1.5 | 0.99 | 1.03 | 0.03 | 12.4 | 7
Frame-Mll-170 | R+1 | Frame-Mll-170 | R+1 | Grille primaire | CurtainWall_01 | 1.5 | 0.99 | 1.03 | 0.03 | 13.9 | 8.5
Frame-Mll-171 | R+1 | Frame-Mll-171 | R+1 | Grille primaire | CurtainWall_01 | 1.5 | 0.99 | 1.03 | 0.03 | 15.4 | 10
Frame-Mll-173 | R+1 | Frame-Mll-173 | R+1 | Grille primaire | CurtainWall_01 | 1.5 | 0.99 | 1.03 | 0.03 | 7.9 | 2.5
Frame-Mll-174 | R+1 | Frame-Mll-174 | R+1 | Grille primaire | CurtainWall_01 | 1.5 | 0.99 | 1.03 | 0.03 | 9.4 | 4
Frame-Mll-175 | R+1 | Frame-Mll-175 | R+1 | Grille primaire | CurtainWall_01 | 1.5 | 0.99 | 1.03 | 0.03 | 10.9 | 5.5
Frame-Mll-176 | R+1 | Frame-Mll-176 | R+1 | Grille primaire | CurtainWall_01 | 1.5 | 0.99 | 1.03 | 0.03 | 12.4 | 7
Frame-Mll-177 | R+1 | Frame-Mll-177 | R+1 | Grille primaire | CurtainWall_01 | 1.5 | 0.99 | 1.03 | 0.03 | 13.9 | 8.5
Frame-Mll-178 | R+1 | Frame-Mll-178 | R+1 | Grille primaire | CurtainWall_01 | 1.5 | 0.99 | 1.03 | 0.03 | 15.4 | 10
Frame-Mll-361 | R+1 | Frame-Mll-361 | R+1 | Cadre | CurtainWall_01 | 1.5 | 0.99 | 1.03 | 0.03 | 9.4 | 4
Frame-Mll-290 | R+1 | Frame-Mll-290 | R+1 | Grille primaire | CurtainWall_01 | 0.4 | 0.264 | 0.304 | 0.008 | 16.9 | 11.5
Frame-Mll-361 | R+1 | Frame-Mll-361 | R+1 | Cadre | CurtainWall_01 | 1.5 | 0.99 | 1.03 | 0.03 | 10.9 | 5.5
Frame-Mll-361 | R+1 | Frame-Mll-361 | R+1 | Cadre | CurtainWall_01 | 1.5 | 0.99 | 1.03 | 0.03 | 12.4 | 7
Frame-Mll-361 | R+1 | Frame-Mll-361 | R+1 | Cadre | CurtainWall_01 | 1.5 | 0.99 | 1.03 | 0.03 | 13.9 | 8.5
Frame-Mll-320 | R+1 | Frame-Mll-320 | R+1 | Grille primaire | CurtainWall_01 | 0.4 | 0.264 | 0.304 | 0.008 | 16.9 | 11.5
Frame-Mll-201 | R+1 | Frame-Mll-201 | R+1 | Grille primaire | CurtainWall_01 | 1.5 | 0.99 | 1.03 | 0.03 | 7.9 | 2.5
Frame-Mll-202 | R+1 | Frame-Mll-202 | R+1 | Grille primaire | CurtainWall_01 | 1.5 | 0.99 | 1.03 | 0.03 | 9.4 | 4
Frame-Mll-203 | R+1 | Frame-Mll-203 | R+1 | Grille primaire | CurtainWall_01 | 1.5 | 0.99 | 1.03 | 0.03 | 10.9 | 5.5
Frame-Mll-204 | R+1 | Frame-Mll-204 | R+1 | Grille primaire | CurtainWall_01 | 1.5 | 0.99 | 1.03 | 0.03 | 12.4 | 7
Frame-Mll-205 | R+1 | Frame-Mll-205 | R+1 | Grille primaire | CurtainWall_01 | 1.5 | 0.99 | 1.03 | 0.03 | 13.9 | 8.5
Frame-Mll-206 | R+1 | Frame-Mll-206 | R+1 | Grille primaire | CurtainWall_01 | 1.5 | 0.99 | 1.03 | 0.03 | 15.4 | 10
Frame-Mll-361 | R+1 | Frame-Mll-361 | R+1 | Cadre | CurtainWall_01 | 0.4 | 0.264 | 0.304 | 0.008 | 16.9 | 11.5
Frame-Mll-131 | R+1 | Frame-Mll-131 | R+1 | Grille primaire | CurtainWall_01 | 0.9 | 0.594 | 0.634 | 0.018 | 5.4 | -6.83897e-14
Frame-Mll-361 | R+1 | Frame-Mll-361 | R+1 | Cadre | CurtainWall_01 | 1.5 | 0.99 | 1.03 | 0.03 | 15.4 | 10
Frame-Mll-447 | R+1 | Frame-Mll-447 | R+1 | Grille primaire | CurtainWall_01 | 1.4 | 0.924 | 0.964 | 0.028 | 5.4 | 0
Frame-Mll-448 | R+1 | Frame-Mll-448 | R+1 | Grille primaire | CurtainWall_01 | 1.4 | 0.924 | 0.964 | 0.028 | 5.4 | 0
Frame-Mll-449 | R+1 | Frame-Mll-449 | R+1 | Grille primaire | CurtainWall_01 | 1.5 | 0.99 | 1.03 | 0.03 | 6.9 | 1.5
Frame-Mll-450 | R+1 | Frame-Mll-450 | R+1 | Grille primaire | CurtainWall_01 | 1.5 | 0.99 | 1.03 | 0.03 | 6.9 | 1.5
Frame-Mll-451 | R+1 | Frame-Mll-451 | R+1 | Grille primaire | CurtainWall_01 | 1.5 | 0.99 | 1.03 | 0.03 | 8.4 | 3
Frame-Mll-452 | R+1 | Frame-Mll-452 | R+1 | Grille primaire | CurtainWall_01 | 1.5 | 0.99 | 1.03 | 0.03 | 8.4 | 3
Frame-Mll-453 | R+1 | Frame-Mll-453 | R+1 | Grille primaire | CurtainWall_01 | 1.5 | 0.99 | 1.03 | 0.03 | 9.9 | 4.5
Frame-Mll-454 | R+1 | Frame-Mll-454 | R+1 | Grille primaire | CurtainWall_01 | 1.5 | 0.99 | 1.03 | 0.03 | 9.9 | 4.5
Frame-Mll-455 | R+1 | Frame-Mll-455 | R+1 | Grille primaire | CurtainWall_01 | 1.5 | 0.99 | 1.03 | 0.03 | 11.4 | 6
Frame-Mll-456 | R+1 | Frame-Mll-456 | R+1 | Grille primaire | CurtainWall_01 | 1.5 | 0.99 | 1.03 | 0.03 | 11.4 | 6
Frame-Mll-457 | R+1 | Frame-Mll-457 | R+1 | Grille primaire | CurtainWall_01 | 1.5 | 0.99 | 1.03 | 0.03 | 12.9 | 7.5
Frame-Mll-458 | R+1 | Frame-Mll-458 | R+1 | Grille primaire | CurtainWall_01 | 1.5 | 0.99 | 1.03 | 0.03 | 12.9 | 7.5
Frame-Mll-459 | R+1 | Frame-Mll-459 | R+1 | Grille primaire | CurtainWall_01 | 1.5 | 0.99 | 1.03 | 0.03 | 14.4 | 9
Frame-Mll-460 | R+1 | Frame-Mll-460 | R+1 | Grille primaire | CurtainWall_01 | 1.5 | 0.99 | 1.03 | 0.03 | 14.4 | 9
Frame-Mll-461 | R+1 | Frame-Mll-461 | R+1 | Grille primaire | CurtainWall_01 | 1.4 | 0.924 | 0.964 | 0.028 | 15.9 | 10.5
Frame-Mll-462 | R+1 | Frame-Mll-462 | R+1 | Grille primaire | CurtainWall_01 | 1.4 | 0.924 | 0.964 | 0.028 | 15.9 | 10.5
3 x Frame-Mll-291 | R+1 | Frame-Mll-291 | R+1 | Grille primaire | CurtainWall_01 | 1.4 | 0.924 | 0.964 | 0.028 | 4.4 | -1
3 x Frame-Mll-291 | R+1 | Frame-Mll-291 | R+1 | Grille primaire | CurtainWall_01 | 1.5 | 0.99 | 1.03 | 0.03 | 5.9 | 0.5
3 x Frame-Mll-291 | R+1 | Frame-Mll-291 | R+1 | Grille primaire | CurtainWall_01 | 1.5 | 0.99 | 1.03 | 0.03 | 7.4 | 2
3 x Frame-Mll-291 | R+1 | Frame-Mll-291 | R+1 | Grille primaire | CurtainWall_01 | 1.5 | 0.99 | 1.03 | 0.03 | 8.9 | 3.5
3 x Frame-Mll-291 | R+1 | Frame-Mll-291 | R+1 | Grille primaire | CurtainWall_01 | 1.5 | 0.99 | 1.03 | 0.03 | 10.4 | 5
3 x Frame-Mll-291 | R+1 | Frame-Mll-291 | R+1 | Grille primaire | CurtainWall_01 | 1.5 | 0.99 | 1.03 | 0.03 | 11.9 | 6.5
3 x Frame-Mll-291 | R+1 | Frame-Mll-291 | R+1 | Grille primaire | CurtainWall_01 | 1.5 | 0.99 | 1.03 | 0.03 | 13.4 | 8
3 x Frame-Mll-291 | R+1 | Frame-Mll-291 | R+1 | Grille primaire | CurtainWall_01 | 1.5 | 0.99 | 1.03 | 0.03 | 14.9 | 9.5
Frame-Mll-307 | R+1 | Frame-Mll-307 | R+1 | Grille primaire | CurtainWall_01 | 0.9 | 0.594 | 0.634 | 0.018 | 16.4 | 11
Frame-Mll-306 | R+1 | Frame-Mll-306 | R+1 | Grille primaire | CurtainWall_01 | 0.9 | 0.594 | 0.634 | 0.018 | 16.4 | 11
Frame-Mll-305 | R+1 | Frame-Mll-305 | R+1 | Grille primaire | CurtainWall_01 | 0.9 | 0.594 | 0.634 | 0.018 | 16.4 | 11
3 x Frame-Mll-300 | R+1 | Frame-Mll-300 | R+1 | Grille primaire | CurtainWall_01 | 1.4 | 0.924 | 0.964 | 0.028 | 4.4 | -1 | ArchiCADProperties - Nom de Zone: Plateau bureaux; Numéro de Zone: 005
3 x Frame-Mll-300 | R+1 | Frame-Mll-300 | R+1 | Grille primaire | CurtainWall_01 | 1.5 | 0.99 | 1.03 | 0.03 | 5.9 | 0.5 | ArchiCADProperties - Nom de Zone: Plateau bureaux; Numéro de Zone: 005
3 x Frame-Mll-300 | R+1 | Frame-Mll-300 | R+1 | Grille primaire | CurtainWall_01 | 1.5 | 0.99 | 1.03 | 0.03 | 7.4 | 2 | ArchiCADProperties - Nom de Zone: Plateau bureaux; Numéro de Zone: 005
3 x Frame-Mll-300 | R+1 | Frame-Mll-300 | R+1 | Grille primaire | CurtainWall_01 | 1.5 | 0.99 | 1.03 | 0.03 | 8.9 | 3.5 | ArchiCADProperties - Nom de Zone: Plateau bureaux; Numéro de Zone: 005
3 x Frame-Mll-300 | R+1 | Frame-Mll-300 | R+1 | Grille primaire | CurtainWall_01 | 1.5 | 0.99 | 1.03 | 0.03 | 10.4 | 5 | ArchiCADProperties - Nom de Zone: Plateau bureaux; Numéro de Zone: 005
3 x Frame-Mll-300 | R+1 | Frame-Mll-300 | R+1 | Grille primaire | CurtainWall_01 | 1.5 | 0.99 | 1.03 | 0.03 | 11.9 | 6.5 | ArchiCADProperties - Nom de Zone: Plateau bureaux; Numéro de Zone: 005
3 x Frame-Mll-300 | R+1 | Frame-Mll-300 | R+1 | Grille primaire | CurtainWall_01 | 1.5 | 0.99 | 1.03 | 0.03 | 13.4 | 8 | ArchiCADProperties - Nom de Zone: Plateau bureaux; Numéro de Zone: 005
3 x Frame-Mll-300 | R+1 | Frame-Mll-300 | R+1 | Grille primaire | CurtainWall_01 | 1.5 | 0.99 | 1.03 | 0.03 | 14.9 | 9.5 | ArchiCADProperties - Nom de Zone: Plateau bureaux; Numéro de Zone: 005
Frame-Mll-314 | R+1 | Frame-Mll-314 | R+1 | Grille primaire | CurtainWall_01 | 0.9 | 0.594 | 0.634 | 0.018 | 16.4 | 11 | ArchiCADProperties - Nom de Zone: Plateau bureaux; Numéro de Zone: 005
Frame-Mll-315 | R+1 | Frame-Mll-315 | R+1 | Grille primaire | CurtainWall_01 | 0.9 | 0.594 | 0.634 | 0.018 | 16.4 | 11 | ArchiCADProperties - Nom de Zone: Plateau bureaux; Numéro de Zone: 005
Frame-Mll-316 | R+1 | Frame-Mll-316 | R+1 | Grille primaire | CurtainWall_01 | 0.9 | 0.594 | 0.634 | 0.018 | 16.4 | 11 | ArchiCADProperties - Nom de Zone: Plateau bureaux; Numéro de Zone: 005
Frame-Mll-414 | R+1 | Frame-Mll-414 | R+1 | Grille primaire | CurtainWall_01 | 1.4 | 0.924 | 0.964 | 0.028 | 5.4 | 0
Frame-Mll-415 | R+1 | Frame-Mll-415 | R+1 | Grille primaire | CurtainWall_01 | 1.4 | 0.924 | 0.964 | 0.028 | 5.4 | 0
Frame-Mll-416 | R+1 | Frame-Mll-416 | R+1 | Grille primaire | CurtainWall_01 | 1.5 | 0.99 | 1.03 | 0.03 | 6.9 | 1.5
Frame-Mll-417 | R+1 | Frame-Mll-417 | R+1 | Grille primaire | CurtainWall_01 | 1.5 | 0.99 | 1.03 | 0.03 | 6.9 | 1.5
Frame-Mll-418 | R+1 | Frame-Mll-418 | R+1 | Grille primaire | CurtainWall_01 | 1.5 | 0.99 | 1.03 | 0.03 | 8.4 | 3
Frame-Mll-419 | R+1 | Frame-Mll-419 | R+1 | Grille primaire | CurtainWall_01 | 1.5 | 0.99 | 1.03 | 0.03 | 8.4 | 3
Frame-Mll-420 | R+1 | Frame-Mll-420 | R+1 | Grille primaire | CurtainWall_01 | 1.5 | 0.99 | 1.03 | 0.03 | 9.9 | 4.5
Frame-Mll-421 | R+1 | Frame-Mll-421 | R+1 | Grille primaire | CurtainWall_01 | 1.5 | 0.99 | 1.03 | 0.03 | 9.9 | 4.5
Frame-Mll-422 | R+1 | Frame-Mll-422 | R+1 | Grille primaire | CurtainWall_01 | 1.5 | 0.99 | 1.03 | 0.03 | 11.4 | 6
Frame-Mll-423 | R+1 | Frame-Mll-423 | R+1 | Grille primaire | CurtainWall_01 | 1.5 | 0.99 | 1.03 | 0.03 | 11.4 | 6
Frame-Mll-424 | R+1 | Frame-Mll-424 | R+1 | Grille primaire | CurtainWall_01 | 1.5 | 0.99 | 1.03 | 0.03 | 12.9 | 7.5
Frame-Mll-425 | R+1 | Frame-Mll-425 | R+1 | Grille primaire | CurtainWall_01 | 1.5 | 0.99 | 1.03 | 0.03 | 12.9 | 7.5
Frame-Mll-426 | R+1 | Frame-Mll-426 | R+1 | Grille primaire | CurtainWall_01 | 1.5 | 0.99 | 1.03 | 0.03 | 14.4 | 9
Frame-Mll-427 | R+1 | Frame-Mll-427 | R+1 | Grille primaire | CurtainWall_01 | 1.5 | 0.99 | 1.03 | 0.03 | 14.4 | 9
Frame-Mll-428 | R+1 | Frame-Mll-428 | R+1 | Grille primaire | CurtainWall_01 | 1.4 | 0.924 | 0.964 | 0.028 | 15.9 | 10.5
Frame-Mll-429 | R+1 | Frame-Mll-429 | R+1 | Grille primaire | CurtainWall_01 | 1.4 | 0.924 | 0.964 | 0.028 | 15.9 | 10.5
14 x Frame-Mll-209 | R+1 | Frame-Mll-209 | R+1 | Grille primaire | CurtainWall_01 | 1.4 | 0.924 | 0.964 | 0.028 | 4.85 | -0.55
14 x Frame-Mll-209 | R+1 | Frame-Mll-209 | R+1 | Grille primaire | CurtainWall_01 | 1.5 | 0.99 | 1.03 | 0.03 | 6.35 | 0.95
14 x Frame-Mll-209 | R+1 | Frame-Mll-209 | R+1 | Grille primaire | CurtainWall_01 | 1.5 | 0.99 | 1.03 | 0.03 | 7.85 | 2.45
14 x Frame-Mll-209 | R+1 | Frame-Mll-209 | R+1 | Grille primaire | CurtainWall_01 | 1.5 | 0.99 | 1.03 | 0.03 | 9.35 | 3.95
14 x Frame-Mll-209 | R+1 | Frame-Mll-209 | R+1 | Grille primaire | CurtainWall_01 | 1.17507 | 0.775545 | 0.815545 | 0.0235014 | 10.85 | 5.45
17 x Frame-Mll-458 | Mezzannine | Frame-Mll-458 | Mezzannine | Grille primaire | CurtainWall_02 | 2.6 | 1.716 | 1.756 | 0.052 | 0.0999999 | -9.325
Frame-Mll-458 | Mezzannine | Frame-Mll-458 | Mezzannine | Grille primaire | CurtainWall_02 | 2.6 | 1.716 | 1.756 | 0.052 | 0.1 | -9.325
18 x Frame-Mll-458 | Mezzannine | Frame-Mll-458 | Mezzannine | Grille primaire | CurtainWall_02 | 1.5 | 0.99 | 1.03 | 0.03 | 2.8 | -6.625

# IfcMember: Personnalisé 100 x 300 (10)
In: R+1
Material: 25 % 359672764
ArchiCADProperties - ID: Frame-Bnd-565; Etage d'implantation: R+1; Calque: A-WALL-CURT; Type: Cadre de mur-rideau; Verrouillé: no; Matériau de construction / Composite / Profil / Hachure: 25 % 359672764; Etat de rénovation: Existant; Afficher sur filtre de rénovation: Tous les filtres appropriés; Emplacement :: Cadre; Type de cadre: Générique; Angle d'inclinaison: 90 deg; Classe de cadre: Autre; Surface: Mtl-Stainless Steel; ID mur-rideau: CurtainWall_01
AC_Pset_RenovationAndPhasing - Renovation Status: Existing
BaseQuantities - CrossSectionArea: 0.03 m2
ArchiCADQuantities - Superficie de surface: 0.03 m2; Largeur cadre: 0.1 m; Profondeur de cadre: 0.3 m
Name | Length (m) = Longueur cadre (m) | OuterSurfaceArea (m2) | TotalSurfaceArea (m2) = GrossSurfaceArea (m2) | GrossVolume (m3) = NetVolume (m3) = Volume net (m3) | Altitude à Zéro du Projet (m) | Altitude à étage (m)
2 x Frame-Bnd-565 | 1.5 | 1.2 | 1.26 | 0.045 | 4.85 | -0.55
2 x Frame-Bnd-565 | 1.5 | 1.2 | 1.26 | 0.045 | 6.35 | 0.95
2 x Frame-Bnd-565 | 1.5 | 1.2 | 1.26 | 0.045 | 7.85 | 2.45
2 x Frame-Bnd-565 | 1.5 | 1.2 | 1.26 | 0.045 | 9.35 | 3.95
Frame-Bnd-565 | 1.275 | 1.02 | 1.08 | 0.03825 | 10.85 | 5.45
Frame-Bnd-565 | 1.27507 | 1.02005 | 1.08005 | 0.038252 | 10.85 | 5.45

# IfcMember: Traverse 60 x 100 (330)
Material: 25 % 359672764
ArchiCADProperties - Calque: A-WALL-CURT; Type: Cadre de mur-rideau; Verrouillé: no; Matériau de construction / Composite / Profil / Hachure: 25 % 359672764; Etat de rénovation: Existant; Afficher sur filtre de rénovation: Tous les filtres appropriés; Emplacement :: Grille secondaire; Type de cadre: En applique; Angle d'inclinaison: 0 deg; Classe de cadre: Traverse; Surface: Mtl-Iron
AC_Pset_RenovationAndPhasing - Renovation Status: Existing
BaseQuantities - CrossSectionArea: 0.006 m2
ArchiCADQuantities - Superficie de surface: 0.006 m2; Largeur cadre: 0.06 m; Profondeur de cadre: 0.1 m
Name | In | ID | Etage d'implantation | ID mur-rideau | Length (m) = Longueur cadre (m) | OuterSurfaceArea (m2) | TotalSurfaceArea (m2) = GrossSurfaceArea (m2) | GrossVolume (m3) = NetVolume (m3) = Volume net (m3) | Altitude à Zéro du Projet (m) | Altitude à étage (m)
Frame-Trs-922 | Rez de chaussée | Frame-Trs-922 | Rez de chaussée | CurtainWall_02 | 1.36 | 0.4352 | 0.4472 | 0.00816 | 2.8 | 2.8
34 x Frame-Trs-922 | Rez de chaussée | Frame-Trs-922 | Rez de chaussée | CurtainWall_02 | 1.42 | 0.4544 | 0.4664 | 0.00852 | 2.8 | 2.8
3 x Frame-Trs-922 | Rez de chaussée | Frame-Trs-922 | Rez de chaussée | CurtainWall_02 | 1.42 | 0.4544 | 0.4664 | 0.00852 | 2.8 | 2.8 | ArchiCADProperties - Nom de Zone: Réserve; Numéro de Zone: 010
Frame-Trs-963 | Rez de chaussée | Frame-Trs-963 | Rez de chaussée | CurtainWall_02 | 0.976827 | 0.312585 | 0.324585 | 0.00586096 | 2.8 | 2.8
Frame-Trs-227 | Rez de chaussée | Frame-Trs-227 | Rez de chaussée | CurtainWall_02 | 1.36 | 0.4352 | 0.4472 | 0.00816 | 4.3 | 4.3
34 x Frame-Trs-227 | Rez de chaussée | Frame-Trs-227 | Rez de chaussée | CurtainWall_02 | 1.42 | 0.4544 | 0.4664 | 0.00852 | 4.3 | 4.3
3 x Frame-Trs-227 | Rez de chaussée | Frame-Trs-227 | Rez de chaussée | CurtainWall_02 | 1.42 | 0.4544 | 0.4664 | 0.00852 | 4.3 | 4.3 | ArchiCADProperties - Nom de Zone: Réserve; Numéro de Zone: 010
Frame-Trs-227 | Rez de chaussée | Frame-Trs-227 | Rez de chaussée | CurtainWall_02 | 0.976827 | 0.312585 | 0.324585 | 0.00586096 | 4.3 | 4.3
Frame-Trs-571 | R+1 | Frame-Trs-571 | R+1 | CurtainWall_01 | 0.503709 | 0.161187 | 0.173187 | 0.00302225 | 10.85 | 5.45
Frame-Trs-571 | R+1 | Frame-Trs-571 | R+1 | CurtainWall_01 | 0.503709 | 0.161187 | 0.173187 | 0.00302225 | 9.35 | 3.95
Frame-Trs-571 | R+1 | Frame-Trs-571 | R+1 | CurtainWall_01 | 0.503709 | 0.161187 | 0.173187 | 0.00302225 | 7.85 | 2.45
Frame-Trs-571 | R+1 | Frame-Trs-571 | R+1 | CurtainWall_01 | 0.503709 | 0.161187 | 0.173187 | 0.00302225 | 6.35 | 0.95
Frame-Trs-424 | R+1 | Frame-Trs-424 | R+1 | CurtainWall_01 | 1.14355 | 0.365937 | 0.377937 | 0.00686132 | 6.4 | 1
Frame-Trs-422 | R+1 | Frame-Trs-422 | R+1 | CurtainWall_01 | 2.86 | 0.9152 | 0.9272 | 0.01716 | 6.4 | 1
Frame-Trs-425 | R+1 | Frame-Trs-425 | R+1 | CurtainWall_01 | 2.86 | 0.9152 | 0.9272 | 0.01716 | 7.9 | 2.5
Frame-Trs-426 | R+1 | Frame-Trs-426 | R+1 | CurtainWall_01 | 2.92 | 0.9344 | 0.9464 | 0.01752 | 7.9 | 2.5
Frame-Trs-427 | R+1 | Frame-Trs-427 | R+1 | CurtainWall_01 | 1.14355 | 0.365937 | 0.377937 | 0.00686132 | 7.9 | 2.5
Frame-Trs-432 | R+1 | Frame-Trs-432 | R+1 | CurtainWall_01 | 2.84365 | 0.909967 | 0.921967 | 0.0170619 | 6.4 | 1
Frame-Trs-434 | R+1 | Frame-Trs-434 | R+1 | CurtainWall_01 | 2.84365 | 0.909967 | 0.921967 | 0.0170619 | 7.9 | 2.5
Frame-Trs-436 | R+1 | Frame-Trs-436 | R+1 | CurtainWall_01 | 2.235 | 0.7152 | 0.7272 | 0.01341 | 7.9 | 2.5
Frame-Trs-437 | R+1 | Frame-Trs-437 | R+1 | CurtainWall_01 | 2.235 | 0.7152 | 0.7272 | 0.01341 | 6.4 | 1
Frame-Trs-446 | R+1 | Frame-Trs-446 | R+1 | CurtainWall_01 | 2.86 | 0.9152 | 0.9272 | 0.01716 | 9.4 | 4
Frame-Trs-447 | R+1 | Frame-Trs-447 | R+1 | CurtainWall_01 | 2.92 | 0.9344 | 0.9464 | 0.01752 | 9.4 | 4
Frame-Trs-448 | R+1 | Frame-Trs-448 | R+1 | CurtainWall_01 | 1.14355 | 0.365937 | 0.377937 | 0.00686132 | 9.4 | 4
Frame-Trs-449 | R+1 | Frame-Trs-449 | R+1 | CurtainWall_01 | 2.86 | 0.9152 | 0.9272 | 0.01716 | 10.9 | 5.5
Frame-Trs-450 | R+1 | Frame-Trs-450 | R+1 | CurtainWall_01 | 2.92 | 0.9344 | 0.9464 | 0.01752 | 10.9 | 5.5
Frame-Trs-451 | R+1 | Frame-Trs-451 | R+1 | CurtainWall_01 | 1.14355 | 0.365937 | 0.377937 | 0.00686132 | 10.9 | 5.5
Frame-Trs-452 | R+1 | Frame-Trs-452 | R+1 | CurtainWall_01 | 2.86 | 0.9152 | 0.9272 | 0.01716 | 12.4 | 7
Frame-Trs-453 | R+1 | Frame-Trs-453 | R+1 | CurtainWall_01 | 2.92 | 0.9344 | 0.9464 | 0.01752 | 12.4 | 7
Frame-Trs-454 | R+1 | Frame-Trs-454 | R+1 | CurtainWall_01 | 1.14355 | 0.365937 | 0.377937 | 0.00686132 | 12.4 | 7
Frame-Trs-455 | R+1 | Frame-Trs-455 | R+1 | CurtainWall_01 | 2.86 | 0.9152 | 0.9272 | 0.01716 | 13.9 | 8.5
Frame-Trs-456 | R+1 | Frame-Trs-456 | R+1 | CurtainWall_01 | 2.92 | 0.9344 | 0.9464 | 0.01752 | 13.9 | 8.5
Frame-Trs-457 | R+1 | Frame-Trs-457 | R+1 | CurtainWall_01 | 1.14355 | 0.365937 | 0.377937 | 0.00686132 | 13.9 | 8.5
Frame-Trs-458 | R+1 | Frame-Trs-458 | R+1 | CurtainWall_01 | 2.86 | 0.9152 | 0.9272 | 0.01716 | 15.4 | 10
Frame-Trs-459 | R+1 | Frame-Trs-459 | R+1 | CurtainWall_01 | 2.92 | 0.9344 | 0.9464 | 0.01752 | 15.4 | 10
Frame-Trs-460 | R+1 | Frame-Trs-460 | R+1 | CurtainWall_01 | 1.14355 | 0.365937 | 0.377937 | 0.00686132 | 15.4 | 10
Frame-Trs-461 | R+1 | Frame-Trs-461 | R+1 | CurtainWall_01 | 2.86 | 0.9152 | 0.9272 | 0.01716 | 16.9 | 11.5
Frame-Trs-462 | R+1 | Frame-Trs-462 | R+1 | CurtainWall_01 | 2.92 | 0.9344 | 0.9464 | 0.01752 | 16.9 | 11.5
Frame-Trs-463 | R+1 | Frame-Trs-463 | R+1 | CurtainWall_01 | 1.14355 | 0.365937 | 0.377937 | 0.00686132 | 16.9 | 11.5
Frame-Trs-423 | R+1 | Frame-Trs-423 | R+1 | CurtainWall_01 | 2.92 | 0.9344 | 0.9464 | 0.01752 | 6.4 | 1
Frame-Trs-471 | R+1 | Frame-Trs-471 | R+1 | CurtainWall_01 | 2.84365 | 0.909967 | 0.921967 | 0.0170619 | 9.4 | 4
Frame-Trs-473 | R+1 | Frame-Trs-473 | R+1 | CurtainWall_01 | 2.84365 | 0.909967 | 0.921967 | 0.0170619 | 10.9 | 5.5
Frame-Trs-475 | R+1 | Frame-Trs-475 | R+1 | CurtainWall_01 | 2.84365 | 0.909967 | 0.921967 | 0.0170619 | 12.4 | 7
Frame-Trs-477 | R+1 | Frame-Trs-477 | R+1 | CurtainWall_01 | 2.84365 | 0.909967 | 0.921967 | 0.0170619 | 13.9 | 8.5
Frame-Trs-479 | R+1 | Frame-Trs-479 | R+1 | CurtainWall_01 | 2.84365 | 0.909967 | 0.921967 | 0.0170619 | 15.4 | 10
Frame-Trs-481 | R+1 | Frame-Trs-481 | R+1 | CurtainWall_01 | 2.84365 | 0.909967 | 0.921967 | 0.0170619 | 16.9 | 11.5
Frame-Trs-485 | R+1 | Frame-Trs-485 | R+1 | CurtainWall_01 | 2.235 | 0.7152 | 0.7272 | 0.01341 | 16.9 | 11.5
Frame-Trs-486 | R+1 | Frame-Trs-486 | R+1 | CurtainWall_01 | 2.235 | 0.7152 | 0.7272 | 0.01341 | 15.4 | 10
Frame-Trs-487 | R+1 | Frame-Trs-487 | R+1 | CurtainWall_01 | 2.235 | 0.7152 | 0.7272 | 0.01341 | 13.9 | 8.5
Frame-Trs-488 | R+1 | Frame-Trs-488 | R+1 | CurtainWall_01 | 2.235 | 0.7152 | 0.7272 | 0.01341 | 12.4 | 7
Frame-Trs-489 | R+1 | Frame-Trs-489 | R+1 | CurtainWall_01 | 2.235 | 0.7152 | 0.7272 | 0.01341 | 10.9 | 5.5
Frame-Trs-490 | R+1 | Frame-Trs-490 | R+1 | CurtainWall_01 | 2.235 | 0.7152 | 0.7272 | 0.01341 | 9.4 | 4
Frame-Trs-487 | R+1 | Frame-Trs-487 | R+1 | CurtainWall_01 | 1.80138 | 0.576442 | 0.588442 | 0.0108083 | 10.85 | 5.45
Frame-Trs-487 | R+1 | Frame-Trs-487 | R+1 | CurtainWall_01 | 1.80138 | 0.576442 | 0.588442 | 0.0108083 | 9.35 | 3.95
Frame-Trs-487 | R+1 | Frame-Trs-487 | R+1 | CurtainWall_01 | 1.80138 | 0.576442 | 0.588442 | 0.0108083 | 7.85 | 2.45
Frame-Trs-487 | R+1 | Frame-Trs-487 | R+1 | CurtainWall_01 | 1.80138 | 0.576442 | 0.588442 | 0.0108083 | 6.35 | 0.95
Frame-Trs-001 | R+1 | Frame-Trs-001 | R+1 | CurtainWall_01 | 2.86 | 0.9152 | 0.9272 | 0.01716 | 6.9 | 1.5
Frame-Trs-002 | R+1 | Frame-Trs-002 | R+1 | CurtainWall_01 | 2.92 | 0.9344 | 0.9464 | 0.01752 | 6.9 | 1.5
Frame-Trs-004 | R+1 | Frame-Trs-004 | R+1 | CurtainWall_01 | 2.86 | 0.9152 | 0.9272 | 0.01716 | 8.4 | 3
Frame-Trs-005 | R+1 | Frame-Trs-005 | R+1 | CurtainWall_01 | 2.92 | 0.9344 | 0.9464 | 0.01752 | 8.4 | 3
Frame-Trs-007 | R+1 | Frame-Trs-007 | R+1 | CurtainWall_01 | 2.86 | 0.9152 | 0.9272 | 0.01716 | 9.9 | 4.5
Frame-Trs-008 | R+1 | Frame-Trs-008 | R+1 | CurtainWall_01 | 2.92 | 0.9344 | 0.9464 | 0.01752 | 9.9 | 4.5
Frame-Trs-010 | R+1 | Frame-Trs-010 | R+1 | CurtainWall_01 | 2.86 | 0.9152 | 0.9272 | 0.01716 | 11.4 | 6
Frame-Trs-011 | R+1 | Frame-Trs-011 | R+1 | CurtainWall_01 | 2.92 | 0.9344 | 0.9464 | 0.01752 | 11.4 | 6
Frame-Trs-013 | R+1 | Frame-Trs-013 | R+1 | CurtainWall_01 | 2.86 | 0.9152 | 0.9272 | 0.01716 | 12.9 | 7.5
Frame-Trs-014 | R+1 | Frame-Trs-014 | R+1 | CurtainWall_01 | 2.92 | 0.9344 | 0.9464 | 0.01752 | 12.9 | 7.5
Frame-Trs-016 | R+1 | Frame-Trs-016 | R+1 | CurtainWall_01 | 2.86 | 0.9152 | 0.9272 | 0.01716 | 14.4 | 9
Frame-Trs-017 | R+1 | Frame-Trs-017 | R+1 | CurtainWall_01 | 2.92 | 0.9344 | 0.9464 | 0.01752 | 14.4 | 9
Frame-Trs-019 | R+1 | Frame-Trs-019 | R+1 | CurtainWall_01 | 2.86 | 0.9152 | 0.9272 | 0.01716 | 15.9 | 10.5
Frame-Trs-020 | R+1 | Frame-Trs-020 | R+1 | CurtainWall_01 | 2.92 | 0.9344 | 0.9464 | 0.01752 | 15.9 | 10.5
Frame-Trs-038 | R+1 | Frame-Trs-038 | R+1 | CurtainWall_01 | 1.06529 | 0.340893 | 0.352893 | 0.00639174 | 15.9 | 10.5
Frame-Trs-039 | R+1 | Frame-Trs-039 | R+1 | CurtainWall_01 | 1.06529 | 0.340893 | 0.352893 | 0.00639174 | 14.4 | 9
Frame-Trs-040 | R+1 | Frame-Trs-040 | R+1 | CurtainWall_01 | 1.06529 | 0.340893 | 0.352893 | 0.00639174 | 12.9 | 7.5
Frame-Trs-041 | R+1 | Frame-Trs-041 | R+1 | CurtainWall_01 | 1.06529 | 0.340893 | 0.352893 | 0.00639174 | 11.4 | 6
Frame-Trs-042 | R+1 | Frame-Trs-042 | R+1 | CurtainWall_01 | 1.06529 | 0.340893 | 0.352893 | 0.00639174 | 9.9 | 4.5
Frame-Trs-043 | R+1 | Frame-Trs-043 | R+1 | CurtainWall_01 | 1.06529 | 0.340893 | 0.352893 | 0.00639174 | 8.4 | 3
Frame-Trs-044 | R+1 | Frame-Trs-044 | R+1 | CurtainWall_01 | 1.06529 | 0.340893 | 0.352893 | 0.00639174 | 6.9 | 1.5
Frame-Trs-752 | R+1 | Frame-Trs-752 | R+1 | CurtainWall_01 | 2.86 | 0.9152 | 0.9272 | 0.01716 | 5.9 | 0.5
2 x Frame-Trs-752 | R+1 | Frame-Trs-752 | R+1 | CurtainWall_01 | 2.92 | 0.9344 | 0.9464 | 0.01752 | 5.9 | 0.5
Frame-Trs-752 | R+1 | Frame-Trs-752 | R+1 | CurtainWall_01 | 2.86 | 0.9152 | 0.9272 | 0.01716 | 7.4 | 2
2 x Frame-Trs-752 | R+1 | Frame-Trs-752 | R+1 | CurtainWall_01 | 2.92 | 0.9344 | 0.9464 | 0.01752 | 7.4 | 2
Frame-Trs-752 | R+1 | Frame-Trs-752 | R+1 | CurtainWall_01 | 2.86 | 0.9152 | 0.9272 | 0.01716 | 8.9 | 3.5
2 x Frame-Trs-752 | R+1 | Frame-Trs-752 | R+1 | CurtainWall_01 | 2.92 | 0.9344 | 0.9464 | 0.01752 | 8.9 | 3.5
Frame-Trs-752 | R+1 | Frame-Trs-752 | R+1 | CurtainWall_01 | 2.86 | 0.9152 | 0.9272 | 0.01716 | 10.4 | 5
2 x Frame-Trs-752 | R+1 | Frame-Trs-752 | R+1 | CurtainWall_01 | 2.92 | 0.9344 | 0.9464 | 0.01752 | 10.4 | 5
Frame-Trs-752 | R+1 | Frame-Trs-752 | R+1 | CurtainWall_01 | 2.86 | 0.9152 | 0.9272 | 0.01716 | 11.9 | 6.5
2 x Frame-Trs-752 | R+1 | Frame-Trs-752 | R+1 | CurtainWall_01 | 2.92 | 0.9344 | 0.9464 | 0.01752 | 11.9 | 6.5
Frame-Trs-752 | R+1 | Frame-Trs-752 | R+1 | CurtainWall_01 | 2.86 | 0.9152 | 0.9272 | 0.01716 | 13.4 | 8
2 x Frame-Trs-752 | R+1 | Frame-Trs-752 | R+1 | CurtainWall_01 | 2.92 | 0.9344 | 0.9464 | 0.01752 | 13.4 | 8
Frame-Trs-752 | R+1 | Frame-Trs-752 | R+1 | CurtainWall_01 | 2.86 | 0.9152 | 0.9272 | 0.01716 | 14.9 | 9.5
2 x Frame-Trs-752 | R+1 | Frame-Trs-752 | R+1 | CurtainWall_01 | 2.92 | 0.9344 | 0.9464 | 0.01752 | 14.9 | 9.5
Frame-Trs-773 | R+1 | Frame-Trs-773 | R+1 | CurtainWall_01 | 2.86 | 0.9152 | 0.9272 | 0.01716 | 16.4 | 11
2 x Frame-Trs-773 | R+1 | Frame-Trs-773 | R+1 | CurtainWall_01 | 2.92 | 0.9344 | 0.9464 | 0.01752 | 16.4 | 11
Frame-Trs-757 | R+1 | Frame-Trs-757 | R+1 | CurtainWall_01 | 0.242419 | 0.0775741 | 0.0895741 | 0.00145451 | 7.4 | 2
Frame-Trs-752 | R+1 | Frame-Trs-752 | R+1 | CurtainWall_01 | 0.242419 | 0.0775741 | 0.0895741 | 0.00145451 | 14.9 | 9.5
Frame-Trs-755 | R+1 | Frame-Trs-755 | R+1 | CurtainWall_01 | 0.242419 | 0.0775741 | 0.0895741 | 0.00145451 | 10.4 | 5
Frame-Trs-756 | R+1 | Frame-Trs-756 | R+1 | CurtainWall_01 | 0.242419 | 0.0775741 | 0.0895741 | 0.00145451 | 8.9 | 3.5
Frame-Trs-754 | R+1 | Frame-Trs-754 | R+1 | CurtainWall_01 | 0.242419 | 0.0775741 | 0.0895741 | 0.00145451 | 11.9 | 6.5
Frame-Trs-753 | R+1 | Frame-Trs-753 | R+1 | CurtainWall_01 | 0.242419 | 0.0775741 | 0.0895741 | 0.00145451 | 13.4 | 8
Frame-Trs-773 | R+1 | Frame-Trs-773 | R+1 | CurtainWall_01 | 0.242419 | 0.0775741 | 0.0895741 | 0.00145451 | 16.4 | 11
Frame-Trs-758 | R+1 | Frame-Trs-758 | R+1 | CurtainWall_01 | 0.242419 | 0.0775741 | 0.0895741 | 0.00145451 | 5.9 | 0.5
Frame-Trs-769 | R+1 | Frame-Trs-769 | R+1 | CurtainWall_01 | 2.86 | 0.9152 | 0.9272 | 0.01716 | 5.9 | 0.5 | ArchiCADProperties - Nom de Zone: Plateau bureaux; Numéro de Zone: 005
2 x Frame-Trs-769 | R+1 | Frame-Trs-769 | R+1 | CurtainWall_01 | 2.92 | 0.9344 | 0.9464 | 0.01752 | 5.9 | 0.5 | ArchiCADProperties - Nom de Zone: Plateau bureaux; Numéro de Zone: 005
Frame-Trs-769 | R+1 | Frame-Trs-769 | R+1 | CurtainWall_01 | 2.86 | 0.9152 | 0.9272 | 0.01716 | 7.4 | 2 | ArchiCADProperties - Nom de Zone: Plateau bureaux; Numéro de Zone: 005
2 x Frame-Trs-769 | R+1 | Frame-Trs-769 | R+1 | CurtainWall_01 | 2.92 | 0.9344 | 0.9464 | 0.01752 | 7.4 | 2 | ArchiCADProperties - Nom de Zone: Plateau bureaux; Numéro de Zone: 005
Frame-Trs-769 | R+1 | Frame-Trs-769 | R+1 | CurtainWall_01 | 2.86 | 0.9152 | 0.9272 | 0.01716 | 8.9 | 3.5 | ArchiCADProperties - Nom de Zone: Plateau bureaux; Numéro de Zone: 005
2 x Frame-Trs-769 | R+1 | Frame-Trs-769 | R+1 | CurtainWall_01 | 2.92 | 0.9344 | 0.9464 | 0.01752 | 8.9 | 3.5 | ArchiCADProperties - Nom de Zone: Plateau bureaux; Numéro de Zone: 005
Frame-Trs-769 | R+1 | Frame-Trs-769 | R+1 | CurtainWall_01 | 2.86 | 0.9152 | 0.9272 | 0.01716 | 10.4 | 5 | ArchiCADProperties - Nom de Zone: Plateau bureaux; Numéro de Zone: 005
2 x Frame-Trs-769 | R+1 | Frame-Trs-769 | R+1 | CurtainWall_01 | 2.92 | 0.9344 | 0.9464 | 0.01752 | 10.4 | 5 | ArchiCADProperties - Nom de Zone: Plateau bureaux; Numéro de Zone: 005
Frame-Trs-769 | R+1 | Frame-Trs-769 | R+1 | CurtainWall_01 | 2.86 | 0.9152 | 0.9272 | 0.01716 | 11.9 | 6.5 | ArchiCADProperties - Nom de Zone: Plateau bureaux; Numéro de Zone: 005
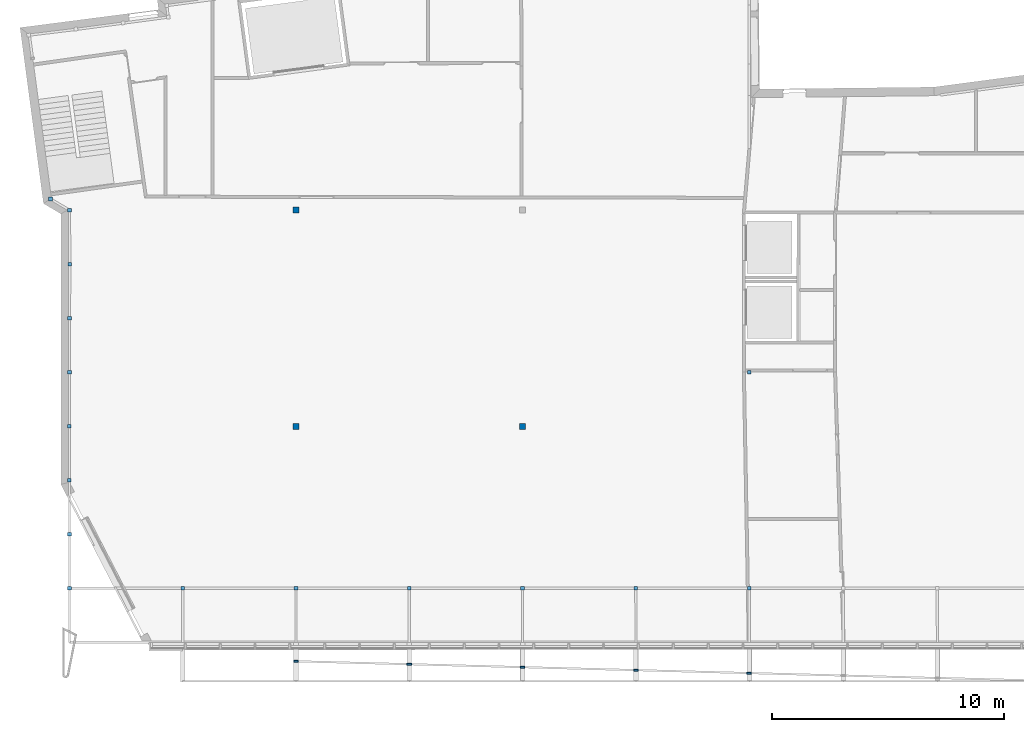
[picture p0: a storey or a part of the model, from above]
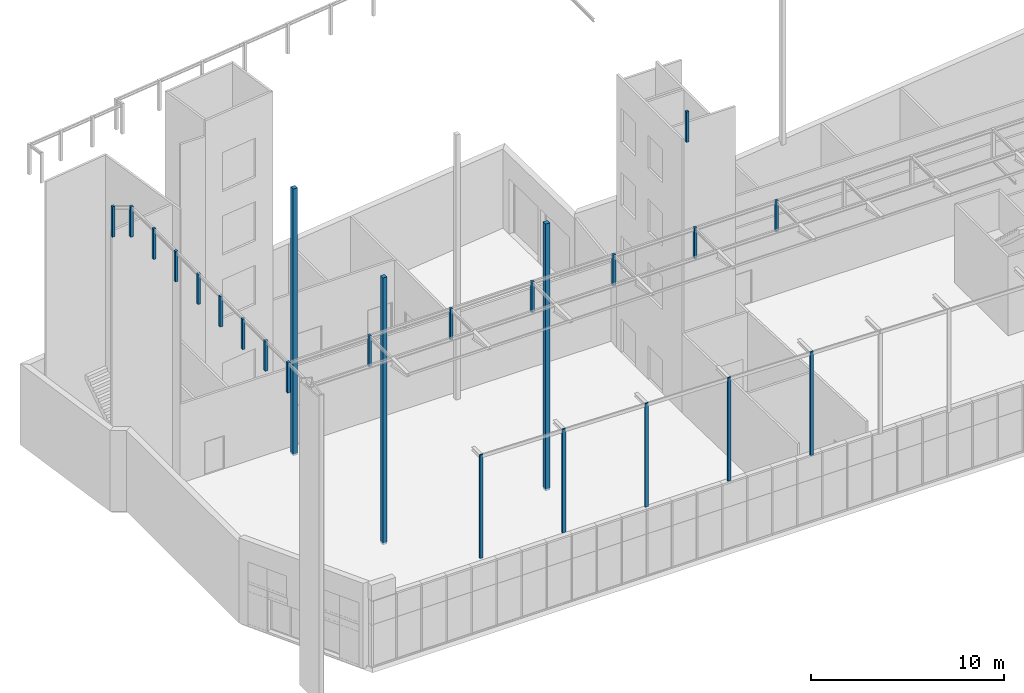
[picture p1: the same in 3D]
Properties of the parts of a building model (IFC2X3), part 11 of 19

# IfcMember: Traverse 60 x 100 (330)
Name | In | ID | Etage d'implantation | ID mur-rideau | Length (m) = Longueur cadre (m) | OuterSurfaceArea (m2) | TotalSurfaceArea (m2) = GrossSurfaceArea (m2) | GrossVolume (m3) = NetVolume (m3) = Volume net (m3) | Altitude à Zéro du Projet (m) | Altitude à étage (m)
2 x Frame-Trs-769 | R+1 | Frame-Trs-769 | R+1 | CurtainWall_01 | 2.92 | 0.9344 | 0.9464 | 0.01752 | 11.9 | 6.5 | ArchiCADProperties - Nom de Zone: Plateau bureaux; Numéro de Zone: 005
Frame-Trs-769 | R+1 | Frame-Trs-769 | R+1 | CurtainWall_01 | 2.86 | 0.9152 | 0.9272 | 0.01716 | 13.4 | 8 | ArchiCADProperties - Nom de Zone: Plateau bureaux; Numéro de Zone: 005
2 x Frame-Trs-769 | R+1 | Frame-Trs-769 | R+1 | CurtainWall_01 | 2.92 | 0.9344 | 0.9464 | 0.01752 | 13.4 | 8 | ArchiCADProperties - Nom de Zone: Plateau bureaux; Numéro de Zone: 005
Frame-Trs-769 | R+1 | Frame-Trs-769 | R+1 | CurtainWall_01 | 2.86 | 0.9152 | 0.9272 | 0.01716 | 14.9 | 9.5 | ArchiCADProperties - Nom de Zone: Plateau bureaux; Numéro de Zone: 005
2 x Frame-Trs-769 | R+1 | Frame-Trs-769 | R+1 | CurtainWall_01 | 2.92 | 0.9344 | 0.9464 | 0.01752 | 14.9 | 9.5 | ArchiCADProperties - Nom de Zone: Plateau bureaux; Numéro de Zone: 005
Frame-Trs-783 | R+1 | Frame-Trs-783 | R+1 | CurtainWall_01 | 2.86 | 0.9152 | 0.9272 | 0.01716 | 16.4 | 11 | ArchiCADProperties - Nom de Zone: Plateau bureaux; Numéro de Zone: 005
2 x Frame-Trs-783 | R+1 | Frame-Trs-783 | R+1 | CurtainWall_01 | 2.92 | 0.9344 | 0.9464 | 0.01752 | 16.4 | 11 | ArchiCADProperties - Nom de Zone: Plateau bureaux; Numéro de Zone: 005
Frame-Trs-783 | R+1 | Frame-Trs-783 | R+1 | CurtainWall_01 | 2.39265 | 0.765648 | 0.777648 | 0.0143559 | 16.4 | 11 | ArchiCADProperties - Nom de Zone: Plateau bureaux; Numéro de Zone: 005
Frame-Trs-769 | R+1 | Frame-Trs-769 | R+1 | CurtainWall_01 | 2.39265 | 0.765648 | 0.777648 | 0.0143559 | 14.9 | 9.5 | ArchiCADProperties - Nom de Zone: Plateau bureaux; Numéro de Zone: 005
Frame-Trs-769 | R+1 | Frame-Trs-769 | R+1 | CurtainWall_01 | 2.39265 | 0.765648 | 0.777648 | 0.0143559 | 13.4 | 8 | ArchiCADProperties - Nom de Zone: Plateau bureaux; Numéro de Zone: 005
Frame-Trs-769 | R+1 | Frame-Trs-769 | R+1 | CurtainWall_01 | 2.39265 | 0.765648 | 0.777648 | 0.0143559 | 11.9 | 6.5 | ArchiCADProperties - Nom de Zone: Plateau bureaux; Numéro de Zone: 005
Frame-Trs-769 | R+1 | Frame-Trs-769 | R+1 | CurtainWall_01 | 2.39265 | 0.765648 | 0.777648 | 0.0143559 | 10.4 | 5 | ArchiCADProperties - Nom de Zone: Plateau bureaux; Numéro de Zone: 005
Frame-Trs-769 | R+1 | Frame-Trs-769 | R+1 | CurtainWall_01 | 2.39265 | 0.765648 | 0.777648 | 0.0143559 | 8.9 | 3.5 | ArchiCADProperties - Nom de Zone: Plateau bureaux; Numéro de Zone: 005
Frame-Trs-769 | R+1 | Frame-Trs-769 | R+1 | CurtainWall_01 | 2.39265 | 0.765648 | 0.777648 | 0.0143559 | 7.4 | 2 | ArchiCADProperties - Nom de Zone: Plateau bureaux; Numéro de Zone: 005
Frame-Trs-769 | R+1 | Frame-Trs-769 | R+1 | CurtainWall_01 | 2.39265 | 0.765648 | 0.777648 | 0.0143559 | 5.9 | 0.5 | ArchiCADProperties - Nom de Zone: Plateau bureaux; Numéro de Zone: 005
Frame-Trs-946 | R+1 | Frame-Trs-946 | R+1 | CurtainWall_01 | 2.86 | 0.9152 | 0.9272 | 0.01716 | 6.9 | 1.5
Frame-Trs-947 | R+1 | Frame-Trs-947 | R+1 | CurtainWall_01 | 2.92 | 0.9344 | 0.9464 | 0.01752 | 6.9 | 1.5
Frame-Trs-949 | R+1 | Frame-Trs-949 | R+1 | CurtainWall_01 | 2.86 | 0.9152 | 0.9272 | 0.01716 | 8.4 | 3
Frame-Trs-950 | R+1 | Frame-Trs-950 | R+1 | CurtainWall_01 | 2.92 | 0.9344 | 0.9464 | 0.01752 | 8.4 | 3
Frame-Trs-952 | R+1 | Frame-Trs-952 | R+1 | CurtainWall_01 | 2.86 | 0.9152 | 0.9272 | 0.01716 | 9.9 | 4.5
Frame-Trs-953 | R+1 | Frame-Trs-953 | R+1 | CurtainWall_01 | 2.92 | 0.9344 | 0.9464 | 0.01752 | 9.9 | 4.5
Frame-Trs-955 | R+1 | Frame-Trs-955 | R+1 | CurtainWall_01 | 2.86 | 0.9152 | 0.9272 | 0.01716 | 11.4 | 6
Frame-Trs-956 | R+1 | Frame-Trs-956 | R+1 | CurtainWall_01 | 2.92 | 0.9344 | 0.9464 | 0.01752 | 11.4 | 6
Frame-Trs-958 | R+1 | Frame-Trs-958 | R+1 | CurtainWall_01 | 2.86 | 0.9152 | 0.9272 | 0.01716 | 12.9 | 7.5
Frame-Trs-959 | R+1 | Frame-Trs-959 | R+1 | CurtainWall_01 | 2.92 | 0.9344 | 0.9464 | 0.01752 | 12.9 | 7.5
Frame-Trs-961 | R+1 | Frame-Trs-961 | R+1 | CurtainWall_01 | 2.86 | 0.9152 | 0.9272 | 0.01716 | 14.4 | 9
Frame-Trs-962 | R+1 | Frame-Trs-962 | R+1 | CurtainWall_01 | 2.92 | 0.9344 | 0.9464 | 0.01752 | 14.4 | 9
Frame-Trs-964 | R+1 | Frame-Trs-964 | R+1 | CurtainWall_01 | 2.86 | 0.9152 | 0.9272 | 0.01716 | 15.9 | 10.5
Frame-Trs-965 | R+1 | Frame-Trs-965 | R+1 | CurtainWall_01 | 2.92 | 0.9344 | 0.9464 | 0.01752 | 15.9 | 10.5
Frame-Trs-983 | R+1 | Frame-Trs-983 | R+1 | CurtainWall_01 | 1.96 | 0.6272 | 0.6392 | 0.01176 | 15.9 | 10.5
Frame-Trs-984 | R+1 | Frame-Trs-984 | R+1 | CurtainWall_01 | 1.96 | 0.6272 | 0.6392 | 0.01176 | 14.4 | 9
Frame-Trs-985 | R+1 | Frame-Trs-985 | R+1 | CurtainWall_01 | 1.96 | 0.6272 | 0.6392 | 0.01176 | 12.9 | 7.5
Frame-Trs-986 | R+1 | Frame-Trs-986 | R+1 | CurtainWall_01 | 1.96 | 0.6272 | 0.6392 | 0.01176 | 11.4 | 6
Frame-Trs-987 | R+1 | Frame-Trs-987 | R+1 | CurtainWall_01 | 1.96 | 0.6272 | 0.6392 | 0.01176 | 9.9 | 4.5
Frame-Trs-988 | R+1 | Frame-Trs-988 | R+1 | CurtainWall_01 | 1.96 | 0.6272 | 0.6392 | 0.01176 | 8.4 | 3
Frame-Trs-989 | R+1 | Frame-Trs-989 | R+1 | CurtainWall_01 | 1.96 | 0.6272 | 0.6392 | 0.01176 | 6.9 | 1.5
Frame-Trs-501 | R+1 | Frame-Trs-501 | R+1 | CurtainWall_01 | 2.91 | 0.9312 | 0.9432 | 0.01746 | 6.35 | 0.95
13 x Frame-Trs-501 | R+1 | Frame-Trs-501 | R+1 | CurtainWall_01 | 2.92 | 0.9344 | 0.9464 | 0.01752 | 6.35 | 0.95
Frame-Trs-501 | R+1 | Frame-Trs-501 | R+1 | CurtainWall_01 | 2.91 | 0.9312 | 0.9432 | 0.01746 | 7.85 | 2.45
13 x Frame-Trs-501 | R+1 | Frame-Trs-501 | R+1 | CurtainWall_01 | 2.92 | 0.9344 | 0.9464 | 0.01752 | 7.85 | 2.45
Frame-Trs-501 | R+1 | Frame-Trs-501 | R+1 | CurtainWall_01 | 2.91 | 0.9312 | 0.9432 | 0.01746 | 9.35 | 3.95
13 x Frame-Trs-501 | R+1 | Frame-Trs-501 | R+1 | CurtainWall_01 | 2.92 | 0.9344 | 0.9464 | 0.01752 | 9.35 | 3.95
Frame-Trs-501 | R+1 | Frame-Trs-501 | R+1 | CurtainWall_01 | 2.91 | 0.9312 | 0.9432 | 0.01746 | 10.85 | 5.45
13 x Frame-Trs-501 | R+1 | Frame-Trs-501 | R+1 | CurtainWall_01 | 2.92 | 0.9344 | 0.9464 | 0.01752 | 10.85 | 5.45
Frame-Trs-606 | R+1 | Frame-Trs-606 | R+1 | CurtainWall_01 | 0.447258 | 0.143123 | 0.155123 | 0.00268355 | 10.85 | 5.45
Frame-Trs-607 | R+1 | Frame-Trs-607 | R+1 | CurtainWall_01 | 0.447258 | 0.143123 | 0.155123 | 0.00268355 | 9.35 | 3.95
Frame-Trs-608 | R+1 | Frame-Trs-608 | R+1 | CurtainWall_01 | 0.447258 | 0.143123 | 0.155123 | 0.00268355 | 7.85 | 2.45
Frame-Trs-609 | R+1 | Frame-Trs-609 | R+1 | CurtainWall_01 | 0.447258 | 0.143123 | 0.155123 | 0.00268355 | 6.35 | 0.95
Frame-Trs-078 | Mezzannine | Frame-Trs-078 | Mezzannine | CurtainWall_02 | 0.682687 | 0.21846 | 0.23046 | 0.00409612 | 2.8 | -6.625
Frame-Trs-030 | Mezzannine | Frame-Trs-030 | Mezzannine | CurtainWall_02 | 0.82 | 0.2624 | 0.2744 | 0.00492 | 4.3 | -5.125
Frame-Trs-029 | Mezzannine | Frame-Trs-029 | Mezzannine | CurtainWall_02 | 0.82 | 0.2624 | 0.2744 | 0.00492 | 4.3 | -5.125
Frame-Trs-013 | Mezzannine | Frame-Trs-013 | Mezzannine | CurtainWall_02 | 0.76 | 0.2432 | 0.2552 | 0.00456 | 2.8 | -6.625
17 x Frame-Trs-013 | Mezzannine | Frame-Trs-013 | Mezzannine | CurtainWall_02 | 0.82 | 0.2624 | 0.2744 | 0.00492 | 2.8 | -6.625
Frame-Trs-077 | Mezzannine | Frame-Trs-077 | Mezzannine | CurtainWall_02 | 0.682687 | 0.21846 | 0.23046 | 0.00409612 | 4.3 | -5.125
Frame-Trs-028 | Mezzannine | Frame-Trs-028 | Mezzannine | CurtainWall_02 | 0.82 | 0.2624 | 0.2744 | 0.00492 | 4.3 | -5.125
Frame-Trs-027 | Mezzannine | Frame-Trs-027 | Mezzannine | CurtainWall_02 | 0.82 | 0.2624 | 0.2744 | 0.00492 | 4.3 | -5.125
Frame-Trs-031 | Mezzannine | Frame-Trs-031 | Mezzannine | CurtainWall_02 | 0.82 | 0.2624 | 0.2744 | 0.00492 | 4.3 | -5.125
Frame-Trs-032 | Mezzannine | Frame-Trs-032 | Mezzannine | CurtainWall_02 | 0.82 | 0.2624 | 0.2744 | 0.00492 | 4.3 | -5.125
Frame-Trs-033 | Mezzannine | Frame-Trs-033 | Mezzannine | CurtainWall_02 | 0.82 | 0.2624 | 0.2744 | 0.00492 | 4.3 | -5.125
Frame-Trs-016 | Mezzannine | Frame-Trs-016 | Mezzannine | CurtainWall_02 | 0.76 | 0.2432 | 0.2552 | 0.00456 | 4.3 | -5.125
Frame-Trs-017 | Mezzannine | Frame-Trs-017 | Mezzannine | CurtainWall_02 | 0.82 | 0.2624 | 0.2744 | 0.00492 | 4.3 | -5.125
Frame-Trs-018 | Mezzannine | Frame-Trs-018 | Mezzannine | CurtainWall_02 | 0.82 | 0.2624 | 0.2744 | 0.00492 | 4.3 | -5.125
Frame-Trs-019 | Mezzannine | Frame-Trs-019 | Mezzannine | CurtainWall_02 | 0.82 | 0.2624 | 0.2744 | 0.00492 | 4.3 | -5.125
Frame-Trs-020 | Mezzannine | Frame-Trs-020 | Mezzannine | CurtainWall_02 | 0.82 | 0.2624 | 0.2744 | 0.00492 | 4.3 | -5.125
Frame-Trs-021 | Mezzannine | Frame-Trs-021 | Mezzannine | CurtainWall_02 | 0.82 | 0.2624 | 0.2744 | 0.00492 | 4.3 | -5.125
Frame-Trs-022 | Mezzannine | Frame-Trs-022 | Mezzannine | CurtainWall_02 | 0.82 | 0.2624 | 0.2744 | 0.00492 | 4.3 | -5.125
Frame-Trs-023 | Mezzannine | Frame-Trs-023 | Mezzannine | CurtainWall_02 | 0.82 | 0.2624 | 0.2744 | 0.00492 | 4.3 | -5.125
Frame-Trs-024 | Mezzannine | Frame-Trs-024 | Mezzannine | CurtainWall_02 | 0.82 | 0.2624 | 0.2744 | 0.00492 | 4.3 | -5.125
Frame-Trs-025 | Mezzannine | Frame-Trs-025 | Mezzannine | CurtainWall_02 | 0.82 | 0.2624 | 0.2744 | 0.00492 | 4.3 | -5.125
Frame-Trs-026 | Mezzannine | Frame-Trs-026 | Mezzannine | CurtainWall_02 | 0.82 | 0.2624 | 0.2744 | 0.00492 | 4.3 | -5.125

# IfcOpeningElement (175)
Name | In | Depth (m) | Height (m) | Width (m) | Area (m2) | Volume (m3)
10 x DOOR_1000 | Rez de chaussée | 0.13 | 2.1 | 1 | 2.1 | 0.0993
4 x DOOR_1000 | Rez de chaussée | 0.13 | 2.1 | 0.9 | 1.89 | 0.09066
3 x DOOR_1000 | Rez de chaussée | 0.13 | 2.1 | 1 | 2.1 | 0.102432
4 x DOOR_1007 | Rez de chaussée | 0.13 | 2.1 | 1.5 | 3.15 | 0.126
4 x DOOR_1006 | Rez de chaussée | 0.13 | 2.1 | 1.5 | 3.15 | 0.126
4 x WD - 003 | Rez de chaussée | 0.37 | 2.7 | 1.2 | 3.24 | 0.065552
8 x WD - 003 | Rez de chaussée | 0.37 | 1.38165 | 1.2 | 1.65798 | 0.0392131
4 x WD - 003 | Rez de chaussée | 0.37 | 0.5 | 1.2 | 0.6 | 0.023696
4 x DOOR | Rez de chaussée | 0.37 | 2.1 | 1.2 | 2.52 | 0.051805
2 x DOOR | Rez de chaussée | 0.37 | 2.1 | 2 | 4.2 | 0.0752371
4 x DOOR | Rez de chaussée | 0.13 | 2.5 | 1.5 | 3.75 | 0.1692
9 x DOOR | Rez de chaussée | 0.13 | 2.1 | 1.5 | 3.15 | 0.1428
DOOR | Rez de chaussée | 0.37 | 2.1 | 1.2 | 2.52 | 0.1167
DOOR_1000 | Rez de chaussée | 0.37 | 2.1 | 1 | 2.1 | 0.0993
2 x DOOR | Rez de chaussée | 0.37 | 3.5 | 2.94934 | 10.3227 | 0.442455
DOOR | Rez de chaussée | 0.37 | 2.1 | 1.25889 | 2.64368 | 0.121824
2 x Slab Opening | Rez de chaussée
4 x DOOR_1007 | Rez de chaussée | 0.13 | 2.47221 | 2.16 | 5.33998 | 0.213599
DOOR | Rez de chaussée | 0.13 | 2.1 | 1.2 | 2.52 | 0.1167
DOOR | Rez de chaussée | 0.13 | 2.1 | 2.35 | 4.935 | 0.21675
7 x DOOR_1000 | R+1 | 0.13 | 2.1 | 1 | 2.1 | 0.0993
6 x Slab Opening | R+1
3 x DOOR | R+1 | 0.13 | 2.1 | 1.5 | 3.15 | 0.1428
3 x DOOR_1000 | R+1 | 0.13 | 2.1 | 1 | 2.1 | 0.102432
WD - 002 | R+1 | 0.37 | 4 | 42.4744 | 169.898 | 0
WD - 004 | R+1 | 0.287 | 2 | 0.9 | 1.8 | 0.0240625
WD - 004 | R+1 | 0.287 | 3 | 0.9 | 2.7 | 0.0330312
DOOR | R+1 | 0.13 | 2.1 | 1.39592 | 2.93143 | 0.133745
4 x DOOR | Mezzannine | 0.13 | 2.1 | 1.5 | 3.15 | 0.1428
7 x DOOR_1000 | Mezzannine | 0.13 | 2.1 | 1 | 2.1 | 0.0993
3 x DOOR_1000 | Mezzannine | 0.13 | 2.1 | 1 | 2.1 | 0.102432
WD - 002 | Mezzannine | 0.37 | 2.225 | 42.5225 | 94.6126 | 0
2 x WD - 004 | Mezzannine | 0.287 | 2 | 0.9 | 1.8 | 0.0240625
5 x Slab Opening | Mezzannine
DOOR | R+2 | 0.13 | 2.1 | 1.39592 | 2.93143 | 0.133745
3 x DOOR | R+2 | 0.13 | 2.1 | 1.5 | 3.15 | 0.1428
6 x Slab Opening | R+2
6 x DOOR_1000 | R+2 | 0.13 | 2.1 | 1 | 2.1 | 0.0993
3 x DOOR_1000 | R+2 | 0.13 | 2.1 | 1 | 2.1 | 0.102432
15 x Window_1200 | R+2 | 0.37 | 1.5 | 1.2 | 1.8 | 0.0185
DOOR_1000 | R+2 | 0.18 | 2.1 | 1 | 2.1 | 0.0993
WD - 004 | R+2 | 0.287 | 2 | 0.9 | 1.8 | 0.0240625
WD - 004 | R+2 | 0.287 | 1.95 | 0.9 | 1.755 | 0.023625
3 x Slab Opening | Toiture
DOOR_1000 | Toiture | 0.13 | 1.84981 | 1 | 1.84981 | 0.0993
DOOR_1000 | Toiture | 0.13 | 2.07891 | 1 | 2.03517 | 0.0993
WD - 001 | Toiture | 0.37 | 1.92009 | 6 | 11.2748 | 0.049
WD - 001 | Toiture | 0.37 | 1.87813 | 6 | 11.2688 | 0.049
WD - 002 | Toiture | 0.37 | 1.87813 | 6 | 11.2688 | 0.049
WD - 003 | Toiture | 0.37 | 1.87813 | 6 | 11.2688 | 0.049
7 x WD - 004 | Toiture | 0.37 | 1.84576 | 6 | 11.0745 | 0.049
WD - 001 | Toiture | 0.37 | 2 | 9.22652 | 18.453 | 0.0663897
WD - 002 | Toiture | 0.37 | 2 | 10.7309 | 21.4617 | 0.0726543
DOOR_1000 | Etage | 0.28 | 2.1 | 1 | 2.1 | 0.0993
DOOR_1000 | Etage | 0.37 | 2.1 | 1 | 2.1 | 0.0993

# IfcPlate: Panneau principal 1037 x 1490 x 20, Panel-Dist-997
In: Rez de chaussée
Material: Background 7019220
ArchiCADProperties - ID: Panel-Dist-997; Etage d'implantation: Rez de chaussée; Calque: A-WALL-CURT; Type: Panneau de mur-rideau; Verrouillé: no; Matériau de construction / Composite / Profil / Hachure: Background 7019220; Etat de rénovation: Existant; Afficher sur filtre de rénovation: Tous les filtres appropriés; Type de panneau: Générique; Angle par rapport nord: 180 deg; Abbréviation d'orientation: S; Angle d'inclinaison: 90 deg; Fonction: Fixe; Surface extérieure: Glass-Blue; Surface intérieure: Glass-Blue; Surface latérale: Glass-Blue; Classe de panneau: Panneau principal; ID mur-rideau: CurtainWall_02
AC_Pset_RenovationAndPhasing - Renovation Status: Existing
BaseQuantities - Width: 0.976827 m; Perimeter: 4.83365 m; GrossArea: 1.54487 m2; NetArea: 1.40663 m2; GrossVolume: 0.0308975 m3; NetVolume: 0.0281326 m3
ArchiCADQuantities - Altitude à Zéro du Projet: 2.8 m; Altitude à étage: 2.8 m; Superficie de surface: 1.40663 m2; Volume net: 0.0281326 m3; Epaisseur: 0.02 m; Périmètre: 4.83365 m; Surface brute: 1.54487 m2; Surface nominale: 1.40663 m2; Largeur: 0.976827 m; Largeur nominale: 0.976827 m; Hauteur: 1.44 m; Hauteur nominale: 1.44 m

# IfcPlate: Panneau principal 1125 x 1425 x 20, Panel-Main-545
In: R+1
Material: Background 7019220
ArchiCADProperties - ID: Panel-Main-545; Etage d'implantation: R+1; Calque: A-WALL-CURT; Type: Panneau de mur-rideau; Verrouillé: no; Matériau de construction / Composite / Profil / Hachure: Background 7019220; Etat de rénovation: Existant; Afficher sur filtre de rénovation: Tous les filtres appropriés; Type de panneau: Générique; Angle par rapport nord: -90 deg; Abbréviation d'orientation: E; Angle d'inclinaison: 90 deg; Fonction: Fixe; Surface extérieure: Glass-Blue; Surface intérieure: Glass-Blue; Surface latérale: Glass-Blue; Classe de panneau: Panneau principal; ID mur-rideau: CurtainWall_01
AC_Pset_RenovationAndPhasing - Renovation Status: Existing
BaseQuantities - Width: 1.06529 m; Perimeter: 4.87058 m; GrossArea: 1.60354 m2; NetArea: 1.45945 m2; GrossVolume: 0.0320708 m3; NetVolume: 0.0291889 m3
ArchiCADQuantities - Altitude à Zéro du Projet: 15.9 m; Altitude à étage: 10.5 m; Superficie de surface: 1.45945 m2; Volume net: 0.0291889 m3; Epaisseur: 0.02 m; Périmètre: 4.87058 m; Surface brute: 1.60354 m2; Surface nominale: 1.45945 m2; Largeur: 1.06529 m; Largeur nominale: 1.06529 m; Hauteur: 1.37 m; Hauteur nominale: 1.37 m

# IfcPlate: Panneau principal 1125 x 1490 x 20 (3)
In: R+1
Material: Background 7019220
ArchiCADProperties - Etage d'implantation: R+1; Calque: A-WALL-CURT; Type: Panneau de mur-rideau; Verrouillé: no; Matériau de construction / Composite / Profil / Hachure: Background 7019220; Etat de rénovation: Existant; Afficher sur filtre de rénovation: Tous les filtres appropriés; Type de panneau: Générique; Angle par rapport nord: -90 deg; Abbréviation d'orientation: E; Angle d'inclinaison: 90 deg; Fonction: Fixe; Surface extérieure: Glass-Blue; Surface intérieure: Glass-Blue; Surface latérale: Glass-Blue; Classe de panneau: Panneau principal; ID mur-rideau: CurtainWall_01
AC_Pset_RenovationAndPhasing - Renovation Status: Existing
BaseQuantities - Width: 1.06529 m; Perimeter: 5.01058 m; GrossArea: 1.67668 m2; NetArea: 1.53402 m2; GrossVolume: 0.0335336 m3; NetVolume: 0.0306804 m3
ArchiCADQuantities - Superficie de surface: 1.53402 m2; Volume net: 0.0306804 m3; Epaisseur: 0.02 m; Périmètre: 5.01058 m; Surface brute: 1.67668 m2; Surface nominale: 1.53402 m2; Largeur: 1.06529 m; Largeur nominale: 1.06529 m; Hauteur: 1.44 m; Hauteur nominale: 1.44 m
Name | ID | Altitude à Zéro du Projet (m) | Altitude à étage (m)
Panel-Main-539 | Panel-Main-539 | 6.9 | 1.5
Panel-Main-541 | Panel-Main-541 | 9.9 | 4.5
Panel-Main-543 | Panel-Main-543 | 12.9 | 7.5

# IfcPlate: Panneau principal 1280 x 1490 x 20 (4)
In: R+1
Material: Background 7019220
ArchiCADProperties - Etage d'implantation: R+1; Calque: A-WALL-CURT; Type: Panneau de mur-rideau; Verrouillé: no; Matériau de construction / Composite / Profil / Hachure: Background 7019220; Etat de rénovation: Existant; Afficher sur filtre de rénovation: Tous les filtres appropriés; Type de panneau: Générique; Angle par rapport nord: 89.9238 deg; Abbréviation d'orientation: O; Angle d'inclinaison: 90 deg; Fonction: Fixe; Surface extérieure: Glass-Blue; Surface intérieure: Glass-Blue; Surface latérale: Glass-Blue; Classe de panneau: Panneau principal; ID mur-rideau: CurtainWall_01
AC_Pset_RenovationAndPhasing - Renovation Status: Existing
BaseQuantities - Width: 1.20363 m; Perimeter: 5.28727 m; GrossArea: 1.90756 m2; NetArea: 1.73323 m2; GrossVolume: 0.0381511 m3; NetVolume: 0.0346646 m3
ArchiCADQuantities - Superficie de surface: 1.73323 m2; Volume net: 0.0346646 m3; Epaisseur: 0.02 m; Périmètre: 5.28727 m; Surface brute: 1.90756 m2; Surface nominale: 1.73323 m2; Largeur: 1.20363 m; Largeur nominale: 1.20363 m; Hauteur: 1.44 m; Hauteur nominale: 1.44 m
Name | ID | Altitude à Zéro du Projet (m) | Altitude à étage (m)
Panel-Main-112 | Panel-Main-112 | 6.4 | 1
Panel-Main-117 | Panel-Main-117 | 9.4 | 4
Panel-Main-118 | Panel-Main-118 | 12.4 | 7
Panel-Main-119 | Panel-Main-119 | 15.4 | 10

# IfcPlate: Panneau principal 1420 x 1490 x 20, Panel-Dist-997
In: Rez de chaussée
Material: Background 7019220
ArchiCADProperties - ID: Panel-Dist-997; Etage d'implantation: Rez de chaussée; Calque: A-WALL-CURT; Type: Panneau de mur-rideau; Verrouillé: no; Matériau de construction / Composite / Profil / Hachure: Background 7019220; Etat de rénovation: Existant; Afficher sur filtre de rénovation: Tous les filtres appropriés; Type de panneau: Générique; Angle par rapport nord: 180 deg; Abbréviation d'orientation: S; Angle d'inclinaison: 90 deg; Fonction: Fixe; Surface extérieure: Glass-Blue; Surface intérieure: Glass-Blue; Surface latérale: Glass-Blue; Classe de panneau: Panneau principal; ID mur-rideau: CurtainWall_02
AC_Pset_RenovationAndPhasing - Renovation Status: Existing
BaseQuantities - Width: 1.36 m; Perimeter: 5.6 m; GrossArea: 2.1158 m2; NetArea: 1.9584 m2; GrossVolume: 0.042316 m3; NetVolume: 0.039168 m3
ArchiCADQuantities - Altitude à Zéro du Projet: 2.8 m; Altitude à étage: 2.8 m; Superficie de surface: 1.9584 m2; Volume net: 0.039168 m3; Epaisseur: 0.02 m; Périmètre: 5.6 m; Surface brute: 2.1158 m2; Surface nominale: 1.9584 m2; Largeur: 1.36 m; Largeur nominale: 1.36 m; Hauteur: 1.44 m; Hauteur nominale: 1.44 m

# IfcPlate: Panneau principal 1480 x 1490 x 20 (18)
In: Rez de chaussée
Material: Background 7019220
ArchiCADProperties - ID: Panel-Dist-997; Etage d'implantation: Rez de chaussée; Calque: A-WALL-CURT; Type: Panneau de mur-rideau; Verrouillé: no; Matériau de construction / Composite / Profil / Hachure: Background 7019220; Etat de rénovation: Existant; Afficher sur filtre de rénovation: Tous les filtres appropriés; Type de panneau: Générique; Angle par rapport nord: 180 deg; Abbréviation d'orientation: S; Angle d'inclinaison: 90 deg; Fonction: Fixe; Surface extérieure: Glass-Blue; Surface intérieure: Glass-Blue; Surface latérale: Glass-Blue; Classe de panneau: Panneau principal; ID mur-rideau: CurtainWall_02
AC_Pset_RenovationAndPhasing - Renovation Status: Existing
BaseQuantities - Width: 1.42 m; Perimeter: 5.72 m; GrossArea: 2.2052 m2; NetArea: 2.0448 m2; GrossVolume: 0.044104 m3; NetVolume: 0.040896 m3
ArchiCADQuantities - Altitude à Zéro du Projet: 2.8 m; Altitude à étage: 2.8 m; Superficie de surface: 2.0448 m2; Volume net: 0.040896 m3; Epaisseur: 0.02 m; Périmètre: 5.72 m; Surface brute: 2.2052 m2; Surface nominale: 2.0448 m2; Largeur: 1.42 m; Largeur nominale: 1.42 m; Hauteur: 1.44 m; Hauteur nominale: 1.44 m
Name
17 x Panel-Dist-997
Panel-Dist-997 | ArchiCADProperties - Nom de Zone: Réserve; Numéro de Zone: 010

# IfcPlate: Panneau principal 1861 x 1490 x 20 (2)
In: R+1
Material: Background 7019220
ArchiCADProperties - ID: Panel-Main-131; Etage d'implantation: R+1; Calque: A-WALL-CURT; Type: Panneau de mur-rideau; Verrouillé: no; Matériau de construction / Composite / Profil / Hachure: Background 7019220; Etat de rénovation: Existant; Afficher sur filtre de rénovation: Tous les filtres appropriés; Type de panneau: Générique; Angle par rapport nord: -90 deg; Abbréviation d'orientation: E; Angle d'inclinaison: 90 deg; Fonction: Fixe; Surface extérieure: Glass-Blue; Surface intérieure: Glass-Blue; Surface latérale: Glass-Blue; Classe de panneau: Panneau principal; ID mur-rideau: CurtainWall_01
AC_Pset_RenovationAndPhasing - Renovation Status: Existing
BaseQuantities - Width: 1.80138 m; Perimeter: 6.48276 m; GrossArea: 2.77346 m2; NetArea: 2.59399 m2; GrossVolume: 0.0554692 m3; NetVolume: 0.0518798 m3
ArchiCADQuantities - Superficie de surface: 2.59399 m2; Volume net: 0.0518798 m3; Epaisseur: 0.02 m; Périmètre: 6.48276 m; Surface brute: 2.77346 m2; Surface nominale: 2.59399 m2; Largeur: 1.80138 m; Largeur nominale: 1.80138 m; Hauteur: 1.44 m; Hauteur nominale: 1.44 m
Name | Altitude à Zéro du Projet (m) | Altitude à étage (m)
Panel-Main-131 | 6.35 | 0.95
Panel-Main-131 | 9.35 | 3.95

# IfcPlate: Panneau principal 2020 x 1425 x 20, Panel-Main-529
In: R+1
Material: Background 7019220
ArchiCADProperties - ID: Panel-Main-529; Etage d'implantation: R+1; Calque: A-WALL-CURT; Type: Panneau de mur-rideau; Verrouillé: no; Matériau de construction / Composite / Profil / Hachure: Background 7019220; Etat de rénovation: Existant; Afficher sur filtre de rénovation: Tous les filtres appropriés; Type de panneau: Générique; Angle par rapport nord: 0.0000721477 deg; Abbréviation d'orientation: N; Angle d'inclinaison: 90 deg; Fonction: Fixe; Surface extérieure: Glass-Blue; Surface intérieure: Glass-Blue; Surface latérale: Glass-Blue; Classe de panneau: Panneau principal; ID mur-rideau: CurtainWall_01
AC_Pset_RenovationAndPhasing - Renovation Status: Existing
BaseQuantities - Width: 1.96 m; Perimeter: 6.66 m; GrossArea: 2.8785 m2; NetArea: 2.6852 m2; GrossVolume: 0.05757 m3; NetVolume: 0.053704 m3
ArchiCADQuantities - Altitude à Zéro du Projet: 15.9 m; Altitude à étage: 10.5 m; Superficie de surface: 2.6852 m2; Volume net: 0.053704 m3; Epaisseur: 0.02 m; Périmètre: 6.66 m; Surface brute: 2.8785 m2; Surface nominale: 2.6852 m2; Largeur: 1.96 m; Largeur nominale: 1.96 m; Hauteur: 1.37 m; Hauteur nominale: 1.37 m

# IfcPlate: Panneau principal 2020 x 1490 x 20 (3)
In: R+1
Material: Background 7019220
ArchiCADProperties - Etage d'implantation: R+1; Calque: A-WALL-CURT; Type: Panneau de mur-rideau; Verrouillé: no; Matériau de construction / Composite / Profil / Hachure: Background 7019220; Etat de rénovation: Existant; Afficher sur filtre de rénovation: Tous les filtres appropriés; Type de panneau: Générique; Angle par rapport nord: 0.0000721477 deg; Abbréviation d'orientation: N; Angle d'inclinaison: 90 deg; Fonction: Fixe; Surface extérieure: Glass-Blue; Surface intérieure: Glass-Blue; Surface latérale: Glass-Blue; Classe de panneau: Panneau principal; ID mur-rideau: CurtainWall_01
AC_Pset_RenovationAndPhasing - Renovation Status: Existing
BaseQuantities - Width: 1.96 m; Perimeter: 6.8 m; GrossArea: 3.0098 m2; NetArea: 2.8224 m2; GrossVolume: 0.060196 m3; NetVolume: 0.056448 m3
ArchiCADQuantities - Superficie de surface: 2.8224 m2; Volume net: 0.056448 m3; Epaisseur: 0.02 m; Périmètre: 6.8 m; Surface brute: 3.0098 m2; Surface nominale: 2.8224 m2; Largeur: 1.96 m; Largeur nominale: 1.96 m; Hauteur: 1.44 m; Hauteur nominale: 1.44 m
Name | ID | Altitude à Zéro du Projet (m) | Altitude à étage (m)
Panel-Main-523 | Panel-Main-523 | 6.9 | 1.5
Panel-Main-525 | Panel-Main-525 | 9.9 | 4.5
Panel-Main-527 | Panel-Main-527 | 12.9 | 7.5

# IfcPlate: Panneau principal 2920 x 1425 x 20 (2)
In: R+1
Material: Background 7019220
ArchiCADProperties - Etage d'implantation: R+1; Calque: A-WALL-CURT; Type: Panneau de mur-rideau; Verrouillé: no; Matériau de construction / Composite / Profil / Hachure: Background 7019220; Etat de rénovation: Existant; Afficher sur filtre de rénovation: Tous les filtres appropriés; Type de panneau: Générique; Angle d'inclinaison: 90 deg; Fonction: Fixe; Surface extérieure: Glass-Blue; Surface intérieure: Glass-Blue; Surface latérale: Glass-Blue; Classe de panneau: Panneau principal; ID mur-rideau: CurtainWall_01
AC_Pset_RenovationAndPhasing - Renovation Status: Existing
BaseQuantities - Width: 2.86 m; Perimeter: 8.46 m; GrossArea: 4.161 m2; NetArea: 3.9182 m2; GrossVolume: 0.08322 m3; NetVolume: 0.078364 m3
ArchiCADQuantities - Altitude à Zéro du Projet: 15.9 m; Altitude à étage: 10.5 m; Superficie de surface: 3.9182 m2; Volume net: 0.078364 m3; Epaisseur: 0.02 m; Périmètre: 8.46 m; Surface brute: 4.161 m2; Surface nominale: 3.9182 m2; Largeur: 2.86 m; Largeur nominale: 2.86 m; Hauteur: 1.37 m; Hauteur nominale: 1.37 m
Name | ID | Angle par rapport nord (deg) | Abbréviation d'orientation
Panel-Main-544 | Panel-Main-544 | -90 | E
Panel-Main-528 | Panel-Main-528 | 0.0000721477 | N

# IfcPlate: Panneau principal 2920 x 1490 x 20 (18)
In: R+1
Material: Background 7019220
ArchiCADProperties - Etage d'implantation: R+1; Calque: A-WALL-CURT; Type: Panneau de mur-rideau; Verrouillé: no; Matériau de construction / Composite / Profil / Hachure: Background 7019220; Etat de rénovation: Existant; Afficher sur filtre de rénovation: Tous les filtres appropriés; Type de panneau: Générique; Angle d'inclinaison: 90 deg; Fonction: Fixe; Surface extérieure: Glass-Blue; Surface intérieure: Glass-Blue; Surface latérale: Glass-Blue; Classe de panneau: Panneau principal; ID mur-rideau: CurtainWall_01
AC_Pset_RenovationAndPhasing - Renovation Status: Existing
BaseQuantities - Width: 2.86 m; Perimeter: 8.6 m; GrossArea: 4.3508 m2; NetArea: 4.1184 m2; GrossVolume: 0.087016 m3; NetVolume: 0.082368 m3
ArchiCADQuantities - Superficie de surface: 4.1184 m2; Volume net: 0.082368 m3; Epaisseur: 0.02 m; Périmètre: 8.6 m; Surface brute: 4.3508 m2; Surface nominale: 4.1184 m2; Largeur: 2.86 m; Largeur nominale: 2.86 m; Hauteur: 1.44 m; Hauteur nominale: 1.44 m
Name | ID | Angle par rapport nord (deg) | Abbréviation d'orientation | Altitude à Zéro du Projet (m) | Altitude à étage (m)
Panel-Main-111 | Panel-Main-111 | 89.9238 | O | 6.4 | 1
Panel-Main-114 | Panel-Main-114 | 89.9238 | O | 9.4 | 4
Panel-Main-115 | Panel-Main-115 | 89.9238 | O | 12.4 | 7
Panel-Main-116 | Panel-Main-116 | 89.9238 | O | 15.4 | 10
Panel-Main-538 | Panel-Main-538 | -90 | E | 6.9 | 1.5
Panel-Main-540 | Panel-Main-540 | -90 | E | 9.9 | 4.5
Panel-Main-542 | Panel-Main-542 | -90 | E | 12.9 | 7.5
Panel-Main-482 | Panel-Main-482 | -82.4 | E | 5.9 | 0.5
Panel-Main-482 | Panel-Main-482 | -82.4 | E | 8.9 | 3.5
Panel-Main-482 | Panel-Main-482 | -82.4 | E | 11.9 | 6.5
Panel-Main-482 | Panel-Main-482 | -82.4 | E | 14.9 | 9.5
Panel-Main-482 | Panel-Main-482 | 180 | S | 5.9 | 0.5 | ArchiCADProperties - Nom de Zone: Plateau bureaux; Numéro de Zone: 005
Panel-Main-482 | Panel-Main-482 | 180 | S | 8.9 | 3.5 | ArchiCADProperties - Nom de Zone: Plateau bureaux; Numéro de Zone: 005
Panel-Main-482 | Panel-Main-482 | 180 | S | 11.9 | 6.5 | ArchiCADProperties - Nom de Zone: Plateau bureaux; Numéro de Zone: 005
Panel-Main-482 | Panel-Main-482 | 180 | S | 14.9 | 9.5
Panel-Main-522 | Panel-Main-522 | 0.0000721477 | N | 6.9 | 1.5
Panel-Main-524 | Panel-Main-524 | 0.0000721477 | N | 9.9 | 4.5
Panel-Main-526 | Panel-Main-526 | 0.0000721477 | N | 12.9 | 7.5

# IfcPlate: Panneau principal 2970 x 1490 x 20 (2)
In: R+1
Material: Background 7019220
ArchiCADProperties - ID: Panel-Main-131; Etage d'implantation: R+1; Calque: A-WALL-CURT; Type: Panneau de mur-rideau; Verrouillé: no; Matériau de construction / Composite / Profil / Hachure: Background 7019220; Etat de rénovation: Existant; Afficher sur filtre de rénovation: Tous les filtres appropriés; Type de panneau: Générique; Angle par rapport nord: 178.509 deg; Abbréviation d'orientation: S; Angle d'inclinaison: 90 deg; Fonction: Fixe; Surface extérieure: Glass-Blue; Surface intérieure: Glass-Blue; Surface latérale: Glass-Blue; Classe de panneau: Panneau principal; ID mur-rideau: CurtainWall_01
AC_Pset_RenovationAndPhasing - Renovation Status: Existing
BaseQuantities - Width: 2.91 m; Perimeter: 8.7 m; GrossArea: 4.4253 m2; NetArea: 4.1904 m2; GrossVolume: 0.088506 m3; NetVolume: 0.083808 m3
ArchiCADQuantities - Superficie de surface: 4.1904 m2; Volume net: 0.083808 m3; Epaisseur: 0.02 m; Périmètre: 8.7 m; Surface brute: 4.4253 m2; Surface nominale: 4.1904 m2; Largeur: 2.91 m; Largeur nominale: 2.91 m; Hauteur: 1.44 m; Hauteur nominale: 1.44 m
Name | Altitude à Zéro du Projet (m) | Altitude à étage (m)
Panel-Main-131 | 6.35 | 0.95
Panel-Main-131 | 9.35 | 3.95

# IfcPlate: Panneau principal 2980 x 1490 x 20 (24)
In: R+1
Material: Background 7019220
ArchiCADProperties - Etage d'implantation: R+1; Calque: A-WALL-CURT; Type: Panneau de mur-rideau; Verrouillé: no; Matériau de construction / Composite / Profil / Hachure: Background 7019220; Etat de rénovation: Existant; Afficher sur filtre de rénovation: Tous les filtres appropriés; Type de panneau: Générique; Angle d'inclinaison: 90 deg; Fonction: Fixe; Surface extérieure: Glass-Blue; Surface intérieure: Glass-Blue; Surface latérale: Glass-Blue; Classe de panneau: Panneau principal; ID mur-rideau: CurtainWall_01
AC_Pset_RenovationAndPhasing - Renovation Status: Existing
ArchiCADQuantities - Epaisseur: 0.02 m; Hauteur: 1.44 m; Hauteur nominale: 1.44 m
Name | ID | Angle par rapport nord (deg) | Abbréviation d'orientation | Width (m) = Largeur (m) = Largeur nominale (m) | Perimeter (m) = Périmètre (m) | GrossArea (m2) = Surface brute (m2) | NetArea (m2) = Superficie de surface (m2) = Surface nominale (m2) | GrossVolume (m3) | NetVolume (m3) = Volume net (m3) | Altitude à Zéro du Projet (m) | Altitude à étage (m)
Panel-Main-113 | Panel-Main-113 | 180 | S | 2.90373 | 8.68745 | 4.4407 | 4.18137 | 0.0888139 | 0.0836273 | 6.4 | 1
Panel-Main-120 | Panel-Main-120 | 180 | S | 2.90373 | 8.68745 | 4.4407 | 4.18137 | 0.0888139 | 0.0836273 | 9.4 | 4
Panel-Main-121 | Panel-Main-121 | 180 | S | 2.90373 | 8.68745 | 4.4407 | 4.18137 | 0.0888139 | 0.0836273 | 12.4 | 7
Panel-Main-122 | Panel-Main-122 | 180 | S | 2.90373 | 8.68745 | 4.4407 | 4.18137 | 0.0888139 | 0.0836273 | 15.4 | 10
Panel-Main-482 | Panel-Main-482 | -82.4 | E | 2.92 | 8.72 | 4.4402 | 4.2048 | 0.088804 | 0.084096 | 5.9 | 0.5
Panel-Main-482 | Panel-Main-482 | -82.4 | E | 2.92 | 8.72 | 4.4402 | 4.2048 | 0.088804 | 0.084096 | 8.9 | 3.5
Panel-Main-482 | Panel-Main-482 | -82.4 | E | 2.92 | 8.72 | 4.4402 | 4.2048 | 0.088804 | 0.084096 | 11.9 | 6.5
Panel-Main-482 | Panel-Main-482 | -82.4 | E | 2.92 | 8.72 | 4.4402 | 4.2048 | 0.088804 | 0.084096 | 14.9 | 9.5
Panel-Main-482 | Panel-Main-482 | 180 | S | 2.92 | 8.72 | 4.4402 | 4.2048 | 0.088804 | 0.084096 | 5.9 | 0.5 | ArchiCADProperties - Nom de Zone: Plateau bureaux; Numéro de Zone: 005
Panel-Main-482 | Panel-Main-482 | 180 | S | 2.92 | 8.72 | 4.4402 | 4.2048 | 0.088804 | 0.084096 | 8.9 | 3.5 | ArchiCADProperties - Nom de Zone: Plateau bureaux; Numéro de Zone: 005
Panel-Main-482 | Panel-Main-482 | 180 | S | 2.92 | 8.72 | 4.4402 | 4.2048 | 0.088804 | 0.084096 | 11.9 | 6.5 | ArchiCADProperties - Nom de Zone: Plateau bureaux; Numéro de Zone: 005
Panel-Main-482 | Panel-Main-482 | 180 | S | 2.92 | 8.72 | 4.4402 | 4.2048 | 0.088804 | 0.084096 | 14.9 | 9.5
6 x Panel-Main-131 | Panel-Main-131 | 178.509 | S | 2.92 | 8.72 | 4.4402 | 4.2048 | 0.088804 | 0.084096 | 6.35 | 0.95
6 x Panel-Main-131 | Panel-Main-131 | 178.509 | S | 2.92 | 8.72 | 4.4402 | 4.2048 | 0.088804 | 0.084096 | 9.35 | 3.95

# IfcPlate: Panneau principal 729 x 1490 x 20 (2)
In: R+1
Material: Background 7019220
ArchiCADProperties - Etage d'implantation: R+1; Calque: A-WALL-CURT; Type: Panneau de mur-rideau; Verrouillé: no; Matériau de construction / Composite / Profil / Hachure: Background 7019220; Etat de rénovation: Existant; Afficher sur filtre de rénovation: Tous les filtres appropriés; Type de panneau: Générique; Angle par rapport nord: 178.509 deg; Abbréviation d'orientation: S; Angle d'inclinaison: 90 deg; Fonction: Fixe; Surface extérieure: Glass-Blue; Surface intérieure: Glass-Blue; Surface latérale: Glass-Blue; Classe de panneau: Panneau principal; ID mur-rideau: CurtainWall_01
AC_Pset_RenovationAndPhasing - Renovation Status: Existing
BaseQuantities - Width: 0.698904 m; Perimeter: 4.27781 m; GrossArea: 1.08607 m2; NetArea: 1.00642 m2; GrossVolume: 0.0217214 m3; NetVolume: 0.0201284 m3
ArchiCADQuantities - Superficie de surface: 1.00642 m2; Volume net: 0.0201284 m3; Epaisseur: 0.02 m; Périmètre: 4.27781 m; Surface brute: 1.08607 m2; Surface nominale: 1.00642 m2; Largeur: 0.698904 m; Largeur nominale: 0.698904 m; Hauteur: 1.44 m; Hauteur nominale: 1.44 m
Name | ID | Altitude à Zéro du Projet (m) | Altitude à étage (m)
Panel-Main-142 | Panel-Main-142 | 6.35 | 0.95
Panel-Main-141 | Panel-Main-141 | 9.35 | 3.95

# IfcPlate: Panneau principal 743 x 1490 x 20, Panel-Main-538
In: Mezzannine
Material: Background 7019220
ArchiCADProperties - ID: Panel-Main-538; Etage d'implantation: Mezzannine; Calque: A-WALL-CURT; Type: Panneau de mur-rideau; Verrouillé: no; Matériau de construction / Composite / Profil / Hachure: Background 7019220; Etat de rénovation: Existant; Afficher sur filtre de rénovation: Tous les filtres appropriés; Type de panneau: Générique; Angle par rapport nord: -82.4095 deg; Abbréviation d'orientation: E; Angle d'inclinaison: 90 deg; Fonction: Fixe; Surface extérieure: Glass-Blue; Surface intérieure: Glass-Blue; Surface latérale: Glass-Blue; Classe de panneau: Panneau principal; ID mur-rideau: CurtainWall_02
AC_Pset_RenovationAndPhasing - Renovation Status: Existing
BaseQuantities - Width: 0.682687 m; Perimeter: 4.24537 m; GrossArea: 1.1066 m2; NetArea: 0.983069 m2; GrossVolume: 0.0221321 m3; NetVolume: 0.0196614 m3
ArchiCADQuantities - Altitude à Zéro du Projet: 2.8 m; Altitude à étage: -6.625 m; Superficie de surface: 0.983069 m2; Volume net: 0.0196614 m3; Epaisseur: 0.02 m; Périmètre: 4.24537 m; Surface brute: 1.1066 m2; Surface nominale: 0.983069 m2; Largeur: 0.682687 m; Largeur nominale: 0.682687 m; Hauteur: 1.44 m; Hauteur nominale: 1.44 m

# IfcPlate: Panneau principal 782 x 1490 x 20 (2)
In: R+1
Material: Background 7019220
ArchiCADProperties - ID: Panel-Main-139; Etage d'implantation: R+1; Calque: A-WALL-CURT; Type: Panneau de mur-rideau; Verrouillé: no; Matériau de construction / Composite / Profil / Hachure: Background 7019220; Etat de rénovation: Existant; Afficher sur filtre de rénovation: Tous les filtres appropriés; Type de panneau: Générique; Angle par rapport nord: 90 deg; Abbréviation d'orientation: O; Angle d'inclinaison: 90 deg; Fonction: Fixe; Surface extérieure: Glass-Blue; Surface intérieure: Glass-Blue; Surface latérale: Glass-Blue; Classe de panneau: Panneau principal; ID mur-rideau: CurtainWall_01
AC_Pset_RenovationAndPhasing - Renovation Status: Existing
BaseQuantities - Width: 0.752231 m; Perimeter: 4.38446 m; GrossArea: 1.16552 m2; NetArea: 1.08321 m2; GrossVolume: 0.0233105 m3; NetVolume: 0.0216643 m3
ArchiCADQuantities - Superficie de surface: 1.08321 m2; Volume net: 0.0216643 m3; Epaisseur: 0.02 m; Périmètre: 4.38446 m; Surface brute: 1.16552 m2; Surface nominale: 1.08321 m2; Largeur: 0.752231 m; Largeur nominale: 0.752231 m; Hauteur: 1.44 m; Hauteur nominale: 1.44 m
Name | Altitude à Zéro du Projet (m) | Altitude à étage (m)
Panel-Main-139 | 6.35 | 0.95
Panel-Main-139 | 9.35 | 3.95

# IfcPlate: Panneau principal 820 x 1490 x 20, Panel-Main-538
In: Mezzannine
Material: Background 7019220
ArchiCADProperties - ID: Panel-Main-538; Etage d'implantation: Mezzannine; Calque: A-WALL-CURT; Type: Panneau de mur-rideau; Verrouillé: no; Matériau de construction / Composite / Profil / Hachure: Background 7019220; Etat de rénovation: Existant; Afficher sur filtre de rénovation: Tous les filtres appropriés; Type de panneau: Générique; Angle par rapport nord: -82.4095 deg; Abbréviation d'orientation: E; Angle d'inclinaison: 90 deg; Fonction: Fixe; Surface extérieure: Glass-Blue; Surface intérieure: Glass-Blue; Surface latérale: Glass-Blue; Classe de panneau: Panneau principal; ID mur-rideau: CurtainWall_02
AC_Pset_RenovationAndPhasing - Renovation Status: Existing
BaseQuantities - Width: 0.76 m; Perimeter: 4.4 m; GrossArea: 1.2218 m2; NetArea: 1.0944 m2; GrossVolume: 0.024436 m3; NetVolume: 0.021888 m3
ArchiCADQuantities - Altitude à Zéro du Projet: 2.8 m; Altitude à étage: -6.625 m; Superficie de surface: 1.0944 m2; Volume net: 0.021888 m3; Epaisseur: 0.02 m; Périmètre: 4.4 m; Surface brute: 1.2218 m2; Surface nominale: 1.0944 m2; Largeur: 0.76 m; Largeur nominale: 0.76 m; Hauteur: 1.44 m; Hauteur nominale: 1.44 m

# IfcPlate: Panneau principal 880 x 1490 x 20 (8)
In: Mezzannine
Material: Background 7019220
ArchiCADProperties - ID: Panel-Main-538; Etage d'implantation: Mezzannine; Calque: A-WALL-CURT; Type: Panneau de mur-rideau; Verrouillé: no; Matériau de construction / Composite / Profil / Hachure: Background 7019220; Etat de rénovation: Existant; Afficher sur filtre de rénovation: Tous les filtres appropriés; Type de panneau: Générique; Angle par rapport nord: -82.4095 deg; Abbréviation d'orientation: E; Angle d'inclinaison: 90 deg; Fonction: Fixe; Surface extérieure: Glass-Blue; Surface intérieure: Glass-Blue; Surface latérale: Glass-Blue; Classe de panneau: Panneau principal; ID mur-rideau: CurtainWall_02
AC_Pset_RenovationAndPhasing - Renovation Status: Existing
BaseQuantities - Width: 0.82 m; Perimeter: 4.52 m; GrossArea: 1.3112 m2; NetArea: 1.1808 m2; GrossVolume: 0.026224 m3; NetVolume: 0.023616 m3
ArchiCADQuantities - Altitude à Zéro du Projet: 2.8 m; Altitude à étage: -6.625 m; Superficie de surface: 1.1808 m2; Volume net: 0.023616 m3; Epaisseur: 0.02 m; Périmètre: 4.52 m; Surface brute: 1.3112 m2; Surface nominale: 1.1808 m2; Largeur: 0.82 m; Largeur nominale: 0.82 m; Hauteur: 1.44 m; Hauteur nominale: 1.44 m

# IfcPlate: Panneau secondaire 1037 x 25 x 20, Panel-Dist-158
In: Rez de chaussée
Material: Background 7019220
ArchiCADProperties - ID: Panel-Dist-158; Etage d'implantation: Rez de chaussée; Calque: A-WALL-CURT; Type: Panneau de mur-rideau; Verrouillé: no; Matériau de construction / Composite / Profil / Hachure: Background 7019220; Etat de rénovation: Existant; Afficher sur filtre de rénovation: Tous les filtres appropriés; Type de panneau: Générique; Angle par rapport nord: 180 deg; Abbréviation d'orientation: S; Angle d'inclinaison: 90 deg; Fonction: Fixe; Surface extérieure: Glass-Blue; Surface intérieure: Glass-Blue; Surface latérale: Glass-Blue; Classe de panneau: Panneau secondaire; ID mur-rideau: CurtainWall_02
AC_Pset_RenovationAndPhasing - Renovation Status: Existing
BaseQuantities - Width: 0 m; Perimeter: 0 m; GrossArea: 0.0259207 m2; NetArea: 0 m2; GrossVolume: 0.000518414 m3; NetVolume: 0 m3
ArchiCADQuantities - Altitude à Zéro du Projet: 4.3 m; Altitude à étage: 4.3 m; Superficie de surface: 0 m2; Volume net: 0 m3; Epaisseur: 0.02 m; Périmètre: 0 m; Surface brute: 0.0259207 m2; Surface nominale: 0 m2; Largeur: 0 m; Largeur nominale: 0 m; Hauteur: 0 m; Hauteur nominale: 0 m

# IfcPlate: Panneau secondaire 1037 x 2625 x 20, Panel-Dist-958
In: Rez de chaussée
Material: Background 7019220
ArchiCADProperties - ID: Panel-Dist-958; Etage d'implantation: Rez de chaussée; Calque: A-WALL-CURT; Type: Panneau de mur-rideau; Verrouillé: no; Matériau de construction / Composite / Profil / Hachure: Background 7019220; Etat de rénovation: Existant; Afficher sur filtre de rénovation: Tous les filtres appropriés; Type de panneau: Générique; Angle par rapport nord: 180 deg; Abbréviation d'orientation: S; Angle d'inclinaison: 90 deg; Fonction: Fixe; Surface extérieure: Glass-Blue; Surface intérieure: Glass-Blue; Surface latérale: Glass-Blue; Classe de panneau: Panneau secondaire; ID mur-rideau: CurtainWall_02
AC_Pset_RenovationAndPhasing - Renovation Status: Existing
BaseQuantities - Width: 0.976827 m; Perimeter: 7.09365 m; GrossArea: 2.72167 m2; NetArea: 2.51045 m2; GrossVolume: 0.0544334 m3; NetVolume: 0.0502089 m3
ArchiCADQuantities - Altitude à Zéro du Projet: 0 m; Altitude à étage: 0 m; Superficie de surface: 2.51045 m2; Volume net: 0.0502089 m3; Epaisseur: 0.02 m; Périmètre: 7.09365 m; Surface brute: 2.72167 m2; Surface nominale: 2.51045 m2; Largeur: 0.976827 m; Largeur nominale: 0.976827 m; Hauteur: 2.57 m; Hauteur nominale: 2.57 m

# IfcPlate: Panneau secondaire 1125 x 1425 x 20, Panel-Dist-170
In: R+1
Material: Background 7019220
ArchiCADProperties - ID: Panel-Dist-170; Etage d'implantation: R+1; Calque: A-WALL-CURT; Type: Panneau de mur-rideau; Verrouillé: no; Matériau de construction / Composite / Profil / Hachure: Background 7019220; Etat de rénovation: Existant; Afficher sur filtre de rénovation: Tous les filtres appropriés; Type de panneau: Générique; Angle par rapport nord: -90 deg; Abbréviation d'orientation: E; Angle d'inclinaison: 90 deg; Fonction: Fixe; Surface extérieure: Glass-Blue; Surface intérieure: Glass-Blue; Surface latérale: Glass-Blue; Classe de panneau: Panneau secondaire; ID mur-rideau: CurtainWall_01
AC_Pset_RenovationAndPhasing - Renovation Status: Existing
BaseQuantities - Width: 1.06529 m; Perimeter: 4.87058 m; GrossArea: 1.60354 m2; NetArea: 1.45945 m2; GrossVolume: 0.0320708 m3; NetVolume: 0.0291889 m3
ArchiCADQuantities - Altitude à Zéro du Projet: 5.4 m; Altitude à étage: 0 m; Superficie de surface: 1.45945 m2; Volume net: 0.0291889 m3; Epaisseur: 0.02 m; Périmètre: 4.87058 m; Surface brute: 1.60354 m2; Surface nominale: 1.45945 m2; Largeur: 1.06529 m; Largeur nominale: 1.06529 m; Hauteur: 1.37 m; Hauteur nominale: 1.37 m

# IfcPlate: Panneau secondaire 1125 x 1490 x 20 (3)
In: R+1
Material: Background 7019220
ArchiCADProperties - Etage d'implantation: R+1; Calque: A-WALL-CURT; Type: Panneau de mur-rideau; Verrouillé: no; Matériau de construction / Composite / Profil / Hachure: Background 7019220; Etat de rénovation: Existant; Afficher sur filtre de rénovation: Tous les filtres appropriés; Type de panneau: Générique; Angle par rapport nord: -90 deg; Abbréviation d'orientation: E; Angle d'inclinaison: 90 deg; Fonction: Fixe; Surface extérieure: Glass-Blue; Surface intérieure: Glass-Blue; Surface latérale: Glass-Blue; Classe de panneau: Panneau secondaire; ID mur-rideau: CurtainWall_01
AC_Pset_RenovationAndPhasing - Renovation Status: Existing
BaseQuantities - Width: 1.06529 m; Perimeter: 5.01058 m; GrossArea: 1.67668 m2; NetArea: 1.53402 m2; GrossVolume: 0.0335336 m3; NetVolume: 0.0306804 m3
ArchiCADQuantities - Superficie de surface: 1.53402 m2; Volume net: 0.0306804 m3; Epaisseur: 0.02 m; Périmètre: 5.01058 m; Surface brute: 1.67668 m2; Surface nominale: 1.53402 m2; Largeur: 1.06529 m; Largeur nominale: 1.06529 m; Hauteur: 1.44 m; Hauteur nominale: 1.44 m
Name | ID | Altitude à Zéro du Projet (m) | Altitude à étage (m)
Panel-Dist-174 | Panel-Dist-174 | 8.4 | 3
Panel-Dist-178 | Panel-Dist-178 | 11.4 | 6
Panel-Dist-182 | Panel-Dist-182 | 14.4 | 9

# IfcPlate: Panneau secondaire 1280 x 1490 x 20 (3)
In: R+1
Material: Background 7019220
ArchiCADProperties - Etage d'implantation: R+1; Calque: A-WALL-CURT; Type: Panneau de mur-rideau; Verrouillé: no; Matériau de construction / Composite / Profil / Hachure: Background 7019220; Etat de rénovation: Existant; Afficher sur filtre de rénovation: Tous les filtres appropriés; Type de panneau: Générique; Angle par rapport nord: 89.9238 deg; Abbréviation d'orientation: O; Angle d'inclinaison: 90 deg; Fonction: Fixe; Surface extérieure: Glass-Blue; Surface intérieure: Glass-Blue; Surface latérale: Glass-Blue; Classe de panneau: Panneau secondaire; ID mur-rideau: CurtainWall_01
AC_Pset_RenovationAndPhasing - Renovation Status: Existing
BaseQuantities - Width: 1.20363 m; Perimeter: 5.28727 m; GrossArea: 1.90756 m2; NetArea: 1.73323 m2; GrossVolume: 0.0381511 m3; NetVolume: 0.0346646 m3
ArchiCADQuantities - Superficie de surface: 1.73323 m2; Volume net: 0.0346646 m3; Epaisseur: 0.02 m; Périmètre: 5.28727 m; Surface brute: 1.90756 m2; Surface nominale: 1.73323 m2; Largeur: 1.20363 m; Largeur nominale: 1.20363 m; Hauteur: 1.44 m; Hauteur nominale: 1.44 m
Name | ID | Altitude à Zéro du Projet (m) | Altitude à étage (m)
Panel-Dist-131 | Panel-Dist-131 | 10.9 | 5.5
Panel-Dist-132 | Panel-Dist-132 | 13.9 | 8.5
Panel-Dist-121 | Panel-Dist-121 | 7.9 | 2.5

# IfcPlate: Panneau secondaire 1280 x 925 x 20, Panel-Dist-102
In: R+1
Material: Background 7019220
ArchiCADProperties - ID: Panel-Dist-102; Etage d'implantation: R+1; Calque: A-WALL-CURT; Type: Panneau de mur-rideau; Verrouillé: no; Matériau de construction / Composite / Profil / Hachure: Background 7019220; Etat de rénovation: Existant; Afficher sur filtre de rénovation: Tous les filtres appropriés; Type de panneau: Générique; Angle par rapport nord: 89.9238 deg; Abbréviation d'orientation: O; Angle d'inclinaison: 90 deg; Fonction: Fixe; Surface extérieure: Glass-Blue; Surface intérieure: Glass-Blue; Surface latérale: Glass-Blue; Classe de panneau: Panneau secondaire; ID mur-rideau: CurtainWall_01
AC_Pset_RenovationAndPhasing - Renovation Status: Existing
BaseQuantities - Width: 1.20363 m; Perimeter: 4.14727 m; GrossArea: 1.18422 m2; NetArea: 1.04716 m2; GrossVolume: 0.0236844 m3; NetVolume: 0.0209432 m3
ArchiCADQuantities - Altitude à Zéro du Projet: 4.9 m; Altitude à étage: -0.5 m; Superficie de surface: 1.04716 m2; Volume net: 0.0209432 m3; Epaisseur: 0.02 m; Périmètre: 4.14727 m; Surface brute: 1.18422 m2; Surface nominale: 1.04716 m2; Largeur: 1.20363 m; Largeur nominale: 1.20363 m; Hauteur: 0.87 m; Hauteur nominale: 0.87 m

# IfcPlate: Panneau secondaire 1420 x 25 x 20, Panel-Dist-120
In: Rez de chaussée
Material: Background 7019220
ArchiCADProperties - ID: Panel-Dist-120; Etage d'implantation: Rez de chaussée; Calque: A-WALL-CURT; Type: Panneau de mur-rideau; Verrouillé: no; Matériau de construction / Composite / Profil / Hachure: Background 7019220; Etat de rénovation: Existant; Afficher sur filtre de rénovation: Tous les filtres appropriés; Type de panneau: Générique; Angle par rapport nord: 180 deg; Abbréviation d'orientation: S; Angle d'inclinaison: 90 deg; Fonction: Fixe; Surface extérieure: Glass-Blue; Surface intérieure: Glass-Blue; Surface latérale: Glass-Blue; Classe de panneau: Panneau secondaire; ID mur-rideau: CurtainWall_02
AC_Pset_RenovationAndPhasing - Renovation Status: Existing
BaseQuantities - Width: 0 m; Perimeter: 0 m; GrossArea: 0.0355 m2; NetArea: 0 m2; GrossVolume: 0.00071 m3; NetVolume: 0 m3
ArchiCADQuantities - Altitude à Zéro du Projet: 4.3 m; Altitude à étage: 4.3 m; Superficie de surface: 0 m2; Volume net: 0 m3; Epaisseur: 0.02 m; Périmètre: 0 m; Surface brute: 0.0355 m2; Surface nominale: 0 m2; Largeur: 0 m; Largeur nominale: 0 m; Hauteur: 0 m; Hauteur nominale: 0 m

# IfcPlate: Panneau secondaire 1420 x 2625 x 20, Panel-Dist-958
In: Rez de chaussée
Material: Background 7019220
ArchiCADProperties - ID: Panel-Dist-958; Etage d'implantation: Rez de chaussée; Calque: A-WALL-CURT; Type: Panneau de mur-rideau; Verrouillé: no; Matériau de construction / Composite / Profil / Hachure: Background 7019220; Etat de rénovation: Existant; Afficher sur filtre de rénovation: Tous les filtres appropriés; Type de panneau: Générique; Angle par rapport nord: 180 deg; Abbréviation d'orientation: S; Angle d'inclinaison: 90 deg; Fonction: Fixe; Surface extérieure: Glass-Blue; Surface intérieure: Glass-Blue; Surface latérale: Glass-Blue; Classe de panneau: Panneau secondaire; ID mur-rideau: CurtainWall_02
AC_Pset_RenovationAndPhasing - Renovation Status: Existing
BaseQuantities - Width: 1.36 m; Perimeter: 7.86 m; GrossArea: 3.7275 m2; NetArea: 3.4952 m2; GrossVolume: 0.07455 m3; NetVolume: 0.069904 m3
ArchiCADQuantities - Altitude à Zéro du Projet: 0 m; Altitude à étage: 0 m; Superficie de surface: 3.4952 m2; Volume net: 0.069904 m3; Epaisseur: 0.02 m; Périmètre: 7.86 m; Surface brute: 3.7275 m2; Surface nominale: 3.4952 m2; Largeur: 1.36 m; Largeur nominale: 1.36 m; Hauteur: 2.57 m; Hauteur nominale: 2.57 m

# IfcPlate: Panneau secondaire 1480 x 1490 x 20 (19)
In: Rez de chaussée
Material: Background 7019220
ArchiCADProperties - ID: Panel-Dist-958; Etage d'implantation: Rez de chaussée; Calque: A-WALL-CURT; Type: Panneau de mur-rideau; Verrouillé: no; Matériau de construction / Composite / Profil / Hachure: Background 7019220; Etat de rénovation: Existant; Afficher sur filtre de rénovation: Tous les filtres appropriés; Type de panneau: Générique; Angle par rapport nord: 180 deg; Abbréviation d'orientation: S; Angle d'inclinaison: 90 deg; Fonction: Fixe; Surface extérieure: Glass-Blue; Surface intérieure: Glass-Blue; Surface latérale: Glass-Blue; Classe de panneau: Panneau secondaire; ID mur-rideau: CurtainWall_02
AC_Pset_RenovationAndPhasing - Renovation Status: Existing
BaseQuantities - Width: 1.42 m; Perimeter: 5.72 m; GrossArea: 2.2052 m2; NetArea: 2.0448 m2; GrossVolume: 0.044104 m3; NetVolume: 0.040896 m3
ArchiCADQuantities - Altitude à Zéro du Projet: 2.8 m; Altitude à étage: 2.8 m; Superficie de surface: 2.0448 m2; Volume net: 0.040896 m3; Epaisseur: 0.02 m; Périmètre: 5.72 m; Surface brute: 2.2052 m2; Surface nominale: 2.0448 m2; Largeur: 1.42 m; Largeur nominale: 1.42 m; Hauteur: 1.44 m; Hauteur nominale: 1.44 m
Name
17 x Panel-Dist-958
2 x Panel-Dist-958 | ArchiCADProperties - Nom de Zone: Réserve; Numéro de Zone: 010

# IfcPlate: Panneau secondaire 1480 x 25 x 20 (37)
In: Rez de chaussée
Material: Background 7019220
ArchiCADProperties - Etage d'implantation: Rez de chaussée; Calque: A-WALL-CURT; Type: Panneau de mur-rideau; Verrouillé: no; Matériau de construction / Composite / Profil / Hachure: Background 7019220; Etat de rénovation: Existant; Afficher sur filtre de rénovation: Tous les filtres appropriés; Type de panneau: Générique; Angle par rapport nord: 180 deg; Abbréviation d'orientation: S; Angle d'inclinaison: 90 deg; Fonction: Fixe; Surface extérieure: Glass-Blue; Surface intérieure: Glass-Blue; Surface latérale: Glass-Blue; Classe de panneau: Panneau secondaire; ID mur-rideau: CurtainWall_02
AC_Pset_RenovationAndPhasing - Renovation Status: Existing
BaseQuantities - Width: 0 m; Perimeter: 0 m; GrossArea: 0.037 m2; NetArea: 0 m2; GrossVolume: 0.00074 m3; NetVolume: 0 m3
ArchiCADQuantities - Altitude à Zéro du Projet: 4.3 m; Altitude à étage: 4.3 m; Superficie de surface: 0 m2; Volume net: 0 m3; Epaisseur: 0.02 m; Périmètre: 0 m; Surface brute: 0.037 m2; Surface nominale: 0 m2; Largeur: 0 m; Largeur nominale: 0 m; Hauteur: 0 m; Hauteur nominale: 0 m
Name | ID
Panel-Dist-156 | Panel-Dist-156
Panel-Dist-157 | Panel-Dist-157
Panel-Dist-121 | Panel-Dist-121
Panel-Dist-122 | Panel-Dist-122
Panel-Dist-123 | Panel-Dist-123
Panel-Dist-124 | Panel-Dist-124
Panel-Dist-125 | Panel-Dist-125
Panel-Dist-126 | Panel-Dist-126
Panel-Dist-127 | Panel-Dist-127
Panel-Dist-128 | Panel-Dist-128
Panel-Dist-129 | Panel-Dist-129
Panel-Dist-130 | Panel-Dist-130
Panel-Dist-131 | Panel-Dist-131
Panel-Dist-132 | Panel-Dist-132
Panel-Dist-133 | Panel-Dist-133
Panel-Dist-134 | Panel-Dist-134
Panel-Dist-135 | Panel-Dist-135
Panel-Dist-136 | Panel-Dist-136
Panel-Dist-137 | Panel-Dist-137 | ArchiCADProperties - Nom de Zone: Réserve; Numéro de Zone: 010
Panel-Dist-138 | Panel-Dist-138 | ArchiCADProperties - Nom de Zone: Réserve; Numéro de Zone: 010
Panel-Dist-139 | Panel-Dist-139 | ArchiCADProperties - Nom de Zone: Réserve; Numéro de Zone: 010
Panel-Dist-140 | Panel-Dist-140
Panel-Dist-141 | Panel-Dist-141
Panel-Dist-142 | Panel-Dist-142
Panel-Dist-143 | Panel-Dist-143
Panel-Dist-144 | Panel-Dist-144
Panel-Dist-145 | Panel-Dist-145
Panel-Dist-146 | Panel-Dist-146
Panel-Dist-147 | Panel-Dist-147
Panel-Dist-148 | Panel-Dist-148
Panel-Dist-149 | Panel-Dist-149
Panel-Dist-150 | Panel-Dist-150
Panel-Dist-151 | Panel-Dist-151
Panel-Dist-152 | Panel-Dist-152
Panel-Dist-153 | Panel-Dist-153
Panel-Dist-154 | Panel-Dist-154
Panel-Dist-155 | Panel-Dist-155

# IfcPlate: Panneau secondaire 1480 x 2625 x 20 (37)
In: Rez de chaussée
Material: Background 7019220
ArchiCADProperties - ID: Panel-Dist-958; Etage d'implantation: Rez de chaussée; Calque: A-WALL-CURT; Type: Panneau de mur-rideau; Verrouillé: no; Matériau de construction / Composite / Profil / Hachure: Background 7019220; Etat de rénovation: Existant; Afficher sur filtre de rénovation: Tous les filtres appropriés; Type de panneau: Générique; Angle par rapport nord: 180 deg; Abbréviation d'orientation: S; Angle d'inclinaison: 90 deg; Fonction: Fixe; Surface extérieure: Glass-Blue; Surface intérieure: Glass-Blue; Surface latérale: Glass-Blue; Classe de panneau: Panneau secondaire; ID mur-rideau: CurtainWall_02
AC_Pset_RenovationAndPhasing - Renovation Status: Existing
BaseQuantities - Width: 1.42 m; Perimeter: 7.98 m; GrossArea: 3.885 m2; NetArea: 3.6494 m2; GrossVolume: 0.0777 m3; NetVolume: 0.072988 m3
ArchiCADQuantities - Altitude à Zéro du Projet: 0 m; Altitude à étage: 0 m; Superficie de surface: 3.6494 m2; Volume net: 0.072988 m3; Epaisseur: 0.02 m; Périmètre: 7.98 m; Surface brute: 3.885 m2; Surface nominale: 3.6494 m2; Largeur: 1.42 m; Largeur nominale: 1.42 m; Hauteur: 2.57 m; Hauteur nominale: 2.57 m
Name
34 x Panel-Dist-958
3 x Panel-Dist-958 | ArchiCADProperties - Nom de Zone: Réserve; Numéro de Zone: 010

# IfcPlate: Panneau secondaire 1861 x 1200 x 20, Panel-Dist-580
In: R+1
Material: Background 7019220
ArchiCADProperties - ID: Panel-Dist-580; Etage d'implantation: R+1; Calque: A-WALL-CURT; Type: Panneau de mur-rideau; Verrouillé: no; Matériau de construction / Composite / Profil / Hachure: Background 7019220; Etat de rénovation: Existant; Afficher sur filtre de rénovation: Tous les filtres appropriés; Type de panneau: Générique; Angle par rapport nord: -90 deg; Abbréviation d'orientation: E; Angle d'inclinaison: 90 deg; Fonction: Fixe; Surface extérieure: Glass-Blue; Surface intérieure: Glass-Blue; Surface latérale: Glass-Blue; Classe de panneau: Panneau secondaire; ID mur-rideau: CurtainWall_01
AC_Pset_RenovationAndPhasing - Renovation Status: Existing
BaseQuantities - Width: 1.80138 m; Perimeter: 5.89276 m; GrossArea: 2.23366 m2; NetArea: 2.06258 m2; GrossVolume: 0.0446732 m3; NetVolume: 0.0412517 m3
ArchiCADQuantities - Altitude à Zéro du Projet: 10.85 m; Altitude à étage: 5.45 m; Superficie de surface: 2.06258 m2; Volume net: 0.0412517 m3; Epaisseur: 0.02 m; Périmètre: 5.89276 m; Surface brute: 2.23366 m2; Surface nominale: 2.06258 m2; Largeur: 1.80138 m; Largeur nominale: 1.80138 m; Hauteur: 1.145 m; Hauteur nominale: 1.145 m

# IfcPlate: Panneau secondaire 1861 x 1425 x 20, Panel-Dist-569
In: R+1
Material: Background 7019220
ArchiCADProperties - ID: Panel-Dist-569; Etage d'implantation: R+1; Calque: A-WALL-CURT; Type: Panneau de mur-rideau; Verrouillé: no; Matériau de construction / Composite / Profil / Hachure: Background 7019220; Etat de rénovation: Existant; Afficher sur filtre de rénovation: Tous les filtres appropriés; Type de panneau: Générique; Angle par rapport nord: -90 deg; Abbréviation d'orientation: E; Angle d'inclinaison: 90 deg; Fonction: Fixe; Surface extérieure: Glass-Blue; Surface intérieure: Glass-Blue; Surface latérale: Glass-Blue; Classe de panneau: Panneau secondaire; ID mur-rideau: CurtainWall_01
AC_Pset_RenovationAndPhasing - Renovation Status: Existing
BaseQuantities - Width: 1.80138 m; Perimeter: 6.34276 m; GrossArea: 2.65247 m2; NetArea: 2.46789 m2; GrossVolume: 0.0530494 m3; NetVolume: 0.0493579 m3
ArchiCADQuantities - Altitude à Zéro du Projet: 4.85 m; Altitude à étage: -0.55 m; Superficie de surface: 2.46789 m2; Volume net: 0.0493579 m3; Epaisseur: 0.02 m; Périmètre: 6.34276 m; Surface brute: 2.65247 m2; Surface nominale: 2.46789 m2; Largeur: 1.80138 m; Largeur nominale: 1.80138 m; Hauteur: 1.37 m; Hauteur nominale: 1.37 m

# IfcPlate: Panneau secondaire 1861 x 1490 x 20, Panel-Dist-569
In: R+1
Material: Background 7019220
ArchiCADProperties - ID: Panel-Dist-569; Etage d'implantation: R+1; Calque: A-WALL-CURT; Type: Panneau de mur-rideau; Verrouillé: no; Matériau de construction / Composite / Profil / Hachure: Background 7019220; Etat de rénovation: Existant; Afficher sur filtre de rénovation: Tous les filtres appropriés; Type de panneau: Générique; Angle par rapport nord: -90 deg; Abbréviation d'orientation: E; Angle d'inclinaison: 90 deg; Fonction: Fixe; Surface extérieure: Glass-Blue; Surface intérieure: Glass-Blue; Surface latérale: Glass-Blue; Classe de panneau: Panneau secondaire; ID mur-rideau: CurtainWall_01
AC_Pset_RenovationAndPhasing - Renovation Status: Existing
BaseQuantities - Width: 1.80138 m; Perimeter: 6.48276 m; GrossArea: 2.77346 m2; NetArea: 2.59399 m2; GrossVolume: 0.0554692 m3; NetVolume: 0.0518798 m3
ArchiCADQuantities - Altitude à Zéro du Projet: 7.85 m; Altitude à étage: 2.45 m; Superficie de surface: 2.59399 m2; Volume net: 0.0518798 m3; Epaisseur: 0.02 m; Périmètre: 6.48276 m; Surface brute: 2.77346 m2; Surface nominale: 2.59399 m2; Largeur: 1.80138 m; Largeur nominale: 1.80138 m; Hauteur: 1.44 m; Hauteur nominale: 1.44 m

# IfcPlate: Panneau secondaire 2020 x 1425 x 20, Panel-Dist-142
In: R+1
Material: Background 7019220
ArchiCADProperties - ID: Panel-Dist-142; Etage d'implantation: R+1; Calque: A-WALL-CURT; Type: Panneau de mur-rideau; Verrouillé: no; Matériau de construction / Composite / Profil / Hachure: Background 7019220; Etat de rénovation: Existant; Afficher sur filtre de rénovation: Tous les filtres appropriés; Type de panneau: Générique; Angle par rapport nord: 0.0000721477 deg; Abbréviation d'orientation: N; Angle d'inclinaison: 90 deg; Fonction: Fixe; Surface extérieure: Glass-Blue; Surface intérieure: Glass-Blue; Surface latérale: Glass-Blue; Classe de panneau: Panneau secondaire; ID mur-rideau: CurtainWall_01
AC_Pset_RenovationAndPhasing - Renovation Status: Existing
BaseQuantities - Width: 1.96 m; Perimeter: 6.66 m; GrossArea: 2.8785 m2; NetArea: 2.6852 m2; GrossVolume: 0.05757 m3; NetVolume: 0.053704 m3
ArchiCADQuantities - Altitude à Zéro du Projet: 5.4 m; Altitude à étage: 0 m; Superficie de surface: 2.6852 m2; Volume net: 0.053704 m3; Epaisseur: 0.02 m; Périmètre: 6.66 m; Surface brute: 2.8785 m2; Surface nominale: 2.6852 m2; Largeur: 1.96 m; Largeur nominale: 1.96 m; Hauteur: 1.37 m; Hauteur nominale: 1.37 m

# IfcPlate: Panneau secondaire 2020 x 1490 x 20 (3)
In: R+1
Material: Background 7019220
ArchiCADProperties - Etage d'implantation: R+1; Calque: A-WALL-CURT; Type: Panneau de mur-rideau; Verrouillé: no; Matériau de construction / Composite / Profil / Hachure: Background 7019220; Etat de rénovation: Existant; Afficher sur filtre de rénovation: Tous les filtres appropriés; Type de panneau: Générique; Angle par rapport nord: 0.0000721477 deg; Abbréviation d'orientation: N; Angle d'inclinaison: 90 deg; Fonction: Fixe; Surface extérieure: Glass-Blue; Surface intérieure: Glass-Blue; Surface latérale: Glass-Blue; Classe de panneau: Panneau secondaire; ID mur-rideau: CurtainWall_01
AC_Pset_RenovationAndPhasing - Renovation Status: Existing
BaseQuantities - Width: 1.96 m; Perimeter: 6.8 m; GrossArea: 3.0098 m2; NetArea: 2.8224 m2; GrossVolume: 0.060196 m3; NetVolume: 0.056448 m3
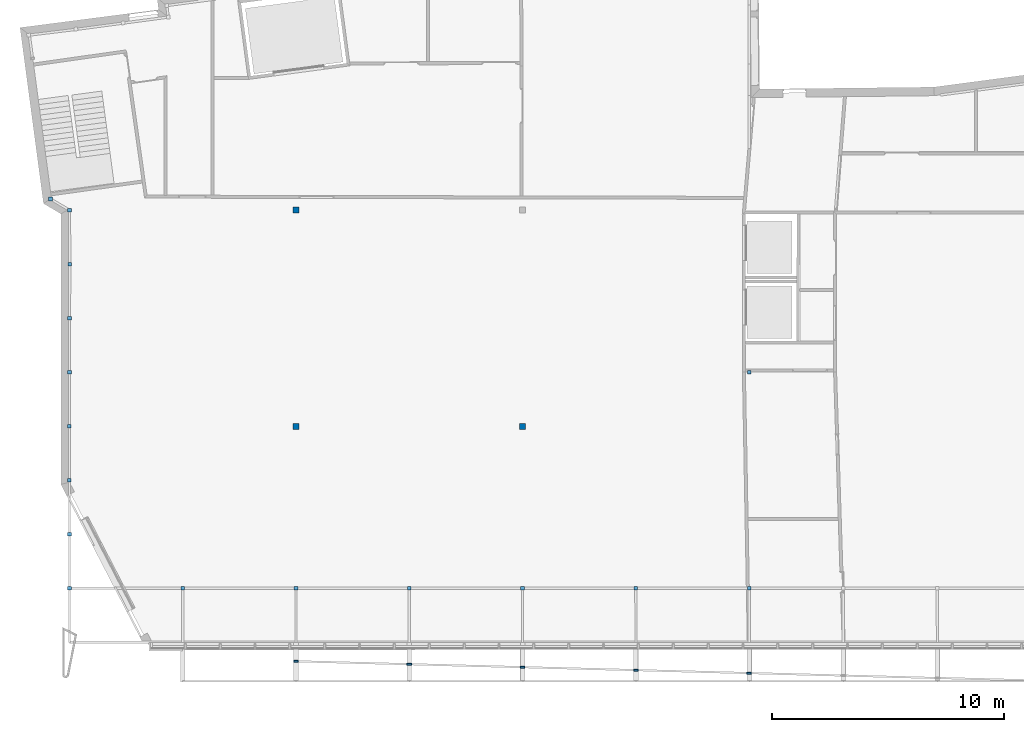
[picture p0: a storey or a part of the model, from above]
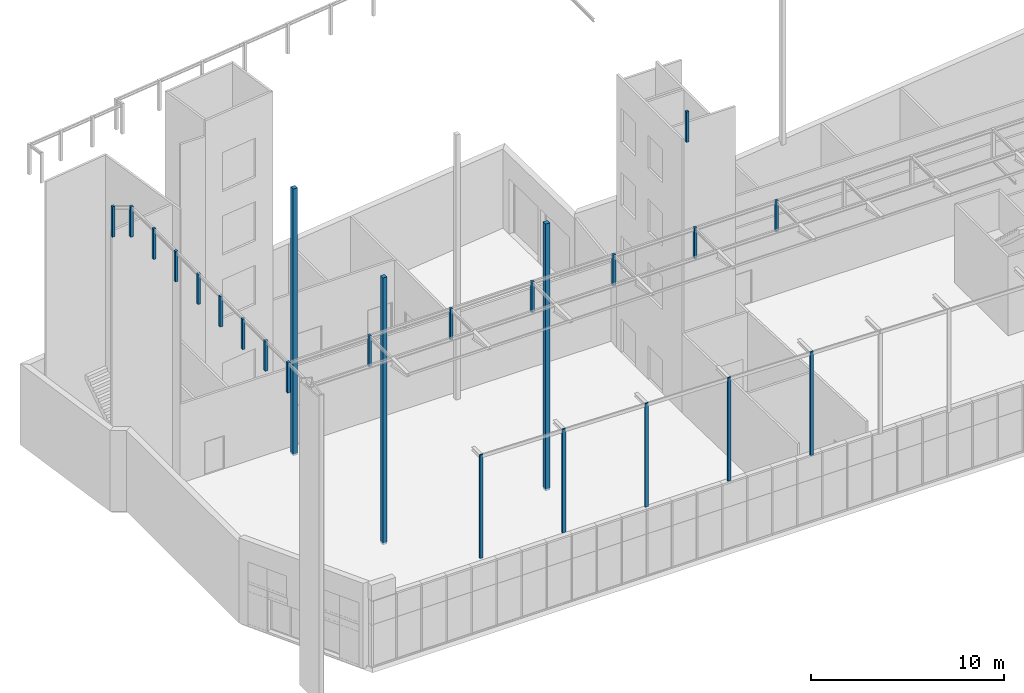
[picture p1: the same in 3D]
Properties of the parts of a building model (IFC2X3), part 12 of 19

# IfcPlate: Panneau secondaire 2020 x 1490 x 20 (3)
ArchiCADQuantities - Superficie de surface: 2.8224 m2; Volume net: 0.056448 m3; Epaisseur: 0.02 m; Périmètre: 6.8 m; Surface brute: 3.0098 m2; Surface nominale: 2.8224 m2; Largeur: 1.96 m; Largeur nominale: 1.96 m; Hauteur: 1.44 m; Hauteur nominale: 1.44 m
Name | ID | Altitude à Zéro du Projet (m) | Altitude à étage (m)
Panel-Dist-146 | Panel-Dist-146 | 8.4 | 3
Panel-Dist-150 | Panel-Dist-150 | 11.4 | 6
Panel-Dist-154 | Panel-Dist-154 | 14.4 | 9

# IfcPlate: Panneau secondaire 2295 x 1490 x 20 (7)
In: R+1
Material: Background 7019220
ArchiCADProperties - Etage d'implantation: R+1; Calque: A-WALL-CURT; Type: Panneau de mur-rideau; Verrouillé: no; Matériau de construction / Composite / Profil / Hachure: Background 7019220; Etat de rénovation: Existant; Afficher sur filtre de rénovation: Tous les filtres appropriés; Type de panneau: Générique; Angle par rapport nord: 180 deg; Abbréviation d'orientation: S; Angle d'inclinaison: 90 deg; Fonction: Fixe; Surface extérieure: Glass-Blue; Surface intérieure: Glass-Blue; Surface latérale: Glass-Blue; Classe de panneau: Panneau secondaire; ID mur-rideau: CurtainWall_01
AC_Pset_RenovationAndPhasing - Renovation Status: Existing
BaseQuantities - Width: 2.235 m; Perimeter: 7.35 m; GrossArea: 3.41955 m2; NetArea: 3.2184 m2; GrossVolume: 0.068391 m3; NetVolume: 0.064368 m3
ArchiCADQuantities - Superficie de surface: 3.2184 m2; Volume net: 0.064368 m3; Epaisseur: 0.02 m; Périmètre: 7.35 m; Surface brute: 3.41955 m2; Surface nominale: 3.2184 m2; Largeur: 2.235 m; Largeur nominale: 2.235 m; Hauteur: 1.44 m; Hauteur nominale: 1.44 m
Name | ID | Altitude à Zéro du Projet (m) | Altitude à étage (m)
Panel-Dist-112 | Panel-Dist-112 | 6.4 | 1
Panel-Dist-145 | Panel-Dist-145 | 15.4 | 10
Panel-Dist-135 | Panel-Dist-135 | 7.9 | 2.5
Panel-Dist-141 | Panel-Dist-141 | 9.4 | 4
Panel-Dist-142 | Panel-Dist-142 | 10.9 | 5.5
Panel-Dist-143 | Panel-Dist-143 | 12.4 | 7
Panel-Dist-144 | Panel-Dist-144 | 13.9 | 8.5

# IfcPlate: Panneau secondaire 2295 x 925 x 20, Panel-Dist-111
In: R+1
Material: Background 7019220
ArchiCADProperties - ID: Panel-Dist-111; Etage d'implantation: R+1; Calque: A-WALL-CURT; Type: Panneau de mur-rideau; Verrouillé: no; Matériau de construction / Composite / Profil / Hachure: Background 7019220; Etat de rénovation: Existant; Afficher sur filtre de rénovation: Tous les filtres appropriés; Type de panneau: Générique; Angle par rapport nord: 180 deg; Abbréviation d'orientation: S; Angle d'inclinaison: 90 deg; Fonction: Fixe; Surface extérieure: Glass-Blue; Surface intérieure: Glass-Blue; Surface latérale: Glass-Blue; Classe de panneau: Panneau secondaire; ID mur-rideau: CurtainWall_01
AC_Pset_RenovationAndPhasing - Renovation Status: Existing
BaseQuantities - Width: 2.235 m; Perimeter: 6.21 m; GrossArea: 2.12288 m2; NetArea: 1.94445 m2; GrossVolume: 0.0424575 m3; NetVolume: 0.038889 m3
ArchiCADQuantities - Altitude à Zéro du Projet: 4.9 m; Altitude à étage: -0.5 m; Superficie de surface: 1.94445 m2; Volume net: 0.038889 m3; Epaisseur: 0.02 m; Périmètre: 6.21 m; Surface brute: 2.12288 m2; Surface nominale: 1.94445 m2; Largeur: 2.235 m; Largeur nominale: 2.235 m; Hauteur: 0.87 m; Hauteur nominale: 0.87 m

# IfcPlate: Panneau secondaire 2453 x 1425 x 20, Panel-Dist-024
In: R+1
Material: Background 7019220
ArchiCADProperties - ID: Panel-Dist-024; Etage d'implantation: R+1; Nom de Zone: Plateau bureaux; Numéro de Zone: 005; Calque: A-WALL-CURT; Type: Panneau de mur-rideau; Verrouillé: no; Matériau de construction / Composite / Profil / Hachure: Background 7019220; Etat de rénovation: Existant; Afficher sur filtre de rénovation: Tous les filtres appropriés; Type de panneau: Générique; Angle par rapport nord: 180 deg; Abbréviation d'orientation: S; Angle d'inclinaison: 90 deg; Fonction: Fixe; Surface extérieure: Glass-Blue; Surface intérieure: Glass-Blue; Surface latérale: Glass-Blue; Classe de panneau: Panneau secondaire; ID mur-rideau: CurtainWall_01
AC_Pset_RenovationAndPhasing - Renovation Status: Existing
BaseQuantities - Width: 2.39265 m; Perimeter: 7.5253 m; GrossArea: 3.49503 m2; NetArea: 3.27793 m2; GrossVolume: 0.0699005 m3; NetVolume: 0.0655586 m3
ArchiCADQuantities - Altitude à Zéro du Projet: 4.4 m; Altitude à étage: -1 m; Superficie de surface: 3.27793 m2; Volume net: 0.0655586 m3; Epaisseur: 0.02 m; Périmètre: 7.5253 m; Surface brute: 3.49503 m2; Surface nominale: 3.27793 m2; Largeur: 2.39265 m; Largeur nominale: 2.39265 m; Hauteur: 1.37 m; Hauteur nominale: 1.37 m

# IfcPlate: Panneau secondaire 2453 x 1490 x 20 (7)
In: R+1
Material: Background 7019220
ArchiCADProperties - ID: Panel-Dist-024; Etage d'implantation: R+1; Calque: A-WALL-CURT; Type: Panneau de mur-rideau; Verrouillé: no; Matériau de construction / Composite / Profil / Hachure: Background 7019220; Etat de rénovation: Existant; Afficher sur filtre de rénovation: Tous les filtres appropriés; Type de panneau: Générique; Angle par rapport nord: 180 deg; Abbréviation d'orientation: S; Angle d'inclinaison: 90 deg; Fonction: Fixe; Surface extérieure: Glass-Blue; Surface intérieure: Glass-Blue; Surface latérale: Glass-Blue; Classe de panneau: Panneau secondaire; ID mur-rideau: CurtainWall_01
AC_Pset_RenovationAndPhasing - Renovation Status: Existing
BaseQuantities - Width: 2.39265 m; Perimeter: 7.6653 m; GrossArea: 3.65445 m2; NetArea: 3.44542 m2; GrossVolume: 0.073089 m3; NetVolume: 0.0689083 m3
ArchiCADQuantities - Superficie de surface: 3.44542 m2; Volume net: 0.0689083 m3; Epaisseur: 0.02 m; Périmètre: 7.6653 m; Surface brute: 3.65445 m2; Surface nominale: 3.44542 m2; Largeur: 2.39265 m; Largeur nominale: 2.39265 m; Hauteur: 1.44 m; Hauteur nominale: 1.44 m
Name | Nom de Zone | Numéro de Zone | Altitude à Zéro du Projet (m) | Altitude à étage (m)
Panel-Dist-024 | Plateau bureaux | 005 | 5.9 | 0.5
Panel-Dist-024 | Plateau bureaux | 005 | 7.4 | 2
Panel-Dist-024 | Plateau bureaux | 005 | 8.9 | 3.5
Panel-Dist-024 | Plateau bureaux | 005 | 10.4 | 5
Panel-Dist-024 | Plateau bureaux | 005 | 11.9 | 6.5
Panel-Dist-024 |  |  | 13.4 | 8
Panel-Dist-024 |  |  | 14.9 | 9.5

# IfcPlate: Panneau secondaire 2453 x 925 x 20, Panel-Dist-035
In: R+1
Material: Background 7019220
ArchiCADProperties - ID: Panel-Dist-035; Etage d'implantation: R+1; Calque: A-WALL-CURT; Type: Panneau de mur-rideau; Verrouillé: no; Matériau de construction / Composite / Profil / Hachure: Background 7019220; Etat de rénovation: Existant; Afficher sur filtre de rénovation: Tous les filtres appropriés; Type de panneau: Générique; Angle par rapport nord: 180 deg; Abbréviation d'orientation: S; Angle d'inclinaison: 90 deg; Fonction: Fixe; Surface extérieure: Glass-Blue; Surface intérieure: Glass-Blue; Surface latérale: Glass-Blue; Classe de panneau: Panneau secondaire; ID mur-rideau: CurtainWall_01
AC_Pset_RenovationAndPhasing - Renovation Status: Existing
BaseQuantities - Width: 2.39265 m; Perimeter: 6.5253 m; GrossArea: 2.2687 m2; NetArea: 2.08161 m2; GrossVolume: 0.045374 m3; NetVolume: 0.0416321 m3
ArchiCADQuantities - Altitude à Zéro du Projet: 16.4 m; Altitude à étage: 11 m; Superficie de surface: 2.08161 m2; Volume net: 0.0416321 m3; Epaisseur: 0.02 m; Périmètre: 6.5253 m; Surface brute: 2.2687 m2; Surface nominale: 2.08161 m2; Largeur: 2.39265 m; Largeur nominale: 2.39265 m; Hauteur: 0.87 m; Hauteur nominale: 0.87 m

# IfcPlate: Panneau secondaire 2920 x 1425 x 20 (4)
In: R+1
Material: Background 7019220
ArchiCADProperties - Etage d'implantation: R+1; Calque: A-WALL-CURT; Type: Panneau de mur-rideau; Verrouillé: no; Matériau de construction / Composite / Profil / Hachure: Background 7019220; Etat de rénovation: Existant; Afficher sur filtre de rénovation: Tous les filtres appropriés; Type de panneau: Générique; Angle d'inclinaison: 90 deg; Fonction: Fixe; Surface extérieure: Glass-Blue; Surface intérieure: Glass-Blue; Surface latérale: Glass-Blue; Classe de panneau: Panneau secondaire; ID mur-rideau: CurtainWall_01
AC_Pset_RenovationAndPhasing - Renovation Status: Existing
BaseQuantities - Width: 2.86 m; Perimeter: 8.46 m; GrossArea: 4.161 m2; NetArea: 3.9182 m2; GrossVolume: 0.08322 m3; NetVolume: 0.078364 m3
ArchiCADQuantities - Superficie de surface: 3.9182 m2; Volume net: 0.078364 m3; Epaisseur: 0.02 m; Périmètre: 8.46 m; Surface brute: 4.161 m2; Surface nominale: 3.9182 m2; Largeur: 2.86 m; Largeur nominale: 2.86 m; Hauteur: 1.37 m; Hauteur nominale: 1.37 m
Name | ID | Angle par rapport nord (deg) | Abbréviation d'orientation | Altitude à Zéro du Projet (m) | Altitude à étage (m)
Panel-Dist-168 | Panel-Dist-168 | -90 | E | 5.4 | 0
Panel-Dist-024 | Panel-Dist-024 | -82.4 | E | 4.4 | -1
Panel-Dist-024 | Panel-Dist-024 | 180 | S | 4.4 | -1 | ArchiCADProperties - Nom de Zone: Plateau bureaux; Numéro de Zone: 005
Panel-Dist-140 | Panel-Dist-140 | 0.0000721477 | N | 5.4 | 0

# IfcPlate: Panneau secondaire 2920 x 1490 x 20 (15)
In: R+1
Material: Background 7019220
ArchiCADProperties - Etage d'implantation: R+1; Calque: A-WALL-CURT; Type: Panneau de mur-rideau; Verrouillé: no; Matériau de construction / Composite / Profil / Hachure: Background 7019220; Etat de rénovation: Existant; Afficher sur filtre de rénovation: Tous les filtres appropriés; Type de panneau: Générique; Angle d'inclinaison: 90 deg; Fonction: Fixe; Surface extérieure: Glass-Blue; Surface intérieure: Glass-Blue; Surface latérale: Glass-Blue; Classe de panneau: Panneau secondaire; ID mur-rideau: CurtainWall_01
AC_Pset_RenovationAndPhasing - Renovation Status: Existing
BaseQuantities - Width: 2.86 m; Perimeter: 8.6 m; GrossArea: 4.3508 m2; NetArea: 4.1184 m2; GrossVolume: 0.087016 m3; NetVolume: 0.082368 m3
ArchiCADQuantities - Superficie de surface: 4.1184 m2; Volume net: 0.082368 m3; Epaisseur: 0.02 m; Périmètre: 8.6 m; Surface brute: 4.3508 m2; Surface nominale: 4.1184 m2; Largeur: 2.86 m; Largeur nominale: 2.86 m; Hauteur: 1.44 m; Hauteur nominale: 1.44 m
Name | ID | Angle par rapport nord (deg) | Abbréviation d'orientation | Altitude à Zéro du Projet (m) | Altitude à étage (m)
Panel-Dist-122 | Panel-Dist-122 | 89.9238 | O | 10.9 | 5.5
Panel-Dist-123 | Panel-Dist-123 | 89.9238 | O | 13.9 | 8.5
Panel-Dist-119 | Panel-Dist-119 | 89.9238 | O | 7.9 | 2.5
Panel-Dist-172 | Panel-Dist-172 | -90 | E | 8.4 | 3
Panel-Dist-176 | Panel-Dist-176 | -90 | E | 11.4 | 6
Panel-Dist-180 | Panel-Dist-180 | -90 | E | 14.4 | 9
Panel-Dist-024 | Panel-Dist-024 | -82.4 | E | 7.4 | 2
Panel-Dist-024 | Panel-Dist-024 | -82.4 | E | 10.4 | 5
Panel-Dist-024 | Panel-Dist-024 | -82.4 | E | 13.4 | 8
Panel-Dist-024 | Panel-Dist-024 | 180 | S | 7.4 | 2 | ArchiCADProperties - Nom de Zone: Plateau bureaux; Numéro de Zone: 005
Panel-Dist-024 | Panel-Dist-024 | 180 | S | 10.4 | 5 | ArchiCADProperties - Nom de Zone: Plateau bureaux; Numéro de Zone: 005
Panel-Dist-024 | Panel-Dist-024 | 180 | S | 13.4 | 8
Panel-Dist-144 | Panel-Dist-144 | 0.0000721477 | N | 8.4 | 3
Panel-Dist-148 | Panel-Dist-148 | 0.0000721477 | N | 11.4 | 6
Panel-Dist-152 | Panel-Dist-152 | 0.0000721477 | N | 14.4 | 9

# IfcPlate: Panneau secondaire 2920 x 925 x 20 (3)
In: R+1
Material: Background 7019220
ArchiCADProperties - Etage d'implantation: R+1; Calque: A-WALL-CURT; Type: Panneau de mur-rideau; Verrouillé: no; Matériau de construction / Composite / Profil / Hachure: Background 7019220; Etat de rénovation: Existant; Afficher sur filtre de rénovation: Tous les filtres appropriés; Type de panneau: Générique; Angle d'inclinaison: 90 deg; Fonction: Fixe; Surface extérieure: Glass-Blue; Surface intérieure: Glass-Blue; Surface latérale: Glass-Blue; Classe de panneau: Panneau secondaire; ID mur-rideau: CurtainWall_01
AC_Pset_RenovationAndPhasing - Renovation Status: Existing
BaseQuantities - Width: 2.86 m; Perimeter: 7.46 m; GrossArea: 2.701 m2; NetArea: 2.4882 m2; GrossVolume: 0.05402 m3; NetVolume: 0.049764 m3
ArchiCADQuantities - Superficie de surface: 2.4882 m2; Volume net: 0.049764 m3; Epaisseur: 0.02 m; Périmètre: 7.46 m; Surface brute: 2.701 m2; Surface nominale: 2.4882 m2; Largeur: 2.86 m; Largeur nominale: 2.86 m; Hauteur: 0.87 m; Hauteur nominale: 0.87 m
Name | ID | Angle par rapport nord (deg) | Abbréviation d'orientation | Altitude à Zéro du Projet (m) | Altitude à étage (m)
Panel-Dist-100 | Panel-Dist-100 | 89.9238 | O | 4.9 | -0.5
Panel-Dist-024 | Panel-Dist-024 | -82.4 | E | 16.4 | 11
Panel-Dist-032 | Panel-Dist-032 | 180 | S | 16.4 | 11

# IfcPlate: Panneau secondaire 2970 x 1200 x 20, Panel-Dist-588
In: R+1
Material: Background 7019220
ArchiCADProperties - ID: Panel-Dist-588; Etage d'implantation: R+1; Calque: A-WALL-CURT; Type: Panneau de mur-rideau; Verrouillé: no; Matériau de construction / Composite / Profil / Hachure: Background 7019220; Etat de rénovation: Existant; Afficher sur filtre de rénovation: Tous les filtres appropriés; Type de panneau: Générique; Angle par rapport nord: 178.509 deg; Abbréviation d'orientation: S; Angle d'inclinaison: 90 deg; Fonction: Fixe; Surface extérieure: Glass-Blue; Surface intérieure: Glass-Blue; Surface latérale: Glass-Blue; Classe de panneau: Panneau secondaire; ID mur-rideau: CurtainWall_01
AC_Pset_RenovationAndPhasing - Renovation Status: Existing
BaseQuantities - Width: 2.91 m; Perimeter: 8.11014 m; GrossArea: 3.5642 m2; NetArea: 3.33215 m2; GrossVolume: 0.0712841 m3; NetVolume: 0.066643 m3
ArchiCADQuantities - Altitude à Zéro du Projet: 10.85 m; Altitude à étage: 5.45 m; Superficie de surface: 3.33215 m2; Volume net: 0.066643 m3; Epaisseur: 0.02 m; Périmètre: 8.11014 m; Surface brute: 3.5642 m2; Surface nominale: 3.33215 m2; Largeur: 2.91 m; Largeur nominale: 2.91 m; Hauteur: 1.14507 m; Hauteur nominale: 1.14507 m

# IfcPlate: Panneau secondaire 2970 x 1425 x 20, Panel-Dist-569
In: R+1
Material: Background 7019220
ArchiCADProperties - ID: Panel-Dist-569; Etage d'implantation: R+1; Calque: A-WALL-CURT; Type: Panneau de mur-rideau; Verrouillé: no; Matériau de construction / Composite / Profil / Hachure: Background 7019220; Etat de rénovation: Existant; Afficher sur filtre de rénovation: Tous les filtres appropriés; Type de panneau: Générique; Angle par rapport nord: 178.509 deg; Abbréviation d'orientation: S; Angle d'inclinaison: 90 deg; Fonction: Fixe; Surface extérieure: Glass-Blue; Surface intérieure: Glass-Blue; Surface latérale: Glass-Blue; Classe de panneau: Panneau secondaire; ID mur-rideau: CurtainWall_01
AC_Pset_RenovationAndPhasing - Renovation Status: Existing
BaseQuantities - Width: 2.91 m; Perimeter: 8.56 m; GrossArea: 4.23225 m2; NetArea: 3.9867 m2; GrossVolume: 0.084645 m3; NetVolume: 0.079734 m3
ArchiCADQuantities - Altitude à Zéro du Projet: 4.85 m; Altitude à étage: -0.55 m; Superficie de surface: 3.9867 m2; Volume net: 0.079734 m3; Epaisseur: 0.02 m; Périmètre: 8.56 m; Surface brute: 4.23225 m2; Surface nominale: 3.9867 m2; Largeur: 2.91 m; Largeur nominale: 2.91 m; Hauteur: 1.37 m; Hauteur nominale: 1.37 m

# IfcPlate: Panneau secondaire 2970 x 1490 x 20, Panel-Dist-569
In: R+1
Material: Background 7019220
ArchiCADProperties - ID: Panel-Dist-569; Etage d'implantation: R+1; Calque: A-WALL-CURT; Type: Panneau de mur-rideau; Verrouillé: no; Matériau de construction / Composite / Profil / Hachure: Background 7019220; Etat de rénovation: Existant; Afficher sur filtre de rénovation: Tous les filtres appropriés; Type de panneau: Générique; Angle par rapport nord: 178.509 deg; Abbréviation d'orientation: S; Angle d'inclinaison: 90 deg; Fonction: Fixe; Surface extérieure: Glass-Blue; Surface intérieure: Glass-Blue; Surface latérale: Glass-Blue; Classe de panneau: Panneau secondaire; ID mur-rideau: CurtainWall_01
AC_Pset_RenovationAndPhasing - Renovation Status: Existing
BaseQuantities - Width: 2.91 m; Perimeter: 8.7 m; GrossArea: 4.4253 m2; NetArea: 4.1904 m2; GrossVolume: 0.088506 m3; NetVolume: 0.083808 m3
ArchiCADQuantities - Altitude à Zéro du Projet: 7.85 m; Altitude à étage: 2.45 m; Superficie de surface: 4.1904 m2; Volume net: 0.083808 m3; Epaisseur: 0.02 m; Périmètre: 8.7 m; Surface brute: 4.4253 m2; Surface nominale: 4.1904 m2; Largeur: 2.91 m; Largeur nominale: 2.91 m; Hauteur: 1.44 m; Hauteur nominale: 1.44 m

# IfcPlate: Panneau secondaire 2980 x 1200 x 20 (13)
In: R+1
Material: Background 7019220
ArchiCADProperties - Etage d'implantation: R+1; Calque: A-WALL-CURT; Type: Panneau de mur-rideau; Verrouillé: no; Matériau de construction / Composite / Profil / Hachure: Background 7019220; Etat de rénovation: Existant; Afficher sur filtre de rénovation: Tous les filtres appropriés; Type de panneau: Générique; Angle par rapport nord: 178.509 deg; Abbréviation d'orientation: S; Angle d'inclinaison: 90 deg; Fonction: Fixe; Surface extérieure: Glass-Blue; Surface intérieure: Glass-Blue; Surface latérale: Glass-Blue; Classe de panneau: Panneau secondaire; ID mur-rideau: CurtainWall_01
AC_Pset_RenovationAndPhasing - Renovation Status: Existing
BaseQuantities - Width: 2.92 m; Perimeter: 8.13014 m; GrossArea: 3.5762 m2; NetArea: 3.3436 m2; GrossVolume: 0.0715241 m3; NetVolume: 0.066872 m3
ArchiCADQuantities - Altitude à Zéro du Projet: 10.85 m; Altitude à étage: 5.45 m; Superficie de surface: 3.3436 m2; Volume net: 0.066872 m3; Epaisseur: 0.02 m; Périmètre: 8.13014 m; Surface brute: 3.5762 m2; Surface nominale: 3.3436 m2; Largeur: 2.92 m; Largeur nominale: 2.92 m; Hauteur: 1.14507 m; Hauteur nominale: 1.14507 m
Name | ID
Panel-Dist-589 | Panel-Dist-589
Panel-Dist-590 | Panel-Dist-590
Panel-Dist-591 | Panel-Dist-591
Panel-Dist-592 | Panel-Dist-592
Panel-Dist-593 | Panel-Dist-593
Panel-Dist-594 | Panel-Dist-594
Panel-Dist-595 | Panel-Dist-595
Panel-Dist-596 | Panel-Dist-596
Panel-Dist-597 | Panel-Dist-597
Panel-Dist-598 | Panel-Dist-598
Panel-Dist-599 | Panel-Dist-599
Panel-Dist-600 | Panel-Dist-600
Panel-Dist-601 | Panel-Dist-601

# IfcPlate: Panneau secondaire 2980 x 1425 x 20 (21)
In: R+1
Material: Background 7019220
ArchiCADProperties - Etage d'implantation: R+1; Calque: A-WALL-CURT; Type: Panneau de mur-rideau; Verrouillé: no; Matériau de construction / Composite / Profil / Hachure: Background 7019220; Etat de rénovation: Existant; Afficher sur filtre de rénovation: Tous les filtres appropriés; Type de panneau: Générique; Angle d'inclinaison: 90 deg; Fonction: Fixe; Surface extérieure: Glass-Blue; Surface intérieure: Glass-Blue; Surface latérale: Glass-Blue; Classe de panneau: Panneau secondaire; ID mur-rideau: CurtainWall_01
AC_Pset_RenovationAndPhasing - Renovation Status: Existing
BaseQuantities - Width: 2.92 m; Perimeter: 8.58 m; GrossArea: 4.2465 m2; NetArea: 4.0004 m2; GrossVolume: 0.08493 m3; NetVolume: 0.080008 m3
ArchiCADQuantities - Superficie de surface: 4.0004 m2; Volume net: 0.080008 m3; Epaisseur: 0.02 m; Périmètre: 8.58 m; Surface brute: 4.2465 m2; Surface nominale: 4.0004 m2; Largeur: 2.92 m; Largeur nominale: 2.92 m; Hauteur: 1.37 m; Hauteur nominale: 1.37 m
Name | ID | Angle par rapport nord (deg) | Abbréviation d'orientation | Altitude à Zéro du Projet (m) | Altitude à étage (m)
Panel-Dist-169 | Panel-Dist-169 | -90 | E | 5.4 | 0
Panel-Dist-183 | Panel-Dist-183 | -90 | E | 15.9 | 10.5
2 x Panel-Dist-024 | Panel-Dist-024 | -82.4 | E | 4.4 | -1
2 x Panel-Dist-024 | Panel-Dist-024 | 180 | S | 4.4 | -1 | ArchiCADProperties - Nom de Zone: Plateau bureaux; Numéro de Zone: 005
Panel-Dist-141 | Panel-Dist-141 | 0.0000721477 | N | 5.4 | 0
Panel-Dist-155 | Panel-Dist-155 | 0.0000721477 | N | 15.9 | 10.5
13 x Panel-Dist-569 | Panel-Dist-569 | 178.509 | S | 4.85 | -0.55

# IfcPlate: Panneau secondaire 2980 x 1490 x 20 (69)
In: R+1
Material: Background 7019220
ArchiCADProperties - Etage d'implantation: R+1; Calque: A-WALL-CURT; Type: Panneau de mur-rideau; Verrouillé: no; Matériau de construction / Composite / Profil / Hachure: Background 7019220; Etat de rénovation: Existant; Afficher sur filtre de rénovation: Tous les filtres appropriés; Type de panneau: Générique; Angle d'inclinaison: 90 deg; Fonction: Fixe; Surface extérieure: Glass-Blue; Surface intérieure: Glass-Blue; Surface latérale: Glass-Blue; Classe de panneau: Panneau secondaire; ID mur-rideau: CurtainWall_01
AC_Pset_RenovationAndPhasing - Renovation Status: Existing
ArchiCADQuantities - Epaisseur: 0.02 m; Hauteur: 1.44 m; Hauteur nominale: 1.44 m
Name | ID | Angle par rapport nord (deg) | Abbréviation d'orientation | Width (m) = Largeur (m) = Largeur nominale (m) | Perimeter (m) = Périmètre (m) | GrossArea (m2) = Surface brute (m2) | NetArea (m2) = Superficie de surface (m2) = Surface nominale (m2) | GrossVolume (m3) | NetVolume (m3) = Volume net (m3) | Altitude à Zéro du Projet (m) | Altitude à étage (m)
Panel-Dist-103 | Panel-Dist-103 | 89.9238 | O | 2.92 | 8.72 | 4.4402 | 4.2048 | 0.088804 | 0.084096 | 6.4 | 1
Panel-Dist-125 | Panel-Dist-125 | 89.9238 | O | 2.92 | 8.72 | 4.4402 | 4.2048 | 0.088804 | 0.084096 | 9.4 | 4
Panel-Dist-126 | Panel-Dist-126 | 89.9238 | O | 2.92 | 8.72 | 4.4402 | 4.2048 | 0.088804 | 0.084096 | 10.9 | 5.5
Panel-Dist-127 | Panel-Dist-127 | 89.9238 | O | 2.92 | 8.72 | 4.4402 | 4.2048 | 0.088804 | 0.084096 | 12.4 | 7
Panel-Dist-128 | Panel-Dist-128 | 89.9238 | O | 2.92 | 8.72 | 4.4402 | 4.2048 | 0.088804 | 0.084096 | 13.9 | 8.5
Panel-Dist-129 | Panel-Dist-129 | 89.9238 | O | 2.92 | 8.72 | 4.4402 | 4.2048 | 0.088804 | 0.084096 | 15.4 | 10
Panel-Dist-120 | Panel-Dist-120 | 89.9238 | O | 2.92 | 8.72 | 4.4402 | 4.2048 | 0.088804 | 0.084096 | 7.9 | 2.5
Panel-Dist-138 | Panel-Dist-138 | 180 | S | 2.90373 | 8.68745 | 4.4407 | 4.18137 | 0.0888139 | 0.0836273 | 10.9 | 5.5
Panel-Dist-139 | Panel-Dist-139 | 180 | S | 2.90373 | 8.68745 | 4.4407 | 4.18137 | 0.0888139 | 0.0836273 | 13.9 | 8.5
Panel-Dist-134 | Panel-Dist-134 | 180 | S | 2.90373 | 8.68745 | 4.4407 | 4.18137 | 0.0888139 | 0.0836273 | 7.9 | 2.5
Panel-Dist-171 | Panel-Dist-171 | -90 | E | 2.92 | 8.72 | 4.4402 | 4.2048 | 0.088804 | 0.084096 | 6.9 | 1.5
Panel-Dist-173 | Panel-Dist-173 | -90 | E | 2.92 | 8.72 | 4.4402 | 4.2048 | 0.088804 | 0.084096 | 8.4 | 3
Panel-Dist-175 | Panel-Dist-175 | -90 | E | 2.92 | 8.72 | 4.4402 | 4.2048 | 0.088804 | 0.084096 | 9.9 | 4.5
Panel-Dist-177 | Panel-Dist-177 | -90 | E | 2.92 | 8.72 | 4.4402 | 4.2048 | 0.088804 | 0.084096 | 11.4 | 6
Panel-Dist-179 | Panel-Dist-179 | -90 | E | 2.92 | 8.72 | 4.4402 | 4.2048 | 0.088804 | 0.084096 | 12.9 | 7.5
Panel-Dist-181 | Panel-Dist-181 | -90 | E | 2.92 | 8.72 | 4.4402 | 4.2048 | 0.088804 | 0.084096 | 14.4 | 9
Panel-Dist-024 | Panel-Dist-024 | -82.4 | E | 2.92 | 8.72 | 4.4402 | 4.2048 | 0.088804 | 0.084096 | 5.9 | 0.5
2 x Panel-Dist-024 | Panel-Dist-024 | -82.4 | E | 2.92 | 8.72 | 4.4402 | 4.2048 | 0.088804 | 0.084096 | 7.4 | 2
Panel-Dist-024 | Panel-Dist-024 | -82.4 | E | 2.92 | 8.72 | 4.4402 | 4.2048 | 0.088804 | 0.084096 | 8.9 | 3.5
2 x Panel-Dist-024 | Panel-Dist-024 | -82.4 | E | 2.92 | 8.72 | 4.4402 | 4.2048 | 0.088804 | 0.084096 | 10.4 | 5
Panel-Dist-024 | Panel-Dist-024 | -82.4 | E | 2.92 | 8.72 | 4.4402 | 4.2048 | 0.088804 | 0.084096 | 11.9 | 6.5
2 x Panel-Dist-024 | Panel-Dist-024 | -82.4 | E | 2.92 | 8.72 | 4.4402 | 4.2048 | 0.088804 | 0.084096 | 13.4 | 8
Panel-Dist-024 | Panel-Dist-024 | -82.4 | E | 2.92 | 8.72 | 4.4402 | 4.2048 | 0.088804 | 0.084096 | 14.9 | 9.5
Panel-Dist-024 | Panel-Dist-024 | 180 | S | 2.92 | 8.72 | 4.4402 | 4.2048 | 0.088804 | 0.084096 | 5.9 | 0.5 | ArchiCADProperties - Nom de Zone: Plateau bureaux; Numéro de Zone: 005
2 x Panel-Dist-024 | Panel-Dist-024 | 180 | S | 2.92 | 8.72 | 4.4402 | 4.2048 | 0.088804 | 0.084096 | 7.4 | 2 | ArchiCADProperties - Nom de Zone: Plateau bureaux; Numéro de Zone: 005
Panel-Dist-024 | Panel-Dist-024 | 180 | S | 2.92 | 8.72 | 4.4402 | 4.2048 | 0.088804 | 0.084096 | 8.9 | 3.5 | ArchiCADProperties - Nom de Zone: Plateau bureaux; Numéro de Zone: 005
2 x Panel-Dist-024 | Panel-Dist-024 | 180 | S | 2.92 | 8.72 | 4.4402 | 4.2048 | 0.088804 | 0.084096 | 10.4 | 5 | ArchiCADProperties - Nom de Zone: Plateau bureaux; Numéro de Zone: 005
Panel-Dist-024 | Panel-Dist-024 | 180 | S | 2.92 | 8.72 | 4.4402 | 4.2048 | 0.088804 | 0.084096 | 11.9 | 6.5 | ArchiCADProperties - Nom de Zone: Plateau bureaux; Numéro de Zone: 005
2 x Panel-Dist-024 | Panel-Dist-024 | 180 | S | 2.92 | 8.72 | 4.4402 | 4.2048 | 0.088804 | 0.084096 | 13.4 | 8
Panel-Dist-024 | Panel-Dist-024 | 180 | S | 2.92 | 8.72 | 4.4402 | 4.2048 | 0.088804 | 0.084096 | 14.9 | 9.5
Panel-Dist-143 | Panel-Dist-143 | 0.0000721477 | N | 2.92 | 8.72 | 4.4402 | 4.2048 | 0.088804 | 0.084096 | 6.9 | 1.5
Panel-Dist-145 | Panel-Dist-145 | 0.0000721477 | N | 2.92 | 8.72 | 4.4402 | 4.2048 | 0.088804 | 0.084096 | 8.4 | 3
Panel-Dist-147 | Panel-Dist-147 | 0.0000721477 | N | 2.92 | 8.72 | 4.4402 | 4.2048 | 0.088804 | 0.084096 | 9.9 | 4.5
Panel-Dist-149 | Panel-Dist-149 | 0.0000721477 | N | 2.92 | 8.72 | 4.4402 | 4.2048 | 0.088804 | 0.084096 | 11.4 | 6
Panel-Dist-151 | Panel-Dist-151 | 0.0000721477 | N | 2.92 | 8.72 | 4.4402 | 4.2048 | 0.088804 | 0.084096 | 12.9 | 7.5
Panel-Dist-153 | Panel-Dist-153 | 0.0000721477 | N | 2.92 | 8.72 | 4.4402 | 4.2048 | 0.088804 | 0.084096 | 14.4 | 9
7 x Panel-Dist-569 | Panel-Dist-569 | 178.509 | S | 2.92 | 8.72 | 4.4402 | 4.2048 | 0.088804 | 0.084096 | 6.35 | 0.95
13 x Panel-Dist-569 | Panel-Dist-569 | 178.509 | S | 2.92 | 8.72 | 4.4402 | 4.2048 | 0.088804 | 0.084096 | 7.85 | 2.45
7 x Panel-Dist-569 | Panel-Dist-569 | 178.509 | S | 2.92 | 8.72 | 4.4402 | 4.2048 | 0.088804 | 0.084096 | 9.35 | 3.95

# IfcPlate: Panneau secondaire 2980 x 925 x 20 (6)
In: R+1
Material: Background 7019220
ArchiCADProperties - Etage d'implantation: R+1; Calque: A-WALL-CURT; Type: Panneau de mur-rideau; Verrouillé: no; Matériau de construction / Composite / Profil / Hachure: Background 7019220; Etat de rénovation: Existant; Afficher sur filtre de rénovation: Tous les filtres appropriés; Type de panneau: Générique; Angle d'inclinaison: 90 deg; Fonction: Fixe; Surface extérieure: Glass-Blue; Surface intérieure: Glass-Blue; Surface latérale: Glass-Blue; Classe de panneau: Panneau secondaire; ID mur-rideau: CurtainWall_01
AC_Pset_RenovationAndPhasing - Renovation Status: Existing
ArchiCADQuantities - Epaisseur: 0.02 m; Hauteur: 0.87 m; Hauteur nominale: 0.87 m
Name | ID | Angle par rapport nord (deg) | Abbréviation d'orientation | Width (m) = Largeur (m) = Largeur nominale (m) | Perimeter (m) = Périmètre (m) | GrossArea (m2) = Surface brute (m2) | NetArea (m2) = Superficie de surface (m2) = Surface nominale (m2) | GrossVolume (m3) | NetVolume (m3) = Volume net (m3) | Altitude à Zéro du Projet (m) | Altitude à étage (m)
Panel-Dist-110 | Panel-Dist-110 | 180 | S | 2.90373 | 7.54745 | 2.75681 | 2.52624 | 0.0551362 | 0.0505248 | 4.9 | -0.5
Panel-Dist-101 | Panel-Dist-101 | 89.9238 | O | 2.92 | 7.58 | 2.7565 | 2.5404 | 0.05513 | 0.050808 | 4.9 | -0.5
Panel-Dist-025 | Panel-Dist-025 | -82.4 | E | 2.92 | 7.58 | 2.7565 | 2.5404 | 0.05513 | 0.050808 | 16.4 | 11
Panel-Dist-026 | Panel-Dist-026 | -82.4 | E | 2.92 | 7.58 | 2.7565 | 2.5404 | 0.05513 | 0.050808 | 16.4 | 11
Panel-Dist-033 | Panel-Dist-033 | 180 | S | 2.92 | 7.58 | 2.7565 | 2.5404 | 0.05513 | 0.050808 | 16.4 | 11
Panel-Dist-034 | Panel-Dist-034 | 180 | S | 2.92 | 7.58 | 2.7565 | 2.5404 | 0.05513 | 0.050808 | 16.4 | 11

# IfcPlate: Panneau secondaire 302 x 1425 x 20, Panel-Dist-024
In: R+1
Material: Background 7019220
ArchiCADProperties - ID: Panel-Dist-024; Etage d'implantation: R+1; Calque: A-WALL-CURT; Type: Panneau de mur-rideau; Verrouillé: no; Matériau de construction / Composite / Profil / Hachure: Background 7019220; Etat de rénovation: Existant; Afficher sur filtre de rénovation: Tous les filtres appropriés; Type de panneau: Générique; Angle par rapport nord: -82.4 deg; Abbréviation d'orientation: E; Angle d'inclinaison: 90 deg; Fonction: Fixe; Surface extérieure: Glass-Blue; Surface intérieure: Glass-Blue; Surface latérale: Glass-Blue; Classe de panneau: Panneau secondaire; ID mur-rideau: CurtainWall_01
AC_Pset_RenovationAndPhasing - Renovation Status: Existing
BaseQuantities - Width: 0.242419 m; Perimeter: 3.22484 m; GrossArea: 0.430947 m2; NetArea: 0.332114 m2; GrossVolume: 0.00861894 m3; NetVolume: 0.00664228 m3
ArchiCADQuantities - Altitude à Zéro du Projet: 4.4 m; Altitude à étage: -1 m; Superficie de surface: 0.332114 m2; Volume net: 0.00664228 m3; Epaisseur: 0.02 m; Périmètre: 3.22484 m; Surface brute: 0.430947 m2; Surface nominale: 0.332114 m2; Largeur: 0.242419 m; Largeur nominale: 0.242419 m; Hauteur: 1.37 m; Hauteur nominale: 1.37 m

# IfcPlate: Panneau secondaire 302 x 1490 x 20 (7)
In: R+1
Material: Background 7019220
ArchiCADProperties - ID: Panel-Dist-024; Etage d'implantation: R+1; Calque: A-WALL-CURT; Type: Panneau de mur-rideau; Verrouillé: no; Matériau de construction / Composite / Profil / Hachure: Background 7019220; Etat de rénovation: Existant; Afficher sur filtre de rénovation: Tous les filtres appropriés; Type de panneau: Générique; Angle par rapport nord: -82.4 deg; Abbréviation d'orientation: E; Angle d'inclinaison: 90 deg; Fonction: Fixe; Surface extérieure: Glass-Blue; Surface intérieure: Glass-Blue; Surface latérale: Glass-Blue; Classe de panneau: Panneau secondaire; ID mur-rideau: CurtainWall_01
AC_Pset_RenovationAndPhasing - Renovation Status: Existing
BaseQuantities - Width: 0.242419 m; Perimeter: 3.36484 m; GrossArea: 0.450604 m2; NetArea: 0.349083 m2; GrossVolume: 0.00901209 m3; NetVolume: 0.00698167 m3
ArchiCADQuantities - Superficie de surface: 0.349083 m2; Volume net: 0.00698167 m3; Epaisseur: 0.02 m; Périmètre: 3.36484 m; Surface brute: 0.450604 m2; Surface nominale: 0.349083 m2; Largeur: 0.242419 m; Largeur nominale: 0.242419 m; Hauteur: 1.44 m; Hauteur nominale: 1.44 m
Name | Altitude à Zéro du Projet (m) | Altitude à étage (m)
Panel-Dist-024 | 7.4 | 2
Panel-Dist-024 | 8.9 | 3.5
Panel-Dist-024 | 10.4 | 5
Panel-Dist-024 | 11.9 | 6.5
Panel-Dist-024 | 13.4 | 8
Panel-Dist-024 | 14.9 | 9.5
Panel-Dist-024 | 5.9 | 0.5

# IfcPlate: Panneau secondaire 302 x 925 x 20, Panel-Dist-027
In: R+1
Material: Background 7019220
ArchiCADProperties - ID: Panel-Dist-027; Etage d'implantation: R+1; Calque: A-WALL-CURT; Type: Panneau de mur-rideau; Verrouillé: no; Matériau de construction / Composite / Profil / Hachure: Background 7019220; Etat de rénovation: Existant; Afficher sur filtre de rénovation: Tous les filtres appropriés; Type de panneau: Générique; Angle par rapport nord: -82.4 deg; Abbréviation d'orientation: E; Angle d'inclinaison: 90 deg; Fonction: Fixe; Surface extérieure: Glass-Blue; Surface intérieure: Glass-Blue; Surface latérale: Glass-Blue; Classe de panneau: Panneau secondaire; ID mur-rideau: CurtainWall_01
AC_Pset_RenovationAndPhasing - Renovation Status: Existing
BaseQuantities - Width: 0.242419 m; Perimeter: 2.22484 m; GrossArea: 0.279738 m2; NetArea: 0.210905 m2; GrossVolume: 0.00559475 m3; NetVolume: 0.00421809 m3
ArchiCADQuantities - Altitude à Zéro du Projet: 16.4 m; Altitude à étage: 11 m; Superficie de surface: 0.210905 m2; Volume net: 0.00421809 m3; Epaisseur: 0.02 m; Périmètre: 2.22484 m; Surface brute: 0.279738 m2; Surface nominale: 0.210905 m2; Largeur: 0.242419 m; Largeur nominale: 0.242419 m; Hauteur: 0.87 m; Hauteur nominale: 0.87 m

# IfcPlate: Panneau secondaire 729 x 1200 x 20, Panel-Dist-656
In: R+1
Material: Background 7019220
ArchiCADProperties - ID: Panel-Dist-656; Etage d'implantation: R+1; Calque: A-WALL-CURT; Type: Panneau de mur-rideau; Verrouillé: no; Matériau de construction / Composite / Profil / Hachure: Background 7019220; Etat de rénovation: Existant; Afficher sur filtre de rénovation: Tous les filtres appropriés; Type de panneau: Générique; Angle par rapport nord: 178.509 deg; Abbréviation d'orientation: S; Angle d'inclinaison: 90 deg; Fonction: Fixe; Surface extérieure: Glass-Blue; Surface intérieure: Glass-Blue; Surface latérale: Glass-Blue; Classe de panneau: Panneau secondaire; ID mur-rideau: CurtainWall_01
AC_Pset_RenovationAndPhasing - Renovation Status: Existing
BaseQuantities - Width: 0.698904 m; Perimeter: 3.68795 m; GrossArea: 0.874735 m2; NetArea: 0.800293 m2; GrossVolume: 0.0174947 m3; NetVolume: 0.0160059 m3
ArchiCADQuantities - Altitude à Zéro du Projet: 10.85 m; Altitude à étage: 5.45 m; Superficie de surface: 0.800293 m2; Volume net: 0.0160059 m3; Epaisseur: 0.02 m; Périmètre: 3.68795 m; Surface brute: 0.874735 m2; Surface nominale: 0.800293 m2; Largeur: 0.698904 m; Largeur nominale: 0.698904 m; Hauteur: 1.14507 m; Hauteur nominale: 1.14507 m

# IfcPlate: Panneau secondaire 729 x 1425 x 20, Panel-Dist-655
In: R+1
Material: Background 7019220
ArchiCADProperties - ID: Panel-Dist-655; Etage d'implantation: R+1; Calque: A-WALL-CURT; Type: Panneau de mur-rideau; Verrouillé: no; Matériau de construction / Composite / Profil / Hachure: Background 7019220; Etat de rénovation: Existant; Afficher sur filtre de rénovation: Tous les filtres appropriés; Type de panneau: Générique; Angle par rapport nord: 178.509 deg; Abbréviation d'orientation: S; Angle d'inclinaison: 90 deg; Fonction: Fixe; Surface extérieure: Glass-Blue; Surface intérieure: Glass-Blue; Surface latérale: Glass-Blue; Classe de panneau: Panneau secondaire; ID mur-rideau: CurtainWall_01
AC_Pset_RenovationAndPhasing - Renovation Status: Existing
BaseQuantities - Width: 0.698904 m; Perimeter: 4.13781 m; GrossArea: 1.03869 m2; NetArea: 0.957499 m2; GrossVolume: 0.0207738 m3; NetVolume: 0.01915 m3
ArchiCADQuantities - Altitude à Zéro du Projet: 4.85 m; Altitude à étage: -0.55 m; Superficie de surface: 0.957499 m2; Volume net: 0.01915 m3; Epaisseur: 0.02 m; Périmètre: 4.13781 m; Surface brute: 1.03869 m2; Surface nominale: 0.957499 m2; Largeur: 0.698904 m; Largeur nominale: 0.698904 m; Hauteur: 1.37 m; Hauteur nominale: 1.37 m

# IfcPlate: Panneau secondaire 729 x 1490 x 20, Panel-Dist-654
In: R+1
Material: Background 7019220
ArchiCADProperties - ID: Panel-Dist-654; Etage d'implantation: R+1; Calque: A-WALL-CURT; Type: Panneau de mur-rideau; Verrouillé: no; Matériau de construction / Composite / Profil / Hachure: Background 7019220; Etat de rénovation: Existant; Afficher sur filtre de rénovation: Tous les filtres appropriés; Type de panneau: Générique; Angle par rapport nord: 178.509 deg; Abbréviation d'orientation: S; Angle d'inclinaison: 90 deg; Fonction: Fixe; Surface extérieure: Glass-Blue; Surface intérieure: Glass-Blue; Surface latérale: Glass-Blue; Classe de panneau: Panneau secondaire; ID mur-rideau: CurtainWall_01
AC_Pset_RenovationAndPhasing - Renovation Status: Existing
BaseQuantities - Width: 0.698904 m; Perimeter: 4.27781 m; GrossArea: 1.08607 m2; NetArea: 1.00642 m2; GrossVolume: 0.0217214 m3; NetVolume: 0.0201284 m3
ArchiCADQuantities - Altitude à Zéro du Projet: 7.85 m; Altitude à étage: 2.45 m; Superficie de surface: 1.00642 m2; Volume net: 0.0201284 m3; Epaisseur: 0.02 m; Périmètre: 4.27781 m; Surface brute: 1.08607 m2; Surface nominale: 1.00642 m2; Largeur: 0.698904 m; Largeur nominale: 0.698904 m; Hauteur: 1.44 m; Hauteur nominale: 1.44 m

# IfcPlate: Panneau secondaire 743 x 25 x 20, Panel-Dist-202
In: Mezzannine
Material: Background 7019220
ArchiCADProperties - ID: Panel-Dist-202; Etage d'implantation: Mezzannine; Calque: A-WALL-CURT; Type: Panneau de mur-rideau; Verrouillé: no; Matériau de construction / Composite / Profil / Hachure: Background 7019220; Etat de rénovation: Existant; Afficher sur filtre de rénovation: Tous les filtres appropriés; Type de panneau: Générique; Angle par rapport nord: -82.4095 deg; Abbréviation d'orientation: E; Angle d'inclinaison: 90 deg; Fonction: Fixe; Surface extérieure: Glass-Blue; Surface intérieure: Glass-Blue; Surface latérale: Glass-Blue; Classe de panneau: Panneau secondaire; ID mur-rideau: CurtainWall_02
AC_Pset_RenovationAndPhasing - Renovation Status: Existing
BaseQuantities - Width: 0 m; Perimeter: 0 m; GrossArea: 0.0185672 m2; NetArea: 0 m2; GrossVolume: 0.000371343 m3; NetVolume: 0 m3
ArchiCADQuantities - Altitude à Zéro du Projet: 4.3 m; Altitude à étage: -5.125 m; Superficie de surface: 0 m2; Volume net: 0 m3; Epaisseur: 0.02 m; Périmètre: 0 m; Surface brute: 0.0185672 m2; Surface nominale: 0 m2; Largeur: 0 m; Largeur nominale: 0 m; Hauteur: 0 m; Hauteur nominale: 0 m

# IfcPlate: Panneau secondaire 743 x 2625 x 20, Panel-Dist-173
In: Mezzannine
Material: Background 7019220
ArchiCADProperties - ID: Panel-Dist-173; Etage d'implantation: Mezzannine; Calque: A-WALL-CURT; Type: Panneau de mur-rideau; Verrouillé: no; Matériau de construction / Composite / Profil / Hachure: Background 7019220; Etat de rénovation: Existant; Afficher sur filtre de rénovation: Tous les filtres appropriés; Type de panneau: Générique; Angle par rapport nord: -82.4095 deg; Abbréviation d'orientation: E; Angle d'inclinaison: 90 deg; Fonction: Fixe; Surface extérieure: Glass-Blue; Surface intérieure: Glass-Blue; Surface latérale: Glass-Blue; Classe de panneau: Panneau secondaire; ID mur-rideau: CurtainWall_02
AC_Pset_RenovationAndPhasing - Renovation Status: Existing
BaseQuantities - Width: 0.682687 m; Perimeter: 6.50537 m; GrossArea: 1.94955 m2; NetArea: 1.7545 m2; GrossVolume: 0.038991 m3; NetVolume: 0.0350901 m3
ArchiCADQuantities - Altitude à Zéro du Projet: 1.05693e-12 m; Altitude à étage: -9.425 m; Superficie de surface: 1.7545 m2; Volume net: 0.0350901 m3; Epaisseur: 0.02 m; Périmètre: 6.50537 m; Surface brute: 1.94955 m2; Surface nominale: 1.7545 m2; Largeur: 0.682687 m; Largeur nominale: 0.682687 m; Hauteur: 2.57 m; Hauteur nominale: 2.57 m

# IfcPlate: Panneau secondaire 782 x 1200 x 20, Panel-Dist-648
In: R+1
Material: Background 7019220
ArchiCADProperties - ID: Panel-Dist-648; Etage d'implantation: R+1; Calque: A-WALL-CURT; Type: Panneau de mur-rideau; Verrouillé: no; Matériau de construction / Composite / Profil / Hachure: Background 7019220; Etat de rénovation: Existant; Afficher sur filtre de rénovation: Tous les filtres appropriés; Type de panneau: Générique; Angle par rapport nord: 90 deg; Abbréviation d'orientation: O; Angle d'inclinaison: 90 deg; Fonction: Fixe; Surface extérieure: Glass-Blue; Surface intérieure: Glass-Blue; Surface latérale: Glass-Blue; Classe de panneau: Panneau secondaire; ID mur-rideau: CurtainWall_01
AC_Pset_RenovationAndPhasing - Renovation Status: Existing
BaseQuantities - Width: 0.752231 m; Perimeter: 3.79412 m; GrossArea: 0.938543 m2; NetArea: 0.861175 m2; GrossVolume: 0.0187709 m3; NetVolume: 0.0172235 m3
ArchiCADQuantities - Altitude à Zéro du Projet: 10.85 m; Altitude à étage: 5.45 m; Superficie de surface: 0.861175 m2; Volume net: 0.0172235 m3; Epaisseur: 0.02 m; Périmètre: 3.79412 m; Surface brute: 0.938543 m2; Surface nominale: 0.861175 m2; Largeur: 0.752231 m; Largeur nominale: 0.752231 m; Hauteur: 1.14483 m; Hauteur nominale: 1.14483 m

# IfcPlate: Panneau secondaire 782 x 1425 x 20, Panel-Dist-637
In: R+1
Material: Background 7019220
ArchiCADProperties - ID: Panel-Dist-637; Etage d'implantation: R+1; Calque: A-WALL-CURT; Type: Panneau de mur-rideau; Verrouillé: no; Matériau de construction / Composite / Profil / Hachure: Background 7019220; Etat de rénovation: Existant; Afficher sur filtre de rénovation: Tous les filtres appropriés; Type de panneau: Générique; Angle par rapport nord: 90 deg; Abbréviation d'orientation: O; Angle d'inclinaison: 90 deg; Fonction: Fixe; Surface extérieure: Glass-Blue; Surface intérieure: Glass-Blue; Surface latérale: Glass-Blue; Classe de panneau: Panneau secondaire; ID mur-rideau: CurtainWall_01
AC_Pset_RenovationAndPhasing - Renovation Status: Existing
BaseQuantities - Width: 0.752231 m; Perimeter: 4.24446 m; GrossArea: 1.11468 m2; NetArea: 1.03056 m2; GrossVolume: 0.0222936 m3; NetVolume: 0.0206111 m3
ArchiCADQuantities - Altitude à Zéro du Projet: 4.85 m; Altitude à étage: -0.55 m; Superficie de surface: 1.03056 m2; Volume net: 0.0206111 m3; Epaisseur: 0.02 m; Périmètre: 4.24446 m; Surface brute: 1.11468 m2; Surface nominale: 1.03056 m2; Largeur: 0.752231 m; Largeur nominale: 0.752231 m; Hauteur: 1.37 m; Hauteur nominale: 1.37 m

# IfcPlate: Panneau secondaire 782 x 1490 x 20, Panel-Dist-637
In: R+1
Material: Background 7019220
ArchiCADProperties - ID: Panel-Dist-637; Etage d'implantation: R+1; Calque: A-WALL-CURT; Type: Panneau de mur-rideau; Verrouillé: no; Matériau de construction / Composite / Profil / Hachure: Background 7019220; Etat de rénovation: Existant; Afficher sur filtre de rénovation: Tous les filtres appropriés; Type de panneau: Générique; Angle par rapport nord: 90 deg; Abbréviation d'orientation: O; Angle d'inclinaison: 90 deg; Fonction: Fixe; Surface extérieure: Glass-Blue; Surface intérieure: Glass-Blue; Surface latérale: Glass-Blue; Classe de panneau: Panneau secondaire; ID mur-rideau: CurtainWall_01
AC_Pset_RenovationAndPhasing - Renovation Status: Existing
BaseQuantities - Width: 0.752231 m; Perimeter: 4.38446 m; GrossArea: 1.16552 m2; NetArea: 1.08321 m2; GrossVolume: 0.0233105 m3; NetVolume: 0.0216643 m3
ArchiCADQuantities - Altitude à Zéro du Projet: 7.85 m; Altitude à étage: 2.45 m; Superficie de surface: 1.08321 m2; Volume net: 0.0216643 m3; Epaisseur: 0.02 m; Périmètre: 4.38446 m; Surface brute: 1.16552 m2; Surface nominale: 1.08321 m2; Largeur: 0.752231 m; Largeur nominale: 0.752231 m; Hauteur: 1.44 m; Hauteur nominale: 1.44 m

# IfcPlate: Panneau secondaire 820 x 25 x 20, Panel-Dist-184
In: Mezzannine
Material: Background 7019220
ArchiCADProperties - ID: Panel-Dist-184; Etage d'implantation: Mezzannine; Calque: A-WALL-CURT; Type: Panneau de mur-rideau; Verrouillé: no; Matériau de construction / Composite / Profil / Hachure: Background 7019220; Etat de rénovation: Existant; Afficher sur filtre de rénovation: Tous les filtres appropriés; Type de panneau: Générique; Angle par rapport nord: -82.4095 deg; Abbréviation d'orientation: E; Angle d'inclinaison: 90 deg; Fonction: Fixe; Surface extérieure: Glass-Blue; Surface intérieure: Glass-Blue; Surface latérale: Glass-Blue; Classe de panneau: Panneau secondaire; ID mur-rideau: CurtainWall_02
AC_Pset_RenovationAndPhasing - Renovation Status: Existing
BaseQuantities - Width: 0 m; Perimeter: 0 m; GrossArea: 0.0205 m2; NetArea: 0 m2; GrossVolume: 0.000409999 m3; NetVolume: 0 m3
ArchiCADQuantities - Altitude à Zéro du Projet: 4.3 m; Altitude à étage: -5.125 m; Superficie de surface: 0 m2; Volume net: 0 m3; Epaisseur: 0.02 m; Périmètre: 0 m; Surface brute: 0.0205 m2; Surface nominale: 0 m2; Largeur: 0 m; Largeur nominale: 0 m; Hauteur: 0 m; Hauteur nominale: 0 m

# IfcPlate: Panneau secondaire 820 x 2625 x 20, Panel-Dist-173
In: Mezzannine
Material: Background 7019220
ArchiCADProperties - ID: Panel-Dist-173; Etage d'implantation: Mezzannine; Calque: A-WALL-CURT; Type: Panneau de mur-rideau; Verrouillé: no; Matériau de construction / Composite / Profil / Hachure: Background 7019220; Etat de rénovation: Existant; Afficher sur filtre de rénovation: Tous les filtres appropriés; Type de panneau: Générique; Angle par rapport nord: -82.4095 deg; Abbréviation d'orientation: E; Angle d'inclinaison: 90 deg; Fonction: Fixe; Surface extérieure: Glass-Blue; Surface intérieure: Glass-Blue; Surface latérale: Glass-Blue; Classe de panneau: Panneau secondaire; ID mur-rideau: CurtainWall_02
AC_Pset_RenovationAndPhasing - Renovation Status: Existing
BaseQuantities - Width: 0.76 m; Perimeter: 6.66 m; GrossArea: 2.1525 m2; NetArea: 1.9532 m2; GrossVolume: 0.04305 m3; NetVolume: 0.039064 m3
ArchiCADQuantities - Altitude à Zéro du Projet: 1.05693e-12 m; Altitude à étage: -9.425 m; Superficie de surface: 1.9532 m2; Volume net: 0.039064 m3; Epaisseur: 0.02 m; Périmètre: 6.66 m; Surface brute: 2.1525 m2; Surface nominale: 1.9532 m2; Largeur: 0.76 m; Largeur nominale: 0.76 m; Hauteur: 2.57 m; Hauteur nominale: 2.57 m

# IfcPlate: Panneau secondaire 880 x 1490 x 20 (9)
In: Mezzannine
Material: Background 7019220
ArchiCADProperties - ID: Panel-Dist-173; Etage d'implantation: Mezzannine; Calque: A-WALL-CURT; Type: Panneau de mur-rideau; Verrouillé: no; Matériau de construction / Composite / Profil / Hachure: Background 7019220; Etat de rénovation: Existant; Afficher sur filtre de rénovation: Tous les filtres appropriés; Type de panneau: Générique; Angle par rapport nord: -82.4095 deg; Abbréviation d'orientation: E; Angle d'inclinaison: 90 deg; Fonction: Fixe; Surface extérieure: Glass-Blue; Surface intérieure: Glass-Blue; Surface latérale: Glass-Blue; Classe de panneau: Panneau secondaire; ID mur-rideau: CurtainWall_02
AC_Pset_RenovationAndPhasing - Renovation Status: Existing
BaseQuantities - Width: 0.82 m; Perimeter: 4.52 m; GrossArea: 1.3112 m2; NetArea: 1.1808 m2; GrossVolume: 0.026224 m3; NetVolume: 0.023616 m3
ArchiCADQuantities - Altitude à Zéro du Projet: 2.8 m; Altitude à étage: -6.625 m; Superficie de surface: 1.1808 m2; Volume net: 0.023616 m3; Epaisseur: 0.02 m; Périmètre: 4.52 m; Surface brute: 1.3112 m2; Surface nominale: 1.1808 m2; Largeur: 0.82 m; Largeur nominale: 0.82 m; Hauteur: 1.44 m; Hauteur nominale: 1.44 m

# IfcPlate: Panneau secondaire 880 x 25 x 20 (17)
In: Mezzannine
Material: Background 7019220
ArchiCADProperties - Etage d'implantation: Mezzannine; Calque: A-WALL-CURT; Type: Panneau de mur-rideau; Verrouillé: no; Matériau de construction / Composite / Profil / Hachure: Background 7019220; Etat de rénovation: Existant; Afficher sur filtre de rénovation: Tous les filtres appropriés; Type de panneau: Générique; Angle par rapport nord: -82.4095 deg; Abbréviation d'orientation: E; Angle d'inclinaison: 90 deg; Fonction: Fixe; Surface extérieure: Glass-Blue; Surface intérieure: Glass-Blue; Surface latérale: Glass-Blue; Classe de panneau: Panneau secondaire; ID mur-rideau: CurtainWall_02
AC_Pset_RenovationAndPhasing - Renovation Status: Existing
BaseQuantities - Width: 0 m; Perimeter: 0 m; GrossArea: 0.022 m2; NetArea: 0 m2; GrossVolume: 0.000439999 m3; NetVolume: 0 m3
ArchiCADQuantities - Altitude à Zéro du Projet: 4.3 m; Altitude à étage: -5.125 m; Superficie de surface: 0 m2; Volume net: 0 m3; Epaisseur: 0.02 m; Périmètre: 0 m; Surface brute: 0.022 m2; Surface nominale: 0 m2; Largeur: 0 m; Largeur nominale: 0 m; Hauteur: 0 m; Hauteur nominale: 0 m
Name | ID
Panel-Dist-197 | Panel-Dist-197
Panel-Dist-196 | Panel-Dist-196
Panel-Dist-195 | Panel-Dist-195
Panel-Dist-194 | Panel-Dist-194
Panel-Dist-193 | Panel-Dist-193
Panel-Dist-192 | Panel-Dist-192
Panel-Dist-191 | Panel-Dist-191
Panel-Dist-190 | Panel-Dist-190
Panel-Dist-189 | Panel-Dist-189
Panel-Dist-188 | Panel-Dist-188
Panel-Dist-187 | Panel-Dist-187
Panel-Dist-186 | Panel-Dist-186
Panel-Dist-185 | Panel-Dist-185
Panel-Dist-198 | Panel-Dist-198
Panel-Dist-199 | Panel-Dist-199
Panel-Dist-201 | Panel-Dist-201
Panel-Dist-200 | Panel-Dist-200

# IfcPlate: Panneau secondaire 880 x 2625 x 20 (17)
In: Mezzannine
Material: Background 7019220
ArchiCADProperties - ID: Panel-Dist-173; Etage d'implantation: Mezzannine; Calque: A-WALL-CURT; Type: Panneau de mur-rideau; Verrouillé: no; Matériau de construction / Composite / Profil / Hachure: Background 7019220; Etat de rénovation: Existant; Afficher sur filtre de rénovation: Tous les filtres appropriés; Type de panneau: Générique; Angle par rapport nord: -82.4095 deg; Abbréviation d'orientation: E; Angle d'inclinaison: 90 deg; Fonction: Fixe; Surface extérieure: Glass-Blue; Surface intérieure: Glass-Blue; Surface latérale: Glass-Blue; Classe de panneau: Panneau secondaire; ID mur-rideau: CurtainWall_02
AC_Pset_RenovationAndPhasing - Renovation Status: Existing
BaseQuantities - Width: 0.82 m; Perimeter: 6.78 m; GrossArea: 2.31 m2; NetArea: 2.1074 m2; GrossVolume: 0.0462 m3; NetVolume: 0.042148 m3
ArchiCADQuantities - Altitude à Zéro du Projet: 1.05693e-12 m; Altitude à étage: -9.425 m; Superficie de surface: 2.1074 m2; Volume net: 0.042148 m3; Epaisseur: 0.02 m; Périmètre: 6.78 m; Surface brute: 2.31 m2; Surface nominale: 2.1074 m2; Largeur: 0.82 m; Largeur nominale: 0.82 m; Hauteur: 2.57 m; Hauteur nominale: 2.57 m

# IfcRailing: Rampe tordue 18 (8)
In: Mezzannine
Material: 50 %
ArchiCADProperties - ID: Tárgy-009; Etage d'implantation: Mezzannine; Calque: A-EQMT; Type: Objet; Verrouillé: no; Nom Elément de Bibliothèque: Rampe tordue 18; Matériau de construction / Composite / Profil / Hachure: 50 %; Fonction structurelle: Elément porteur; Position: Intérieur; Classification d'lément: Type ArchiCAD; Etat de rénovation: Existant; Afficher sur filtre de rénovation: Tous les filtres appropriés; Surface: Mtl-Stainless Steel
AC_Pset_Rampe_tordue_18 - 3D (gs_detlevel_3D): Détaillé; 3D (gs_detlevel_3d_m): 2; Appelé comme Macro escalier: no; Côté 'A'=Longueur main courante: yes; Type rampe et paramètres saisie (ptyp): Carré; Type rampe et paramètres saisie (ptyp_m): 1; Méthode d'inclinaison (rom): Non incliné; Méthode orientation rampe: 1; Méthode d'inclinaison (iInclinationMethod): 1; Méthode de mesure: Vertical; Modes de mesure rampe: 1; Angle d'inclinaison: 25 deg; Angle de courbure: 90 deg; Type main courante (hrt): Arrondi; Type main courante (hrt_m): 2; Nb. de câbles: 7; Résolution arc rampe: 32; Résolution coupe transversale: 12; Ombre: yes; Afficher points chauds 2D en 3D: no; Stylo contour: Fer; Motif de hachure: Background Fill-International; Stylo hachure: Fond - Couleur 1; Stylo fond de hachure: Fond - Couleur 1; Afficher axe: yes; Type de ligne d'axe: 6; Stylo ligne d'axe: Fer; 2D symbolique: no; Type de ligne symbole (postSymbolType): Sans; Type de ligne symbole (iPostSymbolType): 0; Type de ligne de poteau: 1; Stylo ligne de poteau: Structurel - Général; Main courante: 06 | W Pine H; Poteau: 05 | Stainless Reflective; Fil: 05 | Stainless Reflective; Coût: 0; Type de groupe (FM_Type): Autres; Type de groupe (iFMType): 25; Poids de l'objet: 0; Unité poids de l'objet: kg
AC_Pset_RenovationAndPhasing - Renovation Status: Existing
Pset_RailingCommon - IsExternal: no
ArchiCADQuantities - Altitude à Zéro du Projet: 9.35052 m; Altitude à étage: -0.0744786 m; Hauteur (Taille en Z): 1.15 m; Largeur (B): 0.05 m
AC_Equantity_Rampe_tordue_18 - 2ème dimension: 0.05 m; Hauteur: 1.15 m; Hauteur rampe (hr): 1 m; Hauteur rampe (hrPerp): 1 m; Rayon de courbure: 1 m; Distance de Dalle/Escalier (ds): 0.15 m; Distance de Dalle/Escalier (dsPerp): 0.15 m; Diamètre main courante: 0.05 m; Largeur main courante: 0.05 m; Hauteur main courante: 0.025 m; Débord main courante: 0 m; Largeur poteau: 0.05 m; Epaisseur poteau: 0.015 m; Débord base de poteau (gs_PostBaseOverhang): 0 m; Débord base de poteau (gs_PostBaseOverhangPerp): 0 m; Diamètre câble: 0.015 m; Niveau inférieur: 1 m; Niveau supérieur: 0 m
Name | Nom de Zone | Numéro de Zone | Angle de rotation (deg) | Angle de coupe gauche (deg) | Angle de coupe droit (deg) | Nb. poteau | Superficie de surface (m2) | Volume net (m3) = Volume (m3) | Superficie (m2) | Longueur (A) (m) = 1ère dimension (m) = Longueur horizontale de rampe (m) = Longueur rampe (m) | Débord main courante (gauche) (hroL) (m) = Débord main courante (gauche) (hroLDiagonal) (m) | Débord main courante (droite) (hroR) (m) = Débord main courante (droite) (hroRDiagonal) (m) | Ecart entre poteaux (m)
Tárgy-009 | Vide | 001 | 270 | 90 | 45 | 12 | 12.9886 | 0.0805142 | 1.17116 | 23.4231 | 0.0319163 | 0.0551155 | 2.12146
Tárgy-009 | Vide | 001 | 180 | 45 | 135 | 14 | 11.7797 | 0.0725018 | 1.0155 | 20.31 | 0.0319163 | 0.0551155 | 1.55561
Tárgy-009 | Plateau bureaux | 005 | 270 | 135 | 45 | 5 | 4.05973 | 0.0249874 | 0.34875 | 6.975 | 0.0319163 | 0.0551155 | 1.72199
Tárgy-009 | Plateau bureaux | 005 | 180 | 90 | 135 | 5 | 3.16808 | 0.0193316 | 0.256222 | 5.12443 | 0.0319163 | 0.0551155 | 1.25935
Tárgy-009 | Vide | 001 | 90 | 47.4646 | 135 | 6 | 5.26168 | 0.0324463 | 0.458357 | 9.16714 | 0.025 | 0.0551155 | 1.81741
Tárgy-009 | Cafetaria | 007 | 180 | 137.465 | 45 | 3 | 1.38129 | 0.00831487 | 0.100562 | 2.01124 | 0.0319163 | 0.0551155 | 0.962106
Tárgy-009 | Cafetaria | 007 | 90 | 47.4646 | 90 | 6 | 8.47646 | 0.0528668 | 0.792568 | 15.8514 | 0.0319163 | 0.0551155 | 3.15287
Tárgy-009 |  |  | 180 | 137.465 | 90 | 2 | 0.445452 | 0.00251195 | 0.0171981 | 0.343962 | 0.025 | 0.025 | 0.293962

# IfcSlab: % 25 359672764 130, SLAB
In: Rez de chaussée
Type - PredefinedType: FLOOR
Description: 200*31407; Material: % 25 359672764 0.13 m
ArchiCADProperties - ID: SLAB; Etage d'implantation: Rez de chaussée; Calque: A-FLOR; Type: Dalle; Verrouillé: no; Matériau de construction / Composite / Profil / Hachure: % 25 359672764; Fonction structurelle: Elément non porteur; Position: Extérieur; Classification d'lément: Type ArchiCAD; Etat de rénovation: Existant; Afficher sur filtre de rénovation: Tous les filtres appropriés; Type de structure: Basique; Surface supérieure: 09 | Paint-02 Whitewash; Surface latérale: 09 | Paint-02 Whitewash; Surface inférieure: 09 | Paint-02 Whitewash; Matériau de construction / Composite: % 25 359672764; Hachure de recouvrement: Empty Fill; Emplacement de plan de référence: Haut
AC_Pset_RenovationAndPhasing - Renovation Status: Existing
Pset_SlabCommon - LoadBearing: no; IsExternal: yes
BaseQuantities - Width: 0.13 m; Perimeter: 17.5905 m; GrossArea: 9.60236 m2; NetArea: 9.60236 m2; GrossVolume: 1.2593 m3; NetVolume: 1.2593 m3
ArchiCADQuantities - Altitude à Zéro du Projet: 4.4 m; Altitude à étage: 4.4 m; Hauteur: 0.13 m; Superficie de surface: 11.0886 m2; Volume net: 1.2593 m3; Superficie: 11.0886 m2; Surface inférieure: 9.60236 m2; Surface supérieure: 11.0886 m2; Surface d'arête: 1.32554 m2; Volume: 1.2593 m3; Périmètre: 17.5905 m; Surface des trous: 0 m2; Périmètre des trous: 0 m; Epaisseur: 0.13 m; Surface brute supérieure de la Dalle: 11.0886 m2; Surface brute inférieure de la Dalle: 11.0886 m2; Surface brute des bords de la Dalle: 2.28677 m2; Volume brut de la Dalle: 1.44152 m3; Surface conditionnelle inférieure: 9.60236 m2; Surface conditionnelle supérieure: 11.0886 m2; Volume conditionnel: 1.2593 m3; Surface brute supérieure de la dalle avec trous: 11.0886 m2; Surface brute inférieure de la dalle avec trous: 11.0886 m2; Surface brute des arêtes de la dalle avec trous: 2.28677 m2; Volume brut de la dalle avec trous: 1.44152 m3; Altitude supérieure: 4.4 m; Altitude inférieure: 4.27 m

# IfcSlab: % 25 359672764 200 (6)
Type - PredefinedType: FLOOR
Description: 200*31407; Material: % 25 359672764 0.2 m
ArchiCADProperties - ID: SLAB; Calque: A-FLOR; Type: Dalle; Verrouillé: no; Matériau de construction / Composite / Profil / Hachure: % 25 359672764; Fonction structurelle: Non défini; Position: Non défini; Classification d'lément: Type ArchiCAD; Etat de rénovation: Existant; Afficher sur filtre de rénovation: Tous les filtres appropriés; Type de structure: Basique; Surface supérieure: 03 | Concrete Light; Surface latérale: 03 | Concrete Light; Surface inférieure: 03 | Concrete Light; Matériau de construction / Composite: % 25 359672764; Hachure de recouvrement: Empty Fill; Emplacement de plan de référence: Haut
AC_Pset_RenovationAndPhasing - Renovation Status: Existing
BaseQuantities - Width: 0.2 m
ArchiCADQuantities - Hauteur: 0.2 m; Surface des trous: 0 m2; Périmètre des trous: 0 m; Epaisseur: 0.2 m
Name | In | Etage d'implantation | Perimeter (m) = Périmètre (m) | GrossArea (m2) = NetArea (m2) = Surface inférieure (m2) = Surface conditionnelle inférieure (m2) | GrossVolume (m3) = NetVolume (m3) = Volume net (m3) = Volume (m3) = Volume conditionnel (m3) | Altitude à Zéro du Projet (m) = Altitude supérieure (m) | Altitude à étage (m) | Superficie de surface (m2) = Superficie (m2) = Surface supérieure (m2) = Surface conditionnelle supérieure (m2) | Surface d'arête (m2) | Surface brute supérieure de la Dalle (m2) = Surface brute inférieure de la Dalle (m2) = Surface brute supérieure de la dalle avec trous (m2) = Surface brute inférieure de la dalle avec trous (m2) | Surface brute des bords de la Dalle (m2) = Surface brute des arêtes de la dalle avec trous (m2) | Volume brut de la Dalle (m3) = Volume brut de la dalle avec trous (m3) | Altitude inférieure (m)
SLAB | Rez de chaussée | Rez de chaussée | 8.74275 | 4.5681 | 0.91362 | 2.98144 | 2.98144 | 4.5681 | 1.39558 | 4.58424 | 1.74855 | 0.916848 | 2.78144
SLAB | R+1 | R+1 | 8.17275 | 3.59349 | 0.718698 | 5.4 | 0 | 3.59349 | 1.63455 | 3.59349 | 1.63455 | 0.718698 | 5.2
SLAB | R+1 | R+1 | 7.78275 | 3.31402 | 0.662803 | 5.4 | 0 | 3.31402 | 1.30005 | 3.32424 | 1.55655 | 0.664848 | 5.2
SLAB | Mezzannine | Mezzannine | 7.78275 | 3.32218 | 0.664428 | 9.425 | 0 | 3.32211 | 1.32356 | 3.32424 | 1.55655 | 0.664848 | 9.225
SLAB | R+2 | R+2 | 7.71989 | 3.28444 | 0.656887 | 13.45 | 0 | 3.28444 | 1.54398 | 3.28444 | 1.54398 | 0.656887 | 13.25
SLAB | R+2 | R+2 | 7.93275 | 3.52111 | 0.684102 | 13.45 | 0 | 3.35344 | 1.39559 | 3.52111 | 1.58655 | 0.704223 | 13.25

# IfcSlab: 200*28424, SLAB
In: Toiture
Description: 200*30749; PredefinedType: FLOOR; Material: Env. - Gravier 0.1 m, Etanchéité - Fondation 0.005 m, Isolation Int. - Polyuréthane 0.16 m, Struct. - B.A. coulé 0.2 m, Finition int - Enduit plâtre 0.01 m
ArchiCADProperties - ID: SLAB; Etage d'implantation: Toiture; Calque: A-FLOR; Type: Dalle; Verrouillé: no; Matériau de construction / Composite / Profil / Hachure: 7.5-Terrasse: Béton + étanch. + isol + gravier; Fonction structurelle: Elément porteur; Position: Intérieur; Classification d'lément: Type ArchiCAD; Etat de rénovation: Existant; Afficher sur filtre de rénovation: Tous les filtres appropriés; Type de structure: Composite; Surface supérieure: 03 | Concrete Light; Surface latérale: 03 | Concrete Light; Surface inférieure: 09 | Paint-01 Ceiling White; Matériau de construction / Composite: 7.5-Terrasse: Béton + étanch. + isol + gravier; Hachure de recouvrement: Empty Fill; Emplacement de plan de référence: Haut
AC_Pset_RenovationAndPhasing - Renovation Status: Existing
Pset_SlabCommon - LoadBearing: yes; IsExternal: no
BaseQuantities - Width: 0.475 m; Perimeter: 251.16 m; GrossArea: 1797.1 m2; NetArea: 1750.23 m2; GrossVolume: 861.645 m3; NetVolume: 839.381 m3
ArchiCADQuantities - Altitude à Zéro du Projet: 17.425 m; Altitude à étage: 0.025 m; Hauteur: 0.475 m; Superficie de surface: 1749.61 m2; Volume net: 839.381 m3; Superficie: 1749.61 m2; Surface inférieure: 1750.23 m2; Surface supérieure: 1749.61 m2; Surface d'arête: 54.8872 m2; Volume: 839.381 m3; Périmètre: 251.16 m; Surface des trous: 46.8726 m2; Périmètre des trous: 47.6832 m; Epaisseur: 0.475 m; Surface brute supérieure de la Dalle: 1837.86 m2; Surface brute inférieure de la Dalle: 1837.86 m2; Surface brute des bords de la Dalle: 96.6514 m2; Volume brut de la Dalle: 872.983 m3; Surface conditionnelle inférieure: 1750.23 m2; Surface conditionnelle supérieure: 1749.61 m2; Volume conditionnel: 839.381 m3; Surface brute supérieure de la dalle avec trous: 1790.99 m2; Surface brute inférieure de la dalle avec trous: 1790.99 m2; Surface brute des arêtes de la dalle avec trous: 119.301 m2; Volume brut de la dalle avec trous: 850.718 m3; Altitude supérieure: 17.425 m; Altitude inférieure: 16.95 m

# IfcSlab: 200*30675, SLAB
In: R+2
Description: 200*30749; PredefinedType: FLOOR; Material: Struct. - Chape 0.06 m, Isolation Int. - Polyuréthane 0.06 m, Struct. - B.A. coulé 0.18 m
ArchiCADProperties - ID: SLAB; Etage d'implantation: R+2; Calque: A-FLOR; Type: Dalle; Verrouillé: no; Matériau de construction / Composite / Profil / Hachure: 5.0-Dalle & Chape (Simplifié); Fonction structurelle: Elément porteur; Position: Intérieur; Classification d'lément: Type ArchiCAD; Etat de rénovation: Existant; Afficher sur filtre de rénovation: Tous les filtres appropriés; Type de structure: Composite; Surface supérieure: 09 | Paint-01 Ceiling White; Surface latérale: 03 | Concrete Light; Surface inférieure: 09 | Paint-01 Ceiling White; Matériau de construction / Composite: 5.0-Dalle & Chape (Simplifié); Hachure de recouvrement: Empty Fill; Emplacement de plan de référence: Haut
AC_Pset_RenovationAndPhasing - Renovation Status: Existing
Pset_SlabCommon - LoadBearing: yes; IsExternal: no
BaseQuantities - Width: 0.3 m; Perimeter: 286.227 m; GrossArea: 1833.27 m2; NetArea: 1764.42 m2; GrossVolume: 545.823 m3; NetVolume: 525.171 m3
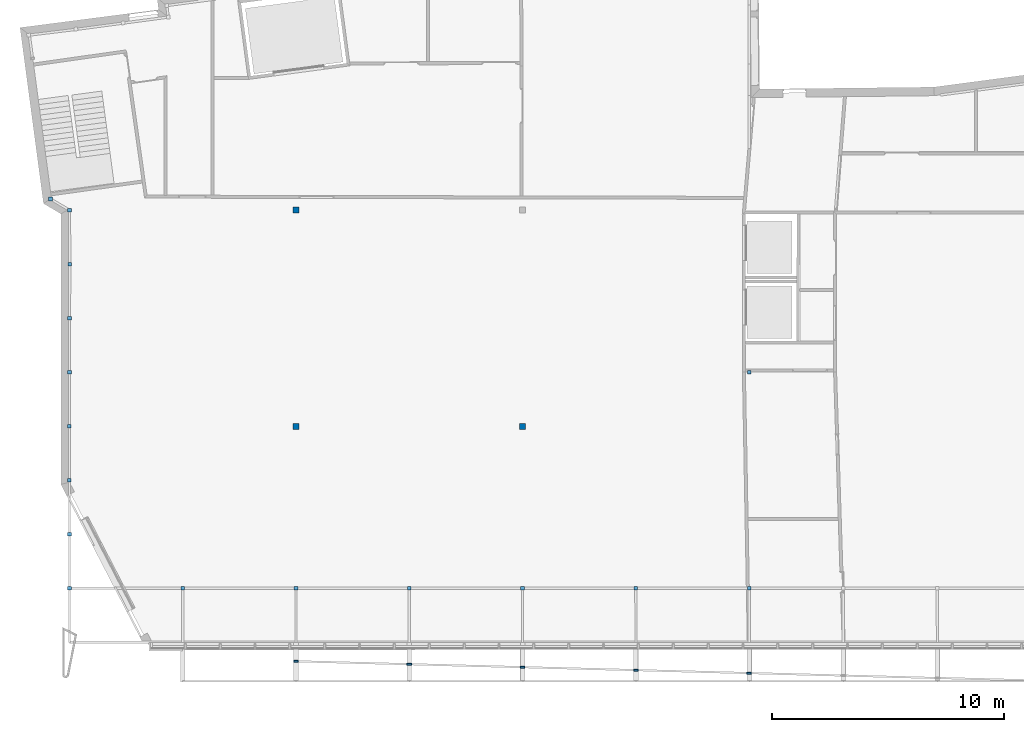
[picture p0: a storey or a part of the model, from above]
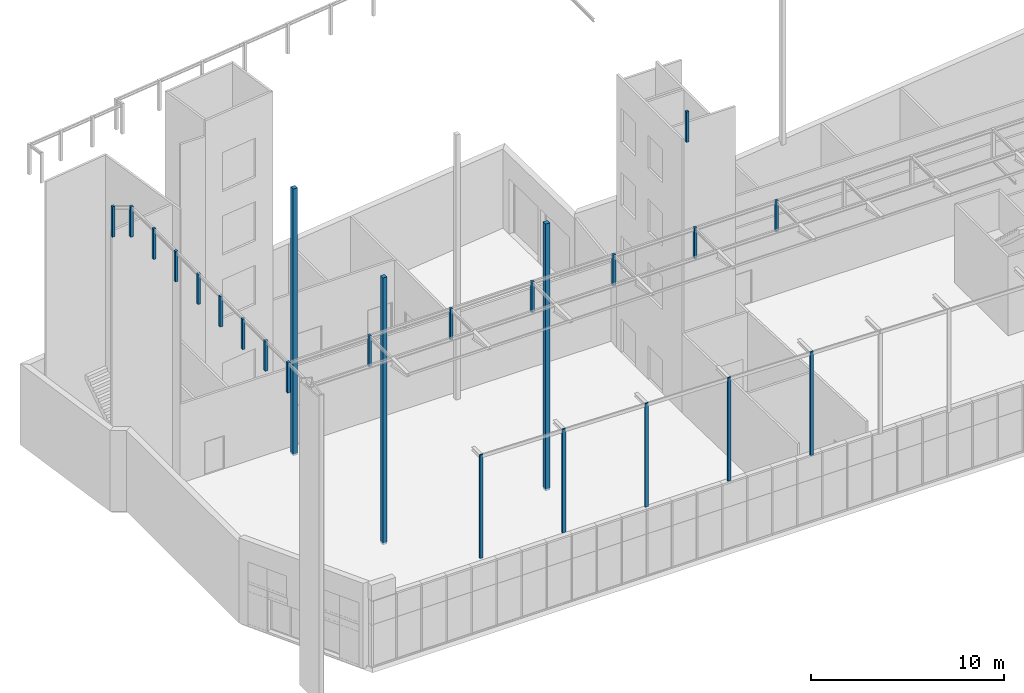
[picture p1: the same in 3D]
Properties of the parts of a building model (IFC2X3), part 13 of 19

# IfcSlab: 200*30675, SLAB
ArchiCADQuantities - Altitude à Zéro du Projet: 13.45 m; Altitude à étage: -2.61124e-13 m; Hauteur: 0.3 m; Superficie de surface: 1727.73 m2; Volume net: 525.171 m3; Superficie: 1727.73 m2; Surface inférieure: 1764.42 m2; Surface supérieure: 1727.73 m2; Surface d'arête: 56.8798 m2; Volume: 525.171 m3; Périmètre: 286.227 m; Surface des trous: 68.8418 m2; Périmètre des trous: 82.036 m; Epaisseur: 0.3 m; Surface brute supérieure de la Dalle: 1833.33 m2; Surface brute inférieure de la Dalle: 1833.33 m2; Surface brute des bords de la Dalle: 61.2573 m2; Volume brut de la Dalle: 550 m3; Surface conditionnelle inférieure: 1764.42 m2; Surface conditionnelle supérieure: 1727.73 m2; Volume conditionnel: 525.171 m3; Surface brute supérieure de la dalle avec trous: 1764.49 m2; Surface brute inférieure de la dalle avec trous: 1764.49 m2; Surface brute des arêtes de la dalle avec trous: 85.8681 m2; Volume brut de la dalle avec trous: 529.347 m3; Altitude supérieure: 13.45 m; Altitude inférieure: 13.15 m

# IfcSlab: 200*30749 (2)
In: Mezzannine
Description: 200*30749; PredefinedType: FLOOR; Material: Struct. - Chape 0.06 m, Isolation Int. - Polyuréthane 0.06 m, Struct. - B.A. coulé 0.18 m
ArchiCADProperties - ID: SLAB; Etage d'implantation: Mezzannine; Calque: A-FLOR; Type: Dalle; Verrouillé: no; Matériau de construction / Composite / Profil / Hachure: 5.0-Dalle & Chape (Simplifié); Fonction structurelle: Elément porteur; Position: Intérieur; Classification d'lément: Type ArchiCAD; Etat de rénovation: Existant; Afficher sur filtre de rénovation: Tous les filtres appropriés; Type de structure: Composite; Surface supérieure: 09 | Paint-01 Ceiling White; Surface latérale: 03 | Concrete Light; Surface inférieure: 09 | Paint-01 Ceiling White; Matériau de construction / Composite: 5.0-Dalle & Chape (Simplifié); Hachure de recouvrement: Empty Fill; Emplacement de plan de référence: Haut
AC_Pset_RenovationAndPhasing - Renovation Status: Existing
Pset_SlabCommon - LoadBearing: yes; IsExternal: no
BaseQuantities - Width: 0.3 m
ArchiCADQuantities - Altitude à Zéro du Projet: 9.425 m; Altitude à étage: -2.61124e-13 m; Hauteur: 0.3 m; Epaisseur: 0.3 m; Altitude supérieure: 9.425 m; Altitude inférieure: 9.125 m
Name | Perimeter (m) = Périmètre (m) | GrossArea (m2) | NetArea (m2) = Surface inférieure (m2) = Surface conditionnelle inférieure (m2) | GrossVolume (m3) | NetVolume (m3) = Volume net (m3) = Volume (m3) = Volume conditionnel (m3) | Superficie de surface (m2) = Superficie (m2) = Surface supérieure (m2) = Surface conditionnelle supérieure (m2) | Surface d'arête (m2) | Surface des trous (m2) | Périmètre des trous (m) | Surface brute supérieure de la Dalle (m2) = Surface brute inférieure de la Dalle (m2) | Surface brute des bords de la Dalle (m2) | Volume brut de la Dalle (m3) | Surface brute supérieure de la dalle avec trous (m2) = Surface brute inférieure de la dalle avec trous (m2) | Surface brute des arêtes de la dalle avec trous (m2) | Volume brut de la dalle avec trous (m3)
SLAB | 198.646 | 897.346 | 862.681 | 267.267 | 256.867 | 845.663 | 46.8393 | 34.6644 | 47.8435 | 897.419 | 45.2408 | 269.226 | 862.754 | 59.5939 | 258.826
SLAB | 98.0469 | 314.897 | 299.304 | 93.5256 | 88.8477 | 291.43 | 22.8393 | 15.5928 | 15.7962 | 314.944 | 24.6752 | 94.4833 | 299.352 | 29.4141 | 89.8055

# IfcSlab: 200*31407 (2)
In: Rez de chaussée
ArchiCADProperties - ID: SLAB; Etage d'implantation: Rez de chaussée; Calque: A-FLOR; Type: Dalle; Verrouillé: no; Classification d'lément: Type ArchiCAD; Etat de rénovation: Existant; Afficher sur filtre de rénovation: Tous les filtres appropriés; Hachure de recouvrement: Empty Fill; Emplacement de plan de référence: Haut
AC_Pset_RenovationAndPhasing - Renovation Status: Existing
Name | Description | Material | Matériau de construction / Composite / Profil / Hachure = Matériau de construction / Composite | Fonction structurelle | Position | Type de structure | ArchiCADProperties, Surface supérieure | Surface latérale | ArchiCADProperties, Surface inférieure | Width (m) = Hauteur (m) = Epaisseur (m) | Perimeter (m) = Périmètre (m) | GrossArea (m2) | NetArea (m2) = ArchiCADQuantities, Surface inférieure (m2) = Surface conditionnelle inférieure (m2) | GrossVolume (m3) | NetVolume (m3) = Volume net (m3) = Volume (m3) = Volume conditionnel (m3) | Altitude à Zéro du Projet (m) = Altitude à étage (m) = Altitude supérieure (m) | Superficie de surface (m2) = Superficie (m2) = ArchiCADQuantities, Surface supérieure (m2) = Surface conditionnelle supérieure (m2) | Surface d'arête (m2) | Surface des trous (m2) | Périmètre des trous (m) | Surface brute supérieure de la Dalle (m2) = Surface brute inférieure de la Dalle (m2) | Surface brute des bords de la Dalle (m2) | Volume brut de la Dalle (m3) | Surface brute supérieure de la dalle avec trous (m2) = Surface brute inférieure de la dalle avec trous (m2) | Surface brute des arêtes de la dalle avec trous (m2) | Volume brut de la dalle avec trous (m3) | Altitude inférieure (m)
SLAB | 200*31407 | % 25 359672764 0.3 m | % 25 359672764 | Non défini | Non défini | Basique | 03 / Concrete Light | 03 / Concrete Light | 03 / Concrete Light | 0.3 | 11.2625 | 0.00859111 | 0.00859111 | 0.00257733 | 0.00257733 | 0 | 0.00859111 | 3.37876 | 0 | 0 | 0.00859111 | 3.37876 | 0.00257733 | 0.00859111 | 3.37876 | 0.00257733 | -0.3 | PredefinedType: FLOOR
SLAB | Slab_Groundbearing_01 | Finition sol - Parquet 0.015 m, Struct. - Chape 0.045 m, Isolation Int. - Polyuréthane 0.06 m, Struct. - B.A. coulé 0.18 m, Finition int - Enduit plâtre 0.015 m | 5.0-Dalle & Chape avec parquet collé (Détaillé) | Elément porteur | Intérieur | Composite | 09 / Paint-01 Ceiling White | 09 / Paint-02 Whitewash | 09 / Stucco White | 0.315 | 229.933 | 1822.77 | 1793.35 | 568.936 | 559.666 | 0.12 | 1741.9 | 58.9645 | 29.4275 | 32.1892 | 1822.8 | 62.2893 | 574.181 | 1793.37 | 72.4289 | 564.911 | -0.195 | Pset_SlabCommon - LoadBearing: yes; IsExternal: no

# IfcSlab: 5.0-Dalle & Chape (Simplifié) 300, SLAB
In: Toiture
Type - PredefinedType: FLOOR
Description: 200*30749; Material: Struct. - Chape 0.06 m, Isolation Int. - Polyuréthane 0.06 m, Struct. - B.A. coulé 0.18 m
ArchiCADProperties - ID: SLAB; Etage d'implantation: Toiture; Calque: A-FLOR; Type: Dalle; Verrouillé: no; Matériau de construction / Composite / Profil / Hachure: 5.0-Dalle & Chape (Simplifié); Fonction structurelle: Elément porteur; Position: Intérieur; Classification d'lément: Type ArchiCAD; Etat de rénovation: Existant; Afficher sur filtre de rénovation: Tous les filtres appropriés; Type de structure: Composite; Surface supérieure: 03 | Concrete Light; Surface latérale: 03 | Concrete Light; Surface inférieure: 03 | Concrete Light; Matériau de construction / Composite: 5.0-Dalle & Chape (Simplifié); Hachure de recouvrement: Empty Fill; Emplacement de plan de référence: Haut
AC_Pset_RenovationAndPhasing - Renovation Status: Existing
Pset_SlabCommon - LoadBearing: yes; IsExternal: no
BaseQuantities - Width: 0.3 m; Perimeter: 10.671 m; GrossArea: 5.6761 m2; NetArea: 5.6761 m2; GrossVolume: 1.66764 m3; NetVolume: 1.66764 m3
ArchiCADQuantities - Altitude à Zéro du Projet: 17.26 m; Altitude à étage: -0.14 m; Hauteur: 0.3 m; Superficie de surface: 5.32423 m2; Volume net: 1.66764 m3; Superficie: 5.32423 m2; Surface inférieure: 5.6761 m2; Surface supérieure: 5.32423 m2; Surface d'arête: 3.00659 m2; Volume: 1.66764 m3; Périmètre: 10.671 m; Surface des trous: 0 m2; Périmètre des trous: 0 m; Epaisseur: 0.3 m; Surface brute supérieure de la Dalle: 5.6761 m2; Surface brute inférieure de la Dalle: 5.6761 m2; Surface brute des bords de la Dalle: 3.20129 m2; Volume brut de la Dalle: 1.70283 m3; Surface conditionnelle inférieure: 5.6761 m2; Surface conditionnelle supérieure: 5.32423 m2; Volume conditionnel: 1.66764 m3; Surface brute supérieure de la dalle avec trous: 5.6761 m2; Surface brute inférieure de la dalle avec trous: 5.6761 m2; Surface brute des arêtes de la dalle avec trous: 3.20129 m2; Volume brut de la dalle avec trous: 1.70283 m3; Altitude supérieure: 17.26 m; Altitude inférieure: 16.96 m

# IfcSlab: 5.0-Dalle& Chape avec sous-face isolée + bois (détaillé) 400, SLAB
In: R+1
Type - PredefinedType: FLOOR
Description: 200*31407; Material: Finition sol - Parquet 0.015 m, Struct. - Chape 0.045 m, Isolation Int. - Polyuréthane 0.04 m, Struct. - B.A. coulé 0.18 m, Isolation - Polystyrène extrudé 0.1 m, Finition int - Enduit plâtre 0.02 m
ArchiCADProperties - ID: SLAB; Etage d'implantation: R+1; Calque: A-FLOR; Type: Dalle; Verrouillé: no; Matériau de construction / Composite / Profil / Hachure: 5.0-Dalle& Chape avec sous-face isolée + bois (détaillé); Fonction structurelle: Elément porteur; Position: Intérieur; Classification d'lément: Type ArchiCAD; Etat de rénovation: Existant; Afficher sur filtre de rénovation: Tous les filtres appropriés; Type de structure: Composite; Surface supérieure: 09 | Paint-01 Ceiling White; Surface latérale: 03 | Concrete Light; Surface inférieure: 09 | Paint-01 Ceiling White; Matériau de construction / Composite: 5.0-Dalle& Chape avec sous-face isolée + bois (détaillé); Hachure de recouvrement: Empty Fill; Emplacement de plan de référence: Haut
AC_Pset_RenovationAndPhasing - Renovation Status: Existing
Pset_SlabCommon - LoadBearing: yes; IsExternal: no
BaseQuantities - Width: 0.4 m; Perimeter: 287.977 m; GrossArea: 1829.34 m2; NetArea: 1761.53 m2; GrossVolume: 746.879 m3; NetVolume: 719.756 m3
ArchiCADQuantities - Altitude à Zéro du Projet: 5.4 m; Altitude à étage: 0 m; Hauteur: 0.4 m; Superficie de surface: 1797.02 m2; Volume net: 719.756 m3; Superficie: 1797.02 m2; Surface inférieure: 1761.53 m2; Surface supérieure: 1797.02 m2; Surface d'arête: 81.4251 m2; Volume: 719.756 m3; Périmètre: 287.977 m; Surface des trous: 67.8081 m2; Périmètre des trous: 81.4447 m; Epaisseur: 0.4 m; Surface brute supérieure de la Dalle: 1900.05 m2; Surface brute inférieure de la Dalle: 1900.05 m2; Surface brute des bords de la Dalle: 82.6128 m2; Volume brut de la Dalle: 760.019 m3; Surface conditionnelle inférieure: 1761.53 m2; Surface conditionnelle supérieure: 1797.02 m2; Volume conditionnel: 719.756 m3; Surface brute supérieure de la dalle avec trous: 1832.24 m2; Surface brute inférieure de la dalle avec trous: 1832.24 m2; Surface brute des arêtes de la dalle avec trous: 115.191 m2; Volume brut de la dalle avec trous: 732.895 m3; Altitude supérieure: 5.4 m; Altitude inférieure: 5 m

# IfcSlab: 50 % 7150420 500, SLA - 003
In: Mezzannine
Type - PredefinedType: FLOOR
Description: Roof_02; PredefinedType: ROOF; Material: 50 % 7150420 0.5 m
ArchiCADProperties - ID: SLA - 003; Etage d'implantation: Mezzannine; Calque: A-ROOF; Type: Dalle; Verrouillé: no; Matériau de construction / Composite / Profil / Hachure: 50 % 7150420; Fonction structurelle: Non défini; Position: Non défini; Classification d'lément: Type ArchiCAD; Etat de rénovation: Existant; Afficher sur filtre de rénovation: Tous les filtres appropriés; Type de structure: Basique; Surface supérieure: Surf-Poured Concrete; Surface latérale: Paint-01; Surface inférieure: Paint-01; Matériau de construction / Composite: 50 % 7150420; Hachure de recouvrement: Plank Floor; Emplacement de plan de référence: Haut
AC_Pset_RenovationAndPhasing - Renovation Status: Existing
BaseQuantities - Width: 0.5 m; Perimeter: 88.5683 m; GrossArea: 54.279 m2; NetArea: 54.279 m2; GrossVolume: 27.2597 m3; NetVolume: 27.2597 m3
ArchiCADQuantities - Altitude à Zéro du Projet: 12.125 m; Altitude à étage: 2.7 m; Hauteur: 0.5 m; Superficie de surface: 54.7688 m2; Volume net: 27.2597 m3; Superficie: 54.7688 m2; Surface inférieure: 54.279 m2; Surface supérieure: 54.7688 m2; Surface d'arête: 22.6516 m2; Volume: 27.2597 m3; Périmètre: 88.5683 m; Surface des trous: 0 m2; Périmètre des trous: 0 m; Epaisseur: 0.5 m; Surface brute supérieure de la Dalle: 66.3046 m2; Surface brute inférieure de la Dalle: 66.3046 m2; Surface brute des bords de la Dalle: 44.2841 m2; Volume brut de la Dalle: 33.1523 m3; Surface conditionnelle inférieure: 54.279 m2; Surface conditionnelle supérieure: 54.7688 m2; Volume conditionnel: 27.2597 m3; Surface brute supérieure de la dalle avec trous: 66.3046 m2; Surface brute inférieure de la dalle avec trous: 66.3046 m2; Surface brute des arêtes de la dalle avec trous: 44.2841 m2; Volume brut de la dalle avec trous: 33.1523 m3; Altitude supérieure: 12.125 m; Altitude inférieure: 11.625 m

# IfcSlab: 7.2-Toiture: Couverture + panneaux sandwich 306 (2)
In: Toiture
Type - PredefinedType: ROOF
Description: Roof_02; Material: Finition int - Enduit plâtre, Bois - OSB 01 (2), Toiture - Chevronnage & Laine de roche, Etanchéité - Pare pluie, Divers - Vide, Toiture - Tuile
ArchiCADProperties - ID: Roof; Etage d'implantation: Toiture; Calque: A-ROOF; Type: Toit; Verrouillé: no; Matériau de construction / Composite / Profil / Hachure: 7.2-Toiture: Couverture + panneaux sandwich; Fonction structurelle: Elément non porteur; Position: Extérieur; Classification d'lément: Type ArchiCAD; Etat de rénovation: Existant; Afficher sur filtre de rénovation: Tous les filtres appropriés; Type de structure: Composite; Surface supérieure: Mtl-Zinc; Surface latérale: Wd-Pine Horizontal; Surface inférieure: Wd-Pine Horizontal; Matériau de construction / Composite: 7.2-Toiture: Couverture + panneaux sandwich; Hachure de recouvrement: Roof Tile 01; Option de géométrie: Panneau-simple; Corps de découpe: Ligne de référence vers le bas; Pente: 5 deg
AC_Pset_RenovationAndPhasing - Renovation Status: Existing
Pset_SlabCommon - LoadBearing: no; IsExternal: yes
BaseQuantities - Width: 0.306 m
ArchiCADQuantities - Hauteur: 0.306 m; Surface des trous: 0 m2; Périmètre des trous: 0 m; Epaisseur: 0.306 m; Epaisseur verticales: 0.307169 m; Epaisseur couche isolation: 0 m; Longueur faîtage: 0 m; Longueur noue: 0 m; Longueur rive: 0 m; Longueur arêtier: 0 m; Longueur d'avant-toit: 0 m; Longueur rive de tête: 0 m; Longueur connexion mur latéral: 0 m; Longueur de la connexion mur d’extrémité: 0 m; Longueur connexion dôme: 0 m; Longueur connexion creux: 0 m; Nombre d'Ouvertures de toit: 0; Nombre de trous: 0; Surface des ouvertures: 0 m2
Name | Perimeter (m) = Périmètre (m) | GrossArea (m2) = NetArea (m2) = Superficie de surface (m2) = Surface supérieure nette (m2) = Surface supérieure brute (m2) = Surface conditionnelles upérieure (m2) | GrossVolume (m3) = NetVolume (m3) = Volume net (m3) = Volume (m3) = Volume conditionnel (m3) | Altitude à Zéro du Projet (m) | Altitude à étage (m) | Superficie (m2) | Surface inférieure nette (m2) | Surface nette de l'arête (m2) | Surface inférieure brute (m2) | Surface brute des bords du Toit (m2) | Volume brut du Toit (m3) | Surface conditionnelle inférieure (m2)
Roof | 153.277 | 474.744 | 145.422 | 19.3021 | 1.90207 | 472.938 | 475.726 | 46.9366 | 475.726 | 46.9366 | 145.422 | 475.726
Roof | 82.645 | 176.951 | 53.8778 | 18.9023 | 1.50226 | 176.277 | 164.127 | 25.3393 | 177.826 | 25.3402 | 54.2808 | 164.124 | ArchiCADProperties - Nom de Zone: Dégagement; Numéro de Zone: 001

# IfcSlab: Background Fill 2344352818 305, Roof_01
In: Etage
Type - PredefinedType: FLOOR
Description: Roof_01; Material: Background Fill 2344352818 0.3048 m
ArchiCADProperties - ID: Roof_01; Calque: A-ROOF; Type: Dalle; Verrouillé: no; Matériau de construction / Composite / Profil / Hachure: Background Fill 2344352818; Fonction structurelle: Elément porteur; Position: Extérieur; Classification d'lément: Type ArchiCAD; Etat de rénovation: Existant; Afficher sur filtre de rénovation: Tous les filtres appropriés; Type de structure: Basique; Surface supérieure: 06 | W Pine H; Surface latérale: 09 | Paint-02 Whitewash; Surface inférieure: 09 | Paint-02 Whitewash; Matériau de construction / Composite: Background Fill 2344352818; Hachure de recouvrement: Air Space; Emplacement de plan de référence: Haut
AC_Pset_RenovationAndPhasing - Renovation Status: Existing
Pset_SlabCommon - LoadBearing: yes; IsExternal: yes
BaseQuantities - Width: 0.3048 m; Perimeter: 39.8572 m; GrossArea: 74.3121 m2; NetArea: 74.3121 m2; GrossVolume: 22.6503 m3; NetVolume: 22.6503 m3
ArchiCADQuantities - Altitude à Zéro du Projet: 21.0947 m; Altitude à étage: 1.74468 m; Hauteur: 0.3048 m; Superficie de surface: 74.3121 m2; Volume net: 22.6503 m3; Superficie: 74.3121 m2; Surface inférieure: 74.3121 m2; Surface supérieure: 74.3121 m2; Surface d'arête: 0 m2; Volume: 22.6503 m3; Périmètre: 39.8572 m; Surface des trous: 0 m2; Périmètre des trous: 0 m; Epaisseur: 0.3048 m; Surface brute supérieure de la Dalle: 81.8675 m2; Surface brute inférieure de la Dalle: 81.8675 m2; Surface brute des bords de la Dalle: 12.1485 m2; Volume brut de la Dalle: 24.9532 m3; Surface conditionnelle inférieure: 74.3121 m2; Surface conditionnelle supérieure: 74.3121 m2; Volume conditionnel: 22.6503 m3; Surface brute supérieure de la dalle avec trous: 81.8675 m2; Surface brute inférieure de la dalle avec trous: 81.8675 m2; Surface brute des arêtes de la dalle avec trous: 12.1485 m2; Volume brut de la dalle avec trous: 24.9532 m3; Altitude supérieure: 21.0947 m; Altitude inférieure: 20.7899 m

# IfcSlab: Struct. - Béton cellulaire 300, SLAB
In: Toiture
Type - PredefinedType: FLOOR
Description: 200*30749; Material: Struct. - Béton cellulaire 0.3 m
ArchiCADProperties - ID: SLAB; Etage d'implantation: Toiture; Calque: A-FLOR; Type: Dalle; Verrouillé: no; Matériau de construction / Composite / Profil / Hachure: Struct. - Béton cellulaire; Fonction structurelle: Elément porteur; Position: Extérieur; Classification d'lément: Type ArchiCAD; Etat de rénovation: Existant; Afficher sur filtre de rénovation: Tous les filtres appropriés; Type de structure: Basique; Surface supérieure: Enduit - Blanc fin; Surface latérale: Enduit - Blanc fin; Surface inférieure: 03 | Concrete Light; Matériau de construction / Composite: Struct. - Béton cellulaire; Hachure de recouvrement: 100 %; Emplacement de plan de référence: Bas
AC_Pset_RenovationAndPhasing - Renovation Status: Existing
Pset_SlabCommon - LoadBearing: yes; IsExternal: yes
BaseQuantities - Width: 0.3 m; Perimeter: 15.6 m; GrossArea: 14.96 m2; NetArea: 14.96 m2; GrossVolume: 4.488 m3; NetVolume: 4.488 m3
ArchiCADQuantities - Altitude à Zéro du Projet: 18.4 m; Altitude à étage: 1 m; Hauteur: 0.3 m; Superficie de surface: 14.96 m2; Volume net: 4.488 m3; Superficie: 14.96 m2; Surface inférieure: 14.96 m2; Surface supérieure: 14.96 m2; Surface d'arête: 4.68 m2; Volume: 4.488 m3; Périmètre: 15.6 m; Surface des trous: 0 m2; Périmètre des trous: 0 m; Epaisseur: 0.3 m; Surface brute supérieure de la Dalle: 14.96 m2; Surface brute inférieure de la Dalle: 14.96 m2; Surface brute des bords de la Dalle: 4.68 m2; Volume brut de la Dalle: 4.488 m3; Surface conditionnelle inférieure: 14.96 m2; Surface conditionnelle supérieure: 14.96 m2; Volume conditionnel: 4.488 m3; Surface brute supérieure de la dalle avec trous: 14.96 m2; Surface brute inférieure de la dalle avec trous: 14.96 m2; Surface brute des arêtes de la dalle avec trous: 4.68 m2; Volume brut de la dalle avec trous: 4.488 m3; Altitude supérieure: 18.7 m; Altitude inférieure: 18.4 m

# IfcSlab: roof, aluminium 0259058706 271, Roof01
In: Toiture
Type - PredefinedType: ROOF
Material: Air Space 327273935 0.03 m, Insulation 335336044 0.04 m, Foreground 335336044 0.001 m, Wood 335336044 0.02 m, Air Space 355482495 0.18 m
ArchiCADProperties - ID: Roof01; Etage d'implantation: Toiture; Calque: A-ROOF; Type: Toit; Verrouillé: no; Matériau de construction / Composite / Profil / Hachure: roof, aluminium 0259058706; Fonction structurelle: Elément porteur; Position: Extérieur; Classification d'lément: Type ArchiCAD; Etat de rénovation: Existant; Afficher sur filtre de rénovation: Tous les filtres appropriés; Type de structure: Composite; Surface supérieure: Mtl-Zinc; Surface latérale: Wd-Pine Horizontal; Surface inférieure: Wd-Pine Horizontal; Matériau de construction / Composite: roof, aluminium 0259058706; Hachure de recouvrement: Roof Tile 01; Option de géométrie: Panneau-simple; Corps de découpe: Ligne de référence vers le bas; Pente: 5 deg
AC_Pset_RenovationAndPhasing - Renovation Status: Existing
Pset_SlabCommon - LoadBearing: yes; IsExternal: yes
BaseQuantities - Width: 0.271 m; Perimeter: 18.5725 m; GrossArea: 20.731 m2; NetArea: 20.731 m2; GrossVolume: 5.61811 m3; NetVolume: 5.61811 m3
ArchiCADQuantities - Altitude à Zéro du Projet: 19.6114 m; Altitude à étage: 2.21141 m; Hauteur: 0.271 m; Superficie de surface: 20.731 m2; Volume net: 5.61811 m3; Superficie: 20.6521 m2; Surface inférieure nette: 20.7311 m2; Surface supérieure nette: 20.731 m2; Surface nette de l'arête: 5.04464 m2; Volume: 5.61811 m3; Périmètre: 18.5725 m; Surface des trous: 0 m2; Périmètre des trous: 0 m; Epaisseur: 0.271 m; Epaisseur verticales: 0.272035 m; Surface inférieure brute: 20.7311 m2; Surface supérieure brute: 20.731 m2; Surface brute des bords du Toit: 5.04464 m2; Volume brut du Toit: 5.61811 m3; Surface conditionnelle inférieure: 20.7311 m2; Surface conditionnelles upérieure: 20.731 m2; Volume conditionnel: 5.61811 m3; Epaisseur couche isolation: 0 m; Longueur faîtage: 0 m; Longueur noue: 0 m; Longueur rive: 0 m; Longueur arêtier: 0 m; Longueur d'avant-toit: 0 m; Longueur rive de tête: 0 m; Longueur connexion mur latéral: 0 m; Longueur de la connexion mur d’extrémité: 0 m; Longueur connexion dôme: 0 m; Longueur connexion creux: 0 m; Nombre d'Ouvertures de toit: 0; Nombre de trous: 0; Surface des ouvertures: 0 m2

# IfcStair: STAIR (12)
Material: Concrete Block
ArchiCADProperties - Calque: A-Structural - Stairs; Type: Escalier; Verrouillé: no; Nom Elément de Bibliothèque: Escalier en U 18; Matériau de construction / Composite / Profil / Hachure: Concrete Block; Fonction structurelle: Elément porteur; Position: Intérieur; Etat de rénovation: Existant; Afficher sur filtre de rénovation: Tous les filtres appropriés; Surface: Surf-Stucco
AC_Pset_Escalier_en_U_18 - 3D: Détaillé; Revêtement contremarche: yes; Type support marches (stairBaseType): Béton; Type support marches (stairBaseType_m): 1; Rampe: 4; Rampe droite (bRightRail): no; Type de rampe (rightRailType): Cadre main courante; Rampe droite (rightRailType_m): 3; Type câble (rightWireType): Rectangulaire; Nombre de barres (nBarsRightRail): 4; Rampe gauche (bLeftRail): no; Type de rampe (leftRailType): Cadre barres parallèles; Rampe gauche (leftRailType_m): 2; Comme droite: no; Type câble (leftWireType): Rectangulaire; Nombre de barres (nBarsLeftRail): 4; Ombre: yes; Niveau de détail 2D (gs_detlevel_2D): Selon échelle; Niveau de détail 2D (gs_detlevel_2D_m): 1; Echelle simple/moyenne change à: 100; Echelle moyen/détail change à: 50; Type Symbole 2D (gs_SymbolType): Type 18; Stylo lignes struct. visibles: Escaliers - Contours; Stylo lignes struct. invisibles: Escaliers - Contours; Type ligne struct. visibles: 1; Type ligne struct. invisibles: 4; Afficher rampe en Plan: no; Type de ligne de rampe: 1; Stylo de rampe: Eléments 2D - Contours; Afficher axe rampe: no; Type de ligne d'axe: 6; Stylo ligne d'axe de rampe: Escaliers - Symboles et séparateurs; 2D symbolique: no; Type de ligne symbole (postSymbolType): Type 1; Type de ligne symbole (iPostSymbolType): 1; Type de ligne de poteau: 1; Stylo ligne de poteau: Objets - Hachures coupées; Afficher rampe au-dessus ligne de rupture: no; Afficher limon en Plan: no; Afficher limon (stShowCarriageUpTo): Jusqu'à 1:50; Afficher limon (iShowCarriageUpTo): 50; Ligne de limon: 4; Stylo limon: Poteaux - Hachures coupées; Motif de hachure de fond: Background Fill-International; Stylo hachure: Fond - Couleur 1; Stylo fond de hachure: Fond - Couleur 1; Hachure au-dessus rupture: no; Style ligne de rupture (breakline_style): Carré; Activer ligne rupture zigzag simple: no; Type ligne au dessus coupe (lineTypeAboveBreak): Coupé; Afficher ligne de foulée: yes; Aff. ligne foulée au-dessus rupt.: yes; Type ligne visible: 1; Type de ligne (gs_wLineType2): 6; Type ligne invisible: 6; Stylo Ligne (gs_wLinePen): Escaliers - Symboles et séparateurs; Style de marque (arrow_style): Style 3; Motif de hachure de marque: Foreground Fill-International; Stylo hachure (0-sans hach.) (gs_ArrowFillPen): Escaliers - Contours; Stylo hach. au-dessus (0-sans): Transparent; Symbole au début (gs_StartEndStyle): Style 1; Symbole au début (gs_StartEndStyle_m): 1; Motif de hachure symbole: Foreground Fill-International; Stylo hachure (0-sans hach.) (gs_StartEndFillPen): Transparent; Afficher numérotation (bShowNumbering): yes; Débuter numérotation de: 1; Taille police (mm) (gs_NumTextSize): 1; Taille police (point) (gs_text_size_pt_num): 2.83465; Stylo texte (gs_NumTextPen): Texte d'annotation - remarques; Orientation texte sur symbole (typeTextRotation_Num): Aligner avec symbole; Orientation texte sur symbole (typeTextRotation_Num_m): 0; Texte contremarche et volée (bShowRiseAndRunText): no; Texte (gs_RiseRunText): Nombre contremarches = Hauteur volée; Texte (iRiseRunText): 1; Texte personnalisé_1: Custom Text_1; Texte personnalisé_2: Custom Text_2; Texte contremarche: STG; Taille police (mm) (fontsize): 1; Taille police (point) (gs_text_size_pt): 2.83465; Stylo police: Texte d'annotation - remarques; Utiliser unités Préférences projet: yes; Angle rotation texte pente: 0 deg; Orientation texte sur symbole (typeTextRotation_RiseRun): Lisible; Orientation texte sur symbole (typeTextRotation_RiseRun_m): 2; Texte ASC/DESC (walkingDirUPDN): Sans; Texte ASC/DESC (walkingDirUPDN_m): 1; Texte DESC: DOWN; Taille texte ASC/DESC (mm): 2; Taille texte ASC/DESC (pt): 5.66929; Stylo texte ASC/DESC: Texte d'annotation - remarques; Angle texte ASC/DESC (AngUPDN): 0 deg; Angle texte ASC/DESC (AngUPDN_top): 0 deg; Orientation texte sur symbole (typeTextRotation_UpDn): Aligner avec symbole; Orientation texte sur symbole (typeTextRotation_UpDn_m): 0; Taille police (mm) (gs_desc_text_size): 1; Taille police (point) (gs_desc_text_size_pt): 2.83465; Stylo texte (gs_desc_text_pen): Ouvertures - Coupé structurel; Police: Arial; Dépendance étage: yes; Ligne de coupe: yes; Partie inférieure: no; Partie supérieure: yes; Afficher girons: yes; Type de ligne (gs_LineTypeStUp): 1; Stylo Ligne (gs_LinePenStUp): Escaliers - Symboles et séparateurs; Type de ligne de foulée: 1; Afficher numérotation (gs_numaStUp): yes; Texte contremarche et volée (gs_txStUp): no; Stylo contour coupé structure (penLineStringer): Général - Dessin; Stylo contour coupé structure (penLineStringer_m): 1; Hachure coupée structure: 03 | Concrete Structural; Stylo hachure coupée structure (penFillStringer): Eléments 2D - Général; Stylo hachure coupée structure (penFillStringer_m): 2; Stylo fond hachure coupée structure (penBackFillStringer): Transparent; Stylo fond hachure coupée structure (penBackFillStringer_m): 0; Stylo contour coupé giron (penLineTread): Général - Dessin; Stylo contour coupé giron (penLineTread_m): 1; Hachure giron coupé: 03 | Concrete Structural; Stylo hachure giron coupé (penFillTread): Zone - Général; Stylo hachure giron coupé (penFillTread_m): 14; Stylo fond hachure giron coupé (penBackFillTread): Zone - Coupé structurel; Stylo fond hachure giron coupé (penBackFillTread_m): 114; Stylo contour coupé contremarche (penLineRiser): Général - Dessin; Stylo contour coupé contremarche (penLineRiser_m): 1; Hachure coupée contremarche: 03 | Concrete Structural; Stylo hachure coupée contremarche (penFillRiser): Eléments 2D - Général; Stylo hachure coupée contremarche (penFillRiser_m): 2; Stylo fond hachure coupée contremarche (penBackFillRiser): Transparent; Stylo fond hachure coupée contremarche (penBackFillRiser_m): 0; Base d'escalier: 03 | Concrete Dark; Marche: 06 | W Pine V; Contremarche: 06 | W Pine V; Poteau: 09 | Paint-04 Grey; Main courante: 09 | Paint-04 Grey; Eléments de remplissage: 06 | W Pine V; Barre: 09 | Paint-04 Grey; Afficher points chauds 2D en 3D: no; Représentation 3D (gs_detlevel_3D_m): 2; Type Symbole 2D (gs_SymbolType_m): 18; Type ligne au dessus coupe (lineTypeAboveBreak_m): 1; Style de marque (arrow_style_m): 3; Style ligne de rupture (breakline_style_m): 1; Coût: 0; Type de groupe (FM_Type): Stairs; Type de groupe (iFMType): 999; Poids de l'objet: 0; Unité poids de l'objet: kg; Nombre d'étages: 0; Nombre de demi-paliers: 0; Hauteur des niveaux: 0; Echappée: 0; Capacité de support: 0; Escalier sans fumée: no; Longueur des marches: 0; Type escalier: 6
AC_Pset_RenovationAndPhasing - Renovation Status: Existing
Pset_StairCommon - IsExternal: no
AC_Equantity_Escalier_en_U_18 - Epaisseur marche (0-Non): 0.03 m; Epaiss. revêtement contremarche: 0.02 m; Epaisseur paillasse / limon: 0.2 m; Décalage base bois: 0.15 m; Epaisseur palier supérieur: 0.15 m; Epaisseur palier inférieur: 0.2 m; Hauteur rampe (rightRailHeight): 0.8 m; Distance à l'escalier: 0.1 m; Décalage rampe droite: 0 m; Dépassement rampe inférieur (rightRailOvhgBottom): 0 m; Dépassement rampe supérieur (rightRailOvhgTop): 0 m; Taille poteau (rightRailPostSize): 0.06 m; Epaisseur cadre: 0.04 m; Epaisseur barres (rightRailBarThk): 0.05 m; Profondeur barres (rightRailBarDepth): 0.02 m; Diamètre câble (rightRailWireDiam): 0.005 m; Epaisseur câble (rightRailWireThk): 0.005 m; Profondeur câble (rightRailWireDepth): 0.005 m; Hauteur rampe (leftRailHeight): 0.8 m; Distance de Dalle/Escalier: 0.1 m; Décalage rampe gauche: 0 m; Dépassement rampe inférieur (leftRailOvhgBottom): 0 m; Dépassement rampe supérieur (leftRailOvhgTop): 0 m; Taille poteau (leftRailPostSize): 0.06 m; Epaisseur cadre/barre: 0.04 m; Epaisseur barres (leftRailBarThk): 0.05 m; Profondeur barres (leftRailBarDepth): 0.02 m; Diamètre câble (leftRailWireDiam): 0.005 m; Epaisseur câble (leftRailWireThk): 0.005 m; Profondeur câble (leftRailWireDepth): 0.005 m; Position ligne rupture (Haut.): 1 m; Hauteur marque: 0.25 m; Moitié largeur marque: 0.2 m; Rayon du cercle: 0.1 m; Moitié largeur symbole: 0.05 m; Moitié hauteur symbole: 0.15 m; Position numérotation X: 0.1 m; Position numérotation Y: 0 m; Position en X de texte pente: 0 m; Position en Y de texte pente: 0.8 m; Déplacement horiz. texte (DirUPDN_X): 0 m; Déplécement vert. texte (DirUPDN_Y): -0.25 m; Déplacement horiz. texte (DirUPDN_X_top): 0 m; Déplécement vert. texte (DirUPDN_Y_top): -0.25 m; Niveau inférieur: 1 m; Niveau supérieur: 0 m
Name | In | Description = ID | Etage d'implantation | Classification d'lément | Angle de rotation (deg) | Type de paramètre | Nb. de contremarches = Nombre de contremarches = Nombre de girons (ifc_NumberOfTreads) | Nb. marches 1ère Volée | Nb. marches 2ème Volée | Définition dimension | Altitude à Zéro du Projet (m) | Altitude à étage (m) | Superficie de surface (m2) | Volume net (m3) = Volume (m3) | Superficie (m2) | Hauteur (Taille en Z) (m) = Hauteur totale (m) | Longueur (A) (m) = Largeur totale (m) | Largeur (B) (m) = Profondeur totale (m) | Largeur de volée (m) | Décalage volées (m) | Haut. marche souhaitée (m) = Hauteur réelle de marche (m) = Hauteur contremarche (m) | Giron (m) = Longueur giron (m) | 2*contremarche + giron (m) | Dépassement du verre (m) | Largeur ligne de rupture (m)
Stair_02 | Rez de chaussée | Stair_02 | Rez de chaussée | Type ArchiCAD | 277.168 | Nb. de marche par volée | 13 | 9 | 4 | 2 | 3 | 3 | 45.176 | 2.12184 | 9.36 | 2.33333 | 3.6 | 2.6 | 1.2 | 0.2 | 0.166667 | 0.266667 | 0.6 | 0.02 | 0.2 | ArchiCADProperties - Nom de Zone: Cage Escalier; Numéro de Zone: 001
Stair_02 | Rez de chaussée | Stair_02 | Rez de chaussée | Type ArchiCAD | 277.168 | Hauteur marche | 18 | 9 | 9 | 1 | 0 | 0 | 55.9751 | 2.63743 | 9.36 | 3 | 3.6 | 2.6 | 1.2 | 0.2 | 0.166667 | 0.266667 | 0.6 | 0.02 | 0.2 | ArchiCADProperties - Nom de Zone: Cage Escalier; Numéro de Zone: 001
Stair_01 | Rez de chaussée | Stair_01 | Rez de chaussée | Escalier | 270 | Hauteur marche | 24 | 12 | 12 | 1 | 0 | 0 | 65.6927 | 3.15987 | 9.66029 | 5.4 | 3.98362 | 2.425 | 1.1 | 0.225 | 0.225 | 0.240302 | 0.690302 | 0.0025 | 0.025 | ArchiCADProperties - Nom de Zone: Cage Escalier; Numéro de Zone: 001
Stair_01 | Rez de chaussée | Stair_01 | Rez de chaussée | Escalier | 277.6 | Hauteur marche | 24 | 12 | 12 | 1 | 0 | 0 | 76.4007 | 3.69697 | 11.0332 | 5.4 | 4.00287 | 2.75633 | 1.29733 | 0.161681 | 0.225 | 0.225462 | 0.675462 | 0.0025 | 0.025 | ArchiCADProperties - Nom de Zone: Cage Escalier; Numéro de Zone: 001
Stair_02 | R+1 | Stair_02 | R+1 | Type ArchiCAD | 277.667 | Nb. de marche par volée | 24 | 12 | 12 | 2 | 5.4 | 0 | 65.3565 | 3.08282 | 10.608 | 4.025 | 4.08 | 2.6 | 1.2 | 0.2 | 0.161 | 0.24 | 0.562 | 0.0025 | 0.025
Stair_01 | R+1 | Stair_01 | R+1 | Escalier | 270 | Hauteur marche | 24 | 12 | 12 | 1 | 5.4 | 0 | 59.3984 | 2.7775 | 9.54078 | 4.03 | 3.98362 | 2.395 | 1.1 | 0.195 | 0.167917 | 0.240302 | 0.576135 | 0.0025 | 0.025
Stair_01 | R+1 | Stair_01 | R+1 | Escalier | 278.169 | Hauteur marche | 24 | 12 | 12 | 1 | 5.4 | 0 | 69.2372 | 3.26073 | 11.0332 | 4.03 | 4.00287 | 2.75633 | 1.29733 | 0.161681 | 0.167917 | 0.225462 | 0.561295 | 0.0025 | 0.025
Stair_01 | Mezzannine | Stair_01 | Mezzannine | Escalier | 270 | Hauteur marche | 24 | 12 | 12 | 1 | 9.425 | 0 | 59.5696 | 2.78671 | 9.67241 | 4.025 | 3.98862 | 2.425 | 1.1 | 0.225 | 0.167708 | 0.240719 | 0.576135 | 0.0025 | 0.025
Stair_02 | Mezzannine | Stair_02 | Mezzannine | Type ArchiCAD | 277.43 | Nb. de marche par volée | 24 | 12 | 12 | 2 | 13.375 | 3.95 | 65.3565 | 3.08282 | 10.608 | 4.025 | 4.08 | 2.6 | 1.2 | 0.2 | 0.161 | 0.24 | 0.562 | 0.0025 | 0.025
Stair_02 | Mezzannine | Stair_02 | Mezzannine | Type ArchiCAD | 277.43 | Nb. de marche par volée | 24 | 12 | 12 | 2 | 9.425 | 0 | 65.3565 | 3.08282 | 10.608 | 4.025 | 4.08 | 2.6 | 1.2 | 0.2 | 0.161 | 0.24 | 0.562 | 0.0025 | 0.025
Stair_01 | Mezzannine | Stair_01 | Mezzannine | Escalier | 277.94 | Hauteur marche | 24 | 12 | 12 | 1 | 9.425 | 0 | 69.2372 | 3.26073 | 11.0332 | 4.03 | 4.00287 | 2.75633 | 1.29733 | 0.161681 | 0.167917 | 0.225462 | 0.561295 | 0.0025 | 0.025
Stair_01 | R+2 | Stair_01 | R+2 | Escalier | 278.169 | Hauteur marche | 24 | 12 | 12 | 1 | 13.45 | 0 | 68.1119 | 3.19393 | 11.0332 | 3.81 | 4.00287 | 2.75633 | 1.29733 | 0.161681 | 0.15875 | 0.225462 | 0.542962 | 0.0025 | 0.025

# IfcTransportElement: Ascenseur 18 (3)
In: Rez de chaussée
OperationType: ELEVATOR; CapacityByWeight: 0 g; CapacityByNumber: 0; Material: 50 %
ArchiCADProperties - ID: Tárgy-009; Etage d'implantation: Rez de chaussée; Nom de Zone: Ascenseur; Numéro de Zone: 001; Calque: A-EQMT; Type: Objet; Verrouillé: no; Nom Elément de Bibliothèque: Ascenseur 18; Matériau de construction / Composite / Profil / Hachure: 50 %; Fonction structurelle: Elément non porteur; Position: Intérieur; Classification d'lément: Type ArchiCAD; Etat de rénovation: Existant; Afficher sur filtre de rénovation: Tous les filtres appropriés; Surface: Mtl-Stainless Steel
AC_Pset_Ascenseur_18 - Afficher points chauds 2D en 3D: no; 3D (gs_detlevel_3D): Détaillé; 3D (gs_detlevel_3D_m): 2; Forme (elevator_form): Rectangulaire; Forme (elevator_form_m): 1; Nombre de segments: 7; Type d'ascenseur (elevator_type): Mécanique; Type d'ascenseur (elevator_type_m): 1; Direction deuxième ouverture (dir_second_opening): Sans; Direction deuxième ouverture (dir_second_opening_m): 1; Position contrepoids (cweight_pos): Normal; Position contrepoids (cweight_pos_m): 1; Nbre étages sous implantation: 0; Etages niveau divisé: no; Nbre étages niveau divisé au-dessus implantation: 0; Nbre étages niveau divisé sous implantation: 0; Dépassement ascenseur: yes; Fosse: yes; Style porte cage ascenseur (elev_door_style): Coulissant; Style porte cage ascenseur (elev_door_style_m): 1; Style porte cabine ascenseur (door_style): Style 1; Style porte cabine ascenseur (door_style_m): 1; Cadre ouverture: yes; Tableau de bord: yes; Surface panneau de porte: 05 | Chrome Simple; Surface vitre de porte: 08 | Glass-Clear; Surface cadre d'ouverture: 05 | Chrome Simple; Surface tableau de bord: 05 | Stainless Reflective; Surface de bouton: 05 | Iron Coarse; Position cabine (Etage) (car_pos_story): 0. Rez de chaussée; Position cabine (Etage) (car_pos_story_m): 0; Surface extérieure de cabine: 06 | P Laminate; Surface latérale intérieure de cabine: 06 | P Laminate; Surface plancher de cabine: 05 | Zinc New; Surface plafond de cabine: 08 | Glass-Tinted Dk; Surface latérale avant de cabine: 08 | Glass-Clear; Surface latérale arrière de cabine: 06 | P Laminate; Surface meneau: 05 | Stainless Reflective; Afficher cage d'ascenseur: no; Surface latérale extérieure de cage d'ascenseur: 09 | Paint-02 Whitewash; Surface latérale intérieure de cage d'ascenseur: 09 | Paint-02 Whitewash; Surface d'arête de cage d'ascenseur: 09 | Paint-02 Whitewash; Afficher mur ascenseur: yes; Surface latérale extérieure de mur d'ascenseur: 09 | Paint-02 Whitewash; Surface latérale intérieure de mur d'ascenseur: 09 | Paint-02 Whitewash; Surface d'arête de mur d'ascenseur: 09 | Paint-02 Whitewash; Dalle supérieure: yes; Surface latérale extérieure de dalle supérieure: 09 | Paint-02 Whitewash; Surface latérale intérieure de dalle supérieure: 09 | Paint-02 Whitewash; Surface d'arête de dalle supérieure: 09 | Paint-02 Whitewash; Dalle de la fosse: yes; Surface latérale extérieure de dalle d'ascenseur: 09 | Paint-02 Whitewash; Surface latérale intérieure de dalle d'ascenseur: 09 | Paint-02 Whitewash; Surface d'arête de dalle d'ascenseur: 09 | Paint-02 Whitewash; Ouverture porte en 3D (%): 30; Ombre: yes; Résolution: 6; Afficher meneaux: yes; Niveau de détail 2D (gs_detlevel_2D): Selon échelle; Niveau de détail 2D (gs_detlevel_2D_m): 1; Afficher mécanismes en 2D: yes; Stylo contour cabine: Technique - Général; Motif de hachure cabine: Background Fill-International; Stylo hachure cabine: Fond - Couleur 1; Stylo fond de hachure cabine: Fond - Couleur 1; Stylo contour mur: Murs - Coupé structurel; Motif de hachure de mur: Background Fill-International; Stylo de hachure de mur: Murs - Hachures coupées; Stylo de fond hachure de mur: Fond - Couleur 1; Motif de hachure de cadre d'ouverture: Background Fill-International; Stylo de hachure de cadre d'ouverture: Murs - Hachures coupées; Stylo de fond de cadre d'ouverture: Fond - Couleur 1; Motif de hachure espace: Background Fill-International; Stylo hachure espace: Fond - Couleur 1; Stylo fond hachure espace: Fond - Couleur 1; Coût: 0; Type de groupe (FM_Type): Elevators; Type de groupe (iFMType): 999; Poids de l'objet: 0; Unité poids de l'objet: kg; Capacité ascenseur (FM_LiftCapacity): 0; Capacité ascenseur (FM_LiftCapacityNumber): 0; Capacité par personne (FM_TransportablePersons): 0; Capacité par largeur: 0; Capacité par personne (ifc_CapacityByNumber): 0; Opération IFC: 1; Poids objet ONORM: 0
AC_Pset_RenovationAndPhasing - Renovation Status: Existing
ArchiCADQuantities - Altitude à Zéro du Projet: 0 m; Altitude à étage: 0 m
AC_Equantity_Ascenseur_18 - Niveau inférieur: -1.3 m; Largeur contrepoids: 0.9 m; Hauteur maximum de sol structurel: 1.8 m; Distance étage niveau divisé-étage normal: 1.55 m; Hauteur de dépassement: 1 m; Profondeur de fosse: 1 m; Axe porte à partir centre: 0 m; Axe 2e porte à partir centre: 0 m; Hauteur de la voiture: 2.4 m; Epaisseur cage d'ascenseur: 0.15 m; Epaisseur mur d'ascenseur: 0.15 m; Dépassement de mur: 0.12 m; Epaisseur de dalle supérieure: 0.3 m; Epaisseur de dalle d'ascenseur: 0.3 m
Name | Angle de rotation (deg) | Nbre étages au-dessus implantation | Nom d'étage à éditer (edited_story) | Nom d'étage à éditer (edited_story_m) | Position porte étage édité (edited_story_door_pos) | Position porte étage édité (edited_story_door_pos_m) | Superficie de surface (m2) | Volume net (m3) = Volume (m3) | Superficie (m2) | Hauteur (Taille en Z) (m) = Hauteur (m) | Longueur (A) (m) = Largeur cage d'ascenseur (m) = Largeur intérieure de cage d'ascenseur (m) | Largeur (B) (m) = Profondeur cage d'ascenseur (m) = Profondeur intérieure de cage d'ascenseur (m) | Niveau supérieur (m) | Profondeur contrepoids (m) | Largeur ouverture (m) | Hauteur ouverture (m) | Hauteur étage édité (m) | Altitude étage édité (m) | Largeur cabine (m) | Profondeur cabine (m) | Largeur intérieure de cabine (m) | Profondeur intérieure de cabine (m)
2 x Tárgy-009 | 270 | 4 | 4. Toiture | 4 | Sans | 4 | 58.657 | 1.82658 | 5.3625 | 21.95 | 2.5 | 2.145 | 20.65 | 0.038 | 0.9 | 2.1 | 1.95 | 17.4 | 2.26 | 1.74 | 2.1 | 1.76
Tárgy-009 | 7.59999 | 3 | 0. Rez de chaussée | 0 | Face | 1 | 110.73 | 3.27656 | 12.71 | 20 | 4.1 | 3.1 | 18.7 | 0.1 | 1.8 | 2.3 | 5.4 | 0 | 3.86 | 2.84 | 3.7 | 2.68

# IfcWall: 1etage 287 x 5000, ExtWall_01
In: R+1
Description: Level_1
ArchiCADProperties - ID: ExtWall_01; Etage d'implantation: R+1; Calque: A-WALL-EXTR; Type: Mur; Verrouillé: no; Matériau de construction / Composite / Profil / Hachure: 1etage; Fonction structurelle: Elément porteur; Position: Extérieur; Classification d'lément: Type ArchiCAD; Etat de rénovation: Existant; Afficher sur filtre de rénovation: Tous les filtres appropriés; Type de structure: Profil complexe; Matériau de construction / Composite / Profil: 1etage; Surface latérale: 09 | Paint-02 Whitewash; Angle d'inclinaison externe: 90 deg; Angle d'inclinaison interne: 90 deg; Type d'inclinaison de mur: Droit; Etage supérieur lié: Non lié; Option de géométrie: Uniforme
AC_Pset_RenovationAndPhasing - Renovation Status: Existing
Pset_WallCommon - LoadBearing: yes; IsExternal: yes
BaseQuantities - Length: 10.7965 m; Height: 5 m; Width: 0.287 m; GrossFootprintArea: 3.0986 m2; NetFootprintArea: 3.0986 m2; GrossSideArea: 51.4385 m2; NetSideArea: 46.9387 m2; GrossVolume: 14.6857 m3; NetVolume: 13.4233 m3
ArchiCADQuantities - Altitude à Zéro du Projet: 4.4 m; Altitude à étage: -1 m; Hauteur: 5 m; Superficie de surface: 48.5656 m2; Volume net: 13.4233 m3; Superficie: 3.0986 m2; Epaisseur: 0.287 m; Longueur de mur sur face extérieure: 10.6131 m; Longueur de mur sur face intérieure: 10.9799 m; Surface de mur nette sur face extérieure: 48.5656 m2; Surface de mur nette sur face intérieure: 45.3119 m2; Surface nette des arêtes: 6.95998 m2; Volume conditionnel: 13.4233 m3; Nombre de Portes: 0; Nombre de Fenêtres: 2; Nombre de trous (Nombre d'ouvertures vides): 0; Nombre de Poteaux: 0; Largeur totale des Portes: 0 m; Largeur totale des Fenêtres: 1.8 m; Epaisseur du Mur à la fin: 0.287 m; Hauteur minimum du Mur: 0 m; Hauteur maximum du Mur: 5 m; Longueur du Mur au centre: 10.7965 m; Surface du Mur: 3.0986 m2; Périmètre du Mur: 22.3457 m; Surface brute de mur sur face intérieure: 54.8998 m2; Surface brute de mur sur face extérieure: 54.9157 m2; Volume brut du Mur: 15.4141 m3; Surface analytique des ouvertures sur face intérieure: 4.49945 m2; Surface analytique des ouvertures sur face extérieure: 4.5 m2; Volume analytique des ouvertures dans le Mur: 1.26239 m3; Epaisseur de couche de mur sur face extérieure: 0 m; Epaisseur de couche de mur sur face intérieure: 0 m; Epaisseur couche isolation: 0 m; Epaisseur couche d'air: 0 m; Hauteur de couche de mur minimum sur face extérieure: 0 m; Hauteur de couche de mur maximum sur face extérieure: 0 m; Hauteur de couche de mur minimum sur face intérieure: 0 m; Hauteur de couche de mur maximum sur face intérieure: 0 m; Longueur conditionnelle sur face extérieure: 10.6131 m; Longueur conditionnelle sur face intérieure: 10.9799 m; Surface conditionnelle sur face extérieure: 48.5656 m2; Surface conditionnelle sur face intérieure: 45.3119 m2; Volume de couche de mur sur face extérieure: 0 m3; Volume de couche de mur sur face intérieure: 0 m3; Volume de couche de mur conditionnelle sur face extérieure: 0 m3; Volume de couche de mur conditionnelle sur face intérieure: 0 m3; Longueur de ligne de référence: 10.6131 m; Décalage étage d'implantation: -1 m; Décalage supérieur: 0 m; Longueur moyenne: 10.7965 m; Surface des fenêtres dans le mur: 4.5225 m2; Surface des portes dans le mur: 0 m2; Surface des baies libres dans le mur: 0 m2; Volume de poteaux: 0 m3

# IfcWall: Panneau 2eme 287 x 4070, SW - 012
In: R+2
Description: WallEx01
ArchiCADProperties - ID: SW - 012; Etage d'implantation: R+2; Calque: A-WALL-EXTR; Type: Mur; Verrouillé: no; Matériau de construction / Composite / Profil / Hachure: Panneau 2eme; Fonction structurelle: Elément porteur; Position: Non défini; Classification d'lément: Type ArchiCAD; Etat de rénovation: Existant; Afficher sur filtre de rénovation: Tous les filtres appropriés; Type de structure: Profil complexe; Matériau de construction / Composite / Profil: Panneau 2eme; Surface de face extérieure: 09 | Paint-02 Whitewash; Surface latérale: 09 | Paint-02 Whitewash; Angle d'inclinaison externe: 90 deg; Angle d'inclinaison interne: 90 deg; Type d'inclinaison de mur: Droit; Etage supérieur lié: Non lié; Option de géométrie: Uniforme
AC_Pset_RenovationAndPhasing - Renovation Status: Existing
Pset_WallCommon - LoadBearing: yes
BaseQuantities - Length: 10.7965 m; Height: 4.07 m; Width: 0.287 m; GrossFootprintArea: 3.0986 m2; NetFootprintArea: 3.0986 m2; GrossSideArea: 43.1908 m2; NetSideArea: 39.6358 m2; GrossVolume: 12.1753 m3; NetVolume: 11.1551 m3
ArchiCADQuantities - Altitude à Zéro du Projet: 13.45 m; Altitude à étage: 0 m; Hauteur: 4.07 m; Superficie de surface: 39.5885 m2; Volume net: 11.1551 m3; Superficie: 3.0986 m2; Epaisseur: 0.287 m; Longueur de mur sur face extérieure: 10.6131 m; Longueur de mur sur face intérieure: 10.9799 m; Surface de mur nette sur face extérieure: 39.5885 m2; Surface de mur nette sur face intérieure: 39.6831 m2; Surface nette des arêtes: 6.08495 m2; Volume conditionnel: 11.1551 m3; Nombre de Portes: 0; Nombre de Fenêtres: 2; Nombre de trous (Nombre d'ouvertures vides): 0; Nombre de Poteaux: 0; Largeur totale des Portes: 0 m; Largeur totale des Fenêtres: 1.8 m; Epaisseur du Mur à la fin: 0.287 m; Hauteur minimum du Mur: 9.00245e-10 m; Hauteur maximum du Mur: 4.07 m; Longueur du Mur au centre: 10.7965 m; Surface du Mur: 3.0986 m2; Périmètre du Mur: 22.3457 m; Surface brute de mur sur face intérieure: 44.5268 m2; Surface brute de mur sur face extérieure: 44.5384 m2; Volume brut du Mur: 12.5591 m3; Surface analytique des ouvertures sur face intérieure: 3.555 m2; Surface analytique des ouvertures sur face extérieure: 3.555 m2; Volume analytique des ouvertures dans le Mur: 1.02017 m3; Epaisseur de couche de mur sur face extérieure: 0 m; Epaisseur de couche de mur sur face intérieure: 0 m; Epaisseur couche isolation: 0 m; Epaisseur couche d'air: 0 m; Hauteur de couche de mur minimum sur face extérieure: 0 m; Hauteur de couche de mur maximum sur face extérieure: 0 m; Hauteur de couche de mur minimum sur face intérieure: 0 m; Hauteur de couche de mur maximum sur face intérieure: 0 m; Longueur conditionnelle sur face extérieure: 10.6131 m; Longueur conditionnelle sur face intérieure: 10.9799 m; Surface conditionnelle sur face extérieure: 39.5885 m2; Surface conditionnelle sur face intérieure: 39.6831 m2; Volume de couche de mur sur face extérieure: 0 m3; Volume de couche de mur sur face intérieure: 0 m3; Volume de couche de mur conditionnelle sur face extérieure: 0 m3; Volume de couche de mur conditionnelle sur face intérieure: 0 m3; Longueur de ligne de référence: 10.6131 m; Décalage étage d'implantation: 0 m; Décalage supérieur: 0 m; Longueur moyenne: 10.7965 m; Surface des fenêtres dans le mur: 3.555 m2; Surface des portes dans le mur: 0 m2; Surface des baies libres dans le mur: 0 m2; Volume de poteaux: 0 m3

# IfcWall: Panneau béton iso mezz 370 x 4120, SW - 010
In: Mezzannine
Description: WallEx01
ArchiCADProperties - ID: SW - 010; Etage d'implantation: Mezzannine; Nom de Zone: Plateau bureaux; Numéro de Zone: 005; Calque: A-WALL-EXTR; Type: Mur; Verrouillé: no; Matériau de construction / Composite / Profil / Hachure: Panneau béton iso mezz; Fonction structurelle: Elément porteur; Position: Extérieur; Classification d'lément: Type ArchiCAD; Etat de rénovation: Existant; Afficher sur filtre de rénovation: Tous les filtres appropriés; Type de structure: Profil complexe; Matériau de construction / Composite / Profil: Panneau béton iso mezz; Surface latérale: 09 | Paint-02 Whitewash; Angle d'inclinaison externe: 90 deg; Angle d'inclinaison interne: 90 deg; Type d'inclinaison de mur: Droit; Etage supérieur lié: Non lié; Option de géométrie: Uniforme
AC_Pset_RenovationAndPhasing - Renovation Status: Existing
Pset_WallCommon - LoadBearing: yes; IsExternal: yes
BaseQuantities - Length: 51.9698 m; Height: 4.12 m; Width: 0.37 m; GrossFootprintArea: 19.2288 m2; NetFootprintArea: 19.2288 m2; GrossSideArea: 206.939 m2; NetSideArea: 112.342 m2; GrossVolume: 75.2501 m3; NetVolume: 40.2439 m3
ArchiCADQuantities - Altitude à Zéro du Projet: 9.425 m; Altitude à étage: 0 m; Hauteur: 4.12 m; Superficie de surface: 119.503 m2; Volume net: 40.2439 m3; Superficie: 19.2288 m2; Epaisseur: 0.37 m; Longueur de mur sur face extérieure: 51.9698 m; Longueur de mur sur face intérieure: 51.9698 m; Surface de mur nette sur face extérieure: 119.503 m2; Surface de mur nette sur face intérieure: 105.18 m2; Surface nette des arêtes: 23.1939 m2; Volume conditionnel: 40.2439 m3; Nombre de Portes: 0; Nombre de Fenêtres: 0; Nombre de trous (Nombre d'ouvertures vides): 1; Nombre de Poteaux: 0; Largeur totale des Portes: 0 m; Largeur totale des Fenêtres: 0 m; Epaisseur du Mur à la fin: 0.37 m; Hauteur minimum du Mur: 2.345 m; Hauteur maximum du Mur: 4.12 m; Longueur du Mur au centre: 51.9698 m; Surface du Mur: 19.2288 m2; Périmètre du Mur: 104.68 m; Surface brute de mur sur face intérieure: 214.116 m2; Surface brute de mur sur face extérieure: 214.116 m2; Volume brut du Mur: 78.0379 m3; Surface analytique des ouvertures sur face intérieure: 94.5812 m2; Surface analytique des ouvertures sur face extérieure: 94.6126 m2; Volume analytique des ouvertures dans le Mur: 35.0062 m3; Epaisseur de couche de mur sur face extérieure: 0 m; Epaisseur de couche de mur sur face intérieure: 0 m; Epaisseur couche isolation: 0 m; Epaisseur couche d'air: 0 m; Hauteur de couche de mur minimum sur face extérieure: 0 m; Hauteur de couche de mur maximum sur face extérieure: 0 m; Hauteur de couche de mur minimum sur face intérieure: 0 m; Hauteur de couche de mur maximum sur face intérieure: 0 m; Longueur conditionnelle sur face extérieure: 51.9698 m; Longueur conditionnelle sur face intérieure: 51.9698 m; Surface conditionnelle sur face extérieure: 119.503 m2; Surface conditionnelle sur face intérieure: 105.18 m2; Volume de couche de mur sur face extérieure: 0 m3; Volume de couche de mur sur face intérieure: 0 m3; Volume de couche de mur conditionnelle sur face extérieure: 0 m3; Volume de couche de mur conditionnelle sur face intérieure: 0 m3; Longueur de ligne de référence: 51.9698 m; Décalage étage d'implantation: 0 m; Décalage supérieur: 0 m; Longueur moyenne: 51.9698 m; Surface des fenêtres dans le mur: 0 m2; Surface des portes dans le mur: 0 m2; Surface des baies libres dans le mur: 94.6126 m2; Volume de poteaux: 0 m3

# IfcWall: Profil personnalisé 287 x 4150, SW - 012
In: Mezzannine
Description: WallEx01
ArchiCADProperties - ID: SW - 012; Etage d'implantation: Mezzannine; Calque: A-WALL-EXTR; Type: Mur; Verrouillé: no; Matériau de construction / Composite / Profil / Hachure: Profil personnalisé; Fonction structurelle: Elément porteur; Position: Non défini; Classification d'lément: Type ArchiCAD; Etat de rénovation: Existant; Afficher sur filtre de rénovation: Tous les filtres appropriés; Type de structure: Profil complexe; Matériau de construction / Composite / Profil: Profil personnalisé; Surface latérale: 09 | Paint-02 Whitewash; Angle d'inclinaison externe: 90 deg; Angle d'inclinaison interne: 90 deg; Type d'inclinaison de mur: Droit; Etage supérieur lié: Non lié; Option de géométrie: Uniforme
AC_Pset_RenovationAndPhasing - Renovation Status: Existing
Pset_WallCommon - LoadBearing: yes
BaseQuantities - Length: 10.7965 m; Height: 4.15 m; Width: 0.287 m; GrossFootprintArea: 3.0986 m2; NetFootprintArea: 3.0986 m2; GrossSideArea: 44.0673 m2; NetSideArea: 40.4676 m2; GrossVolume: 12.0069 m3; NetVolume: 11.0026 m3
ArchiCADQuantities - Altitude à Zéro du Projet: 9.425 m; Altitude à étage: 0 m; Hauteur: 4.15 m; Superficie de surface: 40.4457 m2; Volume net: 11.0026 m3; Superficie: 3.0986 m2; Epaisseur: 0.287 m; Longueur de mur sur face extérieure: 10.6131 m; Longueur de mur sur face intérieure: 10.9799 m; Surface de mur nette sur face extérieure: 40.4457 m2; Surface de mur nette sur face intérieure: 40.4895 m2; Surface nette des arêtes: 6.88883 m2; Volume conditionnel: 11.0026 m3; Nombre de Portes: 0; Nombre de Fenêtres: 2; Nombre de trous (Nombre d'ouvertures vides): 0; Nombre de Poteaux: 0; Largeur totale des Portes: 0 m; Largeur totale des Fenêtres: 1.8 m; Epaisseur du Mur à la fin: 0.287 m; Hauteur minimum du Mur: 0 m; Hauteur maximum du Mur: 4.15 m; Longueur du Mur au centre: 10.7965 m; Surface du Mur: 3.0986 m2; Périmètre du Mur: 22.3457 m; Surface brute de mur sur face intérieure: 45.567 m2; Surface brute de mur sur face extérieure: 45.5798 m2; Volume brut du Mur: 12.4189 m3; Surface analytique des ouvertures sur face intérieure: 3.59945 m2; Surface analytique des ouvertures sur face extérieure: 3.6 m2; Volume analytique des ouvertures dans le Mur: 1.00428 m3; Epaisseur de couche de mur sur face extérieure: 0 m; Epaisseur de couche de mur sur face intérieure: 0 m; Epaisseur couche isolation: 0 m; Epaisseur couche d'air: 0 m; Hauteur de couche de mur minimum sur face extérieure: 0 m; Hauteur de couche de mur maximum sur face extérieure: 0 m; Hauteur de couche de mur minimum sur face intérieure: 0 m; Hauteur de couche de mur maximum sur face intérieure: 0 m; Longueur conditionnelle sur face extérieure: 10.6131 m; Longueur conditionnelle sur face intérieure: 10.9799 m; Surface conditionnelle sur face extérieure: 40.4457 m2; Surface conditionnelle sur face intérieure: 40.4895 m2; Volume de couche de mur sur face extérieure: 0 m3; Volume de couche de mur sur face intérieure: 0 m3; Volume de couche de mur conditionnelle sur face extérieure: 0 m3; Volume de couche de mur conditionnelle sur face intérieure: 0 m3; Longueur de ligne de référence: 10.6131 m; Décalage étage d'implantation: 0 m; Décalage supérieur: 0 m; Longueur moyenne: 10.7965 m; Surface des fenêtres dans le mur: 3.6 m2; Surface des portes dans le mur: 0 m2; Surface des baies libres dans le mur: 0 m2; Volume de poteaux: 0 m3

# IfcWall: Profil personnalisé 370 x 3630, SW - 014
In: R+2
Description: WallEx01
ArchiCADProperties - ID: SW - 014; Etage d'implantation: R+2; Nom de Zone: Dégagement; Numéro de Zone: 001; Calque: A-WALL-EXTR; Type: Mur; Verrouillé: no; Matériau de construction / Composite / Profil / Hachure: Profil personnalisé; Fonction structurelle: Elément porteur; Position: Extérieur; Classification d'lément: Type ArchiCAD; Etat de rénovation: Existant; Afficher sur filtre de rénovation: Tous les filtres appropriés; Type de structure: Profil complexe; Matériau de construction / Composite / Profil: Profil personnalisé; Surface latérale: 09 | Paint-02 Whitewash; Angle d'inclinaison externe: 90 deg; Angle d'inclinaison interne: 90 deg; Type d'inclinaison de mur: Droit; Etage supérieur lié: Non lié; Option de géométrie: Uniforme
AC_Pset_RenovationAndPhasing - Renovation Status: Existing
Pset_WallCommon - LoadBearing: yes; IsExternal: yes
BaseQuantities - Length: 7.4054 m; Height: 3.63 m; Width: 0.37 m; GrossFootprintArea: 2.74 m2; NetFootprintArea: 2.74 m2; GrossSideArea: 26.3421 m2; NetSideArea: 26.3421 m2; GrossVolume: 9.55143 m3; NetVolume: 9.55143 m3
ArchiCADQuantities - Altitude à Zéro du Projet: 13.45 m; Altitude à étage: 0 m; Hauteur: 3.63 m; Superficie de surface: 28.0112 m2; Volume net: 9.55143 m3; Superficie: 2.74 m2; Epaisseur: 0.37 m; Longueur de mur sur face extérieure: 7.77322 m; Longueur de mur sur face intérieure: 7.03758 m; Surface de mur nette sur face extérieure: 28.0112 m2; Surface de mur nette sur face intérieure: 24.6731 m2; Surface nette des arêtes: 5.25938 m2; Volume conditionnel: 9.55143 m3; Nombre de Portes: 0; Nombre de Fenêtres: 0; Nombre de trous (Nombre d'ouvertures vides): 0; Nombre de Poteaux: 0; Largeur totale des Portes: 0 m; Largeur totale des Fenêtres: 0 m; Epaisseur du Mur à la fin: 0.37 m; Hauteur minimum du Mur: 0 m; Hauteur maximum du Mur: 3.63 m; Longueur du Mur au centre: 7.4054 m; Surface du Mur: 2.74 m2; Périmètre du Mur: 15.8542 m; Surface brute de mur sur face intérieure: 28.2327 m2; Surface brute de mur sur face extérieure: 28.217 m2; Volume brut du Mur: 10.2659 m3; Surface analytique des ouvertures sur face intérieure: 0 m2; Surface analytique des ouvertures sur face extérieure: 0 m2; Volume analytique des ouvertures dans le Mur: 0 m3; Epaisseur de couche de mur sur face extérieure: 0 m; Epaisseur de couche de mur sur face intérieure: 0 m; Epaisseur couche isolation: 0 m; Epaisseur couche d'air: 0 m; Hauteur de couche de mur minimum sur face extérieure: 0 m; Hauteur de couche de mur maximum sur face extérieure: 0 m; Hauteur de couche de mur minimum sur face intérieure: 0 m; Hauteur de couche de mur maximum sur face intérieure: 0 m; Longueur conditionnelle sur face extérieure: 7.77322 m; Longueur conditionnelle sur face intérieure: 7.03758 m; Surface conditionnelle sur face extérieure: 28.0112 m2; Surface conditionnelle sur face intérieure: 24.6731 m2; Volume de couche de mur sur face extérieure: 0 m3; Volume de couche de mur sur face intérieure: 0 m3; Volume de couche de mur conditionnelle sur face extérieure: 0 m3; Volume de couche de mur conditionnelle sur face intérieure: 0 m3; Longueur de ligne de référence: 7.77322 m; Décalage étage d'implantation: 0 m; Décalage supérieur: 0 m; Longueur moyenne: 7.4054 m; Surface des fenêtres dans le mur: 0 m2; Surface des portes dans le mur: 0 m2; Surface des baies libres dans le mur: 0 m2; Volume de poteaux: 0 m3

# IfcWall: Profil personnalisé 370 x 4005 (2)
In: R+1
Description: Level_1
ArchiCADProperties - ID: WallEx02; Etage d'implantation: R+1; Calque: A-WALL-EXTR; Type: Mur; Verrouillé: no; Matériau de construction / Composite / Profil / Hachure: Profil personnalisé; Fonction structurelle: Elément porteur; Position: Extérieur; Classification d'lément: Type ArchiCAD; Etat de rénovation: Existant; Afficher sur filtre de rénovation: Tous les filtres appropriés; Type de structure: Profil complexe; Matériau de construction / Composite / Profil: Profil personnalisé; Surface latérale: 09 | Paint-02 Whitewash; Angle d'inclinaison externe: 90 deg; Angle d'inclinaison interne: 90 deg; Type d'inclinaison de mur: Droit; Etage supérieur lié: Non lié; Option de géométrie: Uniforme
AC_Pset_RenovationAndPhasing - Renovation Status: Existing
Pset_WallCommon - LoadBearing: yes; IsExternal: yes
BaseQuantities - Height: 4.005 m; Width: 0.37 m
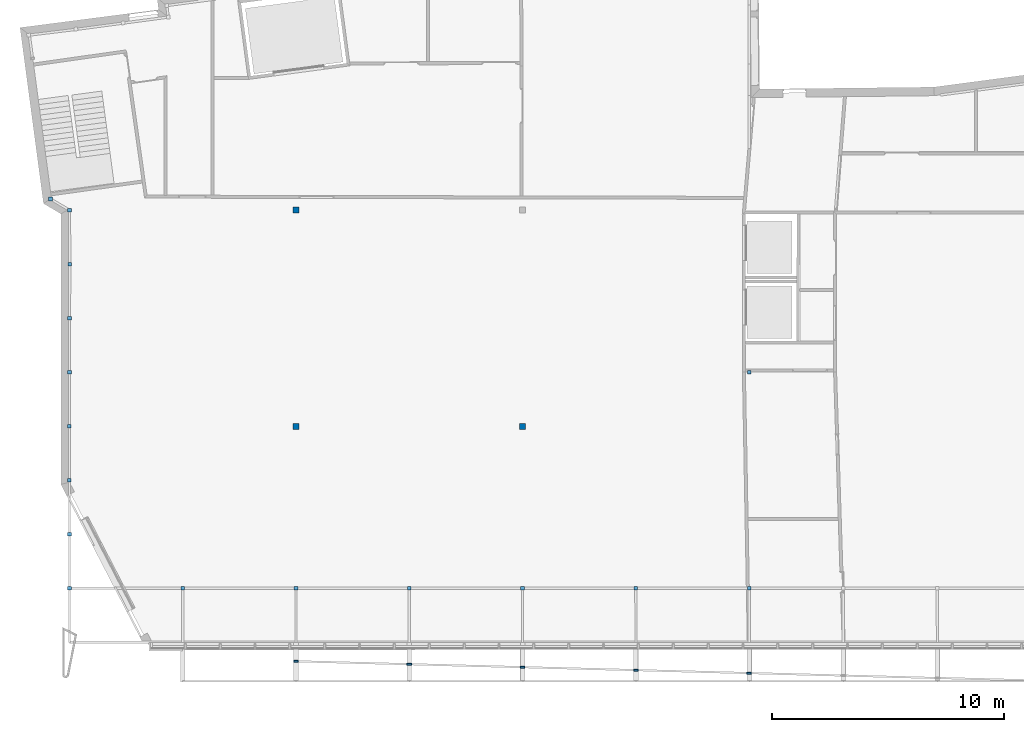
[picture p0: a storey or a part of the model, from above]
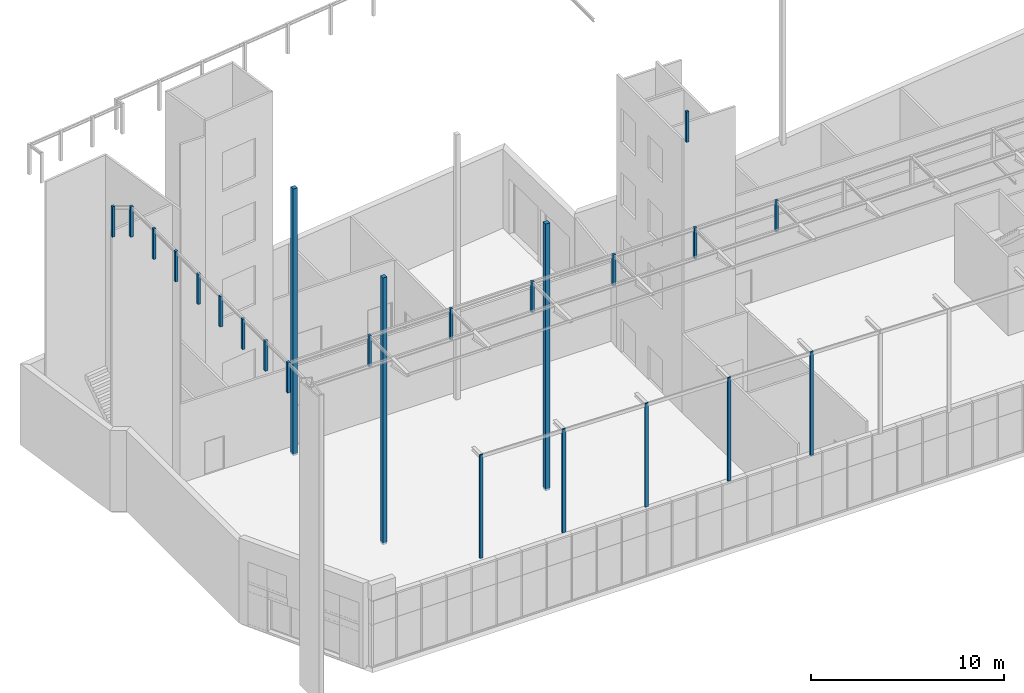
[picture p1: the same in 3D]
Properties of the parts of a building model (IFC2X3), part 14 of 19

# IfcWall: Profil personnalisé 370 x 4005 (2)
ArchiCADQuantities - Altitude à Zéro du Projet: 5.12 m; Altitude à étage: -0.28 m; Hauteur: 4.005 m; Epaisseur: 0.37 m; Nombre de Portes: 0; Nombre de Fenêtres: 0; Nombre de trous (Nombre d'ouvertures vides): 0; Nombre de Poteaux: 0; Largeur totale des Portes: 0 m; Largeur totale des Fenêtres: 0 m; Epaisseur du Mur à la fin: 0.37 m; Hauteur minimum du Mur: 0 m; Hauteur maximum du Mur: 4.005 m; Surface analytique des ouvertures sur face intérieure: 0 m2; Surface analytique des ouvertures sur face extérieure: 0 m2; Volume analytique des ouvertures dans le Mur: 0 m3; Epaisseur de couche de mur sur face extérieure: 0 m; Epaisseur de couche de mur sur face intérieure: 0 m; Epaisseur couche isolation: 0 m; Epaisseur couche d'air: 0 m; Hauteur de couche de mur minimum sur face extérieure: 0 m; Hauteur de couche de mur maximum sur face extérieure: 0 m; Hauteur de couche de mur minimum sur face intérieure: 0 m; Hauteur de couche de mur maximum sur face intérieure: 0 m; Volume de couche de mur sur face extérieure: 0 m3; Volume de couche de mur sur face intérieure: 0 m3; Volume de couche de mur conditionnelle sur face extérieure: 0 m3; Volume de couche de mur conditionnelle sur face intérieure: 0 m3; Décalage étage d'implantation: -0.28 m; Décalage supérieur: 0 m; Surface des fenêtres dans le mur: 0 m2; Surface des portes dans le mur: 0 m2; Surface des baies libres dans le mur: 0 m2; Volume de poteaux: 0 m3
Name | Length (m) = Longueur moyenne (m) | GrossFootprintArea (m2) | NetFootprintArea (m2) = Superficie (m2) = Surface du Mur (m2) | GrossSideArea (m2) = NetSideArea (m2) | GrossVolume (m3) = NetVolume (m3) = Volume net (m3) = Volume conditionnel (m3) | Superficie de surface (m2) = Surface de mur nette sur face extérieure (m2) = Surface conditionnelle sur face extérieure (m2) | Longueur de mur sur face extérieure (m) = Longueur conditionnelle sur face extérieure (m) = Longueur de ligne de référence (m) | Longueur de mur sur face intérieure (m) = Longueur conditionnelle sur face intérieure (m) | Surface de mur nette sur face intérieure (m2) = Surface conditionnelle sur face intérieure (m2) | Surface nette des arêtes (m2) | Longueur du Mur au centre (m) | Périmètre du Mur (m) | Surface brute de mur sur face intérieure (m2) | Surface brute de mur sur face extérieure (m2) | Volume brut du Mur (m3)
WallEx02 | 25.678 | 9.50086 | 9.50086 | 101.774 | 37.0099 | 104.368 | 26.0743 | 25.2817 | 99.1795 | 18.5639 | 25.678 | 52.4409 | 102.775 | 104.428 | 37.4208 | ArchiCADProperties - Nom de Zone: Plateau bureaux; Numéro de Zone: 005
WallEx02 | 0.211111 | 0.0781109 | 0.0692484 | 0.792365 | 0.272546 | 1.54926 | 0.396729 | 0.0254917 | 0.0354654 | 0.134639 | 0.185619 | 1.35362 | 0.0354654 | 1.5889 | 0.273138

# IfcWall: Profil personnalisé 370 x 4070, SW - 010
In: R+2
Description: WallEx01
ArchiCADProperties - ID: SW - 010; Etage d'implantation: R+2; Nom de Zone: Plateau bureaux; Numéro de Zone: 005; Calque: A-WALL-EXTR; Type: Mur; Verrouillé: no; Matériau de construction / Composite / Profil / Hachure: Profil personnalisé; Fonction structurelle: Elément porteur; Position: Extérieur; Classification d'lément: Mur; Etat de rénovation: Existant; Afficher sur filtre de rénovation: Tous les filtres appropriés; Type de structure: Profil complexe; Matériau de construction / Composite / Profil: Profil personnalisé; Surface latérale: 09 | Paint-02 Whitewash; Angle d'inclinaison externe: 90 deg; Angle d'inclinaison interne: 90 deg; Type d'inclinaison de mur: Droit; Etage supérieur lié: Non lié; Option de géométrie: Uniforme
AC_Pset_RenovationAndPhasing - Renovation Status: Existing
Pset_WallCommon - LoadBearing: yes; IsExternal: yes
BaseQuantities - Length: 51.975 m; Height: 4.07 m; Width: 0.37 m; GrossFootprintArea: 19.2308 m2; NetFootprintArea: 19.2308 m2; GrossSideArea: 199.844 m2; NetSideArea: 199.844 m2; GrossVolume: 72.6169 m3; NetVolume: 72.6169 m3
ArchiCADQuantities - Altitude à Zéro du Projet: 13.45 m; Altitude à étage: 0 m; Hauteur: 4.07 m; Superficie de surface: 211.538 m2; Volume net: 72.6169 m3; Superficie: 19.2308 m2; Epaisseur: 0.37 m; Longueur de mur sur face extérieure: 51.975 m; Longueur de mur sur face intérieure: 51.975 m; Surface de mur nette sur face extérieure: 211.538 m2; Surface de mur nette sur face intérieure: 188.149 m2; Surface nette des arêtes: 31.1207 m2; Volume conditionnel: 72.6169 m3; Nombre de Portes: 0; Nombre de Fenêtres: 0; Nombre de trous (Nombre d'ouvertures vides): 0; Nombre de Poteaux: 0; Largeur totale des Portes: 0 m; Largeur totale des Fenêtres: 0 m; Epaisseur du Mur à la fin: 0.37 m; Hauteur minimum du Mur: 3.62 m; Hauteur maximum du Mur: 4.07 m; Longueur du Mur au centre: 51.975 m; Surface du Mur: 19.2308 m2; Périmètre du Mur: 104.69 m; Surface brute de mur sur face intérieure: 211.538 m2; Surface brute de mur sur face extérieure: 211.538 m2; Volume brut du Mur: 77.0841 m3; Surface analytique des ouvertures sur face intérieure: 0 m2; Surface analytique des ouvertures sur face extérieure: 0 m2; Volume analytique des ouvertures dans le Mur: 0 m3; Epaisseur de couche de mur sur face extérieure: 0 m; Epaisseur de couche de mur sur face intérieure: 0 m; Epaisseur couche isolation: 0 m; Epaisseur couche d'air: 0 m; Hauteur de couche de mur minimum sur face extérieure: 0 m; Hauteur de couche de mur maximum sur face extérieure: 0 m; Hauteur de couche de mur minimum sur face intérieure: 0 m; Hauteur de couche de mur maximum sur face intérieure: 0 m; Longueur conditionnelle sur face extérieure: 51.975 m; Longueur conditionnelle sur face intérieure: 51.975 m; Surface conditionnelle sur face extérieure: 211.538 m2; Surface conditionnelle sur face intérieure: 188.149 m2; Volume de couche de mur sur face extérieure: 0 m3; Volume de couche de mur sur face intérieure: 0 m3; Volume de couche de mur conditionnelle sur face extérieure: 0 m3; Volume de couche de mur conditionnelle sur face intérieure: 0 m3; Longueur de ligne de référence: 51.975 m; Décalage étage d'implantation: 0 m; Décalage supérieur: 0 m; Longueur moyenne: 51.975 m; Surface des fenêtres dans le mur: 0 m2; Surface des portes dans le mur: 0 m2; Surface des baies libres dans le mur: 0 m2; Volume de poteaux: 0 m3

# IfcWall: Profil personnalisé 370 x 4120, SW - 014
In: Mezzannine
Description: WallEx01
ArchiCADProperties - ID: SW - 014; Etage d'implantation: Mezzannine; Nom de Zone: Dégagement; Numéro de Zone: 001; Calque: A-WALL-EXTR; Type: Mur; Verrouillé: no; Matériau de construction / Composite / Profil / Hachure: Profil personnalisé; Fonction structurelle: Elément porteur; Position: Extérieur; Classification d'lément: Type ArchiCAD; Etat de rénovation: Existant; Afficher sur filtre de rénovation: Tous les filtres appropriés; Type de structure: Profil complexe; Matériau de construction / Composite / Profil: Profil personnalisé; Surface latérale: 09 | Paint-02 Whitewash; Angle d'inclinaison externe: 90 deg; Angle d'inclinaison interne: 90 deg; Type d'inclinaison de mur: Droit; Etage supérieur lié: Non lié; Option de géométrie: Uniforme
AC_Pset_RenovationAndPhasing - Renovation Status: Existing
Pset_WallCommon - LoadBearing: yes; IsExternal: yes
BaseQuantities - Length: 7.40543 m; Height: 4.12 m; Width: 0.37 m; GrossFootprintArea: 2.74001 m2; NetFootprintArea: 2.74001 m2; GrossSideArea: 30.2711 m2; NetSideArea: 30.2711 m2; GrossVolume: 10.4899 m3; NetVolume: 10.4899 m3
ArchiCADQuantities - Altitude à Zéro du Projet: 9.425 m; Altitude à étage: 0 m; Hauteur: 4.12 m; Superficie de surface: 31.7903 m2; Volume net: 10.4899 m3; Superficie: 2.74001 m2; Epaisseur: 0.37 m; Longueur de mur sur face extérieure: 7.77322 m; Longueur de mur sur face intérieure: 7.03763 m; Surface de mur nette sur face extérieure: 31.7903 m2; Surface de mur nette sur face intérieure: 28.752 m2; Surface nette des arêtes: 5.40048 m2; Volume conditionnel: 10.4899 m3; Nombre de Portes: 0; Nombre de Fenêtres: 0; Nombre de trous (Nombre d'ouvertures vides): 0; Nombre de Poteaux: 0; Largeur totale des Portes: 0 m; Largeur totale des Fenêtres: 0 m; Epaisseur du Mur à la fin: 0.37 m; Hauteur minimum du Mur: 0 m; Hauteur maximum du Mur: 4.12 m; Longueur du Mur au centre: 7.40543 m; Surface du Mur: 2.74001 m2; Périmètre du Mur: 15.8543 m; Surface brute de mur sur face intérieure: 32.0439 m2; Surface brute de mur sur face extérieure: 32.0263 m2; Volume brut du Mur: 11.2512 m3; Surface analytique des ouvertures sur face intérieure: 0 m2; Surface analytique des ouvertures sur face extérieure: 0 m2; Volume analytique des ouvertures dans le Mur: 0 m3; Epaisseur de couche de mur sur face extérieure: 0 m; Epaisseur de couche de mur sur face intérieure: 0 m; Epaisseur couche isolation: 0 m; Epaisseur couche d'air: 0 m; Hauteur de couche de mur minimum sur face extérieure: 0 m; Hauteur de couche de mur maximum sur face extérieure: 0 m; Hauteur de couche de mur minimum sur face intérieure: 0 m; Hauteur de couche de mur maximum sur face intérieure: 0 m; Longueur conditionnelle sur face extérieure: 7.77322 m; Longueur conditionnelle sur face intérieure: 7.03763 m; Surface conditionnelle sur face extérieure: 31.7903 m2; Surface conditionnelle sur face intérieure: 28.752 m2; Volume de couche de mur sur face extérieure: 0 m3; Volume de couche de mur sur face intérieure: 0 m3; Volume de couche de mur conditionnelle sur face extérieure: 0 m3; Volume de couche de mur conditionnelle sur face intérieure: 0 m3; Longueur de ligne de référence: 7.77322 m; Décalage étage d'implantation: 0 m; Décalage supérieur: 0 m; Longueur moyenne: 7.40543 m; Surface des fenêtres dans le mur: 0 m2; Surface des portes dans le mur: 0 m2; Surface des baies libres dans le mur: 0 m2; Volume de poteaux: 0 m3

# IfcWall: Profil personnalisé 370 x 4280, ExtWall_01
In: R+1
Description: Level_1
ArchiCADProperties - ID: ExtWall_01; Etage d'implantation: R+1; Nom de Zone: Dégagement; Numéro de Zone: 001; Calque: A-WALL-EXTR; Type: Mur; Verrouillé: no; Matériau de construction / Composite / Profil / Hachure: Profil personnalisé; Fonction structurelle: Elément porteur; Position: Extérieur; Classification d'lément: Mur; Etat de rénovation: Existant; Afficher sur filtre de rénovation: Tous les filtres appropriés; Type de structure: Profil complexe; Matériau de construction / Composite / Profil: Profil personnalisé; Surface latérale: 09 | Paint-02 Whitewash; Angle d'inclinaison externe: 90 deg; Angle d'inclinaison interne: 90 deg; Type d'inclinaison de mur: Droit; Etage supérieur lié: Non lié; Option de géométrie: Uniforme
AC_Pset_RenovationAndPhasing - Renovation Status: Existing
Pset_WallCommon - LoadBearing: yes; IsExternal: yes
BaseQuantities - Length: 7.4054 m; Height: 4.28 m; Width: 0.37 m; GrossFootprintArea: 2.74 m2; NetFootprintArea: 2.74 m2; GrossSideArea: 30.7955 m2; NetSideArea: 30.7955 m2; GrossVolume: 10.842 m3; NetVolume: 10.842 m3
ArchiCADQuantities - Altitude à Zéro du Projet: 5.12 m; Altitude à étage: -0.28 m; Hauteur: 4.28 m; Superficie de surface: 33.1105 m2; Volume net: 10.842 m3; Superficie: 2.74 m2; Epaisseur: 0.37 m; Longueur de mur sur face extérieure: 7.77322 m; Longueur de mur sur face intérieure: 7.03758 m; Surface de mur nette sur face extérieure: 33.1105 m2; Surface de mur nette sur face intérieure: 28.4805 m2; Surface nette des arêtes: 2.66828 m2; Volume conditionnel: 10.842 m3; Nombre de Portes: 0; Nombre de Fenêtres: 0; Nombre de trous (Nombre d'ouvertures vides): 0; Nombre de Poteaux: 0; Largeur totale des Portes: 0 m; Largeur totale des Fenêtres: 0 m; Epaisseur du Mur à la fin: 0.37 m; Hauteur minimum du Mur: 0 m; Hauteur maximum du Mur: 4.28 m; Longueur du Mur au centre: 7.4054 m; Surface du Mur: 2.74 m2; Périmètre du Mur: 15.8542 m; Surface brute de mur sur face intérieure: 33.2888 m2; Surface brute de mur sur face extérieure: 33.2698 m2; Volume brut du Mur: 12.1617 m3; Surface analytique des ouvertures sur face intérieure: 0 m2; Surface analytique des ouvertures sur face extérieure: 0 m2; Volume analytique des ouvertures dans le Mur: 0 m3; Epaisseur de couche de mur sur face extérieure: 0 m; Epaisseur de couche de mur sur face intérieure: 0 m; Epaisseur couche isolation: 0 m; Epaisseur couche d'air: 0 m; Hauteur de couche de mur minimum sur face extérieure: 0 m; Hauteur de couche de mur maximum sur face extérieure: 0 m; Hauteur de couche de mur minimum sur face intérieure: 0 m; Hauteur de couche de mur maximum sur face intérieure: 0 m; Longueur conditionnelle sur face extérieure: 7.77322 m; Longueur conditionnelle sur face intérieure: 7.03758 m; Surface conditionnelle sur face extérieure: 33.1105 m2; Surface conditionnelle sur face intérieure: 28.4805 m2; Volume de couche de mur sur face extérieure: 0 m3; Volume de couche de mur sur face intérieure: 0 m3; Volume de couche de mur conditionnelle sur face extérieure: 0 m3; Volume de couche de mur conditionnelle sur face intérieure: 0 m3; Longueur de ligne de référence: 7.77322 m; Décalage étage d'implantation: -0.28 m; Décalage supérieur: 0 m; Longueur moyenne: 7.4054 m; Surface des fenêtres dans le mur: 0 m2; Surface des portes dans le mur: 0 m2; Surface des baies libres dans le mur: 0 m2; Volume de poteaux: 0 m3

# IfcWallStandardCase: % 25 491054888 150 (2)
In: R+2
Description: Wall_Int_02; Material: % 25 491054888 0.15 m
ArchiCADProperties - ID: Wall_Int_02; Etage d'implantation: R+2; Calque: A-WALL-INTR; Type: Mur; Verrouillé: no; Matériau de construction / Composite / Profil / Hachure: % 25 491054888; Fonction structurelle: Non défini; Position: Non défini; Classification d'lément: Type ArchiCAD; Etat de rénovation: Existant; Afficher sur filtre de rénovation: Tous les filtres appropriés; Type de structure: Basique; Matériau de construction / Composite / Profil: % 25 491054888; Surface de face extérieure: 03 | Concrete Light; Surface de face intérieure: 03 | Concrete Light; Surface latérale: 03 | Concrete Light; Angle d'inclinaison externe: 90 deg; Angle d'inclinaison interne: 90 deg; Type d'inclinaison de mur: Droit; Emplacement de ligne de référence: Face extérieure; Etage supérieur lié: Non lié; Option de géométrie: Uniforme
AC_Pset_RenovationAndPhasing - Renovation Status: Existing
BaseQuantities - Height: 3.51 m; Width: 0.15 m
ArchiCADQuantities - Altitude à Zéro du Projet: 13.45 m; Altitude à étage: 0 m; Hauteur: 3.95 m; Epaisseur: 0.15 m; Nombre de Portes: 0; Nombre de Fenêtres: 0; Nombre de trous (Nombre d'ouvertures vides): 0; Nombre de Poteaux: 0; Largeur totale des Portes: 0 m; Largeur totale des Fenêtres: 0 m; Epaisseur du Mur à la fin: 0.15 m; Hauteur minimum du Mur: 3.51 m; Hauteur maximum du Mur: 3.51 m; Surface analytique des ouvertures sur face intérieure: 0 m2; Surface analytique des ouvertures sur face extérieure: 0 m2; Volume analytique des ouvertures dans le Mur: 0 m3; Epaisseur de couche de mur sur face extérieure: 0 m; Epaisseur de couche de mur sur face intérieure: 0 m; Epaisseur couche isolation: 0 m; Epaisseur couche d'air: 0 m; Hauteur de couche de mur minimum sur face extérieure: 0 m; Hauteur de couche de mur maximum sur face extérieure: 0 m; Hauteur de couche de mur minimum sur face intérieure: 0 m; Hauteur de couche de mur maximum sur face intérieure: 0 m; Volume de couche de mur sur face extérieure: 0 m3; Volume de couche de mur sur face intérieure: 0 m3; Volume de couche de mur conditionnelle sur face extérieure: 0 m3; Volume de couche de mur conditionnelle sur face intérieure: 0 m3; Décalage étage d'implantation: 0 m; Décalage supérieur: 0 m; Surface des fenêtres dans le mur: 0 m2; Surface des portes dans le mur: 0 m2; Surface des baies libres dans le mur: 0 m2; Volume de poteaux: 0 m3
Name | Length (m) = Longueur de mur sur face extérieure (m) = Longueur de mur sur face intérieure (m) = Longueur du Mur au centre (m) = Longueur conditionnelle sur face extérieure (m) = Longueur conditionnelle sur face intérieure (m) = Longueur de ligne de référence (m) = Longueur moyenne (m) | GrossFootprintArea (m2) = NetFootprintArea (m2) = Superficie (m2) = Surface du Mur (m2) | GrossSideArea (m2) = NetSideArea (m2) = Superficie de surface (m2) = Surface de mur nette sur face extérieure (m2) = Surface de mur nette sur face intérieure (m2) = Surface conditionnelle sur face extérieure (m2) = Surface conditionnelle sur face intérieure (m2) | GrossVolume (m3) = NetVolume (m3) = Volume net (m3) = Volume conditionnel (m3) | Surface nette des arêtes (m2) | Périmètre du Mur (m) | Surface brute de mur sur face intérieure (m2) = Surface brute de mur sur face extérieure (m2) | Volume brut du Mur (m3)
Wall_Int_02 | 0.00362344 | 0.000543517 | 0.0127183 | 0.00190774 | 1.05354 | 0.307247 | 0.0143126 | 0.00214689
Wall_Int_02 | 0.00339848 | 0.000509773 | 0.0119287 | 0.0017893 | 1.05351 | 0.306797 | 0.013424 | 0.0020136

# IfcWallStandardCase: % 25 491054888 5, SW - 016
In: Mezzannine
Description: Balustrade; Material: % 25 491054888 0.005 m
ArchiCADProperties - ID: SW - 016; Etage d'implantation: Mezzannine; Nom de Zone: Cafetaria; Numéro de Zone: 007; Calque: A-EQMT; Type: Mur; Verrouillé: no; Matériau de construction / Composite / Profil / Hachure: % 25 491054888; Fonction structurelle: Non défini; Position: Non défini; Classification d'lément: Type ArchiCAD; Etat de rénovation: Existant; Afficher sur filtre de rénovation: Tous les filtres appropriés; Type de structure: Basique; Matériau de construction / Composite / Profil: % 25 491054888; Surface de face extérieure: 09 | Glass-Blue/Ice; Surface de face intérieure: 09 | Glass-Blue/Ice; Surface latérale: 09 | Glass-Blue/Ice; Angle d'inclinaison externe: 90 deg; Angle d'inclinaison interne: 90 deg; Type d'inclinaison de mur: Droit; Emplacement de ligne de référence: Face extérieure; Etage supérieur lié: Non lié; Option de géométrie: Uniforme
AC_Pset_RenovationAndPhasing - Renovation Status: Existing
BaseQuantities - Length: 0.395862 m; Height: 1 m; Width: 0.005 m; GrossFootprintArea: 0.00197931 m2; NetFootprintArea: 0.00197931 m2; GrossSideArea: 0.395862 m2; NetSideArea: 0.395862 m2; GrossVolume: 0.00197931 m3; NetVolume: 0.00197931 m3
ArchiCADQuantities - Altitude à Zéro du Projet: 9.425 m; Altitude à étage: 0 m; Hauteur: 1 m; Superficie de surface: 0.395862 m2; Volume net: 0.00197931 m3; Superficie: 0.00197931 m2; Epaisseur: 0.005 m; Longueur de mur sur face extérieure: 0.395862 m; Longueur de mur sur face intérieure: 0.395862 m; Surface de mur nette sur face extérieure: 0.395862 m2; Surface de mur nette sur face intérieure: 0.395862 m2; Surface nette des arêtes: 0.0139586 m2; Volume conditionnel: 0.00197931 m3; Nombre de Portes: 0; Nombre de Fenêtres: 0; Nombre de trous (Nombre d'ouvertures vides): 0; Nombre de Poteaux: 0; Largeur totale des Portes: 0 m; Largeur totale des Fenêtres: 0 m; Epaisseur du Mur à la fin: 0.005 m; Hauteur minimum du Mur: 1 m; Hauteur maximum du Mur: 1 m; Longueur du Mur au centre: 0.395862 m; Surface du Mur: 0.00197931 m2; Périmètre du Mur: 0.801725 m; Surface brute de mur sur face intérieure: 0.395862 m2; Surface brute de mur sur face extérieure: 0.395862 m2; Volume brut du Mur: 0.00197931 m3; Surface analytique des ouvertures sur face intérieure: 0 m2; Surface analytique des ouvertures sur face extérieure: 0 m2; Volume analytique des ouvertures dans le Mur: 0 m3; Epaisseur de couche de mur sur face extérieure: 0 m; Epaisseur de couche de mur sur face intérieure: 0 m; Epaisseur couche isolation: 0 m; Epaisseur couche d'air: 0 m; Hauteur de couche de mur minimum sur face extérieure: 0 m; Hauteur de couche de mur maximum sur face extérieure: 0 m; Hauteur de couche de mur minimum sur face intérieure: 0 m; Hauteur de couche de mur maximum sur face intérieure: 0 m; Longueur conditionnelle sur face extérieure: 0.395862 m; Longueur conditionnelle sur face intérieure: 0.395862 m; Surface conditionnelle sur face extérieure: 0.395862 m2; Surface conditionnelle sur face intérieure: 0.395862 m2; Volume de couche de mur sur face extérieure: 0 m3; Volume de couche de mur sur face intérieure: 0 m3; Volume de couche de mur conditionnelle sur face extérieure: 0 m3; Volume de couche de mur conditionnelle sur face intérieure: 0 m3; Longueur de ligne de référence: 0.395862 m; Décalage étage d'implantation: 0 m; Décalage supérieur: 0 m; Longueur moyenne: 0.395862 m; Surface des fenêtres dans le mur: 0 m2; Surface des portes dans le mur: 0 m2; Surface des baies libres dans le mur: 0 m2; Volume de poteaux: 0 m3

# IfcWallStandardCase: % 50 1740021793 75 (7)
In: Rez de chaussée
Description: Level_1; Material: % 50 1740021793 0.075 m
ArchiCADProperties - Etage d'implantation: Rez de chaussée; Calque: A-WALL-EXTR; Type: Mur; Verrouillé: no; Matériau de construction / Composite / Profil / Hachure: % 50 1740021793; Classification d'lément: Type ArchiCAD; Etat de rénovation: Existant; Afficher sur filtre de rénovation: Tous les filtres appropriés; Type de structure: Basique; Matériau de construction / Composite / Profil: % 50 1740021793; Surface de face extérieure: 09 | Paint-02 Whitewash; Surface de face intérieure: 09 | Paint-02 Whitewash; Surface latérale: 09 | Paint-02 Whitewash; Angle d'inclinaison externe: 90 deg; Angle d'inclinaison interne: 90 deg; Type d'inclinaison de mur: Droit; Etage supérieur lié: Non lié; Option de géométrie: Uniforme
AC_Pset_RenovationAndPhasing - Renovation Status: Existing
BaseQuantities - Width: 0.075 m
ArchiCADQuantities - Epaisseur: 0.075 m; Nombre de Portes: 0; Nombre de Fenêtres: 0; Nombre de trous (Nombre d'ouvertures vides): 0; Nombre de Poteaux: 0; Largeur totale des Portes: 0 m; Largeur totale des Fenêtres: 0 m; Epaisseur du Mur à la fin: 0.075 m; Epaisseur de couche de mur sur face extérieure: 0 m; Epaisseur de couche de mur sur face intérieure: 0 m; Epaisseur couche isolation: 0 m; Epaisseur couche d'air: 0 m; Hauteur de couche de mur minimum sur face extérieure: 0 m; Hauteur de couche de mur maximum sur face extérieure: 0 m; Hauteur de couche de mur minimum sur face intérieure: 0 m; Hauteur de couche de mur maximum sur face intérieure: 0 m; Volume de couche de mur sur face extérieure: 0 m3; Volume de couche de mur sur face intérieure: 0 m3; Volume de couche de mur conditionnelle sur face extérieure: 0 m3; Volume de couche de mur conditionnelle sur face intérieure: 0 m3; Décalage supérieur: 0 m; Surface des fenêtres dans le mur: 0 m2; Surface des portes dans le mur: 0 m2; Surface des baies libres dans le mur: 0 m2; Volume de poteaux: 0 m3
Name | ID | Fonction structurelle | Position | Emplacement de ligne de référence | LoadBearing = IsExternal | Length (m) = Longueur moyenne (m) | Height (m) = Hauteur maximum du Mur (m) | GrossFootprintArea (m2) | NetFootprintArea (m2) = Superficie (m2) = Surface du Mur (m2) | GrossSideArea (m2) = NetSideArea (m2) | GrossVolume (m3) = NetVolume (m3) = Volume net (m3) = Volume conditionnel (m3) | Altitude à Zéro du Projet (m) = Altitude à étage (m) = Décalage étage d'implantation (m) | Hauteur (m) | Superficie de surface (m2) = Surface de mur nette sur face extérieure (m2) = Surface conditionnelle sur face extérieure (m2) | Longueur de mur sur face extérieure (m) = Longueur conditionnelle sur face extérieure (m) | Longueur de mur sur face intérieure (m) = Longueur conditionnelle sur face intérieure (m) | Surface de mur nette sur face intérieure (m2) = Surface conditionnelle sur face intérieure (m2) | Surface nette des arêtes (m2) | Hauteur minimum du Mur (m) | Longueur du Mur au centre (m) | Périmètre du Mur (m) | Surface brute de mur sur face intérieure (m2) | Surface brute de mur sur face extérieure (m2) | Volume brut du Mur (m3) | Surface analytique des ouvertures sur face intérieure (m2) | Surface analytique des ouvertures sur face extérieure (m2) | Volume analytique des ouvertures dans le Mur (m3) | Longueur de ligne de référence (m)
WallEx_04 | WallEx_04 | Elément porteur | Extérieur | Centrer | yes | 1.97149 | 19.3993 | 0.147861 | 0.147861 | 36.6778 | 2.75084 | -0.195 | 22.195 | 36.3346 | 1.91185 | 2.03112 | 37.021 | 1.72137 | 0 | 1.97149 | 4.15887 | 39.2102 | 38.5241 | 2.91504 | 0 | 0 | 0 | 1.97149
WallEx_04 | WallEx_04 | Non défini | Non défini | Centrer |  | 0.597692 | 19.2542 | 0.0448269 | 0.0448269 | 12.3858 | 0.928937 | 0 | 22 | 12.2383 | 0.509046 | 0.686338 | 12.5334 | 0.101901 | 0 | 0.597692 | 1.4311 | 13.2014 | 12.887 | 0.978317 | 3.8618e-12 | 3.25251e-12 | 2.66787e-13 | 0.597692
WallEx04 | WallEx04 | Elément porteur | Extérieur | Face extérieure | yes | 1.86457 | 19.3098 | 0.139843 | 0.139843 | 34.637 | 2.59777 | -0.195 | 22.195 | 34.7812 | 1.86085 | 1.86829 | 34.4927 | 1.58532 | 0 | 1.86457 | 3.87951 | 36.8628 | 36.8749 | 2.76517 | 0 | 0 | 0 | 1.86085
WallEx04 | WallEx04 | Non défini | Non défini | Face extérieure |  | 0.32321 | 22 | 0.0242407 | 0.0242404 | 0 | 0 | 0 | 22 | 0 | 0.437042 | 0.209377 | 0 | 0 | 22 | 0.323002 | 0.796794 | 0 | 0 | 0 | 0 | 0 | 0 | 0.437042
WallEx04 | WallEx04 | Elément porteur | Extérieur | Face extérieure | yes | 2.11582 | 19.2622 | 0.158687 | 0.158687 | 34.9417 | 2.66003 | -0.195 | 22.195 | 34.072 | 2.11635 | 2.11529 | 35.8114 | 1.48138 | 0 | 2.11582 | 4.38165 | 43.2506 | 41.4838 | 3.21752 | 0 | 0 | 0 | 2.11635
WallEx_04 | WallEx_04 | Elément porteur | Extérieur | Centrer | yes | 1.76497 | 19.4016 | 0.132373 | 0.132373 | 32.1116 | 2.40837 | -0.195 | 22.195 | 32.276 | 1.73596 | 1.79398 | 31.9471 | 1.68973 | 0 | 1.76497 | 3.69976 | 34.6622 | 35.0309 | 2.61349 | 1.28842e-09 | 9.50209e-10 | 8.39488e-11 | 1.76497
WallEx_04 | WallEx_04 | Non défini | Non défini | Centrer |  | 0.294743 | 19.4113 | 0.0221057 | 0.0221057 | 5.73443 | 0.430068 | 0 | 22 | 3.58346 | 0.184214 | 0.405271 | 7.88541 | 2.95443 | 19.3993 | 0.294743 | 0.739485 | 7.88541 | 3.58346 | 0.430068 | 0 | 0 | 0 | 0.294743

# IfcWallStandardCase: 0.0-Cloison: parpaing + plâtre 2 faces copie 130 (138)
Material: Finition int - Enduit plâtre 0.015 m, Struct. - Parpaing béton 0.1 m, Finition int - Enduit plâtre 0.015 m
ArchiCADProperties - Calque: A-WALL-INTR; Type: Mur; Verrouillé: no; Matériau de construction / Composite / Profil / Hachure: 0.0-Cloison: parpaing + plâtre 2 faces copie; Etat de rénovation: Existant; Afficher sur filtre de rénovation: Tous les filtres appropriés; Type de structure: Composite; Matériau de construction / Composite / Profil: 0.0-Cloison: parpaing + plâtre 2 faces copie; Angle d'inclinaison externe: 90 deg; Angle d'inclinaison interne: 90 deg; Type d'inclinaison de mur: Droit; Etage supérieur lié: Non lié; Option de géométrie: Uniforme
AC_Pset_RenovationAndPhasing - Renovation Status: Existing
BaseQuantities - Width: 0.13 m
ArchiCADQuantities - Epaisseur: 0.13 m; Nombre de Fenêtres: 0; Nombre de trous (Nombre d'ouvertures vides): 0; Largeur totale des Fenêtres: 0 m; Epaisseur du Mur à la fin: 0.13 m; Epaisseur de couche de mur sur face extérieure: 0.015 m; Epaisseur de couche de mur sur face intérieure: 0.015 m; Epaisseur couche isolation: 0 m; Epaisseur couche d'air: 0 m; Décalage supérieur: 0 m; Surface des fenêtres dans le mur: 0 m2; Surface des baies libres dans le mur: 0 m2; Volume de poteaux: 0 m3
Name | In | Description | ID | Etage d'implantation | Nom de Zone | Numéro de Zone | Fonction structurelle | Position | Classification d'lément | Surface de face extérieure = Surface de face intérieure = Surface latérale | Emplacement de ligne de référence | LoadBearing | IsExternal | Length (m) = Longueur du Mur au centre (m) = Longueur moyenne (m) | Height (m) = Hauteur maximum du Mur (m) | GrossFootprintArea (m2) = NetFootprintArea (m2) = Superficie (m2) = Surface du Mur (m2) | GrossSideArea (m2) | NetSideArea (m2) | GrossVolume (m3) | NetVolume (m3) = Volume net (m3) | Altitude à Zéro du Projet (m) | Altitude à étage (m) = Décalage étage d'implantation (m) | Hauteur (m) | Superficie de surface (m2) = Surface de mur nette sur face extérieure (m2) = Surface conditionnelle sur face extérieure (m2) | Longueur de mur sur face extérieure (m) = Longueur conditionnelle sur face extérieure (m) | Longueur de mur sur face intérieure (m) = Longueur conditionnelle sur face intérieure (m) | Surface de mur nette sur face intérieure (m2) = Surface conditionnelle sur face intérieure (m2) | Surface nette des arêtes (m2) | Volume conditionnel (m3) | Nombre de Portes | Nombre de Poteaux | Largeur totale des Portes (m) | Hauteur minimum du Mur (m) | Périmètre du Mur (m) | Surface brute de mur sur face intérieure (m2) | Surface brute de mur sur face extérieure (m2) | Volume brut du Mur (m3) | Surface analytique des ouvertures sur face intérieure (m2) | Surface analytique des ouvertures sur face extérieure (m2) | Volume analytique des ouvertures dans le Mur (m3) | Hauteur de couche de mur minimum sur face extérieure (m) | Hauteur de couche de mur maximum sur face extérieure (m) | Hauteur de couche de mur minimum sur face intérieure (m) | Hauteur de couche de mur maximum sur face intérieure (m) | Volume de couche de mur sur face extérieure (m3) | Volume de couche de mur sur face intérieure (m3) | Volume de couche de mur conditionnelle sur face extérieure (m3) | Volume de couche de mur conditionnelle sur face intérieure (m3) | Longueur de ligne de référence (m) | Surface des portes dans le mur (m2)
Wall_Int_02 | Rez de chaussée | Wall_Int_02 | Wall_Int_02 | Rez de chaussée | Dégagement | 001 | Elément porteur | Intérieur | Type ArchiCAD | Enduit - Blanc fin | Face extérieure | yes | no | 2.60376 | 5.22 | 0.338489 | 12.7614 | 10.8664 | 1.73293 | 1.47608 | -0.1 | -0.1 | 5.22 | 10.8661 | 2.60369 | 2.60384 | 10.8668 | 0.284167 | 1.47608 | 1 | 0 | 1 | 0 | 5.46752 | 16.189 | 16.1883 | 2.10452 | 1.895 | 1.89497 | 0.25685 | 0 | 5.22 | 0 | 5.22 | 0.162992 | 0.163001 | 0.162992 | 0.163001 | 2.97369 | 2.1
VOILE_15CM | Rez de chaussée | 6700*150 | VOILE_15CM | Rez de chaussée |  |  | Elément porteur | Intérieur | Mur | Enduit - Blanc fin | Centrer | yes | no | 3.85973 | 16.95 | 0.501765 | 63.8233 | 63.8233 | 8.65543 | 8.65543 | 0 | 0 | 16.95 | 65.9573 | 3.78892 | 3.93055 | 61.6894 | 1.59588 | 8.65543 | 0 | 0 | 0 | 0 | 8.04171 | 68.7603 | 68.7032 | 8.93513 | 0 | 0 | 0 | 0 | 16.95 | 0 | 16.95 | 0.987223 | 0.925292 | 0.987223 | 0.925292 | 4.05497 | 0 | Pset_WallCommon - Reference: VO0(?); Tekla Commun - GUID: ID551A4115-0000-4188-3134-323737393933; RepËre de piËce: VO0(?); RepËre d'assemblage: VO0(?); Phase: 10; Classe: 6; MatÈriau: C25/30; Profil: 6700*150; Nom: VOILE_15CM
Wall_Int | Rez de chaussée | Wall_Int_02 | Wall_Int | Rez de chaussée | Réserve | 010 | Elément porteur | Intérieur | Type ArchiCAD | Enduit - Blanc fin | Face extérieure | yes | no | 3.88015 | 5.12 | 0.504419 | 18.9933 | 18.9933 | 2.5718 | 2.5718 | 0 | 0 | 5.12 | 18.9976 | 3.88103 | 3.87927 | 18.989 | 0.782031 | 2.5718 | 0 | 0 | 0 | 0 | 8.02038 | 21.1935 | 21.2025 | 2.75574 | 0 | 0 | 0 | 0 | 5.12 | 0 | 5.12 | 0.284957 | 0.284843 | 0.284957 | 0.284843 | 4.14111 | 0
Wall_Int_06 | Rez de chaussée | Wall_Int_02 | Wall_Int_06 | Rez de chaussée |  |  | Elément porteur | Intérieur | Type ArchiCAD | Enduit - Blanc fin | Centrer | yes | no | 2.00799 | 5.12 | 0.261039 | 9.58437 | 7.68087 | 1.3233 | 1.0664 | 0 | 0 | 5.12 | 7.92854 | 2.00859 | 2.0074 | 7.43319 | 0.973449 | 1.0664 | 1 | 0 | 0.9 | 0 | 4.27599 | 10.9435 | 10.9496 | 1.42305 | 1.9035 | 1.9035 | 0.256905 | 0 | 5.12 | 0 | 5.12 | 0.118923 | 0.111503 | 0.118923 | 0.111503 | 2.073 | 1.89
VOILE_10CM | Rez de chaussée | 5850*100 | VOILE_10CM | Rez de chaussée | Surface expoitation | 007 | Elément porteur | Intérieur | Mur | Surf-White | Face extérieure | yes | no | 2.92 | 5.11886 | 0.3796 | 13.6448 | 11.5898 | 1.90405 | 1.6264 | 0 | 0 | 5.11886 | 12.2384 | 2.92 | 2.92 | 10.9412 | 1.72805 | 1.6264 | 1 | 0 | 1 | 0 | 6.1 | 14.9471 | 14.9471 | 1.94312 | 2.055 | 2.055 | 0.27765 | 0 | 5.11886 | 0 | 5.11886 | 0.183576 | 0.164118 | 0.183576 | 0.164118 | 2.92 | 2.1 | Pset_WallCommon - Reference: VO0(?); Tekla Commun - GUID: ID551A4115-0000-E719-3134-323738313437; RepËre de piËce: VO0(?); RepËre d'assemblage: VO0(?); Phase: 10; Classe: 6; MatÈriau: C25/30; Profil: 5850*100; Nom: VOILE_10CM
VOILE_15CM | Rez de chaussée | 6700*150 | VOILE_15CM | Rez de chaussée | Plateau bureaux | 005 | Elément porteur | Intérieur | Type ArchiCAD | Enduit - Blanc fin | Face extérieure | yes | no | 6.78015 | 16.96 | 0.881419 | 109.4 | 84.1996 | 14.6814 | 11.4054 | 0 | 0 | 17.425 | 85.9951 | 6.78015 | 6.78015 | 82.4042 | 1.99609 | 11.4054 | 8 | 0 | 12 | 0 | 13.8203 | 127.805 | 120.046 | 16.1103 | 25.2 | 25.2 | 3.276 | 0 | 16.96 | 0 | 16.96 | 1.31634 | 1.23606 | 1.31634 | 1.23606 | 6.84515 | 25.2 | Pset_WallCommon - Reference: VO0(?); Tekla Commun - GUID: ID551A4115-0000-40DE-3134-323737393933; RepËre de piËce: VO0(?); RepËre d'assemblage: VO0(?); Phase: 10; Classe: 6; MatÈriau: C25/30; Profil: 6700*150; Nom: VOILE_15CM
Wall_Int_06 | Rez de chaussée | Wall_Int_02 | Wall_Int_06 | Rez de chaussée | Réserve | 010 | Elément porteur | Intérieur | Type ArchiCAD | Enduit - Blanc fin | Face extérieure | yes | no | 11.6468 | 5.12 | 1.51409 | 56.7614 | 56.7614 | 7.66603 | 7.66603 | 0 | 0 | 5.12 | 57.0113 | 11.6468 | 11.6468 | 56.5115 | 3.57364 | 7.66603 | 0 | 0 | 0 | 0 | 23.5537 | 59.6318 | 59.6318 | 7.75214 | 0 | 0 | 0 | 0 | 5.12 | 0 | 5.12 | 0.855169 | 0.847682 | 0.855169 | 0.847682 | 11.6468 | 0
VOILE_15CM | Rez de chaussée | 6700*150 | VOILE_15CM | Rez de chaussée | Local Tech. | 008 | Elément porteur | Intérieur | Type ArchiCAD | Enduit - Blanc fin | Face extérieure | yes | no | 3.79497 | 16.96 | 0.493346 | 61.3467 | 61.3467 | 8.24992 | 8.24992 | 0 | 0 | 17.4 | 60.747 | 3.79497 | 3.79497 | 61.9464 | 0.948419 | 8.24992 | 0 | 0 | 0 | 0 | 7.84994 | 70.5565 | 70.5565 | 9.17234 | 0 | 0 | 0 | 0 | 16.96 | 0 | 16.96 | 0.911205 | 0.929195 | 0.911205 | 0.929195 | 4.05497 | 0 | Pset_WallCommon - Reference: VO0(?); Tekla Commun - GUID: ID551A4115-0000-41A0-3134-323737393933; RepËre de piËce: VO0(?); RepËre d'assemblage: VO0(?); Phase: 10; Classe: 6; MatÈriau: C25/30; Profil: 6700*150; Nom: VOILE_15CM
Wall_Int_06 | Rez de chaussée | Wall_Int_02 | Wall_Int_06 | Rez de chaussée | Réserve | 008 | Elément porteur | Intérieur | Type ArchiCAD | Enduit - Blanc fin | Face extérieure | yes | no | 3.92296 | 5.12 | 0.509985 | 19.2029 | 19.2029 | 2.59232 | 2.59232 | 0 | 0 | 5.12 | 19.2027 | 3.92293 | 3.923 | 19.2031 | 1.44644 | 2.59232 | 0 | 0 | 0 | 0 | 8.10592 | 20.7513 | 20.751 | 2.69765 | 0 | 0 | 0 | 0 | 5.12 | 0 | 5.12 | 0.288041 | 0.288046 | 0.288041 | 0.288046 | 3.92293 | 0
Wall_Int_SEC_01 | Rez de chaussée | Wall_Int_02 | Wall_Int_SEC_01 | Rez de chaussée | Réserve | 010 | Elément porteur | Intérieur | Type ArchiCAD | Enduit - Blanc fin | Face extérieure | yes | no | 4.21579 | 5.12 | 0.548052 | 20.3431 | 20.3431 | 2.57203 | 2.57203 | 0 | 0 | 5.12 | 20.6143 | 4.2113 | 4.22027 | 20.0719 | 0.766302 | 2.57203 | 0 | 0 | 0 | 0 | 8.69183 | 22.2734 | 27.5427 | 3.23804 | 0 | 0 | 0 | 0 | 5.12 | 0 | 5.12 | 0.304855 | 0.305438 | 0.304855 | 0.305438 | 4.79536 | 0
Wall_Int_05 | Rez de chaussée | Wall_Int_02 | Wall_Int_05 | Rez de chaussée | Réserve | 008 | Elément porteur | Intérieur | Type ArchiCAD | Enduit - Blanc fin | Face extérieure | yes | no | 7.38567 | 5.12 | 0.960137 | 35.6266 | 28.4416 | 4.83241 | 3.86686 | 0 | 0 | 5.12 | 28.276 | 7.45934 | 7.31199 | 28.6072 | 1.17016 | 3.86686 | 2 | 0 | 3 | 0 | 15.0864 | 38.7745 | 38.8633 | 5.04645 | 7.185 | 7.185 | 0.96555 | 0 | 5.12 | 0 | 5.12 | 0.424067 | 0.429182 | 0.424067 | 0.429182 | 7.45934 | 7.5
VOILE_10CM | Rez de chaussée | 5850*100 | VOILE_10CM | Rez de chaussée | WC | 003 | Elément porteur | Intérieur | Mur | Surf-White | Face extérieure | yes | no | 2.33 | 5.11886 | 0.3029 | 11.4054 | 11.4054 | 1.55021 | 1.55021 | 8.88178e-16 | 8.88178e-16 | 5.11886 | 11.4054 | 2.33 | 2.33 | 11.4054 | 0.472 | 1.55021 | 0 | 0 | 0 | 0 | 4.92 | 13.2578 | 13.2578 | 1.72352 | 0 | 0 | -2.22045e-16 | 0 | 5.11886 | 0 | 5.11886 | 0.17108 | 0.17108 | 0.17108 | 0.17108 | 2.54 | 0 | Pset_WallCommon - Reference: VO0(?); Tekla Commun - GUID: ID551A4115-0000-E741-3134-323738313437; RepËre de piËce: VO0(?); RepËre d'assemblage: VO0(?); Phase: 10; Classe: 6; MatÈriau: C25/30; Profil: 5850*100; Nom: VOILE_10CM
Wall_Int_06 | Rez de chaussée | Wall_Int_02 | Wall_Int_06 | Rez de chaussée |  |  | Elément porteur | Intérieur | Type ArchiCAD | Enduit - Blanc fin | Face extérieure | yes | no | 11.6363 | 5.12 | 1.51272 | 57.8745 | 54.1755 | 8.49635 | 7.89303 | 0 | 0 | 5.12 | 55.575 | 11.6353 | 11.6373 | 52.776 | 3.12198 | 7.89303 | 2 | 0 | 1.8 | 0 | 23.5326 | 59.5832 | 80.597 | 9.11171 | 3.699 | 3.699 | 0.603314 | 0 | 5.12 | 0 | 5.12 | 0.816239 | 0.80272 | 0.816239 | 0.80272 | 11.6353 | 3.78
Wall_Int_05 | Rez de chaussée | Wall_Int_02 | Wall_Int_05 | Rez de chaussée |  |  | Elément porteur | Intérieur | Type ArchiCAD | Enduit - Blanc fin | Centrer | yes | no | 7.53706 | 5.12 | 0.979818 | 36.3677 | 34.5722 | 4.93208 | 4.68922 | 0 | 0 | 5.12 | 34.8535 | 7.60202 | 7.47209 | 34.2909 | 1.41041 | 4.68922 | 1 | 0 | 0.9 | 0 | 15.3879 | 40.8171 | 40.8168 | 5.3062 | 1.7955 | 1.7955 | 0.242865 | 0 | 5.12 | 0 | 5.12 | 0.522802 | 0.514363 | 0.522802 | 0.514363 | 7.90706 | 1.89
VOILE_15CM | Rez de chaussée | 5850*150 | VOILE_15CM | Rez de chaussée | Rangement | 006 | Elément porteur | Intérieur | Type ArchiCAD | Enduit - Blanc fin | Face extérieure | yes | no | 9.75 | 5.12 | 1.2675 | 47.0632 | 40.7182 | 6.3527 | 5.49635 | 0 | 0 | 5.12 | 39.5656 | 9.62 | 9.88 | 41.8708 | 1.66615 | 5.49635 | 3 | 0 | 3 | 0 | 19.8677 | 50.5856 | 50.5856 | 6.57613 | 6.345 | 6.345 | 0.85635 | 0 | 5.12 | 0 | 5.12 | 0.593484 | 0.628061 | 0.593484 | 0.628061 | 9.75 | 6.3 | Pset_WallCommon - Reference: VO0(?); Tekla Commun - GUID: ID551A4115-0000-423A-3134-323737393933; RepËre de piËce: VO0(?); RepËre d'assemblage: VO0(?); Phase: 10; Classe: 6; MatÈriau: C25/30; Profil: 5850*150; Nom: VOILE_15CM
Wall_Int_02 | Rez de chaussée | Wall_Int_02 | Wall_Int_02 | Rez de chaussée | Dégagement | 002 | Elément porteur | Intérieur | Type ArchiCAD | Enduit - Blanc fin | Face extérieure | yes | no | 4.03055 | 16.96 | 0.523972 | 63.9267 | 63.9267 | 8.51678 | 8.51678 | 0 | 0 | 17.425 | 63.9335 | 4.03112 | 4.02998 | 63.9198 | 2.50773 | 8.51678 | 0 | 0 | 0 | 0 | 8.32111 | 76.6742 | 76.6897 | 9.96866 | 0 | 0 | 0 | 0 | 16.96 | 0 | 16.96 | 0.919425 | 0.948717 | 0.919425 | 0.948717 | 4.40113 | 0
Wall_Int_SEC_01 | Rez de chaussée | Wall_Int_02 | Wall_Int_SEC_01 | Rez de chaussée | Réserve | 008 | Elément porteur | Intérieur | Type ArchiCAD | Enduit - Blanc fin | Face extérieure | yes | no | 2.65473 | 5.12 | 0.345115 | 12.9949 | 12.9949 | 1.7645 | 1.7645 | 0 | 0 | 5.12 | 12.9526 | 2.6461 | 2.66337 | 13.0372 | 0.536973 | 1.7645 | 0 | 0 | 0 | 0 | 5.57061 | 16.2131 | 16.1247 | 2.10196 | 0 | 0 | 0 | 0 | 5.12 | 0 | 5.12 | 0.194363 | 0.195485 | 0.194363 | 0.195485 | 3.08435 | 0
Wall_Int_SEC_01 | Rez de chaussée | Wall_Int_02 | Wall_Int_SEC_01 | Rez de chaussée |  |  | Elément porteur | Intérieur | Type ArchiCAD | Enduit - Blanc fin | Centrer | yes | no | 25.9248 | 5.12 | 3.37023 | 126.461 | 114.491 | 17.2795 | 15.6604 | 0 | 0 | 5.12 | 114.977 | 25.9341 | 25.9156 | 114.005 | 4.66783 | 15.6604 | 4 | 0 | 6 | 0 | 52.1104 | 138.671 | 133.45 | 17.6879 | 11.97 | 11.97 | 1.6191 | 0 | 5.12 | 0 | 5.12 | 1.72898 | 1.70575 | 1.72898 | 1.70575 | 25.5362 | 12.6
VOILE_15CM | Rez de chaussée | 6700*150 | VOILE_15CM | Rez de chaussée | Réserve | 009 | Elément porteur | Intérieur | Type ArchiCAD | Enduit - Blanc fin | Face extérieure | yes | no | 3.79586 | 5.12 | 0.493462 | 18.5807 | 15.4082 | 2.51626 | 2.08809 | 0 | 0 | 5.12 | 15.4025 | 3.79468 | 3.79704 | 15.414 | 0.615173 | 2.08809 | 1 | 0 | 1.5 | 0 | 7.85174 | 20.7722 | 20.7601 | 2.69959 | 3.1725 | 3.1725 | 0.428175 | 0 | 5.12 | 0 | 5.12 | 0.231047 | 0.2312 | 0.231047 | 0.2312 | 4.0547 | 3.15 | Pset_WallCommon - Reference: VO0(?); Tekla Commun - GUID: ID551A4115-0000-4160-3134-323737393933; RepËre de piËce: VO0(?); RepËre d'assemblage: VO0(?); Phase: 10; Classe: 6; MatÈriau: C25/30; Profil: 6700*150; Nom: VOILE_15CM
VOILE_15CM | Rez de chaussée | 6700*150 | VOILE_15CM | Rez de chaussée | Surface expoitation | 007 | Elément porteur | Intérieur | Type ArchiCAD | Enduit - Blanc fin | Face extérieure | yes | no | 6.86106 | 5.12 | 0.891938 | 31.6549 | 25.4899 | 3.6273 | 2.90382 | 0 | 0 | 5.12 | 27.1708 | 6.79518 | 6.92694 | 23.809 | 0.795672 | 2.90382 | 2 | 0 | 3 | 0 | 14.0358 | 35.4659 | 56.4812 | 5.97657 | 6.165 | 6.165 | 0.723489 | 0 | 5.12 | 0 | 5.12 | 0.390175 | 0.373485 | 0.390175 | 0.373485 | 6.86018 | 6.3 | Pset_WallCommon - Reference: VO0(?); Tekla Commun - GUID: ID551A4115-0000-413C-3134-323737393933; RepËre de piËce: VO0(?); RepËre d'assemblage: VO0(?); Phase: 10; Classe: 6; MatÈriau: C25/30; Profil: 6700*150; Nom: VOILE_15CM
MACONNERIE_15CM | Rez de chaussée | 5000*150 | MACONNERIE_15CM | Rez de chaussée |  |  | Elément porteur | Intérieur | Type ArchiCAD | Enduit - Blanc fin | Centrer | yes | no | 23.7796 | 5.12 | 3.09134 | 116.251 | 113.078 | 15.6328 | 15.2047 | 0 | 0 | 5.12 | 112.797 | 23.7147 | 23.8444 | 113.359 | 4.59427 | 15.2047 | 1 | 1 | 1.5 | 0 | 47.8727 | 122.083 | 122.085 | 15.8709 | 3.1725 | 3.1725 | 0.428175 | 0 | 5.12 | 0 | 5.12 | 1.69195 | 1.70039 | 1.69195 | 1.70039 | 23.7146 | 3.15 | Pset_WallCommon - Reference: MA0(?); Tekla Commun - GUID: ID551A4115-0000-E7E9-3134-323738313437; RepËre de piËce: MA0(?); RepËre d'assemblage: MA0(?); Phase: 10; Classe: 6; MatÈriau: MUR-BRIQUE; Profil: 5000*150; Nom: MACONNERIE_15CM
VOILE_15CM | Rez de chaussée | 5850*150 | VOILE_15CM | Rez de chaussée | Dégagement | 001 | Elément porteur | Intérieur | Type ArchiCAD | Enduit - Blanc fin | Face extérieure | yes | no | 1.845 | 5.12 | 0.23985 | 9.03127 | 9.03127 | 1.23094 | 1.23094 | 0 | 0 | 5.12 | 9.03127 | 1.845 | 1.845 | 9.03127 | 0.375 | 1.23094 | 0 | 0 | 0 | 0 | 3.95 | 10.7776 | 10.7776 | 1.40109 | 0 | 0 | 0 | 0 | 5.12 | 0 | 5.12 | 0.135469 | 0.135469 | 0.135469 | 0.135469 | 1.845 | 0 | Pset_WallCommon - Reference: VO0(?); Tekla Commun - GUID: ID551A4115-0000-418C-3134-323737393933; RepËre de piËce: VO0(?); RepËre d'assemblage: VO0(?); Phase: 10; Classe: 6; MatÈriau: C25/30; Profil: 5850*150; Nom: VOILE_15CM
VOILE_15CM | Rez de chaussée | 5850*150 | VOILE_15CM | Rez de chaussée | Rangement | 006 | Elément porteur | Intérieur | Type ArchiCAD | Enduit - Blanc fin | Face extérieure | yes | no | 5.32638 | 5.12 | 0.692429 | 25.8279 | 23.8329 | 3.5173 | 3.24745 | 0 | 0 | 5.12 | 23.5881 | 5.32638 | 5.32638 | 24.0776 | 0.971275 | 3.24745 | 1 | 0 | 1 | 0 | 10.9128 | 28.6022 | 28.6022 | 3.71829 | 1.995 | 1.995 | 0.26985 | 0 | 5.12 | 0 | 5.12 | 0.353822 | 0.361164 | 0.353822 | 0.361164 | 5.58638 | 2.1 | Pset_WallCommon - Reference: VO0(?); Tekla Commun - GUID: ID551A4115-0000-418C-3134-323737393933; RepËre de piËce: VO0(?); RepËre d'assemblage: VO0(?); Phase: 10; Classe: 6; MatÈriau: C25/30; Profil: 5850*150; Nom: VOILE_15CM
VOILE_15CM | Rez de chaussée | 5850*150 | VOILE_15CM | Rez de chaussée | Cage Escalier | 001 | Elément porteur | Intérieur | Type ArchiCAD | Enduit - Blanc fin | Face extérieure | yes | no | 2.575 | 5.12 | 0.33475 | 12.5312 | 12.5312 | 1.64314 | 1.64314 | 0 | 0 | 5.12 | 11.9683 | 2.445 | 2.705 | 13.0941 | 0.495 | 1.64314 | 0 | 0 | 0 | 0 | 5.5177 | 13.8496 | 13.8496 | 1.80045 | 0 | 0 | 0 | 0 | 5.12 | 0 | 5.12 | 0.179524 | 0.196412 | 0.179524 | 0.196412 | 2.575 | 0 | Pset_WallCommon - Reference: VO0(?); Tekla Commun - GUID: ID551A4115-0000-41A8-3134-323737393933; RepËre de piËce: VO0(?); RepËre d'assemblage: VO0(?); Phase: 10; Classe: 6; MatÈriau: C25/30; Profil: 5850*150; Nom: VOILE_15CM
VOILE_15CM | Rez de chaussée | 5850*150 | VOILE_15CM | Rez de chaussée | Surface expoitation | 007 | Elément porteur | Intérieur | Type ArchiCAD | Enduit - Blanc fin | Face extérieure | yes | no | 5.425 | 5.12 | 0.70525 | 26.6288 | 26.6288 | 3.62766 | 3.62766 | 0 | 0 | 5.12 | 27.1917 | 5.555 | 5.295 | 26.0659 | 1.25185 | 3.62766 | 0 | 0 | 0 | 0 | 11.2177 | 28.4416 | 28.4416 | 3.69741 | 0 | 0 | 0 | 0 | 5.12 | 0 | 5.12 | 0.407876 | 0.390988 | 0.407876 | 0.390988 | 5.295 | 0 | Pset_WallCommon - Reference: VO0(?); Tekla Commun - GUID: ID551A4115-0000-41B0-3134-323737393933; RepËre de piËce: VO0(?); RepËre d'assemblage: VO0(?); Phase: 10; Classe: 6; MatÈriau: C25/30; Profil: 5850*150; Nom: VOILE_15CM
VOILE_15CM | Rez de chaussée | 5850*150 | VOILE_15CM | Rez de chaussée | Cage Escalier | 001 | Elément porteur | Intérieur | Type ArchiCAD | Enduit - Blanc fin | Face extérieure | yes | no | 5.36 | 5.12 | 0.6968 | 26.1021 | 24.1071 | 3.56066 | 3.29081 | 0 | 0 | 5.12 | 24.6328 | 5.295 | 5.425 | 23.5814 | 1.13785 | 3.29081 | 1 | 0 | 1 | 0 | 11.0338 | 28.4416 | 28.4416 | 3.69741 | 1.995 | 1.995 | 0.26985 | 0 | 5.12 | 0 | 5.12 | 0.369493 | 0.353721 | 0.369493 | 0.353721 | 5.295 | 2.1 | Pset_WallCommon - Reference: VO0(?); Tekla Commun - GUID: ID551A4115-0000-4174-3134-323737393933; RepËre de piËce: VO0(?); RepËre d'assemblage: VO0(?); Phase: 10; Classe: 6; MatÈriau: C25/30; Profil: 5850*150; Nom: VOILE_15CM
VOILE_15CM | Rez de chaussée | 5850*150 | VOILE_15CM | Rez de chaussée | Rangement | 005 | Elément porteur | Intérieur | Type ArchiCAD | Enduit - Blanc fin | Face extérieure | yes | no | 7.11 | 5.12 | 0.9243 | 34.522 | 34.522 | 4.65806 | 4.65806 | 0 | 0 | 5.12 | 33.9958 | 7.045 | 7.175 | 35.0482 | 1.415 | 4.65806 | 0 | 0 | 0 | 0 | 14.5338 | 37.4016 | 37.4016 | 4.86221 | 0 | 0 | 0 | 0 | 5.12 | 0 | 5.12 | 0.509937 | 0.525723 | 0.509937 | 0.525723 | 7.175 | 0 | Pset_WallCommon - Reference: VO0(?); Tekla Commun - GUID: ID551A4115-0000-41AC-3134-323737393933; RepËre de piËce: VO0(?); RepËre d'assemblage: VO0(?); Phase: 10; Classe: 6; MatÈriau: C25/30; Profil: 5850*150; Nom: VOILE_15CM
Wall_Int_02 | Rez de chaussée | Wall_Int_02 | Wall_Int_02 | Rez de chaussée | Réserve | 008 | Elément porteur | Intérieur | Type ArchiCAD | Enduit - Blanc fin | Face extérieure | yes | no | 6.25627 | 16.96 | 0.813316 | 97.5267 | 95.5317 | 13.1091 | 12.8393 | 0 | 0 | 17.425 | 95.8474 | 6.19999 | 6.31255 | 95.216 | 2.63838 | 12.8393 | 1 | 0 | 1 | 0 | 12.8145 | 108.611 | 108.707 | 14.1257 | 1.995 | 1.995 | 0.26985 | 0 | 16.96 | 0 | 16.96 | 1.43763 | 1.42832 | 1.43763 | 1.42832 | 6.19999 | 2.1
VOILE_15CM | Rez de chaussée | 6700*150 | VOILE_15CM | Rez de chaussée | Local Tech. | 008 | Elément porteur | Intérieur | Type ArchiCAD | Enduit - Blanc fin | Face extérieure | yes | no | 1.46511 | 5.12 | 0.190465 | 7.14266 | 7.14266 | 0.972098 | 0.972098 | 0 | 0 | 5.12 | 7.14353 | 1.46511 | 1.46511 | 7.14179 | 0.808119 | 0.972098 | 0 | 0 | 0 | 0 | 3.19023 | 8.16698 | 8.16698 | 1.06171 | 0 | 0 | 0 | 0 | 5.12 | 0 | 5.12 | 0.107151 | 0.107128 | 0.107151 | 0.107128 | 1.59511 | 0 | Pset_WallCommon - Reference: VO0(?); Tekla Commun - GUID: ID551A4115-0000-4236-3134-323737393933; RepËre de piËce: VO0(?); RepËre d'assemblage: VO0(?); Phase: 10; Classe: 6; MatÈriau: C25/30; Profil: 6700*150; Nom: VOILE_15CM
Wall_Int_05 | Rez de chaussée | Wall_Int_02 | Wall_Int_05 | Rez de chaussée | Garage | 004 | Elément porteur | Intérieur | Type ArchiCAD | Enduit - Blanc fin | Face extérieure | yes | no | 4.61452 | 5.12 | 0.599888 | 10.9545 | 10.9545 | 0.334184 | 0.334184 | 0 | 0 | 5.12 | 0.244751 | 4.62291 | 4.60613 | 21.6642 | 0.0699259 | 0.334184 | 0 | 0 | 0 | 0 | 9.49012 | 25.4935 | 25.5794 | 3.31974 | 0 | 0 | 0 | 0 | 5.12 | 0 | 5.12 | 0.0000518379 | 0.162642 | 0.0000518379 | 0.162642 | 4.99598 | 0
MACONNERIE_15CM | Rez de chaussée | 5000*150 | MACONNERIE_15CM | Rez de chaussée | Dégagement | 003 | Elément porteur | Intérieur | Type ArchiCAD | Enduit - Blanc fin | Face extérieure | yes | no | 1.48646 | 17.425 | 0.19324 | 23.6998 | 23.6998 | 3.82806 | 3.82806 | 0 | 0 | 17.425 | 23.6513 | 1.49078 | 1.48214 | 23.7483 | 0.227614 | 3.82806 | 0 | 0 | 0 | 0 | 3.23321 | 43.6311 | 26.6425 | 4.56778 | 0 | 0 | 0 | 0 | 17.425 | 0 | 17.425 | 0.368571 | 0.351425 | 0.368571 | 0.351425 | 1.49078 | 0 | Pset_WallCommon - Reference: MA0(?); Tekla Commun - GUID: ID551A4115-0000-E879-3134-323738313437; RepËre de piËce: MA0(?); RepËre d'assemblage: MA0(?); Phase: 10; Classe: 6; MatÈriau: MUR-BRIQUE; Profil: 5000*150; Nom: MACONNERIE_15CM
Wall_Int_05 | Rez de chaussée | Wall_Int_02 | Wall_Int_05 | Rez de chaussée | Dégagement | 003 | Elément porteur | Intérieur | Type ArchiCAD | Enduit - Blanc fin | Face extérieure | yes | no | 8.42158 | 5.12 | 1.09481 | 40.9789 | 40.9789 | 5.55665 | 5.55665 | 0 | 0 | 5.12 | 40.777 | 8.43033 | 8.41284 | 41.1808 | 1.69034 | 5.55665 | 0 | 0 | 0 | 0 | 17.1043 | 45.6503 | 45.7398 | 5.94036 | 0 | 0 | 0 | 0 | 5.12 | 0 | 5.12 | 0.61158 | 0.617787 | 0.61158 | 0.617787 | 8.80356 | 0
Wall_Int_05 | Rez de chaussée | Wall_Int_02 | Wall_Int_05 | Rez de chaussée | Dégagement | 002 | Elément porteur | Intérieur | Type ArchiCAD | Enduit - Blanc fin | Face extérieure | yes | no | 1.50439 | 5.12 | 0.195571 | 7.32692 | 5.33192 | 0.971884 | 0.702034 | 0 | 0 | 5.12 | 5.66143 | 1.57928 | 1.4295 | 5.00241 | 0.19378 | 0.702034 | 1 | 0 | 1 | 0 | 3.33694 | 8.65679 | 8.75152 | 1.13154 | 1.995 | 1.995 | 0.26985 | 0 | 5.12 | 0 | 5.12 | 0.0848431 | 0.0751146 | 0.0848431 | 0.0751146 | 1.57928 | 2.1
Wall_Int_05 | Rez de chaussée | Wall_Int_02 | Wall_Int_05 | Rez de chaussée | Dégagement | 002 | Elément porteur | Intérieur | Type ArchiCAD | Enduit - Blanc fin | Face extérieure | yes | no | 5.08536 | 5.12 | 0.661097 | 24.856 | 24.856 | 3.37518 | 3.37518 | 0 | 0 | 5.12 | 25.1856 | 5.16014 | 5.01059 | 24.5263 | 1.02715 | 3.37518 | 0 | 0 | 0 | 0 | 10.4989 | 26.3263 | 26.4199 | 3.42851 | 0 | 0 | 0 | 0 | 5.12 | 0 | 5.12 | 0.377705 | 0.367974 | 0.377705 | 0.367974 | 5.16014 | 0
Wall_Int_02 | Rez de chaussée | Wall_Int_02 | Wall_Int_02 | Rez de chaussée | Surface expoitation | 007 | Elément porteur | Intérieur | Type ArchiCAD | Enduit - Blanc fin | Face extérieure | yes | no | 3.96489 | 16.96 | 0.515435 | 62.8848 | 62.8848 | 8.36991 | 8.36991 | 0 | 0 | 17.425 | 62.8921 | 3.96546 | 3.96432 | 62.8775 | 0.399489 | 8.36991 | 0 | 0 | 0 | 0 | 8.18978 | 77.7943 | 77.8107 | 10.1143 | 0 | 0 | 0 | 0 | 16.96 | 0 | 16.96 | 0.931474 | 0.873033 | 0.931474 | 0.873033 | 4.46547 | 0
Wall_Int_06 | Rez de chaussée | Wall_Int_02 | Wall_Int_06 | Rez de chaussée |  |  | Elément porteur | Intérieur | Type ArchiCAD | Enduit - Blanc fin | Centrer | yes | no | 6.78702 | 5.12 | 0.882313 | 33.1361 | 29.9636 | 4.48951 | 4.06134 | 0 | 0 | 5.12 | 29.64 | 6.72208 | 6.85196 | 30.2872 | 1.2154 | 4.06134 | 1 | 1 | 1.5 | 0 | 13.8878 | 35.082 | 35.0827 | 4.56071 | 3.1725 | 3.1725 | 0.428175 | 0 | 5.12 | 0 | 5.12 | 0.444673 | 0.454236 | 0.444673 | 0.454236 | 6.78702 | 3.15
VOILE_15CM | Rez de chaussée | 5850*150 | VOILE_15CM | Rez de chaussée | Rangement | 004 | Elément porteur | Intérieur | Type ArchiCAD | Enduit - Blanc fin | Face extérieure | yes | no | 4.62 | 5.12 | 0.6006 | 22.3701 | 22.3701 | 3.0519 | 3.0519 | 0 | 0 | 5.12 | 22.6149 | 4.62 | 4.62 | 22.1254 | 0.93 | 3.0519 | 0 | 0 | 0 | 0 | 9.5 | 24.9856 | 24.9856 | 3.24813 | 0 | 0 | 0 | 0 | 5.12 | 0 | 5.12 | 0.339223 | 0.331881 | 0.339223 | 0.331881 | 4.62 | 0 | Pset_WallCommon - Reference: VO0(?); Tekla Commun - GUID: ID551A4115-0000-418C-3134-323737393933; RepËre de piËce: VO0(?); RepËre d'assemblage: VO0(?); Phase: 10; Classe: 6; MatÈriau: C25/30; Profil: 5850*150; Nom: VOILE_15CM
VOILE_15CM | Rez de chaussée | 6700*150 | VOILE_15CM | Rez de chaussée | Local Tech. | 008 | Elément porteur | Intérieur | Type ArchiCAD | Enduit - Blanc fin | Face extérieure | yes | no | 5.44502 | 16.96 | 0.707853 | 87.5246 | 87.5246 | 11.9611 | 11.9611 | 0 | 0 | 17.425 | 86.1462 | 5.44502 | 5.44502 | 88.9031 | 0.701526 | 11.9611 | 0 | 0 | 0 | 0 | 11.15 | 99.376 | 99.3759 | 12.9189 | 0 | 0 | 0 | 0 | 16.96 | 0 | 16.96 | 1.34214 | 1.33355 | 1.34214 | 1.33355 | 5.51002 | 0 | Pset_WallCommon - Reference: VO0(?); Tekla Commun - GUID: ID551A4115-0000-429A-3134-323737393933; RepËre de piËce: VO0(?); RepËre d'assemblage: VO0(?); Phase: 10; Classe: 6; MatÈriau: C25/30; Profil: 6700*150; Nom: VOILE_15CM
VOILE_10CM | Rez de chaussée | 5850*100 | VOILE_10CM | Rez de chaussée | Surface expoitation | 007 | Elément porteur | Intérieur | Mur | Surf-White | Face extérieure | yes | no | 1.86 | 5.11886 | 0.2418 | 8.8318 | 6.8368 | 1.24266 | 0.972805 | 0 | 0 | 5.11886 | 7.42788 | 1.925 | 1.795 | 6.24572 | 0.945986 | 0.972805 | 1 | 0 | 1 | 0 | 4.03385 | 9.8538 | 9.8538 | 1.28099 | 1.995 | 1.995 | 0.26985 | 0 | 5.11886 | 0 | 5.11886 | 0.111418 | 0.0936859 | 0.111418 | 0.0936859 | 1.875 | 2.1 | Pset_WallCommon - Reference: VO0(?); Tekla Commun - GUID: ID551A4115-0000-E719-3134-323738313437; RepËre de piËce: VO0(?); RepËre d'assemblage: VO0(?); Phase: 10; Classe: 6; MatÈriau: C25/30; Profil: 5850*100; Nom: VOILE_10CM
VOILE_10CM | Rez de chaussée | 5850*100 | VOILE_10CM | Rez de chaussée | WC | 003 | Elément porteur | Intérieur | Mur | Surf-White | Face extérieure | yes | no | 2.295 | 5.11886 | 0.29835 | 11.234 | 9.11903 | 1.51948 | 1.23403 | 0 | 0 | 5.11886 | 9.11903 | 2.295 | 2.295 | 9.11903 | 1.02074 | 1.23403 | 1 | 0 | 1 | 0 | 4.85 | 12.4132 | 12.4132 | 1.61372 | 2.115 | 2.115 | 0.28545 | 0 | 5.11886 | 0 | 5.11886 | 0.136785 | 0.136785 | 0.136785 | 0.136785 | 2.375 | 2.1 | Pset_WallCommon - Reference: VO0(?); Tekla Commun - GUID: ID551A4115-0000-E73D-3134-323738313437; RepËre de piËce: VO0(?); RepËre d'assemblage: VO0(?); Phase: 10; Classe: 6; MatÈriau: C25/30; Profil: 5850*100; Nom: VOILE_10CM
VOILE_10CM | Rez de chaussée | 5850*100 | VOILE_10CM | Rez de chaussée | WC | 002 | Elément porteur | Intérieur | Mur | Surf-White | Face extérieure | yes | no | 2.33 | 5.11886 | 0.3029 | 11.4054 | 11.4054 | 1.55021 | 1.55021 | 0 | 0 | 5.11886 | 11.4054 | 2.33 | 2.33 | 11.4054 | 0.472 | 1.55021 | 0 | 0 | 0 | 0 | 4.92 | 13.2578 | 13.2578 | 1.72352 | 0 | 0 | 0 | 0 | 5.11886 | 0 | 5.11886 | 0.17108 | 0.17108 | 0.17108 | 0.17108 | 2.54 | 0 | Pset_WallCommon - Reference: VO0(?); Tekla Commun - GUID: ID551A4115-0000-E73D-3134-323738313437; RepËre de piËce: VO0(?); RepËre d'assemblage: VO0(?); Phase: 10; Classe: 6; MatÈriau: C25/30; Profil: 5850*100; Nom: VOILE_10CM
VOILE_10CM | Rez de chaussée | 5850*100 | VOILE_10CM | Rez de chaussée |  |  | Elément porteur | Intérieur | Mur | Surf-White | Face extérieure | yes | no | 2.36 | 5.11886 | 0.3068 | 11.6519 | 11.6519 | 1.53201 | 1.53201 | 0 | 0 | 5.11886 | 11.797 | 2.425 | 2.295 | 11.5068 | 1.15694 | 1.53201 | 0 | 0 | 0 | 0 | 5.03385 | 12.4132 | 12.4132 | 1.61372 | 0 | 0 | 0 | 0 | 5.11886 | 0 | 5.11886 | 0.176954 | 0.172602 | 0.176954 | 0.172602 | 2.375 | 0 | Pset_WallCommon - Reference: VO0(?); Tekla Commun - GUID: ID551A4115-0000-E719-3134-323738313437; RepËre de piËce: VO0(?); RepËre d'assemblage: VO0(?); Phase: 10; Classe: 6; MatÈriau: C25/30; Profil: 5850*100; Nom: VOILE_10CM
VOILE_15CM | Rez de chaussée | 5850*150 | VOILE_15CM | Rez de chaussée | Rangement | 004 | Elément porteur | Intérieur | Type ArchiCAD | Enduit - Blanc fin | Face extérieure | yes | no | 4.75 | 5.12 | 0.6175 | 22.6114 | 22.6114 | 3.16154 | 3.16154 | 0 | 0 | 5.12 | 22.7617 | 4.62 | 4.88 | 22.4611 | 1.1221 | 3.16154 | 0 | 0 | 0 | 0 | 9.8677 | 24.9856 | 24.9856 | 3.24813 | 0 | 0 | 0 | 0 | 5.12 | 0 | 5.12 | 0.341426 | 0.336916 | 0.341426 | 0.336916 | 4.62 | 0 | Pset_WallCommon - Reference: VO0(?); Tekla Commun - GUID: ID551A4115-0000-4296-3134-323737393933; RepËre de piËce: VO0(?); RepËre d'assemblage: VO0(?); Phase: 10; Classe: 6; MatÈriau: C25/30; Profil: 5850*150; Nom: VOILE_15CM
VOILE_10CM | Rez de chaussée | 5850*100 | VOILE_10CM | Rez de chaussée |  |  | Elément porteur | Intérieur | Mur | Surf-White | Face extérieure | yes | no | 4.7 | 5.11886 | 0.611 | 23.0065 | 23.0065 | 3.09606 | 3.09606 | 0 | 0 | 5.11886 | 23.0065 | 4.7 | 4.7 | 23.0065 | 2.25747 | 3.09606 | 0 | 0 | 0 | 0 | 9.66 | 24.0586 | 24.0586 | 3.12762 | 0 | 0 | 0 | 0 | 5.11886 | 0 | 5.11886 | 0.345098 | 0.345098 | 0.345098 | 0.345098 | 4.7 | 0 | Pset_WallCommon - Reference: VO0(?); Tekla Commun - GUID: ID551A4115-0000-E73D-3134-323738313437; RepËre de piËce: VO0(?); RepËre d'assemblage: VO0(?); Phase: 10; Classe: 6; MatÈriau: C25/30; Profil: 5850*100; Nom: VOILE_10CM
VOILE_10CM | Rez de chaussée | 5850*100 | VOILE_10CM | Rez de chaussée | WC | 002 | Elément porteur | Intérieur | Mur | Surf-White | Face extérieure | yes | no | 2.33 | 5.11886 | 0.3029 | 11.5438 | 11.5438 | 1.55436 | 1.55436 | 0 | 0 | 5.11886 | 11.4054 | 2.33 | 2.33 | 11.6823 | 0.50695 | 1.55436 | 0 | 0 | 0 | 0 | 4.92 | 13.2578 | 13.2578 | 1.72352 | 0 | 0 | 0 | 0 | 5.11886 | 0 | 5.11886 | 0.17108 | 0.175234 | 0.17108 | 0.175234 | 2.54 | 0 | Pset_WallCommon - Reference: VO0(?); Tekla Commun - GUID: ID551A4115-0000-E73D-3134-323738313437; RepËre de piËce: VO0(?); RepËre d'assemblage: VO0(?); Phase: 10; Classe: 6; MatÈriau: C25/30; Profil: 5850*100; Nom: VOILE_10CM
VOILE_15CM | Rez de chaussée | 6700*150 | VOILE_15CM | Rez de chaussée | Ascenseur | 001 | Elément porteur | Intérieur | Type ArchiCAD | Enduit - Blanc fin | Face extérieure | yes | no | 2.2073 | 16.96 | 0.286949 | 37.4137 | 37.4137 | 4.91687 | 4.91687 | 0 | 0 | 17.425 | 37.4166 | 2.20747 | 2.20712 | 37.4107 | 0.289949 | 4.91687 | 0 | 0 | 0 | 0 | 4.67459 | 42.9896 | 42.9957 | 5.58905 | 0 | 0 | 0 | 0 | 16.96 | 0 | 16.96 | 0.561244 | 0.561166 | 0.561244 | 0.561166 | 2.46747 | 0 | Pset_WallCommon - Reference: VO0(?); Tekla Commun - GUID: ID551A4115-0000-42A2-3134-323737393933; RepËre de piËce: VO0(?); RepËre d'assemblage: VO0(?); Phase: 10; Classe: 6; MatÈriau: C25/30; Profil: 6700*150; Nom: VOILE_15CM
VOILE_15CM | Rez de chaussée | 6700*150 | VOILE_15CM | Rez de chaussée | Ascenseur | 001 | Elément porteur | Intérieur | Type ArchiCAD | Enduit - Blanc fin | Face extérieure | yes | no | 2.20684 | 16.96 | 0.286889 | 37.4059 | 37.4059 | 4.91586 | 4.91586 | 0 | 0 | 17.425 | 37.403 | 2.20667 | 2.20702 | 37.4089 | 0.289889 | 4.91586 | 0 | 0 | 0 | 0 | 4.67368 | 42.9877 | 42.9817 | 5.58801 | 0 | 0 | 0 | 0 | 16.96 | 0 | 16.96 | 0.56105 | 0.561128 | 0.56105 | 0.561128 | 2.46667 | 0 | Pset_WallCommon - Reference: VO0(?); Tekla Commun - GUID: ID551A4115-0000-429E-3134-323737393933; RepËre de piËce: VO0(?); RepËre d'assemblage: VO0(?); Phase: 10; Classe: 6; MatÈriau: C25/30; Profil: 6700*150; Nom: VOILE_15CM
VOILE_15CM | Rez de chaussée | 6700*150 | VOILE_15CM | Rez de chaussée | Dégagement | 003 | Elément porteur | Intérieur | Type ArchiCAD | Enduit - Blanc fin | Face extérieure | yes | no | 4.3457 | 18.4 | 0.56494 | 76.1789 | 54.819 | 9.7274 | 6.95061 | 0 | 0 | 18.4 | 53.7193 | 4.41501 | 4.27638 | 55.9187 | 1.09952 | 6.95061 | 4 | 0 | 8.64 | 0 | 9.00552 | 98.2393 | 81.2508 | 11.6669 | 21.3599 | 21.3599 | 2.77679 | 0 | 18.4 | 0 | 18.4 | 0.819669 | 0.838268 | 0.819669 | 0.838267 | 4.415 | 21.3599 | Pset_WallCommon - Reference: VO0(?); Tekla Commun - GUID: ID551A4115-0000-426E-3134-323737393933; RepËre de piËce: VO0(?); RepËre d'assemblage: VO0(?); Phase: 10; Classe: 6; MatÈriau: C25/30; Profil: 6700*150; Nom: VOILE_15CM
VOILE_15CM | Rez de chaussée | 6700*150 | VOILE_15CM | Rez de chaussée | Local Tech. | 007 | Elément porteur | Intérieur | Type ArchiCAD | Enduit - Blanc fin | Face extérieure | yes | no | 3.23511 | 18.4 | 0.420564 | 58.1132 | 58.1132 | 7.82141 | 7.82141 | 0 | 0 | 18.4 | 57.592 | 3.29857 | 3.17165 | 58.6344 | 0.856676 | 7.82141 | 0 | 0 | 0 | 0 | 6.78408 | 63.1424 | 63.1085 | 8.20832 | 0 | 0 | 0 | 0 | 18.4 | 0 | 18.4 | 0.867532 | 0.879517 | 0.867532 | 0.879517 | 3.4317 | 0 | Pset_WallCommon - Reference: VO0(?); Tekla Commun - GUID: ID551A4115-0000-42A6-3134-323737393933; RepËre de piËce: VO0(?); RepËre d'assemblage: VO0(?); Phase: 10; Classe: 6; MatÈriau: C25/30; Profil: 6700*150; Nom: VOILE_15CM
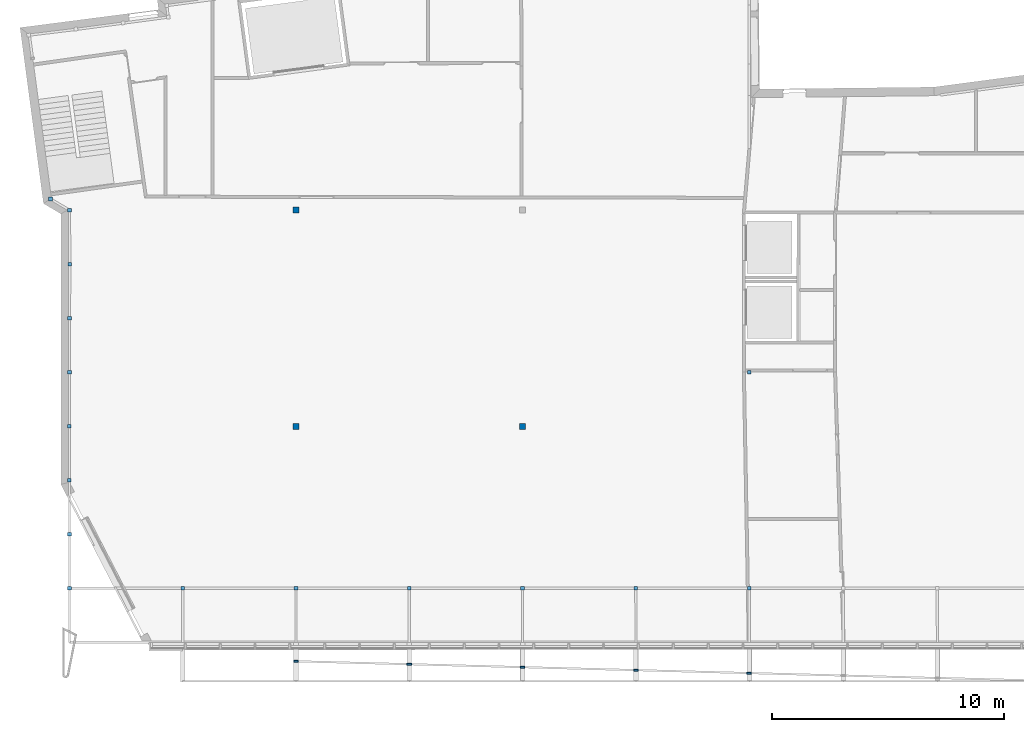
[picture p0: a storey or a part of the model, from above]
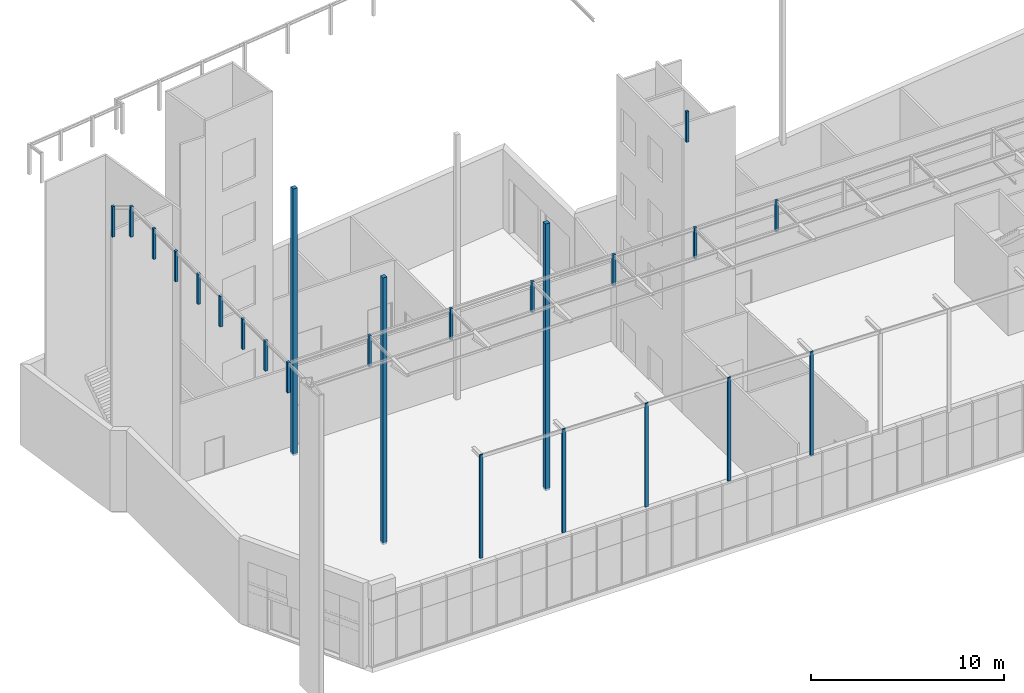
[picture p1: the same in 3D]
Properties of the parts of a building model (IFC2X3), part 15 of 19

# IfcWallStandardCase: 0.0-Cloison: parpaing + plâtre 2 faces copie 130 (138)
Name | In | Description | ID | Etage d'implantation | Nom de Zone | Numéro de Zone | Fonction structurelle | Position | Classification d'lément | Surface de face extérieure = Surface de face intérieure = Surface latérale | Emplacement de ligne de référence | LoadBearing | IsExternal | Length (m) = Longueur du Mur au centre (m) = Longueur moyenne (m) | Height (m) = Hauteur maximum du Mur (m) | GrossFootprintArea (m2) = NetFootprintArea (m2) = Superficie (m2) = Surface du Mur (m2) | GrossSideArea (m2) | NetSideArea (m2) | GrossVolume (m3) | NetVolume (m3) = Volume net (m3) | Altitude à Zéro du Projet (m) | Altitude à étage (m) = Décalage étage d'implantation (m) | Hauteur (m) | Superficie de surface (m2) = Surface de mur nette sur face extérieure (m2) = Surface conditionnelle sur face extérieure (m2) | Longueur de mur sur face extérieure (m) = Longueur conditionnelle sur face extérieure (m) | Longueur de mur sur face intérieure (m) = Longueur conditionnelle sur face intérieure (m) | Surface de mur nette sur face intérieure (m2) = Surface conditionnelle sur face intérieure (m2) | Surface nette des arêtes (m2) | Volume conditionnel (m3) | Nombre de Portes | Nombre de Poteaux | Largeur totale des Portes (m) | Hauteur minimum du Mur (m) | Périmètre du Mur (m) | Surface brute de mur sur face intérieure (m2) | Surface brute de mur sur face extérieure (m2) | Volume brut du Mur (m3) | Surface analytique des ouvertures sur face intérieure (m2) | Surface analytique des ouvertures sur face extérieure (m2) | Volume analytique des ouvertures dans le Mur (m3) | Hauteur de couche de mur minimum sur face extérieure (m) | Hauteur de couche de mur maximum sur face extérieure (m) | Hauteur de couche de mur minimum sur face intérieure (m) | Hauteur de couche de mur maximum sur face intérieure (m) | Volume de couche de mur sur face extérieure (m3) | Volume de couche de mur sur face intérieure (m3) | Volume de couche de mur conditionnelle sur face extérieure (m3) | Volume de couche de mur conditionnelle sur face intérieure (m3) | Longueur de ligne de référence (m) | Surface des portes dans le mur (m2)
VOILE_15CM | Rez de chaussée | 6700*150 | VOILE_15CM | Rez de chaussée | Plateau bureaux | 005 | Elément porteur | Intérieur | Type ArchiCAD | Enduit - Blanc fin | Face extérieure | yes | no | 4.29781 | 18.4 | 0.558716 | 76.741 | 76.741 | 10.232 | 10.232 | 0 | 0 | 18.4 | 76.5175 | 4.42777 | 4.16786 | 76.9646 | 1.11743 | 10.232 | 0 | 0 | 0 | 0 | 8.96326 | 81.4726 | 81.471 | 10.5913 | 0 | 0 | 0 | 0 | 18.4 | 0 | 18.4 | 1.17181 | 1.15447 | 1.17181 | 1.15447 | 4.41277 | 0 | Pset_WallCommon - Reference: VO0(?); Tekla Commun - GUID: ID551A4115-0000-42AA-3134-323737393933; RepËre de piËce: VO0(?); RepËre d'assemblage: VO0(?); Phase: 10; Classe: 6; MatÈriau: C25/30; Profil: 6700*150; Nom: VOILE_15CM
Wall_Int_08 | Rez de chaussée | Wall_Int_02 | Wall_Int_08 | Rez de chaussée | Local Tech. | 007 | Elément porteur | Intérieur | Type ArchiCAD | Enduit - Blanc fin | Face extérieure | yes | no | 3.30003 | 18.4 | 0.429003 | 59.0387 | 59.0387 | 7.66013 | 7.66013 | 0 | 0 | 18.4 | 59.7485 | 3.43 | 3.17005 | 58.3289 | 0.835593 | 7.66013 | 0 | 0 | 0 | 0 | 6.96771 | 63.1129 | 63.112 | 8.20462 | 0 | -7.10543e-15 | -8.88178e-15 | 0 | 18.4 | 0 | 18.4 | 0.897151 | 0.874933 | 0.897151 | 0.874933 | 3.43 | 0
MACONNERIE_15CM | Rez de chaussée | 5000*150 | MACONNERIE_15CM | Rez de chaussée | Garage | 004 | Elément porteur | Intérieur | Type ArchiCAD | Enduit - Blanc fin | Face extérieure | yes | no | 5.71034 | 5.12 | 0.742344 | 25.3405 | 21.748 | 3.54819 | 3.08658 | 0 | 0 | 5.12 | 19.3821 | 5.77551 | 5.64516 | 24.114 | 1.00507 | 3.08658 | 1 | 0 | 1.5 | 0 | 11.7346 | 30.2344 | 30.2362 | 3.93059 | 3.5925 | 3.5925 | 0.461605 | 0 | 5.12 | 0 | 5.12 | 0.142896 | 0.361711 | 0.142896 | 0.361711 | 5.77551 | 3.75 | Pset_WallCommon - Reference: MA0(?); Tekla Commun - GUID: ID551A4115-0000-E861-3134-323738313437; RepËre de piËce: MA0(?); RepËre d'assemblage: MA0(?); Phase: 10; Classe: 6; MatÈriau: MUR-BRIQUE; Profil: 5000*150; Nom: MACONNERIE_15CM
Wall_Int_06 | Rez de chaussée | Wall_Int_02 | Wall_Int_06 | Rez de chaussée | Réserve | 008 | Elément porteur | Intérieur | Type ArchiCAD | Enduit - Blanc fin | Face extérieure | yes | no | 25.7264 | 5.12 | 3.34443 | 124.989 | 118.678 | 16.9551 | 16.1064 | 0 | 0 | 5.12 | 117.977 | 25.6755 | 25.7772 | 119.379 | 4.88839 | 16.1064 | 2 | 0 | 2.7 | 0 | 51.7552 | 132.647 | 132.799 | 17.254 | 6.3105 | 6.3105 | 0.848715 | 0 | 5.12 | 0 | 5.12 | 1.76953 | 1.79082 | 1.76953 | 1.79082 | 25.6755 | 6.27
Wall_Int_06 | Rez de chaussée | Wall_Int_02 | Wall_Int_06 | Rez de chaussée | Garage | 004 | Elément porteur | Intérieur | Type ArchiCAD | Enduit - Blanc fin | Face extérieure | yes | no | 4.98095 | 5.12 | 0.647524 | 24.1896 | 22.1946 | 3.25031 | 2.98046 | 0 | 0 | 5.12 | 22.3435 | 5.05177 | 4.91014 | 22.0457 | 1.56846 | 2.98046 | 1 | 0 | 1 | 0 | 10.2842 | 25.808 | 25.865 | 3.35874 | 1.995 | 1.995 | 0.26985 | 0 | 5.12 | 0 | 5.12 | 0.33514 | 0.330766 | 0.33514 | 0.330766 | 4.98653 | 2.1
Wall_Int_SEC_01 | Rez de chaussée | Wall_Int_02 | Wall_Int_SEC_01 | Rez de chaussée | Dégagement | 003 | Elément porteur | Intérieur | Type ArchiCAD | Enduit - Blanc fin | Face extérieure | yes | no | 4.94319 | 5.12 | 0.642614 | 23.9514 | 18.9811 | 3.26487 | 2.59406 | 0 | 0 | 5.12 | 19.223 | 4.94244 | 4.94394 | 18.7393 | 0.759659 | 2.59406 | 1 | 0 | 2.35 | 0 | 10.1473 | 27.8829 | 27.8752 | 3.62428 | 4.97025 | 4.97025 | 0.670808 | 0 | 5.12 | 0 | 5.12 | 0.288351 | 0.281083 | 0.288351 | 0.281083 | 5.37917 | 4.935
Wall_Int_SEC_01 | Rez de chaussée | Wall_Int_02 | Wall_Int_SEC_01 | Rez de chaussée | Réserve | 010 | Elément porteur | Intérieur | Type ArchiCAD | Enduit - Blanc fin | Face extérieure | yes | no | 4.10616 | 5.12 | 0.533801 | 20.0997 | 20.0997 | 2.72077 | 2.72077 | 0 | 0 | 5.12 | 20.0574 | 4.09752 | 4.1148 | 20.1419 | 0.827258 | 2.72077 | 0 | 0 | 0 | 0 | 8.47346 | 23.6444 | 23.556 | 3.06803 | 0 | 0 | 0 | 0 | 5.12 | 0 | 5.12 | 0.300934 | 0.302056 | 0.300934 | 0.302056 | 4.53578 | 0
Wall_Int_SEC_01 | Rez de chaussée | Wall_Int_02 | Wall_Int_SEC_01 | Rez de chaussée | Réserve | 009 | Elément porteur | Intérieur | Type ArchiCAD | Enduit - Blanc fin | Face extérieure | yes | no | 3.42297 | 5.12 | 0.444987 | 16.7555 | 16.7555 | 2.27065 | 2.27065 | 0 | 0 | 5.12 | 16.7132 | 3.41434 | 3.43161 | 16.7977 | 0.690621 | 2.27065 | 0 | 0 | 0 | 0 | 7.10709 | 20.1465 | 20.0581 | 2.6133 | 0 | 0 | 0 | 0 | 5.12 | 0 | 5.12 | 0.250771 | 0.251893 | 0.250771 | 0.251893 | 3.85259 | 0
VOILE_15CM | Rez de chaussée | 5850*150 | VOILE_15CM | Rez de chaussée | Dégagement | 001 | Elément porteur | Intérieur | Type ArchiCAD | Enduit - Blanc fin | Face extérieure | yes | no | 7.09294 | 5.12 | 0.922082 | 34.3348 | 32.3398 | 4.67598 | 4.40613 | 0 | 0 | 5.12 | 31.9519 | 7.09237 | 7.09351 | 32.7277 | 1.32476 | 4.40613 | 1 | 0 | 1 | 0 | 14.4459 | 38.8788 | 38.873 | 5.05386 | 1.995 | 1.995 | 0.26985 | 0 | 5.12 | 0 | 5.12 | 0.478276 | 0.490911 | 0.478276 | 0.490911 | 7.52738 | 2.1 | Pset_WallCommon - Reference: VO0(?); Tekla Commun - GUID: ID551A4115-0000-E6DD-3134-323738313437; RepËre de piËce: VO0(?); RepËre d'assemblage: VO0(?); Phase: 10; Classe: 6; MatÈriau: C25/30; Profil: 5850*150; Nom: VOILE_15CM
Wall_Int | R+1 | Wall_Int_02 | Wall_Int | R+1 | WC | 004 | Elément porteur | Intérieur | Type ArchiCAD | Enduit - Blanc fin | Face extérieure | yes | no | 4.62 | 3.825 | 0.6006 | 17.0918 | 17.0918 | 2.29138 | 2.29138 | 5.3 | -0.1 | 3.825 | 17.2788 | 4.62 | 4.62 | 16.9048 | 1.0671 | 2.29138 | 0 | 0 | 0 | 0 | 9.5 | 18.666 | 18.666 | 2.42658 | 0 | 0 | 0 | 0 | 3.825 | 0 | 3.825 | 0.259182 | 0.253572 | 0.259182 | 0.253572 | 4.62 | 0
Wall_Int_02 | R+1 | Wall_Int_02 | Wall_Int_02 | R+1 | Dégagement | 001 | Elément porteur | Intérieur | Type ArchiCAD | Enduit - Blanc fin | Face extérieure | yes | no | 2.60376 | 3.825 | 0.338489 | 9.73807 | 7.72309 | 1.29956 | 1.02911 | 5.3 | -0.1 | 4.05 | 7.72283 | 2.60369 | 2.60384 | 7.72334 | 0.163376 | 1.02911 | 1 | 0 | 1 | 0 | 5.46753 | 12.5705 | 12.5699 | 1.63413 | 2.015 | 2.01497 | 0.27045 | 0 | 3.825 | 0 | 3.825 | 0.115843 | 0.11585 | 0.115843 | 0.11585 | 2.97369 | 2.1
Wall_Int_02 | R+1 | Wall_Int_02 | Wall_Int_02 | R+1 |  |  | Elément porteur | Intérieur | Type ArchiCAD | 03 / Concrete Light | Face extérieure | yes | no | 0.397622 | 3.825 | 0.0516909 | 1.51516 | 1.51516 | 0.21667 | 0.21667 | 5.3 | -0.1 | 4.05 | 1.29897 | 0.332317 | 0.462927 | 1.73135 | 0.539462 | 0.21667 | 0 | 0 | 0 | 0 | 1.10952 | 1.87485 | 1.87239 | 0.243571 | 0 | 0 | 0 | 0 | 3.825 | 0 | 3.825 | 0.0194865 | 0.0259682 | 0.0194865 | 0.0259682 | 0.332317 | 0
VOILE_10CM | R+1 | Wall_Int_05 | VOILE_10CM | R+1 | WC | 002 | Elément porteur | Intérieur | Mur | Surf-White | Face extérieure | yes | no | 2.33 | 3.825 | 0.3029 | 8.7142 | 8.7142 | 1.16413 | 1.16413 | 5.3 | -0.1 | 3.885 | 8.7142 | 2.33 | 2.33 | 8.7142 | 0.236 | 1.16413 | 0 | 0 | 0 | 0 | 4.92 | 10.0622 | 10.0622 | 1.30808 | 0 | 0 | 0 | 0 | 3.825 | 0 | 3.825 | 0.130713 | 0.130713 | 0.130713 | 0.130713 | 2.54 | 0
Wall_Int | R+1 | Wall_Int_05 | Wall_Int | R+1 |  |  | Elément porteur | Intérieur | Mur | Surf-White | Face extérieure | yes | no | 4.7 | 3.825 | 0.611 | 17.578 | 17.578 | 2.32509 | 2.32509 | 5.3 | -0.1 | 3.885 | 17.578 | 4.7 | 4.7 | 17.578 | 1.4594 | 2.32509 | 0 | 0 | 0 | 0 | 9.66 | 18.2595 | 18.2595 | 2.37373 | 0 | 0 | 0 | 0 | 3.825 | 0 | 3.825 | 0.26367 | 0.26367 | 0.26367 | 0.26367 | 4.7 | 0
Wall_Int_02 | R+1 | Wall_Int_02 | Wall_Int_02 | R+1 | WC | 006 | Elément porteur | Intérieur | Type ArchiCAD | Enduit - Blanc fin | Face extérieure | yes | no | 9.75 | 3.825 | 1.2675 | 35.9428 | 28.5403 | 4.84591 | 3.85383 | 5.3 | -0.1 | 3.825 | 27.5319 | 9.62 | 9.88 | 29.5487 | 2.02088 | 3.85383 | 3 | 0 | 3.5 | 0 | 19.8677 | 37.791 | 37.791 | 4.91283 | 7.4025 | 7.4025 | 0.992075 | 0 | 3.825 | 0 | 3.825 | 0.412978 | 0.443231 | 0.412978 | 0.443231 | 9.75 | 7.35
VOILE_10CM | R+1 | Wall_Int_05 | VOILE_10CM | R+1 | Plateau bureaux | 005 | Elément porteur | Intérieur | Mur | Surf-White | Face extérieure | yes | no | 2.855 | 3.825 | 0.37115 | 10.3411 | 8.2661 | 1.38315 | 1.1049 | 5.3 | -0.1 | 3.885 | 8.7897 | 2.92 | 2.79 | 7.7425 | 0.6191 | 1.1049 | 1 | 0 | 1 | 0 | 6.02385 | 11.3442 | 11.3442 | 1.47475 | 2.075 | 2.075 | 0.27825 | 0 | 3.825 | 0 | 3.825 | 0.131845 | 0.116137 | 0.131845 | 0.116137 | 2.87 | 2.1
VOILE_10CM | R+1 | Wall_Int_05 | VOILE_10CM | R+1 | Plateau bureaux | 005 | Elément porteur | Intérieur | Mur | Surf-White | Face extérieure | yes | no | 2.34647 | 3.825 | 0.305041 | 8.80384 | 6.68884 | 1.18076 | 0.897314 | 5.3 | -0.1 | 3.885 | 6.90389 | 2.41147 | 2.28147 | 6.47379 | 0.690447 | 0.897314 | 1 | 0 | 1 | 0 | 5.00678 | 9.36855 | 9.36855 | 1.21791 | 2.115 | 2.115 | 0.28345 | 0 | 3.825 | 0 | 3.825 | 0.103558 | 0.0971068 | 0.103558 | 0.0971068 | 2.36147 | 2.1
Wall_Int | R+1 | Wall_Int_02 | Wall_Int | R+1 | Dégagement | 001 | Elément porteur | Intérieur | Type ArchiCAD | Enduit - Blanc fin | Face extérieure | yes | no | 1.845 | 3.825 | 0.23985 | 6.9003 | 6.9003 | 0.924197 | 0.924197 | 5.3 | -0.1 | 3.825 | 6.9003 | 1.845 | 1.845 | 6.9003 | 0.43035 | 0.924197 | 0 | 0 | 0 | 0 | 3.95 | 8.05163 | 8.05163 | 1.04671 | 0 | 0 | 0 | 0 | 3.825 | 0 | 3.825 | 0.103505 | 0.103505 | 0.103505 | 0.103505 | 1.845 | 0
Wall_Int_02 | R+1 | Wall_Int_02 | Wall_Int_02 | R+1 | Dégagement | 001 | Elément porteur | Intérieur | Type ArchiCAD | Enduit - Blanc fin | Face extérieure | yes | no | 7.13162 | 4.05 | 0.927111 | 26.9393 | 24.8243 | 3.52179 | 3.23835 | 5.3 | -0.1 | 4.05 | 24.9031 | 7.06627 | 7.19697 | 24.7456 | 0.670146 | 3.23834 | 1 | 0 | 1 | 0 | 14.5775 | 30.6462 | 30.6434 | 3.98383 | 2.115 | 2.115 | 0.283437 | 0 | 4.05 | 0 | 3.825 | 0.372712 | 0.371181 | 0.372699 | 0.371181 | 7.43627 | 2.1
Wall_Int_02 | R+1 | Wall_Int_02 | Wall_Int_02 | R+1 | WC | 006 | Elément porteur | Intérieur | Type ArchiCAD | Enduit - Blanc fin | Face extérieure | yes | no | 5.32638 | 3.825 | 0.692429 | 19.7336 | 17.6186 | 2.64082 | 2.35737 | 5.3 | -0.1 | 3.825 | 17.4316 | 5.32638 | 5.32638 | 17.8056 | 1.12957 | 2.35737 | 1 | 0 | 1 | 0 | 10.9128 | 21.3679 | 21.3679 | 2.77783 | 2.115 | 2.115 | 0.28345 | 0 | 3.825 | 0 | 3.825 | 0.261475 | 0.267085 | 0.261475 | 0.267085 | 5.58638 | 2.1
Wall_Int_02 | R+1 | Wall_Int_02 | Wall_Int_02 | R+1 |  |  | Elément porteur | Intérieur | Type ArchiCAD | Enduit - Blanc fin | Face extérieure | yes | no | 3.98058 | 3.725 | 0.517475 | 7.53607 | 7.53607 | 0.0341232 | 0.0341232 | 5.4 | 0 | 3.95 | 9.60355 | 3.91614 | 4.04501 | 5.46858 | 0.0091606 | 0.0341232 | 0 | 0 | 0 | 0 | 8.2751 | 17.4393 | 17.4438 | 2.26741 | 0 | 0 | 0 | 0 | 3.725 | 0 | 3.725 | 0.0128279 | 0.00415955 | 0.0128279 | 0.00415955 | 4.41616 | 0
Wall_Int_02 | R+1 | Wall_Int_02 | Wall_Int_02 | R+1 | Plateau bureaux | 005 | Elément porteur | Intérieur | Type ArchiCAD | Enduit - Blanc fin | Face extérieure | yes | no | 4.02993 | 3.725 | 0.523891 | 14.7694 | 14.7694 | 1.93119 | 1.93119 | 5.4 | 0 | 3.95 | 14.7715 | 4.0955 | 3.96436 | 14.7673 | 0.518441 | 1.93119 | 0 | 0 | 0 | 0 | 8.37378 | 17.6343 | 17.6388 | 2.29275 | 0 | 0 | 0 | 0 | 3.725 | 0 | 3.725 | 0.221569 | 0.221513 | 0.221569 | 0.221513 | 4.46551 | 0
Wall_Int_02 | R+1 | Wall_Int_02 | Wall_Int_02 | R+1 | Plateau bureaux | 005 | Elément porteur | Intérieur | Type ArchiCAD | Enduit - Blanc fin | Face extérieure | yes | no | 5.64582 | 3.95 | 0.733956 | 0 | 0 | 0 | 0 | 5.4 | 0 | 3.95 | 0 | 5.77593 | 5.51571 | 0 | 0 | 0 | 1 | 0 | 1 | 3.95 | 11.6595 | 22.3014 | 22.3014 | 2.89918 | 0 | 0 | 0 | 3.95 | 3.95 | 3.95 | 3.95 | 0 | 0 | 0 | 0 | 5.64593 | 2.1
Wall_Int_02 | R+1 | Wall_Int_02 | Wall_Int_02 | R+1 |  |  | Elément porteur | Intérieur | Type ArchiCAD | Enduit - Blanc fin | Face extérieure | yes | no | 2.575 | 3.825 | 0.33475 | 9.67619 | 9.67619 | 1.23394 | 1.23394 | 5.3 | -0.1 | 3.825 | 9.34787 | 2.445 | 2.705 | 10.0045 | 0.572042 | 1.23394 | 0 | 0 | 0 | 0 | 5.5177 | 10.3466 | 10.3466 | 1.34506 | 0 | 0 | 0 | 0 | 3.825 | 0 | 3.825 | 0.137185 | 0.150067 | 0.137185 | 0.150067 | 2.575 | 0
Wall_Int_02 | R+1 | Wall_Int_02 | Wall_Int_02 | R+1 | Plateau bureaux | 005 | Elément porteur | Intérieur | Type ArchiCAD | Enduit - Blanc fin | Face extérieure | yes | no | 5.42475 | 3.825 | 0.705218 | 20.2886 | 20.2886 | 2.68363 | 2.68363 | 5.3 | -0.1 | 3.825 | 20.7187 | 5.55475 | 5.29476 | 19.8585 | 1.24769 | 2.68363 | 0 | 0 | 0 | 0 | 11.2172 | 21.247 | 21.2469 | 2.7621 | 0 | 0 | 0 | 0 | 3.825 | 0 | 3.825 | 0.31078 | 0.297877 | 0.31078 | 0.297877 | 5.29475 | 0
Wall_Int_02 | R+1 | Wall_Int_02 | Wall_Int_02 | R+1 |  |  | Elément porteur | Intérieur | Type ArchiCAD | Enduit - Blanc fin | Face extérieure | yes | no | 5.35997 | 3.825 | 0.696796 | 19.9254 | 17.8679 | 2.67281 | 2.40109 | 5.3 | -0.1 | 3.825 | 18.2093 | 5.29497 | 5.42498 | 17.5264 | 1.26354 | 2.40109 | 1 | 0 | 1 | 0 | 11.0338 | 21.2478 | 21.2477 | 2.76221 | 2.015 | 2.1 | 0.271725 | 0 | 3.825 | 0 | 3.825 | 0.27314 | 0.262896 | 0.27314 | 0.262896 | 5.29497 | 2.1
Wall_Int_02 | R+1 | Wall_Int_02 | Wall_Int_02 | R+1 | WC | 005 | Elément porteur | Intérieur | Type ArchiCAD | Enduit - Blanc fin | Face extérieure | yes | no | 7.11 | 3.825 | 0.9243 | 26.3764 | 26.3764 | 3.49748 | 3.49748 | 5.3 | -0.1 | 3.825 | 25.9743 | 7.045 | 7.175 | 26.7784 | 1.62658 | 3.49748 | 0 | 0 | 0 | 0 | 14.5338 | 27.9416 | 27.9416 | 3.63241 | 0 | 0 | 0 | 0 | 3.825 | 0 | 3.825 | 0.389615 | 0.401676 | 0.389615 | 0.401676 | 7.175 | 0
Wall_Int_02 | R+1 | Wall_Int_02 | Wall_Int_02 | R+1 | Local Tech. | 008 | Elément porteur | Intérieur | Mur | Enduit - Blanc fin | Face extérieure | yes | no | 1.46497 | 3.725 | 0.190446 | 5.43517 | 5.43517 | 0.714345 | 0.714345 | 5.4 | 0 | 3.725 | 5.43582 | 1.46497 | 1.46497 | 5.43452 | 0.756041 | 0.714345 | 0 | 0 | 0 | 0 | 3.18994 | 5.94127 | 5.94127 | 0.772365 | 0 | 0 | 0 | 0 | 3.725 | 0 | 3.725 | 0.0815362 | 0.0815189 | 0.0815362 | 0.0815189 | 1.59497 | 0
Wall_Int_02 | R+1 | Wall_Int_02 | Wall_Int_02 | R+1 | Plateau bureaux | 005 | Elément porteur | Intérieur | Mur | Enduit - Blanc fin | Face extérieure | yes | no | 6.78015 | 3.825 | 0.881419 | 24.9845 | 18.8596 | 3.34294 | 2.52209 | 5.3 | -0.1 | 3.825 | 19.663 | 6.91015 | 6.65015 | 18.0563 | 1.32294 | 2.52209 | 2 | 0 | 2.89592 | 0 | 13.928 | 26.4313 | 26.4313 | 3.43607 | 6.12487 | 6.12487 | 0.820848 | 0 | 3.825 | 0 | 3.825 | 0.294945 | 0.270844 | 0.294945 | 0.270844 | 6.84515 | 6.08143
VOILE_10CM | R+1 | Wall_Int_05 | VOILE_10CM | R+1 | Plateau bureaux | 005 | Elément porteur | Intérieur | Mur | Surf-White | Face extérieure | yes | no | 2.345 | 3.885 | 0.30485 | 8.90755 | 8.90755 | 1.14506 | 1.14506 | 5.3 | -0.1 | 3.885 | 8.9573 | 2.41 | 2.28 | 8.8578 | 0.794775 | 1.14506 | 0 | 0 | 0 | 0 | 5.00385 | 9.36285 | 9.36285 | 1.21717 | 0 | 0 | 0 | 0 | 3.825 | 0 | 3.885 | 0.134359 | 0.132867 | 0.134359 | 0.132867 | 2.36 | 0
VOILE_10CM | R+1 | Wall_Int_05 | VOILE_10CM | R+1 | WC | 002 | Elément porteur | Intérieur | Mur | Surf-White | Face extérieure | yes | no | 2.33 | 3.885 | 0.3029 | 8.88207 | 8.88207 | 1.16916 | 1.16916 | 5.3 | -0.1 | 3.885 | 8.7142 | 2.33 | 2.33 | 9.04995 | 0.305375 | 1.16916 | 0 | 0 | 0 | 0 | 4.92 | 10.0622 | 10.0622 | 1.30808 | 0 | 0 | 0 | 0 | 3.825 | 0 | 3.885 | 0.130713 | 0.135749 | 0.130713 | 0.135749 | 2.54 | 0
Wall_Int_05 | R+1 | Wall_Int_05 | Wall_Int_05 | R+1 | Plateau bureaux | 005 | Elément porteur | Intérieur | Mur | Surf-White | Face extérieure | yes | no | 1.86 | 3.885 | 0.2418 | 6.75738 | 4.74238 | 0.933611 | 0.663161 | 5.3 | -0.1 | 3.885 | 5.1845 | 1.925 | 1.795 | 4.30025 | 0.60145 | 0.663161 | 1 | 0 | 1 | 0 | 4.03385 | 7.47863 | 7.47863 | 0.972221 | 2.015 | 2.015 | 0.27045 | 0 | 3.825 | 0 | 3.885 | 0.0777675 | 0.0645038 | 0.0777675 | 0.0645038 | 1.875 | 2.1
Wall_Int_07 | R+1 | Wall_Int_05 | Wall_Int_07 | R+1 | WC | 003 | Elément porteur | Intérieur | Mur | Surf-White | Face extérieure | yes | no | 2.33 | 3.825 | 0.3029 | 8.7142 | 8.7142 | 1.16413 | 1.16413 | 5.3 | -0.1 | 3.885 | 8.7142 | 2.33 | 2.33 | 8.7142 | 0.236 | 1.16413 | 0 | 0 | 0 | 0 | 4.92 | 10.0622 | 10.0622 | 1.30808 | 0 | 0 | 0 | 0 | 3.825 | 0 | 3.825 | 0.130713 | 0.130713 | 0.130713 | 0.130713 | 2.54 | 0
Wall_Int_07 | R+1 | Wall_Int_02 | Wall_Int_07 | R+1 | WC | 004 | Elément porteur | Intérieur | Type ArchiCAD | Enduit - Blanc fin | Face extérieure | yes | no | 4.75 | 3.825 | 0.6175 | 17.2189 | 17.2189 | 2.33344 | 2.33344 | 5.3 | -0.1 | 3.825 | 17.3349 | 4.62 | 4.88 | 17.1029 | 1.14935 | 2.33344 | 0 | 0 | 0 | 0 | 9.8677 | 18.666 | 18.666 | 2.42658 | 0 | 0 | 0 | 0 | 3.825 | 0 | 3.825 | 0.260024 | 0.256543 | 0.260024 | 0.256543 | 4.62 | 0
Wall_Int_02 | R+1 | Wall_Int_02 | Wall_Int_02 | R+1 |  |  | Elément porteur | Intérieur | Type ArchiCAD | Enduit - Blanc fin | Face extérieure | yes | no | 3.92497 | 3.825 | 0.510246 | 14.6794 | 11.5069 | 1.94168 | 1.51651 | 5.3 | -0.1 | 3.825 | 11.937 | 4.05497 | 3.79497 | 11.0768 | 0.808843 | 1.51651 | 1 | 0 | 1.5 | 0 | 8.21763 | 15.5103 | 15.5103 | 2.01633 | 3.1725 | 3.1725 | 0.425175 | 0 | 3.825 | 0 | 3.825 | 0.179055 | 0.166152 | 0.179055 | 0.166152 | 4.05497 | 3.15
Wall_Int_07 | Mezzannine | Wall_Int_02 | Wall_Int_07 | Mezzannine | WC | 004 | Elément porteur | Intérieur | Type ArchiCAD | Enduit - Blanc fin | Face extérieure | yes | no | 4.75 | 3.845 | 0.6175 | 17.3213 | 17.3213 | 2.34601 | 2.34601 | 9.305 | -0.12 | 3.845 | 17.2654 | 4.62 | 4.88 | 17.3771 | 1.14538 | 2.34601 | 0 | 0 | 0 | 0 | 9.8677 | 18.7636 | 18.7636 | 2.43927 | 0 | 0 | 0 | 0 | 3.845 | 0 | 3.845 | 0.258981 | 0.260657 | 0.258981 | 0.260657 | 4.62 | 0
Wall_Int_02 | Mezzannine | Wall_Int_02 | Wall_Int_02 | Mezzannine |  |  | Elément porteur | Intérieur | Type ArchiCAD | 03 / Concrete Light | Face extérieure | yes | no | 0.398234 | 3.845 | 0.0517704 | 1.51136 | 1.51136 | 0.217689 | 0.217689 | 9.305 | -0.12 | 4.07 | 1.29354 | 0.332258 | 0.464209 | 1.72918 | 0.541074 | 0.217689 | 0 | 0 | 0 | 0 | 1.1117 | 1.88933 | 1.88145 | 0.245101 | 0 | 0 | 0 | 0 | 3.845 | 0 | 3.845 | 0.0194094 | 0.0259315 | 0.0194094 | 0.0259315 | 0.332258 | 0
Wall_Int_02 | Mezzannine | Wall_Int_02 | Wall_Int_02 | Mezzannine | WC | 006 | Elément porteur | Intérieur | Type ArchiCAD | Enduit - Blanc fin | Face extérieure | yes | no | 9.75 | 3.845 | 1.2675 | 35.8159 | 28.4659 | 4.8618 | 3.8643 | 9.305 | -0.12 | 3.845 | 27.4788 | 9.62 | 9.88 | 29.453 | 2.0202 | 3.8643 | 3 | 0 | 3.5 | 0 | 19.8677 | 37.9886 | 37.9886 | 4.93852 | 7.35 | 7.35 | 0.9975 | 0 | 3.845 | 0 | 3.845 | 0.412181 | 0.441795 | 0.412181 | 0.441795 | 9.75 | 7.35
Wall_Int_02 | Mezzannine | Wall_Int_02 | Wall_Int_02 | Mezzannine |  |  | Elément porteur | Intérieur | Type ArchiCAD | Enduit - Blanc fin | Face extérieure | yes | no | 3.98058 | 3.95 | 0.517475 | 7.53607 | 7.53607 | 0.034421 | 0.034421 | 9.425 | 0 | 3.95 | 9.39579 | 3.91614 | 4.04501 | 5.67634 | 0.0092841 | 0.034421 | 0 | 0 | 0 | 0 | 8.2751 | 17.4396 | 17.4438 | 2.26743 | 0 | 0 | 0 | 0 | 3.95 | 0 | 3.725 | 0.0125504 | 0.00458071 | 0.0125504 | 0.00458071 | 4.41616 | 0
Wall_Int_02 | Mezzannine | Wall_Int_02 | Wall_Int_02 | Mezzannine | Plateau bureaux | 005 | Elément porteur | Intérieur | Mur | Enduit - Blanc fin | Face extérieure | yes | no | 3.95997 | 3.845 | 0.514796 | 14.723 | 11.573 | 1.94507 | 1.51757 | 9.305 | -0.12 | 3.845 | 11.7871 | 4.02497 | 3.89497 | 11.3588 | 1.24682 | 1.51757 | 1 | 0 | 1.5 | 0 | 8.23379 | 15.476 | 15.476 | 2.01188 | 3.15 | 3.15 | 0.4275 | 0 | 3.845 | 0 | 3.845 | 0.176807 | 0.170382 | 0.176807 | 0.170382 | 4.02497 | 3.15
Wall_Int_02 | Mezzannine | Wall_Int_02 | Wall_Int_02 | Mezzannine | Cafetaria | 007 | Elément porteur | Intérieur | Type ArchiCAD | Enduit - Blanc fin | Face extérieure | yes | no | 5.64591 | 3.95 | 0.733968 | 0 | 0 | 0 | 0 | 9.425 | 0 | 3.95 | 0 | 5.77602 | 5.5158 | 0 | 0 | 0 | 1 | 0 | 1 | 3.95 | 11.6597 | 22.3018 | 22.3018 | 2.89923 | 0 | 0 | 0 | 3.95 | 3.95 | 3.95 | 3.95 | 0 | 0 | 0 | 0 | 5.64602 | 2.1
Wall_Int_05 | Mezzannine | Wall_Int_05 | Wall_Int_05 | Mezzannine | Plateau bureaux | 005 | Elément porteur | Intérieur | Mur | Surf-White | Face extérieure | yes | no | 1.86 | 3.725 | 0.2418 | 6.64912 | 4.54913 | 0.873699 | 0.600699 | 9.425 | 0 | 3.725 | 5.01475 | 1.925 | 1.795 | 4.0835 | 0.767475 | 0.600699 | 1 | 0 | 1 | 0 | 4.03385 | 7.17063 | 7.17063 | 0.932181 | 2.1 | 2.1 | 0.273 | 0 | 3.725 | 0 | 3.725 | 0.0752213 | 0.0612525 | 0.0752213 | 0.0612525 | 1.875 | 2.1
Wall_Int_07 | Mezzannine | Wall_Int_07 | Wall_Int_07 | Mezzannine | WC | 002 | Elément porteur | Intérieur | Mur | Surf-White | Face extérieure | yes | no | 2.33 | 3.785 | 0.3029 | 8.67925 | 8.67925 | 1.15364 | 1.15364 | 9.365 | -0.06 | 3.785 | 8.67925 | 2.33 | 2.33 | 8.67925 | 0.5419 | 1.15364 | 0 | 0 | 0 | 0 | 4.92 | 9.80315 | 9.80315 | 1.27441 | 0 | 0 | 0 | 0 | 3.785 | 0 | 3.785 | 0.130189 | 0.130189 | 0.130189 | 0.130189 | 2.54 | 0
Wall_Int_07 | Mezzannine | Wall_Int_07 | Wall_Int_07 | Mezzannine | WC | 002 | Elément porteur | Intérieur | Mur | Surf-White | Face extérieure | yes | no | 2.445 | 3.785 | 0.31785 | 9.17737 | 9.17737 | 1.20682 | 1.20682 | 9.365 | -0.06 | 3.785 | 9.10763 | 2.445 | 2.445 | 9.24713 | 1.09698 | 1.20682 | 0 | 0 | 0 | 0 | 5.15 | 9.74338 | 9.74338 | 1.26664 | 0 | 0 | 0 | 3.55271e-15 | 3.785 | 0 | 3.785 | 0.136614 | 0.138707 | 0.136614 | 0.138707 | 2.525 | 0
Wall_Int_07 | Mezzannine | Wall_Int_07 | Wall_Int_07 | Mezzannine | WC | 003 | Elément porteur | Intérieur | Mur | Surf-White | Face extérieure | yes | no | 2.33 | 3.785 | 0.3029 | 8.67925 | 8.67925 | 1.15364 | 1.15364 | 9.365 | -0.06 | 3.785 | 8.67925 | 2.33 | 2.33 | 8.67925 | 0.5419 | 1.15364 | 0 | 0 | 0 | 0 | 4.92 | 9.80315 | 9.80315 | 1.27441 | 0 | 0 | 0 | 0 | 3.785 | 0 | 3.785 | 0.130189 | 0.130189 | 0.130189 | 0.130189 | 2.54 | 0
Wall_Int_05 | Mezzannine | Wall_Int_05 | Wall_Int_05 | Mezzannine | Plateau bureaux | 005 | Elément porteur | Intérieur | Mur | Surf-White | Face extérieure | yes | no | 2.36 | 3.785 | 0.3068 | 8.88869 | 8.88869 | 1.17864 | 1.17864 | 9.365 | -0.06 | 3.785 | 9.03313 | 2.425 | 2.295 | 8.74425 | 1.13142 | 1.17864 | 0 | 0 | 0 | 0 | 5.03385 | 9.17563 | 9.17563 | 1.19283 | 0 | 0 | 0 | 1.77636e-15 | 3.785 | 0 | 3.785 | 0.135497 | 0.131164 | 0.135497 | 0.131164 | 2.375 | 0
Wall_Int | Mezzannine | Wall_Int_02 | Wall_Int | Mezzannine | WC | 004 | Elément porteur | Intérieur | Type ArchiCAD | Enduit - Blanc fin | Face extérieure | yes | no | 4.62 | 3.845 | 0.6006 | 17.0233 | 17.0233 | 2.29862 | 2.29862 | 9.305 | -0.12 | 3.845 | 17.2095 | 4.62 | 4.62 | 16.837 | 1.0671 | 2.29862 | 0 | 0 | 0 | 0 | 9.5 | 18.7636 | 18.7636 | 2.43927 | 0 | 0 | 0 | 0 | 3.845 | 0 | 3.845 | 0.258143 | 0.252555 | 0.258143 | 0.252555 | 4.62 | 0
Wall_Int | Mezzannine | Wall_Int_02 | Wall_Int | Mezzannine | Dégagement | 001 | Elément porteur | Intérieur | Type ArchiCAD | Enduit - Blanc fin | Face extérieure | yes | no | 1.86 | 3.845 | 0.2418 | 6.87263 | 6.87263 | 0.927116 | 0.927116 | 9.305 | -0.12 | 3.845 | 6.87263 | 1.86 | 1.86 | 6.87263 | 0.81485 | 0.927116 | 0 | 0 | 0 | 0 | 3.98 | 7.65155 | 7.65155 | 0.994702 | 0 | 0 | 0 | 0 | 3.845 | 0 | 3.845 | 0.103089 | 0.103089 | 0.103089 | 0.103089 | 1.86 | 0
Wall_Int_02 | Mezzannine | Wall_Int_02 | Wall_Int_02 | Mezzannine |  |  | Elément porteur | Intérieur | Mur | Enduit - Blanc fin | Face extérieure | yes | no | 6.71515 | 3.845 | 0.872969 | 24.3714 | 18.1029 | 3.29966 | 2.4456 | 9.305 | -0.12 | 3.845 | 18.5033 | 6.78015 | 6.65015 | 17.7024 | 1.28818 | 2.4456 | 2 | 0 | 3 | 0 | 13.7441 | 26.5695 | 26.5695 | 3.45404 | 6.2685 | 6.2685 | 0.854055 | 0 | 3.845 | 0 | 3.845 | 0.277549 | 0.265536 | 0.277549 | 0.265536 | 6.84515 | 6.3
Wall_Int_02 | Mezzannine | Wall_Int_02 | Wall_Int_02 | Mezzannine |  |  | Elément porteur | Intérieur | Type ArchiCAD | Enduit - Blanc fin | Face extérieure | yes | no | 7.13596 | 4.07 | 0.927675 | 27.0636 | 24.9636 | 3.53571 | 3.25047 | 9.305 | -0.12 | 4.07 | 25.2559 | 7.06999 | 7.20194 | 24.6713 | 1.21513 | 3.25069 | 1 | 0 | 1 | 0 | 14.5872 | 29.3119 | 29.304 | 3.81003 | 2.1 | 2.1 | 0.285241 | 0 | 4.07 | 0 | 3.845 | 0.378784 | 0.370064 | 0.378771 | 0.370064 | 7.06999 | 2.1
Wall_Int | Mezzannine | Wall_Int_05 | Wall_Int | Mezzannine |  |  | Elément porteur | Intérieur | Mur | Surf-White | Face extérieure | yes | no | 4.7 | 3.785 | 0.611 | 17.5075 | 17.5075 | 2.30417 | 2.30417 | 9.365 | -0.06 | 3.785 | 17.5075 | 4.7 | 4.7 | 17.5075 | 2.0615 | 2.30417 | 0 | 0 | 0 | 0 | 9.66 | 17.7895 | 17.7895 | 2.31264 | 0 | 0 | 0 | 0 | 3.785 | 0 | 3.785 | 0.262613 | 0.262613 | 0.262613 | 0.262613 | 4.7 | 0
Wall_Int_02 | Mezzannine | Wall_Int_02 | Wall_Int_02 | Mezzannine | WC | 006 | Elément porteur | Intérieur | Type ArchiCAD | Enduit - Blanc fin | Face extérieure | yes | no | 5.32638 | 4.025 | 0.692429 | 19.6572 | 17.5572 | 2.64951 | 2.36451 | 9.305 | -0.12 | 4.07 | 17.371 | 5.32638 | 5.32638 | 17.7435 | 0.459038 | 2.36451 | 1 | 0 | 1 | 0 | 10.9128 | 22.7366 | 22.7366 | 2.95575 | 2.1 | 2.1 | 0.285 | 0 | 4.025 | 0 | 4.025 | 0.260564 | 0.266152 | 0.260564 | 0.266152 | 5.58638 | 2.1
Wall_Int_02 | Mezzannine | Wall_Int_02 | Wall_Int_02 | Mezzannine |  |  | Elément porteur | Intérieur | Type ArchiCAD | Enduit - Blanc fin | Face extérieure | yes | no | 2.575 | 3.845 | 0.33475 | 9.536 | 9.536 | 1.23772 | 1.23772 | 9.305 | -0.12 | 3.845 | 9.10762 | 2.445 | 2.705 | 9.96437 | 0.5718 | 1.23772 | 0 | 0 | 0 | 0 | 5.5177 | 10.4007 | 10.4007 | 1.3521 | 0 | 0 | 0 | 0 | 3.845 | 0 | 3.845 | 0.136614 | 0.149466 | 0.136614 | 0.149466 | 2.575 | 0
Wall_Int_02 | Mezzannine | Wall_Int_02 | Wall_Int_02 | Mezzannine | Plateau bureaux | 005 | Elément porteur | Intérieur | Type ArchiCAD | Enduit - Blanc fin | Face extérieure | yes | no | 5.425 | 3.845 | 0.70525 | 20.2081 | 20.2081 | 2.69216 | 2.69216 | 9.305 | -0.12 | 3.845 | 20.6365 | 5.555 | 5.295 | 19.7797 | 1.30362 | 2.69216 | 0 | 0 | 0 | 0 | 11.2177 | 21.359 | 21.359 | 2.77667 | 0 | 0 | 0 | 0 | 3.845 | 0 | 3.845 | 0.309548 | 0.296696 | 0.309548 | 0.296696 | 5.295 | 0
Wall_Int_02 | Mezzannine | Wall_Int_02 | Wall_Int_02 | Mezzannine | Cafetaria | 007 | Elément porteur | Intérieur | Type ArchiCAD | Enduit - Blanc fin | Face extérieure | yes | no | 4.02993 | 3.95 | 0.523891 | 14.7695 | 14.7695 | 1.93155 | 1.93155 | 9.425 | 0 | 3.95 | 14.7715 | 4.0955 | 3.96436 | 14.7675 | 0.52001 | 1.93155 | 0 | 0 | 0 | 0 | 8.37378 | 17.6345 | 17.6388 | 2.29276 | 0 | 0 | 0 | 0 | 3.95 | 0 | 3.95 | 0.221569 | 0.221516 | 0.221569 | 0.221516 | 4.46551 | 0
Wall_Int_02 | Mezzannine | Wall_Int_02 | Wall_Int_02 | Mezzannine |  |  | Elément porteur | Intérieur | Type ArchiCAD | Enduit - Blanc fin | Face extérieure | yes | no | 5.35996 | 3.845 | 0.696795 | 19.6213 | 17.6413 | 2.67454 | 2.40514 | 9.305 | -0.12 | 3.845 | 17.7996 | 5.29497 | 5.42496 | 17.483 | 1.19889 | 2.40514 | 1 | 0 | 1 | 0 | 11.0338 | 21.3588 | 21.3588 | 2.77665 | 1.98 | 1.98 | 0.2694 | 0 | 3.845 | 0 | 3.845 | 0.266994 | 0.262245 | 0.266994 | 0.262245 | 5.29497 | 2.1
Wall_Int_02 | Mezzannine | Wall_Int_02 | Wall_Int_02 | Mezzannine | WC | 005 | Elément porteur | Intérieur | Type ArchiCAD | Enduit - Blanc fin | Face extérieure | yes | no | 7.11 | 3.85185 | 0.9243 | 26.2707 | 26.2707 | 3.50847 | 3.50847 | 9.305 | -0.12 | 3.85185 | 25.8702 | 7.045 | 7.175 | 26.6711 | 0.71034 | 3.50847 | 0 | 0 | 0 | 0 | 14.5338 | 28.1369 | 28.1369 | 3.65779 | 0 | 0 | 0 | 0 | 3.85185 | 0 | 3.85185 | 0.388053 | 0.400067 | 0.388053 | 0.400067 | 7.175 | 0
Wall_Int_02 | Mezzannine | Wall_Int_02 | Wall_Int_02 | Mezzannine | Local Tech. | 008 | Elément porteur | Intérieur | Mur | Enduit - Blanc fin | Face extérieure | yes | no | 1.44997 | 3.725 | 0.188496 | 5.37929 | 5.37929 | 0.707081 | 0.707081 | 9.425 | 0 | 3.725 | 5.37994 | 1.44997 | 1.44997 | 5.37864 | 0.752141 | 0.707081 | 0 | 0 | 0 | 0 | 3.15994 | 5.8854 | 5.8854 | 0.765101 | 0 | 0 | 0 | 0 | 3.725 | 0 | 3.725 | 0.080698 | 0.0806808 | 0.080698 | 0.0806808 | 1.57997 | 0
Wall_Int_05 | Mezzannine | Wall_Int_05 | Wall_Int_05 | Mezzannine | Plateau bureaux | 005 | Elément porteur | Intérieur | Mur | Surf-White | Face extérieure | yes | no | 2.855 | 3.785 | 0.37115 | 10.2996 | 8.19962 | 1.37089 | 1.09189 | 9.365 | -0.06 | 3.785 | 8.72112 | 2.92 | 2.79 | 7.67812 | 0.54745 | 1.09189 | 1 | 0 | 1 | 0 | 6.02385 | 11.0552 | 11.0552 | 1.43718 | 2.1 | 2.1 | 0.279 | 0 | 3.785 | 0 | 3.785 | 0.130817 | 0.115172 | 0.130817 | 0.115172 | 2.87 | 2.1
Wall_Int_05 | Mezzannine | Wall_Int_05 | Wall_Int_05 | Mezzannine | Plateau bureaux | 005 | Elément porteur | Intérieur | Mur | Surf-White | Face extérieure | yes | no | 2.345 | 3.785 | 0.30485 | 8.76306 | 6.66306 | 1.1694 | 0.890399 | 9.365 | -0.06 | 3.785 | 6.87725 | 2.41 | 2.28 | 6.44888 | 0.9957 | 0.890399 | 1 | 0 | 1 | 0 | 5.00385 | 9.12185 | 9.12185 | 1.18584 | 2.1 | 2.1 | 0.279 | 0 | 3.785 | 0 | 3.785 | 0.103159 | 0.0967331 | 0.103159 | 0.0967331 | 2.36 | 2.1
Wall_Int_02 | Mezzannine | Wall_Int_02 | Wall_Int_02 | Mezzannine |  |  | Elément porteur | Intérieur | Type ArchiCAD | Enduit - Blanc fin | Face extérieure | yes | no | 2.60369 | 3.905 | 0.338479 | 9.69998 | 7.59998 | 1.27216 | 0.999164 | 9.425 | 0 | 3.95 | 7.59971 | 2.60361 | 2.60376 | 7.60025 | 0.211479 | 0.999164 | 1 | 0 | 1 | 0 | 5.46737 | 12.2599 | 12.2593 | 1.59374 | 2.1 | 2.1 | 0.273 | 0 | 3.905 | 2.20055e-10 | 3.905 | 0.113996 | 0.114003 | 0.113996 | 0.114003 | 2.97361 | 2.1
Wall_Int_02 | R+2 | Wall_Int_02 | Wall_Int_02 | R+2 | Plateau bureaux | 005 | Elément porteur | Intérieur | Mur | Enduit - Blanc fin | Face extérieure | yes | no | 6.78015 | 3.62 | 0.881419 | 23.3805 | 17.2991 | 3.15583 | 2.33049 | 13.33 | -0.12 | 3.62 | 18.0516 | 6.91015 | 6.65015 | 16.5466 | 1.31934 | 2.33049 | 2 | 0 | 2.89592 | 0 | 13.928 | 25.0147 | 25.0147 | 3.25191 | 6.08143 | 6.08143 | 0.825337 | 0 | 3.62 | 0 | 3.62 | 0.270774 | 0.248199 | 0.270774 | 0.248199 | 6.84515 | 6.08143
Wall_Int_02 | R+2 | Wall_Int_02 | Wall_Int_02 | R+2 | Rangement | 005 | Elément porteur | Intérieur | Type ArchiCAD | Enduit - Blanc fin | Face extérieure | yes | no | 7.11 | 3.63 | 0.9243 | 24.6838 | 24.6838 | 3.30874 | 3.30874 | 13.33 | -0.12 | 3.63 | 24.3075 | 7.045 | 7.175 | 25.06 | 1.415 | 3.30874 | 0 | 0 | 0 | 0 | 14.5338 | 26.5172 | 26.5172 | 3.44723 | 0 | 0 | 0 | 0 | 3.63 | 0 | 3.63 | 0.364613 | 0.3759 | 0.364613 | 0.3759 | 7.175 | 0
Wall_Int_02 | R+2 | Wall_Int_02 | Wall_Int_02 | R+2 | Local Tech. | 008 | Elément porteur | Intérieur | Mur | Enduit - Blanc fin | Face extérieure | yes | no | 1.45911 | 3.63 | 0.189684 | 5.10728 | 5.10728 | 0.693879 | 0.693879 | 13.33 | -0.12 | 4.07 | 5.10791 | 1.45928 | 1.45893 | 5.10665 | 0.150014 | 0.693879 | 0 | 0 | 0 | 0 | 3.17821 | 6.99605 | 6.99747 | 0.909579 | 0 | 0 | 0 | 0 | 3.63 | 0 | 3.63 | 0.0766176 | 0.0766009 | 0.0766176 | 0.0766009 | 1.58928 | 0
Wall_Int_02 | R+2 | Wall_Int_02 | Wall_Int_02 | R+2 |  |  | Elément porteur | Intérieur | Type ArchiCAD | 03 / Concrete Light | Face extérieure | yes | no | 0.397816 | 3.63 | 0.051716 | 1.41861 | 1.41861 | 0.204666 | 0.204666 | 13.33 | -0.12 | 4.07 | 1.21561 | 0.332316 | 0.463316 | 1.6216 | 0.502781 | 0.204666 | 0 | 0 | 0 | 0 | 1.11019 | 1.88569 | 1.88164 | 0.244877 | 0 | 0 | 0 | 0 | 3.63 | 0 | 3.63 | 0.0182371 | 0.024321 | 0.0182371 | 0.024321 | 0.332316 | 0
Wall_Int_02 | R+2 | Wall_Int_02 | Wall_Int_02 | R+2 |  |  | Elément porteur | Intérieur | Type ArchiCAD | Enduit - Blanc fin | Face extérieure | yes | no | 5.35996 | 3.63 | 0.696795 | 18.6751 | 16.6951 | 2.52951 | 2.26011 | 13.33 | -0.12 | 4.07 | 17.0829 | 5.29496 | 5.42496 | 16.3074 | 0.55475 | 2.26011 | 1 | 0 | 1 | 0 | 11.0338 | 22.6087 | 22.6087 | 2.93913 | 1.98 | 1.98 | 0.2694 | 0 | 3.63 | 0 | 3.63 | 0.256243 | 0.24461 | 0.256243 | 0.24461 | 5.29497 | 2.1
Wall_Int | R+2 | Wall_Int | Wall_Int | R+2 |  |  | Elément non porteur | Intérieur | Type ArchiCAD | Surf-White | Face extérieure | no | no | 4.7 | 3.57 | 0.611 | 16.45 | 16.45 | 2.1714 | 2.1714 | 13.39 | -0.06 | 3.785 | 16.45 | 4.7 | 4.7 | 16.45 | 1.394 | 2.1714 | 0 | 0 | 0 | 0 | 9.66 | 17.7895 | 17.7895 | 2.31264 | 0 | 0 | 0 | 0 | 3.57 | 0 | 3.57 | 0.24675 | 0.24675 | 0.24675 | 0.24675 | 4.7 | 0
Wall_Int_07 | R+2 | Wall_Int_02 | Wall_Int_07 | R+2 | Rangement | 004 | Elément porteur | Intérieur | Type ArchiCAD | Enduit - Blanc fin | Face extérieure | yes | no | 4.75 | 3.63 | 0.6175 | 16.121 | 16.121 | 2.20788 | 2.20788 | 13.33 | -0.12 | 4.07 | 16.2225 | 4.62 | 4.88 | 16.0195 | 0.53275 | 2.20788 | 0 | 0 | 0 | 0 | 9.8677 | 19.8044 | 19.8044 | 2.57457 | 0 | 0 | 0 | 0 | 3.63 | 0 | 3.63 | 0.243338 | 0.240293 | 0.243338 | 0.240293 | 4.62 | 0
Wall_Int_05 | R+2 | Wall_Int_05 | Wall_Int_05 | R+2 | Plateau bureaux | 005 | Elément non porteur | Intérieur | Mur | Surf-White | Face extérieure | no | no | 2.345 | 3.57 | 0.30485 | 8.30305 | 8.30305 | 1.1039 | 1.1039 | 13.39 | -0.06 | 3.785 | 8.435 | 2.41 | 2.28 | 8.1711 | 0.78605 | 1.1039 | 0 | 0 | 0 | 0 | 5.00385 | 9.11885 | 9.11885 | 1.18545 | 0 | 0 | 0 | 0 | 3.57 | 0 | 3.57 | 0.126525 | 0.122566 | 0.126525 | 0.122566 | 2.36 | 0
Wall_Int_05 | R+2 | Wall_Int_05 | Wall_Int_05 | R+2 | Plateau bureaux | 005 | Elément non porteur | Intérieur | Mur | Surf-White | Face extérieure | no | no | 2.855 | 3.57 | 0.37115 | 9.6775 | 7.5775 | 1.29192 | 1.01292 | 13.39 | -0.06 | 3.785 | 8.0675 | 2.92 | 2.79 | 7.0875 | 0.184 | 1.01292 | 1 | 0 | 1 | 0 | 6.02385 | 11.0552 | 11.0552 | 1.43718 | 2.1 | 2.1 | 0.279 | 0 | 3.57 | 0 | 3.57 | 0.121012 | 0.106312 | 0.121012 | 0.106312 | 2.87 | 2.1
Wall_Int_07 | R+2 | Wall_Int_07 | Wall_Int_07 | R+2 | WC | 003 | Elément non porteur | Intérieur | Mur | Surf-White | Face extérieure | no | no | 2.33 | 3.57 | 0.3029 | 8.155 | 8.155 | 1.08717 | 1.08717 | 13.39 | -0.06 | 3.76 | 8.155 | 2.33 | 2.33 | 8.155 | 0.236 | 1.08717 | 0 | 0 | 0 | 0 | 4.92 | 9.7384 | 9.7384 | 1.26599 | 0 | 0 | 0 | 0 | 3.57 | 0 | 3.57 | 0.122325 | 0.122325 | 0.122325 | 0.122325 | 2.54 | 0
Wall_Int_07 | R+2 | Wall_Int_07 | Wall_Int_07 | R+2 | WC | 002 | Elément non porteur | Intérieur | Mur | Surf-White | Face extérieure | no | no | 2.33 | 3.57 | 0.3029 | 8.2258 | 8.2258 | 1.08968 | 1.08968 | 13.39 | -0.06 | 3.76 | 8.155 | 2.33 | 2.33 | 8.2966 | 0.2779 | 1.08968 | 0 | 0 | 0 | 0 | 4.92 | 9.7354 | 9.7354 | 1.2656 | 0 | 0 | 0 | 0 | 3.57 | 0 | 3.57 | 0.122325 | 0.124449 | 0.122325 | 0.124449 | 2.54 | 0
Wall_Int_05 | R+2 | Wall_Int_05 | Wall_Int_05 | R+2 | Plateau bureaux | 005 | Elément non porteur | Intérieur | Mur | Surf-White | Face extérieure | no | no | 2.345 | 3.57 | 0.30485 | 8.23375 | 6.13375 | 1.10203 | 0.823028 | 13.39 | -0.06 | 3.785 | 6.335 | 2.41 | 2.28 | 5.9325 | 0.654 | 0.823028 | 1 | 0 | 1 | 0 | 5.00385 | 9.12185 | 9.12185 | 1.18584 | 2.1 | 2.1 | 0.279 | 0 | 3.57 | 0 | 3.57 | 0.095025 | 0.0889875 | 0.095025 | 0.0889875 | 2.36 | 2.1
Wall_Int_07 | R+2 | Wall_Int_07 | Wall_Int_07 | R+2 | WC | 002 | Elément non porteur | Intérieur | Mur | Surf-White | Face extérieure | no | no | 2.33 | 3.57 | 0.3029 | 8.155 | 8.155 | 1.08717 | 1.08717 | 13.39 | -0.06 | 3.76 | 8.155 | 2.33 | 2.33 | 8.155 | 0.236 | 1.08717 | 0 | 0 | 0 | 0 | 4.92 | 9.7384 | 9.7384 | 1.26599 | 0 | 0 | 0 | 0 | 3.57 | 0 | 3.57 | 0.122325 | 0.122325 | 0.122325 | 0.122325 | 2.54 | 0
Wall_Int_05 | R+2 | Wall_Int_05 | Wall_Int_05 | R+2 | Plateau bureaux | 005 | Elément non porteur | Intérieur | Mur | Surf-White | Face extérieure | no | no | 1.86 | 3.51 | 0.2418 | 6.2475 | 4.1475 | 0.822735 | 0.549735 | 13.45 | 0 | 3.725 | 4.585 | 1.925 | 1.795 | 3.71 | 0.50805 | 0.549735 | 1 | 0 | 1 | 0 | 4.03385 | 7.17063 | 7.17063 | 0.932181 | 2.1 | 2.1 | 0.273 | 0 | 3.51 | 0 | 3.51 | 0.068775 | 0.05565 | 0.068775 | 0.05565 | 1.875 | 2.1
Wall_Int_02 | R+2 | Wall_Int_02 | Wall_Int_02 | R+2 |  |  | Elément porteur | Intérieur | Mur | Enduit - Blanc fin | Face extérieure | yes | no | 3.92497 | 3.63 | 0.510246 | 13.7374 | 10.5874 | 1.837 | 1.4095 | 13.33 | -0.12 | 4.07 | 10.9899 | 4.05497 | 3.79497 | 10.1849 | 0.295997 | 1.4095 | 1 | 1 | 1.5 | 0 | 8.21763 | 16.5037 | 16.5037 | 2.14548 | 3.15 | 3.15 | 0.4275 | 0 | 3.63 | 0 | 3.63 | 0.164848 | 0.152773 | 0.164848 | 0.152773 | 4.05497 | 3.15
Wall_Int_02 | R+2 | Wall_Int_02 | Wall_Int_02 | R+2 |  |  | Elément porteur | Intérieur | Type ArchiCAD | Enduit - Blanc fin | Face extérieure | yes | no | 3.98028 | 3.95 | 0.517436 | 7.06149 | 7.06149 | 0.0313835 | 0.0313835 | 13.45 | 0 | 3.95 | 10.6393 | 3.91568 | 4.04488 | 3.48371 | 0.00893869 | 0.0313835 | 0 | 0 | 0 | 0 | 8.27472 | 17.3469 | 17.3495 | 2.25527 | 0 | 0 | 0 | 0 | 3.95 | 0 | 3.51 | 0.0142189 | 0.00152575 | 0.0142189 | 0.00152575 | 4.23069 | 0
Wall_Int_02 | R+2 | Wall_Int_02 | Wall_Int_02 | R+2 | Rangement | 006 | Elément porteur | Intérieur | Type ArchiCAD | Enduit - Blanc fin | Face extérieure | yes | no | 5.32638 | 3.63 | 0.692429 | 18.4673 | 16.3673 | 2.49838 | 2.21338 | 13.33 | -0.12 | 4.07 | 16.1923 | 5.32638 | 5.32638 | 16.5423 | 0.435638 | 2.21338 | 1 | 0 | 1 | 0 | 10.9128 | 22.7366 | 22.7366 | 2.95575 | 2.1 | 2.1 | 0.285 | 0 | 3.63 | 0 | 3.63 | 0.242885 | 0.248135 | 0.242885 | 0.248135 | 5.58638 | 2.1
Wall_Int_02 | R+2 | Wall_Int_02 | Wall_Int_02 | R+2 |  |  | Elément porteur | Intérieur | Type ArchiCAD | Enduit - Blanc fin | Face extérieure | yes | no | 5.62916 | 3.51 | 0.731791 | 19.7546 | 17.6546 | 2.60357 | 2.33057 | 13.45 | 0 | 3.95 | 18.0565 | 5.759 | 5.49932 | 17.2526 | 0.612241 | 2.33057 | 1 | 0 | 1 | 0 | 11.6258 | 22.7493 | 22.7481 | 2.95733 | 2.1 | 2.1 | 0.273 | 0 | 3.51 | 0 | 3.51 | 0.270849 | 0.258788 | 0.270849 | 0.258788 | 5.629 | 2.1
Wall_Int_02 | R+2 | Wall_Int_02 | Wall_Int_02 | R+2 |  |  | Elément porteur | Intérieur | Type ArchiCAD | Enduit - Blanc fin | Face extérieure | yes | no | 7.13182 | 3.83 | 0.927136 | 25.1099 | 23.0099 | 3.29264 | 3.01213 | 13.33 | -0.12 | 4.07 | 22.9858 | 7.06627 | 7.19736 | 23.0339 | 0.00169075 | 3.01213 | 1 | 0 | 1 | 0 | 14.5782 | 30.7991 | 30.7947 | 4.0036 | 2.1 | 2.1 | 0.280504 | 0 | 3.83 | 0 | 3.63 | 0.339846 | 0.345505 | 0.339846 | 0.345505 | 7.43627 | 2.1
Wall_Int_05 | R+2 | Wall_Int_02 | Wall_Int_05 | R+2 | Rangement | 004 | Elément porteur | Intérieur | Type ArchiCAD | Enduit - Blanc fin | Face extérieure | yes | no | 4.62 | 3.63 | 0.6006 | 15.995 | 15.995 | 2.1678 | 2.1678 | 13.33 | -0.12 | 4.07 | 16.17 | 4.62 | 4.62 | 15.82 | 0.465 | 2.1678 | 0 | 0 | 0 | 0 | 9.5 | 19.8044 | 19.8044 | 2.57457 | 0 | 0 | 0 | 0 | 3.63 | 0 | 3.63 | 0.24255 | 0.2373 | 0.24255 | 0.2373 | 4.62 | 0
Wall_Int_05 | R+2 | Wall_Int_02 | Wall_Int_05 | R+2 | Dégagement | 001 | Elément porteur | Intérieur | Type ArchiCAD | Enduit - Blanc fin | Face extérieure | yes | no | 1.86 | 3.63 | 0.2418 | 6.4575 | 6.4575 | 0.87435 | 0.87435 | 13.33 | -0.12 | 4.07 | 6.4575 | 1.86 | 1.86 | 6.4575 | 0.5505 | 0.87435 | 0 | 0 | 0 | 0 | 3.98 | 8.0993 | 8.0993 | 1.05291 | 0 | 0 | 0 | 0 | 3.63 | 0 | 3.63 | 0.0968625 | 0.0968625 | 0.0968625 | 0.0968625 | 1.86 | 0
Wall_Int_02 | R+2 | Wall_Int_02 | Wall_Int_02 | R+2 |  |  | Elément porteur | Intérieur | Type ArchiCAD | Enduit - Blanc fin | Face extérieure | yes | no | 4.01512 | 3.51 | 0.521966 | 6.9188 | 6.9188 | 0.164031 | 0.164031 | 13.45 | 0 | 3.95 | 4.05823 | 4.08052 | 3.94972 | 9.77937 | 0.0467635 | 0.164031 | 0 | 0 | 0 | 0 | 8.34356 | 17.4848 | 17.4872 | 2.27318 | 0 | 0 | 0 | 0 | 3.51 | 0 | 3.51 | 0.0119571 | 0.0694115 | 0.0119571 | 0.0694115 | 4.26554 | 0
Wall_Int_02 | R+2 | Wall_Int_02 | Wall_Int_02 | R+2 | Rangement | 006 | Elément porteur | Intérieur | Type ArchiCAD | Enduit - Blanc fin | Face extérieure | yes | no | 9.75 | 3.63 | 1.2675 | 33.6525 | 26.3025 | 4.58513 | 3.58763 | 13.33 | -0.12 | 4.07 | 25.375 | 9.62 | 9.88 | 27.23 | 0.74 | 3.58763 | 3 | 0 | 3.5 | 0 | 19.8677 | 40.2116 | 40.2116 | 5.22751 | 7.35 | 7.35 | 0.9975 | 0 | 3.63 | 0 | 3.63 | 0.380625 | 0.40845 | 0.380625 | 0.40845 | 9.75 | 7.35
Wall_Int_02 | R+2 | Wall_Int_02 | Wall_Int_02 | R+2 | Plateau bureaux | 005 | Elément porteur | Intérieur | Type ArchiCAD | Enduit - Blanc fin | Face extérieure | yes | no | 5.42496 | 3.63 | 0.705245 | 18.9874 | 18.9874 | 2.53888 | 2.53888 | 13.33 | -0.12 | 4.07 | 19.3899 | 5.55496 | 5.29496 | 18.5849 | 0.594996 | 2.53888 | 0 | 0 | 0 | 0 | 11.2176 | 22.6087 | 22.6087 | 2.93913 | 0 | 0 | 0 | 0 | 3.63 | 0 | 3.63 | 0.290848 | 0.278773 | 0.290848 | 0.278773 | 5.29496 | 0
Wall_Int_02 | R+2 | Wall_Int_02 | Wall_Int_02 | R+2 |  |  | Elément porteur | Intérieur | Type ArchiCAD | Enduit - Blanc fin | Face extérieure | yes | no | 2.575 | 3.63 | 0.33475 | 9.1046 | 9.1046 | 1.17156 | 1.17156 | 13.33 | -0.12 | 4.07 | 8.8467 | 2.445 | 2.705 | 9.3625 | 0.28365 | 1.17156 | 0 | 0 | 0 | 0 | 5.5177 | 11.0093 | 11.0093 | 1.43122 | 0 | 0 | 0 | 0 | 3.63 | 5.50671e-14 | 3.63 | 0.1327 | 0.140437 | 0.1327 | 0.140437 | 2.575 | 0
Wall_Int_02 | Toiture | Wall_Int_02 | Wall_Int_02 | Toiture |  |  | Elément porteur | Extérieur | Type ArchiCAD | 03 / Concrete Light | Face extérieure | yes | yes | 7.13162 | 1.84981 | 0.927111 | 12.1506 | 10.4714 | 1.67022 | 1.43544 | 17.16 | -0.24 | 4.19 | 10.6017 | 7.06627 | 7.19697 | 10.3412 | 1.42361 | 1.43544 | 1 | 0 | 1 | 0 | 14.5775 | 13.9112 | 13.9959 | 1.81396 | 1.67343 | 1.68481 | 0.234785 | 0 | 1.84981 | 0 | 1.83975 | 0.15599 | 0.155178 | 0.15599 | 0.155178 | 7.43627 | 2.1
Wall_Int_02 | Toiture | Wall_Int_02 | Wall_Int_02 | Toiture |  |  | Elément porteur | Extérieur | Type ArchiCAD | 03 / Concrete Light | Face extérieure | yes | yes | 0.397932 | 1.87928 | 0.0517311 | 0.719085 | 0.719085 | 0.105666 | 0.105666 | 17.4 | 0 | 3.95 | 0.578475 | 0.332625 | 0.463238 | 0.859696 | 0.352437 | 0.105666 | 0 | 0 | 0 | 0 | 1.11015 | 0.861169 | 0.860044 | 0.111879 | -2.51554e-12 | 0 | -3.34455e-14 | 0 | 1.87928 | 0 | 1.87928 | 0.00947056 | 0.0128944 | 0.00947056 | 0.0128944 | 0.332625 | 0
Wall_Int_02 | Toiture | Wall_Int_02 | Wall_Int_02 | Toiture |  |  | Elément porteur | Extérieur | Type ArchiCAD | 03 / Concrete Light | Face extérieure | yes | yes | 2.60283 | 1.94643 | 0.338368 | 4.56525 | 2.74165 | 0.636714 | 0.382989 | 17.115 | -0.285 | 4.235 | 2.74164 | 2.60283 | 2.60283 | 2.74166 | 0.43885 | 0.382989 | 1 | 0 | 1 | 0 | 5.46566 | 5.11471 | 5.11468 | 0.66491 | 1.8236 | 1.82359 | 0.253724 | 0 | 1.94642 | 0 | 1.94643 | 0.0411247 | 0.0411249 | 0.0411247 | 0.0411249 | 2.60283 | 2.1

# IfcWallStandardCase: 0.0-Mur béton enduit platre x2 180, Wall_Int_02
In: R+2
Description: Wall_Int_02; Material: Finition int - Enduit plâtre 0.015 m, Struct. - Parpaing béton 0.15 m, Finition int - Enduit plâtre 0.015 m
ArchiCADProperties - ID: Wall_Int_02; Etage d'implantation: R+2; Nom de Zone: Dégagement; Numéro de Zone: 001; Calque: A-WALL-INTR; Type: Mur; Verrouillé: no; Matériau de construction / Composite / Profil / Hachure: 0.0-Mur béton enduit platre x2; Fonction structurelle: Non défini; Position: Non défini; Classification d'lément: Type ArchiCAD; Etat de rénovation: Existant; Afficher sur filtre de rénovation: Tous les filtres appropriés; Type de structure: Composite; Matériau de construction / Composite / Profil: 0.0-Mur béton enduit platre x2; Surface de face extérieure: Enduit - Blanc fin; Surface de face intérieure: Enduit - Blanc fin; Surface latérale: Enduit - Blanc fin; Angle d'inclinaison externe: 90 deg; Angle d'inclinaison interne: 90 deg; Type d'inclinaison de mur: Droit; Emplacement de ligne de référence: Face extérieure; Etage supérieur lié: Non lié; Option de géométrie: Uniforme
AC_Pset_RenovationAndPhasing - Renovation Status: Existing
BaseQuantities - Length: 2.60378 m; Height: 3.63624 m; Width: 0.18 m; GrossFootprintArea: 0.468681 m2; NetFootprintArea: 0.468681 m2; GrossSideArea: 9.11433 m2; NetSideArea: 7.13433 m2; GrossVolume: 1.69598 m3; NetVolume: 1.32599 m3
ArchiCADQuantities - Altitude à Zéro du Projet: 13.33 m; Altitude à étage: -0.12 m; Hauteur: 4.07 m; Superficie de surface: 7.13398 m2; Volume net: 1.32599 m3; Superficie: 0.468681 m2; Epaisseur: 0.18 m; Longueur de mur sur face extérieure: 2.60368 m; Longueur de mur sur face intérieure: 2.60388 m; Surface de mur nette sur face extérieure: 7.13398 m2; Surface de mur nette sur face intérieure: 7.13468 m2; Surface nette des arêtes: 0.0828025 m2; Volume conditionnel: 1.32599 m3; Nombre de Portes: 1; Nombre de Fenêtres: 0; Nombre de trous (Nombre d'ouvertures vides): 0; Nombre de Poteaux: 0; Largeur totale des Portes: 1 m; Largeur totale des Fenêtres: 0 m; Epaisseur du Mur à la fin: 0.18 m; Hauteur minimum du Mur: 0 m; Hauteur maximum du Mur: 3.63624 m; Longueur du Mur au centre: 2.60378 m; Surface du Mur: 0.468681 m2; Périmètre du Mur: 5.56757 m; Surface brute de mur sur face intérieure: 12.6284 m2; Surface brute de mur sur face extérieure: 12.6276 m2; Volume brut du Mur: 2.27304 m3; Surface analytique des ouvertures sur face intérieure: 1.98 m2; Surface analytique des ouvertures sur face extérieure: 1.98 m2; Volume analytique des ouvertures dans le Mur: 0.369995 m3; Epaisseur de couche de mur sur face extérieure: 0.015 m; Epaisseur de couche de mur sur face intérieure: 0.015 m; Epaisseur couche isolation: 0 m; Epaisseur couche d'air: 0 m; Hauteur de couche de mur minimum sur face extérieure: 4.47093e-08 m; Hauteur de couche de mur maximum sur face extérieure: 3.63624 m; Hauteur de couche de mur minimum sur face intérieure: 0 m; Hauteur de couche de mur maximum sur face intérieure: 3.63624 m; Longueur conditionnelle sur face extérieure: 2.60368 m; Longueur conditionnelle sur face intérieure: 2.60388 m; Surface conditionnelle sur face extérieure: 7.13398 m2; Surface conditionnelle sur face intérieure: 7.13468 m2; Volume de couche de mur sur face extérieure: 0.10701 m3; Volume de couche de mur sur face intérieure: 0.10702 m3; Volume de couche de mur conditionnelle sur face extérieure: 0.10701 m3; Volume de couche de mur conditionnelle sur face intérieure: 0.10702 m3; Longueur de ligne de référence: 2.97369 m; Décalage étage d'implantation: -0.12 m; Décalage supérieur: 0 m; Longueur moyenne: 2.60378 m; Surface des fenêtres dans le mur: 0 m2; Surface des portes dans le mur: 2.1 m2; Surface des baies libres dans le mur: 0 m2; Volume de poteaux: 0 m3

# IfcWallStandardCase: 1.2-Mur ext: revét ext + isol ext + maçonnerie + enduit 370 (61)
Material: Finition ext - Crépis 0.015 m, Isolation - Fibres de bois 0.16 m, Struct. - B.A. banché 0.18 m, Finition int - Enduit plâtre 0.015 m
ArchiCADProperties - Calque: A-WALL-EXTR; Type: Mur; Verrouillé: no; Matériau de construction / Composite / Profil / Hachure: 1.2-Mur ext: revét ext + isol ext + maçonnerie + enduit; Position: Extérieur; Etat de rénovation: Existant; Afficher sur filtre de rénovation: Tous les filtres appropriés; Type de structure: Composite; Matériau de construction / Composite / Profil: 1.2-Mur ext: revét ext + isol ext + maçonnerie + enduit; Surface de face extérieure: 09 | Paint-02 Whitewash; Surface de face intérieure: 09 | Paint-02 Whitewash; Surface latérale: 09 | Paint-02 Whitewash; Angle d'inclinaison externe: 90 deg; Angle d'inclinaison interne: 90 deg; Type d'inclinaison de mur: Droit; Etage supérieur lié: Non lié; Option de géométrie: Uniforme
AC_Pset_RenovationAndPhasing - Renovation Status: Existing
Pset_WallCommon - IsExternal: yes
BaseQuantities - Width: 0.37 m
ArchiCADQuantities - Epaisseur: 0.37 m; Epaisseur du Mur à la fin: 0.37 m; Epaisseur de couche de mur sur face extérieure: 0.015 m; Epaisseur de couche de mur sur face intérieure: 0.015 m; Epaisseur couche isolation: 0 m; Epaisseur couche d'air: 0 m; Décalage supérieur: 0 m; Volume de poteaux: 0 m3
Name | In | Description | ID | Etage d'implantation | Fonction structurelle | Classification d'lément | Emplacement de ligne de référence | LoadBearing | Length (m) = Longueur moyenne (m) | Height (m) = Hauteur maximum du Mur (m) = Hauteur de couche de mur maximum sur face extérieure (m) | GrossFootprintArea (m2) | NetFootprintArea (m2) = Superficie (m2) = Surface du Mur (m2) | GrossSideArea (m2) | NetSideArea (m2) | GrossVolume (m3) | NetVolume (m3) = Volume net (m3) | Altitude à Zéro du Projet (m) | Altitude à étage (m) = Décalage étage d'implantation (m) | Hauteur (m) | Superficie de surface (m2) = Surface de mur nette sur face extérieure (m2) | Longueur de mur sur face extérieure (m) = Longueur conditionnelle sur face extérieure (m) | Longueur de mur sur face intérieure (m) = Longueur conditionnelle sur face intérieure (m) | Surface de mur nette sur face intérieure (m2) | Surface nette des arêtes (m2) | Volume conditionnel (m3) | Nombre de Portes | Nombre de Fenêtres | Nombre de trous (Nombre d'ouvertures vides) | Nombre de Poteaux | Largeur totale des Portes (m) | Largeur totale des Fenêtres (m) | Hauteur minimum du Mur (m) | Longueur du Mur au centre (m) | Périmètre du Mur (m) | Surface brute de mur sur face intérieure (m2) | Surface brute de mur sur face extérieure (m2) | Volume brut du Mur (m3) | Surface analytique des ouvertures sur face intérieure (m2) | Surface analytique des ouvertures sur face extérieure (m2) | Volume analytique des ouvertures dans le Mur (m3) | Hauteur de couche de mur minimum sur face extérieure (m) | Hauteur de couche de mur minimum sur face intérieure (m) | Hauteur de couche de mur maximum sur face intérieure (m) | Surface conditionnelle sur face extérieure (m2) | Surface conditionnelle sur face intérieure (m2) | Volume de couche de mur sur face extérieure (m3) | Volume de couche de mur sur face intérieure (m3) | Volume de couche de mur conditionnelle sur face extérieure (m3) | Volume de couche de mur conditionnelle sur face intérieure (m3) | Longueur de ligne de référence (m) | Surface des fenêtres dans le mur (m2) | Surface des portes dans le mur (m2) | Surface des baies libres dans le mur (m2) | Nom de Zone | Numéro de Zone
ExtWall_02 | Rez de chaussée | Level_1 | ExtWall_02 | Rez de chaussée | Elément porteur | Type ArchiCAD | Centrer | yes | 1.44622 | 1 | 0.535101 | 0.535101 | 1.24375 | 1.24375 | 0.529027 | 0.529027 | 4.4 | 4.4 | 1 | 1.04128 | 1.44622 | 1.44622 | 1.44622 | 1.78011 | 0.529027 | 0 | 0 | 0 | 0 | 0 | 0 | 0.72 | 1.44622 | 3.63244 | 1.44622 | 1.44622 | 0.535101 | 0 | 0 | 0 | 0.72 | 1 | 1 | 1.04128 | 1.44622 | 0.0156192 | 0.0216933 | 0.0156192 | 0.0216933 | 1.44622 | 0 | 0 | 0
SW - 013 | Rez de chaussée | Level_1 | SW - 013 | Rez de chaussée | Elément non porteur | Type ArchiCAD | Face extérieure | no | 7.70592 | 5.4 | 2.85119 | 2.85119 | 38.7104 | 15.2995 | 15.2355 | 6.45422 | 0 | 0 | 5.4 | 15.7886 | 7.65527 | 7.75657 | 14.8104 | 2.42275 | 6.45422 | 3 | 8 | 0 | 0 | 4.4 | 9.6 | 0 | 7.70592 | 16.2091 | 46.2361 | 41.3385 | 16.2013 | 23.3179 | 23.5039 | 8.78125 | 0 | 0 | 5.12 | 15.7886 | 14.8104 | 0.238241 | 0.220806 | 0.238241 | 0.220806 | 8.03292 | 14.3119 | 9.24 | 0 | Surface expoitation | 007
WallEx | Rez de chaussée | Level_1 | WallEx | Rez de chaussée | Elément porteur | Type ArchiCAD | Face extérieure | yes | 0.88553 | 5.12 | 0.327646 | 0.327646 | 4.42825 | 4.42825 | 1.65783 | 1.65783 | 0 | 0 | 5.12 | 4.44512 | 0.86986 | 0.901201 | 4.41138 | 0.621785 | 1.65783 | 0 | 0 | 0 | 0 | 0 | 0 | 0 | 0.88553 | 2.60779 | 7.02943 | 6.65777 | 2.53213 | 0 | 0 | 0 | 0 | 0 | 5.12 | 4.44512 | 4.41138 | 0.0667898 | 0.0660627 | 0.0667898 | 0.0660627 | 0.86986 | 0 | 0 | 0 | Surface expoitation | 007
WallEx | Rez de chaussée | Level_1 | WallEx | Rez de chaussée | Elément porteur | Type ArchiCAD | Face extérieure | yes | 7.36232 | 5.12 | 2.72406 | 2.72406 | 36.4167 | 36.4167 | 13.9497 | 13.9497 | 0 | 0 | 5.12 | 39.0278 | 7.63761 | 7.08704 | 33.8056 | 5.25118 | 13.9497 | 0 | 0 | 0 | 0 | 0 | 0 | 0 | 7.36232 | 15.66 | 40.5953 | 39.1046 | 14.7445 | 0 | 0 | 0 | 0 | 0 | 5.12 | 39.0278 | 33.8056 | 0.58587 | 0.506651 | 0.58587 | 0.506651 | 7.63761 | 0 | 0 | 0 | Surface expoitation | 007
WallEx | Rez de chaussée | Level_1 | WallEx | Rez de chaussée | Elément porteur | Type ArchiCAD | Face extérieure | yes | 11.7019 | 5.12 | 4.3297 | 4.3297 | 58.4642 | 58.4642 | 21.6286 | 21.6286 | 0 | 0 | 5.12 | 59.4381 | 11.6417 | 11.7621 | 57.4902 | 8.11209 | 21.6286 | 0 | 0 | 0 | 0 | 0 | 0 | 0 | 11.7019 | 24.2102 | 64.3471 | 61.8095 | 23.339 | 0 | 0 | 0 | 0 | 0 | 5.12 | 59.4381 | 57.4902 | 0.892344 | 0.861615 | 0.892344 | 0.861615 | 11.6417 | 0 | 0 | 0 | Surface expoitation | 007
ExtWall_01 | Rez de chaussée | Level_1 | ExtWall_01 | Rez de chaussée | Elément porteur | Type ArchiCAD | Face extérieure | yes | 2.45274 | 5.12 | 0.907512 | 0.907512 | 12.3033 | 12.3033 | 4.78731 | 4.78731 | 0 | 0 | 5.12 | 13.4216 | 2.63547 | 2.27 | 11.1851 | 3.69446 | 4.78731 | 0 | 0 | 0 | 0 | 0 | 0 | 0 | 2.45274 | 5.79554 | 13.5169 | 13.4936 | 4.99695 | 0 | 0 | 0 | 0 | 0 | 5.12 | 13.4216 | 11.1851 | 0.201331 | 0.167769 | 0.201331 | 0.167769 | 2.63547 | 0 | 0 | 0 | Dégagement | 001
ExtWall_01 | Rez de chaussée | Level_1 | ExtWall_01 | Rez de chaussée | Elément porteur | Type ArchiCAD | Face extérieure | yes | 7.40537 | 5.12 | 2.73999 | 2.73999 | 37.101 | 34.581 | 13.9987 | 13.0418 | 0 | 0 | 5.12 | 37.2019 | 7.77319 | 7.03755 | 31.96 | 5.04431 | 13.0418 | 1 | 0 | 0 | 0 | 1.2 | 0 | 0 | 7.40537 | 15.8542 | 39.8212 | 39.7987 | 14.7297 | 2.52 | 2.52 | 0.95697 | 0 | 0 | 5.12 | 37.2019 | 31.96 | 0.558036 | 0.473846 | 0.558036 | 0.473846 | 7.77319 | 0 | 2.52 | 0 | Dégagement | 001
WallEx02 | Rez de chaussée | Level_1 | WallEx02 | Rez de chaussée | Elément porteur | Type ArchiCAD | Face extérieure | yes | 30.2281 | 5.12 | 11.1844 | 11.1844 | 149.43 | 149.43 | 55.7239 | 55.7239 | 0 | 0 | 5.12 | 155.582 | 30.402 | 30.0542 | 143.278 | 20.925 | 55.7239 | 0 | 0 | 0 | 1 | 0 | 0 | 0 | 30.2281 | 61.3503 | 155.772 | 171.397 | 60.5262 | 0 | 0 | 0 | 0 | 0 | 5.12 | 155.582 | 143.278 | 2.32897 | 2.15589 | 2.32897 | 2.15589 | 30.402 | 0 | 0 | 0 | Réserve | 010
ExtWall_01 | Rez de chaussée | Level_1 | ExtWall_01 | Rez de chaussée | Elément porteur | Type ArchiCAD | Face extérieure | yes | 7.68307 | 5.595 | 2.84273 | 2.84273 | 40.3582 | 38.4082 | 16.5661 | 15.8287 | -0.195 | -0.195 | 5.595 | 40.5393 | 7.48695 | 7.87918 | 36.2771 | 2.55364 | 15.8287 | 1 | 0 | 0 | 0 | 1 | 0 | 0 | 7.68307 | 16.26 | 43.904 | 60.3833 | 19.2932 | 1.8 | 2.1 | 0.737399 | 0 | 0.195 | 5.315 | 40.5393 | 36.2771 | 0.603099 | 0.548698 | 0.603098 | 0.548698 | 7.48695 | 0 | 2.1 | 0 | Réserve | 008
ExtWall_01 | Rez de chaussée | Level_1 | ExtWall_01 | Rez de chaussée | Elément porteur | Type ArchiCAD | Face extérieure | yes | 7.31217 | 5.12 | 2.7055 | 2.7055 | 36.6186 | 15.929 | 13.8287 | 6.05064 | 0 | 0 | 5.12 | 16.9142 | 7.33585 | 7.28849 | 14.9439 | 4.04353 | 6.05064 | 2 | 0 | 0 | 0 | 5.89867 | 0 | 0 | 7.31217 | 15.7052 | 39.2252 | 39.4539 | 14.5556 | 20.7338 | 20.6453 | 7.77801 | 0 | 0 | 5.12 | 16.9142 | 14.9439 | 0.253643 | 0.224224 | 0.253643 | 0.224224 | 7.33585 | 0 | 20.6453 | 0 | Garage | 004
WallEx02 | Rez de chaussée | Level_1 | WallEx02 | Rez de chaussée | Elément porteur | Type ArchiCAD | Face extérieure | yes | 25.6805 | 5.12 | 9.50179 | 9.50179 | 128.069 | 128.069 | 48.2486 | 48.2486 | -1.77636e-15 | -1.77636e-15 | 5.12 | 133.346 | 26.0743 | 25.2867 | 122.791 | 18.1276 | 48.2486 | 0 | 0 | 0 | 0 | 0 | 0 | 0 | 25.6805 | 52.4422 | 133.27 | 133.5 | 49.3526 | 0 | 0 | 0 | 0 | 0 | 5.12 | 133.346 | 122.791 | 2.00012 | 1.84193 | 2.00012 | 1.84193 | 26.0743 | 0 | 0 | 0 | Réserve | 008
WallEx02 | Rez de chaussée | Level_1 | WallEx02 | Rez de chaussée | Elément porteur | Type ArchiCAD | Face extérieure | yes | 0.499449 | 5.4 | 0.184796 | 0.184796 | 2.64589 | 2.64589 | 1.26745 | 1.26745 | 0 | 0 | 5.4 | 2.77086 | 0.498901 | 0.499998 | 2.52091 | 0.320414 | 1.26745 | 0 | 0 | 0 | 0 | 0 | 0 | 0 | 0.499449 | 2.04672 | 4.59396 | 4.58847 | 1.69875 | 0 | 0 | 0 | 0 | 0 | 5.12 | 2.77086 | 2.52091 | 0.0415646 | 0.037812 | 0.0415646 | 0.037812 | 0.498901 | 0 | 0 | 0 | Dégagement | 002
WallEx02 | Rez de chaussée | Level_1 | WallEx02 | Rez de chaussée | Elément porteur | Type ArchiCAD | Face extérieure | yes | 6.01505 | 5.12 | 2.22557 | 2.22557 | 30.1204 | 27.5428 | 11.3746 | 10.3984 | 0 | 0 | 5.12 | 28.1534 | 6.01505 | 6.01505 | 26.9322 | 3.82378 | 10.3984 | 1 | 0 | 0 | 0 | 1.25889 | 0 | 0 | 6.01505 | 13.0787 | 32.6915 | 32.6915 | 12.0958 | 2.5115 | 2.64368 | 0.976179 | 0 | 0 | 5.12 | 28.1534 | 26.9322 | 0.422301 | 0.403983 | 0.422301 | 0.403983 | 6.01505 | 0 | 2.64368 | 0 | Dégagement | 002
SW - 013 | Rez de chaussée | Level_1 | SW - 013 | Rez de chaussée | Elément non porteur | Type ArchiCAD | Centrer | no | 7.2897 | 4.2926 | 2.69719 | 2.69719 | 30.8589 | 7.32398 | 11.5649 | 2.85124 | 0.1 | 0.1 | 4.2926 | 6.91055 | 7.2897 | 7.2897 | 7.73741 | 5.94388 | 2.85124 | 3 | 8 | 0 | 0 | 4.4 | 9.6 | 0 | 7.2897 | 15.3194 | 31.2918 | 31.2918 | 11.578 | 23.5179 | 23.5519 | 8.7137 | 4.44089e-16 | 4.44089e-16 | 4.2926 | 6.91055 | 7.73741 | 0.10363 | 0.116061 | 0.10363 | 0.116061 | 7.2897 | 14.3119 | 9.24 | 0
ExtWall_01 | R+1 | Level_1 | ExtWall_01 | R+1 | Elément porteur | Type ArchiCAD | Face extérieure | yes | 2.31132 | 4.005 | 0.855189 | 0.855189 | 9.3343 | 8.98384 | 3.65887 | 3.65818 | 5.12 | -0.28 | 4.005 | 9.42234 | 2.35264 | 2.27 | 8.54534 | 1.3536 | 3.65818 | 0 | 0 | 0 | 0 | 0 | 0 | 0 | 2.31132 | 5.60843 | 10.5727 | 10.5713 | 3.91165 | 0 | 0.70092 | 0.000694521 | 0 | 0.18 | 4.005 | 9.42234 | 8.54534 | 0.151155 | 0.12818 | 0.151155 | 0.12818 | 2.35264 | 0 | 0 | 0 | Dégagement | 001
WallEx02 | R+1 | Level_1 | WallEx02 | R+1 | Elément porteur | Type ArchiCAD | Face extérieure | yes | 30.2169 | 4.305 | 11.1803 | 11.1803 | 121.067 | 121.067 | 45.3205 | 45.3205 | 5.12 | -0.28 | 4.305 | 130.881 | 30.402 | 30.0319 | 111.253 | 10.5665 | 45.3205 | 0 | 0 | 0 | 1 | 0 | 0 | 0 | 30.2169 | 61.3272 | 130.886 | 131.741 | 48.5861 | 0 | 0 | 0 | 0 | 0.18 | 4.305 | 130.881 | 111.253 | 1.96297 | 1.65712 | 1.96297 | 1.65712 | 30.402 | 0 | 0 | 0 | Plateau bureaux | 005
WallEx02 | R+1 | Level_1 | WallEx02 | R+1 | Elément porteur | Type ArchiCAD | Face intérieure | yes | 6.01505 | 4.005 | 2.22557 | 2.22557 | 23.2908 | 23.2908 | 8.69076 | 8.69076 | 5.12 | -0.28 | 4.005 | 24.0907 | 6.01505 | 6.01505 | 22.491 | 3.276 | 8.69076 | 0 | 0 | 0 | 0 | 0 | 0 | 0 | 6.01505 | 13.0787 | 25.4685 | 25.4689 | 9.42343 | 0 | 0 | 0 | 0 | 0.18 | 4.005 | 24.0907 | 22.491 | 0.36136 | 0.337364 | 0.36136 | 0.337364 | 6.01505 | 0 | 0 | 0 | Plateau bureaux | 005
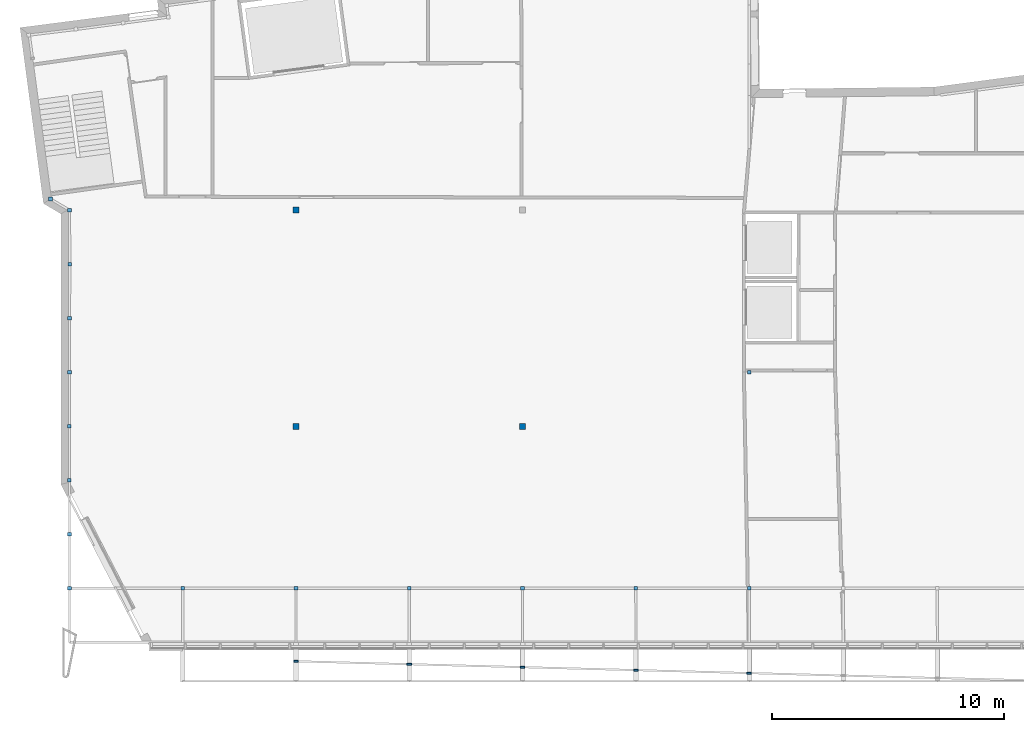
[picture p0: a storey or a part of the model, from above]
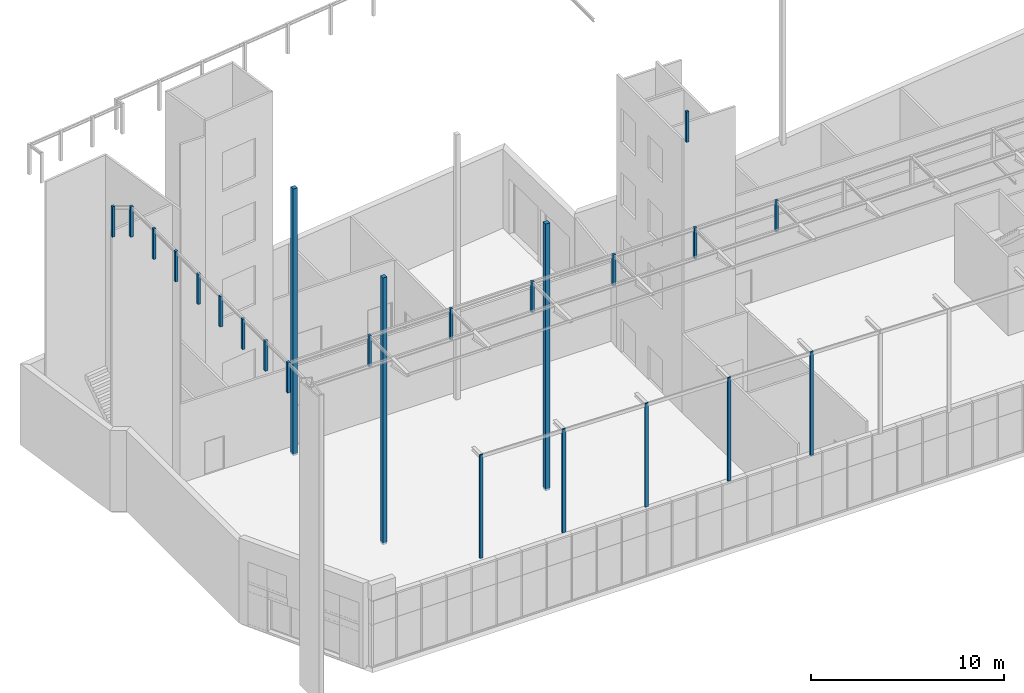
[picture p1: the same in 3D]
Properties of the parts of a building model (IFC2X3), part 16 of 19

# IfcWallStandardCase: 1.2-Mur ext: revét ext + isol ext + maçonnerie + enduit 370 (61)
Name | In | Description | ID | Etage d'implantation | Fonction structurelle | Classification d'lément | Emplacement de ligne de référence | LoadBearing | Length (m) = Longueur moyenne (m) | Height (m) = Hauteur maximum du Mur (m) = Hauteur de couche de mur maximum sur face extérieure (m) | GrossFootprintArea (m2) | NetFootprintArea (m2) = Superficie (m2) = Surface du Mur (m2) | GrossSideArea (m2) | NetSideArea (m2) | GrossVolume (m3) | NetVolume (m3) = Volume net (m3) | Altitude à Zéro du Projet (m) | Altitude à étage (m) = Décalage étage d'implantation (m) | Hauteur (m) | Superficie de surface (m2) = Surface de mur nette sur face extérieure (m2) | Longueur de mur sur face extérieure (m) = Longueur conditionnelle sur face extérieure (m) | Longueur de mur sur face intérieure (m) = Longueur conditionnelle sur face intérieure (m) | Surface de mur nette sur face intérieure (m2) | Surface nette des arêtes (m2) | Volume conditionnel (m3) | Nombre de Portes | Nombre de Fenêtres | Nombre de trous (Nombre d'ouvertures vides) | Nombre de Poteaux | Largeur totale des Portes (m) | Largeur totale des Fenêtres (m) | Hauteur minimum du Mur (m) | Longueur du Mur au centre (m) | Périmètre du Mur (m) | Surface brute de mur sur face intérieure (m2) | Surface brute de mur sur face extérieure (m2) | Volume brut du Mur (m3) | Surface analytique des ouvertures sur face intérieure (m2) | Surface analytique des ouvertures sur face extérieure (m2) | Volume analytique des ouvertures dans le Mur (m3) | Hauteur de couche de mur minimum sur face extérieure (m) | Hauteur de couche de mur minimum sur face intérieure (m) | Hauteur de couche de mur maximum sur face intérieure (m) | Surface conditionnelle sur face extérieure (m2) | Surface conditionnelle sur face intérieure (m2) | Volume de couche de mur sur face extérieure (m3) | Volume de couche de mur sur face intérieure (m3) | Volume de couche de mur conditionnelle sur face extérieure (m3) | Volume de couche de mur conditionnelle sur face intérieure (m3) | Longueur de ligne de référence (m) | Surface des fenêtres dans le mur (m2) | Surface des portes dans le mur (m2) | Surface des baies libres dans le mur (m2) | Nom de Zone | Numéro de Zone
WallEx02 | R+1 | Level_1 | WallEx02 | R+1 | Elément porteur | Type ArchiCAD | Face extérieure | yes | 0.499449 | 4 | 0.184796 | 0.184796 | 1.98492 | 1.98492 | 0.938679 | 0.938679 | 5.4 | 0 | 4 | 2.05148 | 0.498901 | 0.499998 | 1.91837 | 0.36174 | 0.938679 | 0 | 0 | 0 | 0 | 0 | 0 | 0 | 0.499449 | 2.04672 | 3.47959 | 3.47561 | 1.28671 | 0 | 0 | 0 | 0 | 0 | 3.725 | 2.05148 | 1.91837 | 0.0307731 | 0.0287743 | 0.0307731 | 0.0287743 | 0.868904 | 0 | 0 | 0 | Plateau bureaux | 005
WallEx | R+1 | Level_1 | WallEx | R+1 | Elément porteur | Type ArchiCAD | Face extérieure | yes | 11.7469 | 4.005 | 4.34635 | 4.34635 | 45.4428 | 45.4428 | 16.8544 | 16.8544 | 5.12 | -0.28 | 4.005 | 46.6249 | 11.6417 | 11.8521 | 44.2608 | 6.36772 | 16.8544 | 0 | 0 | 0 | 0 | 0 | 0 | 0 | 11.7469 | 24.2894 | 47.6681 | 48.349 | 17.7632 | 0 | 0 | 0 | 0 | 0.18 | 4.005 | 46.6249 | 44.2608 | 0.699166 | 0.664159 | 0.699166 | 0.664159 | 11.6417 | 0 | 0 | 0 | Plateau bureaux | 005
WallEx | R+1 | Level_1 | WallEx | R+1 | Elément porteur | Type ArchiCAD | Face extérieure | yes | 0.88553 | 4.005 | 0.327646 | 0.327646 | 3.42379 | 3.42379 | 1.26701 | 1.26701 | 5.12 | -0.28 | 4.005 | 3.47709 | 0.86986 | 0.901201 | 3.37049 | 0.476471 | 1.26701 | 0 | 0 | 0 | 0 | 0 | 0 | 0 | 0.88553 | 2.60779 | 5.49861 | 5.20789 | 1.9807 | 0 | 0 | 0 | 0 | 0.18 | 4.005 | 3.47709 | 3.37049 | 0.0522448 | 0.0504748 | 0.0522448 | 0.0504748 | 0.86986 | 0 | 0 | 0 | Plateau bureaux | 005
WallEx | R+1 | Level_1 | WallEx | R+1 | Elément porteur | Type ArchiCAD | Face extérieure | yes | 7.36232 | 4.005 | 2.72406 | 2.72406 | 28.1629 | 28.1629 | 10.6666 | 10.6666 | 5.12 | -0.28 | 4.005 | 30.5286 | 7.63761 | 7.08704 | 25.7972 | 4.04631 | 10.6666 | 0 | 0 | 0 | 0 | 0 | 0 | 0 | 7.36232 | 15.66 | 31.7547 | 30.5886 | 11.5335 | 0 | 0 | 0 | 0 | 0.18 | 4.005 | 30.5286 | 25.7972 | 0.458283 | 0.386626 | 0.458283 | 0.386626 | 7.26761 | 0 | 0 | 0 | Plateau bureaux | 005
ExtWall_01 | R+1 | Level_1 | ExtWall_01 | R+1 | Elément porteur | Type ArchiCAD | Face extérieure | yes | 47.1 | 5 | 17.427 | 17.427 | 221.934 | 49.6345 | 84.9584 | 20.5947 | 4.4 | -1 | 5 | 53.7093 | 47.1 | 47.1 | 45.5596 | 20.2881 | 20.5947 | 0 | 0 | 1 | 0 | 0 | 0 | 0.6 | 47.1 | 94.94 | 235.5 | 235.5 | 87.135 | 170.453 | 174.145 | 64.3637 | 0.72 | 0.6 | 5 | 53.7093 | 45.5596 | 0.80564 | 0.683394 | 0.80564 | 0.683394 | 47.1 | 0 | 0 | 170.283 | Serre | 006
ExtWall_01 | R+1 | Level_1 | ExtWall_01 | R+1 | Elément porteur | Type ArchiCAD | Face extérieure | yes | 4.57785 | 5 | 1.6938 | 1.6938 | 21.3786 | 21.3786 | 8.04878 | 8.04878 | 4.4 | -1 | 5 | 22.8893 | 4.57785 | 4.57785 | 19.8679 | 6.01133 | 8.04878 | 0 | 0 | 0 | 0 | 0 | 0 | 0.6 | 4.57785 | 9.8957 | 22.8893 | 22.8893 | 8.46902 | 0 | 0 | 0 | 5 | 0.6 | 4.725 | 22.8893 | 19.8679 | 0.343339 | 0.298018 | 0.343339 | 0.298018 | 4.57785 | 0 | 0 | 0 | Serre | 006
WallEx02 | Mezzannine | WallEx02 | WallEx02 | Mezzannine | Elément porteur | Type ArchiCAD | Face extérieure | yes | 0.208618 | 4.025 | 0.0771886 | 0.0694147 | 0.795028 | 0.795028 | 0.278515 | 0.278515 | 9.125 | -0.3 | 4.025 | 1.59006 | 0.395045 | 0.0221907 | 0 | 0.138393 | 0.278515 | 0 | 0 | 0 | 0 | 0 | 0 | 0 | 0.186427 | 1.3449 | 0 | 1.59006 | 0.278515 | 0 | 0 | 0 | 0 | 4.025 | 4.025 | 1.59006 | 0 | 0.0233402 | 0 | 0.0233402 | 0 | 0.395045 | 0 | 0 | 0
WallEx02 | Mezzannine | WallEx01 | WallEx02 | Mezzannine | Elément porteur | Type ArchiCAD | Face extérieure | yes | 30.1079 | 4.145 | 11.1399 | 11.1399 | 117.78 | 117.78 | 44.4812 | 44.4812 | 9.305 | -0.12 | 4.145 | 125.564 | 30.2929 | 29.9228 | 109.996 | 17.6032 | 44.4812 | 0 | 0 | 0 | 1 | 0 | 0 | 0 | 30.1079 | 61.1091 | 125.564 | 125.564 | 46.4587 | 0 | 0 | 0 | 0 | 0 | 4.145 | 125.564 | 109.996 | 1.88346 | 1.64987 | 1.88346 | 1.64987 | 30.2929 | 0 | 0 | 0
WallEx02 | Mezzannine | WallEx02 | WallEx02 | Mezzannine | Elément porteur | Type ArchiCAD | Face extérieure | yes | 6.01505 | 4.3 | 2.22557 | 2.22557 | 24.1356 | 24.1356 | 9.03576 | 9.03576 | 9.125 | -0.3 | 4.3 | 25.8647 | 6.01505 | 6.01505 | 22.4065 | 2.25761 | 9.03576 | 0 | 0 | 0 | 0 | 0 | 0 | 0 | 6.01505 | 13.0787 | 27.4468 | 27.4465 | 10.1553 | 0 | 0 | 0 | 1.77636e-15 | 0.18 | 4.3 | 25.8647 | 22.4065 | 0.387971 | 0.336097 | 0.387971 | 0.336097 | 6.01505 | 0 | 0 | 0 | Cafetaria | 007
WallEx02 | Mezzannine | WallEx02 | WallEx02 | Mezzannine | Elément porteur | Type ArchiCAD | Face extérieure | yes | 0.499449 | 4 | 0.184796 | 0.184796 | 1.92905 | 1.92905 | 0.712389 | 0.712389 | 9.425 | 0 | 4 | 1.9956 | 0.498901 | 0.499998 | 1.86249 | 0.27215 | 0.712389 | 0 | 0 | 0 | 0 | 0 | 0 | 0 | 0.499449 | 2.04672 | 3.47999 | 3.47561 | 1.28679 | 0 | 0 | 0 | 1.77636e-15 | 0 | 3.725 | 1.9956 | 1.86249 | 0.0299355 | 0.0279362 | 0.0299355 | 0.0279362 | 0.498901 | 0 | 0 | 0 | Cafetaria | 007
WallEx | Mezzannine | WallEx_01 | WallEx | Mezzannine | Elément porteur | Type ArchiCAD | Face extérieure | yes | 0.88553 | 4.025 | 0.327646 | 0.327646 | 3.42571 | 3.42571 | 1.27303 | 1.27303 | 9.125 | -0.3 | 4.025 | 3.49445 | 0.86986 | 0.901201 | 3.35697 | 0.476471 | 1.27303 | 0 | 0 | 0 | 0 | 0 | 0 | 0 | 0.88553 | 2.60779 | 5.52606 | 5.23389 | 1.99059 | 0 | 0 | 0 | 0 | 0.18 | 4.025 | 3.49445 | 3.35697 | 0.0525057 | 0.0502724 | 0.0525057 | 0.0502724 | 0.86986 | 0 | 0 | 0 | Cafetaria | 007
WallEx | Mezzannine | WallEx_01 | WallEx | Mezzannine | Elément porteur | Type ArchiCAD | Face extérieure | yes | 11.7469 | 4.025 | 4.34635 | 4.34635 | 45.4709 | 45.4709 | 16.9266 | 16.9266 | 9.125 | -0.3 | 4.025 | 46.8577 | 11.6417 | 11.8521 | 44.0841 | 7.80345 | 16.9266 | 0 | 0 | 0 | 0 | 0 | 0 | 0 | 11.7469 | 24.2894 | 47.7048 | 48.5904 | 17.8146 | 0 | 0 | 0 | 0 | 0.18 | 4.025 | 46.8577 | 44.0841 | 0.702597 | 0.661511 | 0.702597 | 0.661511 | 11.6417 | 0 | 0 | 0
WallEx | Mezzannine | WallEx_01 | WallEx | Mezzannine | Elément porteur | Type ArchiCAD | Face extérieure | yes | 7.36232 | 4.025 | 2.72406 | 2.72406 | 28.7851 | 28.7851 | 10.7364 | 10.7364 | 9.125 | -0.3 | 4.025 | 30.681 | 7.63761 | 7.08704 | 26.8893 | 4.11476 | 10.7364 | 0 | 0 | 0 | 0 | 0 | 0 | 0 | 7.36232 | 15.66 | 31.9133 | 30.7414 | 11.5911 | 0 | 0 | 0 | 0 | 0 | 4.025 | 30.681 | 26.8893 | 0.460571 | 0.401214 | 0.460571 | 0.401214 | 7.63761 | 0 | 0 | 0 | Cafetaria | 007
WallEx02 | Mezzannine | WallEx02 | WallEx02 | Mezzannine | Elément porteur | Type ArchiCAD | Face extérieure | yes | 25.6805 | 4.025 | 9.50179 | 9.50179 | 102.561 | 102.561 | 38.1525 | 38.1525 | 9.125 | -0.3 | 4.025 | 104.949 | 26.0743 | 25.2867 | 100.173 | 17.9562 | 38.1525 | 0 | 0 | 0 | 0 | 0 | 0 | 0 | 25.6805 | 52.4422 | 103.268 | 104.949 | 38.5202 | 0 | 0 | 0 | 0 | 1.55136e-09 | 4.025 | 104.949 | 100.173 | 1.57373 | 1.50311 | 1.57373 | 1.50311 | 26.0743 | 0 | 0 | 0 | Vide | 001
SW - 013 | Mezzannine | WallEx01 | SW - 013 | Mezzannine | Elément porteur | Type ArchiCAD | Face extérieure | yes | 2.31132 | 4.025 | 0.855189 | 0.855189 | 9.33239 | 8.98236 | 3.6693 | 3.66861 | 9.125 | -0.3 | 4.025 | 9.45276 | 2.35264 | 2.27 | 8.51196 | 1.33861 | 3.66865 | 0 | 0 | 0 | 0 | 0 | 0 | 0 | 2.31132 | 5.60843 | 10.5829 | 10.5815 | 3.91542 | 0 | 0.700045 | 0.000693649 | 0 | 0.18 | 4.025 | 9.45276 | 8.51196 | 0.151599 | 0.127679 | 0.151647 | 0.127679 | 2.35264 | 0 | 0 | 0 | Dégagement | 001
WallEx | R+2 | WallEx_01 | WallEx | R+2 | Elément porteur | Type ArchiCAD | Face extérieure | yes | 11.7469 | 3.75 | 4.34635 | 4.34635 | 42.2429 | 42.2429 | 15.7393 | 15.7393 | 13.15 | -0.3 | 3.75 | 43.6563 | 11.6417 | 11.8521 | 40.8296 | 7.69393 | 15.7393 | 0 | 0 | 0 | 0 | 0 | 0 | 0 | 11.7469 | 24.2894 | 44.4454 | 45.2706 | 16.5975 | 0 | 0 | 0 | 0 | 0.18 | 3.75 | 43.6563 | 40.8296 | 0.654593 | 0.612675 | 0.654593 | 0.612675 | 11.8569 | 0 | 0 | 0 | Plateau bureaux | 005
WallEx02 | R+2 | WallEx02 | WallEx02 | R+2 | Elément porteur | Type ArchiCAD | Face extérieure | yes | 25.6805 | 3.75 | 9.50179 | 9.50179 | 92.5347 | 79.9347 | 34.7995 | 30.1375 | 13.15 | -0.3 | 3.75 | 85.1786 | 26.0743 | 25.2867 | 74.6909 | 14.0828 | 30.1375 | 0 | 7 | 0 | 0 | 0 | 8.4 | 0 | 25.6805 | 52.4422 | 96.2126 | 97.7786 | 35.8884 | 12.6 | 12.6 | 4.662 | 0 | 0.18 | 3.75 | 85.1786 | 74.6909 | 1.2772 | 1.1208 | 1.2772 | 1.1208 | 26.0743 | 12.6 | 0 | 0 | Plateau bureaux | 005
WallEx02 | R+2 | WallEx01 | WallEx02 | R+2 | Elément porteur | Type ArchiCAD | Face extérieure | yes | 30.1079 | 3.63 | 11.1399 | 11.1399 | 106.46 | 92.06 | 40.3555 | 35.0275 | 13.33 | -0.12 | 3.63 | 95.2643 | 30.293 | 29.9228 | 88.8558 | 20.4599 | 35.0275 | 0 | 8 | 0 | 1 | 0 | 9.6 | 0 | 30.1079 | 61.1092 | 109.963 | 109.963 | 40.6864 | 14.4 | 14.4 | 5.328 | 0 | 0 | 3.63 | 95.2643 | 88.8558 | 1.42896 | 1.32894 | 1.42896 | 1.32894 | 30.293 | 14.4 | 0 | 0 | Plateau bureaux | 005
WallEx02 | R+2 | WallEx02 | WallEx02 | R+2 | Elément porteur | Type ArchiCAD | Face extérieure | yes | 6.01505 | 3.475 | 2.22557 | 2.22557 | 20.8271 | 20.8271 | 7.73159 | 7.73159 | 13.15 | -0.3 | 3.75 | 20.9023 | 6.01505 | 6.01505 | 20.7519 | 2.22557 | 7.73159 | 0 | 0 | 0 | 0 | 0 | 0 | 0 | 6.01505 | 13.0787 | 23.9443 | 23.9439 | 8.85933 | 0 | 0 | 0 | 0 | 0 | 3.475 | 20.9023 | 20.7519 | 0.313534 | 0.311279 | 0.313534 | 0.311279 | 5.83005 | 0 | 0 | 0 | Plateau bureaux | 005
WallEx02 | R+2 | WallEx02 | WallEx02 | R+2 | Elément porteur | Type ArchiCAD | Face extérieure | yes | 0.499449 | 3.475 | 0.184796 | 0.184796 | 1.72934 | 1.72934 | 0.64198 | 0.64198 | 13.15 | -0.3 | 3.75 | 1.73368 | 0.498901 | 0.499998 | 1.72499 | 0.184797 | 0.64198 | 0 | 0 | 0 | 0 | 0 | 0 | 0 | 0.499449 | 2.04672 | 3.26249 | 3.25839 | 1.20636 | 0 | 0 | 0 | 0 | 0 | 3.475 | 1.73368 | 1.72499 | 0.0260063 | 0.0258738 | 0.0260063 | 0.0258738 | 0.498901 | 0 | 0 | 0 | Plateau bureaux | 005
WallEx | R+2 | WallEx_01 | WallEx | R+2 | Elément porteur | Type ArchiCAD | Centrer | yes | 7.36232 | 3.75 | 2.72406 | 2.72406 | 25.768 | 25.768 | 9.95444 | 9.95444 | 13.15 | -0.3 | 3.75 | 27.7392 | 7.63761 | 7.08704 | 23.7967 | 4.03507 | 9.95444 | 0 | 0 | 0 | 0 | 0 | 0 | 0 | 7.36232 | 15.66 | 29.7329 | 28.641 | 10.7992 | 0 | 0 | 0 | 0 | 0.18 | 3.75 | 27.7392 | 23.7967 | 0.416419 | 0.356643 | 0.416419 | 0.356643 | 7.54733 | 0 | 0 | 0 | Plateau bureaux | 005
SW - 013 | R+2 | WallEx01 | SW - 013 | R+2 | Elément porteur | Type ArchiCAD | Face extérieure | yes | 2.31132 | 3.81 | 0.855189 | 0.855189 | 8.8036 | 8.77953 | 3.46902 | 3.46898 | 13.15 | -0.3 | 3.81 | 9.56124 | 2.35264 | 2.27 | 7.99783 | 1.34751 | 3.46902 | 0 | 0 | 0 | 0 | 0 | 0 | 0 | 2.31132 | 5.60843 | 10.0159 | 10.0145 | 3.70563 | 0 | 0.048128 | 0.0000476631 | 0 | 1.77636e-15 | 3.81 | 9.56124 | 7.99783 | 0.144093 | 0.119967 | 0.144141 | 0.119967 | 2.35264 | 0 | 0 | 0 | Dégagement | 001
WallEx | R+2 | WallEx_01 | WallEx | R+2 | Elément porteur | Type ArchiCAD | Centrer | yes | 0.88553 | 3.75 | 0.327646 | 0.327646 | 3.18242 | 3.18242 | 1.18382 | 1.18382 | 13.15 | -0.3 | 3.75 | 3.2557 | 0.86986 | 0.901201 | 3.10914 | 0.476471 | 1.18382 | 0 | 0 | 0 | 0 | 0 | 0 | 0 | 0.88553 | 2.60779 | 5.14851 | 4.8763 | 1.85459 | 0 | 0 | 0 | 0 | 0.18 | 3.75 | 3.2557 | 3.10914 | 0.0489183 | 0.046561 | 0.0489183 | 0.046561 | 0.670287 | 0 | 0 | 0 | Plateau bureaux | 005
WallEx02 | R+2 | WallEx02 | WallEx02 | R+2 | Elément porteur | Type ArchiCAD | Face extérieure | yes | 0.208618 | 3.75 | 0.0771886 | 0.0693809 | 0.740517 | 0.740517 | 0.259145 | 0.259145 | 13.15 | -0.3 | 3.75 | 1.48103 | 0.394943 | 0.0222931 | 0 | 0.137173 | 0.259145 | 0 | 0 | 0 | 0 | 0 | 0 | 0 | 0.186325 | 1.3449 | 0 | 1.48103 | 0.259352 | 0 | 0 | 0 | 2.4869e-13 | 3.75 | 3.75 | 1.48103 | 0 | 0.0217398 | 0 | 0.0217398 | 0 | 0.394943 | 0 | 0 | 0
WallEx_09 | Toiture | WallEx_09 | WallEx_09 | Toiture | Elément porteur | Type ArchiCAD | Face extérieure | yes | 4.24477 | 1.9151 | 1.57057 | 1.57057 | 6.85294 | 6.85294 | 2.63111 | 2.63111 | 17.4 | 0 | 3.302 | 7.60243 | 4.42996 | 4.05959 | 6.10344 | 3.64106 | 2.63111 | 0 | 0 | 0 | 1 | 0 | 0 | 0 | 4.24477 | 9.38306 | 7.63047 | 7.63117 | 2.8234 | 5.0554e-08 | 0 | 1.09636e-10 | 0 | 0 | 1.88532 | 7.60243 | 6.10344 | 0.114036 | 0.0975042 | 0.114036 | 0.0975042 | 4.42996 | 0 | 0 | 0
WallEx_09 | Toiture | WallEx_09 | WallEx_09 | Toiture | Elément porteur | Type ArchiCAD | Face extérieure | yes | 25.6805 | 2.03114 | 9.50179 | 9.50179 | 46.2556 | 46.2556 | 18.2595 | 18.2595 | 16.9 | -0.5 | 2.03114 | 52.9606 | 26.0743 | 25.2867 | 39.5506 | 18.7276 | 18.2595 | 0 | 0 | 0 | 9 | 0 | 0 | 0 | 25.6805 | 52.4422 | 52.1123 | 52.9606 | 19.4385 | 0 | 0 | 0 | 0 | 0 | 2.03114 | 52.9606 | 39.5506 | 0.79415 | 0.593469 | 0.79415 | 0.593469 | 26.0743 | 0 | 0 | 0
WallEx02 | Toiture | WallEx02 | WallEx02 | Toiture | Elément porteur | Type ArchiCAD | Face extérieure | yes | 0.49945 | 2.0311 | 0.184797 | 0.184797 | 0.791157 | 0.791157 | 0.350654 | 0.350654 | 16.9 | -0.5 | 2.0311 | 1.01332 | 0.498901 | 0.499999 | 0.568996 | 0.362094 | 0.350654 | 0 | 0 | 0 | 2 | 0 | 0 | 0 | 0.49945 | 2.04672 | 1.76706 | 1.76483 | 0.653399 | 0 | 0 | 0 | 0 | 0 | 2.0311 | 1.01332 | 0.568996 | 0.0152005 | 0.00853435 | 0.0152005 | 0.00853435 | 0.498901 | 0 | 0 | 0
WallEx_09 | Toiture | WallEx_09 | WallEx_09 | Toiture | Elément porteur | Type ArchiCAD | Face extérieure | yes | 6.01505 | 2.0311 | 2.22557 | 2.22557 | 10.723 | 10.723 | 4.25933 | 4.25933 | 16.9 | -0.5 | 2.0311 | 12.2172 | 6.01505 | 6.01505 | 9.22874 | 4.36091 | 4.25933 | 0 | 0 | 0 | 4 | 0 | 0 | 0 | 6.01505 | 13.0787 | 12.9687 | 12.9687 | 4.79841 | 0 | 0 | 0 | 0 | 0 | 2.0311 | 12.2172 | 9.22874 | 0.183257 | 0.138431 | 0.183257 | 0.138431 | 6.01505 | 0 | 0 | 0
WallEx | Toiture | WallEx_09 | WallEx | Toiture | Elément porteur | Type ArchiCAD | Face extérieure | yes | 0.88553 | 2.03114 | 0.327646 | 0.327646 | 1.5662 | 1.5662 | 0.761764 | 0.761764 | 16.9 | -0.5 | 2.03114 | 1.80225 | 0.86986 | 0.901201 | 1.33015 | 0.784036 | 0.761764 | 0 | 0 | 0 | 2 | 0 | 0 | 0 | 0.88553 | 2.60779 | 2.78862 | 2.64118 | 1.00451 | -3.10862e-15 | -5.32907e-15 | 1.66533e-15 | 0 | 0 | 2.03114 | 1.80225 | 1.33015 | 0.0270786 | 0.0195415 | 0.0270786 | 0.0195415 | 0.86986 | 0 | 0 | 0
WallEx_09 | Toiture | WallEx_09 | WallEx_09 | Toiture | Elément porteur | Type ArchiCAD | Face extérieure | yes | 14.5548 | 2.03114 | 5.38527 | 5.38527 | 25.8948 | 25.8948 | 10.2377 | 10.2377 | 16.9 | -0.5 | 2.03114 | 29.3491 | 14.4496 | 14.66 | 22.4405 | 11.1926 | 10.2377 | 0 | 0 | 0 | 7 | 0 | 0 | 0 | 14.5548 | 29.9052 | 29.7765 | 30.2234 | 11.1 | 0 | 0 | 0 | 0 | 0 | 2.03114 | 29.3491 | 22.4405 | 0.4401 | 0.336637 | 0.4401 | 0.336637 | 14.4496 | 0 | 0 | 0
SW - 010 | Toiture | WallEx01 | SW - 010 | Toiture | Elément non porteur | Type ArchiCAD | Face extérieure | no | 68.6574 | 1.87813 | 25.4032 | 25.4032 | 126.901 | 4.89414 | 47.3389 | 1.88329 | 17.4 | 0 | 3.302 | 5.33867 | 68.8425 | 68.4722 | 4.44962 | 2.02647 | 1.88329 | 0 | 11 | 0 | 1 | 0 | 66 | 0 | 68.6574 | 138.208 | 127.078 | 129.301 | 47.4302 | 120.052 | 123.962 | 45.4556 | 0 | 0 | 1.84707 | 5.33867 | 4.44962 | 0.0800518 | 0.0667683 | 0.0800518 | 0.0667683 | 68.8425 | 132 | 0 | 0
WallEx02 | Toiture | WallEx02 | WallEx02 | Toiture | Elément porteur | Type ArchiCAD | Face extérieure | yes | 6.46411 | 2.62691 | 2.39172 | 2.39172 | 13.5735 | 13.5735 | 5.36486 | 5.36486 | 16.915 | -0.485 | 3.787 | 15.5328 | 6.6492 | 6.27903 | 11.6142 | 3.19578 | 5.36486 | 0 | 0 | 0 | 1 | 0 | 0 | 0 | 6.46411 | 13.8216 | 17.3744 | 17.375 | 6.42864 | 0 | 0 | -8.88178e-16 | 0.051238 | 0 | 2.61156 | 15.5328 | 11.6142 | 0.232992 | 0.172246 | 0.232992 | 0.172246 | 6.6492 | 0 | 0 | 0
WallEx_09 | Toiture | WallEx_09 | WallEx_09 | Toiture | Elément porteur | Type ArchiCAD | Face extérieure | yes | 23.8539 | 1.97114 | 8.82595 | 8.82595 | 41.641 | 41.641 | 16.3113 | 16.3113 | 16.96 | -0.44 | 1.97114 | 46.8153 | 24.0168 | 23.691 | 36.4667 | 13.2614 | 16.3113 | 0 | 0 | 0 | 5 | 0 | 0 | 0 | 23.8539 | 48.5708 | 47.3495 | 47.2658 | 17.5038 | 0 | 0 | 0 | 0 | 0.2 | 1.97114 | 46.8153 | 36.4667 | 0.70066 | 0.546977 | 0.70066 | 0.546977 | 23.6438 | 0 | 0 | 0
WallEx_09 | Toiture | WallEx_09 | WallEx_09 | Toiture | Elément porteur | Type ArchiCAD | Face extérieure | yes | 7.36232 | 2.03114 | 2.72406 | 2.72406 | 14.4254 | 14.4254 | 5.11751 | 5.11751 | 16.9 | -0.5 | 2.03114 | 15.4437 | 7.63761 | 7.08704 | 13.407 | 5.3924 | 5.11751 | 0 | 0 | 0 | 3 | 0 | 0 | 0 | 7.36232 | 15.66 | 16.1044 | 15.513 | 5.84924 | 0 | 0 | 0 | 0 | 0 | 2.03114 | 15.4437 | 13.407 | 0.231836 | 0.188422 | 0.231836 | 0.188422 | 7.63761 | 0 | 0 | 0
SW - 014 | Toiture | WallEx01 | SW - 014 | Toiture | Elément porteur | Type ArchiCAD | Face extérieure | yes | 7.4054 | 2.57567 | 2.74 | 2.74 | 18.2046 | 18.2046 | 6.58041 | 6.58041 | 16.9662 | -0.433762 | 4.38376 | 19.9414 | 7.77322 | 7.03758 | 16.4679 | 1.31325 | 6.58041 | 0 | 0 | 0 | 0 | 0 | 0 | 0 | 7.4054 | 15.8542 | 21.933 | 22.1722 | 8.15947 | 0 | 0 | 0 | 0 | 0 | 2.54458 | 19.9414 | 16.4679 | 0.299115 | 0.232223 | 0.299115 | 0.232223 | 7.77322 | 0 | 0 | 0 | Dégagement | 001
SW - 012 | Toiture | WallEx01 | SW - 012 | Toiture | Elément porteur | Type ArchiCAD | Face extérieure | yes | 20.018 | 1.94268 | 7.40665 | 7.40665 | 36.7913 | 0.353483 | 14.2994 | 0.197185 | 17.4 | 0 | 3.302 | 0.0599235 | 19.8351 | 20.2009 | 0.647042 | 0.102769 | 0.197185 | 0 | 2 | 0 | 1 | 0 | 20.2088 | 0 | 20.018 | 40.9263 | 44.1868 | 44.85 | 16.4718 | 34.3731 | 38.5025 | 14.1022 | 0 | 0 | 1.91162 | 0.0599235 | 0.647042 | 0.000896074 | 0.0104494 | 0.000896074 | 0.0104494 | 19.8351 | 40.4176 | 0 | 0
WALL_EX_03 | Toiture | Wall_Ex_03 | WALL_EX_03 | Toiture | Elément porteur | Type ArchiCAD | Face extérieure | yes | 7.67156 | 4.215 | 2.83848 | 2.83848 | 31.7312 | 31.7312 | 11.9687 | 11.9687 | 17.16 | -0.24 | 4.215 | 33.138 | 7.85562 | 7.48749 | 30.3243 | 5.57577 | 0 | 0 | 0 | 0 | 0 | 0 | 0 | 0 | 7.67156 | 16.2365 | 34.7207 | 39.8545 | 13.7964 | 0 | 0 | 0 | 2.90399e-11 | 0 | 4.215 | 0 | 0 | 0.495549 | 0.454863 | 0 | 0 | 8.04063 | 0 | 0 | 0
SW - 013 | Toiture | WallEx01 | SW - 013 | Toiture | Elément porteur | Type ArchiCAD | Face extérieure | yes | 2.26982 | 2.58124 | 0.839833 | 0.839833 | 5.15329 | 5.15329 | 1.97367 | 1.97367 | 16.96 | -0.44 | 3.905 | 5.63315 | 2.26964 | 2.27 | 4.67344 | 0.432138 | 1.97367 | 0 | 0 | 0 | 0 | 0 | 0 | 0 | 2.26982 | 5.58003 | 7.08019 | 7.07733 | 2.61914 | -1.62429e-08 | 0 | -2.42482e-10 | 0 | 0 | 2.56596 | 5.63315 | 4.67344 | 0.0844982 | 0.0701012 | 0.0844982 | 0.0701012 | 2.26964 | 0 | 0 | 0 | Dégagement | 001
WallEx_09 | Toiture | WallEx_09 | WallEx_09 | Toiture | Elément porteur | Type ArchiCAD | Face extérieure | yes | 0.208618 | 2.03114 | 0.0771886 | 0.0693809 | 0.401092 | 0.401092 | 0.137152 | 0.137152 | 16.9 | -0.5 | 2.03114 | 0.802184 | 0.394943 | 0.0222931 | 0 | 0.138321 | 0.137152 | 0 | 0 | 0 | 0 | 0 | 0 | 0 | 0.186325 | 1.3449 | 0 | 0.802184 | 0.140475 | 0 | 0 | 0 | 0 | 2.03114 | 2.03114 | 0.802184 | 0 | 0.0117751 | 0 | 0.0117751 | 0 | 0.394943 | 0 | 0 | 0
WALL_EX_03 | Etage | Wall_Ex_03 | WALL_EX_03 |  | Elément porteur | Type ArchiCAD | Face extérieure | yes | 7.20326 | 4.215 | 2.6652 | 2.6652 | 29.7676 | 27.4919 | 11.2161 | 10.346 | 17.16 | -2.19 | 4.215 | 28.0106 | 7.20493 | 7.20158 | 26.9732 | 4.86742 | 10.346 | 1 | 0 | 0 | 0 | 1 | 0 | 0 | 7.20326 | 15.4257 | 31.9162 | 31.9311 | 11.8117 | 2.19317 | 2.35817 | 0.870049 | 0 | 0 | 4.215 | 28.0106 | 26.9732 | 0.420155 | 0.404603 | 0.420155 | 0.404603 | 7.20493 | 0 | 2.1 | 0 | Local Tech. | 007
WALL_EX_03 | Etage | Wall_Ex_03 | WALL_EX_03 |  | Elément porteur | Type ArchiCAD | Face extérieure | yes | 5.60149 | 4.215 | 2.07255 | 2.07255 | 23.1766 | 23.1766 | 8.72294 | 8.72294 | 17.16 | -2.19 | 4.215 | 25.0614 | 5.96076 | 5.24221 | 21.2918 | 4.06632 | 8.72294 | 0 | 0 | 0 | 1 | 0 | 0 | 0 | 5.60149 | 12.2345 | 25.217 | 25.1246 | 9.3132 | 0 | 0 | 0 | 0 | 0 | 4.215 | 25.0614 | 21.2918 | 0.375949 | 0.31935 | 0.375949 | 0.31935 | 5.77576 | 0 | 0 | 0 | Local Tech. | 007
WALL_EX_03 | Etage | Wall_Ex_03 | WALL_EX_03 |  | Elément porteur | Type ArchiCAD | Face extérieure | yes | 5.27351 | 4.215 | 1.9512 | 1.9512 | 20.7405 | 20.7405 | 7.86527 | 7.86527 | 17.16 | -2.19 | 4.215 | 22.3145 | 5.45945 | 5.08758 | 19.1665 | 3.69798 | 7.86527 | 0 | 0 | 0 | 0 | 0 | 0 | 0 | 5.27351 | 11.4416 | 22.9197 | 23.0116 | 8.49728 | 0 | 0 | 0 | 6.41833e-10 | 0 | 4.215 | 22.3145 | 19.1665 | 0.334689 | 0.2875 | 0.334689 | 0.2875 | 5.45945 | 0 | 0 | 0 | Local Tech. | 007
WALL_EX_03 | Etage | Wall_Ex_03 | WALL_EX_03 |  | Elément porteur | Type ArchiCAD | Face extérieure | yes | 1.8547 | 4.215 | 0.686238 | 0.686238 | 7.66544 | 7.66544 | 2.88771 | 2.88771 | 17.16 | -2.19 | 4.215 | 7.86633 | 1.86627 | 1.84312 | 7.46454 | 1.34472 | 2.88771 | 0 | 0 | 0 | 0 | 0 | 0 | 0 | 1.8547 | 4.74241 | 9.32833 | 9.42862 | 3.47004 | 0 | 0 | 0 | 0 | 0 | 4.215 | 7.86633 | 7.46454 | 0.117974 | 0.111998 | 0.117974 | 0.111998 | 1.86627 | 0 | 0 | 0 | Local Tech. | 007
WALL_EX_03 | Etage | Wall_Ex_03 | WALL_EX_03 |  | Elément porteur | Mur | Centrer | yes | 19.2501 | 4.215 | 7.12255 | 7.12255 | 79.3777 | 79.3777 | 29.9531 | 29.9531 | 17.16 | -2.19 | 4.215 | 81.8107 | 19.4334 | 19.0669 | 76.9447 | 15.5094 | 29.9531 | 0 | 0 | 0 | 1 | 0 | 0 | 0 | 19.2501 | 39.391 | 81.9265 | 81.9117 | 30.3101 | 0 | 0 | 0 | 0 | 0 | 4.215 | 81.8107 | 76.9447 | 1.22716 | 1.13776 | 1.22716 | 1.13776 | 19.4351 | 0 | 0 | 0

# IfcWallStandardCase: 3.3-Refend: 2x béton + vide + enduit plâtre 2 faces 280 (4)
In: Etage
Description: Wall_Ex_03; Material: Finition int - Enduit plâtre 0.015 m, Struct. - B.A. coulé 0.1 m, Divers - Vide 0.05 m, Struct. - B.A. coulé 0.1 m, Finition int - Enduit plâtre 0.015 m
ArchiCADProperties - ID: WALL_EX_03; Calque: A-WALL-EXTR; Type: Mur; Verrouillé: no; Matériau de construction / Composite / Profil / Hachure: 3.3-Refend: 2x béton + vide + enduit plâtre 2 faces; Fonction structurelle: Elément porteur; Position: Extérieur; Classification d'lément: Type ArchiCAD; Etat de rénovation: Existant; Afficher sur filtre de rénovation: Tous les filtres appropriés; Type de structure: Composite; Matériau de construction / Composite / Profil: 3.3-Refend: 2x béton + vide + enduit plâtre 2 faces; Surface de face extérieure: 09 | Paint-02 Whitewash; Surface de face intérieure: 09 | Paint-02 Whitewash; Surface latérale: 09 | Paint-02 Whitewash; Angle d'inclinaison externe: 90 deg; Angle d'inclinaison interne: 90 deg; Type d'inclinaison de mur: Droit; Emplacement de ligne de référence: Face intérieure; Etage supérieur lié: Non lié; Option de géométrie: Uniforme
AC_Pset_RenovationAndPhasing - Renovation Status: Existing
Pset_WallCommon - LoadBearing: yes; IsExternal: yes
BaseQuantities - Height: 3.0609 m; Width: 0.28 m
ArchiCADQuantities - Altitude à Zéro du Projet: 17.16 m; Altitude à étage: -2.19 m; Hauteur: 3.0609 m; Epaisseur: 0.28 m; Nombre de Fenêtres: 0; Nombre de trous (Nombre d'ouvertures vides): 0; Largeur totale des Fenêtres: 0 m; Epaisseur du Mur à la fin: 0.28 m; Hauteur minimum du Mur: 0 m; Hauteur maximum du Mur: 3.0609 m; Epaisseur de couche de mur sur face extérieure: 0.015 m; Epaisseur de couche de mur sur face intérieure: 0.015 m; Epaisseur couche isolation: 0 m; Epaisseur couche d'air: 0 m; Hauteur de couche de mur minimum sur face extérieure: 0 m; Hauteur de couche de mur maximum sur face extérieure: 3.0609 m; Hauteur de couche de mur minimum sur face intérieure: 0 m; Hauteur de couche de mur maximum sur face intérieure: 3.0609 m; Décalage étage d'implantation: -2.19 m; Décalage supérieur: 0 m; Surface des fenêtres dans le mur: 0 m2; Surface des baies libres dans le mur: 0 m2; Volume de poteaux: 0 m3
Name | Length (m) = Longueur du Mur au centre (m) = Longueur moyenne (m) | GrossFootprintArea (m2) = NetFootprintArea (m2) = Superficie (m2) = Surface du Mur (m2) | GrossSideArea (m2) | NetSideArea (m2) | GrossVolume (m3) | NetVolume (m3) = Volume net (m3) = Volume conditionnel (m3) | Superficie de surface (m2) = Surface de mur nette sur face extérieure (m2) = Surface conditionnelle sur face extérieure (m2) | Longueur de mur sur face extérieure (m) = Longueur conditionnelle sur face extérieure (m) | Longueur de mur sur face intérieure (m) = Longueur conditionnelle sur face intérieure (m) | Surface de mur nette sur face intérieure (m2) = Surface conditionnelle sur face intérieure (m2) | Surface nette des arêtes (m2) | Nombre de Portes = Largeur totale des Portes (m) | Nombre de Poteaux | Périmètre du Mur (m) | Surface brute de mur sur face intérieure (m2) | Surface brute de mur sur face extérieure (m2) | Volume brut du Mur (m3) | Surface analytique des ouvertures sur face intérieure (m2) = Surface analytique des ouvertures sur face extérieure (m2) | Volume analytique des ouvertures dans le Mur (m3) | Volume de couche de mur sur face extérieure (m3) = Volume de couche de mur conditionnelle sur face extérieure (m3) | Volume de couche de mur sur face intérieure (m3) = Volume de couche de mur conditionnelle sur face intérieure (m3) | Longueur de ligne de référence (m) | Surface des portes dans le mur (m2)
WALL_EX_03 | 5.77621 | 1.61734 | 16.9914 | 16.9914 | 4.86099 | 4.86099 | 17.3131 | 6.05644 | 5.49598 | 16.6698 | 3.07582 | 0 | 2 | 12.3447 | 18.5369 | 18.5381 | 5.1905 | 0 | 0 | 0.259725 | 0.250047 | 6.05603 | 0
WALL_EX_03 | 5.77002 | 1.6156 | 16.7528 | 14.5648 | 4.98681 | 4.33293 | 13.798 | 5.49022 | 6.04981 | 15.3317 | 2.85356 | 1 | 0 | 12.3317 | 18.5179 | 18.5191 | 5.18518 | 2.18798 | 0.653885 | 0.20697 | 0.229975 | 6.04981 | 2.1
WALL_EX_03 | 3.89069 | 1.08939 | 11.195 | 11.195 | 3.31517 | 3.31517 | 10.5044 | 3.61235 | 4.16903 | 11.8856 | 2.06207 | 0 | 1 | 8.571 | 12.761 | 12.7712 | 3.5745 | 0 | 0 | 0.157563 | 0.180358 | 3.88901 | 0
WALL_EX_03 | 3.95963 | 1.1087 | 11.389 | 11.389 | 3.37165 | 3.37165 | 10.6944 | 3.67794 | 4.24131 | 12.0835 | 2.0986 | 0 | 1 | 8.7136 | 12.9822 | 12.972 | 3.63359 | 0 | 0 | 0.16042 | 0.181223 | 3.96128 | 0

# IfcWindow: F devanture 3 15 (12)
In: Rez de chaussée
Type - OperationType: USERDEFINED; ParameterTakesPrecedence: no; Sizeable: no
OverallWidth: 1.2 m; Material: Background Fill-International (3), 05 | Aluminum
ArchiCADProperties - ID: WD - 003; Etage d'implantation: Rez de chaussée; Calque: A-WALL-EXTR; Type: Fenêtre; Verrouillé: no; Nom Elément de Bibliothèque: F devanture 3 15; Matériau de construction / Composite / Profil / Hachure: Background; Fonction structurelle: Non défini; Position: Non défini; Classification d'lément: Type ArchiCAD; Etat de rénovation: Existant; Afficher sur filtre de rénovation: Tous les filtres appropriés; Orientation: G; Structure mur: 1.2-Mur ext: revét ext + isol ext + maçonnerie + enduit
AC_Pset_F_devanture_3_15 - Contours Mur (0-Sans,1-Tout,2-Côté,3-Longueur): 0; Point ch.0-Non,1-2D,2-3D,3-Tous: 3; Afficher points chauds 2D en 3D: yes; Option affichage en plan: 3; Angle de position baie: 0 deg; Trou a matière bord de mur: yes; Mat. trémie coupée par courbe: no; Type de mur: 1; Type de direction de mur: 0; Motif de hachure démolition: 0; Stylo démolition: Transparent; Stylo fond Démolition: Transparent; Niveau de paramétrage: Elevé; Afficher points chaud éditables: yes; Afficher ébrasure sur symbole: Toujours; Niveau de détail 2D: Selon échelle; Type division panneau: Nombre de divisions; Nombre divisions horizontales: 1; Nombre meneaux horizontaux: 0; Nombre divisions vert. inf.: 2; Nbre meneaux vert. inf.: 1; Nombre divisions vert. milieu: 1; Nombre meneaux vert. milieu: 0; Nombre divisions vert. sup.: 2; Nombre meneaux vert. sup.: 1; Style cadre sur côté gauche: Meneaux visibles; Style cadre sur côté droit: Meneaux visibles; Epaisseur cadre=Epaisseur mur: no; Joint gauche: no; Joint droit: no; Joint inférieur: no; Joint supérieur: no; Style cadre sur men.: Meneaux visibles; Prof. meneau=Prof. cadre: no; Espace vitrage=1/2 Prof. meneau: no; Type ébrasure (gs_reveal_type_new): Pas d'ébrasure - arête; Type ébrasure (gs_reveal_type_int): 1; Type ébrasure extérieure: No Reveal; Type ébrasure intérieure: No Reveal; Angle côté gauche: 20 deg; Angle côté droit: 20 deg; Angle côté supérieur: 20 deg; Angle côté inférieur: 20 deg; Utiliser composant finition mur: no; Tourner autom. plâtre côté opp.: yes; Tourner plâtre côté opposé: 0; Tourner autom. plâtre côté réf.: yes; Tourner plâtre côté référence: 0; Afficher en 3D: no; Type de fermeture (gs_closure_type): Pas de fermeture; Type de fermeture (gs_closure_type_int): 1; Tourner couche sur côté: Both; Nbre de couches retournées: 1; Num. à partir de: Côté de référence; Placer fermeture sur côté 2: yes; Placer fermeture sur côté 1: yes; Placer fermeture en haut: no; Placer fermeture en bas: no; Placer fermeture sur couche: 1; Placer fermeture de côté (gs_cc_dutch_ClosureToSide): 1; Tourner couche sur fermeture: no; Insérer bande d'isolation: yes; Afficher bande d'isolation: yes; Stylo contour (gs_penJoint): Ouvertures - Coupé non structurel; Type de ligne de contour (gs_ltJoint): 1; Motif de hachure (gs_fillJoint): 07 | Insulation Rigid; Stylo hachure (gs_penJointFg): Général - Dessin; Stylo fond de hachure (gs_penJointBg): Eléments 2D - Dessin; Matière personnalisée: no; Matière (gs_cc_dutch_matJoint): 06 | W Pine H; Stylo contour (gs_penPlug): Ouvertures - Coupé non structurel; Type de ligne de contour (gs_ltPlug): 1; Motif de hachure (gs_fillPlug): 07 | Insulation Rigid; Stylo hachure (gs_penPlugFg): Général - Dessin; Stylo fond de hachure (gs_penPlugBg): Eléments 2D - Dessin; Côté montant édité: Edit Both Jambs; Côté mur édité: Reference Side; Numéro couche éditée: 1. Skin; Tourner couche: no; Considérer couches comme plâtre: no; Tourner épaiseur: Original; Orientation hachure: Original; Ligne de séparation tournant: no; Stylo ligne de séparation: Général - Dessin; Dernier côté sélectionné: no; Méthode fermeture changée auto.: no; Stylo cadre (gs_pen_2D): Ouvertures - Coupé structurel; Stylo vitrage (gs_pen_glass): Ouvertures - Coupé non structurel; Ligne de contour de mur: Sans; Type ligne contour int. mur: 1; Type ligne contour ext. mur: 1; Stylo ligne contour de mur: Ouvertures - Général; Utiliser hachures: yes; Type hachure non coupée: Background Fill-International; Stylo hachure non coupée: Fond - Couleur 1; Stylo fond de hachure non coupé: Fond - Couleur 1; Motif de hachure cadre: 05 | Aluminum; Stylo hachure cadre: Ouvertures - Hachures coupées; Stylo fond de hachure cadre: Fond - Couleur 1; Motif hachure section vitre: Background Fill-International; Stylo hachure section vitre: Fond - Couleur 1; Stylo fond hachure section vitre: Fond - Couleur 1; Motif hachure symbole en plan: Background Fill-International; Stylo hachure symbole en plan: Fond - Couleur 1; Stylo fond hachure symbole plan: Fond - Couleur 1; Joint élément cadre: Assemblage à onglet; Stylo cadre (gs_frame_pen): Ouvertures - Général; Stylo panneaux: Ouvertures - Général; Hachure coupe cadre: 05 | Aluminum; Hachure coupe meneau: 05 | Aluminum; Toutes matières identiques: no; Matière (gs_mat): 05 | Stainless Reflective; Matière cadre: 05 | Aluminum Plain; Matière cadre central: 05 | Aluminum Plain; Matière vitrage: 08 | Glass-Clear; Coin gauche: no; Angle gauche: 90 deg; Coin droit: no; Angle droit: 90 deg; Symbole en plan Linteau/seuil: no; Type ligne symb. Linteau/seuil: 21; Stylo symbole Linteau/seuil: Texte d'annotation - Général; Coût: 0; Surface totale vitrage: 0; Périmètre total vitrage: 0; Type de groupe: Default Objects; Numéro de série: Off; Poids de l'objet: 0; Unité poids de l'objet: kg; Opération IFC (ifc_optype): 10
AC_Pset_RenovationAndPhasing - Renovation Status: Existing
BaseQuantities - Width: 1.2 m; Depth: 0.37 m
ArchiCADQuantities - Largeur: 1.2 m; Epaisseur: 0.08 m; Largeur ouverture côté ébrasure: 1.2 m; Largeur ouverture côté opposé ébrasure: 1.2 m; Largeur nominale de l'ouverture côté ébrasure: 1.2 m; Largeur nominale de l'ouverture côté opposée ébrasure: 1.2 m; Epaisseur de Mur: 0.37 m
AC_Equantity_F_devanture_3_15 - Largeur: 1.2 m; Dimension Z: 1 m; Niveau inférieur: 1 m; Niveau supérieur: 0 m; Tolérance: 0 m; Largeur premier panneau (0-sans): 0 m; Largeur dernier panneau (0-sans): 0 m; Elévation rampe centrale (0-sans): 0 m; Hauteur panneau sup. (0-sans): 0 m; Larg. div. horizontale (0-sans): 0.3 m; Larg. div. vert. inf. (0-sans): 0.3 m; Larg. div. vert. centre (0-sans): 0.3 m; Larg. div. vert. sup. (0-sans): 0.3 m; Hauteur imposte: 0 m; Epaisseur cadre: 0.08 m; Largeur cadre: 0.04 m; Largeur rampe centrale: 0.15 m; Largeur rampe inférieure: 0.15 m; Largeur cadre sur côté gauche: 0.04 m; Largeur cadre sur côté droit: 0.04 m; Largeur inférieure cadre: 0.15 m; Largeur supérieure cadre: 0.04 m; Largeur meneau horizontal: 0.03 m; Profondeur meneau horizontal: 0.05 m; Largeur meneau vertical: 0.03 m; Profondeur meneau vertical: 0.05 m; Epaisseur châssis: 0.0500063 m; Largeur châssis: 0.05 m; Epaisseur vitrage: 0.01 m; Espace libre vitré: 0.01 m; Assemblage vitrage: 0.01 m; Dépassement ouverture gauche: 0 m; Dépassement ouverture droite: 0 m; Dépassement ouverture supérieur: 0 m; Dépassement ouverture inférieur: 0 m; Profondeur ébrasure : (gs_wido_sill): 0 m; Profondeur ébrasure : (AC_wido_sill): 0 m; Profondeur montant gauche: 0.06 m; Profondeur montant droit: 0.06 m; Profondeur montant gauche int. (gs_reveal_splayed_innerLeft): 0.06 m; Profondeur montant droit int. (gs_reveal_splayed_innerRight): 0.06 m; Profondeur montant gauche int. (gs_reveal_double_innerLeft): 0.06 m; Profondeur montant droit int. (gs_reveal_double_innerRight): 0.06 m; Profondeur montant linteau: 0.06 m; Profondeur montant appui: 0 m; Profondeur linteau int. (gs_reveal_splayed_innerTop): 0.06 m; Profondeur appui int. (gs_reveal_splayed_innerBottom): 0.06 m; Profondeur linteau int. (gs_reveal_double_innerTop): 0.06 m; Profondeur appui int. (gs_reveal_double_innerBottom): 0 m; Profondeur montant ext.: 0.08 m; Limite épaisseur plâtre: 0.04 m; Distance de couche / fermeture: 0 m; Largeur tasseau: 0.038 m; Epaisseur tasseau: 0.1 m; Epaisseur bande: 0.025 m; Largeur profilé: 0.075 m; Epaisseur personnalisée: 0.015 m; Dépassement couche prof. cadre: 0 m; Dépass.ouverture gauche: 0 m; Dépass.ouverture à droite: 0 m; Dépass.ouverture supérieur: 0 m; Dépass.ouverture inférieur: 0 m
Name | OverallHeight (m) = Height (m) = ArchiCADQuantities, Hauteur (m) = Hauteur ouverture côté ébrasure (m) = Hauteur ouverture côté opposé ébrasure (m) = Hauteur nominale de l'ouverture côté ébrasure (m) = Hauteur nominale de l'ouverture côté opposée ébrasure (m) = AC_Equantity_F_devanture_3_15, Hauteur (m) | Taille L x H nominale | Taille L x H x E nominale | Stylo meneau | Stylo vitrage (gs_glass_pen) | Matière meneau horizontal = Matière meneau vertical | Opération IFC (ifc_optypestr) | GrossArea (m2) = Area (m2) = Surface ouverture côté ébrasure (m2) = Surface ouverture côté opposé ébrasure (m2) = Surface nominale de l'ouverture P/F côté ébrasure (m2) = Surface nominale de l'ouverture P/F côté opposé ébrasure (m2) = Surface nominale ouverture P/F (m2) | Perimeter (m) | Volume (m3) = Volume net (m3) = Volume ouverture (m3) | Altitude à Zéro du Projet (m) = Altitude à étage (m) = Hauteur appui à étage actuel (m) | Superficie de surface (m2) | Hauteur nominale seuil (m) = Hauteur seuil côté ébrasure (m) = Hauteur seuil côté opposé ébrasure (m) = Valeur Appui ou Linteau (m) | Hauteur nominale linteau (m) = Hauteur linteau côté ébrasure (m) = Hauteur linteau côté opposé ébrasure (m) | Volume nominal ouverture (m3)
4 x WD - 003 | 1.38165 | 47,24"x54,40" | 47,24"x54,40"x14,57" | Ouvertures - Coupé non structurel | Ouvertures - Général | 05 / Aluminum Plain | Other | 1.65798 | 5.1633 | 0.0392131 | 2.7 | 4.2129 | 2.7 | 4.08165 | 0.613453 | ArchiCADProperties - Nom de Zone: Surface expoitation; Numéro de Zone: 007; De Zone: Surface expoitation; De la Zone numéro: 007
2 x WD - 003 | 0.5 | 47,24"x19,69" | 47,24"x19,69"x14,57" | Ouvertures - Coupé non structurel | Ouvertures - Général | 05 / Aluminum Plain | Other | 0.6 | 3.4 | 0.023696 | 2.2 | 1.79718 | 2.2 | 2.7 | 0.222 | ArchiCADProperties - Nom de Zone: Surface expoitation; Numéro de Zone: 007; De Zone: Surface expoitation; De la Zone numéro: 007
4 x WD - 003 | 1.38165 | 47,24"x54,40" | 47,24"x54,40"x14,57" | A construire - Coupe | A construire - Coupe | Paint-05 | Autre | 1.65798 | 5.1633 | 0.0392131 | 2.8 | 4.2129 | 2.7 | 4.08165 | 0.613453
2 x WD - 003 | 0.5 | 47,24"x19,69" | 47,24"x19,69"x14,57" | A construire - Coupe | A construire - Coupe | Paint-05 | Autre | 0.6 | 3.4 | 0.023696 | 2.3 | 1.79718 | 2.2 | 2.7 | 0.222

# IfcWindow: F devanture 4 15 (4)
In: Rez de chaussée
Type - OperationType: USERDEFINED; ParameterTakesPrecedence: no; Sizeable: no
OverallHeight: 2.7 m; OverallWidth: 1.2 m; Material: Background Fill-International (3), 05 | Aluminum
ArchiCADProperties - ID: WD - 003; Etage d'implantation: Rez de chaussée; Calque: A-WALL-EXTR; Type: Fenêtre; Verrouillé: no; Nom Elément de Bibliothèque: F devanture 4 15; Matériau de construction / Composite / Profil / Hachure: Background; Fonction structurelle: Non défini; Position: Non défini; Classification d'lément: Type ArchiCAD; Etat de rénovation: Existant; Afficher sur filtre de rénovation: Tous les filtres appropriés; Orientation: G; Structure mur: 1.2-Mur ext: revét ext + isol ext + maçonnerie + enduit; Taille L x H nominale: 47,24"x106,30"; Taille L x H x E nominale: 47,24"x106,30"x14,57"
AC_Pset_F_devanture_4_15 - Contours Mur (0-Sans,1-Tout,2-Côté,3-Longueur): 0; Point ch.0-Non,1-2D,2-3D,3-Tous: 3; Afficher points chauds 2D en 3D: yes; Option affichage en plan: 3; Angle de position baie: 0 deg; Trou a matière bord de mur: yes; Mat. trémie coupée par courbe: no; Type de mur: 1; Type de direction de mur: 0; Motif de hachure démolition: 0; Stylo démolition: Transparent; Stylo fond Démolition: Transparent; Niveau de paramétrage: Elevé; Afficher points chaud éditables: yes; Afficher ébrasure sur symbole: Toujours; Niveau de détail 2D: Selon échelle; Type division panneau: Nombre de divisions; Nombre divisions horizontales: 1; Nombre meneaux horizontaux: 0; Nombre divisions vert. inf.: 2; Nbre meneaux vert. inf.: 1; Nombre divisions vert. milieu: 1; Nombre meneaux vert. milieu: 0; Nombre divisions vert. sup.: 1; Nombre meneaux vert. sup.: 0; Style cadre sur côté gauche: Meneaux visibles; Style cadre sur côté droit: Meneaux visibles; Epaisseur cadre=Epaisseur mur: no; Joint gauche: no; Joint droit: no; Joint inférieur: no; Joint supérieur: no; Style cadre sur men.: Meneaux visibles; Prof. meneau=Prof. cadre: no; Espace vitrage=1/2 Prof. meneau: no; Type ébrasure (gs_reveal_type_new): Pas d'ébrasure - arête; Type ébrasure (gs_reveal_type_int): 1; Type ébrasure extérieure: No Reveal; Type ébrasure intérieure: No Reveal; Angle côté gauche: 20 deg; Angle côté droit: 20 deg; Angle côté supérieur: 20 deg; Angle côté inférieur: 20 deg; Utiliser composant finition mur: no; Tourner autom. plâtre côté opp.: yes; Tourner plâtre côté opposé: 0; Tourner autom. plâtre côté réf.: yes; Tourner plâtre côté référence: 0; Afficher en 3D: no; Type de fermeture (gs_closure_type): Pas de fermeture; Type de fermeture (gs_closure_type_int): 1; Tourner couche sur côté: Both; Nbre de couches retournées: 1; Num. à partir de: Côté de référence; Placer fermeture sur côté 2: yes; Placer fermeture sur côté 1: yes; Placer fermeture en haut: no; Placer fermeture en bas: no; Placer fermeture sur couche: 1; Placer fermeture de côté (gs_cc_dutch_ClosureToSide): 1; Tourner couche sur fermeture: no; Insérer bande d'isolation: yes; Afficher bande d'isolation: yes; Stylo contour (gs_penJoint): Ouvertures - Coupé non structurel; Type de ligne de contour (gs_ltJoint): 1; Motif de hachure (gs_fillJoint): 07 | Insulation Rigid; Stylo hachure (gs_penJointFg): Général - Dessin; Stylo fond de hachure (gs_penJointBg): Eléments 2D - Dessin; Matière personnalisée: no; Matière (gs_cc_dutch_matJoint): 06 | W Pine H; Stylo contour (gs_penPlug): Ouvertures - Coupé non structurel; Type de ligne de contour (gs_ltPlug): 1; Motif de hachure (gs_fillPlug): 07 | Insulation Rigid; Stylo hachure (gs_penPlugFg): Général - Dessin; Stylo fond de hachure (gs_penPlugBg): Eléments 2D - Dessin; Côté montant édité: Edit Both Jambs; Côté mur édité: Reference Side; Numéro couche éditée: 1. Skin; Tourner couche: no; Considérer couches comme plâtre: no; Tourner épaiseur: Original; Orientation hachure: Original; Ligne de séparation tournant: no; Stylo ligne de séparation: Général - Dessin; Dernier côté sélectionné: no; Méthode fermeture changée auto.: no; Stylo cadre (gs_pen_2D): Ouvertures - Coupé structurel; Stylo vitrage (gs_pen_glass): Ouvertures - Coupé non structurel; Ligne de contour de mur: Sans; Type ligne contour int. mur: 1; Type ligne contour ext. mur: 1; Stylo ligne contour de mur: Ouvertures - Général; Utiliser hachures: yes; Type hachure non coupée: Background Fill-International; Stylo hachure non coupée: Fond - Couleur 1; Stylo fond de hachure non coupé: Fond - Couleur 1; Motif de hachure cadre: 05 | Aluminum; Stylo hachure cadre: Ouvertures - Hachures coupées; Stylo fond de hachure cadre: Fond - Couleur 1; Motif hachure section vitre: Background Fill-International; Stylo hachure section vitre: Fond - Couleur 1; Stylo fond hachure section vitre: Fond - Couleur 1; Motif hachure symbole en plan: Background Fill-International; Stylo hachure symbole en plan: Fond - Couleur 1; Stylo fond hachure symbole plan: Fond - Couleur 1; Joint élément cadre: Assemblage à onglet; Stylo cadre (gs_frame_pen): Ouvertures - Général; Stylo panneaux: Ouvertures - Général; Hachure coupe cadre: 05 | Aluminum; Hachure coupe meneau: 05 | Aluminum; Toutes matières identiques: no; Matière (gs_mat): 05 | Stainless Reflective; Matière cadre: 05 | Aluminum Plain; Matière cadre central: 05 | Aluminum Plain; Matière vitrage: 08 | Glass-Clear; Coin gauche: no; Angle gauche: 90 deg; Coin droit: no; Angle droit: 90 deg; Symbole en plan Linteau/seuil: no; Type ligne symb. Linteau/seuil: 21; Stylo symbole Linteau/seuil: Texte d'annotation - Général; Coût: 0; Surface totale vitrage: 0; Périmètre total vitrage: 0; Type de groupe: Default Objects; Numéro de série: Off; Poids de l'objet: 0; Unité poids de l'objet: kg; Opération IFC (ifc_optypestr): Autre; Opération IFC (ifc_optype): 10
AC_Pset_RenovationAndPhasing - Renovation Status: Existing
BaseQuantities - GrossArea: 3.24 m2; Height: 2.7 m; Width: 1.2 m; Perimeter: 7.8 m; Area: 3.24 m2; Volume: 0.065552 m3; Depth: 0.37 m
ArchiCADQuantities - Hauteur: 2.7 m; Superficie de surface: 8.03238 m2; Volume net: 0.065552 m3; Largeur: 1.2 m; Epaisseur: 0.08 m; Hauteur nominale seuil: 0 m; Hauteur seuil côté ébrasure: 0 m; Hauteur seuil côté opposé ébrasure: 0 m; Hauteur nominale linteau: 2.7 m; Hauteur linteau côté ébrasure: 2.7 m; Hauteur linteau côté opposé ébrasure: 2.7 m; Largeur ouverture côté ébrasure: 1.2 m; Largeur ouverture côté opposé ébrasure: 1.2 m; Hauteur ouverture côté ébrasure: 2.7 m; Hauteur ouverture côté opposé ébrasure: 2.7 m; Surface ouverture côté ébrasure: 3.24 m2; Surface ouverture côté opposé ébrasure: 3.24 m2; Largeur nominale de l'ouverture côté ébrasure: 1.2 m; Largeur nominale de l'ouverture côté opposée ébrasure: 1.2 m; Hauteur nominale de l'ouverture côté ébrasure: 2.7 m; Hauteur nominale de l'ouverture côté opposée ébrasure: 2.7 m; Surface nominale de l'ouverture P/F côté ébrasure: 3.24 m2; Surface nominale de l'ouverture P/F côté opposé ébrasure: 3.24 m2; Volume ouverture: 0.065552 m3; Surface nominale ouverture P/F: 3.24 m2; Volume nominal ouverture: 1.1988 m3; Valeur Appui ou Linteau: 0 m; Epaisseur de Mur: 0.37 m
AC_Equantity_F_devanture_4_15 - Largeur: 1.2 m; Hauteur: 2.7 m; Dimension Z: 1 m; Niveau inférieur: 1 m; Niveau supérieur: 0 m; Tolérance: 0 m; Largeur premier panneau (0-sans): 0 m; Largeur dernier panneau (0-sans): 0 m; Elévation rampe centrale (0-sans): 0 m; Larg. div. horizontale (0-sans): 0.3 m; Larg. div. vert. inf. (0-sans): 0.3 m; Larg. div. vert. centre (0-sans): 0.3 m; Larg. div. vert. sup. (0-sans): 0.3 m; Hauteur imposte: 0 m; Epaisseur cadre: 0.08 m; Largeur cadre: 0.04 m; Largeur rampe centrale: 0.15 m; Largeur rampe inférieure: 0.15 m; Largeur cadre sur côté gauche: 0.04 m; Largeur cadre sur côté droit: 0.04 m; Largeur inférieure cadre: 0.15 m; Largeur supérieure cadre: 0.04 m; Largeur meneau horizontal: 0.03 m; Profondeur meneau horizontal: 0.05 m; Largeur meneau vertical: 0.03 m; Profondeur meneau vertical: 0.05 m; Epaisseur châssis: 0.0500063 m; Largeur châssis: 0.05 m; Epaisseur vitrage: 0.01 m; Espace libre vitré: 0.01 m; Assemblage vitrage: 0.01 m; Dépassement ouverture gauche: 0 m; Dépassement ouverture droite: 0 m; Dépassement ouverture supérieur: 0 m; Dépassement ouverture inférieur: 0 m; Profondeur ébrasure : (gs_wido_sill): 0 m; Profondeur ébrasure : (AC_wido_sill): 0 m; Profondeur montant gauche: 0.06 m; Profondeur montant droit: 0.06 m; Profondeur montant gauche int. (gs_reveal_splayed_innerLeft): 0.06 m; Profondeur montant droit int. (gs_reveal_splayed_innerRight): 0.06 m; Profondeur montant gauche int. (gs_reveal_double_innerLeft): 0.06 m; Profondeur montant droit int. (gs_reveal_double_innerRight): 0.06 m; Profondeur montant linteau: 0.06 m; Profondeur montant appui: 0 m; Profondeur linteau int. (gs_reveal_splayed_innerTop): 0.06 m; Profondeur appui int. (gs_reveal_splayed_innerBottom): 0.06 m; Profondeur linteau int. (gs_reveal_double_innerTop): 0.06 m; Profondeur appui int. (gs_reveal_double_innerBottom): 0 m; Profondeur montant ext.: 0.08 m; Limite épaisseur plâtre: 0.04 m; Distance de couche / fermeture: 0 m; Largeur tasseau: 0.038 m; Epaisseur tasseau: 0.1 m; Epaisseur bande: 0.025 m; Largeur profilé: 0.075 m; Epaisseur personnalisée: 0.015 m; Dépassement couche prof. cadre: 0 m; Dépass.ouverture gauche: 0 m; Dépass.ouverture à droite: 0 m; Dépass.ouverture supérieur: 0 m; Dépass.ouverture inférieur: 0 m
Name | Stylo meneau | Stylo vitrage (gs_glass_pen) | Matière meneau horizontal = Matière meneau vertical | Altitude à Zéro du Projet (m) = Altitude à étage (m) = Hauteur appui à étage actuel (m) | Hauteur panneau sup. (0-sans) (m)
WD - 003 | Ouvertures - Coupé non structurel | Ouvertures - Général | 05 / Aluminum Plain | 0 | 0.48 | ArchiCADProperties - Nom de Zone: Surface expoitation; Numéro de Zone: 007; De Zone: Surface expoitation; De la Zone numéro: 007
WD - 003 | Ouvertures - Coupé non structurel | Ouvertures - Général | 05 / Aluminum Plain | 0 | 0.46 | ArchiCADProperties - Nom de Zone: Surface expoitation; Numéro de Zone: 007; De Zone: Surface expoitation; De la Zone numéro: 007
2 x WD - 003 | A construire - Coupe | A construire - Coupe | Paint-05 | 0.1 | 0.6

# IfcWindow: Fenêtre 18 (15)
In: R+2
Type - OperationType: DOUBLE_PANEL_HORIZONTAL; ParameterTakesPrecedence: no; Sizeable: no
Type - Propriétés Doublure Fenêtre - LiningDepth: 0.05 m; LiningThickness: 0.05 m; TransomThickness: 0.05 m; FirstTransomOffset: 0.766667
Type - Propriétés Panneau Fenêtre - Panneau1 - OperationType: FIXEDCASEMENT; PanelPosition: TOP
Type - Propriétés Panneau Fenêtre - Panneau2 - OperationType: FIXEDCASEMENT; PanelPosition: BOTTOM
Description: Window_1200; OverallHeight: 1.5 m; OverallWidth: 1.2 m; Material: Background Fill-International (10), Air Space (2), 07 | Insulation Rigid
ArchiCADProperties - ID: Window_1200; Etage d'implantation: R+2; Nom de Zone: Plateau bureaux; Numéro de Zone: 005; Calque: A-WALL-EXTR; Type: Fenêtre; Verrouillé: no; Nom Elément de Bibliothèque: Fenêtre 18; Matériau de construction / Composite / Profil / Hachure: Background; Fonction structurelle: Non défini; Position: Non défini; Classification d'lément: Type ArchiCAD; Etat de rénovation: Existant; Afficher sur filtre de rénovation: Tous les filtres appropriés; De Zone: Plateau bureaux; De la Zone numéro: 005; Dimensions ébrasure: 47,24"x59,06"; Dimensions trou mur: 47,24"x59,06"; Dimensions unité: 47,24"x59,06"; Structure mur: 1.2-Mur ext: revét ext + isol ext + maçonnerie + enduit; Taille L x H nominale: 47,24"x59,06"; Taille L x H x E nominale: 47,24"x59,06"x14,57"
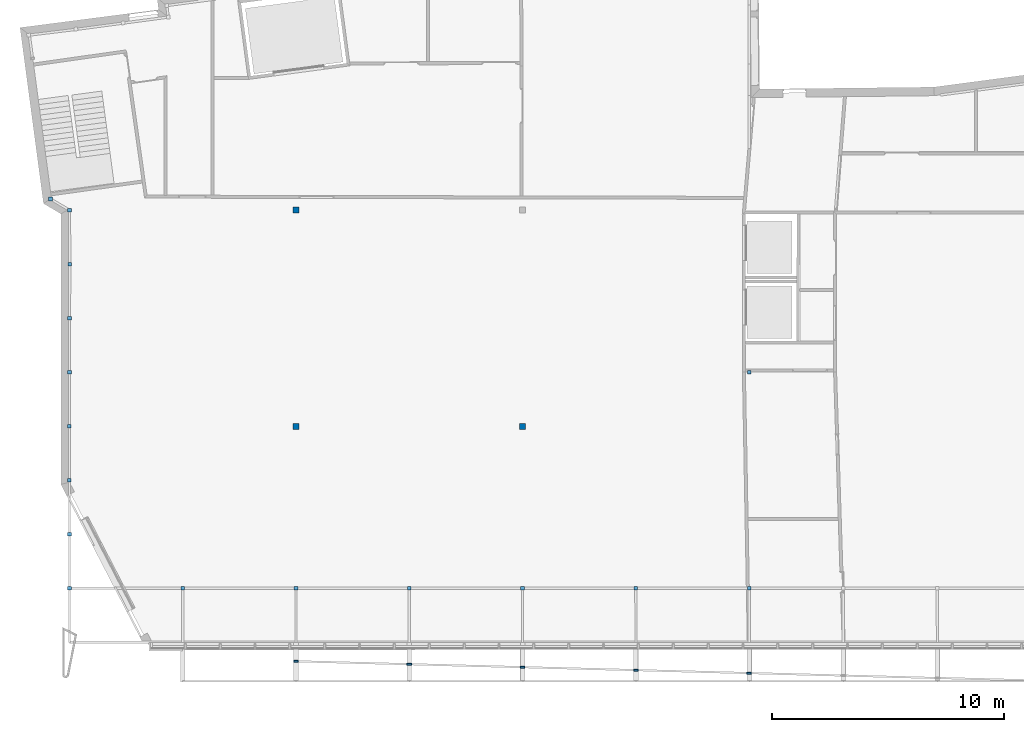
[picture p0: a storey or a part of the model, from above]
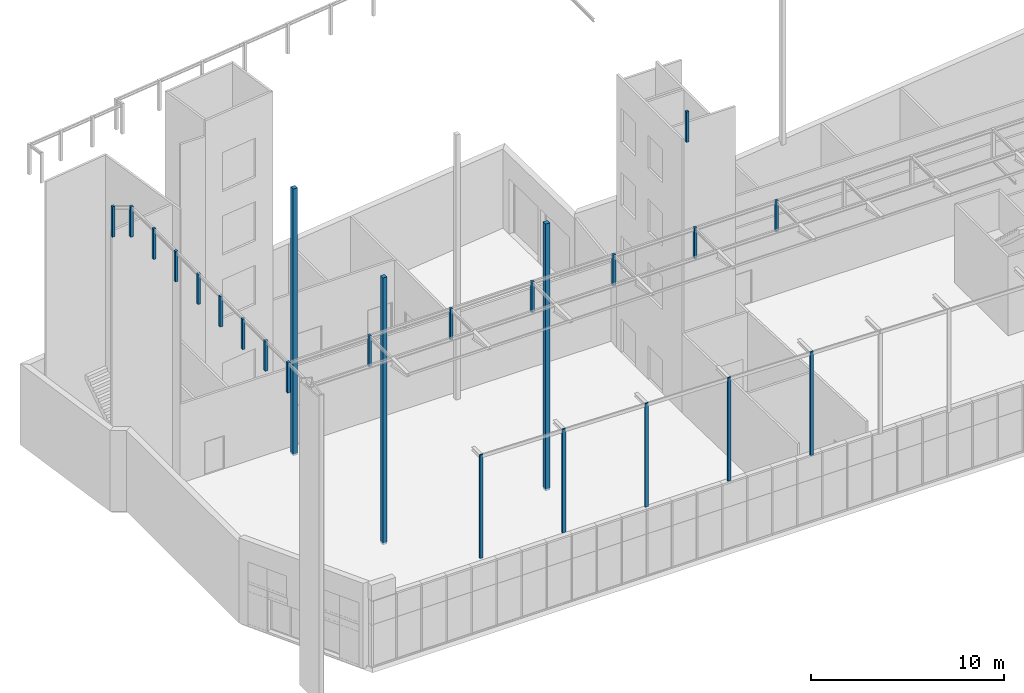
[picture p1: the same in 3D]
Properties of the parts of a building model (IFC2X3), part 18 of 19

# IfcWindow: Fenêtre horizontale à châssis multiples 18 (8)
AC_Pset_Fenêtre_horizontale_à_châssis_multiples_18 - Contours Mur (0-Sans,1-Tout,2-Côté,3-Longueur): 0; Point ch.0-Non,1-2D,2-3D,3-Tous: 3; Option affichage en plan: 3; Angle de position baie: 0 deg; Trou reprend surface latérale de mur: yes; Division de surface de trou courbée: no; Afficher points chauds 2D en 3D: yes; Type de mur: 1; Type de direction de mur: 1; Fonction de debug Fenêtre Angle: no; Placement (1=Angle, 0=Centre): no; Basculer: no; Démolition / Nouvelle constr.: 1; Nouveau motif de hachure de mur: Masonry Block; Nouveau stylo de hachure de mur: Général - Dessin; Nouveau stylo fond hachure mur: Fond - Couleur 1; Afficher nouv. constr. sur mur: no; Type de ligne démolition: 4; Aff. param. Démolition/Nouveau: no; Fonction Fenêtre Angle: yes; Angle Murs: 90 deg; Murs connectés d'épaiss. diff.: no; Poteau d'angle: no; Angle gauche:: no; Angle coin gauche: 90 deg; Murs connectés épaiss. diff. G: no; Angle droit: no; Angle coin droit: 90 deg; Murs connectés épaiss. diff. D: no; Type connexion angle droite: 1; Type connexion angle: 1; Entièrement éditable: yes; Niveau de détail 2D: 2; Afficher ébrasure sur symbole: 2; Niveau de détail 3D: 2; Activer niveau détail 3D: 14; Taille nominale: 0; Taille trou comme taille nominale: yes; Taille ébrasure comme nominale: no; Taille unité comme nominale: no; Conserver valeur de taille nominale en changeant: no; Nombre de panneaux (gs_panes_number): 1; Multiplier unité: yes; Nombre de copies: 3; Conserver distance d'axe: yes; Configuration panneaux: Panneaux uniformes; Panneaux horizontaux: 1; Largeur cadre uniforme: yes; Châssis uniformes: no; Direction vitrage fixe (FixGlassDir): Par direction d'ouverture; Direction vitrage fixe (FixGlassDir_m): 1; Type d'ouverture Châssis 1: Vitrage fixe; Type d'ouverture (gs_optype_m_01): 1; Type d'ouverture Châssis 2: Vitrage fixe; Type d'ouverture (gs_optype_m_02): 1; Type d'ouverture Châssis 3: Vitrage fixe; Type d'ouverture (gs_optype_m_03): 1; Type d'ouverture Châssis 4: Vitrage fixe; Type d'ouverture (gs_optype_m_04): 1; Type d'ouverture Châssis 5: Vitrage fixe; Type d'ouverture (gs_optype_m_05): 1; Type d'ouverture Châssis 6: Vitrage fixe; Type d'ouverture (gs_optype_m_06): 1; Type d'ouverture Châssis 7: Vitrage fixe; Type d'ouverture (gs_optype_m_07): 1; Type d'ouverture Châssis 8: Vitrage fixe; Type d'ouverture (gs_optype_m_08): 1; Type d'ouverture Châssis 9: Vitrage fixe; Type d'ouverture (gs_optype_m_09): 1; Type d'ouverture Châssis 10: Vitrage fixe; Type d'ouverture (gs_optype_m_10): 1; Type châssis (MullionStyle_00): Nombre de meneaux; Type châssis (iMullionStyle_00): 1; Type de châssis Châssis 1: Nombre de meneaux; Type châssis (iMullionStyle_01): 1; Type de châssis Châssis 2: Nombre de meneaux; Type châssis (iMullionStyle_02): 1; Type de châssis Châssis 3: Nombre de meneaux; Type châssis (iMullionStyle_03): 1; Type de châssis Châssis 4: Nombre de meneaux; Type châssis (iMullionStyle_04): 1; Type de châssis Châssis 5: Nombre de meneaux; Type châssis (iMullionStyle_05): 1; Type de châssis Châssis 6: Nombre de meneaux; Type châssis (iMullionStyle_06): 1; Type de châssis Châssis 7: Nombre de meneaux; Type châssis (iMullionStyle_07): 1; Type de châssis Châssis 8: Nombre de meneaux; Type châssis (iMullionStyle_08): 1; Type de châssis Châssis 9: Nombre de meneaux; Type châssis (iMullionStyle_09): 1; Type châssis (iMullionStyle_10): 1; Edition point chaud de grille: yes; Position meneau (MullionPosition): Extérieur; Position meneau (iMullionPosition): 1; Nbre de panneaux verticaux Châssis 1: 4; Nbre de panneaux horizontaux Châssis 1: 3; Nbre de panneaux verticaux 2 Châssis 1: 2; Nbre de panneaux horizontaux 2 Châssis 1: 2; Nbre de panneaux verticaux Châssis 2: 2; Nbre de panneaux horizontaux Châssis 2: 2; Nbre de panneaux verticaux 2 Châssis 2: 2; Nbre de panneaux horizontaux 2 Châssis 2: 2; Nbre de panneaux verticaux Châssis 3: 2; Nbre de panneaux horizontaux Châssis 3: 2; Nbre de panneaux verticaux 2 Châssis 3: 2; Nbre de panneaux horizontaux 2 Châssis 3: 2; Nbre de panneaux verticaux Châssis 4: 2; Nbre de panneaux horizontaux Châssis 4: 2; Nbre de panneaux verticaux 2 Châssis 4: 2; Nbre de panneaux horizontaux 2 Châssis 4: 2; Nbre de panneaux verticaux Châssis 5: 2; Nbre de panneaux horizontaux Châssis 5: 2; Nbre de panneaux verticaux 2 Châssis 5: 2; Nbre de panneaux horizontaux 2 Châssis 5: 2; Nbre de panneaux verticaux Châssis 6: 2; Nbre de panneaux horizontaux Châssis 6: 2; Nbre de panneaux verticaux 2 Châssis 6: 2; Nbre de panneaux horizontaux 2 Châssis 6: 2; Nbre de panneaux verticaux Châssis 7: 2; Nbre de panneaux horizontaux Châssis 7: 2; Nbre de panneaux verticaux 2 Châssis 7: 2; Nbre de panneaux horizontaux 2 Châssis 7: 2; Nbre de panneaux verticaux Châssis 8: 2; Nbre de panneaux horizontaux Châssis 8: 2; Nbre de panneaux verticaux 2 Châssis 8: 2; Nbre de panneaux horizontaux 2 Châssis 8: 2; Nbre de panneaux verticaux Châssis 9: 2; Nbre de panneaux horizontaux Châssis 9: 2; Nbre de panneaux verticaux 2 Châssis 9: 2; Nbre de panneaux horizontaux 2 Châssis 9: 2; Nbre de panneaux verticaux Châssis 10: 2; Nbre de panneaux horizontaux Châssis 10: 2; Nbre de panneaux verticaux 2 Châssis 10: 2; Nbre de panneaux horizontaux 2 Châssis 10: 2; Style persiennes (iLouverStyle): 1; Angle d'ouverture persiennes: 0 deg; Chambranle extérieur: no; Type chambr. ext. (gs_trimtype_out): Rectangulaire; Type chambr. ext. (gs_trimtype_out_int): 1; Coffrage sous appui: no; Largeurs uniformes de chambranle (gs_trim_outside_uniform): no; Chambranle intérieur.: no; Type chambr. intérieur (gs_trimtype_in): Rectangulaire; Type chambr. intérieur (gs_trimtype_in_int): 1; Largeurs uniformes de chambranle (gs_trim_inside_uniform): no; Appui: no; Dépassement appui: no; Type d'appui/seuil: 1; Angle appui: 3 deg; Appui courbe dans murs courbes: yes; Isolation sous appui: yes; Utiliser couche isolation mur: no; Niveau détail 3D seuil brique: 1; Tablette: no; Angle tablette: 0 deg; Tabl. courbe dans murs courbes: yes; Tableau dans murs polygonaux: 1; Aération naturelle (VentilationProfileType): Sans; Aération naturelle (iVentilationProfileType): 1; Châssis 1: yes; Châssis 2: no; Châssis 3: no; Châssis 4: no; Châssis 5: no; Châssis 6: no; Châssis 7: no; Châssis 8: no; Châssis 9: no; Châssis 10: no; Type volet (gs_sunShade_type): Sans; Type volet (gs_sunShade_iType): 0; Types volet activés: 127; Nombre de panneaux (gs_shutter_nPanels): 2; Nombre de panneaux 2: 1; Position panneau (gs_shutter_panelPos): Symmetric; Position panneau (gs_shutter_iPanelPos): 1; Hauteur volet automatique: yes; Cadre supplémentaire: no; Type de couverture (gs_slidingShutter_cover): Z-Profile; Type de couverture (gs_slidingShutter_iCover): 1; Direction articulation (gs_foldingShutter_stacking): Inside; Direction articulation (gs_foldingShutter_iStacking): 1; Ouvert en 3D: yes; Angle ouverture en 3D: 180 deg; Afficher symbole 2D: yes; Afficher lignes d'ouverture sur symbole: no; Type de panneau: (gs_shutPanel_type): Style 1; Type de panneau: (gs_shutPanel_iType): 1; Largeur cadre inf. différente: no; Largeur volets automatiques: yes; Angle persienne: 30 deg; Résolution trou: 3; Nombre trous horizontaux: 5; Nombre trous verticaux: 8; Placement volet roulant (gs_shutRoll_placement): Fixed on Facade; Placement volet roulant (gs_shutRoll_iPlacement): 1; Type boîte (gs_shutRoll_boxType): Rectangular; Type boîte (gs_shutRoll_iBoxType): 1; Position rampe (gs_shutRoll_railPos): Sur revêtement; Position rampe (gs_shutRoll_iRailPos): 1; Afficher revêtement derrière parasol (gs_shutRoll_showCasingBehind): no; Isolation derrière cellule (gs_shutRoll_cutWallBehind): no; Inclure hauteur dans hauteur de trou de mur: no; Angle supérieur boîte: 10 deg; Taille boîte par défaut (gs_shutRoll_boxDefaultSize): Reveal Width; Taille boîte par défaut (gs_shutRoll_iBoxDefaultSize): 1; Placement stores (gs_shutLam_placement): Fixed on Facade; Placement stores (gs_shutLam_iPlacement): 1; Isolation derrière cellule (gs_shutLam_cutWallBehind): no; Boîte ouverte: yes; Rampe: yes; Position rampe (gs_shutLam_railPos): Sur revêtement; Position rampe (gs_shutLam_iRailPos): 1; Afficher revêtement derrière parasol (gs_shutLam_showCasingBehind): no; Angle de rotation des lamelles (gs_shutLam_rotation): 45 deg; Angle de rotation des lamelles (gs_shutLam2_rotation): 45 deg; Linteau (gs_masonry_arch): Sans; Linteau (gs_masonry_arch_int): 1; Type linteau (gs_masonry_arch_structure): Stuc; Type linteau (gs_masonry_arch_structure_int): 1; Arche sur linteau: yes; Niche sous arche: yes; Angle inclinaison: 75 deg; Surface niche personnalisée: no; Type ébrasure (gs_reveal_type_new): Baie simple; Type ébrasure (gs_reveal_type_int): 2; Type ébrasure inférieure (gs_reveal_type_bottom): Uniforme; Type ébrasure inférieure (gs_reveal_type_bottom_int): 1; Type ébrasure extérieure: Baie simple; Type ébrasure (gs_reveal_doubleOuterTypeInt): 2; Type ébrasure intérieure: Baie simple; Type ébrasure (gs_reveal_doubleInnerTypeInt): 2; Profondeur montant uniforme: no; Côté angle 2: 20 deg; Côté angle: 20 deg; Angle côté supérieur: 20 deg; Angle côté inférieur: 20 deg; Utiliser composant finition mur: no; Tourner automatiquement plâtre surface intérieure: yes; Tourner plâtre surface intérieure: 0; Tourner automatiquement plâtre surface extérieure: yes; Tourner plâtre surface extérieure: 0; Afficher en 3D: no; Type de fermeture (gs_closure_type): Pas de fermeture; Type de fermeture (gs_closure_type_int): 1; Tourner couche sur côté (gs_cavity_side): Les deux; Tourner couche sur côté (iCavityClosureSide): 1; Nbre de couches retournées: 1; Num. à partir de (gs_nTurnDir): Face extérieure; Num. à partir de (iCavityClosureTurnDir): 1; Placer fermeture sur côté 2: yes; Placer fermeture sur côté 1: yes; Placer fermeture en haut: no; Placer fermeture en bas: no; Placer fermeture sur couche: 1; Placer fermeture de côté (gs_cc_dutch_ClosureToSide): 1; Ecart à couche externe: yes; Tourner couche sur fermeture: no; Insérer bande d'isolation: yes; Afficher bande d'isolation: yes; Stylo contour (gs_penJoint): Ouvertures - Coupé non structurel; Type de ligne de contour (gs_ltJoint): 1; Motif de hachure (gs_fillJoint): Rigid Insulation; Stylo hachure (gs_penJointFg): Général - Dessin; Stylo fond de hachure (gs_penJointBg): Eléments 2D - Dessin; Surface personnalisée: no; Surface: 06 | W Pine H; Stylo contour (gs_penPlug): Ouvertures - Coupé non structurel; Type de ligne de contour (gs_ltPlug): 1; Motif de hachure (gs_fillPlug): Rigid Insulation; Stylo hachure (gs_penPlugFg): Général - Dessin; Stylo fond de hachure (gs_penPlugBg): Eléments 2D - Dessin; Côté montant édité: 1; Côté mur édité: 1; Numéro couche éditée: 1; Tourner couche: no; Considérer couches comme plâtre: no; Tourner épaiseur: 1; Orientation hachure: 1; Ligne de séparation tournant: no; Stylo ligne de séparation: Général - Dessin; Dernier côté sélectionné: no; Méthode fermeture changée auto.: no; Connexion à gauche: no; Connexion à droite: no; Connexion en haut: no; Connexion en bas: no; Incrustation allège fenêtre: no; Tailles incrustation mur (gs_parapet_sizes_st): Automatique; Tailles incrustation mur (iParapetSize): 1; Cotes largeur et longueur auto: yes; Incrustation base mur à (gs_parapet_bottom_st): Etage actuel; Incrustation base mur à (iParapetBottom): 1; Afficher allège masquée: yes; Type ligne allège masquée: 1; Angle d'ouverture de Châssis 1 (openingAngle_01): 0 deg; Angle d'ouverture de Châssis 1 (openingAngle2_01): 0 deg; Angle d'ouverture de Châssis 2 (openingAngle_02): 0 deg; Angle d'ouverture de Châssis 2 (openingAngle2_02): 0 deg; Angle d'ouverture de Châssis 3 (openingAngle_03): 0 deg; Angle d'ouverture de Châssis 3 (openingAngle2_03): 0 deg; Angle d'ouverture de Châssis 4 (openingAngle_04): 0 deg; Angle d'ouverture de Châssis 4 (openingAngle2_04): 0 deg; Angle d'ouverture de Châssis 5 (openingAngle_05): 0 deg; Angle d'ouverture de Châssis 5 (openingAngle2_05): 0 deg; Angle d'ouverture de Châssis 6 (openingAngle_06): 0 deg; Angle d'ouverture de Châssis 6 (openingAngle2_06): 0 deg; Angle d'ouverture de Châssis 7 (openingAngle_07): 0 deg; Angle d'ouverture de Châssis 7 (openingAngle2_07): 0 deg; Angle d'ouverture de Châssis 8 (openingAngle_08): 0 deg; Angle d'ouverture de Châssis 8 (openingAngle2_08): 0 deg; Angle d'ouverture de Châssis 9 (openingAngle_09): 0 deg; Angle d'ouverture de Châssis 9 (openingAngle2_09): 0 deg; Angle d'ouverture de Châssis 10 (openingAngle_10): 0 deg; Angle d'ouverture de Châssis 10 (openingAngle2_10): 0 deg; Angle ouverture en 2D: 0 deg; Suppl. Opt. vue pour aff. symb. 2D: no; Type ligne ouverture: 1; Forme ligne ouverture (or_SwingType): Courbé; Forme ligne ouverture (or_iSwingType): 1; Forme ligne ouverture (or_SlidingType): Sans; Forme ligne ouverture (or_iSlidingType): 0; Stylo ligne ouverture 2D/3D (or_opLinePen): Ouvertures - Général; Stylo ligne ouverture 2D/3D (or_iOpLinePen): 3; Suppl. Opt. vue pour proj. 3D: no; Afficher ligne d'ouverture: yes; Type ligne côté ouverture (or_opLineType3dIn): Tirets; Type ligne côté ouverture (or_iOpLineType3dIn): 1; Type ligne côté opposé (or_opLineType3dOut): Ligne continue; Type ligne côté opposé (or_iOpLineType3dOut): 0; Orient. ligne (or_oplineStyle): Poignée; Orient. ligne (or_iOplineStyle): 1; Stylo ligne non coupée: A construire - Coupe; Stylo ligne coupée: A construire - Coupe; Stylo contour des deux côtés de chambranle: Ouvertures - Général; Ligne de contour de mur (gs_wcont_line): Des deux côtés; Ligne de contour de mur (iWallContourLine): 4; Type ligne contour int. mur: 1; Type ligne contour ext. mur: 1; Type ligne contour int. mur masqué: 1; Type ligne contour ext. mur masqué: 1; Stylo ligne contour de mur: Ouvertures - Général; Utiliser hachures: yes; Motif de hachure cadre: Background; Stylo hachure cadre: A construire - Coupe; Stylo fond de hachure cadre: Fond - Couleur 1; Motif de hachure châssis: Air Space; Stylo fond de châssis: Ouvertures - Hachures coupées; Stylo fond de hachure châssis: Fond - Couleur 1; Type hachure non coupée: Background; Stylo hachure non coupée: A construire - Coupe; Stylo fond de hachure non coupé: Fond - Couleur 1; Motif hachure symbole en plan: Background; Stylo hachure symbole en plan: Fond - Couleur 1; Stylo fond hachure symbole plan: Fond - Couleur 1; Stylo appui 3D et non coupé: Général - Dessin; Stylo contour appui en Coupe: Général - Dessin; Motif hachure appui en Coupe: Background; Stylo hachure d'appui en Coupe: Fond - Couleur 1; Stylo fond hachure appui Coupe: Fond - Couleur 1; Stylo contour isolation coupe: Général - Dessin; Motif hachure isolation Coupe: Rigid Insulation; Stylo hachure isolation Coupe: Général - Dessin; Stylo fond hachure isol. Coupe: Fond - Couleur 1; Stylo latte 3D et non coupé: Général - Dessin; Stylo contour latte en Coupe: Général - Dessin; Motif hachure tablette en Coupe: Background; Stylo hachure tablette en Coupe: Fond - Couleur 1; Stylo fond hach. tablette Coupe: Fond - Couleur 1; Type hachure chambr. intérieur: Background; Stylo hachure chambr. int.: Fond - Couleur 1; Stylo fond hachure chambr. int.: Fond - Couleur 1; Type hachure chambr. ext.: Background; Stylo hachure chambr. ext.: Fond - Couleur 1; Stylo fond hachure chambr. ext.: Fond - Couleur 1; Motif de hachure arche coupe: Background; Stylo fond hachure appui arche Coupe (gs_masonry_arch_pen_fg): Fond - Couleur 1; Stylo fond hachure appui arche Coupe (gs_masonry_arch_pen_bg): Fond - Couleur 1; Motif de hachure de Coupe de Profil de ventilation: Air Space; Stylo de hachure de Coupe de Profil de ventilation: Fond - Couleur 1; Stylo de fond de hachure de Coupe de Profil de ventilation: Fond - Couleur 1; Type de ligne symbole volet: 1; Stylo ligne coupée volet: Général - Dessin; Stylo ligne non coupée volet: Général - Dessin; Type hachure coupée volet: Background; Stylo hachure coupée volet: Général - Dessin; Stylo fond hachure coupé volet: Fond de fenêtre; Motif de hachure d'isolation de pare-soleil: Background; Stylo de hachure d'isolation de pare-soleil: Général - Dessin; Stylo de fond d'isolation de pare-soleil: Fond de fenêtre; Jonction éléments cadree: 1; Stylo cadre: A construire - Coupe; Stylo châssis: Ouvertures - Général; Stylo vitrage: Ouvertures - Coupé non structurel; Stylo linteau: Murs - Général; Ombre: yes; Surface extérieure cadre: Paint-05; Surface intérieure cadre: Paint-05; Surface extérieure châssis: Wd-Pine Horizontal; Surface intérieure châssis: 06 | W Pine H; Surface persiennes: 06 | W Pine H; Surface vitre: Glass-Blue; Surface extérieure de meneau: Wd-Pine Horizontal; Surface intérieure de meneau: Wd-Pine Horizontal; Surface extérieure panneau solide: 06 | W Pine H; Surface intérieure panneau solide: 06 | W Pine H; Surface intérieure chambranle: Wd-Pine Horizontal; Surface extérieure chambranle: Wd-Pine Horizontal; Surface de profil de ventilation: 05 | Aluminum Plain; Surface panneau de volet: Wd-Pine Horizontal; Surface cadre volet: Wd-Pine Horizontal; Surface boîte volet roulant: Mtl-Stainless Steel; Surface lames volet roulant: Surf-White; Surface rail volet roulant: Surf-White; Surface boîtier de stores: Mtl-Stainless Steel; Surface segments de stores: Surf-White; Surface rail volet coulissant: Mtl-Stainless Steel; Surface d'appui: Wd-Pine Horizontal; Surface mortier appui briques: Surf-Stucco White; Surface de tableau: Wd-Pine Horizontal; Surface brique linteau: Brick-Running Bond; Surface mortier linteau: Surf-Stucco White; Surface clef de voûte linteau: Stn-Sandstone; Surface niche: 32 | Mulch; Direction d'ouverture: 1; Afficher comme imposte: no; Stylo ligne tête de mur: Général - Dessin; Type de ligne tête de mur: 21; Symbole en plan Linteau/seuil: no; Type ligne symb. Linteau/seuil: 21; Stylo symbole Linteau/seuil: Texte d'annotation - Général; Fenêtre appartient à Zone vers laquelle elle donne: no; Coût: 0; Surface vitrée totale (gs_list_glassarea_tmp): 0; Supplanter surface vitrée: yes; Surface vitrée totale (gs_list_glassarea): 0; Périmètre total vitrage: 0; Performance air libre (mm2/l/m): 0; Type de groupe (FM_Type): Default Objects; Type de groupe (iFMType): 999; Poids de l'objet: 0; Unité poids de l'objet: kg; Opération IFC (ifc_optypestr): Triple vertical; Opération IFC (ifc_optype): 4; Angle ouverture volet: 180 deg; Style lignes d'ouverture: 1
AC_Pset_RenovationAndPhasing - Renovation Status: Existing
BaseQuantities - Width: 6 m; Volume: 0.049 m3; Depth: 0.37 m
ArchiCADQuantities - Altitude à Zéro du Projet: 17.4 m; Altitude à étage: 0 m; Hauteur: 2 m; Superficie de surface: 26.883 m2; Volume net: 0.049 m3; Largeur: 6 m; Epaisseur: 0.05 m; Hauteur nominale seuil: 0 m; Hauteur seuil côté ébrasure: 0 m; Hauteur seuil côté opposé ébrasure: 0 m; Hauteur nominale linteau: 2 m; Hauteur linteau côté ébrasure: 2 m; Hauteur linteau côté opposé ébrasure: 2 m; Largeur ouverture côté ébrasure: 6 m; Largeur ouverture côté opposé ébrasure: 6 m; Largeur nominale de l'ouverture côté ébrasure: 6 m; Largeur nominale de l'ouverture côté opposée ébrasure: 6 m; Hauteur nominale de l'ouverture côté ébrasure: 2 m; Hauteur nominale de l'ouverture côté opposée ébrasure: 2 m; Surface nominale de l'ouverture P/F côté ébrasure: 12 m2; Surface nominale de l'ouverture P/F côté opposé ébrasure: 12 m2; Volume ouverture: 0.049 m3; Surface nominale ouverture P/F: 12 m2; Volume nominal ouverture: 4.44 m3; Valeur Appui ou Linteau: 0 m; Epaisseur de Mur: 0.37 m
AC_Equantity_Fenêtre_horizontale_à_châssis_multiples_18 - Largeur: 6 m; Hauteur: 2 m; Dimension Z: 1 m; Niveau inférieur: 1 m; Niveau supérieur: 0 m; Hauteur appui à étage actuel: 0 m; Nouv. largeur droite hach. mur: 0.15 m; Nouv. largeur gauche hach. mur: 0.15 m; Epaisseur du mur connecté: 0 m; Epaissseur murs connectés G: 0.37 m; Epaissseur murs connectés D: 0.37 m; Largeur poteau d'angle: 0 m; Epaisseur poteau d'angle: 0 m; Projection poteau d'angle: 0 m; Tolérance max.: 0.1 m; Tolérance: 0 m; Tolérance gauche: 0 m; Tolérance droite: 0 m; Tolérance supérieure: 0 m; Tolérance inférieure: 0 m; Largeur cavité mur: 6 m; Hauteur cavité mur: 2 m; Largeur ébrasure: 6 m; Hauteur ébrasure: 2 m; Largeur unité: 6 m; Hauteur unité: 2 m; Distance d'axe: 1.98333 m; Largeur de panneau 1: 1.98333 m; Largeur de panneau 2: 0.5 m; Largeur de panneau 3: 0.5 m; Largeur de panneau 4: 0.5 m; Largeur de panneau 5: 0.5 m; Largeur de panneau 6: 0.5 m; Largeur de panneau 7: 0.5 m; Largeur de panneau 8: 0.5 m; Largeur de panneau 9: 0.5 m; Conserver largeur de panneau: 0.5 m; Epaisseur cadre: 0.05 m; Largeur cadre: 0.05 m; Largeur cadre côté 2: 0.05 m; Largeur cadre supérieur: 0.05 m; Largeur cadre inférieur (gs_frame_width_lower): 0.05 m; Profondeur feuillure: 0.025 m; Largeur feuillure: 0.025 m; Largeur meneau central: 0.05 m; Largeur de meneau 1: 0.1 m; Largeur de meneau 2: 0.1 m; Largeur de meneau 3: 0.1 m; Largeur de meneau 4: 0.1 m; Largeur de meneau 5: 0.1 m; Largeur de meneau 6: 0.1 m; Largeur de meneau 7: 0.1 m; Largeur de meneau 8: 0.1 m; Largeur de meneau 9: 0.1 m; Hauteur de division horizontale Châssis 1: 0.9 m; Hauteur de division horizontale Châssis 2: 0.9 m; Hauteur de division horizontale Châssis 3: 0.9 m; Hauteur de division horizontale Châssis 4: 0.9 m; Hauteur de division horizontale Châssis 5: 0.9 m; Hauteur de division horizontale Châssis 6: 0.9 m; Hauteur de division horizontale Châssis 7: 0.9 m; Hauteur de division horizontale Châssis 8: 0.9 m; Hauteur de division horizontale Châssis 9: 0.9 m; Hauteur de division horizontale Châssis 10: 0.9 m; Epaisseur châssis: 0.05 m; Largeur châssis: 0.05 m; Largeur grille: 0.02 m; Epaisseur grille: 0.025 m; Epaisseur vitrage: 0.02 m; Epaisseur persiennes: 0.01 m; Largeur persiennes: 0.05 m; Dépassement ouverture gauche: 0 m; Dépassement ouverture droite: 0 m; Dépassement ouverture supérieur: 0 m; Dépassement ouverture inférieur: 0 m; Largeur côté 1 (gs_tw_right_out): 0.1 m; Largeur côté 2 (gs_tw_left_out): 0.1 m; Largeur haut (gs_tw_top_out): 0.1 m; Largeur base (gs_tw_bottom_out): 0.1 m; Epaisseur sur mur (gs_trim_thk_out): 0.025 m; Epaisseur dans trou de mur (gs_trim_width_out): 0.025 m; Décalage (gs_trim_offs_out): 0 m; Débord supérieur (gs_trimov_top_left_out): 0.1 m; Débord supérieur (gs_trimov_top_right_out): 0.1 m; Débord inférieur: (gs_trimov_bot_left_out): 0.1 m; Débord inférieur: (gs_trimov_bot_right_out): 0.1 m; Largeur côté 1 (gs_tw_right_in): 0.1 m; Largeur côté 2 (gs_tw_left_in): 0.1 m; Largeur haut (gs_tw_top_in): 0.1 m; Largeur base (gs_tw_bottom_in): 0.1 m; Epaisseur sur mur (gs_trim_thk_in): 0.025 m; Epaisseur dans trou de mur (gs_trim_width_in): 0.025 m; Décalage (gs_trim_offs_in): 0 m; Débord supérieur (gs_trimov_top_left_in): 0.1 m; Débord supérieur (gs_trimov_top_right_in): 0.1 m; Débord inférieur: (gs_trimov_bot_left_in): 0.1 m; Débord inférieur: (gs_trimov_bot_right_in): 0.1 m; Largeur appui: 0 m; Largeur supérieure appui: 0.01 m; Hauteur supérieure appui: 0.01 m; Epaisseur appui: 0.025 m; Epaisseur front appui: 0.015 m; Altitude appui: 0 m; Débord larmier appui: 0.02 m; Largeur larmier appui: 0.03 m; Débord appui: 0.03 m; Dépassement appui gauche: 0 m; Dépassement appui droite: 0 m; Glissement appui en profondeur: 0.02 m; Glissement appui de mur: 0 m; Profondeur trou arrière (gs_sill_holeDepthBehind): 0 m; Epaisseur brique (gs_brick_sill_br_thk): 0.065 m; Epaisseur mortier (gs_brick_sill_mort_thk): 0.015 m; Largeur latte: 0.23 m; Epaisseur latte: 0.025 m; Débord tablette: 0.03 m; Dépassement tablette gauche: 0 m; Dépassement tablette droite: 0 m; Glissement tabl. en profondeur: 0 m; Hauteur profil: 0.065 m; Epaisseur profil: 0.11 m; Hauteur panneau: 1.5 m; Décalage intérieur: 0.02 m; Profondeur fermeture: 0 m; Largeur cadre supplémentaire: 0.04 m; Epaisseur cadre supplémentaire: 0.03 m; Epaisseur allège vitrée: 0.03 m; Longueur colonne centrale: 0.02 m; Rayon colonne centrale: 0.005 m; Distance panneau: 0.006 m; Débord extérieur: 0 m; Largeur panneau intérieur: 0.12 m; Longueur ouverture en 3D: 1.5 m; Longueur fermée en 3D: 0 m; Longueur ouverture 1 en 3D (gs_shutter_opLength_1): 0.56 m; Longueur ouverture 1 en 3D (gs_shutter_opLength_2): 0.14 m; Hauteur ouverture en 3D: 1.5 m; Hauteur fermée en 3D: 0 m; Epaisseur panneau: 0.05 m; Largeur cadre panneau: 0.05 m; Largeur cadre inférieur (gs_shutPanel_frameWidthBottom): 0.05 m; Largeur panneau: 0 m; Epaisseur hachure panneau: 0.01 m; Epaisseur persienne: 0.01 m; Largeur persienne: 0.04 m; Largeur diviseur cadre horiz.: 0.05 m; Largeur diviseur cadre vert.: 0.05 m; Rayon trou: 0.01 m; Largeur montant: 0.1 m; Largeur cadre Z: 0.05 m; Epaisseur cadre Z: 0.025 m; Epaisseur plans verticaux: 0.025 m; Epaisseur plans horizontaux: 0.025 m; Largeur appr. plans verticaux: 0.08 m; Largeur appr. plans horizontaux: 0.115 m; Hauteur boîte (gs_shutRoll_boxHeight): 0.2 m; Profondeur boîte (gs_shutRoll_boxWidth): 0.15 m; Décalage boîte gauche: 0 m; Décalage boîte droite: 0 m; Profondeur rails: 0.0725 m; Distance au mur (gs_shutRoll_distFromWall): 0 m; Distance au linteau (gs_shutRoll_distFromHead): 0 m; Largeur lamelle: 0.05 m; Hauteur boîte (gs_shutLam_boxHeight): 0.2 m; Profondeur boîte (gs_shutLam_boxWidth): 0.15 m; Largeur recouvrement: 0 m; Distance au mur (gs_shutLam_distFromWall): 0 m; Distance au linteau (gs_shutLam_distFromHead): 0 m; Largeur segment (gs_shutLam_segmentWidth): 0.06 m; Hauteur boîte (gs_shutLam2_boxHeight): 0.06 m; Largeur boîte: 0.06 m; Distance à fenêtre: 0.06 m; Distance au linteau (gs_shutLam2_distFromHead): 0.06 m; Hauteur axe cellule à linteau: 0 m; Largeur segment (gs_shutLam2_segmentWidth): 0.06 m; Distance entre arche et fenêtre: 0 m; Dépassement gauche linteau: 0 m; Dépassement droite linteau: 0 m; Elevation linteau: 0.03 m; Décalage linteau: 0 m; Hauteur linteau: 0.25 m; Profondeur linteau: 0.12 m; Profondeur trou arrière (gs_masonry_arch_rearHoleDepth): 0 m; Epaisseur brique (gs_masonry_arch_brick_thk): 0.065 m; Epaisseur mortier (gs_masonry_arch_mort_thk): 0.01 m; Largeur clé de voûte: 0.1 m; Dépassement clé de voûte: 0 m; Projection clé de voûte: 0.01 m; Profondeur ébrasure : (gs_wido_sill): 0.12 m; Profondeur ébrasure : (AC_wido_sill): 0.12 m; Profondeur montant côté 2: 0.06 m; Profondeur montant: 0.06 m; Profondeur montant int. côté 2 (gs_reveal_splayed_innerLeft): 0.06 m; Profondeur montant intérieur (gs_reveal_splayed_innerRight): 0.06 m; Profondeur montant int. côté 2 (gs_reveal_double_innerLeft): 0.06 m; Profondeur montant intérieur (gs_reveal_double_innerRight): 0.06 m; Profondeur montant linteau: 0.06 m; Profondeur montant appui: 0 m; Profondeur linteau int. (gs_reveal_splayed_innerTop): 0.06 m; Profondeur appui int. (gs_reveal_splayed_innerBottom): 0.06 m; Profondeur linteau int. (gs_reveal_double_innerTop): 0.06 m; Profondeur appui int. (gs_reveal_double_innerBottom): 0 m; Profondeur montant ext.: 0.08 m; Limite épaisseur plâtre: 0.04 m; Distance de couche / fermeture: 0 m; Largeur fermeture: 0.038 m; Epaisseur fermeture: 0.1 m; Epaisseur bande: 0.025 m; Largeur profilé: 0.075 m; Epaisseur personnalisée: 0.015 m; Dépassement couche prof. cadre: 0 m; Profondeur incrustation: 0.05 m; Largeur allège: 1 m; Débord gauche: 0 m; Débord droite: 0 m; Hauteur allège: 0.9 m; Débord inférieur: (gs_parapet_botelev): 0 m; Distance d'ouverture 1 Châssis 1: 0 m; Distance d'ouverture 2 Châssis 1: 0 m; Distance d'ouverture 1 Châssis 2: 0 m; Distance d'ouverture 2 Châssis 2: 0 m; Distance d'ouverture 1 Châssis 3: 0 m; Distance d'ouverture 2 Châssis 3: 0 m; Distance d'ouverture 1 Châssis 4: 0 m; Distance d'ouverture 2 Châssis 4: 0 m; Distance d'ouverture 1 Châssis 5: 0 m; Distance d'ouverture 2 Châssis 5: 0 m; Distance d'ouverture 1 Châssis 6: 0 m; Distance d'ouverture 2 Châssis 6: 0 m; Distance d'ouverture 1 Châssis 7: 0 m; Distance d'ouverture 2 Châssis 7: 0 m; Distance d'ouverture 1 Châssis 8: 0 m; Distance d'ouverture 2 Châssis 8: 0 m; Distance d'ouverture 1 Châssis 9: 0 m; Distance d'ouverture 2 Châssis 9: 0 m; Distance d'ouverture 1 Châssis 10: 0 m; Distance d'ouverture 2 Châssis 10: 0 m; Dépass.ouverture gauche: 0 m; Dépass.ouverture à droite: 0 m; Dépass.ouverture supérieur: 0 m; Dépass.ouverture inférieur: 0 m
Name | ID | GrossArea (m2) = Area (m2) = Surface ouverture côté ébrasure (m2) | Height (m) = Hauteur ouverture côté ébrasure (m) | Perimeter (m) | Hauteur ouverture côté opposé ébrasure (m) | Surface ouverture côté opposé ébrasure (m2)
WD - 001 | WD - 001 | 11.2748 | 1.92009 | 15.8402 | 1.92437 | 11.0869
7 x WD - 004 | WD - 004 | 11.0745 | 1.84576 | 15.6915 | 1.87813 | 11.2688

# IfcWindow: Fenêtre horizontale à châssis multiples 18, WD - 001
In: Toiture
Type - OperationType: TRIPLE_PANEL_VERTICAL; ParameterTakesPrecedence: no; Sizeable: no
Type - Propriétés Doublure Fenêtre - LiningDepth: 0.05 m; LiningThickness: 0.05 m; MullionThickness: 0.05 m; FirstMullionOffset: 0.331575; SecondMullionOffset: 0.66315
Type - Propriétés Panneau Fenêtre - Panneau1 - OperationType: FIXEDCASEMENT; PanelPosition: LEFT
Type - Propriétés Panneau Fenêtre - Panneau2 - OperationType: FIXEDCASEMENT; PanelPosition: MIDDLE
Type - Propriétés Panneau Fenêtre - Panneau3 - OperationType: FIXEDCASEMENT; PanelPosition: RIGHT
OverallHeight: 2 m; OverallWidth: 9.47793 m; Material: Background (10), Air Space (2), Rigid Insulation
ArchiCADProperties - ID: WD - 001; Etage d'implantation: Toiture; Calque: A-WALL-EXTR; Type: Fenêtre; Verrouillé: no; Nom Elément de Bibliothèque: Fenêtre horizontale à châssis multiples 18; Matériau de construction / Composite / Profil / Hachure: Background; Fonction structurelle: Non défini; Position: Non défini; Classification d'lément: Type ArchiCAD; Etat de rénovation: Existant; Afficher sur filtre de rénovation: Tous les filtres appropriés; Dimensions ébrasure: 373,15"x78,74"; Dimensions trou mur: 373,15"x78,74"; Dimensions unité: 373,15"x78,74"; Structure mur: 1.2-Mur ext: revét ext + isol ext + maçonnerie + enduit; Taille L x H nominale: 373,15"x78,74"; Taille L x H x E nominale: 373,15"x78,74"x14,57"
AC_Pset_Fenêtre_horizontale_à_châssis_multiples_18 - Contours Mur (0-Sans,1-Tout,2-Côté,3-Longueur): 0; Point ch.0-Non,1-2D,2-3D,3-Tous: 3; Option affichage en plan: 3; Angle de position baie: 0 deg; Trou reprend surface latérale de mur: yes; Division de surface de trou courbée: no; Afficher points chauds 2D en 3D: yes; Type de mur: 1; Type de direction de mur: 1; Fonction de debug Fenêtre Angle: no; Placement (1=Angle, 0=Centre): no; Basculer: no; Démolition / Nouvelle constr.: 1; Nouveau motif de hachure de mur: Masonry Block; Nouveau stylo de hachure de mur: Général - Dessin; Nouveau stylo fond hachure mur: Fond - Couleur 1; Afficher nouv. constr. sur mur: no; Type de ligne démolition: 4; Aff. param. Démolition/Nouveau: no; Fonction Fenêtre Angle: yes; Angle Murs: 90 deg; Murs connectés d'épaiss. diff.: no; Poteau d'angle: no; Angle gauche:: no; Angle coin gauche: 90 deg; Murs connectés épaiss. diff. G: no; Angle droit: no; Angle coin droit: 90 deg; Murs connectés épaiss. diff. D: no; Type connexion angle droite: 1; Type connexion angle: 1; Entièrement éditable: yes; Niveau de détail 2D: 2; Afficher ébrasure sur symbole: 2; Niveau de détail 3D: 2; Activer niveau détail 3D: 14; Taille nominale: 0; Taille trou comme taille nominale: yes; Taille ébrasure comme nominale: no; Taille unité comme nominale: no; Conserver valeur de taille nominale en changeant: no; Nombre de panneaux (gs_panes_number): 1; Multiplier unité: yes; Nombre de copies: 3; Conserver distance d'axe: yes; Configuration panneaux: Panneaux uniformes; Panneaux horizontaux: 1; Largeur cadre uniforme: yes; Châssis uniformes: no; Direction vitrage fixe (FixGlassDir): Par direction d'ouverture; Direction vitrage fixe (FixGlassDir_m): 1; Type d'ouverture Châssis 1: Vitrage fixe; Type d'ouverture (gs_optype_m_01): 1; Type d'ouverture Châssis 2: Vitrage fixe; Type d'ouverture (gs_optype_m_02): 1; Type d'ouverture Châssis 3: Vitrage fixe; Type d'ouverture (gs_optype_m_03): 1; Type d'ouverture Châssis 4: Vitrage fixe; Type d'ouverture (gs_optype_m_04): 1; Type d'ouverture Châssis 5: Vitrage fixe; Type d'ouverture (gs_optype_m_05): 1; Type d'ouverture Châssis 6: Vitrage fixe; Type d'ouverture (gs_optype_m_06): 1; Type d'ouverture Châssis 7: Vitrage fixe; Type d'ouverture (gs_optype_m_07): 1; Type d'ouverture Châssis 8: Vitrage fixe; Type d'ouverture (gs_optype_m_08): 1; Type d'ouverture Châssis 9: Vitrage fixe; Type d'ouverture (gs_optype_m_09): 1; Type d'ouverture Châssis 10: Vitrage fixe; Type d'ouverture (gs_optype_m_10): 1; Type châssis (MullionStyle_00): Nombre de meneaux; Type châssis (iMullionStyle_00): 1; Type de châssis Châssis 1: Nombre de meneaux; Type châssis (iMullionStyle_01): 1; Type de châssis Châssis 2: Nombre de meneaux; Type châssis (iMullionStyle_02): 1; Type de châssis Châssis 3: Nombre de meneaux; Type châssis (iMullionStyle_03): 1; Type de châssis Châssis 4: Nombre de meneaux; Type châssis (iMullionStyle_04): 1; Type de châssis Châssis 5: Nombre de meneaux; Type châssis (iMullionStyle_05): 1; Type de châssis Châssis 6: Nombre de meneaux; Type châssis (iMullionStyle_06): 1; Type de châssis Châssis 7: Nombre de meneaux; Type châssis (iMullionStyle_07): 1; Type de châssis Châssis 8: Nombre de meneaux; Type châssis (iMullionStyle_08): 1; Type de châssis Châssis 9: Nombre de meneaux; Type châssis (iMullionStyle_09): 1; Type châssis (iMullionStyle_10): 1; Edition point chaud de grille: yes; Position meneau (MullionPosition): Extérieur; Position meneau (iMullionPosition): 1; Nbre de panneaux verticaux Châssis 1: 4; Nbre de panneaux horizontaux Châssis 1: 3; Nbre de panneaux verticaux 2 Châssis 1: 2; Nbre de panneaux horizontaux 2 Châssis 1: 2; Nbre de panneaux verticaux Châssis 2: 2; Nbre de panneaux horizontaux Châssis 2: 2; Nbre de panneaux verticaux 2 Châssis 2: 2; Nbre de panneaux horizontaux 2 Châssis 2: 2; Nbre de panneaux verticaux Châssis 3: 2; Nbre de panneaux horizontaux Châssis 3: 2; Nbre de panneaux verticaux 2 Châssis 3: 2; Nbre de panneaux horizontaux 2 Châssis 3: 2; Nbre de panneaux verticaux Châssis 4: 2; Nbre de panneaux horizontaux Châssis 4: 2; Nbre de panneaux verticaux 2 Châssis 4: 2; Nbre de panneaux horizontaux 2 Châssis 4: 2; Nbre de panneaux verticaux Châssis 5: 2; Nbre de panneaux horizontaux Châssis 5: 2; Nbre de panneaux verticaux 2 Châssis 5: 2; Nbre de panneaux horizontaux 2 Châssis 5: 2; Nbre de panneaux verticaux Châssis 6: 2; Nbre de panneaux horizontaux Châssis 6: 2; Nbre de panneaux verticaux 2 Châssis 6: 2; Nbre de panneaux horizontaux 2 Châssis 6: 2; Nbre de panneaux verticaux Châssis 7: 2; Nbre de panneaux horizontaux Châssis 7: 2; Nbre de panneaux verticaux 2 Châssis 7: 2; Nbre de panneaux horizontaux 2 Châssis 7: 2; Nbre de panneaux verticaux Châssis 8: 2; Nbre de panneaux horizontaux Châssis 8: 2; Nbre de panneaux verticaux 2 Châssis 8: 2; Nbre de panneaux horizontaux 2 Châssis 8: 2; Nbre de panneaux verticaux Châssis 9: 2; Nbre de panneaux horizontaux Châssis 9: 2; Nbre de panneaux verticaux 2 Châssis 9: 2; Nbre de panneaux horizontaux 2 Châssis 9: 2; Nbre de panneaux verticaux Châssis 10: 2; Nbre de panneaux horizontaux Châssis 10: 2; Nbre de panneaux verticaux 2 Châssis 10: 2; Nbre de panneaux horizontaux 2 Châssis 10: 2; Style persiennes (iLouverStyle): 1; Angle d'ouverture persiennes: 0 deg; Chambranle extérieur: no; Type chambr. ext. (gs_trimtype_out): Rectangulaire; Type chambr. ext. (gs_trimtype_out_int): 1; Coffrage sous appui: no; Largeurs uniformes de chambranle (gs_trim_outside_uniform): no; Chambranle intérieur.: no; Type chambr. intérieur (gs_trimtype_in): Rectangulaire; Type chambr. intérieur (gs_trimtype_in_int): 1; Largeurs uniformes de chambranle (gs_trim_inside_uniform): no; Appui: no; Dépassement appui: no; Type d'appui/seuil: 1; Angle appui: 3 deg; Appui courbe dans murs courbes: yes; Isolation sous appui: yes; Utiliser couche isolation mur: no; Niveau détail 3D seuil brique: 1; Tablette: no; Angle tablette: 0 deg; Tabl. courbe dans murs courbes: yes; Tableau dans murs polygonaux: 1; Aération naturelle (VentilationProfileType): Sans; Aération naturelle (iVentilationProfileType): 1; Châssis 1: yes; Châssis 2: no; Châssis 3: no; Châssis 4: no; Châssis 5: no; Châssis 6: no; Châssis 7: no; Châssis 8: no; Châssis 9: no; Châssis 10: no; Type volet (gs_sunShade_type): Sans; Type volet (gs_sunShade_iType): 0; Types volet activés: 127; Nombre de panneaux (gs_shutter_nPanels): 2; Nombre de panneaux 2: 1; Position panneau (gs_shutter_panelPos): Symmetric; Position panneau (gs_shutter_iPanelPos): 1; Hauteur volet automatique: yes; Cadre supplémentaire: no; Type de couverture (gs_slidingShutter_cover): Z-Profile; Type de couverture (gs_slidingShutter_iCover): 1; Direction articulation (gs_foldingShutter_stacking): Inside; Direction articulation (gs_foldingShutter_iStacking): 1; Ouvert en 3D: yes; Angle ouverture en 3D: 180 deg; Afficher symbole 2D: yes; Afficher lignes d'ouverture sur symbole: no; Type de panneau: (gs_shutPanel_type): Style 1; Type de panneau: (gs_shutPanel_iType): 1; Largeur cadre inf. différente: no; Largeur volets automatiques: yes; Angle persienne: 30 deg; Résolution trou: 3; Nombre trous horizontaux: 5; Nombre trous verticaux: 8; Placement volet roulant (gs_shutRoll_placement): Fixed on Facade; Placement volet roulant (gs_shutRoll_iPlacement): 1; Type boîte (gs_shutRoll_boxType): Rectangular; Type boîte (gs_shutRoll_iBoxType): 1; Position rampe (gs_shutRoll_railPos): Sur revêtement; Position rampe (gs_shutRoll_iRailPos): 1; Afficher revêtement derrière parasol (gs_shutRoll_showCasingBehind): no; Isolation derrière cellule (gs_shutRoll_cutWallBehind): no; Inclure hauteur dans hauteur de trou de mur: no; Angle supérieur boîte: 10 deg; Taille boîte par défaut (gs_shutRoll_boxDefaultSize): Reveal Width; Taille boîte par défaut (gs_shutRoll_iBoxDefaultSize): 1; Placement stores (gs_shutLam_placement): Fixed on Facade; Placement stores (gs_shutLam_iPlacement): 1; Isolation derrière cellule (gs_shutLam_cutWallBehind): no; Boîte ouverte: yes; Rampe: yes; Position rampe (gs_shutLam_railPos): Sur revêtement; Position rampe (gs_shutLam_iRailPos): 1; Afficher revêtement derrière parasol (gs_shutLam_showCasingBehind): no; Angle de rotation des lamelles (gs_shutLam_rotation): 45 deg; Angle de rotation des lamelles (gs_shutLam2_rotation): 45 deg; Linteau (gs_masonry_arch): Sans; Linteau (gs_masonry_arch_int): 1; Type linteau (gs_masonry_arch_structure): Stuc; Type linteau (gs_masonry_arch_structure_int): 1; Arche sur linteau: yes; Niche sous arche: yes; Angle inclinaison: 75 deg; Surface niche personnalisée: no; Type ébrasure (gs_reveal_type_new): Baie simple; Type ébrasure (gs_reveal_type_int): 2; Type ébrasure inférieure (gs_reveal_type_bottom): Uniforme; Type ébrasure inférieure (gs_reveal_type_bottom_int): 1; Type ébrasure extérieure: Baie simple; Type ébrasure (gs_reveal_doubleOuterTypeInt): 2; Type ébrasure intérieure: Baie simple; Type ébrasure (gs_reveal_doubleInnerTypeInt): 2; Profondeur montant uniforme: no; Côté angle 2: 20 deg; Côté angle: 20 deg; Angle côté supérieur: 20 deg; Angle côté inférieur: 20 deg; Utiliser composant finition mur: no; Tourner automatiquement plâtre surface intérieure: yes; Tourner plâtre surface intérieure: 0; Tourner automatiquement plâtre surface extérieure: yes; Tourner plâtre surface extérieure: 0; Afficher en 3D: no; Type de fermeture (gs_closure_type): Pas de fermeture; Type de fermeture (gs_closure_type_int): 1; Tourner couche sur côté (gs_cavity_side): Les deux; Tourner couche sur côté (iCavityClosureSide): 1; Nbre de couches retournées: 1; Num. à partir de (gs_nTurnDir): Face extérieure; Num. à partir de (iCavityClosureTurnDir): 1; Placer fermeture sur côté 2: yes; Placer fermeture sur côté 1: yes; Placer fermeture en haut: no; Placer fermeture en bas: no; Placer fermeture sur couche: 1; Placer fermeture de côté (gs_cc_dutch_ClosureToSide): 1; Ecart à couche externe: yes; Tourner couche sur fermeture: no; Insérer bande d'isolation: yes; Afficher bande d'isolation: yes; Stylo contour (gs_penJoint): Ouvertures - Coupé non structurel; Type de ligne de contour (gs_ltJoint): 1; Motif de hachure (gs_fillJoint): Rigid Insulation; Stylo hachure (gs_penJointFg): Général - Dessin; Stylo fond de hachure (gs_penJointBg): Eléments 2D - Dessin; Surface personnalisée: no; Surface: 06 | W Pine H; Stylo contour (gs_penPlug): Ouvertures - Coupé non structurel; Type de ligne de contour (gs_ltPlug): 1; Motif de hachure (gs_fillPlug): Rigid Insulation; Stylo hachure (gs_penPlugFg): Général - Dessin; Stylo fond de hachure (gs_penPlugBg): Eléments 2D - Dessin; Côté montant édité: 1; Côté mur édité: 1; Numéro couche éditée: 1; Tourner couche: no; Considérer couches comme plâtre: no; Tourner épaiseur: 1; Orientation hachure: 1; Ligne de séparation tournant: no; Stylo ligne de séparation: Général - Dessin; Dernier côté sélectionné: no; Méthode fermeture changée auto.: no; Connexion à gauche: no; Connexion à droite: no; Connexion en haut: no; Connexion en bas: no; Incrustation allège fenêtre: no; Tailles incrustation mur (gs_parapet_sizes_st): Automatique; Tailles incrustation mur (iParapetSize): 1; Cotes largeur et longueur auto: yes; Incrustation base mur à (gs_parapet_bottom_st): Etage actuel; Incrustation base mur à (iParapetBottom): 1; Afficher allège masquée: yes; Type ligne allège masquée: 1; Angle d'ouverture de Châssis 1 (openingAngle_01): 0 deg; Angle d'ouverture de Châssis 1 (openingAngle2_01): 0 deg; Angle d'ouverture de Châssis 2 (openingAngle_02): 0 deg; Angle d'ouverture de Châssis 2 (openingAngle2_02): 0 deg; Angle d'ouverture de Châssis 3 (openingAngle_03): 0 deg; Angle d'ouverture de Châssis 3 (openingAngle2_03): 0 deg; Angle d'ouverture de Châssis 4 (openingAngle_04): 0 deg; Angle d'ouverture de Châssis 4 (openingAngle2_04): 0 deg; Angle d'ouverture de Châssis 5 (openingAngle_05): 0 deg; Angle d'ouverture de Châssis 5 (openingAngle2_05): 0 deg; Angle d'ouverture de Châssis 6 (openingAngle_06): 0 deg; Angle d'ouverture de Châssis 6 (openingAngle2_06): 0 deg; Angle d'ouverture de Châssis 7 (openingAngle_07): 0 deg; Angle d'ouverture de Châssis 7 (openingAngle2_07): 0 deg; Angle d'ouverture de Châssis 8 (openingAngle_08): 0 deg; Angle d'ouverture de Châssis 8 (openingAngle2_08): 0 deg; Angle d'ouverture de Châssis 9 (openingAngle_09): 0 deg; Angle d'ouverture de Châssis 9 (openingAngle2_09): 0 deg; Angle d'ouverture de Châssis 10 (openingAngle_10): 0 deg; Angle d'ouverture de Châssis 10 (openingAngle2_10): 0 deg; Angle ouverture en 2D: 0 deg; Suppl. Opt. vue pour aff. symb. 2D: no; Type ligne ouverture: 1; Forme ligne ouverture (or_SwingType): Courbé; Forme ligne ouverture (or_iSwingType): 1; Forme ligne ouverture (or_SlidingType): Sans; Forme ligne ouverture (or_iSlidingType): 0; Stylo ligne ouverture 2D/3D (or_opLinePen): Ouvertures - Général; Stylo ligne ouverture 2D/3D (or_iOpLinePen): 3; Suppl. Opt. vue pour proj. 3D: no; Afficher ligne d'ouverture: yes; Type ligne côté ouverture (or_opLineType3dIn): Tirets; Type ligne côté ouverture (or_iOpLineType3dIn): 1; Type ligne côté opposé (or_opLineType3dOut): Ligne continue; Type ligne côté opposé (or_iOpLineType3dOut): 0; Orient. ligne (or_oplineStyle): Poignée; Orient. ligne (or_iOplineStyle): 1; Stylo ligne non coupée: A construire - Coupe; Stylo ligne coupée: A construire - Coupe; Stylo contour des deux côtés de chambranle: Ouvertures - Général; Ligne de contour de mur (gs_wcont_line): Des deux côtés; Ligne de contour de mur (iWallContourLine): 4; Type ligne contour int. mur: 1; Type ligne contour ext. mur: 1; Type ligne contour int. mur masqué: 1; Type ligne contour ext. mur masqué: 1; Stylo ligne contour de mur: Ouvertures - Général; Utiliser hachures: yes; Motif de hachure cadre: Background; Stylo hachure cadre: A construire - Coupe; Stylo fond de hachure cadre: Fond - Couleur 1; Motif de hachure châssis: Air Space; Stylo fond de châssis: Ouvertures - Hachures coupées; Stylo fond de hachure châssis: Fond - Couleur 1; Type hachure non coupée: Background; Stylo hachure non coupée: A construire - Coupe; Stylo fond de hachure non coupé: Fond - Couleur 1; Motif hachure symbole en plan: Background; Stylo hachure symbole en plan: Fond - Couleur 1; Stylo fond hachure symbole plan: Fond - Couleur 1; Stylo appui 3D et non coupé: Général - Dessin; Stylo contour appui en Coupe: Général - Dessin; Motif hachure appui en Coupe: Background; Stylo hachure d'appui en Coupe: Fond - Couleur 1; Stylo fond hachure appui Coupe: Fond - Couleur 1; Stylo contour isolation coupe: Général - Dessin; Motif hachure isolation Coupe: Rigid Insulation; Stylo hachure isolation Coupe: Général - Dessin; Stylo fond hachure isol. Coupe: Fond - Couleur 1; Stylo latte 3D et non coupé: Général - Dessin; Stylo contour latte en Coupe: Général - Dessin; Motif hachure tablette en Coupe: Background; Stylo hachure tablette en Coupe: Fond - Couleur 1; Stylo fond hach. tablette Coupe: Fond - Couleur 1; Type hachure chambr. intérieur: Background; Stylo hachure chambr. int.: Fond - Couleur 1; Stylo fond hachure chambr. int.: Fond - Couleur 1; Type hachure chambr. ext.: Background; Stylo hachure chambr. ext.: Fond - Couleur 1; Stylo fond hachure chambr. ext.: Fond - Couleur 1; Motif de hachure arche coupe: Background; Stylo fond hachure appui arche Coupe (gs_masonry_arch_pen_fg): Fond - Couleur 1; Stylo fond hachure appui arche Coupe (gs_masonry_arch_pen_bg): Fond - Couleur 1; Motif de hachure de Coupe de Profil de ventilation: Air Space; Stylo de hachure de Coupe de Profil de ventilation: Fond - Couleur 1; Stylo de fond de hachure de Coupe de Profil de ventilation: Fond - Couleur 1; Type de ligne symbole volet: 1; Stylo ligne coupée volet: Général - Dessin; Stylo ligne non coupée volet: Général - Dessin; Type hachure coupée volet: Background; Stylo hachure coupée volet: Général - Dessin; Stylo fond hachure coupé volet: Fond de fenêtre; Motif de hachure d'isolation de pare-soleil: Background; Stylo de hachure d'isolation de pare-soleil: Général - Dessin; Stylo de fond d'isolation de pare-soleil: Fond de fenêtre; Jonction éléments cadree: 1; Stylo cadre: A construire - Coupe; Stylo châssis: Ouvertures - Général; Stylo vitrage: Ouvertures - Coupé non structurel; Stylo linteau: Murs - Général; Ombre: yes; Surface extérieure cadre: Paint-05; Surface intérieure cadre: Paint-05; Surface extérieure châssis: Wd-Pine Horizontal; Surface intérieure châssis: 06 | W Pine H; Surface persiennes: 06 | W Pine H; Surface vitre: Glass-Blue; Surface extérieure de meneau: Wd-Pine Horizontal; Surface intérieure de meneau: Wd-Pine Horizontal; Surface extérieure panneau solide: 06 | W Pine H; Surface intérieure panneau solide: 06 | W Pine H; Surface intérieure chambranle: Wd-Pine Horizontal; Surface extérieure chambranle: Wd-Pine Horizontal; Surface de profil de ventilation: 05 | Aluminum Plain; Surface panneau de volet: Wd-Pine Horizontal; Surface cadre volet: Wd-Pine Horizontal; Surface boîte volet roulant: Mtl-Stainless Steel; Surface lames volet roulant: Surf-White; Surface rail volet roulant: Surf-White; Surface boîtier de stores: Mtl-Stainless Steel; Surface segments de stores: Surf-White; Surface rail volet coulissant: Mtl-Stainless Steel; Surface d'appui: Wd-Pine Horizontal; Surface mortier appui briques: Surf-Stucco White; Surface de tableau: Wd-Pine Horizontal; Surface brique linteau: Brick-Running Bond; Surface mortier linteau: Surf-Stucco White; Surface clef de voûte linteau: Stn-Sandstone; Surface niche: 32 | Mulch; Direction d'ouverture: 1; Afficher comme imposte: no; Stylo ligne tête de mur: Général - Dessin; Type de ligne tête de mur: 21; Symbole en plan Linteau/seuil: no; Type ligne symb. Linteau/seuil: 21; Stylo symbole Linteau/seuil: Texte d'annotation - Général; Fenêtre appartient à Zone vers laquelle elle donne: no; Coût: 0; Surface vitrée totale (gs_list_glassarea_tmp): 0; Supplanter surface vitrée: yes; Surface vitrée totale (gs_list_glassarea): 0; Périmètre total vitrage: 0; Performance air libre (mm2/l/m): 0; Type de groupe (FM_Type): Default Objects; Type de groupe (iFMType): 999; Poids de l'objet: 0; Unité poids de l'objet: kg; Opération IFC (ifc_optypestr): Triple vertical; Opération IFC (ifc_optype): 4; Angle ouverture volet: 180 deg; Style lignes d'ouverture: 1
AC_Pset_RenovationAndPhasing - Renovation Status: Existing
BaseQuantities - GrossArea: 18.453 m2; Height: 2 m; Width: 9.22652 m; Perimeter: 22.453 m; Area: 18.453 m2; Volume: 0.0663897 m3; Depth: 0.37 m
ArchiCADQuantities - Altitude à Zéro du Projet: 17.4 m; Altitude à étage: 0 m; Hauteur: 2 m; Superficie de surface: 41.6294 m2; Volume net: 0.0663897 m3; Largeur: 9.47793 m; Epaisseur: 0.05 m; Hauteur nominale seuil: 0 m; Hauteur seuil côté ébrasure: 0 m; Hauteur seuil côté opposé ébrasure: 0 m; Hauteur nominale linteau: 2 m; Hauteur linteau côté ébrasure: 2 m; Hauteur linteau côté opposé ébrasure: 2 m; Largeur ouverture côté ébrasure: 9.22652 m; Largeur ouverture côté opposé ébrasure: 9.22652 m; Hauteur ouverture côté ébrasure: 2 m; Hauteur ouverture côté opposé ébrasure: 2 m; Surface ouverture côté ébrasure: 18.453 m2; Surface ouverture côté opposé ébrasure: 18.453 m2; Largeur nominale de l'ouverture côté ébrasure: 9.47793 m; Largeur nominale de l'ouverture côté opposée ébrasure: 9.47793 m; Hauteur nominale de l'ouverture côté ébrasure: 2 m; Hauteur nominale de l'ouverture côté opposée ébrasure: 2 m; Surface nominale de l'ouverture P/F côté ébrasure: 18.9559 m2; Surface nominale de l'ouverture P/F côté opposé ébrasure: 18.9559 m2; Volume ouverture: 0.0663897 m3; Surface nominale ouverture P/F: 18.9559 m2; Volume nominal ouverture: 7.01367 m3; Valeur Appui ou Linteau: 0 m; Epaisseur de Mur: 0.37 m
AC_Equantity_Fenêtre_horizontale_à_châssis_multiples_18 - Largeur: 9.47793 m; Hauteur: 2 m; Dimension Z: 1 m; Niveau inférieur: 1 m; Niveau supérieur: 0 m; Hauteur appui à étage actuel: 0 m; Nouv. largeur droite hach. mur: 0.15 m; Nouv. largeur gauche hach. mur: 0.15 m; Epaisseur du mur connecté: 0 m; Epaissseur murs connectés G: 0.37 m; Epaissseur murs connectés D: 0.37 m; Largeur poteau d'angle: 0 m; Epaisseur poteau d'angle: 0 m; Projection poteau d'angle: 0 m; Tolérance max.: 0.1 m; Tolérance: 0 m; Tolérance gauche: 0 m; Tolérance droite: 0 m; Tolérance supérieure: 0 m; Tolérance inférieure: 0 m; Largeur cavité mur: 9.47793 m; Hauteur cavité mur: 2 m; Largeur ébrasure: 9.47793 m; Hauteur ébrasure: 2 m; Largeur unité: 9.47793 m; Hauteur unité: 2 m; Distance d'axe: 3.14264 m; Largeur de panneau 1: 3.14264 m; Largeur de panneau 2: 0.5 m; Largeur de panneau 3: 0.5 m; Largeur de panneau 4: 0.5 m; Largeur de panneau 5: 0.5 m; Largeur de panneau 6: 0.5 m; Largeur de panneau 7: 0.5 m; Largeur de panneau 8: 0.5 m; Largeur de panneau 9: 0.5 m; Conserver largeur de panneau: 0.5 m; Epaisseur cadre: 0.05 m; Largeur cadre: 0.05 m; Largeur cadre côté 2: 0.05 m; Largeur cadre supérieur: 0.05 m; Largeur cadre inférieur (gs_frame_width_lower): 0.05 m; Profondeur feuillure: 0.025 m; Largeur feuillure: 0.025 m; Largeur meneau central: 0.05 m; Largeur de meneau 1: 0.1 m; Largeur de meneau 2: 0.1 m; Largeur de meneau 3: 0.1 m; Largeur de meneau 4: 0.1 m; Largeur de meneau 5: 0.1 m; Largeur de meneau 6: 0.1 m; Largeur de meneau 7: 0.1 m; Largeur de meneau 8: 0.1 m; Largeur de meneau 9: 0.1 m; Hauteur de division horizontale Châssis 1: 0.9 m; Hauteur de division horizontale Châssis 2: 0.9 m; Hauteur de division horizontale Châssis 3: 0.9 m; Hauteur de division horizontale Châssis 4: 0.9 m; Hauteur de division horizontale Châssis 5: 0.9 m; Hauteur de division horizontale Châssis 6: 0.9 m; Hauteur de division horizontale Châssis 7: 0.9 m; Hauteur de division horizontale Châssis 8: 0.9 m; Hauteur de division horizontale Châssis 9: 0.9 m; Hauteur de division horizontale Châssis 10: 0.9 m; Epaisseur châssis: 0.05 m; Largeur châssis: 0.05 m; Largeur grille: 0.02 m; Epaisseur grille: 0.025 m; Epaisseur vitrage: 0.02 m; Epaisseur persiennes: 0.01 m; Largeur persiennes: 0.05 m; Dépassement ouverture gauche: 0 m; Dépassement ouverture droite: 0 m; Dépassement ouverture supérieur: 0 m; Dépassement ouverture inférieur: 0 m; Largeur côté 1 (gs_tw_right_out): 0.1 m; Largeur côté 2 (gs_tw_left_out): 0.1 m; Largeur haut (gs_tw_top_out): 0.1 m; Largeur base (gs_tw_bottom_out): 0.1 m; Epaisseur sur mur (gs_trim_thk_out): 0.025 m; Epaisseur dans trou de mur (gs_trim_width_out): 0.025 m; Décalage (gs_trim_offs_out): 0 m; Débord supérieur (gs_trimov_top_left_out): 0.1 m; Débord supérieur (gs_trimov_top_right_out): 0.1 m; Débord inférieur: (gs_trimov_bot_left_out): 0.1 m; Débord inférieur: (gs_trimov_bot_right_out): 0.1 m; Largeur côté 1 (gs_tw_right_in): 0.1 m; Largeur côté 2 (gs_tw_left_in): 0.1 m; Largeur haut (gs_tw_top_in): 0.1 m; Largeur base (gs_tw_bottom_in): 0.1 m; Epaisseur sur mur (gs_trim_thk_in): 0.025 m; Epaisseur dans trou de mur (gs_trim_width_in): 0.025 m; Décalage (gs_trim_offs_in): 0 m; Débord supérieur (gs_trimov_top_left_in): 0.1 m; Débord supérieur (gs_trimov_top_right_in): 0.1 m; Débord inférieur: (gs_trimov_bot_left_in): 0.1 m; Débord inférieur: (gs_trimov_bot_right_in): 0.1 m; Largeur appui: 0 m; Largeur supérieure appui: 0.01 m; Hauteur supérieure appui: 0.01 m; Epaisseur appui: 0.025 m; Epaisseur front appui: 0.015 m; Altitude appui: 0 m; Débord larmier appui: 0.02 m; Largeur larmier appui: 0.03 m; Débord appui: 0.03 m; Dépassement appui gauche: 0 m; Dépassement appui droite: 0 m; Glissement appui en profondeur: 0.02 m; Glissement appui de mur: 0 m; Profondeur trou arrière (gs_sill_holeDepthBehind): 0 m; Epaisseur brique (gs_brick_sill_br_thk): 0.065 m; Epaisseur mortier (gs_brick_sill_mort_thk): 0.015 m; Largeur latte: 0.23 m; Epaisseur latte: 0.025 m; Débord tablette: 0.03 m; Dépassement tablette gauche: 0 m; Dépassement tablette droite: 0 m; Glissement tabl. en profondeur: 0 m; Hauteur profil: 0.065 m; Epaisseur profil: 0.11 m; Hauteur panneau: 1.5 m; Décalage intérieur: 0.02 m; Profondeur fermeture: 0 m; Largeur cadre supplémentaire: 0.04 m; Epaisseur cadre supplémentaire: 0.03 m; Epaisseur allège vitrée: 0.03 m; Longueur colonne centrale: 0.02 m; Rayon colonne centrale: 0.005 m; Distance panneau: 0.006 m; Débord extérieur: 0 m; Largeur panneau intérieur: 0.12 m; Longueur ouverture en 3D: 1.5 m; Longueur fermée en 3D: 0 m; Longueur ouverture 1 en 3D (gs_shutter_opLength_1): 0.56 m; Longueur ouverture 1 en 3D (gs_shutter_opLength_2): 0.14 m; Hauteur ouverture en 3D: 1.5 m; Hauteur fermée en 3D: 0 m; Epaisseur panneau: 0.05 m; Largeur cadre panneau: 0.05 m; Largeur cadre inférieur (gs_shutPanel_frameWidthBottom): 0.05 m; Largeur panneau: 0 m; Epaisseur hachure panneau: 0.01 m; Epaisseur persienne: 0.01 m; Largeur persienne: 0.04 m; Largeur diviseur cadre horiz.: 0.05 m; Largeur diviseur cadre vert.: 0.05 m; Rayon trou: 0.01 m; Largeur montant: 0.1 m; Largeur cadre Z: 0.05 m; Epaisseur cadre Z: 0.025 m; Epaisseur plans verticaux: 0.025 m; Epaisseur plans horizontaux: 0.025 m; Largeur appr. plans verticaux: 0.08 m; Largeur appr. plans horizontaux: 0.115 m; Hauteur boîte (gs_shutRoll_boxHeight): 0.2 m; Profondeur boîte (gs_shutRoll_boxWidth): 0.15 m; Décalage boîte gauche: 0 m; Décalage boîte droite: 0 m; Profondeur rails: 0.0725 m; Distance au mur (gs_shutRoll_distFromWall): 0 m; Distance au linteau (gs_shutRoll_distFromHead): 0 m; Largeur lamelle: 0.05 m; Hauteur boîte (gs_shutLam_boxHeight): 0.2 m; Profondeur boîte (gs_shutLam_boxWidth): 0.15 m; Largeur recouvrement: 0 m; Distance au mur (gs_shutLam_distFromWall): 0 m; Distance au linteau (gs_shutLam_distFromHead): 0 m; Largeur segment (gs_shutLam_segmentWidth): 0.06 m; Hauteur boîte (gs_shutLam2_boxHeight): 0.06 m; Largeur boîte: 0.06 m; Distance à fenêtre: 0.06 m; Distance au linteau (gs_shutLam2_distFromHead): 0.06 m; Hauteur axe cellule à linteau: 0 m; Largeur segment (gs_shutLam2_segmentWidth): 0.06 m; Distance entre arche et fenêtre: 0 m; Dépassement gauche linteau: 0 m; Dépassement droite linteau: 0 m; Elevation linteau: 0.03 m; Décalage linteau: 0 m; Hauteur linteau: 0.25 m; Profondeur linteau: 0.12 m; Profondeur trou arrière (gs_masonry_arch_rearHoleDepth): 0 m; Epaisseur brique (gs_masonry_arch_brick_thk): 0.065 m; Epaisseur mortier (gs_masonry_arch_mort_thk): 0.01 m; Largeur clé de voûte: 0.1 m; Dépassement clé de voûte: 0 m; Projection clé de voûte: 0.01 m; Profondeur ébrasure : (gs_wido_sill): 0.12 m; Profondeur ébrasure : (AC_wido_sill): 0.12 m; Profondeur montant côté 2: 0.06 m; Profondeur montant: 0.06 m; Profondeur montant int. côté 2 (gs_reveal_splayed_innerLeft): 0.06 m; Profondeur montant intérieur (gs_reveal_splayed_innerRight): 0.06 m; Profondeur montant int. côté 2 (gs_reveal_double_innerLeft): 0.06 m; Profondeur montant intérieur (gs_reveal_double_innerRight): 0.06 m; Profondeur montant linteau: 0.06 m; Profondeur montant appui: 0 m; Profondeur linteau int. (gs_reveal_splayed_innerTop): 0.06 m; Profondeur appui int. (gs_reveal_splayed_innerBottom): 0.06 m; Profondeur linteau int. (gs_reveal_double_innerTop): 0.06 m; Profondeur appui int. (gs_reveal_double_innerBottom): 0 m; Profondeur montant ext.: 0.08 m; Limite épaisseur plâtre: 0.04 m; Distance de couche / fermeture: 0 m; Largeur fermeture: 0.038 m; Epaisseur fermeture: 0.1 m; Epaisseur bande: 0.025 m; Largeur profilé: 0.075 m; Epaisseur personnalisée: 0.015 m; Dépassement couche prof. cadre: 0 m; Profondeur incrustation: 0.05 m; Largeur allège: 1 m; Débord gauche: 0 m; Débord droite: 0 m; Hauteur allège: 0.9 m; Débord inférieur: (gs_parapet_botelev): 0 m; Distance d'ouverture 1 Châssis 1: 0 m; Distance d'ouverture 2 Châssis 1: 0 m; Distance d'ouverture 1 Châssis 2: 0 m; Distance d'ouverture 2 Châssis 2: 0 m; Distance d'ouverture 1 Châssis 3: 0 m; Distance d'ouverture 2 Châssis 3: 0 m; Distance d'ouverture 1 Châssis 4: 0 m; Distance d'ouverture 2 Châssis 4: 0 m; Distance d'ouverture 1 Châssis 5: 0 m; Distance d'ouverture 2 Châssis 5: 0 m; Distance d'ouverture 1 Châssis 6: 0 m; Distance d'ouverture 2 Châssis 6: 0 m; Distance d'ouverture 1 Châssis 7: 0 m; Distance d'ouverture 2 Châssis 7: 0 m; Distance d'ouverture 1 Châssis 8: 0 m; Distance d'ouverture 2 Châssis 8: 0 m; Distance d'ouverture 1 Châssis 9: 0 m; Distance d'ouverture 2 Châssis 9: 0 m; Distance d'ouverture 1 Châssis 10: 0 m; Distance d'ouverture 2 Châssis 10: 0 m; Dépass.ouverture gauche: 0 m; Dépass.ouverture à droite: 0 m; Dépass.ouverture supérieur: 0 m; Dépass.ouverture inférieur: 0 m

# IfcWindow: Fenêtre horizontale à châssis multiples 18, WD - 002
In: Toiture
Type - OperationType: TRIPLE_PANEL_VERTICAL; ParameterTakesPrecedence: no; Sizeable: no
Type - Propriétés Doublure Fenêtre - LiningDepth: 0.05 m; LiningThickness: 0.05 m; MullionThickness: 0.05 m; FirstMullionOffset: 0.33644; SecondMullionOffset: 0.66822
Type - Propriétés Panneau Fenêtre - Panneau1 - OperationType: FIXEDCASEMENT; PanelPosition: RIGHT
Type - Propriétés Panneau Fenêtre - Panneau2 - OperationType: FIXEDCASEMENT; PanelPosition: MIDDLE
Type - Propriétés Panneau Fenêtre - Panneau3 - OperationType: FIXEDCASEMENT; PanelPosition: LEFT
OverallHeight: 2 m; OverallWidth: 10.7309 m; Material: Background (10), Air Space (2), Rigid Insulation
ArchiCADProperties - ID: WD - 002; Etage d'implantation: Toiture; Calque: A-WALL-EXTR; Type: Fenêtre; Verrouillé: no; Nom Elément de Bibliothèque: Fenêtre horizontale à châssis multiples 18; Matériau de construction / Composite / Profil / Hachure: Background; Fonction structurelle: Non défini; Position: Non défini; Classification d'lément: Type ArchiCAD; Etat de rénovation: Existant; Afficher sur filtre de rénovation: Tous les filtres appropriés; Dimensions ébrasure: 422,47"x78,74"; Dimensions trou mur: 422,47"x78,74"; Dimensions unité: 422,47"x78,74"; Structure mur: 1.2-Mur ext: revét ext + isol ext + maçonnerie + enduit; Taille L x H nominale: 422,47"x78,74"; Taille L x H x E nominale: 422,47"x78,74"x14,57"
